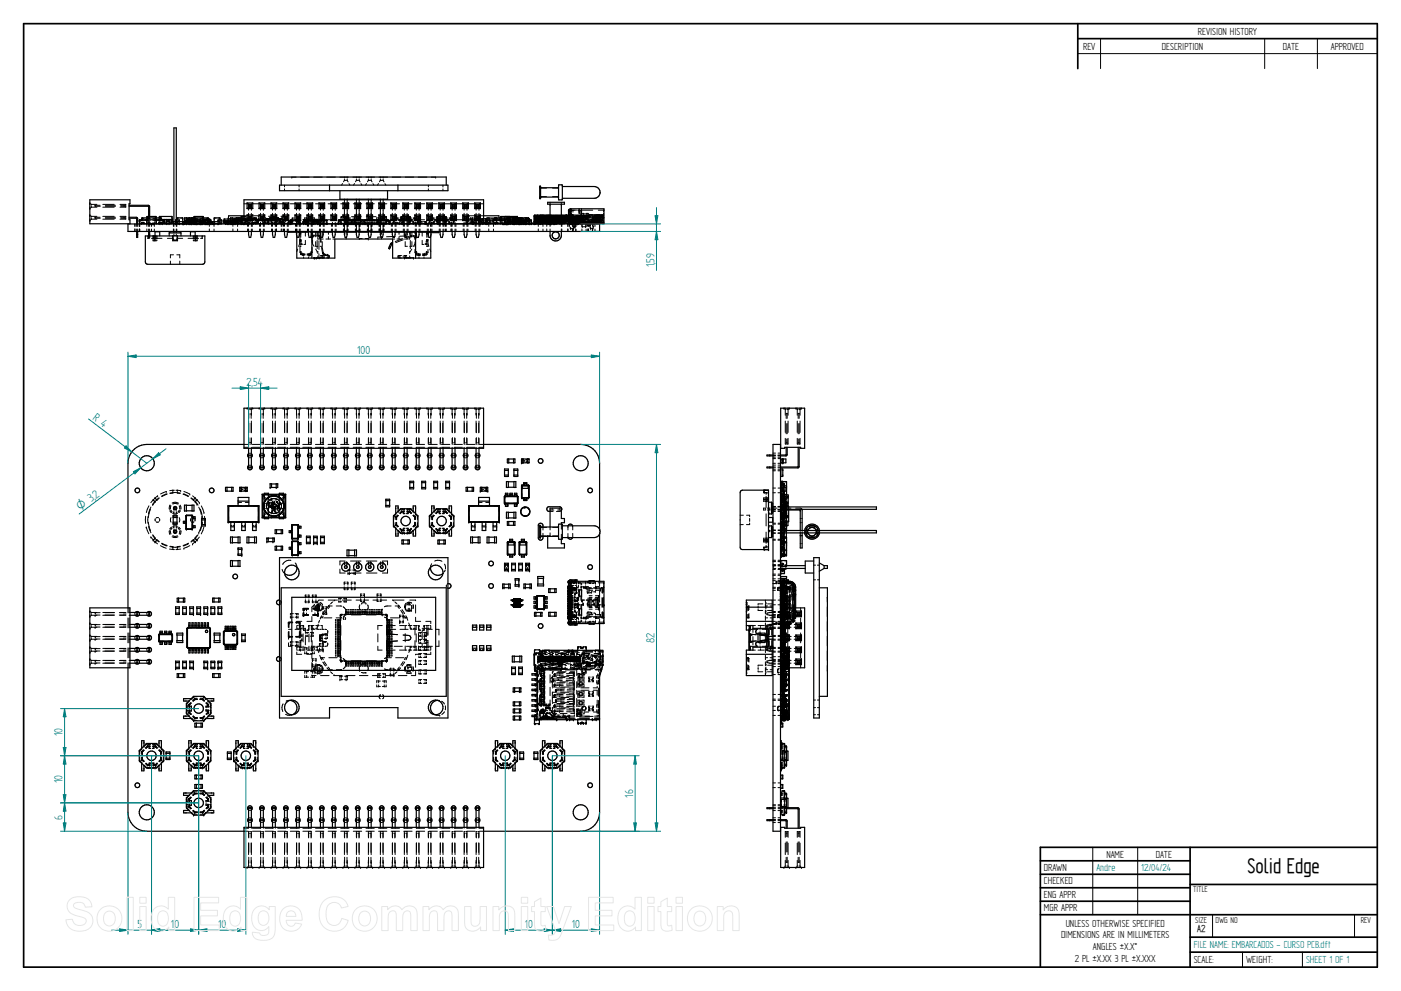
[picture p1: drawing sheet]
<svg xmlns="http://www.w3.org/2000/svg" width="594mm" height="420mm" viewBox="0 0 594 420" stroke-linecap="round" stroke-linejoin="round" font-family="sans-serif">
<defs><g id="words">
<text font-size="10.1" x="529" y="370.2">Solid Edge</text>
<g font-size="5.6" fill="#008080">
<text x="277.5" y="113.4" transform="rotate(-90 277.5 113.4)">1,59</text>
<text x="151.5" y="150.2">100</text>
<text x="104.5" y="163.7">2,54</text>
<text x="39" y="177.7" transform="rotate(37 39 177.7)">R 4</text>
<text x="40.8" y="211.4" transform="rotate(-37 40.8 211.4)">2</text>
<text x="277.5" y="272.6" transform="rotate(-90 277.5 272.6)">82</text>
<text x="26.5" y="312.2" transform="rotate(-90 26.5 312.2)">10</text>
<text x="26.5" y="332.1" transform="rotate(-90 26.5 332.1)">10</text>
<text x="268.4" y="338.2" transform="rotate(-90 268.4 338.2)">16</text>
<text x="26.5" y="347.5" transform="rotate(-90 26.5 347.5)">6</text>
<text x="58.2" y="393.5">5</text>
<text x="72.5" y="393.5">10</text>
<text x="92.5" y="393.5">10</text>
<text x="222.5" y="393.5">10</text>
<text x="242.5" y="393.5">10</text>
</g>
<text font-size="5.4" fill="#008080" x="34" y="216.5" transform="rotate(-37 34 216.5)">O 3,</text>
<g font-size="4.9">
<text x="507.9" y="14.7">REVISION HISTORY</text>
<text x="459.3" y="21">REV</text>
<text x="492.7" y="21">DESCRIPTION</text>
<text x="544" y="21">DATE</text>
<text x="564.3" y="21">APPROVED</text>
<text x="469.1" y="363.6">NAME</text>
<text x="490.1" y="363.6">DATE</text>
<text x="442.7" y="369.3">DRAWN</text>
<text x="442.7" y="375">CHECKED</text>
<text x="442.7" y="380.7">ENG APPR</text>
<text x="442.7" y="386.4">MGR APPR</text>
<text x="451.9" y="392.9">UNLESS OTHERWISE SPECIFIED</text>
<text x="449.9" y="397.9">DIMENSIONS ARE IN MILLIMETERS</text>
<text x="455.7" y="407.8">2 PL ±X.XX 3 PL ±X.XXX</text>
<text x="463.5" y="402.9">ANGLES ±X.X°</text>
<text x="506.2" y="408.3">SCALE:</text>
<text x="528.4" y="408.3">WEIGHT:</text>
</g>
<g font-size="4.9" fill="#008080">
<text x="464.9" y="369.3">Andre</text>
<text x="483.9" y="369.3">12/04/24</text>
<text x="506.2" y="402">FILE NAME: EMBARCADOS - CURSO PCB.dft</text>
<text x="553.8" y="408.4">SHEET 1 OF 1</text>
</g>
<text font-size="4.8" x="507.7" y="395.3">A2</text>
<g font-size="4.1">
<text x="505.9" y="378.3">TITLE</text>
<text x="506.9" y="391.1">SIZE</text>
<text x="515.4" y="391.1">DWG NO</text>
<text x="577" y="391.1">REV</text>
</g>
</g></defs>
<g fill="none" stroke="#000" stroke-width=".72">
<path d="M10 10h574v400h-574zM457 10v19.1M457 16.4h127M504.6 359.2v50.8M584 359.2h-142.9v50.8M441.1 365h63.5M441.1 370.7h63.5M441.1 376.4h63.5M504.6 375h79.4M441.1 382.1h63.5M441.1 387.8h142.9M504.6 397.3h79.4"/>
<path d="M504.6 403.7h79.4"/>
</g>
<g fill="none" stroke="#000" stroke-width=".42">
<path d="M466.7 16.4v12.7M536.3 16.4v12.7M558.6 16.4v12.7M457 22.7h127M120.6 78.5v.7M123.7 75.1h.1M123.7 75.1h1.9M126.8 78.5v.8M127.5 75.1h3.6M133 75.1h3.6M138.6 75.1h3.6M144.1 75.1h3.6"/>
<path d="M145.2 77.8l-.3 .7M146 76.5h.2M146 76.5l-.3 .6M146 75.1v.4M146 76v.5M146.5 76.5h.3M147 76.5h.2M147.2 75.1v.4M147.2 76v.5M147.2 76.5l.4 .6M148 77.9l.4 .6M149.6 75.1h3.7"/>
<path d="M150.3 77.8l-.4 .7M151.1 76.5h.2M151.1 76.5l-.4 .6M151.1 75.1v.4M151.1 76v.5M151.5 76.5h.3M152.1 76.5h.2M152.3 75.1v.4M152.3 76v.5M152.3 76.5l.4 .6M153.1 77.9l.4 .6M155.2 75.1h3.6"/>
<path d="M155.4 77.8l-.4 .7M156.2 76.5h.2M156.2 76.5l-.4 .6M156.2 75.1v.4M156.2 76v.5M156.6 76.5h.3M157.2 76.5h.2M157.4 75.1v.4M157.4 76v.5M157.4 76.5l.4 .6M158.2 77.9l.3 .6M160.5 77.8l-.4 .7"/>
<path d="M160.7 75.1h3.7M161.3 76.5h.2M161.3 76.5l-.4 .6M161.3 75.1v.4M161.3 76v.5M161.7 76.5h.3M162.3 76.5h.2M162.5 75.1v.4M162.5 76v.5M162.5 76.5l.3 .6M163.2 77.9l.4 .6M166.3 75.1h3.6"/>
<path d="M171.8 75.1h3.7M177.3 75.1h3.7M181.6 78.5v.7M182.9 75.1h1.8M184.7 75.1h.1M187.8 78.5v.8M228.8 79.4l.1 .1M228.9 79.6l.2 .1M229.2 79.8h.1M229.2 79.8h2.5M234.3 79.8h2.5M38.1 91.1l.2 .2"/>
<path d="M38.1 86.1h.1M38.1 88.4h.1M38.1 93.5h.1M38.1 91.1h.1M38.1 86.1v.8M38.1 87.7v.7M38.1 91.1v.8M38.1 92.8v.7M38.1 86.1l.2 .1M38.3 93.3l-.2 .2M38.3 88.3l-.2 .1M38.5 91.5l.2 .2"/>
<path d="M38.5 86.4l.2 .3M38.7 91.7v.4M38.7 92.6v.3M38.7 92.9l-.2 .2M38.7 86.7v.3M38.7 87.5v.3M38.7 86.7h2.4M38.7 87.8l-.2 .3M38.7 87.8h2.4M38.7 92.9h2.4M38.7 91.7h2.4M40.3 87.4l2.2 .1"/>
<path d="M40.3 92.5h2.2M40.4 87v.2M40.4 87.4v.1M40.4 92.1v.1M40.4 92.5h.1M42.5 87l-2.2 .2M42.5 92.1l-2.2 .1M43.6 86.7h4.8M43.6 87.8h4.8M43.6 92.9h4.8M43.6 91.7h4.8M44.7 87h4.2"/>
<path d="M44.7 92.1h4.2M44.7 87.5h4.3M44.7 92.5h4.3M50.9 86.7l2.4 .1M50.9 91.7l2.4 .2M51.2 87.5l2.1 .1M51.2 92.5l2.1 .2M52.6 87v.2M52.6 87.4v.1M52.6 92.1v.1M52.6 92.5h.1M53.3 87h-2.1"/>
<path d="M53.3 87.8h-2.4M53.3 92l-2.1 .1M53.3 92.8l-2.4 .1M57.2 95v1M57.2 97.1v1M57.9 95v1M57.9 97.1v1M58.4 95v1M58.4 97.1v1M59 95v1M59 97.1v1M59.2 95v1"/>
<path d="M59.2 97.1v1M59.3 95v1M59.3 97.1v1M60.1 94.5h.3M60.1 93.2h.1M60.1 93.3v.1M60.3 93l-.1 .2M60.3 92.4l-.2 .1M60.4 92.6v.2M60.4 93.2v.2M60.7 94.5h.3M61.1 92.6l-.8 .2"/>
<path d="M61.9 92.6h1.8M62.3 95v1M62.3 97.1v1M62.5 93.2h.1M62.5 93.3v.1M62.6 93v.4M62.6 92.8h.1M62.7 93.4h1M63 91.8v1M63 93.9v2.1M63 97.1v1M63.2 94.9h.1"/>
<path d="M63.2 94.7v.2M63.5 91.8v1M63.5 93.9v2.1M63.5 97.1v1M63.5 94.9h.1M63.7 94.7h.3M64.3 95v1M64.3 97.1v1M64.5 94.7h.3M64.8 92.6h1.8M64.8 93.4h.9M64.9 94.9h.1"/>
<path d="M65.1 94.9h.1M65.2 94.7h.1M65.3 94.9h.1M65.3 94.7h.1M65.4 95v1M65.4 97.1v1M65.8 93.2v.2M65.9 92.6l-.1 .2M65.9 93v.2M66 93.2h.1M66 93.3v.1M67.3 93.4h.1"/>
<path d="M67.3 93.3v.1M67.3 93.4l.1 .4M67.4 94.5h.4M67.4 92.6l.7 .2M67.4 92.9l-.1 .3M67.5 94.3v.4M67.5 92.4v.2M67.6 93.4v.4M67.6 93.3v.1M67.6 93h.1M67.6 93.4h.1M67.6 92.9v.3"/>
<path d="M67.6 94.3v.4M67.6 92.4v.2M67.8 93h.2M67.8 93.4h.4M67.9 94.9h.1M67.9 94.1v.3M67.9 93.4v.5M67.9 93v.2M68.1 92.6v.2M68.1 93.2v.2M68.1 94.5h.3M68.1 92.4l.1 .1"/>
<path d="M68.1 92.4h.1M68.2 93v.2M68.2 92.4h.1M68.2 94.6l-.3 .1M68.3 93h.1M68.3 92.5h.1M68.4 93.2h.1M68.4 93.3v.1M68.4 94.7h.3M68.6 93.4h.4M68.6 94.6h.2M68.8 94.6h.1"/>
<path d="M68.8 94.9h.1M68.8 93.2v.1M68.8 93.5v.4M68.8 94.1v.3M68.8 94.6v.1M69 94.7h.3M69.3 93.4h.2M69.8 93.4h.3M70.4 94.8h.5M70.4 94.1h.5M70.4 93.4h.3M70.4 94.6h.2"/>
<path d="M70.7 94.6h.1M70.7 94.9h.1M70.7 94.6l-.9 .1M70.7 94v.1M70.7 94.3v.1M71.5 94.8h.5M71.5 94.1h.5M71.7 93.4h.3M71.7 94.9h.1M71.7 94.3v.1M71.7 94v.1M71.8 94.6l.8 .1"/>
<path d="M72 94.6h.1M72.3 93.4h.3M73.4 94.8h.5M73.5 95v1M73.5 97.1v1M73.7 95v1M73.7 97.1v1M73.7 98.3v.5M73.7 99.4v.5h.4M73.7 94.9h.2M74.1 94l-.7 .1M74.5 94.1l.6-.1v.9"/>
<path d="M74.5 94.3v.4M74.5 94.7l.1 .1M74.8 93.3v.5M74.8 94.4v1.6M74.8 97.1v1M74.8 98.3v.5M74.8 99.4v.5h-.3M75 95v1M75 97.1v1M75 93.3l-.5 .1v.5M75 94.8l-.8 .1M75 94.8l.1 .1"/>
<path d="M75.1 94.7v.1M75.5 93.3h.4M75.9 92.5h-.8l-.1 1.3M75.9 94.8h-1.4M76 93.4v.5M76 94.3l-.1 .5h-.4M76.1 94v.2M76.1 94.6v.2M76.6 92.5h.8v.8M77.4 94l-.1 .8h-.7M77.5 94.6v.3M77.8 94.8h.4"/>
<path d="M77.8 94.9h.1M77.8 94.6h.1M77.8 94.6v.1M78 94.1h-.5v.2M78 94.6h.1M78.1 94.6h.1M78.2 94v.2M78.2 94.6v.3M78.2 94.8l-.1 .1M78.2 94.5h.1M78.3 94.8h.1M78.3 94.4h.1"/>
<path d="M78.4 94.8h.1M78.4 94v.1M78.4 94.7v.1M78.6 94.6l-.2 .2M78.6 94v.1M78.6 94.2v.2M78.9 94v.2M78.9 94.5l.3 .2M79 93.7h.8M79 94.3h.1M79 94.4h.1M79 92.5v.3"/>
<path d="M79 93.1v.3h.8M79 93.9l.1 .2M79.1 94.4v.3M79.1 93.3v.1M79.1 94l-.5 .1M79.2 93.9h.1M79.2 93.9l.1 .2M79.2 93.9h.2M79.2 94h.1M79.2 93.4v.1M79.2 94.5h.1M79.2 94.3h.1"/>
<path d="M79.2 94.9h.4M79.4 94.4v.3M79.4 93.5l-.1 .1M79.4 93.6l-.2 .3M79.5 93.2l-.1 .1M79.5 94.7h-.2M79.5 93.9h.3M79.7 93.6v.1M79.7 93.9v.2M79.7 94.7h.1M79.7 93.5v.1M79.7 94.4v.3"/>
<path d="M79.7 93.2v.1M79.8 93.6h-.3M79.8 94.8h-1.2M80 93.6h.3M80 93.9h.3M80 93.2h.1M80 94.7h.1M80 94.3h.1M80 93.3v.1M80 94.5v.1M80 94.8v.1M80.1 94.6h.2"/>
<path d="M80.1 94.9h.1M80.1 94.6v.1M80.1 94.4h.1M80.1 94v.2M80.1 93.6v.2M80.1 94.9h1M80.2 92.5h.4M80.2 92.5h.1M80.3 93v.2M80.3 92.4h.1M80.4 94.5h.1M80.4 94.3h.1"/>
<path d="M80.4 94.7h-.4M80.4 93.2v.2M80.4 93.3l.1 .6M80.5 94.6h.1M80.5 93.9h.3M80.5 94.7h.1M80.5 93.4h.1M80.5 94.3v.6M80.5 94.7l.1 .1M80.5 94.9h.1M80.6 93.3h1.3M80.6 94.4h.1"/>
<path d="M80.6 94.6h.1M80.6 94.9h.1M80.6 93.6v.2M80.6 94v.2M80.6 94.6v.1M80.7 93.7h.8M80.7 94.8h.7M80.8 93.6h-.3M81 93.3h-.6M81 92.5h.4l.1 .3M81.1 94.3h.1M81.1 94.5v.1"/>
<path d="M81.1 94.9h.1M81.1 94.7h.1M81.1 94.8v.1M81.1 92.6h-.8l.1 .2M81.2 93.6h.4M81.2 94.9h.1M81.2 94.7h.1M81.2 93.9h.4M81.4 92.5v.3M81.4 94.9h.1M81.4 94.4h.1M81.4 94v.2"/>
<path d="M81.4 92.4v2.5M81.4 92.9h3.5M81.5 93.3h.5M81.5 94.8h.4M81.6 94.6l-.2 .1M81.6 93.1l.1 .4M81.6 94.4l-.1 .3M81.7 93.7h.1M81.7 93.6v.1M81.7 93.7l-.1 .3M81.7 93.8h.1M81.8 94.6h.1"/>
<path d="M81.8 93.9l.4 .2M81.8 93.9l.1 .1M81.9 94.2v.2M81.9 93.5l.2 .2M81.9 93.5h.1M81.9 94.4h.1M81.9 94.6h.1M81.9 94.9h.1M81.9 94v.2M81.9 93.3l.1 .1M81.9 94.6l.2 .2M81.9 92.6h1.8"/>
<path d="M82 94.3l-.1 .5M82 93.4v.5M82 94.4v.4M82 93.3v.5M82.2 94.4h.1M82.2 94.3v.1M82.2 93.4l-.4 .2M82.2 94.5h.1M82.2 92.4v.8M82.2 94.1l.1 .8M82.3 93.4h-.2M82.3 94.6h.2"/>
<path d="M82.5 93.6h.3M82.5 93.9h.3M82.5 93.2h.1M82.5 93.3v.1M82.6 92.4h.1M82.6 93v.2M82.6 94.1h.1M82.6 94.8h.1M82.6 94.1v.2M82.6 94.6v.2M82.6 92.5h.1M82.6 92.4v.1"/>
<path d="M82.6 92.6v.2M82.7 94.9h.1M82.7 94.6v.1M82.7 94.4h.1M82.7 94v.2M82.7 93.6v.2M82.7 94.6h.1M82.7 92.6v.2M82.7 93.2v.2M82.7 94h.1M82.8 94h.1M82.8 94.9h.1"/>
<path d="M82.8 94.1v.3M82.8 93.4v.3M82.8 94.6v.1M82.8 94.5h.1M82.9 94.6l.1 .1M83.1 94h.1M83.1 93.9h.4M83.1 94.6h.1M83.2 94.7h-2.7M83.2 94.4h.1M83.2 94.6h.1M83.2 94.9h.1"/>
<path d="M83.2 93.6v.2M83.2 94v.2M83.2 94.6v.1M83.3 94h.6M83.3 94.8h.1M83.3 94.1h.1M83.3 94.8h.6M83.3 94.7h.1M83.3 94.8v.1M83.4 94.4v.4M83.4 94.8l.1 .1M83.4 94.7h.2"/>
<path d="M83.5 93.6h-.4M83.5 94.9h.1M83.5 93.4h.1M83.5 94.3l.1 .5M83.5 93.4v.5M83.6 94.8l.4 .1M83.6 94.7h.1M83.6 94.9h.1M83.6 94.7h.4M83.6 94.8v.1M83.8 93.6h.4M83.8 93.9h.4"/>
<path d="M83.9 93.3h-.5v.5M84 94.9h.1M84 94.4h.1M84 94v.2M84 93.6v.2M84 93.3l-1.6 .1M84.2 94.6l-.2 .1M84.4 94.6h.1M84.4 93.9h.3M84.4 94.9h.5M84.5 94.4h.1M84.5 94.6h.1"/>
<path d="M84.5 94.9h.1M84.5 94.6l.5 .1M84.5 93.6v.2M84.5 94v.2M84.5 93.3h.5M84.5 93.3l1.6 .1M84.6 94.8h.7M84.7 93.6h-.3M84.8 94.7h.1M84.8 94.8v.1M84.8 92.6h1.8M84.9 94.9h.1"/>
<path d="M84.9 94.7h.1M84.9 94.8v.1M84.9 93.3l.1 .1M85 94.7l-.1 .1M85 94.3v.5M85 94.8h.1M85 93.3v.6M85.1 93.6h.4M85.1 93.9h.4M85.1 94.9h.2M85.3 94.1h.1M85.3 94.8h.1"/>
<path d="M85.3 94.7h.1M85.3 94.9h.1M85.3 94.4h.1M85.3 94v.2M85.3 93.6v.2M85.3 94h.1M85.5 94v.3M85.5 94.8h.5M85.6 94.6h.1M85.7 93.9h.4M85.7 94.6h.1M85.8 94.4h.1"/>
<path d="M85.8 93.4v.4M85.8 94.6h.1M85.8 94.9h.1M85.8 94v.4M85.8 94.6v.1M85.8 94h.1M85.8 94.8h.1M85.8 94.1h.1M85.8 94.1v.2M85.8 94.6v.2M85.8 92.5h.1M85.8 92.4h.1"/>
<path d="M85.8 92.4v.1M85.8 92.6v.2M85.8 92.6l.1 .2M85.9 93l-.1 .4M86 93.2h.1M86 93.3v.1M86.1 93.6h-.4M86.2 94h-1.6M86.3 93.4v.2M86.3 93.8v.1M86.3 93.4h.1M86.4 93.6h.4"/>
<path d="M86.4 93.9h.4M86.4 93.3v.5M86.4 94.4l.1 .5M86.5 93.4h.1M86.5 93.4v.5M86.5 94.3l.1 .5M86.6 94.2l.4-.2v.3M86.6 94.9h.1M86.6 94.4h.1M86.6 93.6v.2M86.6 94.8h.4M86.6 93.3h.4"/>
<path d="M86.7 92.9h1.7M86.8 94.6l-.2 .1M87 93.9h.4M87 93.3h-.6M87.1 92.9h.1M87.1 93h.1M87.1 93h.3M87.1 94.6l-.1 .3-.4-.1M87.1 94.4h.1M87.1 94.6h.1M87.1 94.9h.1M87.1 93.6v.2"/>
<path d="M87.1 94v.2M87.1 94.6v.1M87.3 94.9h.1M87.3 94.7h.1M87.4 93.6h-.4M87.4 92.6h.7M87.5 94.9h.1M87.5 94.3h.1M87.5 94.5v.1M87.5 94.7h.1M87.5 94.8v.1M87.5 94.9h.9"/>
<path d="M87.5 93.3l.5 .1v.5M87.5 93.3h.5M87.7 93.6h.3M87.7 93.9h.3M87.8 93h.3M87.9 94.9h.1M87.9 94.4h.1M87.9 94v.2M87.9 93.6v.2M88 94.9h.1M88 94.3l-.1 .5M88 94.6l-.1 .1"/>
<path d="M88 94.4v.4M88 94.7h.1M88 94.7l-2.7-.1 .2 .3M88.1 93h.1M88.1 92.9h.1M88.1 92.6v.2M88.1 93.2l-.1 .6M88.1 94.3h.1M88.1 94.4v.1M88.1 92.6l.1 .2M88.2 94.7h.4M88.2 92.4v.1"/>
<path d="M88.2 93l.1 .2M88.3 93.6h.3M88.3 94.6h.1M88.3 92.5h.1M88.4 94.4h.1M88.4 94.6h.1M88.4 94.9h.1M88.4 93.6v.2M88.4 94v.2M88.4 94.6v.1M88.4 94.3h.1M88.4 94.5v.1"/>
<path d="M88.4 94.7h.1M88.4 94.8v.1M88.4 93.2h.1M88.4 93.3v.1M88.6 93.9h-.3M88.7 93.6h.3M88.7 93.9h.3M88.8 95v1M88.8 97.1v1M88.8 93.5l.1 .2M88.8 93.2v.1M88.8 94.4l.1 .3"/>
<path d="M88.9 93.9l-.1 .2M88.9 94.9h.3M89.1 93.2v.1M89.1 93.5l.1 .3M89.1 94.4l-.1 .3M89.1 93.9h.1M89.2 93.9h.1M89.2 93.8h.1M89.2 94h.1M89.2 93.4v.1M89.2 93.9v.2M89.2 94.5h.1"/>
<path d="M89.2 94.3h.1M89.4 94h.1M89.4 94.8h.5M89.4 94.1h.6M89.4 94.3h.1M89.4 94.4h.1M90.2 94.8h.1M90.2 94.7v.1M90.4 94.8h.4M90.5 94.1h.6v.2M90.8 95v1M90.8 97.1v1"/>
<path d="M90.8 94l.1 .9M90.9 94.7l.8 .1M91.1 94.6v.2M91.7 92.5h-.8v.8M92.4 94v.8M92.4 92.5h.8v.8M92.5 94.7l.5 .1M93 93.3l-.5 .1v.5M93.2 94v.7l-.8 .1M93.3 94.3l-.1 .6M93.3 93.3v.5M93.5 93.3l.5 .1v.5"/>
<path d="M94 94.3l-.1 .5h-.4M95.5 94.7h.2M95.5 93.9h.2M95.6 94.1v.2M95.6 94.6v.2M95.6 94.1h.1M95.6 94.8h.1M95.7 94h.1M95.7 94.8h.1M95.8 94h.1M95.9 94.7h.1M95.9 93.9h.1"/>
<path d="M96 94h.2M96.2 94h.1M96.3 94.1h.1M96.4 94h.1M96.4 94.1h.5M96.4 94.8h.5M96.5 94.9h.1M96.5 94.4h.1M96.5 94.1v.1M96.5 94h.1M96.5 93.9h.2M96.7 94.6h.3"/>
<path d="M96.7 93.3h.4M96.7 93.3l.1 .5M96.7 92.9v.1M96.7 93.2v.1M96.9 93.9h.1M96.9 94.6h.1M96.9 94.3v.4M97 94.1h.1M97 94h.1M97 94.4h.1M97 94.6h.1M97 94.9h.1"/>
<path d="M97 94.1v.1M97.5 93.9h.2M97.5 94.1h.5M97.5 94.8h.5M97.5 94.9h.1M97.5 94.4h.1M97.5 94.1v.1M97.5 94h.1M97.7 94.6l.3 .1M97.7 92.8h.1M97.7 92.9v.6M97.7 94.2v.7"/>
<path d="M97.8 92.8h.1M97.9 92.8h.5M97.9 94.3h.5M97.9 94.2l.1 .4M97.9 93.5v.3M97.9 92.8v.3M97.9 94.7v.2M98 94.1h.1M98 94h.1M98 94.4h.1M98 94.6h.1M98 94.9h.1"/>
<path d="M98 93.9l-.1 .2M98 94.1v.1M98 94.6v.1M98 94.8h.1M98.2 94.8h.1M98.2 94h.2M98.2 94.1h.1M98.3 94.8h.1M98.4 93.3h-.9M98.5 94.7h.2M98.5 93.9h.2M98.5 94.8h.2"/>
<path d="M98.5 92.9v.6M98.5 94.2v.7M98.6 93h.3M98.6 92.9h.1M98.6 93h.1M98.6 94h.2M98.8 95v1M98.8 97.1v1M98.8 94.8h.1M98.8 94h.1M98.8 94.1v.2M98.8 94.6v.2"/>
<path d="M98.9 94.7h.1M98.9 93.9h.3M98.9 94.8h.1M98.9 92.8h1.5M98.9 94.3h.5M99.1 93.6h.1M99.2 94.8h.6M99.3 93h.3M99.4 93.9h.3M99.4 93.6h.3M99.4 93.9h.1M99.4 92.8v.3"/>
<path d="M99.4 93.5v.3M99.4 93.9v.2M99.4 94.2v.3M99.4 94.7v.2M99.5 94.9h.1M99.5 94.4h.1M99.5 94v.2M99.5 93.6v.2M99.6 93h.1M99.6 92.9h.1M99.7 94.6l-.5 .1M99.8 94.7h.2"/>
<path d="M99.9 93.6h.2M99.9 94.6h.1M100 94.4h.1M100 94.6h.1M100 94.9h.1M100 93.6v.2M100 94v.2M100 94.6v.1M100 94.5h.4M100.1 93.2h.1M100.1 93.3v.1M100.1 92.9h.2"/>
<path d="M100.1 93.9h-.2M100.2 92.5h.3M100.2 92.9l.1 .1M100.2 92.5h.1M100.3 93.9h.2M100.3 93.4l.2 .2M100.3 94.4v.3M100.3 92.4h.1M100.4 92.6l-.1 .2M100.4 92.6h.7M100.4 93.6v.1M100.4 93.9l-.1 .2"/>
<path d="M100.4 94.8h.6M100.4 92.6v.2M100.4 93.2l-1.5 .1M100.5 92.9v.2M100.5 92.9h.1M100.6 93.4l.1 .2M100.6 94.4v.3M100.7 93.9h.1M100.7 93.6h.1M100.7 95v1M100.7 97.1v1M100.7 94.5h.3"/>
<path d="M100.7 93.9v.2M100.7 92.5h.3M100.7 93.6v.1M101 94.8h.1M101 94.3h.4M101 92.4v.9h.5M101 93.7h.1M101 93.6v.1M101 93.9v1M101 94.3v.4l.5 .1M101 94.7h2.1M101.5 92.8h1.5"/>
<path d="M101.6 94.6l.1 .3M101.7 93.9h.2M101.7 93.9l-.1 .3M101.8 92.4v.8M101.8 94.1v.8M101.8 94.9h.1M101.8 93.9h.1M101.9 92.6h1.8M102 93.3h1M102 94.8h.4M102 94.3h1M102.1 93.9h.1"/>
<path d="M102.2 94.8h.1M102.3 93.6l-.1 .3M102.4 94.8h.7M102.4 94.4v.4M102.4 94.8l.1 .1M102.4 94.8h.1M102.5 93.3h.1M102.5 93.4v.5M102.5 94.3v.6M102.5 94.2v.3M102.5 93.9v.2M102.5 93.5v.3"/>
<path d="M102.5 92.8v.3M102.5 94.8h.1M102.5 93.3l-.1 .5M102.5 93.2h.1M102.5 93.4h.1M102.5 93.3v.6M102.6 92.8h.1M102.6 93l.1 .4M102.7 94.8h.1M102.9 92.7h-.5l-.1 .4M103.2 94.9h.1M103.2 94.7h.1"/>
<path d="M103.5 86.4h1.7M103.5 93.2h1.7M103.5 91.5h1.9M103.5 91.8h.8M103.5 92.4h.8M103.5 94.7h.1M103.5 92.8h1.5M103.5 94.3h1M103.5 93.3h.5v.5M103.5 92.7h.6l.1 .3M103.6 94.9h.1M103.6 94.7h.1"/>
<path d="M103.6 94.8v.1M103.6 94.8l.4 .1M103.6 94.7h.4M103.8 94.8h.1M104 93.4v.5v-.4M104 94.7l-.1 .1M104 93.9h.1M104 94.2v.6M104 92.8v.3M104 93.9v.2M104 94.4v.4M104.1 94.8l-.9 .1"/>
<path d="M104.2 93.5l.1 .4M104.3 93.9h.1M104.3 94.9h.1M104.4 93.9h-.1M104.5 94.7h.4M104.6 93.9l.3 .2M104.7 94.8h.1M104.7 94.8l-.2 .1h.4M104.7 94.1l.2 .7M104.8 92.6h1.8M104.9 94.7h.2M104.9 94.4v.3"/>
<path d="M104.9 94.9h.1M104.9 94.7h.1M105 95v1M105 97.1v1M105 94.3h.5M105.2 94.9h.1M105.2 94.7h.1M105.3 94.7l-.1 .2M105.3 91.8h.9M105.4 92.9v.6M105.4 94.2v1.8M105.4 87.8v1.3"/>
<path d="M105.4 90.4v1.3M105.4 97.1v1M105.5 92.5h.8M105.5 94.8h.8M105.5 92.4v1M105.5 94.1v.8M105.5 93.6v.1M105.5 93.9v.3M105.6 93.2h4.9M105.6 94.6h.1M105.7 94.5h.1M105.7 94.1v.3"/>
<path d="M105.7 93.4v.3M105.8 92.6v.2M105.8 93.2v.2M105.9 92.4h.1M105.9 92.5h.1M105.9 92.4v.4M105.9 93.2l.1-.3v.3M106 92.5h.1M106 93.2h.1M106 93.3v.1M106 92.8h1.6M106.2 91.8h.1"/>
<path d="M106.2 93.4h1.2M106.2 91.9h.1M106.2 91.9v.2M106.2 92.2v.2M106.3 93.4v.5M106.3 94.4v.5M106.4 93.3h.1M106.5 93.3h.1M106.6 93.2h.1M106.6 87.8v1.4M106.6 90.5v1.2M106.6 92.9v.7"/>
<path d="M106.6 94.3v1.7M106.6 97.1v1M106.6 92.4h-1.9v.8M107 95v1M107 97.1v1M107.1 86.4h3.5M107.1 94.3h.5M107.1 94.2v.3M107.1 93.9v.2M107.1 93.5v.3M107.1 92.8v.3M107.1 94.7v.2"/>
<path d="M107.2 92.5h.7M107.2 94.8h.7M107.4 94.3h.4M107.4 94.5h.4M107.4 94.7h.1M107.4 94.3h.1M107.4 94.5v.1M107.4 94.8v.1M107.4 92.6l1.6 .2M107.4 92.4h.8M107.5 91.5h2l.1 .4M107.6 93.3h-6.5l-.1 .6"/>
<path d="M107.8 94.7h-2.5M107.9 92.4v.8M107.9 94.1v.8M108.1 92.6v.2M108.1 93.2v.2M108.2 94.7h.6M108.2 92.4v.1M108.2 94.3h.3M108.2 94.5h.3M108.2 93.3h1.6M108.2 94.3h.4M108.2 92.4h.1"/>
<path d="M108.2 93v.2M108.2 92.5h.1M108.3 92.5h.1M108.3 92.5l.1 .2M108.4 92.9l.1 .2M108.5 94.3h.1M108.5 94.5v.1M108.5 94.7h.1M108.5 93.3v.1M108.5 94.8v.1M108.5 93.1h.1M108.5 93.2h.1"/>
<path d="M108.5 92.4l.2 .8M108.6 93.9h.1M108.6 92.8v.3M108.6 93.5v.3M108.6 93.9v.2M108.6 94.2v.3M108.6 94.7v.2M108.7 94.1v.8M109.3 93.9v.4M109.3 93.4v.1M109.3 93.6v.2M109.3 94.6v.3"/>
<path d="M109.3 93.8h.1M109.3 93.9h.1M109.3 93.2h.1M109.3 94h.1M109.4 92.8h.4M109.4 93.4h.1M109.4 93.3h.1M109.4 94h.1M109.4 93.4v.1M109.4 93.6v.2M109.4 93.8h.1M109.4 93.9h.1"/>
<path d="M109.6 94.3v.4h-.4M109.7 92.4v.4M109.8 93.3l-.1 .5M109.8 92.8v.2M109.8 93.2v.1M110.1 95v1M110.1 97.1v1M110.5 92.9v.6M110.5 94.2v1.8M110.5 87.8v1.3M110.5 90.4v1.3M110.5 97.1v1"/>
<path d="M111.2 93.6l.3 .1M111.2 93.3v.1M111.2 93.3h.2M111.2 92.8v.5M111.3 93.7l.1 .2M111.5 94.1v.3M111.5 94.4h.1M111.6 94.5h.1M111.7 87.8v1.4M111.7 90.5v1.2M111.7 92.9v.7M111.7 94.3v1.7"/>
<path d="M111.7 97.1v1M111.8 94.6h.1M111.8 93.3h.8M111.8 93.7h.8M111.8 91.7l.4 .3M112 94.4h.1M112 94.5v.1M112 94.1v.1M112 93.3v.1M112 94.2v.3M112 93.3h.1M112 97.1v1"/>
<path d="M112 94.5h.6M112.1 91.7h-.6l-.1 .5M112.3 93.2h3.6M112.4 86.4h3.5M112.6 92.4l.3 .3M112.6 94.6h-.7M112.6 94.7h-.6v1.3M112.6 94.3l-.6 .1M112.6 93.6h-.6v.3M112.9 92.7h.1M112.9 92.7h1.4M113.2 94.4v.4"/>
<path d="M113.2 93.6h.6v.3M113.2 94.7h.6M113.3 93.7h2.1M113.3 94.6h1M113.7 94.8h.1M113.7 93.3h.7M113.7 94.8h.7M113.7 93.3v.5M113.7 94.4v.4M113.8 93.3v.1M113.8 94.1v.4h-.6M113.8 94.7v.2"/>
<path d="M113.8 93.3h.1M113.9 91.7h3.4M114 94.3h-.8M114 94.4h.1M114 94.5v.1M114 94.1h.1M114 94.3v.1M114.2 92.5h.1M114.2 92.6v.1M114.3 92.7h.1M114.3 92.5h.1M114.3 92.4v.1"/>
<path d="M114.3 92.4h.1M114.5 92.7h.1M114.5 93.3h-1.3v.5M114.5 94.4v.4M114.5 93.3v.5M114.5 92.6v.1M114.6 92.5h.1M114.6 92.7h.1M114.6 92.4h.1M114.6 92.4v.1M114.7 92.2l-.2 .1M114.7 92.2h.1"/>
<path d="M114.7 92.3h.1M115 92.2h.3M115.1 92.7h2.1M115.1 94.4h.1M115.1 94.5v.2M115.1 94.8h.1M115.1 93.9v.3M115.1 95v1M115.1 97.1v1M115.1 94.4h.6v.4M115.4 92.4v.1M115.4 92.5h.1"/>
<path d="M115.4 92.6v.1M115.4 92.2h.1M115.4 92.3h.1M115.4 92.6l1 .1M115.4 92.2v.1M115.5 92.6h.1M115.5 92.7h.1M115.5 92.3h.1M115.6 92.9v.6M115.6 94.2v1.8M115.6 92.3v.3M115.6 87.8v1.3"/>
<path d="M115.6 90.4v1.3M115.6 97.1v1M115.6 92.5l-.1 .2M115.6 92.7h.1M115.6 92.6h.1M115.7 93.3v.5M115.8 92.3l-.1 .2M115.8 94.6h-1M115.8 92.5l-.1 .1M115.9 92.6h.1M115.9 92.2h.2M115.9 93.3h-.8v.3"/>
<path d="M116 92.6h.1M116.2 92.3h.1M116.2 92.6h.1M116.2 93.3h-1.1M116.2 94.8h-1.1M116.2 92.2l-.3 .4M116.2 92.5l.1 .1M116.2 92.5h.1M116.2 92.4v.3M116.3 92.7h.1M116.3 92.4v.1M116.3 94.8h.1"/>
<path d="M116.3 93.3v.5M116.3 94.4v.4M116.3 92.6h.1M116.3 92.4l-.1 .1M116.3 92.3v.1M116.4 92.3l-.1 .1M116.5 92.5h.1M116.5 92.6v.1M116.5 92.2l-.2 .1M116.5 92.7h.1M116.5 94.6h1M116.5 94.3h.6"/>
<path d="M116.6 92.3l-.1 .2M116.6 92.2h.7M116.7 92.3h.4M116.7 93.3h.4M116.7 94.8h.4M116.7 94.1h.1M116.7 94.8h.1M116.7 94.1v1.9M116.7 92.7h.1M116.7 87.8v1.4M116.7 90.5v1.2M116.7 92.9v.7"/>
<path d="M116.7 97.1v1M116.7 94h.1M116.8 92.2h.5M116.8 92.2h.7M117 94h.8M117 93.3h-.8M117.1 94.4h.1M117.1 94.5v.2M117.1 94.3v.1M117.1 94.8h.1M117.1 93.3v.3M117.1 93.9v.2"/>
<path d="M117.1 95v1M117.1 97.1v1M117.2 94.8h.1M117.2 94h.1M117.3 95v1M117.3 97.1v1M117.3 94.8h.1M117.3 94.1h.1M117.3 94.8h.5M117.3 92.7h2M117.3 92.4l.2 .1M117.4 92.7h.1"/>
<path d="M117.5 92.5h.1M117.5 92.6v.1M117.5 92.7h.1M117.6 92.7h.1M117.6 92.3l.1 .2M117.7 92.2h.1M117.7 92.2l.1 .3M117.7 93.2h3.5M117.7 92.5h.1M117.7 92.6v.1M117.8 86.4h3.5M117.8 94.8h.1"/>
<path d="M117.8 94.4v.4M117.8 92.7h.1M117.8 92.5h.1M117.8 92.3h.1M117.8 92.6v.1M117.9 92.5h.1M117.9 92.7h.1M117.9 92.3l.1 .1M118 92.7h.5M118 92.7h.1M118.1 92.5h.1M118.1 92.6v.1"/>
<path d="M118.1 92.7h.1M118.4 94.4h.1M118.4 94.5v.1M118.4 94.1v.1M118.4 94.5h.6M118.4 94.2v.3M118.4 93.3h.1M118.6 94h.8M119 94.6h-1.1M119 93.7h-2.1M119 94.3l-.6 .1M119 93.6h-.6v.3"/>
<path d="M119 93.3h-1.2v.5M119.1 91.7h1.8v.5M119.2 95v1M119.2 97.1v1M119.2 94.8l-.8 .1M119.2 94.1h.1M119.2 94.8h.1M119.3 94.8h.1M119.3 92.7h.1M119.5 95v1M119.5 97.1v1M119.5 92.2v.3h.5"/>
<path d="M119.6 93.6h.7v.3M119.6 91.7v.2M119.6 93.7h1M119.6 94h.2M119.7 94.7h.6M119.7 94.3h.6M119.7 92.4l-.4 .3M119.7 94.6h.6M119.8 94.8h.1M119.8 94h.1M119.8 94.1v.2M119.8 94.6v.2"/>
<path d="M120.2 97.1v1M120.3 93.3v.1M120.3 94.1v.4h-.6M120.3 94.7l-.1 1.3M120.3 93.3h.1M120.3 94.6h.1M120.3 94.4h.1M120.3 94.5v.1M120.3 94.1h.1M120.3 94.3v.1M120.4 91.7l-.3 .3M120.5 94.6h.1"/>
<path d="M120.5 92.5h.5M120.5 93.3h-.9M120.6 87.8v1.3M120.6 90.4v1.3M120.6 97.1v1M120.6 80.1v.8M120.6 92.9v.6M120.6 94.2v1.8M120.7 94.5h.1M120.7 94.4h.1M120.8 94.2v.2M120.9 93.3h.3"/>
<path d="M120.9 93.7v.2M121.1 92.8l.1 .5M121.2 93.6l-.3 .1M121.2 93.3v.1M121.8 87.8v1.4M121.8 90.5v1.2M121.8 92.9v.7M121.8 94.3v1.7M121.8 97.1v1M122.2 97.1v1M122.3 94.1v.2M122.3 94.7l-.1 1.3"/>
<path d="M122.3 94.1h.1M122.5 94.1h1.5M122.5 94.1h.1M122.5 94.1v.2M122.5 94.7v.2M122.5 93.8l-.2 .1M122.5 93.8h.1M122.5 93.6h.1M122.6 93.8h1.4M122.6 94.9h.1M122.7 94.6l-.1 .1M122.8 93.6h1.3"/>
<path d="M122.9 94.6h.1M123 94.6h.1M123.1 93.2h3.5M123.1 94.9h.1M123.1 86.4h3.5M123.1 94.5h.1M123.2 94.4h.1M123.2 94.3l-.1 .5M123.3 94.8h.1M123.3 93.3l-.1 .8M123.4 94.6l-.1 .2M123.5 93.5l-.2 .2"/>
<path d="M123.5 93.9v.1M123.5 94.2v.2M123.6 93.3l.1 .5M123.6 93.8h.1M123.6 93.4h1.1M123.7 94.8h.1M123.7 94.4v.4M123.7 94.8h.7M123.7 93.7l.1 .3M123.7 93.7h.1M123.8 93.7h.1M123.8 93.4h.1"/>
<path d="M123.8 94.4l.1 .3h.8M123.8 93.1v.3M123.9 93.7v.3M123.9 93.7h.8M123.9 93.7h.1M123.9 93.4h.1M123.9 93.6v.1M123.9 94.4l.1 .3M123.9 93.1v.4M124 92.5v.3M124.7 92.5h-.8v.3M125.3 95v1"/>
<path d="M125.3 97.1v1M125.3 93.6l1.2 .1M125.4 93.8h1.4M125.6 94.1h1.5M125.6 93.7h.8M125.6 92.5h.7l.1 .3M125.7 87.8v1.3M125.7 90.4v1.3M125.7 94.4v.4h-.6M125.7 93.3h.2M125.7 92.9v.9M125.7 94.2v1.8"/>
<path d="M125.7 97.1v1M125.8 98.5h.1M125.9 98.5v.4M125.9 99.5v.5M125.9 98.5h.1M125.9 98.5h.2M125.9 95v1M125.9 97.1v1M126.1 93.3l.2 .7M126.2 92.5l.1 .3M126.3 94.4v.3M126.3 93.1l.1 .3-1.3-.1"/>
<path d="M126.4 94.8h.1M126.4 94.4v.4M126.4 94.4v.3h-.8M126.4 93.1l.1 .3M126.5 98.1h.1M126.5 93.7h.1M126.5 93.7v.3M126.5 98.5h.4M126.5 93.4v.1M126.5 93.4h.1M126.6 93.8h.1M126.7 98.2h.1"/>
<path d="M126.7 93.8h.1M126.7 93.9v.1M126.7 94.2v.2M126.8 94.6l.2 .2M126.8 93.5l.2 .2M126.8 93.6h.2M126.8 80.1v.8M126.9 98.2h.1M126.9 87.8v1.4M126.9 90.5v1.2M126.9 92.9v.7M126.9 94.3v1.7"/>
<path d="M126.9 97.1v1M126.9 98.6l.2 .2M127 93.8h.1M127 93.6h.1M127 94.8h.1M127 93.8l.2 .1M127 93.9v.5M127 94.7v.2M127 98.5v1.6M127 94.4h.1M127.1 94.5h.1M127.2 94.1h.1"/>
<path d="M127.2 94.9h.1M127.2 99v2.7M127.2 99.1h.1M127.2 94.6h.1M127.2 94.1v.2M127.2 94.7v.2M127.2 98.4l.1 .1M127.3 95v1M127.3 97.1v1M127.4 98.6l.1 .2M127.5 98.8h.1M127.5 99l-.1 .1"/>
<path d="M127.5 98.5v.1M127.5 98.9v1.7M127.5 94.6l.1 .1M127.6 94.9h.1M128.4 93.2h3.5M128.4 86.4h3.5M128.6 94.7v.1M128.6 94.2h2.1M128.6 94.8h1.3M128.6 94.5v.3M128.6 93.9v.5M128.6 94.1h2.2"/>
<path d="M128.6 93.9h.1M128.6 94.2h.1M128.6 94.1v.2M128.6 94.6v.2zM128.6 94.1h.1M128.6 93.9h2.2h-2M128.7 93.9h.1M128.7 93.5v.1M128.7 93.8l-.1 .4M128.7 94.9h.1M128.7 93.5h.1M128.8 93h.1"/>
<path d="M128.8 93.5h.1M128.8 93v.2M128.8 93.3v.1M128.9 93h.1M128.9 93.5h1.9M128.9 93h1.9v.5M129.2 94.1v.8M129.4 94.8h.1M129.4 94.4v.4M129.5 98.5v1.6M129.5 92.4h-.3v.8M129.5 93.4v.5"/>
<path d="M129.5 94.3l.1 .5M129.6 93.3l-.1 .1M129.6 93.3h.4M129.7 94.1h.1M129.7 94.8h.1M129.7 94.1v.2M129.7 94.6v.2M129.7 94h.1M129.8 92.4l.2 .8M130 94.9h.1M130 94.8h.1M130 94.6v.2"/>
<path d="M130 93.3h-.5l-.1 .5M130 92.5h.8M130 94.8h.9M130 94.1v.8M130.2 94.8h.1M130.2 94h.1M130.3 94.8h.1M130.3 94.1h.1M130.4 95v1M130.4 97.1v1M130.5 93.3l.5 .1v.5M130.5 93.3h.5l.1 .5"/>
<path d="M130.8 87.8v1.3M130.8 90.4v1.3M130.8 94.2v1.8M130.8 97.1v1M130.8 98.5h.3M130.9 94h-.9v.3M131 94.3v.4M131 94.1h1.5l-.1 1.9M131.1 94.4l-.1 .3M131.5 94v.3M131.5 94.6v.3M131.6 98.5h.4v.6"/>
<path d="M131.7 92.5h.8M132 87.8v1.4M132 90.5v1.2M132 92.9v.7M132 94.3v1.7M132 97.1v1M132 99.9v.8M132.2 94.1h.1M132.2 94.8h.1M132.3 94h.1M132.3 94.8h.1M132.4 97.1v1"/>
<path d="M132.5 94.8h.1M132.5 93.3h.5v.5M132.5 94.8h-.9M132.5 99.9l-.3 .3M132.5 94.3l.1 .5M132.5 98.5v1.6M132.6 94h.2M132.7 93.5h1.8M132.7 93h1.8zM132.7 94.1h1.9M132.7 93.9h1.9M132.7 92.4h-.2v.8"/>
<path d="M132.8 94.2h2.1M132.8 94.8h.1M132.8 94h.1M132.8 93.9h2.1M132.8 94.1v.2M132.8 94.6v.2M133 94.8h.1M133 94.4v.4M133 93.4h.1M133 94.3v.5h-1.7M133 93.4v.5M133 93.3l-.5 .1v.5"/>
<path d="M133 92.4h.3v.8M133.3 94.1v.8M133.5 93.3h.6M133.6 94.9h.1M133.6 99.7l-.8 .1M133.8 93.2h3.5M133.8 86.4h3.5M133.9 98.5v1.9M134 93.3h.1M134 93.4v.5M134 94.3l-.1 .5M134.1 93.3v.5"/>
<path d="M134.1 94.4l-.1 .5M134.2 94.8h-.7M134.3 93.3h.1M134.3 99.7h.8M134.4 93.3h.1M134.5 98.5v1.7M134.5 93.3v.6zM134.5 93h.1M134.6 93h.1M134.7 93h.1M134.7 93v.2M134.7 93.3l.1 .3"/>
<path d="M134.7 94.9h.1M134.7 93.5h.1M134.7 93.9h.1M134.8 93.8v.1M134.8 98.5v.9M134.8 93.9h.1M134.8 94.8h.1M134.8 94.6v.2M134.8 93.9v.4M134.9 94.1h.1M134.9 94.2h.1M134.9 94.8h.1"/>
<path d="M134.9 94.8h-.4v-.4l-.1 .4M134.9 94.1h-2.1M134.9 93.9h.1M135 93.9l-.1 .5M135 94.5l-.1 .3M135.1 99.7h.1M135.2 98.5v1.7M135.4 99.9h.1M135.4 99.9l.3 .2M135.5 95v1M135.5 97.1v1M135.5 94.8h.1"/>
<path d="M135.5 93.3v.6M135.5 94.7v.1M135.5 93.4h.1M135.5 94.3v.5M135.5 94.8h.5M135.5 93.3h.5M135.6 94.4v.4M135.6 93.3v.5M135.9 87.8v1.3M135.9 90.4v1.3M135.9 92.9v.6M135.9 94.2v1.8"/>
<path d="M135.9 97.1v1M135.9 98.5h.3M135.9 94.8h.5M136 93.3h-.5M136 98.5v.9M136.3 94.8h.1M136.3 93.3v.5M136.3 94.4v.4M136.4 94h-.5v.3M136.5 94.8h.8M136.5 93.3h.8M136.9 93.3l.1 .6z"/>
<path d="M136.9 94.8h.1M136.9 93.3h.1M137 94.3l-.1 .5M137 94h.5v.3M137 94.8h.5M137 94.8h.1M137.1 87.8v1.4M137.1 90.5v1.2M137.1 92.9l-.1 .9M137.1 94.3v1.7M137.1 97.1v1M137.1 98.5h-.5v1.9"/>
<path d="M137.1 94.8h-.2M137.4 93.3h-.9M137.4 97.1v1M137.5 94.6l-.1 1.4M137.8 93.3h.5M137.8 94.8h.5M137.8 93.3h.6M138.3 93.3h.1M138.3 94.4v.4M138.3 93.3v.5M138.3 94.8h.1M138.4 93.3h.1"/>
<path d="M138.4 94.8h.1M138.5 93.3l.1 .5M138.5 93.4v.5M138.5 94.3v.6l.1-.5M138.6 93.3l.2 .5M138.8 94.8h.1M138.8 94.4v.4M139.1 93.2h3.5M139.1 86.4h3.6M139.3 98.5v.9M140.5 95v1M140.5 97.1v1"/>
<path d="M141 92.9v.6M141 94.2v1.8M141 97.1v1M141 98.5h.3M141 87.8v1.3M141 90.4v1.3M141.7 98.5h.4M142.1 87.8v1.4M142.1 90.5v1.2M142.1 92.9v.7M142.1 94.3v1.7M142.1 97.1v1"/>
<path d="M142.2 94.9h.1M142.5 95v1M142.5 97.1v1M142.5 94.7h-.3M142.9 94.7h.3M143.2 94.7h.1M143.3 94.6h.1M143.3 94.8l-.1 .1M143.4 94.5h.1M143.5 93.6h.1M143.5 93.6v.3M143.5 94.2v.3"/>
<path d="M143.5 94.7v.1M143.6 94.5h.1M143.6 93.6v.2M143.6 94.1v.5M143.6 93.3l-.1 .1M143.6 94.8h.1M143.6 93.6h.1M143.6 93.3v.1M143.6 94.7v.1M143.6 93.3h.2M143.7 93.5h.1M143.8 93.4h.1"/>
<path d="M143.8 93.4h.2M143.9 93.2h-.1M144.1 94.4v.4zM144.1 93.3l.1 .6M144.2 94.8h.1M144.2 94.8h.2M144.2 93.4l.2 .4M144.2 93.4h.1M144.2 93.2h.1M144.3 93.3h-.3M144.4 93.3l-.3 .1M144.4 94.3l.2 .4"/>
<path d="M144.5 86.4h3.5M144.5 92.8l-.1 .4M144.6 93.3h.1M144.6 93.4v.4M144.6 93.4h.1M144.6 93.2h.1M144.6 91.9h.1M144.6 91.9v.5M144.7 92.8v1M144.7 94.3v.4h.6M144.7 94.8h.1M144.7 94.4v.4"/>
<path d="M144.8 91.9h.1M144.8 91.9v.5M144.9 91.9h.1M145.4 93.3l-.9 .1M145.4 94.8h-.8M145.6 91.9h.1M145.6 92l.3 .1M145.6 95v1M145.6 97.1v1M145.9 95v1M145.9 97.1v1M145.9 93.4h1.2"/>
<path d="M146 94.6v.3M146 94.7h.7M146 84.7v2.2M146 98.5h.4M146 97.9h.2M146 87.8v5.7M146 94.2v3.9M146.3 92.1h.3M146.3 94.8h.1M146.3 94.4v.4M146.4 93.3l-.1 .5M146.5 94h-.5v.3"/>
<path d="M146.5 94.9h.1M146.5 94.7l-.5 .1M146.5 94.5h.1M146.5 93.5v.4M146.5 93.2v.1M146.5 94.2v.3M146.6 92.1h.1M146.6 91.9h.1M146.8 97.9h-.3M146.8 98.5v.9M146.8 94.4v.4h-.7M146.8 93.3v.5"/>
<path d="M146.8 98.5h.4M146.8 94.7h.3M146.8 94.8h.1M146.8 94.4v.4M146.9 91.9h-2.3M147 94.7h.1M147 94.5h.1M147 94.9h.1M147 93.2l-.4 .1M147 93.5v.4M147 94.2v.3M147 97.9h.2"/>
<path d="M147.1 94h.4v.3M147.1 94.1v.8M147.1 93.3l.3 .5M147.2 84.7v2.2M147.2 87.8v5.8M147.2 94.3v3.8M147.3 95v1M147.3 97.1v1M147.4 94.8h.1M147.4 94.4v.4M147.4 94.7h.3M147.4 93.4h.3"/>
<path d="M147.4 92.4h-.3v.8M147.5 94.7l-.4 .1M147.5 94.5h.1M147.5 93.2v.7v-.4M147.5 94.2l.1 1.8M147.6 94.8h.1M147.6 93.3h.2M147.6 97.1v1M147.7 92.4l.2 .3M147.9 94.7h.3M147.9 93.4h1.2M147.9 92.5h.9"/>
<path d="M147.9 93l.3 .8M147.9 94.7h.1M147.9 94.5h.1M147.9 94.9h.1M147.9 93.5v.4M147.9 94.2v.3M147.9 94.7l.9 .1M148.2 94.8h.1M148.2 94.4v.4M148.2 94.8h.6M148.2 93.2h-4.1M148.4 94.7h.3"/>
<path d="M148.4 93.2h.3M148.5 94.9h.1M148.5 94.7h.1M148.5 94.5h.1M148.5 93.5v.4M148.5 93.2v.1M148.5 94.2v.3M148.9 94.7h.2M148.9 93.2h.2M149 94.7h.1M149 94.5h.1M149 94.9h.1"/>
<path d="M149 93.2v.1M149 93.5v.4M149 91.9h4.2M149.4 94.7h.3M149.4 93.4h.7M149.4 93.2h4.3M149.5 94h-.5v.9M149.5 94.9h.1M149.5 94.7l-.5 .1M149.5 94.5h.1M149.5 93.5v.4M149.5 93.2v.1"/>
<path d="M149.5 94.2v.3M149.6 94.8h.5M149.6 92.5h.8M149.8 86.4h3.6M149.9 94.7h.2M150 94.7h.1M150 94.5h.1M150 94.9h.1M150 93.2v.1M150 93.5v.4M150 94.2v.3M150.1 94h.4v.3"/>
<path d="M150.1 94.8h.1M150.1 94.4v.4M150.4 93.3l-.3 .5M150.4 94.1v.8M150.4 94.7h.3M150.4 93.4h.3M150.5 94.9h.1M150.5 94.7l-.9 .1M150.5 94.5h.1M150.5 93.5v.4M150.5 93.2v.1M150.5 94.2v.7"/>
<path d="M150.6 93.3l.1 .5M150.6 92.4h-.2v.8M150.7 95v1M150.7 97.1v1M150.7 94.8h.1M150.7 94.4v.4M150.9 94.7h.3M150.9 93.4h.3M151 92.4h.2M151 94.7h.1M151 94.5h.1M151 94.9h.1"/>
<path d="M151 93.2v.1M151 93.5v.4M151 94.2v.3M151 95v1M151 97.1v1M151.1 87.8v5.7M151.1 84.7v2.2M151.1 98.5h.4M151.1 97.9h.2M151.2 94.1l-.1 4M151.4 94.7h.3M151.4 93.4h.3"/>
<path d="M151.5 94.9h.1M151.5 94.7h.1M151.5 94.5h.1M151.5 93.5v.4M151.5 93.2v.1M151.5 94.2v.3M151.8 97.9h-.3M151.8 94.7h.3M151.8 93.4h.3M151.9 98.5h.4M152 94.7h.1M152 94.5h.1"/>
<path d="M152 94.9h.1M152 93.2v.1M152 93.5v.4M152 94.2v.3M152.1 97.9h.2M152.3 87.8v5.8M152.3 84.7v2.2M152.3 94.3v3.8M152.4 95v1M152.4 97.1v1M152.4 94.7h.3M152.4 93.4h.3"/>
<path d="M152.5 94.9h.1M152.5 94.7h.1M152.5 94.5h.1M152.5 93.5v.4M152.5 93.2v.1M152.5 94.2v.3M152.7 95v1M152.7 97.1v1M152.9 94.7h.3M152.9 93.4h.3M152.9 94.7h.1M152.9 94.5h.1"/>
<path d="M152.9 94.9h.1M152.9 93.2v.1M152.9 93.5v.4M153.4 94.7h.3M153.4 93.4h.3M153.5 94h-.6v.9M153.5 94.9h.1M153.5 94.7l-.6 .1M153.5 94.5h.1M153.5 93.5v.4M153.5 93.2v.1M153.5 94.2v.3"/>
<path d="M153.9 94.7h.2M153.9 93.4h.2M154 94.7h.1M154 94.5h.1M154 94.9h.1M154 93.5v.4M154 94.2v.3M154 94h.6v.3M154.1 93.2l-.1 .1M154.4 94.7h.3M154.4 93.4h.3M154.4 93.2h.3"/>
<path d="M154.5 94.9h.1M154.5 94.7l-.5 .1M154.5 94.5h.1M154.5 93.5v.4M154.5 93.2v.1M154.5 94.2l.1 .7M154.8 94.7h.3M154.8 93.2h3.9M154.8 93.4h.3M155 94.7h.1M155 94.5h.1M155 94.9h.1"/>
<path d="M155 93.2v.1M155 93.5v.4M155 94.2v.3M155.2 86.4h3.5M155.3 91.9h4.2M155.4 94.7h.3M155.4 93.4h.3M155.5 94.9h.1M155.5 94.7h.1M155.5 94.5h.1M155.5 93.5v.4M155.5 93.2v.1"/>
<path d="M155.5 94.2v.3M155.8 95v1M155.8 97.1v1M155.9 94.7h.3M155.9 93.4h.3M155.9 94.7h.1M155.9 94.5h.1M155.9 94.9h.1M155.9 94.2v.3M155.9 93.2v.1M155.9 93.5v.4M156.1 95v1"/>
<path d="M156.1 97.1v1M156.2 87.8v5.7M156.2 97.9h.2M156.2 84.7v2.2M156.2 94.2v3.9M156.2 98.5h.3M156.4 94.7h.3M156.4 93.4h.3M156.5 94.9h.1M156.5 94.7h.1M156.5 94.5h.1M156.5 93.5v.4"/>
<path d="M156.5 93.2v.1M156.5 94.2v.3M156.8 94.7h.3M156.8 93.4h.3M156.9 97.9h-.3M157 98.5h.4M157 94.7h.1M157 94.5h.1M157 94.9h.1M157 93.2v.1M157 93.5v.4M157 94.2v.3"/>
<path d="M157.2 97.9h.2M157.4 87.8v5.8M157.4 84.7v2.2M157.4 94.3v3.8M157.4 94.7h.3M157.4 93.4h.3M157.5 94.9h.1M157.5 94.7h.1M157.5 94.5h.1M157.5 93.5v.4M157.5 93.2v.1M157.5 94.2v.3"/>
<path d="M157.8 95v1M157.8 97.1v1M157.9 94.7h.3M157.9 93.4h.3M158 94.7h.1M158 94.5h.1M158 94.9h.1M158 93.2v.1M158 93.5v.4M158 94.2v.3M158.4 94.7h.3M158.4 93.4h.3"/>
<path d="M158.5 94.9h.1M158.5 94.7h.1M158.5 94.5h.1M158.5 93.5v.4M158.5 93.2v.1M158.5 94.2v.3M158.9 94.7h.3M158.9 93.4h.3M159 94.7h.1M159 94.5h.1M159 94.9h.1M159 93.5v.4"/>
<path d="M159 94.2v.3M159.2 93.2l-.2 .1M159.4 94.7h.3M159.4 93.4h.3M159.4 93.2h.3M159.5 94.9h.1M159.5 94.7h.1M159.5 94.5h.1M159.5 93.5v.4M159.5 93.2v.1M159.5 94.2v.3M159.8 94.1v.8"/>
<path d="M159.8 94.7h.3M159.8 93.2h.3M159.8 93.4h.3M160 92.4l-.2 .8M160 94.7h.1M160 94.5h.1M160 94.9h.1M160 93.2v.1M160 93.5v.4M160.1 94.8h.1M160.1 94.4v.4M160.3 92.4h.3v.8"/>
<path d="M160.4 93.3l-.3 .5M160.4 94.7h.3M160.4 93.4h1.3M160.4 93.2h3.6M160.5 94h-.6v.9M160.5 86.4h3.5M160.5 94.9h.1M160.5 94.7h.1M160.5 94.5h.1M160.5 93.5v.4M160.5 93.2v.1M160.5 94.2v.3"/>
<path d="M160.6 94.1v.8M160.6 92.5h.7M160.6 93.3l.1 .5M160.7 95v1M160.7 97.1v1M160.7 94.8h.1M160.7 94.4v.4M160.7 94.8h.7M160.9 95v1M160.9 97.1v1M160.9 94.7h.3M160.9 94.7h.1"/>
<path d="M160.9 94.5h.1M160.9 94.9h.1M160.9 93.2v.1M160.9 93.5v.4M160.9 94.2v.3M161.1 94h.4v.3M161.2 95v1M161.2 97.1v1M161.3 97.9h.2M161.3 84.7v2.2M161.3 87.8v5.7M161.3 94.2v3.9"/>
<path d="M161.3 98.5h.3M161.4 94.7h.3M161.5 94.9h.1M161.5 94.7l-1.6 .1M161.5 94.5h.1M161.5 93.5v.4M161.5 93.2v.1M161.5 94.2v.7M161.6 91.9h2.1M161.7 98.5v.9M161.9 94.7h.7M162 94.7h.1"/>
<path d="M162 94.5h.1M162 94.9h.1M162 93.2v.1M162 93.5v.4M162 94.2v.3M162 97.9h-.3M162 98.5h.5M162.1 94.8h.6M162.1 92.5h.8M162.1 94.8h.8M162.3 97.9h.2M162.5 84.7v2.2"/>
<path d="M162.5 87.8v5.8M162.5 94.3v3.8M162.7 95v1M162.7 97.1v1M162.7 94.8h.1M162.7 94.4v.4M162.7 93.3l-.8 .1M162.8 95v1M162.8 97.1v1M162.9 93.3l-.2 .5M162.9 94.1v.8M163.2 92.4h-.3v.8"/>
<path d="M163.2 93.3l.2 .5M163.3 93.4h.7M163.4 94.8h.1M163.4 94.4v.4M163.5 92.4h.2M163.6 94.6v.3M163.6 94.8h.5M163.7 91.9h.1M163.7 91.9v.5M163.7 92.4v.8l.1-.4M163.7 94.1v.8M163.8 94.3v.4h-.6"/>
<path d="M163.8 91.9l.1 .5M163.8 91.9h.1M163.9 93.4v.4M163.9 93.4h.1M163.9 93.2h.1M164 94.7h.1M164 94.3v.4M164 92.8l.1 .4M164.1 94h-.5v.3M164.2 93.4h.1M164.2 93.2h.2M164.2 93.4v.4"/>
<path d="M164.2 93.2h.1M164.5 93.4h.1M164.5 93.2h.3M164.6 93.4h.1M164.7 94h.5v.3M164.7 94.8h.5M164.8 93.4h.1M164.8 93.5h.1M164.8 94.1v.4M164.8 93.6v.2M164.9 93.3l.1 .1M164.9 93.3h.1"/>
<path d="M164.9 94.7h.1M165 94.7h.1M165.1 93.6h.1M165.1 94.5h.1M165.1 93.6v.3M165.1 94.2v.3M165.1 94.6h.1M165.2 94.6l-.1 .2M165.3 94.7h.3M165.4 93.3l.1 .6M165.4 94.8l.1 .1M165.5 93.4h.1"/>
<path d="M165.5 94.3l-.1 .5M165.5 94.7l.5 .1M165.6 93.3h.4M165.9 86.4h3.5M165.9 95v1M165.9 97.1v1M165.9 94.7h.3M166 93.3h-.6M166.2 94.9h.1M166.4 92.9v.6M166.4 94.2v1.8M166.4 97.1v1"/>
<path d="M166.4 98.5h.3M166.4 87.8v1.3M166.4 90.4v1.3M166.5 93.3h.5v.6M166.5 94.8h.4M166.8 93.3h.1M166.8 94h.1M166.8 93.4v.1M166.8 93.6v.3M166.9 93.3h.1M166.9 93.2h.1M166.9 93.3l.1 .1"/>
<path d="M167 94h.1M167 93.4v1.5M167 94.7l-.1 .1M167 93.9h.1M167 93.2h.1M167 94.4v.4M167.1 98.5h.4M167.5 87.8v1.4M167.5 90.5v1.2M167.5 92.9v.7M167.5 94.3v1.7M167.5 97.1v1"/>
<path d="M167.7 93.2h.1M167.8 94.3h.3M167.8 94.5h.3M167.8 94.7h.1M167.8 94.3h.1M167.8 94.5v.1M167.8 94.8v.1M167.8 94.7h.3M167.8 93.1h.1M167.8 93.3h-1.3M167.9 92.9l-.1 .2M167.9 95v1"/>
<path d="M167.9 97.1v1M167.9 92.5v.2M167.9 92.5h.1M168 92.5h.1M168 92.5h-.1M168.1 92.4h.1M168.1 93l-.1 .2M168.1 92.4h.8M168.1 92.6v.2M168.1 92.6h.8M168.2 92.6v.2M168.2 93.2v.2"/>
<path d="M168.5 94.3h.3M168.5 94.5h.3M168.5 94.7h.3M168.8 94.3h.1M168.8 94.5v.1M168.8 94.7h.1M168.8 94.8v.1M168.9 93.4h1.1M169.2 98.5v.9M169.5 94.8h.1M169.5 94.4v.4M169.5 94.3v.4l.5 .1"/>
<path d="M169.6 93.3l-.1 .6M169.7 93.2h.1M169.7 92.6h1.8M169.8 93.3h.1M170 93.4v.5M170 94.4v.5M170 93.3h-.5v.5M170 91.9v.1M170 92.2v.2M170 91.9h.1M170.1 91.8h.1M170.1 91.8h1.3"/>
<path d="M170.3 92.5h.1M170.3 92.9v.3M170.3 93.2h.1M170.3 93.3l1.2 .1M170.3 92.5v.2M170.3 92.4h.1M170.4 92.5h.1M170.4 92.8h.1M170.4 92.4v.1M170.4 92.4h.1M170.4 93v.2M170.4 94.1h.1"/>
<path d="M170.4 94.8h.1M170.4 94.1l.1 .3M170.4 94.6v.2M170.4 93.2l.1 .5M170.5 94.8h.1M170.5 94.4h.1M170.5 94h.1M170.5 94.8l.6 .1M170.5 93.3h.5l.1 .5M170.6 94.5h.1M170.7 94.6h.1M170.7 94.7h.2"/>
<path d="M170.9 94h.8M171 93.4v.5M171 94.3v.4M171 94.7l-.1 .1M171 95v1M171 97.1v1M171 94.8h.1M171 94.1h.1M171 94.8h.7M171 94.9h.1M171 94.7h.1M171.1 94.4v.4"/>
<path d="M171.1 94.8l-.1 .1M171.2 86.4h3.5M171.2 94.7h.6M171.4 94.9h.4M171.4 94.9h.1M171.4 94.7h.1M171.4 94.8v.1M171.4 92.9v.6M171.4 94.2v1.8M171.4 97.1v1M171.4 98.5h.4M171.4 87.8v1.3"/>
<path d="M171.4 90.4v1.3M171.5 92.4h-1.8M171.7 99.8h.1M171.7 99.8l-.1 .2M171.8 99.6h.1M171.8 98.5v1.9M172.2 98.5h.3v.9M172.2 94.9h.4M172.2 94.7h.6M172.4 94h.9M172.4 94.8h.6M172.6 92.6h1.8"/>
<path d="M172.6 87.8v1.4M172.6 90.5v1.2M172.6 92.9v.7M172.6 94.3v1.7M172.6 97.1v1M172.7 94.7h.1M172.7 94.8l.1 .1M172.7 91.8h1.2M173 97.1v1M173 94.1h.1M173 94.8h.1M173 94.9h.1"/>
<path d="M173 94.7h.1M173.1 94.7l-.1 1.3M173.1 94h.1M173.1 94.8h.1M173.4 94.6l-.3 .1M173.4 94h.1M173.5 94.5h.1M173.5 94.1v.3M173.5 93.4v.3M173.6 94.8h.1M173.6 94h.1M173.6 94.1h.1"/>
<path d="M173.6 94.1v.2M173.6 94.6v.2M173.6 92.5h.1M173.6 92.4v.1M173.6 92.4h.1M173.6 92.6v.2M173.6 93v.4M173.7 92.5h.1M173.7 92.4h.1M173.7 92.5v.2M173.7 98.5v.9M173.7 92.9l.1 .3"/>
<path d="M173.8 92.5h.1M173.8 94.6v.3M173.8 94.8h.5M173.8 93.2h.1M173.8 93.3l-1.3 .1M173.9 91.8h.1M174 93.4h1.2M174 98.5v1.7M174 91.9h.1M174 91.9v.2M174 92.2v.2M174.1 99.9l.1 .2"/>
<path d="M174.1 99.9h.1M174.1 93.4v.5M174.1 94.4v.5M174.1 99.9l-1.6 .6M174.2 93.3h.1M174.2 99.9h.1M174.3 93.2h.1M174.3 94h-.5v.3M174.4 93.2h.1M174.4 99.9h.1M174.4 92.4h-1.8M174.4 99.9h.3"/>
<path d="M174.7 98.5v1.9M174.9 94h.5v.3M174.9 94.8h.5M175.1 99.9h.6M175.2 94.3h.3M175.2 94.5h.3M175.2 94.7h.1M175.2 94.3h.1M175.2 94.5v.1M175.2 94.8v.1M175.2 94.7h.3M175.2 92.4h.7"/>
<path d="M175.2 92.6l.7 .2M175.3 93.2h-9.5M175.4 94.6v.3M175.8 92.6v.2M175.8 93.2v.2M175.9 94.3h.3M175.9 94.5h.3M175.9 94.7h.3M175.9 92.4l.1 .1M175.9 92.4h.1M176 98.5v.7M176 100l.3 .3"/>
<path d="M176 92.4h.1M176 93v.2M176 92.5h.1M176.1 92.5h.1M176.1 95v1M176.1 97.1v1M176.1 92.5v.2M176.2 93.2h3.8M176.2 92.9v.2M176.2 94.3h.1M176.2 94.5v.1M176.2 94.7h.1"/>
<path d="M176.2 94.8v.1M176.2 93.1h.1M176.2 93.3v.1M176.3 93.4h.9M176.3 93.2h.1M176.5 92.9v.6M176.5 94.2v1.8M176.5 87.8v1.3M176.5 90.4v1.3M176.5 97.1v1M176.6 86.4h3.5M176.9 98.5h-.4v.7"/>
<path d="M177 93.4v.1M177 93.6v.2M177 93.8h.1M177 93.9h.1M177 93.9v.4M177 94.6v.3M177.1 94h.1M177.1 93.2h.1M177.2 93.3h.1M177.2 94h.1M177.2 93.8h.1M177.2 93.9h.1"/>
<path d="M177.2 93.4h.1M177.2 93.4v.1M177.2 93.6v.2M177.3 98.5h.4M177.6 94.1h.1M177.6 94.8h.1M177.6 94.1l.1 1.9M177.7 87.8v1.4M177.7 90.5v1.2M177.7 92.9v.7M177.7 97.1v1M177.7 94.8h.1"/>
<path d="M177.8 94h.1M178 94h.1M178.1 95v1M178.1 97.1v1M178.2 94.8h.1M178.2 94h.1M178.3 94.8h.1M178.3 94.1h.1M178.3 94.8h.6M178.3 94l1.1 .1M178.9 94v.3M178.9 94.6v.3"/>
<path d="M179 98.5v1.6M179.6 94.8h.6M179.6 94h.9v.3M180.2 94.1h.1M180.2 94.8h.1M180.3 94h.1M180.3 94.8h.1M180.5 94.8h.1M180.5 94.6v.3M180.6 94h.2M180.8 94.8h.1M180.8 94h.1"/>
<path d="M180.8 94.1v.2M180.8 94.6v.2M181 99.1h.1M181 98.5v.2M181 99v1.6M181.1 98.7l-.1 .2M181.2 95v1M181.2 97.1v1M181.3 98.4l-.1 .2M181.5 98.5v.1M181.5 99.1h-.2M181.6 98.2h.1"/>
<path d="M181.6 87.8v1.3M181.6 90.4v1.3M181.6 92.9v.6M181.6 94.2v1.8M181.6 97.1v1M181.6 98.5h.3M181.6 80.1v.8M181.7 98.7h.1M181.7 98.2h.1M181.7 98.7l-.2 1.8M181.9 93.2h3.5M181.9 86.4h3.6"/>
<path d="M181.9 98.2h.1M182.1 94h.1M182.1 93.4h.1M182.1 93.4v.1M182.1 93.6v.3M182.1 93.3h.1M182.2 98.6l-.4 .1M182.2 94.6v.3M182.2 94h.1M182.3 98.5h.4v.4M182.3 93.9h.1M182.3 93.4v.1"/>
<path d="M182.3 93.6l-.1 .7M182.3 93.2h-.1M182.5 98.6h.3M182.5 95v1M182.5 97.1v1M182.7 99.5v.5M182.8 87.8v1.4M182.8 90.5v1.2M182.8 92.9v.7M182.8 94.3v1.7M182.8 97.1v1M183 93.2h.1"/>
<path d="M183 94.3h.4M183 94.7h.1M183 94.3h.1M183 94.5v.1M183 94.8v.1M183 94.7h.4M183 94.5h.4M183 93.1h.1M183.1 93.3l-1 .1M183.1 92.9v.2M183.2 95v1M183.2 97.1v1"/>
<path d="M183.2 92.5v.2M183.2 92.5h.1M183.3 92.5h-.1M183.3 93v.2M183.3 92.4h.1M183.3 92.4h.8M183.3 92.4l-.1 .1M183.4 92.6h.7M183.4 92.6l-.1 .2M183.4 92.6v.2M183.4 93.2v.2M183.8 94.3h.3"/>
<path d="M183.8 94.7h.3M183.8 94.5h.3M183.9 94.6v.3M183.9 94.8h.5M184.1 94.3h.1M184.1 94.5v.1M184.1 94.7h.1M184.1 94.8v.1M184.1 93.4h1.2M184.4 94h-.5v.3M184.9 93.2h1.6M184.9 92.4h1.8"/>
<path d="M184.9 92.6h1.8M185 93.2h.1M185 94h.5v.3M185 94.8h.5M185 93.3h.1M185.1 93.3h.1M185.2 93.4v.5M185.2 94.4v.5M185.2 91.9v.1M185.2 92.2v.2M185.3 91.9h.1M185.4 91.8h1.2"/>
<path d="M185.4 91.8h.1M185.5 92.5h.1M185.5 93.2h.1M185.5 93.3l1.3 .1M185.5 94.6v.3M185.5 92.4h.1M185.5 92.9v.3M185.6 92.5h.1M185.6 92.4h.1M185.6 92.5l-.1 .2M185.6 93l.1 .4M185.6 92.4v.1"/>
<path d="M185.7 94.1h.1M185.7 94.8h.1M185.7 94.1v.2M185.7 94.6v.2M185.7 92.6l-.1 .2M185.7 92.6v.2M185.7 94h.1M185.8 94h.1M185.8 94.1v.3M185.8 93.4v.3M185.8 94.5h.1M185.9 94.6h.1"/>
<path d="M186 94.7h.1M186 94h.9M186.3 97.1v1M186.3 94.9h.1M186.3 94.7h.1M186.3 94.8v1.2M186.3 94.8h.1M186.3 94.1h.1M186.3 94.8h.6M186.4 94.7h.7M186.5 94.9h.1M186.6 94.7h.1"/>
<path d="M186.6 94.9h.1M186.6 94.8v.1M186.6 87.8v1.3M186.6 90.4v1.3M186.6 92.9v.6M186.6 94.2v1.8M186.6 97.1v1M186.6 94.9h.4M187.2 93.2h3.5M187.3 86.4h3.5M187.4 94.9h.6M187.5 94.7h.5"/>
<path d="M187.6 94.8h.6M187.6 94h.9M187.8 80.1v.8M187.8 92.6h1.8M187.8 92.4h1.8M187.9 87.8v1.4M187.9 90.5v1.2M187.9 92.9v.7M187.9 94.3v1.7M187.9 97.1v1M187.9 91.8h1.3M187.9 94.9h.1"/>
<path d="M187.9 94.7h.1M187.9 94.8v.1M188.1 93.2h2.4M188.2 94.9h.1M188.2 95v1M188.2 97.1v1M188.2 94.7h.1M188.2 94.1h.1M188.2 94.8h.1M188.3 94.9h.1M188.3 94.7h.1M188.3 94.7h.2"/>
<path d="M188.3 94h.1M188.3 94.8h.1M188.6 94.6h.1M188.6 94h.2M188.7 94.5h.1M188.8 94.4h.1M188.8 94.1v.3M188.8 94.8h.1M188.8 94h.1M188.8 94.1v.2M188.8 94.6v.2M188.8 92.6v.2"/>
<path d="M188.8 93.2v.5M188.9 92.6v.2M188.9 93v.2M188.9 92.5h.1M188.9 92.4h.1M188.9 95v1M188.9 97.1v1M189 92.5h.1M189 92.5v.2M189 92.9l.1 .3M189 93.2h.1M189 93.3l-1.2 .1"/>
<path d="M189 94.6v.3M189 94.8h.5M189.2 91.8h.1M189.2 95v1M189.2 97.1v1M189.2 93.4h1.3M189.3 91.9v.2M189.3 92.2v.2M189.3 91.9h.1M189.4 93.4v.5M189.4 94.4v.5M189.4 93.3h.1"/>
<path d="M189.5 93.3h.1M189.5 94h-.5v.3M189.5 93.2h.1M189.6 93.2h.1M190.1 94h.5v.3M190.1 94.8h.5M190.5 92.6h.7l-.1 .2M190.5 92.4h.7M190.5 94.3h.3M190.5 94.7h.3M190.5 94.5h.3M190.5 94.7h.1"/>
<path d="M190.5 94.3h.1M190.5 94.5v.1M190.5 94.8v.1M190.6 94.6v.3M191.1 93.2v.2M191.2 92.4h.1M191.2 92.4v.1M191.2 94.3h.3M191.2 94.7h.3M191.2 94.5h.3M191.2 93l.1 .2M191.3 95v1"/>
<path d="M191.3 97.1v1M191.3 92.4h.1M191.3 92.5h.1M191.3 92.5l.1 .2M191.4 93.2h.9M191.4 92.9l.1 .2M191.5 93.3v.1M191.5 94.3h.1M191.5 94.5v.1M191.5 94.7h.1M191.5 94.8v.1M191.5 93.1h.1"/>
<path d="M191.5 93.4l1 .1M191.6 93.2h.1M191.7 87.8v1.3M191.7 90.4v1.3M191.7 92.9v.6M191.7 94.2v1.8M191.7 97.1v1M192.3 93.8h.1M192.3 93.9h.1M192.3 94h.1M192.3 93.4v.1M192.3 93.6v.2"/>
<path d="M192.3 93.9v.4M192.3 93.2h.1M192.3 94.6v.3M192.4 93.2h.1M192.4 94h.1M192.4 93.3h.1M192.5 93.8h.1M192.5 93.9h.1M192.5 93.6v.2M192.6 93.2h3.5M192.6 86.4h3.5M192.9 87.8v1.4"/>
<path d="M192.9 90.5v1.2M192.9 92.9v.7M192.9 94.3v1.7M192.9 97.1v1M193.3 95v1M193.3 97.1v1M196.4 95v1M196.4 97.1v1M196.8 87.8v1.3M196.8 90.4v1.3M196.8 92.9v.6M196.8 94.2v1.8"/>
<path d="M196.8 97.1v1M197.6 94.1h.1M197.6 94.8h.1M197.6 94.1v.2M197.6 94.6v.2M197.7 94h.1M197.7 94.8h.1M197.9 86.4h3.6M198 87.8v1.4M198 90.5v1.2M198 92.9v.7M198 94.3v1.7"/>
<path d="M198 97.1v1M198 94h.9M198.2 94.8h.1M198.2 94.1h.1M198.2 94.8h.7M198.4 95v1M198.4 97.1v1M198.7 93.3h.4M198.7 93.3l.1 .5M198.7 92.8h.4M198.7 92.8v.2M198.7 93.2v.1"/>
<path d="M198.8 92.4v.4M198.9 94.3v.4h2.3M199.5 92.8h.9M199.6 94.1v.8M199.6 94h.8M199.6 94.8h.6M199.8 92.4h-.2v.8M199.9 94.2v.3M199.9 93.9v.2M199.9 93.5v.3M199.9 92.8v.3M199.9 94.7v.2"/>
<path d="M199.9 94.3h.5M200.1 92.4l.3 1-.9-.1M200.2 94.1h.1M200.2 94.8h.1M200.3 94h.1M200.3 94.8h.1M200.4 93.3h.5M200.4 94.5h.5M200.4 93.7h.5M200.4 93.6v.3M200.4 94.1v.8M200.4 92.5h.8"/>
<path d="M200.4 94.8h.8M200.6 94h.1M200.8 94.8h.1M200.8 94h.1M200.8 94.1v.2M200.8 94.6v.2M200.9 91.5h-1.9l-.1 .4M200.9 93.3h1.5M200.9 92.8h1.5M200.9 94.3h.5M201.4 93.9h.1M201.4 92.8v.4h-3.5"/>
<path d="M201.4 93.5v.3M201.4 93.9v.2M201.4 94.2v.3M201.4 94.7v.2M201.5 95v1M201.5 97.1v1M201.5 93.3h.6M201.5 94.5h.6M201.5 93.7h.6M201.9 87.8v1.3M201.9 90.4v1.3M201.9 92.9v.6"/>
<path d="M201.9 94.2v1.8M201.9 97.1v1M202 92.5h.8M202 94.8h.8M202.1 93.6v.3M202.1 94.2v.4M202.1 94.7v.2M202.8 94.1v.8M202.9 93.7h.1M202.9 93.6v.1M202.9 93.9v.3M202.9 94.6v.3"/>
<path d="M202.9 94.3h.5M202.9 92.8v.1M202.9 93.2v.2M203 92.4h-.2v.8M203 91.5h2.1M203.1 87.8v1.4M203.1 90.5v1.2M203.1 92.9v.7M203.1 94.3v1.7M203.1 97.1v1M203.3 93.2h1.8M203.3 86.4h1.8"/>
<path d="M203.3 92.4l.2 .8M203.4 94.5h.5M203.4 93.7h.5M203.4 93.6v.3M203.4 94.2v.4M203.4 94.8v.1M203.4 93.3h1.6M203.4 92.8h1.3M203.5 97.1v1M203.5 94.1v1.9M203.7 94.7h2.3M203.7 94.8h.1"/>
<path d="M203.7 94.6v.2M203.7 93.9h.2M203.7 93.9v.3M203.8 94.8h1.3M203.8 94.9h.1M203.8 93.9h.1M203.9 93.3l-.5 .1M204 94.3h.7M204.1 93.9h.2M204.3 93.6v.3M204.3 94.8l-.1 .1M204.5 94.2v.3"/>
<path d="M204.5 93.9v.2M204.5 93.5v.3M204.5 93.3h.6M204.5 92.8v.3M204.5 94.7v.2M204.5 94.5h.6M204.5 93.7h.6M204.7 94.8h.1M204.9 92.7h-.6v.4M204.9 92.8h.2M205 94.3h.1M205.5 92.7h.7v.3"/>
<path d="M205.5 93.3h.5M205.8 94.8h.1M206 94.3h.5v.6M206.2 93.5v.4M206.2 93.9h.2M206.3 94.9h.1M206.3 94.7h1.2M206.3 94.5h.6M206.3 93.3h.9M206.3 93.7h.7M206.4 93.9h-.2M206.5 92.8h.8"/>
<path d="M206.5 93.3v.5M206.6 93.9l.2 .3M206.7 94.8h-1.2M206.7 94.8h.1M206.7 93.9h-.2M206.8 94.6v.2M207 94.3h.6M207.3 95v1M207.3 97.1v1M207.3 94.8h.3M207.3 93.3v.5M207.3 94.3v.6"/>
<path d="M207.6 93.6l.5 .1M207.6 93.9v.3M207.6 94.5h.5M207.6 94.6v.3M207.6 92.8v.1M207.6 93.2v.2M207.9 94.8h.2M208.1 93.3h1.5M208.2 92.8h1.4M208.8 94.7h1.3M209.1 94.3h.5M209.1 94.2v.3"/>
<path d="M209.1 93.9v.2M209.1 93.5v.3M209.1 92.8v.3M209.1 94.7v.1M209.2 95v1M209.2 97.1v1M209.2 94.8h.2M209.6 94.8h.1M209.7 93.2v.5M209.7 94.3v.6M210.1 93.2h.1M210.1 93.3v.1"/>
<path d="M210.1 94.5h.3M210.1 93.3h.8M210.1 92.8h.8M210.1 94.3h.5M210.3 93l-.1 .2M210.3 92.4l-.2 .1M210.4 92.6v.2M210.4 93.2v.2M210.5 92.4v.8M210.5 94.1v.8M210.6 93.9h.1M210.6 92.8v.3"/>
<path d="M210.6 93.5v.3M210.6 93.9v.2M210.6 94.2v.3M210.6 94.7v.2M210.8 94.5h.2M211 94.7h.2M211.1 92.6l-.8 .2M211.4 92.8l.3 .2M211.4 93.3h.3M211.6 94.3l-.2 .4M211.7 92.4v.1M211.7 93.2v.1"/>
<path d="M211.7 93.3v.5M211.9 92.6h1.8M212.5 93.2h.1M212.5 93.3v.1M212.6 93v.2M212.6 92.6v.2M212.6 93.2v.2M212.8 93.4h1.9M213.1 94.8h.1M213.1 94.4l.1 .5M213.2 94.7h.1M213.2 94.9h.1"/>
<path d="M213.4 93.3l-.3 .5M213.5 94.9h.1M213.6 93.3l.1 .5M213.6 94.7h.4M213.7 94.8h.7M213.7 94.8h.1M213.7 94.4v.4M213.9 93.3v.5M213.9 93v.2M213.9 93.4h.1M213.9 93h.1M213.9 94.8h.1"/>
<path d="M213.9 93.9v.3M213.9 94.6v.2M213.9 93.9h.6M213.9 93.5v.4M213.9 94l.5 .1M213.9 94.8h.5M214 93.9h.1M214 94.3v.4M214 93.4l.1 .4M214 93.4h.1M214 93h.1M214 93.3v.1"/>
<path d="M214.1 92.7l-.1 .5M214.1 94.3v.4M214.2 94.8h.1M214.2 93.9h.1M214.2 93.9h.3M214.2 91.8l-.2 .4M214.3 94.9h.1M214.3 94.1v.3M214.3 93.4v.5M214.3 93v.2M214.3 93h.4M214.3 93.4h.1"/>
<path d="M214.3 93h.1M214.4 92.7h-.5v.3M214.6 94.8h.2M214.7 94.6l-.4 .1M214.8 94.8l.2 .1M214.8 94.8h.1M214.8 93.4h1.5M214.8 92.6h1.8M214.9 92.4l-.1 .8M215 92.7h.6M215 94.8h1.4M215 93.9h.6"/>
<path d="M215 93l1.2 .2M215.1 94.1h.1M215.1 94.8h.1M215.1 94.1v.2M215.1 93.7h.1M215.1 93.7l.1 .3M215.1 93.6v.1M215.2 92.4h.5M215.2 94h.1M215.2 94.8h.1M215.2 93l-.1 .5M215.2 94.4l.1 .3"/>
<path d="M215.3 94.7h.1M215.3 94.8h.1M215.3 93.9h.1M215.3 94.6h.1M215.3 93v1.1M215.3 94.3v.1M215.3 94.6v.1M215.3 94.6l-.2 .2M215.3 92.4v.3M215.3 93.3h.3M215.3 93.7h.3M215.3 93.7h.1"/>
<path d="M215.3 93.3h.1M215.4 94.8h.1M215.4 93l-.1 .3M215.4 94.4v.3M215.4 93.9h-.4M215.4 92.4v.3M215.5 92.4h.1M215.6 93.9h.1M215.6 94.8h.1M215.6 92.7v.3M215.6 93.5v.7M215.6 94.6v.2"/>
<path d="M215.6 92.7h.1M215.6 92.4v.1M215.6 92.5h.8M215.7 94.8h.1M215.7 94.1h.1M215.7 93.4h.1M215.7 94.8l-.4 .1M215.7 94.4v.2M215.7 94.7v.1M215.9 92.6v.2M215.9 93.2v.2M215.9 93.7h.6"/>
<path d="M215.9 93v.2M216 93.2h.1M216 93.3v.1M216 92.4h.2M216.1 94.7h-2.1M216.1 94.2v.1M216.1 93.8v.3l-1.3-.1v.8M216.1 93.3v.2M216.1 94.8v.1M216.2 93.4h.1M216.2 93.5h.1M216.2 94.6h.3"/>
<path d="M216.2 93.6v.2M216.2 94.1v.4M216.2 94.7v.2M216.2 93.3v.1M216.4 94.8h.1M216.4 93.3v.5M216.4 94.4v.4M216.5 94.8h2.7M216.5 94.5l-.4 .1M216.5 93.3h-.8M216.9 94.6h.3M217 94v.3"/>
<path d="M217 94.6l.2 .2M217 93.7h.6M217 93.3h.6M217 94.5h.8M217.2 92.5h.7M217.2 94.8h.1M217.2 92.4v.8M217.2 94v.9M217.2 94.7h.1M217.2 93.4l1.4-.1 .1 1.6M217.3 93.9h.1M217.3 94.7h.1"/>
<path d="M217.4 94.2h.1M217.4 94.5h.1M217.4 94h.1M217.4 93.3v.2M217.4 93.8v.5M217.4 94.5v.4M217.4 92.6l.8 .2M217.4 93.9h.1M217.5 94.7l-.7 .1M217.6 93.9h.1M217.6 94.8h.1M217.6 93.3v.3"/>
<path d="M217.6 93.9v.4M217.6 94.1h.1M217.6 94.6v.2M217.7 94.8h.1M217.8 94.1h.1M217.8 94.8h.1M217.8 94h.1M217.9 93.4v.5M217.9 93.8h.2M217.9 93.9h.1M217.9 93.8h.1M217.9 92.4v.8"/>
<path d="M217.9 94.1v.8M217.9 93.7h.3M218 92.4h.1M218 93.9h.1M218 94h.1M218 92.5h.1M218 93.8h.1M218.1 93.9l-.1 .1M218.1 92.4h.1M218.1 93.9h.1M218.1 92.4v1.5M218.1 94.1v.8"/>
<path d="M218.1 93.8h.1M218.1 92.4v.3M218.1 94h.1M218.1 92.5h.1M218.1 93v.3M218.1 92.4l.1 .1M218.1 94.9h.1M218.1 94.1l.3 .4M218.1 93.9v-.5v.6M218.1 92.4v.8M218.1 93.9h.2M218.2 92.4v.3"/>
<path d="M218.2 93.9h.1M218.2 93.9l-.1 .1M218.2 94h.1M218.2 94.8h.1M218.2 93v.6M218.2 93.8v.5M218.2 94.8h.4M218.3 94h.1M218.3 93l-.1 .3h-.6M218.3 94.4l-.1 .4M218.3 92.5h.1M218.3 94.8h.1"/>
<path d="M218.3 94.1v.2M218.3 94.6v.2M218.3 93.7h.1M218.3 93.7v.3M218.3 93.3v.2M218.3 93.6v.1M218.4 94l.2 .8M218.4 94.8l.1 .1M218.4 93.2h.1M218.4 93.3l.1 .6M218.4 94.7h.3M218.5 94.6l-.4 .1"/>
<path d="M218.5 93h-1.3M218.5 93.4h.1M218.5 93.3h-.1M218.5 93.3h.4M218.6 94v.3M218.6 94.6v.3M218.7 93.9h.1M218.7 94h.1M218.7 93.8h.1M218.7 92.5h.1M218.7 93.8h.2M218.7 92.4v.8"/>
<path d="M218.8 94h.1M218.8 93.9v.1M218.8 92.4h.1M218.8 93.9h.1M218.9 93.8h.1M218.9 93.9h.1M218.9 92.5l-.1 .5M218.9 93h.3M218.9 94.6h.3M218.9 94h.1M218.9 92.5h.1M218.9 94v-.6h.6v.6"/>
<path d="M218.9 92.5v.5M218.9 92.4h.1M218.9 93.4v.6M218.9 94.8h.3M219 93.9h.1M219 93.9l-.1 .1M219.2 94.6h.1M219.2 94.9h.1M219.2 93v.2M219.2 93.4v.5M219.2 94.1v.3M219.2 93.9h-.6"/>
<path d="M219.4 92.5v.2M219.4 93.9h.6M219.4 92.9v.1M219.4 94.3v.4M219.4 93.4h.1M219.4 93.4v.4M219.4 93v.2M219.5 92.5v.2M219.5 93.8h.1M219.5 93.9h.1M219.5 94h.1M219.5 94v.3"/>
<path d="M219.5 92.5l-.1 .5M219.5 94.6v.3M219.5 94.3l-.1 .4-.2-.1M219.6 94h.1M219.6 93.9h.1M219.6 93.8h.1M219.6 92.5h.1M219.6 92.4h.1M219.6 93.9l.1 .1M219.6 93.9l-.1 .1M219.7 94.8h1.2M219.7 94h.1"/>
<path d="M219.7 93.8h.1M219.7 92.5v.7M219.7 93.9h.1M219.7 93.4l-.1 .4M219.7 93.4h.1M219.7 93.3l-.1 .5M219.7 93h.1M219.7 92.5h.1M219.7 93.8h-.2M219.7 92.4h.1M219.7 93.4v.4M219.7 92.5v.5"/>
<path d="M219.8 93.9h.1M219.9 93.3l.1 .6M220 94.8h.1M220 94v.8M220 94.7l-.1 .1M220 93.3l-.6 .1M220 94.4v.4M220.2 93.1l-.2 .7M220.2 93.9h.6M220.2 93.7v.3M220.3 94.8h.1M220.3 94.7h1.1"/>
<path d="M220.3 92.5v.3M220.3 93.9h.1M220.3 93.3h.3M220.3 92.4h1v.3M220.3 94h.1M220.3 92.5v.4M220.3 93.4v1.4M220.3 92.5h.1M220.3 93.7h.1M220.3 93.3h.1M220.3 93.7h.3M220.4 94.8h.1"/>
<path d="M220.4 94h.1M220.4 93l-.1 .3M220.4 93.8h.1M220.4 92.5h.1M220.4 94.4v.3M220.4 93.9h.1M220.4 92.4h.1M220.4 92.5v.5M220.4 93.3v.7M220.4 92.4v.3M220.5 94h.1M220.5 93.9h.1"/>
<path d="M220.5 93.4v.5M220.5 93.8h.1M220.5 92.5h.1M220.5 92.4h.1M220.6 92.4v.6M220.8 94.8h.1M220.8 94h.1M220.8 94v.1M220.8 94.1v.2M220.8 93.5l.1 .1M220.8 94.6v.2M220.9 93.6h.1"/>
<path d="M220.9 93.6h1.2M221 93.9h.1M221.1 94.5l.3 .2M221.1 94.5v.2zM221.1 93.3v.2M221.1 93.9v.4M221.1 93.9v.2M221.1 94.8h.1M221.1 94.6v.3M221.1 94h.1M221.1 93.3h.1M221.1 93.9h.1"/>
<path d="M221.1 93.6l.1 .4M221.2 94.8h.1M221.2 94.7h.1M221.2 93.3h.1M221.2 94v.2M221.2 94.5v.4l.6-.1M221.2 93v.3M221.2 94.4l.1 .3M221.2 94h.1M221.3 94.9h.1M221.3 93.9h.1M221.3 93.6l.1 .4"/>
<path d="M221.4 93l-.1 .5M221.4 92.4v.3M221.5 92.4h.1M221.5 94.8h.5M221.5 94v.3M221.5 94.6v.3M221.5 93.7h-.6l1.2 .1v.3l-5.6-.1M221.6 93.9h.1M221.7 93.9h.1M221.7 94.7l.1 .1M221.7 94.8h.1M221.8 93.6l-.1 .3"/>
<path d="M221.8 94.5h.2M222 93.3h-1.2M222 93.7h.6M222.1 94.5v.1M222.1 94.2v.1M222.1 93.3v.2M222.1 94.8v.1M222.2 92.7h-.4v.4M222.2 94.5h.1M222.2 92.4h1.1M222.2 93.3h.1M222.2 94.8h.1"/>
<path d="M222.2 94.7h1.3M222.4 94.5h.3M222.4 93.3h.1M222.4 94.2h.1M222.4 94.5h.1M222.4 93.3v.2M222.4 93.8v.3M222.4 94.2v.1M222.4 94.5v.1M222.4 94.8v.1M222.5 93.8h.1M222.6 92.7h.3"/>
<path d="M222.7 93.3h.1M222.7 93.8h.1M222.9 93.3h.1M222.9 93.9h.1M222.9 93.9v.3M222.9 93.3v.2M222.9 94.6v.2M223 92.4h.1M223.1 94.8h.1M223.1 92.7v.2M223.1 93.9h.1M223.1 93.3h.1"/>
<path d="M223.1 93.9h.5M223.1 93.6v.4M223.1 93.1v.4M223.2 92.7v.2M223.2 93.7l-.3 .2M223.3 93.1v.2M223.3 94.4l-.1 .3M223.3 94.8h-1.1M223.3 94.8h.1M223.3 93.7v.3M223.4 93.3h.1M223.4 94.5l-.3 .2"/>
<path d="M223.4 93.7h.1M223.4 94.2h.1M223.4 94.5h.1M223.4 94.2v.1M223.4 94.5v.1M223.4 94.8v.1M223.4 93.7h.2M223.4 94.1h1.3M223.6 94.8h.1M223.6 92.7l.1 .3M223.6 92.4h.3M223.7 93.5l.1 .4"/>
<path d="M223.7 94.8h.2M223.7 94.8l.1 .1M223.9 92.4h.1M223.9 93.7h.3M224 93.9h.3l.1 .3M224.1 92.7v.2M224.1 94.4v.3M224.1 93.1v.4M224.1 93.6v.4M224.2 94.8h.2M224.2 92.7v.2M224.2 94.8h.1"/>
<path d="M224.2 93.9h.1M224.2 94.4l-.3 .3M224.3 93.1l.1 .4M224.4 94.6v.2M224.4 94.8h.1M224.4 93.7l-.1 .3M224.4 93.7h.1M224.4 93.6v.1M224.4 93.9h.1M224.5 93.9h.1M224.5 93.3h-1.4M224.5 93.3v.2"/>
<path d="M224.5 94.6v.2M224.6 93.8h.1M224.6 93.6h.1M224.6 93.6h-1.2v.5M224.6 93.8l-1.7 .1M224.6 93.9l-.1 .3M224.7 94v.1M224.7 93.3v.1M226.4 94.7h.3M226.4 94.9h.1M226.4 91.9h.3M226.4 94.1h.5"/>
<path d="M226.5 94.6h.1M226.5 94.9h.2M226.6 94.6h.1M226.6 93.9h.1M226.6 94.9h.1M226.6 94.3h.1M226.6 94h.1M226.6 91.5h.9M226.6 94.1v.2M226.6 94.5v.2M226.6 93.3h.3M226.7 94.6h.1"/>
<path d="M226.7 93.6l-.1 .1M226.7 93.6h.1M226.8 93.9h.1M226.8 94.5h.1M226.8 93.6h.1M226.9 93.9l.1 .3M226.9 94.6h.4M226.9 91.5v.7M226.9 93.1v.8M226.9 93.9h.1M226.9 94.6h.1M226.9 91.2v.1"/>
<path d="M226.9 91.4v.1M226.9 94.5h.1M226.9 94.8v.1M227 94.3l-.2 .2M227 91.9h1M227 94.4h.1M227 94.1v.3M227.1 93.8h.1M227.1 94.7h.1M227.1 94.7h.5M227.1 93.5l-.1 .4M227.2 94.5h.1"/>
<path d="M227.2 93.6l-.1 .2M227.2 94.5l-.8 .3M227.2 94.8h.6M227.2 94.8h.1M227.2 94.4v.4M227.3 94.2h.1M227.3 93.1l-.1 .2M227.3 94.6l-.2 .2M227.3 93.6h.2M227.3 91.5v.1M227.3 91.8v.2M227.3 92.2v.2"/>
<path d="M227.3 93.5h.3M227.4 93.5h.1M227.4 93.9l-.1 .3M227.4 93.4h.1M227.5 94.1h.5M227.5 94.8h.5M227.5 93.9h-.3M227.5 93v.1M227.5 93.4h.1M227.6 93v.2M227.6 93.3l.1 .5M227.6 93.6h.1"/>
<path d="M227.7 91.5v.8M227.7 94.6h.3M227.7 92.2l.1 .8M227.7 93.1v.8M227.7 92.7l-.2 .3M227.8 91.2h.1M227.8 91.5h.1M227.8 93.4l.1 .4M227.8 93.4h.1M227.8 93.3v.1M227.9 93.9h.1M227.9 94.3v.4h.4"/>
<path d="M227.9 93.5v.4M227.9 91.8l-.1 .4M227.9 92.4v.6M228 91.8l-.1 .4M228 93.5h.3M228 94.8l.1 .1M228 91.5h.1M228 93.3l.3 .2M228 93.5h.1M228 93.6h.1M228 91.7v.6M228 94.3h.3"/>
<path d="M228 93.3h.1M228 93.9h.1M228 93.9v.9M228.1 93.9h.1M228.1 93.3h.1M228.1 93.9v.8l.7 .1M228.1 91.2v.1M228.1 91.4v.1M228.1 93.6h.1M228.1 93.2h.1M228.1 91.8h-.2M228.2 93.6h.1"/>
<path d="M228.2 93.9h-.4v.8v-.4M228.2 93.3l.1 .1M228.2 93.6h-.1M228.2 93.3h.1M228.3 95v1M228.3 97.1v1M228.3 93.6h.1M228.3 92.3h.1M228.3 92.2h.1M228.3 92.3l-.1 .5M228.3 92.2v.1M228.3 93.4h.1"/>
<path d="M228.3 93.6h.3M228.3 92.5v.3M228.3 91.9h.1M228.4 93.9h.3M228.4 93.5h.1M228.4 91.7l-.4 .5h.3M228.4 92.2h.1M228.4 91.7h.1M228.4 91.9h.1M228.4 93.1l-.1 .4M228.4 93.1v.3M228.4 93.4h.1"/>
<path d="M228.4 92.5h.1M228.4 94.8h.5M228.4 92.7v.4M228.5 91.9h.1M228.5 93.9h.1M228.5 92.4h.1M228.5 91.7h.1M228.5 91.5v.2M228.5 93.1l-.2 .8M228.5 93.9h3.5M228.5 92.3v.2M228.5 92.3v.1"/>
<path d="M228.5 92.3v-.3l-.1 .8M228.5 92.4v.6M228.5 93.7v.6M228.5 91.5h.9M228.5 92.4v.1M228.5 93l-.7 .2M228.6 94.7h.1M228.6 92.2l-.1 .1M228.6 92.1v.1M228.6 92h.1M228.6 91.9h.1M228.6 91.7h.1"/>
<path d="M228.6 93.1l.1 .2M228.7 91.9h.6M228.7 93.3v.1M228.7 93.5h.1M228.7 91.9h.1M228.7 91.8h.1M228.8 94.3l.6-.1v.5M228.8 93.6h.1M228.8 93.3h.1M228.8 93.4h.1M228.8 94.6h.1M228.8 92.4l-.8 .1v1.2"/>
<path d="M228.8 93.2h.1M228.8 91.5v.7h-.8M228.8 92.4l.1 .5M228.8 83.8h.1M228.8 92.9l.1 .1M228.8 92.8v.2M228.8 92.9h.1M228.8 93.1v.1M228.8 92.5h-.7v.8M228.9 93.6h.8M228.9 93.3h.1M228.9 93.1v.1"/>
<path d="M228.9 93l-.1 .1M228.9 93.6h.1M228.9 94.6h.1M228.9 94.3h.1M228.9 94.3v.1M228.9 94.6v.1M228.9 93.2h.1M229 94.1h.1M229 83.5h.1M229 83.5l-.1 .1M229 94.1l-.1 .1M229 93.6h.1"/>
<path d="M229 93.5h.1M229 91.9h.1M229.1 94.1h.1M229.1 91.8l-.1 .4M229.1 93.5v.1M229.1 91.9h.1M229.1 93.2h1.1M229.1 94.6v.1M229.1 93.9h.1M229.1 91.7h.1M229.1 93.2h.1M229.1 93.9v.1"/>
<path d="M229.1 94.2v.2M229.1 93.2v.1M229.1 92.9h.1M229.1 92.9v.1M229.1 93.2l-.1 .3M229.1 92h.1M229.1 92l.1 .4M229.1 91.4v.2M229.1 91.2v.3M229.1 91.7v.8M229.1 93.2l.1 1M229.1 91.2h.1"/>
<path d="M229.1 93.6h.1M229.1 91.8l-.8 .1M229.2 91.9h.1M229.2 92.5h.1M229.2 94.8h.1M229.2 93.4h.1M229.2 94.6v.2M229.2 94.4h.1M229.2 91.7h.1M229.2 93.3l-2 .1 .1 .7M229.2 93h.7M229.2 94.7h.3"/>
<path d="M229.3 91.9h.1M229.3 94.4h.1M229.3 92.1h.1M229.3 92h.1M229.3 91.5v.1M229.3 91.8v.6M229.3 93v.5h.4M229.3 92.1l-.1 .1M229.3 93.9h.1M229.3 91.7h.1M229.3 93.1h.1M229.3 93.1v.1"/>
<path d="M229.4 91.8l.1 .4M229.4 94.4h.1M229.4 91.8h.1M229.4 93.3h.1M229.4 93.4v.1M229.4 91.9h.1M229.4 92.2h.6M229.4 93.5h.1M229.4 94.5h.2M229.4 91.6h-.7M229.4 93.2v.5M229.4 93.6h.1"/>
<path d="M229.4 91.9h.3M229.5 93.4h.1M229.5 93.3h.1M229.5 93.6h.1M229.5 93.3h-.7M229.5 93.5h.1M229.5 93l.1 .2M229.5 93h.1M229.5 93.1v.1M229.5 93.2h.1M229.5 91.8l-.1 .1M229.6 93.9h.1"/>
<path d="M229.6 93.3h.1M229.6 93.6h.1M229.6 93.2h.1M229.6 92.5h.8M229.7 93.6h.1M229.7 93.8v.1M229.7 92.1h.1M229.7 93.3h.1M229.7 92.4l.8 .1-.1 1.2M229.7 91.9v.2M229.7 93.5h.1M229.7 93.6v.3"/>
<path d="M229.7 94.3h.3M229.7 93.6h1M229.7 93.9h.1M229.8 91.8l-.1 .1M229.8 93.3l.9 .1M229.8 94.8h.1M229.8 94.4v.4M229.8 94.5h3.3M229.8 91.2h.9M229.8 91.7h.1M229.8 94.7h.2M229.8 93.1h.1"/>
<path d="M229.8 91.9h.1M229.8 92h.1M229.8 93.1v.7M229.9 93.9h.1M229.9 93.6h.1M229.9 91.7h.1M229.9 91.9h.1M229.9 92v.2M229.9 92.8v.4M229.9 91.6h.5M229.9 93.6h.2M229.9 92.5h.1"/>
<path d="M229.9 92.2v.2M229.9 93.4v1M229.9 91.8h.7v.6M229.9 91.5h.1M229.9 91.2v.1M229.9 91.4v.1M229.9 91.7v1M229.9 91.5l-.2 .1M229.9 92.1v.1M229.9 92h.1M229.9 93.3h.7M230 91.7h.1"/>
<path d="M230 92h.1M230 91.9h.1M230 93.1v.1M230 93.3h.1M230 93.2h.1M230 93.9h.1M230 93.2v.2M230 93.3l.1 .1M230.1 92.2h.1M230.1 91.9h.3v.5M230.1 91.9h.1M230.1 91.8h.1"/>
<path d="M230.1 93.6h.1M230.1 93.4v.1M230.1 93.2h.1M230.1 92.8h.1M230.1 91.9l.1 .3M230.1 93.5h.1M230.2 93.9h.1M230.2 93.3h.1M230.2 93.5h.3v.4M230.2 93.6h.1M230.2 92.2h.1M230.2 93.2h.1"/>
<path d="M230.2 92.5h.1M230.2 91.5h.2M230.2 93.6v.3M230.2 95v1M230.2 97.1v1M230.2 92.4h.1M230.2 93v.1M230.2 92.9v.1M230.2 92.9h.1M230.2 93.6h.3M230.2 92.7h.1M230.2 92.5v.1"/>
<path d="M230.2 93h.1M230.2 92.4v.1M230.3 93.9h.1M230.3 93l-.1 .2M230.3 93.1v.1M230.3 93v.1M230.3 93.8v.1M230.3 93.6h.1M230.3 92.4h.1M230.3 93.3h.1M230.4 93l.5 .1M230.4 93.9h.1"/>
<path d="M230.4 93h.1M230.4 92.9v.7M230.4 93.8l-.1 .1M230.4 93.5h.1M230.4 93.6h.1M230.4 94v.9M230.4 94.7l-.8 .1M230.5 91.8h.1M230.5 91.8l-.1 .3M230.5 93.3h.1M230.5 93.9h.1M230.5 91.7h.1"/>
<path d="M230.5 93.1v.2M230.5 93.6h1.3M230.5 93.6h.1M230.5 91.9h.1M230.5 91.9l.1 .5M230.5 91.8l.1 .4M230.6 94.3l-.1 .4v-.4M230.6 91.7h.1M230.6 92.5h.1M230.6 91.9h.1M230.6 92.7v.3M230.6 92.4h.1"/>
<path d="M230.7 93.5v.1M230.7 93.4l-.1 .4M230.7 93v.4M230.7 93.6h.1M230.7 91.7h.1M230.7 92l-2.1 .2M230.7 92h.1M230.7 91.9h.1M230.7 93.4h.1M230.7 94.3v.4M230.7 93.1h.1M230.7 93.1l.1 .2"/>
<path d="M230.8 93.6h.1M230.8 93.3h.1M230.8 93.5v.1M230.8 91.8h.1M230.8 93.9h.1M230.8 93.3v.1M230.8 92.7v.3M230.8 91.9v.3M230.8 91.9h.1M230.8 93.4h.1M230.8 93.5h.1M230.8 93.3h.2"/>
<path d="M230.8 93.4v.4M230.9 93.4h.1M230.9 93.2h.1M230.9 93.2l-.1 .1M230.9 93.3h.1M230.9 92.2h.1M230.9 93.9h.1M230.9 92.5v.1M230.9 92.9l-.1 .3M230.9 93.6h.1M230.9 93.5h.1M230.9 93.1h.1"/>
<path d="M231 92.4h.1M231 93.6h.1M231 93.6v.1M231 92.8h.1M231 92.9v.1M231 93.3h.1M231 93.9h.1M231 93.1h.1M231 93.9v.1M231 94.1v.2M231 93l3.5 .2M231 93.2h.1"/>
<path d="M231 93.1v.1M231 92.3h.1M231 94.3h.7M231 93.2v.8M231 93.5h.6M231 92.2h.1M231 91.5v.1M231 92.1h1.1M231.1 92.6l-.8 .2M231.1 93.5h.1M231.1 92.1l-.1 .1M231.1 93.4h.1"/>
<path d="M231.1 94.1l.1 .3M231.1 91.9v.1M231.2 93.6v.1M231.2 93.8v.1M231.2 91.7l-.1 .4M231.2 93.1l.2 .2M231.2 93.1h.1M231.2 93h.1M231.2 91.9v.3M231.2 92.6v.5M231.2 91.9h.1M231.2 91.7h.1"/>
<path d="M231.2 94.6l.2 .2M231.3 92.6v.2M231.3 92.8l-.1 .2M231.3 93h.1M231.3 91.9h.1M231.3 92.1h.1M231.3 91.7h.1M231.3 94.1v.2M231.3 93.3h.9M231.3 93.6h.1M231.3 92.1l.1 .3M231.3 92.8v.1"/>
<path d="M231.3 92.5h.1M231.3 92.5v.2M231.3 93.9v.1M231.4 93.6h.1M231.4 92h.1M231.4 91.9h.1M231.4 92l-.1 .1M231.4 92.7h.1M231.4 92.5v.2M231.4 92.7l-.1 .1M231.4 92.8v.1M231.4 93h.1"/>
<path d="M231.4 93.5h.1M231.4 91.7h.1M231.4 93.5v.4M231.4 94.1v.3M231.5 91.9h.5M231.5 93.5h.3M231.5 91.2h.1M231.5 91.8h.1M231.5 91.4l-.1 .1M231.5 93.4v.1M231.5 94.4h.1M231.5 93h1.9"/>
<path d="M231.5 91.9l.1 .4h-.5M231.5 91.9v.3M231.5 92.6v.4M231.5 93.5h.1M231.5 93.6h.1M231.6 93.3h.1M231.6 93.5v.1M231.6 91.9h.1M231.6 93h.1M231.6 93.6h.1M231.6 94.8v.1M231.6 94.5h.1"/>
<path d="M231.6 93.2h.1M231.6 92.5v.4M231.6 93.9h.1M231.6 92.9v.1M231.6 93v.1M231.6 92.9h.1M231.6 92.5h-.6v.3M231.6 93.6v.1M231.6 91.2h.9M231.6 94.6h.2M231.7 93v.1M231.7 93.6h.1"/>
<path d="M231.7 83.4h-2.6M231.7 93.3h.1M231.7 93.2h.1M231.8 93.5h.1M231.8 93.5l-.1 .1M231.8 91.9v.3M231.8 91.9h.1M231.9 95v1M231.9 97.1v1M231.9 91.8h.1M231.9 93.4h.1M231.9 93.6h.1"/>
<path d="M231.9 92.6h1.8M231.9 93.9h.1M231.9 93.6v.1M231.9 91.7h.1M231.9 91.7v.1M231.9 91.9h.1M231.9 92v.1M231.9 94.6l-.9 .1M231.9 92.8v.3M232 93.2h3.5M232 92.1h.1M232 91.7h.1"/>
<path d="M232 92.5v.2M232 92.7l-.1 .1M232 93.6v.1M232 93.6h.1M232 93.6h.2M232 93h.1M232 92.5l.1 .5M232 94.9h.1M232 93.9h.1M232.1 91.9h.1M232.1 91.7h.1M232.1 92v.2"/>
<path d="M232.1 92h.1M232.1 92.2h-.1M232.1 93h.1M232.1 93.4l.1 .1M232.2 92.3h.5M232.2 93.5h.1M232.2 91.9h.1M232.2 91.8h.1M232.2 93.6h.1M232.2 91.9h1.3M232.2 91.9l.1 .3M232.3 92.5h.5v.3"/>
<path d="M232.3 93.3h.1M232.3 93.6h.1M232.3 93.1h.1M232.3 93.1v.1M232.4 92.8h.1M232.4 92.9v.1M232.4 93.3h.1M232.4 92.8v.2M232.4 93l-.1 .1M232.4 93v.1M232.4 93.6h.1M232.4 93.2h.1"/>
<path d="M232.4 93.5h.1M232.5 93.2h.1M232.5 94.3l.7 .1M232.5 93.3v.1M232.5 91.2l1.5 .1M232.5 91.5h.1M232.5 91.2v.1M232.5 91.9l4.2 .1M232.5 91.9h.6M232.5 93.6h.1M232.5 93.8v.1M232.5 91.9h.1"/>
<path d="M232.5 93.6v.1M232.5 93.9h.1M232.5 93.4h.1M232.5 93.5v.1M232.6 93h.5M232.6 93.6h.1M232.6 91.8l-.1 .1M232.6 92.6v.2M232.6 93v.2M232.6 91.7h.1M232.6 93v.1M232.6 91.9h.1"/>
<path d="M232.7 92.6v.2M232.7 93.2l1.1 .2M232.7 94.1h.1M232.7 94.8h.1M232.7 94.1v.2M232.7 94.6v.2M232.7 91.7h.1M232.7 93.9h1.6h-1.3M232.7 92.8l-.1 .2M232.7 92h.1M232.7 92.1v.1M232.7 93.9h.1"/>
<path d="M232.7 93.6v.1M232.7 92.5h.1M232.7 92.5v.3M232.7 92.2h.1M232.7 93.6h.1M232.7 94h.2M232.7 92.5l.1 .4M232.8 92.3h.1M232.8 91.7h.1M232.8 92l-.1 .1M232.8 92h.1M232.8 91.9h.1"/>
<path d="M232.8 92.9h.1M232.8 92.9v.2M232.8 93.2v.3h-.7M232.8 93.6h.1M232.8 93.9v.1M232.8 94.2v.1M232.8 93.1h.1M232.9 93.6h.1M232.9 93.3v.2M232.9 92.3h.1M232.9 91.8v.1M232.9 91.8h.1"/>
<path d="M232.9 91.9l.1 .3M232.9 91.9h.1M232.9 93.5h.1M233 92.4h.1M233 92.8v.2M233 93h.1M233 93.1h.1M233 92.5v.1M233 93.6h.1M233 93.2h.1M233 93.5h.1M233 93.6h1.3"/>
<path d="M233 93.3h.1M233 94h.2M233 93.4h.1M233 92.9l.1 .1M233 92.9v.1M233 93v.1M233 92.9h.1M233.1 93.3h.1M233.1 93v.3M233.1 92.8l-.1 .1M233.1 93.6h.1M233.1 93.3h.9"/>
<path d="M233.2 94.8h.1M233.2 93.3h.1M233.2 92.1v.1M233.2 94.9h.1M233.2 94.7h1.1M233.2 93.5h.1M233.2 93.9h.1M233.2 94.7h.1M233.2 94.1h.1M233.2 94.6v.1M233.2 94h.7M233.2 94.8h.7"/>
<path d="M233.2 85.8v.2M233.2 86.4v.2M233.2 91.2v.9M233.2 93v1M233.2 95v1M233.2 97.1v1M233.2 91.8h.1M233.2 91.8v.3M233.3 93.4h.1M233.3 93.4l-.1 .1M233.3 91.9h.4M233.3 93h.5"/>
<path d="M233.3 91.7h.1M233.3 93v.1M233.3 91.9h.1M233.3 92h.1M233.4 91.7h.1M233.4 92.6l-.1 .4M233.4 92.1h.1M233.4 92.1v.1M233.4 92.2h.1M233.4 92.6l.1 .4M233.4 92.5v.1M233.5 92v.2"/>
<path d="M233.5 94.9h.1M233.5 91.9h.1M233.5 91.8h.1M233.5 91.7h.1M233.6 91.9l.1 .3M233.6 91.8v.1M233.6 93.4h.1M233.6 93.4v.1M233.6 93.3v.4M233.6 94.2v.5M233.6 93.5h.1M233.6 93.6h.1"/>
<path d="M233.7 93.3h.1M233.7 93.9v.2M233.7 94.4v.3M233.7 93.1v.1M233.8 92.8h.1M233.8 92.8v.2M233.8 92.9v.1M233.8 93l-.1 .1M233.8 93.6h.1M233.8 93.3h.1M233.8 93.2v.1M233.8 93v.1"/>
<path d="M233.8 93.5v.1M233.8 92.2h.1M233.8 93.9h.1M233.9 93.5h.1M233.9 93.3h.1M233.9 93.9h.1M233.9 93.6v.1M233.9 93.9v.2M233.9 94.4v.3M233.9 93.6h.1M233.9 93.3v.2M234 91.8h.1"/>
<path d="M234 91.7l-.2 .5M234 91.9h.1M234 91.9l.1 .1M234.1 92h.1M234.1 92.1h.1M234.1 91.9h1.2M234.1 91.7h.1M234.1 92.6h.1M234.1 92.6l-.1 .5M234.1 93h1.2M234.1 92.5h.1M234.1 92.5l.1 .5"/>
<path d="M234.2 92h.1M234.2 91.9h.1M234.2 92l-.1 .2M234.2 91.7h.1M234.2 93.5v.2M234.2 93.9v.2M234.2 94.4v.3M234.2 94.3h1.1M234.2 93.9h.1M234.2 93.6h.1M234.3 91.8v.3M234.3 91.8h.1"/>
<path d="M234.3 91.5v.1M234.3 93.4v.1M234.3 92l.1 .2M234.3 92.7h.1M234.3 83.4h2.5M234.3 93.5h.1M234.4 93.6h.1M234.4 93.3h-.2M234.4 93.2v.1M234.4 93.3h.1M234.4 91.5v.1M234.4 91.7v.1"/>
<path d="M234.4 92.9h.1M234.4 93.1v.1M234.4 92.6h.1M234.4 92.8l.1 .5M234.4 91.8h.1M234.5 93.9h.1M234.5 93.3h.1M234.5 92.8l-.1 .3M234.5 94.7h1.2M234.5 94.7h.1M234.5 93.6h.1M234.6 92.2h.1"/>
<path d="M234.6 93.3h.1M234.6 92.9h.1M234.6 93.6h.1M234.6 91.8h.1M234.6 94.4l4.7 .1M234.6 94h.9M234.6 94.8h.6M234.6 93.5h.1M234.6 91.8v.4M234.6 91.9h.1M234.6 93.4h.1M234.6 93.4v.1"/>
<path d="M234.7 91.7h.1M234.7 92.8h.1M234.7 92.4l-.2 .1M234.7 93.3h.1M234.7 91.8h.1M234.7 93.6h2.2M234.7 93.6h.1M234.7 91.3h.1M234.7 91.9h1.4M234.7 91.5v.1M234.7 93.3v.1M234.7 93h2.1"/>
<path d="M234.7 93.9h2.3h-2.2M234.7 93.9h.1M234.7 93v.1M234.7 91.9h.1M234.7 92h.1M234.8 93.9h.1M234.8 91.7h.1M234.8 93.4h.9M234.8 94.7h.1M234.8 91.8h.1M234.8 92.6l-.1 .4M234.8 92.1v.1"/>
<path d="M234.8 92.2h.1M234.8 92.6h1.8M234.8 91.8h.2M234.8 93.6v.1M234.8 93.8v.1M234.8 92.7l-.1 .1M234.8 92.5l.1 .1M234.9 93.3h.1M234.9 92v.1M234.9 92.1l-.1 .1M234.9 92.6v.4M234.9 94.9h.1"/>
<path d="M234.9 91.7h.1M234.9 92h.1M234.9 91.9h.1M234.9 93h.1M235 92.7v.1M235 91.8v.3M235 91.8h.1M235 93.4v.1M235 92.1l-.1 .1M235 93.5h.1M235.1 92.6l-.1 .1M235.1 93.3h.1"/>
<path d="M235.1 92.1v.1M235.1 93.6h.1M235.1 92.8l.1 .1M235.1 93.1h.1M235.2 92.6h.1M235.2 92.8h.1M235.2 92.9v.1M235.2 93l-.1 .1M235.2 94.9h.1M235.2 93v.2M235.2 93.3h.1M235.2 93.6h.1"/>
<path d="M235.2 92.1h-.2M235.2 92.9h.1M235.2 94.7h.1M235.2 94.8v.1M235.2 94.1h.1M235.2 94.8h.1M235.2 91.8h.2M235.2 93.3h.6M235.2 92.4h.1M235.2 92.4l-.2 .1M235.3 92v.2M235.3 94.8h.1"/>
<path d="M235.3 92h.2M235.3 92.8h.1M235.3 91.9h.1M235.3 91.9v.1M235.3 92.3h.1M235.4 92.4l-.2 .2M235.4 91.7h.1M235.4 91.8h.1M235.4 91.8l-.1 .1M235.4 93v.1M235.4 91.9h.1M235.4 93.1l-.1 .4"/>
<path d="M235.5 91.7h.1M235.5 91.8h.1M235.5 92.3h.1M235.5 92h.1M235.5 92.1v.1M235.5 92.7l-.2 .1M235.5 91.9h.1M235.5 92.2v.2M235.5 91.3l1.6 .1M235.5 92.7v.1M235.5 92.3v.1M235.5 92.7h.1"/>
<path d="M235.6 91.7h.1M235.6 92.4l.1 .1M235.6 92h.1M235.6 91.9h.1M235.6 91.5v.1M235.6 91.9v.2M235.6 93.1l.1 .2M235.6 92.8l.1 .1M235.6 92.6h.1M235.7 91.8v.3M235.7 91.8h.1M235.7 94h.1"/>
<path d="M235.7 92.1h.1M235.7 93.3v.1M235.7 91.8h-.2M235.7 92.1l-.2 .2M235.7 93.5h.1M235.7 92.1v.1M235.7 92.1l.3 .1M235.7 93.6h.1M235.7 92.9h.1M235.8 93.2h.1M235.8 93.3h.1M235.8 94.8h.1"/>
<path d="M235.8 94h.1M235.8 93.6h.1M235.8 93v.1M235.8 93.2v.2M235.8 92.1h-.1M235.8 94.1h.1M235.8 94.7v.1M235.8 91.8h.2M235.8 93.9v.1M235.8 94.1v.3M235.9 92.6l-.1 .2M235.9 93v.2"/>
<path d="M235.9 92.8h.1M235.9 93.3h.1M235.9 92.9v.3M235.9 92.9l-.1 .1M235.9 92.5h.1M235.9 92.4l-.2 .2zM235.9 93.6h.1M235.9 92.4h.1M236 92.3h.1M236 92l.2 .2M236 92.2h.1M236 93.3h.1"/>
<path d="M236 93.2h.1M236 93.3v.1M236 93.6h-3.6M236 93.6h.1M236 92v.2M236 93.5h.1M236 91.8v.2M236 93.4v.1M236.1 91.7h.1M236.1 92.3h.1M236.1 91.9h.1M236.1 91.8h.1"/>
<path d="M236.1 91.5h.1M236.1 92h.1M236.1 91.7v.1M236.2 92.5v.3M236.2 92.8l-.1 .3M236.2 92.3h.1M236.2 91.7h.1M236.2 92.4l.4 .1v.7M236.2 92.8h-.3M236.2 92.5l.1 .3M236.3 91.9h1.4M236.3 91.9h.1"/>
<path d="M236.3 92.1v.1M236.3 92h.1M236.3 92.8v.1M236.3 91.7h.1M236.3 93h1.4M236.3 92.9l2.4 .2M236.3 92.1l.3 .1M236.3 92.1h.1M236.3 91.8h.1M236.3 92.9h.1M236.3 92.1l-.2 .1M236.4 91.8l.1 .4"/>
<path d="M236.4 94.3h1M236.4 93.3h1.1M236.4 92.9h.1M236.4 93.4v.1M236.4 93.5h.1M236.4 93.6h.1M236.4 92.4h.1M236.4 92.4l-.2 .1M236.5 93.3h.1M236.5 92.9h.1M236.5 93.6h.1M236.5 92.3h.1"/>
<path d="M236.5 93.1v.1M236.5 92.6h.1M236.5 92h.2M236.6 93v.1M236.6 92.8h.1M236.6 92.9l-.1 .2M236.6 93.3h.1M236.6 93.4v.2M236.6 93.6h.1M236.6 93.1v.1M236.6 94.7h.8M236.6 92.3h.1"/>
<path d="M236.7 93.5h.1M236.7 91.8v.2M236.7 93.9v.1M236.7 94.1v.2M236.7 93.4h.1M236.7 92.3h.1M236.8 91.8h.1M236.8 91.7h.2M236.8 92.4l.1 .1M236.8 93.1h.1M236.8 91.9h.1M236.8 91.7h.1"/>
<path d="M236.8 93.9h.1M236.8 93h.5M236.8 93.6h.1M236.8 93.3v.1M236.8 93l1.7 .2M236.8 92.7l.1 .1M236.8 92.7h.1M236.8 92h.1M236.8 92.9v.1M236.8 92.7l1.6 .2M236.8 92.1h.1M236.9 91.7h.1"/>
<path d="M236.9 92.4l.2 .2M236.9 91.5h-.3v.4M236.9 92.5v.1M236.9 92.1h.1M236.9 92.6l-.1 .3M236.9 92.8h.1M236.9 92.6l.1 .2M237 91.6h.1M237 91.7h.1M237 93h.1M237 93v.1M237 92.1h.1"/>
<path d="M237 92h.1M237 91.9h.1M237 92.8v.2M237 93.1h.1M237.1 92.9h.1M237.1 91.8v.3M237.1 91.8h.1M237.1 93.4v.1M237.1 91.6h.1M237.1 91.4h.1M237.1 93.5h.1M237.1 92.1h-.2"/>
<path d="M237.1 92.2h.1M237.2 92.6h.1M237.2 93.3h.1M237.2 93.6h.1M237.2 92.7l.3 .2M237.2 93l1.7 .2M237.2 91.9h.1M237.3 93.1v.1M237.3 93.3h.1M237.3 92.8v.1M237.3 92.9l-.1 .1M237.3 93.9h.1"/>
<path d="M237.3 93.1h.1M237.3 92.9v.1M237.3 93.6v.1M237.3 91.6h.1M237.3 93.6h.1M237.3 93.2h.1M237.4 92.6l.1 .1M237.4 93.3h.1M237.4 91.4l-.2 .1M237.4 93.6h.1M237.4 92.1v.1M237.4 92.6h.7"/>
<path d="M237.4 91.7h.1M237.4 93h.1M237.4 92.2l.2 .2M237.4 93.5h.1M237.4 92.4l.2 .1M237.4 91.8v.3M237.5 92.7h.5v.6M237.5 92.7h.1M237.5 92.9v.1M237.5 91.7h.1M237.5 91.8h.1M237.5 93h.3"/>
<path d="M237.5 92h.1M237.5 92.9v.2M237.5 91.9h.1M237.5 92.9h.2M237.6 92.1h.1M237.6 92.1v.1M237.6 92.6l-.1 .3M237.6 92.5l.1 .5M237.6 91.7h.1M237.6 93h2M237.6 92.5l.1 .2M237.7 93h2.6"/>
<path d="M237.7 92.7v.1M237.7 93v.1M237.7 92v.2M237.7 92h.1M237.7 91.7h.1M237.7 92.6h.1M237.7 93h.1M237.7 91.9h.1M237.7 93.6h3.5M237.8 91.9l.1 .3M237.8 91.9h.1M237.8 91.8h.1"/>
<path d="M237.8 93.4h.1M237.8 93.5h.1M237.8 91.9v.1M237.8 93.6h.1M237.9 93.3h.1M237.9 91.9v.1M237.9 93.6h.1M237.9 92.9l.1 .1M237.9 92.8v.5M237.9 92.9h.1M237.9 93h.2M237.9 92.7l.6 .1"/>
<path d="M238 93.5v2.5M238 93.3h.1M238 93v.1M238 93.6h.1M238 93.2h.1M238 85.8v.2M238 86.3v.3M238 91.2v1.2M238 97.1v1M238.1 92.6v.4M238.1 93.2v.2M238.1 93l1.2 .2"/>
<path d="M238.1 93.9h.1M238.1 92.2h.1M238.1 93.9v.1M238.1 94.1v.2M238.1 93.6h.1M238.1 91.8h.1M238.1 91.9v.3M238.1 92.6l.1 .2M238.1 92.2l.1 .3M238.1 93.5h.1M238.2 91.8h.1M238.2 93.1h.3"/>
<path d="M238.2 91.7h.1M238.2 93h.1M238.2 92.6v.2M238.2 91.9h.1M238.2 93v.1M238.2 95v1M238.2 97.1v1M238.2 91.9h1.5M238.2 92.7v.3M238.2 92h.1M238.2 92v.1M238.3 91.7h.1"/>
<path d="M238.3 92.5v.1M238.3 92.2h.1M238.3 92.6l-.1 .1M238.3 91.2v.1M238.3 91.4v.1M238.3 92.5h.1M238.3 92.6l.1 .2M238.4 91.7h.1M238.4 92.1h.1M238.4 92h.1M238.4 91.9h.1M238.4 92.8h.1"/>
<path d="M238.4 92.8v.2M238.4 92.1l-.1 .1M238.4 93.2h.1M238.4 93.3l.1 .2M238.4 93h.1M238.5 91.8l.1 .4M238.5 91.8h.1M238.5 91.7h.1M238.5 94.7h.2M238.5 94.3h1.6M238.5 93.5h.1M238.5 93.6h.1"/>
<path d="M238.6 92.9l.5 .1M238.6 93.3h.1M238.6 93.6h.1M238.6 93l1 .3M238.7 93v.1M238.7 92.8h.1M238.7 93h.1M238.7 92.9v.1M238.7 92.9l-.1 .1M238.7 93.6h.1M238.7 93.3h.1M238.7 93.2h.1"/>
<path d="M238.8 92.2h.1M238.8 93.3h.1M238.8 92v.2M238.8 93.5h.1M238.8 91.5v.1M238.8 91.9l-1 .2M238.8 91.9h.1M238.8 93.4h.1M238.8 93.4v.1M238.9 91.7h.1M238.9 91.8h.1M238.9 93.9h.1"/>
<path d="M238.9 93.2v.1M238.9 93.5v.1M238.9 91.9h.1M238.9 92h.1M239 91.7h.1M239 92.6l-.1 .5M239 92.1h.1M239 92.1v.1M239 94.7h.3M239 92.5l.1 .6M239 92.9l.5 .1M239.1 91.7h.1"/>
<path d="M239.1 92h.1M239.1 91.9h.1M239.1 92l-.1 .2M239.2 91.8l.1 .3M239.2 93.4h.1M239.2 91.9l.1 .3M239.2 93.5h.1M239.3 93.3h.1M239.3 93.6h.1M239.3 93.2h.1M239.3 92.9h.1M239.3 92.9v.1"/>
<path d="M239.3 93v.2M239.4 93.3h.1M239.4 93.2h.1M239.4 93v.1M239.4 92.8l-.1 .1M239.4 93.6h.1M239.4 93.9h.1M239.5 92.1h.1M239.5 93.6h.1M239.5 93.5h.1M239.6 91.8h.1M239.6 91.8l-.1 .3"/>
<path d="M239.6 93.4h.1M239.6 91.7h.1M239.6 91.9h.1M239.6 92h.1M239.6 92.1h.1M239.6 92.8v.3M239.7 91.7h.1M239.7 93.9h.1M239.7 92.7l.1 .4M239.7 92.7l-.1 .1M239.7 93.9v.1M239.7 94.1v.2"/>
<path d="M239.7 92.2h.1M239.8 91.7h.1M239.8 92.1h.1M239.8 92h.1M239.8 91.9h.1M239.8 92.1l-.1 .1M239.9 91.8h.1M239.9 93.4v.1M239.9 91.8l.1 .4M239.9 93.5h.1M239.9 93.6h.1M240 93.3h.1"/>
<path d="M240 93.6h.1M240 91.9h.3M240 91.5h2.4M240.1 93l-.1 .2M240.1 93.3h.1M240.1 92.9l-.7 .2M240.1 92.8v.2M240.1 93.6h.1M240.1 93.2l1.6 .3M240.1 93.2v.1M240.1 93.1h.1M240.1 93.5l1.6 .2"/>
<path d="M240.2 92.2h.1M240.2 93.3h.1M240.2 93.6h.1M240.2 92.1h1M240.2 91.5v.1M240.2 91.9v.2M240.2 93.2l.5 .1M240.2 93.5h.1M240.3 91.8l-.1 .3M240.3 91.7h.1M240.3 92h.1M240.3 92.9l.3 .2"/>
<path d="M240.3 92.9l.1-.3 .1 .4h.8M240.3 91.9h.1M240.4 91.7h.1M240.4 92.1v.1M240.4 92.2h.1M240.4 93.5l.9 .2M240.4 92.1h.1M240.4 92h.1M240.5 93.3h-2.3M240.5 93.5l1.2 .2M240.5 92h.1M240.5 91.9h.1"/>
<path d="M240.5 91.7h.1M240.6 91.9h.1M240.6 91.8h.1M240.6 93.4v.1M240.6 93.2h-.3h.4M240.6 91.9l.1 .3M240.6 93.5h.1M240.7 93.3h.1M240.7 93.6h.1M240.7 91.9l3 .1M240.7 93.2v.1M240.7 95l.1 1"/>
<path d="M240.7 95h.3M240.7 92.9h.1M240.7 92.9v.3M240.8 93.1v.1M240.8 93.1h.1M240.8 92.8l-.1 .1M240.8 97.1v1M240.8 93.6h.1M240.8 93.3h.1M240.8 93h.1M240.8 92.9h.1M240.8 95v1"/>
<path d="M240.9 92.1v.1M240.9 93.1h.1M240.9 92.8h.1M240.9 93.5h.1M240.9 92v.1M240.9 93.4v.1M240.9 93.2h3.1M241 93.2h.1M241 92.7h.1M241 91.8v.3M241 92.4v.2M241 93v.1"/>
<path d="M241 91.8h.1M241 91.2h.1M241 91.5h.1M241 91.2v.1M241 91.5v.1M241 93.1h.3M241 91.7h.1M241 93.1h.1M241 92.8v.2M241 91.9h.1M241 92h.1M241 92.1h.1"/>
<path d="M241 92.8l.1 1.4h.3M241.1 91.7h.1M241.1 89.8h.2M241.1 92.9h.1M241.1 89.2h.1M241.1 89.3h.1M241.1 91.2l-.1 1.1M241.1 93.3h.1M241.1 92.7h.2M241.1 89.4h.2M241.1 89.7h.2M241.1 91.5v.1"/>
<path d="M241.1 92.5v.2M241.1 92.1v.1M241.1 89.4h.1M241.1 91.5h.1M241.1 91.3v.1M241.1 91.2h.1M241.1 92.7l-.1 .1M241.1 92.6l.1 .3M241.1 89.1v.1M241.1 92.5v.1M241.2 92v.1M241.2 92h.1"/>
<path d="M241.2 91.9h.1M241.2 92.9v.1M241.2 92.1l-.1 .1M241.2 91.7h.1M241.2 93.3h.1M241.2 93h.1M241.2 91.6h.1M241.2 93.3l.5 .1M241.3 91.8h.1M241.3 91.6h.2M241.3 93.3h.1M241.3 93.4v.1"/>
<path d="M241.3 91.8l.1 .4M241.3 93.2h.1M241.3 93.5h.1M241.3 93.6h.1M241.4 93.3h.1M241.4 92.2h.1M241.4 93.7h.1M241.4 93.6h.1M241.5 93v.1M241.5 92.8h.1M241.5 93l-.1 .2M241.5 93.3h.1"/>
<path d="M241.5 92.9v.1M241.5 92.8v.2M241.5 94.8h.1M241.5 95.2h.1M241.5 95h.5M241.5 93.6h.1M241.5 94.2v.5M241.5 95.6l.1 .5M241.5 95.2v.2M241.5 93.1v.1M241.5 89.8h.2M241.5 93.4v.1"/>
<path d="M241.5 93.6v.3M241.5 93h.2M241.5 92.7h.2M241.5 89.4h.2M241.5 89.7h.2M241.5 92.2h.1M241.5 93.9h.1M241.5 93.2h.1M241.5 91.5v.1M241.5 91.8v.4M241.5 92.2v.1M241.5 94.2v.3"/>
<path d="M241.5 93.1h1.7M241.5 95.2v.1M241.5 93.7v.1M241.6 93.6h.5M241.6 93.2v.1M241.6 91.9h.1M241.6 94.7h.1M241.6 93.4l-.1 .5M241.7 91.8l-.1 .1M241.7 91.2h.1M241.7 91.3h.1M241.7 91.4h.1"/>
<path d="M241.7 91.6h.1M241.7 89.1h.1M241.7 90.9v1.1M241.7 93.3l-.1 .1M241.7 93.4h.1M241.7 93.7h.1M241.7 93.4v.1M241.7 91.7h.1M241.7 91.9h.1M241.7 92h.1M241.7 94.6h.1M241.7 93.1v.1"/>
<path d="M241.7 92.8v1.4h1M241.8 94.8h.2M241.8 92h.1M241.8 92.1v.1M241.8 91.1h-.1M241.8 95h-.1M241.8 96.4v.2M241.8 91.7h.1M241.8 92.5h.1M241.8 91.9h.1M241.8 92.2v.3M241.8 94.2h4.5"/>
<path d="M241.8 93.4h.1M241.8 91.2h.1M241.8 91.3h.1M241.8 91.2v1.2M241.8 93.2v1.3l-.3 .1M241.8 93.4l-.1 .1M241.8 92.1v.2M241.8 92.3v.1M241.8 96.6h.1M241.9 92h.1M241.9 91.9h.1M241.9 90.9h.1"/>
<path d="M241.9 93.4h.1M241.9 96.6h.1M241.9 93.8l.3 .1M241.9 93.9h.1M241.9 93.1l.1 .4M241.9 91.8h.1M241.9 91.7h.1M241.9 89.6v1.3M241.9 92.2v1.2M241.9 96.7l.1 .1M241.9 92.7h.4M241.9 92.4h.4"/>
<path d="M241.9 90.9h.4M241.9 93.9v.1M241.9 94.2v.1M242 93.3l.1 1.4M242 91.9h.1M242 91.8v.1M242 93.5h.1M242 92l.1 .2M242 96.8h.1M242 94.6h.3M242.1 93.3h1.9M242.1 93.6h.1"/>
<path d="M242.1 94.7h.1M242.1 90.9h.1M242.1 91.2v1.1M242.1 93.5l.3 .1M242.1 93.2h.1M242.1 93.3h.1M242.1 96.8h.3M242.2 93.3h.1M242.2 92.8l-.1 .4M242.2 89.1h2.3M242.2 92.9v.3M242.2 93.6h.1"/>
<path d="M242.2 89.2h.1M242.2 89.2v.6M242.2 90.5v1.6M242.2 94.9h.1M242.2 94.9l-.1 .1M242.2 93.2v1M242.2 93.2h.1M242.3 92h.1M242.3 92.1v.1M242.3 94.6l-.2 .2M242.3 94.6h.1M242.3 91.7h-.4"/>
<path d="M242.3 91.9h.1M242.3 91.9v.1M242.3 93.5h.1M242.4 91.8h.1M242.4 94.5h.1M242.4 91.7h.1M242.4 93.2h.1M242.4 93.2v.2M242.4 93.9h.1M242.4 91.9h.1M242.4 92h.1M242.5 91.7h.1"/>
<path d="M242.5 93.4h.1M242.5 93.2v.1M242.5 92.5v.3M242.5 94.5h.1M242.5 94h.1M242.5 92.4v.1M242.5 92.6v.3M242.5 94.1v.2M242.5 91.9h.1M242.5 92.1h.1M242.5 92.1v.2M242.5 92.4h.3"/>
<path d="M242.5 93.4h.3M242.5 93.5l.1 .1M242.5 93.5h.1M242.5 92.4h.1M242.5 92.3v.1M242.6 93.2h.1M242.6 92l-.1 .4M242.6 91.9h.1M242.6 93.6h.1M242.6 91.7h.1M242.6 93.6h.5M242.6 93v.1"/>
<path d="M242.6 92.3h.1M242.6 93.1v.1M242.6 91.8h.1M242.6 93.2l.1 .3M242.6 92.7h.3M242.6 92.4h.3M242.6 90.9h.3M242.7 93.6h.2M242.7 91.9l.1 .3M242.7 91.8v.1M242.7 93.3h.1M242.7 92.2h.2"/>
<path d="M242.7 93.5h.1M242.7 96.8h.3M242.7 91.6h-.9M242.7 94h.2M242.7 93l2.4 .1M242.7 93.6h.1M242.8 93.3h.1M242.8 93.6l.5 .1M242.8 93.1v.1M242.9 92.8l-.1 .3M242.9 92.9v.1M242.9 97.1v1"/>
<path d="M242.9 92.7l-.3 .1M242.9 91.5h.1M242.9 93.6h.1M242.9 94h.1M242.9 91.5v.1M242.9 91.8v.5M242.9 92.8v.4M242.9 94.1v.3M242.9 94.7v1.3M242.9 94.9l.2 1.1M242.9 93.3h.1M242.9 93.2h.1"/>
<path d="M242.9 93.1v.1M242.9 91.2h.1M242.9 92.2h.1M242.9 92.3v.3M242.9 92.7h.1M242.9 92.1h.1M242.9 92.4h.1M242.9 92.4v.1M242.9 91.2v.1M242.9 89.2v.8M242.9 90.9v1.3M242.9 91.7h-.3"/>
<path d="M243 92.1l-.1 .1M243 93.1h.1M243 92.8v.1M243 93.5h.1M243 97.1v1M243 91.9v.2M243 91.8v.1M243 92.9h.1M243 93h.1M243 93.4h.1M243.1 91.8h.1M243.1 96h.1"/>
<path d="M243.1 96.8h.1M243.1 91.7h.1M243.1 93.1h.1M243.1 91.9h.1M243.1 93.1l-.1 .3M243.2 92.2h.1M243.2 92.4h.4M243.2 91.9h.1M243.2 92h.1M243.2 92.1h.1M243.2 92.1v.1M243.2 93.6h2.1"/>
<path d="M243.2 91.7h.1M243.2 92.7l.2 .2M243.2 96.2h.2M243.2 96.7h.1M243.2 96.7l-.1 .1M243.2 92.2v.1M243.2 92.3v.1M243.2 92.4v.1M243.2 96.6h.1M243.2 92.2v.2M243.3 92h.1M243.3 91.9h.1"/>
<path d="M243.3 93.9h-4M243.3 91.8h.1M243.3 93.9h.1M243.3 93.1l.1 .4M243.3 91.5v.1M243.3 91.9v.2M243.3 92.1h-1.4M243.4 91.9h.1M243.4 91.8h.1M243.4 92.2h.1M243.4 96.4l-.1 .2M243.4 93.9h.5"/>
<path d="M243.4 91.9l.1 .2M243.4 93.6h.1M243.4 93v.1M243.4 93.5h.1M243.5 92.2h.1M243.5 92.1v.1M243.5 93.6h.1M243.5 93.2v.1M243.5 93.3h.1M243.5 96.2h.1M243.5 91.6l1.3 .2M243.5 92.9v.2"/>
<path d="M243.5 93.1h.1M243.5 93.7h.1M243.5 94.2v.5M243.5 93.2v.5M243.6 92.8v.5M243.6 93.3h.1M243.6 92.1h.1M243.6 92.1l-.1 .1M243.6 96.2h.1M243.6 93.6h.1M243.6 93.4h-.4M243.6 93.7h.1"/>
<path d="M243.6 95.8h.1M243.6 95.8l.1 .2M243.7 92.1v.1M243.7 93.3h.1M243.7 94.7h.1M243.7 94.5v.1M243.7 93.6h.1M243.7 92.5h.1M243.7 95.5v.3M243.7 93.5h.1M243.7 91.8h.1M243.7 91.8v.3"/>
<path d="M243.7 93.7h.1M243.7 93.7l.1 .6M243.7 94.7v.5M243.7 96.2h.2M243.7 94.2h.3M243.7 94.2h.1M243.7 92.6h.1M243.8 91.7h.1M243.8 92.1h.1M243.8 94.3h.1M243.8 93.2l-.1 .1M243.8 94.2h.1"/>
<path d="M243.8 92.7h.1M243.8 93v.1M243.8 93.2h.1M243.8 92.7v.1M243.8 93.7h.1M243.8 91.9h.1M243.8 92h.1M243.9 91.7h.1M243.9 92.2h.1M243.9 92.6h.1M243.9 92.7h.1M243.9 93.2h.1"/>
<path d="M243.9 92.7l-.2 .6M243.9 96.2h.1M243.9 91.9h.1M243.9 93.6h.1M243.9 92.5h.1M243.9 92.2v.2M243.9 92.4v.1M243.9 94.1h.1M243.9 94.1h-.1M243.9 96h.2M244 91.7h.1M244 92.3h.1"/>
<path d="M244 92.5h.1M244 93.3h.1M244 93.5l-.1 .1M244 94.4l-2.5 .1M244 94.2h.1M244 92.2h.1M244 92h.1M244 91.9h.1M244 93.1h-.1M244 92.2h-.1M244 93.1v.1M244 91.8h.1"/>
<path d="M244 92.3v.1M244 92.5l.1 .2M244 94.8l-.6 .1M244 93.2v.1M244 93.3l.1 .1M244.1 91.8l.1 .3M244.1 92.7h.1M244.1 93h.1M244.1 91.6v.9M244.1 92.9v.1M244.1 93.4v.8M244.1 92.2h.1"/>
<path d="M244.1 96l-.1 .1M244.1 93.4h.1M244.1 93.5h.1M244.1 94.2h.1M244.1 93.6h.1M244.2 93.3h.1M244.2 95l-.1 1M244.2 97.1v1M244.2 93.1h.1M244.2 92.2h.1M244.2 93.1v.1M244.2 92.9h1"/>
<path d="M244.2 93.6h.1M244.3 92.8l-.1 .3M244.3 93.2h.1M244.3 93.2h.8M244.3 92.1h.1M244.3 94.8h.2M244.3 92.1h1.9M244.3 93.6h.1M244.3 93.1v.1M244.3 93h.1M244.3 93.3h.1M244.3 94.2h.3"/>
<path d="M244.3 94.1h-.3M244.4 92h.1M244.4 92.1v.1M244.4 94h.1M244.4 93v.1M244.4 94l-.1 .1M244.4 91.5h2.3M244.4 91.6h.4M244.4 93.6h.1M244.4 93.5h.1M244.4 94.1h.2M244.4 91.6h.1"/>
<path d="M244.4 91.9h.1M244.4 91.9v.1M244.5 91.7h.1M244.5 91.8h.1M244.5 92.2v.6M244.5 93.3v.5M244.5 94.1v.2M244.5 94.5v.2M244.5 93.3h.8M244.5 91.9h.1M244.5 93.1v.1M244.5 93.2v.1"/>
<path d="M244.6 91.7v.1M244.6 94.1l-.1 .1M244.6 91.7h.1M244.6 93.9h.1M244.6 93.9v.5M244.6 94.6v.1M244.6 92h.1M244.6 92v.4M244.6 94.1h.1M244.6 93.3h.1M244.6 93.5v.3M244.6 93.6h.1"/>
<path d="M244.6 91.9h.1M244.6 91.9l-.1 .1M244.6 92.4h.1M244.6 92.4v.1M244.6 92.1v.3M244.7 91.9v.7M244.7 91.7h.1M244.7 93.6h.1M244.7 92.1h.1M244.7 92h.1M244.7 91.9h.1M244.7 91.5v.1"/>
<path d="M244.7 91.9v.2M244.7 94.1h.1M244.7 93.1l-.1 .8M244.7 93.2l.1 .3M244.8 91.8v.4M244.8 91.8h.1M244.8 91.7h.1M244.8 94.2h.1M244.8 94.7h.1M244.8 94.1v.1M244.8 93.7v.2M244.8 93.7h.1"/>
<path d="M244.8 94.2v.2M244.8 94.5v.2M244.8 91.5h5.1M244.8 93.6v.1M244.8 93.5h.1M244.8 92.2h.1M244.8 94.8h.1M244.8 94.2h1.2M244.8 93.6h.1M244.9 93.2h.1M244.9 92.9v.4M244.9 93.6l.1 .4"/>
<path d="M244.9 92.8l.1 .1M244.9 93.3h.1M244.9 92.8h.1M244.9 94.2h.1M244.9 93.6h.1M245 93.6h.1M245 94.8h1.1M245 93.9h.1M245 93.3h.1M245 93v.1M245 94.2h.1M245 92.9v.1"/>
<path d="M245 94.2l1.2 .2M245 92.8l-.1 .2M245 89.2h1.3M245 93.2h.1M245 94.8h.1M245.1 93.9v.1M245.1 93.9h.1M245.1 93.3v.4M245.1 93.6h.1M245.1 92.1v.1M245.1 93.5h.1M245.1 94.8h.1"/>
<path d="M245.1 91.9v.1M245.1 94.2h.1M245.1 91.8h.1M245.1 91.9h.1M245.2 93.1l-.1 .2M245.2 91.8h.1M245.2 91.9h.1M245.2 92h.1M245.2 94.8h.1M245.2 94.2h.1M245.2 92l.1 .1M245.2 91.7h.1"/>
<path d="M245.3 93.9v.9M245.3 94.8h.1M245.3 94.2h.1M245.3 92.1v1M245.3 92.2v.2M245.3 93h.1M245.3 91.7h.1M245.3 92.5h.1M245.3 92.4h.1M245.4 92.1v.1M245.4 92h.1M245.4 91.9h.1"/>
<path d="M245.4 92.2l-.1 .1M245.4 94.2v.2M245.4 94.7v.1M245.4 93.1l.1 .3M245.4 91.6h.5M245.4 91.8h.1M245.4 91.7h.1M245.4 91.8l.1 .1M245.5 93h.2M245.5 91.9l.1 .3M245.5 91.9h.1M245.5 93.4v.1"/>
<path d="M245.5 93.5h.1M245.5 93.6h.7M245.6 89.5h.3M245.6 90.1h.3M245.6 94.4h.1M245.6 93.6l.3 .2M245.6 93.4l1-.2v.7M245.6 94v.1M245.6 94.6v.2M245.6 89.1h.1M245.6 88.5v.2M245.6 88.9v.9"/>
<path d="M245.6 90l-.1 .5h.4M245.6 93.3h.1M245.6 93.6h.1M245.6 94.1l.1 .1M245.6 94.1h.1M245.7 93.9h.1M245.7 93.6h.1M245.7 93.8v.1M245.7 93v.2M245.7 92.8h.1M245.7 93l-.1 .3M245.7 93.3h.1"/>
<path d="M245.7 93h.1M245.7 92.8v.1M245.7 92.9v.1M245.7 93.2v.1M245.7 92.9v.3M245.7 93.6v.4M245.7 94.1v.2M245.7 92.2h.1M245.7 93.3h.9M245.8 93.5h.1M245.8 91.9h4.2M245.8 93.6h.1"/>
<path d="M245.8 91.9l-.1 .3M245.8 91.8v.1M245.9 93.9h.1M245.9 93.6l-.1 .3M245.9 93.3h.1M245.9 93h.2M245.9 91.7h.1M245.9 91.8h.1M245.9 93.6v.1M245.9 93.6h.1M245.9 91.6h.1M245.9 91.7l-.5 .1"/>
<path d="M245.9 91.9v.1M245.9 92.1h.1M245.9 92.9h1.7M246 92.1v.2M246 92.3h.1M246 91.7h.1M246 92.2v.1M246 92.3v.8M246 92.4h.1M246.1 91.7h.1M246.1 92.3h.1M246.1 92.4h.1"/>
<path d="M246.2 93.6h.1M246.2 93.2v.1M246.2 93.5v.1M246.2 91.8v.2M246.2 92.4h.1M246.2 91.8h.1M246.2 94.7l-1.2 .1M246.2 91.5v.7M246.2 92.9v.7M246.2 93h.1M246.2 93h.2M246.2 92.3h.1"/>
<path d="M246.3 93.9h.1M246.3 93.6v.6M246.3 89.2v.6M246.3 89.2h.1M246.3 91.9v1M246.4 93h.1M246.4 94.3h.1M246.4 93.6h.1M246.4 93.9h.1M246.5 94.1l-.2 .1M246.5 94.3h.1M246.5 93.1h.1"/>
<path d="M246.5 93.1l-1.6 .1M246.5 93h.1M246.5 89.4l-.3 .1M246.6 94.4h.1M246.6 93.6l-.4 .2M246.6 94.2v.2M246.6 94.6v.2M246.6 93.9h.1M246.6 89.2h.1M246.6 88.5v.2M246.6 88.9v.2M246.6 89.2v.9h-.4"/>
<path d="M246.6 94.3h.1M246.6 93.1h.1M246.6 93.9v.2M246.6 90.5v2.6M246.7 94.4h.1M246.7 94.2v.2M246.7 94.6v.2M246.7 94.3l.1 .1M246.8 97.1v1M246.8 94.6l.1 1.5M246.8 94.6v.1M246.8 93.9h.1"/>
<path d="M246.8 94.1v.3M246.8 94.3h.1M246.8 94.7h.1M246.8 89.1h4.5M246.8 95.5v.3M246.8 94.4h.1M246.8 93.6v.4M246.8 93.6h.1M246.9 94.3h.1M246.9 93.2h3.5M246.9 94.4h.1M246.9 96.1h.1"/>
<path d="M247 93h.1M247 92.5v.5M247 94.6h.1M247 96.1h.2M247 92.1v.3M247.1 93.6h-.8M247.1 94.3l.2 .1M247.2 93.3h2.4M247.2 93h.1M247.2 94.2l4.3 .1M247.3 91.5v.4M247.3 92.5v.5"/>
<path d="M247.3 93h.1M247.3 93h1.5M247.3 94.8h1.1M247.3 92.1v.3M247.3 92.7v.3M247.3 93.9h.1M247.3 93.9v.1M247.3 94.1v.3M247.3 94.7v.1M247.4 94.2v.2M247.4 91.1v.5M247.4 91.8v.4"/>
<path d="M247.4 92.5l.5 .2M247.4 91.8h.1M247.4 91.6h.1M247.4 94.5h1.2M247.4 96.1h.3M247.5 94.4h.1M247.5 90.5h-1.2v1M247.5 91.6h.1M247.6 91.8h.1M247.6 91.5v.4M247.6 92.5v.5M247.6 93.9v.1"/>
<path d="M247.6 94.2v.2M247.6 93.5v.1M247.7 93.2l-.1 .1M247.7 92.1h1.8M247.7 91.6h.1M247.7 93.9h.1M247.7 91.5v.7M247.7 93v.6M247.7 91.6h.3M247.7 91.8h.3M247.9 90.6h-.5v.3M247.9 91.6l-.9-.1v.4"/>
<path d="M247.9 91.9l-1.1 .2M247.9 92.1h.1M248.1 91.5v.7M248.1 92.9v.7M248.1 93.9h.1M248.2 96.1h-.3M248.2 94.7h.1M248.2 94.6h.1M248.3 94.4h.1M248.3 93.6h-1M248.3 92.2h.1M248.3 91.6h.3"/>
<path d="M248.3 92.3v.8M248.3 94v.8M248.3 96.1h.1M248.4 94.8h.1M248.4 91.8h.3M248.4 96l-.1 .1M248.4 94.8v.4M248.4 94.7h.1M248.4 90.6l.5 .2M248.4 95.5v.3M248.4 95.8h.1M248.4 94.3h.1"/>
<path d="M248.4 94.3v.1M248.4 90.5h.9M248.4 91.9h.1M248.4 91.9v.1M248.5 92.9h.8M248.5 94.4h.1M248.5 95v1M248.5 97.1v1M248.5 93.9h-4.2M248.6 94.3h.1M248.6 94.8h.1M248.6 94.7l-1.2 .1"/>
<path d="M248.6 91.7l.1 .1M248.6 91.6h.1M248.7 91.2v.1M248.7 91.4v.5M248.7 92.5v.5M248.7 91.6h.1M248.7 91.8l.2 .4M248.7 91.8h.1M248.7 91.6h.2M248.8 91.8h.1M248.9 91.1v.4M248.9 93.9h.1"/>
<path d="M248.9 92.5v.2h-.5M248.9 93.6v.1M248.9 91.9l.2 .1M249 94.2v.2M249 94.6v.1M249 94.6v.2M249 93.9h.1M249.1 92h.1M249.1 94.8h.6M249.1 92.1v.9M249.1 93.9v.8M249.2 95h.1"/>
<path d="M249.2 91.5h.1M249.2 93l-2.6 .1M249.2 92.5v.5M249.2 95.1h.1M249.3 95v1M249.3 97.1v1M249.3 94.2h.4M249.3 91.2h.1M249.3 91.4v.6h.8M249.3 90.5v.3M249.3 91.1v.5M249.3 90.5l.2 .1"/>
<path d="M249.3 95.1h.1M249.3 91.8v.5M249.3 92.6v.3M249.4 95v1M249.4 97.1v1M249.4 93.6v.1M249.4 93.8v.1M249.4 95.1h.1M249.5 95v1M249.5 97.1v1M249.5 92.7l-.2 .2M249.5 93.9v.1"/>
<path d="M249.5 94.1v.2M249.5 93.9h.1M249.6 94.7v.1M249.6 94.2v.2h1.9M249.6 95.1h.2M249.6 90.8l.2 .1M249.6 93.6h.1M249.7 93l-.1 .6M249.8 93.9l-.2 .1M249.8 90.9l.9 .2M249.8 91.2v.3M249.8 92.2l-.1 .3"/>
<path d="M249.8 91.6h.9M249.8 92.3l1.5 .1M249.8 91h1.6M249.8 95.1h.1M249.9 95.1h.1M250 95h.1M250.1 95h.1M250.1 93.9h.1M250.1 93.6h.1M250.1 95.5v.1M250.1 95.8l.1 .4M250.1 94.2h.5"/>
<path d="M250.1 94.8h.5M250.2 95.1h.1M250.2 95.4h.1M250.2 95.2h.1M250.2 95.3h.1M250.3 96.4v.2M250.3 93.4l-1.3 .2M250.3 93v.2M250.3 96.6h.1M250.4 93.9h.1M250.4 96.6h.1M250.4 93.6v.1"/>
<path d="M250.4 93.9v.1M250.4 94.2v.1M250.4 93h1.7M250.4 96.7l.1 .1M250.5 96.8h.1M250.6 91.5h.6M250.6 96.8h.2M250.7 94.8h.4M250.7 91.8h-.9v.3M250.8 94.2v.2M250.8 94.7v.1M251 96.8h.2"/>
<path d="M251.1 92.1h1.6M251.1 93.9h.1M251.1 93.6v.1M251.1 93.8v.2M251.1 93.6h.1M251.1 94.1v.2M251.2 91.5h.1M251.2 92.5h.1M251.2 96.8h.1M251.2 95v1M251.2 97.1v1M251.3 91.5l.1 .5"/>
<path d="M251.3 94.2v.2M251.3 94.6v.2M251.3 96.8h.1M251.4 92.5v.5M251.5 94.8h.2M251.5 96.7l-.1 .1M251.5 96.7h.1M251.6 96.4l-.1 .2M251.6 93.5v.1M251.6 93.9v.1M251.6 94.2v.1M251.6 93.9h.1"/>
<path d="M251.6 93.6h.1M251.7 91.6h1M251.7 94.2h.6M251.7 91.8h1M251.7 92.3l2.8 .1M251.7 91.1h1.1M251.7 93.9v.8M251.7 95v.3M251.7 95.7v.5M251.8 92h.1M251.8 92l-.1 1h2.5M251.8 93.6h-.8"/>
<path d="M251.9 93.9h.1M251.9 93h.1M251.9 91.5h2.3M252 94.2v.2M252 94.7v.1M252 93.9h-3M252 91.8l.3 .1M252 91.8l-.1 .1M252 93.6h.3M252 91.5h.1M252 91.8l-.9 .2M252 91.2v.1"/>
<path d="M252 91.5v.1M252.1 93.2h1.9M252.2 93.9v.1M252.2 94.1v.2M252.2 93.9h.1M252.2 93.6v.1M252.3 95v1M252.3 97.1v1M252.3 91.9h.1M252.3 93.4h.1M252.4 93.5h.1M252.4 93.2h.1"/>
<path d="M252.4 93.2l-.1 .1M252.4 93h.1M252.4 93.1h.1M252.4 92.5v.1M252.4 92.4h.1M252.4 92.9v.3M252.4 94.2h1.3M252.4 93.9h.1M252.4 93.6h.1M252.4 92.1h.1M252.4 93.4v.2M252.4 93.6h.4"/>
<path d="M252.5 92.4h.1M252.5 92v.1M252.5 93h.1M252.5 92.1h.1M252.5 92.2v.8M252.5 93.9v.8M252.5 92.2h.1M252.6 93.6h.1M252.6 92.5h.5M252.6 93.2v.3h.7h-.3M252.6 92.4v.2M252.6 92.8h.1"/>
<path d="M252.6 92.7h.1M252.6 92.4h.1M252.6 92.8l-.1 .1M252.6 92.3h.1M252.6 92.1h.1M252.6 91.8h.1M252.6 91.2v.1M252.6 91.4v.1M252.6 91.6h.1M252.7 92.1h.1M252.7 93h.1M252.7 93h-.1"/>
<path d="M252.8 93.6h.1M252.8 92.2v.1M252.8 93v.2M252.8 93.4v.2M252.8 92.3h.1M252.8 92.8v.1M252.8 93.9h.1M252.9 93.6h.1M252.9 93h.1M252.9 92.7h.1M252.9 92.4v.2M252.9 92.1h.2"/>
<path d="M252.9 93.5h.1M252.9 91l1.6 .1M253 93h.1M253 91.7l.2 .1M253 91.6h.1M253 91.1h.3M253 93.9v.1M253 94.2v.1M253.1 93.9v.1M253.1 94.1v.2M253.1 93.9h.1M253.1 93.6v.1"/>
<path d="M253.1 91.4l-.2 .2M253.1 91.1v.1M253.1 91.8v.1M253.1 92.1v.2M253.1 93h-.6M253.2 93.9h-.9h.3M253.2 94.3l.1 .1M253.2 94.6l.1 .1M253.2 93h.4M253.2 92.1h.4M253.2 93.6h.7M253.3 94.3h.1"/>
<path d="M253.3 91.5v.4M253.3 92.5v.5M253.4 91l.1 .1M253.4 91.6h.8M253.4 93.9h1M253.5 92.3h.1M253.5 91.8h.7M253.6 91.1h.6M253.6 94.2v.2M253.6 94.6v.2M253.7 93.6h.1M253.7 91.6h.1"/>
<path d="M253.7 91.7v.1M253.7 93.2v.3h.6M253.7 93.7v1.1M253.7 93.3h-2.1M253.7 93.9h.1M253.7 89.1h2.2M253.7 93.6l.1 .1M253.7 93.3h.1M253.8 91l.1 .1M253.8 92.5h.5v.3M253.8 93.9h.1M253.8 93.7h.1"/>
<path d="M253.8 93.9h-.1M253.8 91.1v.1M253.8 91.4v.2M253.8 91.8v.1M253.8 92.1l.1 .2M253.8 93.3h.1M253.8 94.3h.2M253.8 93.2l.2 .1M253.8 93.3l.2 .1M253.9 92.3h.1M253.9 93h.3M253.9 92.1h.3"/>
<path d="M254 93.5h.1M254 93.3h.1M254 94.3v.1M254 94.6v.1M254 94.3h.1M254 93.6h.1M254.1 91.5v.7M254.1 92.9v.7M254.1 93.5l.1 .1M254.1 93.6h.1M254.1 93.6h.3M254.2 93.9h.2"/>
<path d="M254.2 93.2h.1M254.2 93.9h.1M254.2 93h.1M254.2 92.1h.1M254.2 93.3h.1M254.2 94.7v.1M254.2 92.3h.1M254.2 93.6h.1M254.2 93.4h.1M254.3 92.3h.1M254.3 94.2v.2M254.3 93v.6"/>
<path d="M254.3 92.2v.1M254.3 94.3l-.1 .1M254.3 94.3h.1M254.3 93.6h.1M254.3 94.6v.2M254.3 92.7h.1M254.3 92.8l-.5 .2M254.3 93.9h.1M254.4 93.5h.1M254.4 92.3h.1M254.4 93.9v.1M254.4 94.2v.1"/>
<path d="M254.4 92.4v.2M254.4 93v.3M254.4 93.5v.1M254.4 93.9h.1M254.4 92.4h.1M254.5 92.8v.2M254.5 93h.1M254.5 93.1h.1M254.5 93.6h.1M254.5 93.5h.1M254.5 93.2h.1M254.5 93.9h.1"/>
<path d="M254.5 93v.2M254.5 93.3v.2M254.5 93.4h.1M254.5 94.3l.1 .1M254.5 92.3h.1M254.5 92.3v.1M254.6 94.6v.1M254.6 93.9h.1M254.6 93.6h.1M254.6 93.9h-.1M254.7 93.6v.1M254.7 93.8l-.1 .2"/>
<path d="M254.7 91.9h-2.5M254.8 91.1h.5M254.8 93.9h.1M254.8 91.6h.6M254.8 92.3h.5M254.9 91.8h.5M254.9 93v.9M254.9 91.5v.8M254.9 93.9h.1M255 93v.2M255 93.4l-.2 .1M255.2 91.9h.4"/>
<path d="M255.3 91.1h.1M255.3 92.3h.1M255.3 94.4h.1M255.3 92.2v.1M255.4 94.4h-2M255.5 92.1h.1M255.5 91.6h.1M255.5 91.8h.1M255.5 91.8v.1M255.5 91.3v.4M255.6 94.3h.1M255.6 94.3l-.1 .1"/>
<path d="M255.6 91.6h.1M255.6 92.5v.4M255.6 91.8h.1M255.6 91.2h.1M255.6 94.1h.1M255.6 94.1v.1M255.6 91.4v.5M255.9 91.9v1M255.9 89.1v.6M255.9 90.4v1M255.9 93.6v.6h-1.1M256 94.3h.1"/>
<path d="M256 89l-.1 .1M256.1 94.4h.1M256.1 88.9h.1M62.6 100v.4M62.6 100.8v.2h.8M62.9 100v.3M62.9 100.7v.3M63 100h.2M63.4 100h.1M64.2 101h.8M65.6 100v.4M65.6 100.8v.2"/>
<path d="M65.8 102.1h.2M65.9 100v.4M65.9 100.8l.1 .2M66.2 101h2.5M66.5 101.8l-.2 .3M66.5 100v.4M66.5 100.8v.6M66.5 100v.3M66.5 100.7v.3M71 101h2.2M72.3 110.7v1.4M73.6 108h-1.3v1.3"/>
<path d="M75 108h1.2v1.3M75.3 101h2.2M76.2 110.7v1.4M79.7 101h2.6M82 101v-.2v.6M82 100v.4M82 101.8l.2 .3M82.5 101h.2M82.5 102.1h.2M82.6 100v.4M82.6 100.8v.2M82.9 100v.4"/>
<path d="M82.9 100.8v.2M83.5 101h.7M85.6 100v.3M85.6 100.7v.3M85.8 100v.4M85.8 100.8v.2h-.8M126.2 105.6l-.3 1M127 101.8v1.6l-.4 1.1M127.2 104.3l.1 2.9M127.2 104.5h.1M127.2 101.5h.1M127.2 101.6h.1"/>
<path d="M127.3 101.9l.2 .6M127.3 101.9h.1M127.4 107.6h.1M127.4 107.6l.4 .3M127.4 101.5h.1M127.5 103.6h.7M127.5 102.2v1.7M127.5 106.6l.3 .3M127.5 106.6h.1M127.5 106.8v.3M127.5 101.5h.1M127.5 101.6h.1"/>
<path d="M127.5 101.8h.1M127.5 104.3l-.1 .2M127.5 107.1h.1M127.6 101.8l.1 .6M127.6 103.1l.2 .5M127.7 107.4l.3 .3M127.7 107.4h.1M127.8 107.9h.1M127.9 103l.2 .6M128 107.7h.1M128.2 107.3l.3 .4h.8M128.2 108.1h.1"/>
<path d="M128.3 108.1l1 .1M128.3 107.8h.1M128.3 107.8l1.1 .1M128.7 107.9h.1M128.7 107.7v.5M128.7 108.9v.5M129.5 101.9v1.7h-.6M130.8 107.7v.5M130.8 108.9v.5M130.9 107.9h.1M130.9 108.1v.1M131.2 107.8l-.9 .1"/>
<path d="M131.3 108.1l-1.1 .1M131.3 107.8h.1M131.3 108.1h.1M131.3 107.4l-1.1 .3M131.6 107.7h.1M131.7 107.9h.1M131.9 107.4l-.3 .3M131.9 107.4h.1M132 107.1h.1M132 106.6l-.3 .4M132 100.7h.1M132 106.6h.1"/>
<path d="M132 106.8v.3M132.1 100.5l-.1 .2M132.1 107.6h.1M132.1 107.6l-.4 .3M132.3 100.6v.1M132.3 100.7h.1M132.3 100.7v2.1M132.3 104.9v2.3M132.4 100.4h.1M132.5 100.3h.1M132.5 101.8v1.6l.7 1M132.7 100.1h.1"/>
<path d="M132.7 100.1l-.2 .1M132.8 100h.1M132.9 100h.1M133 100h.6M133.1 109.3h.1M133.1 109.3v.1M133.2 109.3h.5M133.4 109.4h.1M133.4 109.3h.1M133.9 105.6l.6 1M133.9 102.4v2h.9M134.1 109.4h.1"/>
<path d="M134.1 109.3h.1M134.3 100h.7M134.3 109.2v.1M134.5 106.6h.1M134.5 101.9v3.5M134.5 109.3h.1M134.7 106.6h.1M134.8 100.4v.9h.4M134.8 106.6v.9M134.8 108.5v.9M134.9 109.3h-.7M135.1 109.3h.8"/>
<path d="M135.2 100.1l.3 .2M135.2 102.1v3.6M135.2 107.6v1.8M135.3 109.3h.1M135.5 100.3h.1M135.5 100.5h.1M135.5 109.3h.1M135.6 100.6h.1M135.6 100.6l.4 2.1M135.6 100.5v.1M135.6 101.3h1.5M135.7 100.1h.1"/>
<path d="M135.8 100.4l.1 .1M135.8 100.4h.1M135.9 100.5l-.1 .1M135.9 100.5l.4 2.2M136 100.4v.9M136.1 108.3l.1 .1M136.1 108.3h1.1M136.1 108.3v.3M136.1 109v.3h.2M136.3 104.9l.4 2.2M136.4 109.3h1.3M136.4 108.5h.2"/>
<path d="M136.6 108.5v.2M136.6 108.9v.2M136.6 108.5h1.1M136.6 109.1h1M136.6 109.1h-.1M136.6 104.9l.4 2.1M136.6 102.4v2h-.8M136.7 107.1h.1M136.7 107.1l.1 .2M136.8 107.3h.1M136.9 109.3h.1M136.9 109.3v.1"/>
<path d="M137 107.6l.4 .4M137 107h.1M137 107.1l.1 .1M137.1 107.2h.1M137.3 107.5l.3 .2M137.3 107.5h.1M137.4 108h.1M137.5 107.7h.1M137.7 108.1l.6 .1M137.8 107.8h.1M137.8 107.8l.2 .1M138 107.9h.1"/>
<path d="M138 108v.2M138 107.9h.3M138.2 101.3h2M138.3 108.3h1M138.5 109.3h.8M138.7 109.1h1M138.7 108.2h.3M138.7 108.5h1M138.7 107.9h.3M139 107.9h.1M139 108.1v.1M139.3 108.3l.1 .1"/>
<path d="M139.3 100.4v.9M139.3 108.3v.4M139.3 109.1v.2M139.4 109.3h-.1M139.6 108.5h.1M139.7 109.1h-.1M139.7 108.5v.2M139.7 108.9v.2M141.1 101.3h.9M146.8 100.4v.9M152.4 101.1h.1M152.4 101.3h.1"/>
<path d="M152.4 101.1h1.2M154.9 101.1l1.3 .1M156.2 101.3h.1M160.2 101.1v.2M161.7 100.4v.9M162 100.5h-1.8v.3M165.1 104.4h.1M165.6 104.7h.1M165.6 103.5l.1 .1M165.9 103.7h.1M166.1 103l.1 .2M166.2 103.3l.1 .2"/>
<path d="M166.5 101.3h.9M167.5 100.2l-3.6 .2M168.4 101.3h1.9M168.8 108.5h1M168.8 108.5v.2M168.8 108.9v.2M168.8 109.1h.1M168.8 109.1h.9M168.9 108.5h-.1M169.1 109.3h.1M169.2 108.3l-.1 .1M169.2 109.3h1"/>
<path d="M169.2 108.3h1.1M169.2 108.3v.3M169.2 109v.3M169.2 100.4v.9M170.9 109.1h1M170.9 101.2l-3.3 1.2M170.9 108.5h1M171 101.6l-3.2 1.3M171.3 100.1h.1M171.3 100.1l-1.9 .1M171.4 108.3h1M171.5 101.3h1.4"/>
<path d="M171.5 109.3h.1M171.5 109.4h.1M171.8 102.4v2h1M171.9 108.5v.2M171.9 108.9v.2M171.9 109.1h.1M172 108.5h-.1M172.4 108.3l-.2 .1M172.4 108.3v.4M172.4 109.1l-.1 .2M172.5 100.4v.9M172.8 109.3h-1.4"/>
<path d="M172.8 109.3h.1M173 109.3h.4M173.1 109.3h.1M173.7 106.6h.1M173.7 100.4v.9h-.4M173.7 106.6v.9M173.7 108.5v.9M174 101.9v3.5M174.1 109.3h.1M174.2 100.2l.1 .2M174.3 100.4l-1.6 .6M174.6 105.6l-.7 1"/>
<path d="M174.7 102.4v2h-.9M174.8 100.3l-.5 .1M175.2 100.3l.4 .1M175.3 109.3h-1.6M175.3 109.4h.1M175.3 109.3h.1M175.8 100.5l.1 .1M175.8 100.5h.1M175.9 100.8h.2M176 100v1.7M176 103.4l-.7 1.1M176 102.6v2"/>
<path d="M176 105.7v1.5M176.2 107.7h.1M176.2 107.7l.5 .4M176.3 100.8h.2M176.4 100.6l.1 .2M176.5 107.1h.1M176.5 106.6l.3 .3M176.5 100v.8M176.5 106.6h.1M176.5 106.8v.3M176.7 107.4l.2 .3M176.7 107.4h.1"/>
<path d="M176.9 107.7h.1M177.1 107.3l.4 .4h.8M177.1 108.3h1.2M177.3 107.8l1 .1M177.7 107.7l-.1 .6M177.7 108.9v.5M179 101.9v1.7h.7M179.1 108.3h1.1M179.8 107.7v.6M179.8 108.9v.5M180.2 107.8l-1 .1M180.2 107.8h.1"/>
<path d="M180.2 107.4l-1.1 .3M180.4 103.6h.6M180.4 103.1l-.2 .5M180.5 107.7h.1M180.8 107.4l-.3 .3M180.8 108.1l-.1 .1M180.8 107.4h.1M180.9 101.9h.1M180.9 101.9l-.2 .5M180.9 107.1h.1M180.9 103.2l-.2 .4M180.9 101.7h.1"/>
<path d="M181 106.6l-.4 .4M181 106.6h.1M181 106.8l-.1 .3M181 104.2l.1 .3M181 101.5h.1M181 101.6h.1M181 102.2v1.7M181.2 107.6l-.4 .5M181.3 101.5h.2M181.4 101.9l-.3 .7M181.4 101.7v.1M181.5 102l-.2 2.5"/>
<path d="M181.5 101.5h.1M181.5 105.7l-.1 1.5M181.5 103.4l.4 1M182.2 105.6l.5 1M104.8 173.1h.1M104.8 173.1h.7M104.8 173.1l.1 .1M105.2 173.4l.2 .3M105.4 175.3h.1M105.4 173.7v2.4M105.4 178.5v4.8M105.4 173.7h.3"/>
<path d="M105.5 175.3v2M105.5 179.4v4.1M106.2 173.7h.4M106.4 173.1h.8M106.5 175.3h.1M106.6 173.7l-.1 3.7M106.6 178.5l-.1 5M106.8 173.4l-.2 .3M107.2 173.1h.1M107.2 173.1l-.2 .1M109.8 173.1h.1M109.8 173.1h.8"/>
<path d="M109.8 173.1l.2 .1M110.3 173.4l.2 .3M110.5 175.3h.1M110.5 173.7v2.4M110.5 178.5v4.8M110.5 173.7h.3M110.6 175.3v2M110.6 179.4v4.1M111.2 173.7h.5M111.5 173.1h.8M111.6 175.3h.1M111.7 173.7l-.1 3.7"/>
<path d="M111.7 178.5l-.1 5M111.9 173.4l-.2 .3M112.3 173.1h.1M112.3 173.1l-.2 .1M114.9 173.1h.1M114.9 173.1h.8M114.9 173.1l.2 .1M115.4 173.4l.2 .3M115.6 175.3h.1M115.6 173.7v2.4M115.6 178.5v4.8M115.6 173.7h.3"/>
<path d="M115.6 175.3v2M115.6 179.4v4.1M116.3 173.7h.4M116.5 173.1h.8M116.7 175.3h.1M116.7 173.7v3.7M116.7 178.5v5M117 173.4l-.3 .3M117.3 173.1h.1M117.3 173.1l-.1 .1M120 173.1h.1M120 173.1h.8"/>
<path d="M120 173.1l.2 .1M120.4 173.4l.2 .3M120.6 175.3h.1M120.6 173.7v2.4M120.6 178.5v4.8M120.6 173.7h.4M120.7 175.3h.1M120.7 175.3v2M120.7 179.4v4.1M121.4 173.7h.4M121.6 173.1h.8M121.7 175.3h.1"/>
<path d="M121.7 175.3v2.1M121.7 179.5v4M121.8 175.3h.1M121.8 173.7v2.4M121.8 178.5v4.8M122 173.4l-.2 .3M122.4 173.1h.1M122.4 173.1l-.1 .1M125.1 173.1h.1M125.1 173.1h.8M125.1 173.1l.2 .1M125.5 173.4l.2 .3"/>
<path d="M125.7 175.3h.1M125.7 173.7v2.4M125.7 178.5v4.8M125.7 173.7h.4M125.8 175.3h.1M125.8 175.3v2M125.8 179.4v4.1M126.5 173.7h.4M126.7 173.1h.8M126.8 175.3h.1M126.8 175.3v2.1M126.8 179.5v4"/>
<path d="M126.9 175.3h.1M126.9 173.7v2.4M126.9 178.5v4.8M127.1 173.4l-.2 .3M127.5 173.1h.1M127.5 173.1l-.2 .1M130.2 173.1h.1M130.2 173.1h.7M130.2 173.1l.1 .1M130.6 173.4l.5 .3M130.8 175.3h.1M130.8 173.7v2.4"/>
<path d="M130.8 178.5v4.8M130.9 175.3v2M130.9 179.4v4.1M131.6 173.7h.4M131.8 173.1h.8M131.9 175.3h.1M131.9 175.3v2.1M131.9 179.5v4M132 173.7v2.4M132 178.5v4.8M132.2 173.4l-.2 .3M132.6 173.1h.1"/>
<path d="M132.6 173.1l-.2 .1M135.2 173.1h.1M135.2 173.1h.8M135.2 173.1l.2 .1M135.7 173.4l.5 .3M135.9 175.3h.1M135.9 173.7v2.4M135.9 178.5v4.8M136 175.3v2M136 179.4v4.1M136.6 173.7h.5M136.9 173.1h.8"/>
<path d="M137 175.3h.1M137 175.3v2.1M137 179.5v4M137.1 173.7v2.4M137.1 178.5v4.8M137.3 173.4l-.2 .3M137.7 173.1h.1M137.7 173.1l-.2 .1M140.3 173.1h.1M140.3 173.1h.8M140.3 173.1l.2 .1M140.8 173.4l.5 .3"/>
<path d="M141 175.3h.1M141 173.7v2.4M141 178.5v4.8M141 175.3v2M141 179.4v4.1M141.7 173.7h.4M141.9 173.1h.8M142.1 175.3h.1M142.1 175.3v2.1M142.1 179.5v4M142.1 173.7v2.4M142.1 178.5v4.8"/>
<path d="M142.4 173.4l-.3 .3M142.7 173.1h.1M142.7 173.1l-.1 .1M145.4 173.1h.1M145.4 173.1h.8M145.4 173.1l.2 .1M145.8 173.4l.6 .3M146 175.3h.1M146 173.7l.1 3.6M146 178.5l.1 5M146.1 175.3h.1M146.8 173.7h.4"/>
<path d="M147 173.1h.8M147.1 175.3h.1M147.1 175.3v2.1M147.1 179.5v4M147.2 173.7v2.4M147.2 178.5v4.8M147.4 173.4l-.2 .3M147.8 173.1h.1M147.8 173.1l-.1 .1M150.5 173.1h.1M150.5 173.1h.8M150.5 173.1l.2 .1"/>
<path d="M150.9 173.4l.6 .3M151.1 173.7l.1 3.6M151.1 178.5l.1 5M151.1 175.3h.1M151.2 175.3h.1M151.9 173.7h.4M152.1 173.1h.8M152.2 175.3h.1M152.2 175.3v2.1M152.2 179.5v4M152.3 173.7v2.4M152.3 178.5v4.8"/>
<path d="M152.5 173.4l-.2 .3M152.9 173.1h.1M152.9 173.1l-.2 .1M155.6 173.1h.1M155.6 173.1h.7M155.6 173.1l.1 .1M156 173.4l.2 .3M156.2 173.7h.3M156.2 173.7v2.4M156.2 178.5v4.8M156.2 175.3h.1M156.3 175.3v2"/>
<path d="M156.3 179.4v4.1M157 173.7h.4M157.2 173.1h.8M157.3 175.3h.1M157.3 175.3v2.1M157.3 179.5v4M157.4 173.7v2.4M157.4 178.5v4.8M157.6 173.4l-.2 .3M158 173.1h.1M158 173.1l-.2 .1M160.6 173.1h.1"/>
<path d="M160.6 173.1h.8M160.6 173.1l.2 .1M161.1 173.4l.1 .3M161.2 173.7h.4M161.3 173.7v2.4M161.3 178.5v4.8M161.3 175.3h.1M161.4 175.3v2M161.4 179.4v4.1M162 173.7h.5M162.3 173.1h.8M162.4 175.3h.1"/>
<path d="M162.4 175.3v2.1M162.4 179.5v4M162.5 173.7v2.4M162.5 178.5v4.8M162.7 173.4l-.2 .3M163.1 173.1h.1M163.1 173.1l-.2 .1M165.7 173.1h.1M165.7 173.1h.8M165.7 173.1l.2 .1M166.2 173.4l.1 .3M166.3 173.7h.4"/>
<path d="M166.4 175.3h.1M166.4 173.7v2.4M166.4 178.5v4.8M166.4 175.3v2M166.4 179.4v4.1M167.1 173.7h.4M167.3 173.1h.8M167.4 175.3h.1M167.4 175.3v2.1M167.4 179.5v4M167.5 175.3h.1M167.5 173.7v2.4"/>
<path d="M167.5 178.5v4.8M167.8 173.4l-.3 .3M168.1 173.1h.1M168.1 173.1l-.1 .1M170.8 173.1h.1M170.8 173.1h.8M170.8 173.1l.2 .1M171.2 173.4l.2 .3M171.4 173.7h.4M171.4 175.3h.1M171.4 173.7v2.4M171.4 178.5v4.8"/>
<path d="M171.5 175.3h.1M171.5 175.3v2M171.5 179.4v4.1M172.2 173.7h.4M172.4 173.1h.8M172.5 175.3h.1M172.5 175.3v2.1M172.5 179.5v4M172.6 175.3h.1M172.6 173.7v2.4M172.6 178.5v4.8M172.8 173.4l-.2 .3"/>
<path d="M173.2 173.1h.1M173.2 173.1l-.1 .1M175.9 173.1h.1M175.9 173.1h.8M175.9 173.1l.2 .1M176.3 173.4l.2 .3M176.5 173.7h.4M176.5 175.3h.1M176.5 173.7v2.4M176.5 178.5v4.8M176.6 175.3h.1M176.6 175.3v2"/>
<path d="M176.6 179.4v4.1M177.3 173.7h.4M177.5 173.1h.8M177.6 175.3v2.1M177.6 179.5v4M177.6 175.3h.1M177.7 175.3h.1M177.7 173.7v2.4M177.7 178.5v4.8M177.9 173.4l-.2 .3M178.3 173.1h.1M178.3 173.1l-.2 .1"/>
<path d="M181 173.1h.1M181 173.1h.7M181 173.1l.1 .1M181.4 173.4l.2 .3M181.6 173.7h.3M181.6 175.3h.1M181.6 173.7v2.4M181.6 178.5v4.8M181.7 175.3v2M181.7 179.4v4.1M182.4 173.7h.4M182.6 173.1h.8"/>
<path d="M182.7 175.3h.1M182.7 175.3v2.1M182.7 179.5v4M182.8 173.7v2.4M182.8 178.5v4.8M183 173.4l-.2 .3M183.4 173.1h.1M183.4 173.1l-.2 .1M186 173.1h.1M186 173.1h.8M186 173.1l.2 .1M186.5 173.4l.1 .3"/>
<path d="M186.6 175.3h.1M186.6 173.7v2.4M186.6 178.5v4.8M186.6 173.7h.4M186.7 175.3h.1M186.8 175.3v2M186.8 179.4v4.1M187.4 173.7h.5M187.7 173.1h.8M187.7 175.3h.1M187.7 175.3v2.1M187.7 179.5v4"/>
<path d="M187.8 175.3h.1M187.9 173.7v2.4M187.9 178.5v4.8M188.1 173.4l-.2 .3M188.5 173.1h.1M188.5 173.1l-.2 .1M191.1 173.1h.1M191.1 173.1h.8M191.1 173.1l.2 .1M191.6 173.4l.1 .3M191.7 175.3h.1M191.7 173.7v2.4"/>
<path d="M191.7 178.5v4.8M191.7 173.7h.4M191.8 175.3h.1M191.8 175.3v2M191.8 179.4v4.1M192.5 173.7h.4M192.7 173.1h.8M192.8 175.3h.1M192.8 175.3v2.1M192.8 179.5v4M192.9 175.3h.1M192.9 173.7v2.4"/>
<path d="M192.9 178.5v4.8M193.2 173.4l-.3 .3M193.5 173.1h.1M193.5 173.1l-.1 .1M196.2 173.1h.1M196.2 173.1h.8M196.2 173.1l.2 .1M196.6 173.4l.2 .3M196.8 175.3h.1M196.8 173.7v2.4M196.8 178.5v4.8M196.8 173.7h.4"/>
<path d="M196.9 175.3h.1M196.9 175.3v2M196.9 179.4v4.1M197.6 173.7h.4M197.8 173.1h.8M197.9 175.3h.1M197.9 175.3v2.1M197.9 179.5v4M198 175.3h.1M198 173.7v2.4M198 178.5v4.8M198.2 173.4l-.2 .3"/>
<path d="M198.6 173.1h.1M198.6 173.1l-.1 .1M201.3 173.1h.1M201.3 173.1h.8M201.3 173.1l.2 .1M201.7 173.4l.2 .3M201.9 175.3h.1M201.9 173.7v2.4M201.9 178.5v4.8M201.9 173.7h.4M202 175.3h.1M202 175.3v2"/>
<path d="M202 179.4v4.1M202.7 173.7h.4M202.9 173.1h.8M203 175.3h.1M203 175.3v2.1M203 179.5v4M203.1 175.3h.1M203.1 173.7v2.4M203.1 178.5v4.8M203.3 173.4l-.2 .3M203.7 173.1h.1M203.7 173.1l-.2 .1"/>
<path d="M332.4 173.1l.2 .1M332.4 173.1h.1M332.4 173.1h.7M332.8 173.4l.2 .3M333 173.7h.3M333 173.7v2.4M333 178.5v4.8M333.4 175.3v2.1M333.4 179.6v4.3M333.4 175.3h.1M333.7 175.3l.1 2.1M333.7 175.3h.1"/>
<path d="M333.8 179.6v4.3M333.8 173.7h.4M334 173.1h.8M334.2 173.7v2.4M334.2 178.5v4.8M334.4 173.4l-.2 .3M334.8 173.1h.1M334.8 173.1l-.2 .1M337.5 173.1l.1 .1M337.5 173.1h.1M337.5 173.1h.7M337.9 173.4l.2 .3"/>
<path d="M338.1 173.7h.3M338.1 173.7v2.4M338.1 178.5v4.8M338.4 175.3h.1M338.4 175.3v2.1M338.4 179.6v4.3M338.7 175.3h.2M338.7 175.3l.2 2.1M338.9 173.7h.4M338.9 179.6v4.3M339 173.1h.8M339.3 173.7v2.4"/>
<path d="M339.3 178.5v4.8M339.5 173.4l-.2 .3M339.8 173.1h.1M339.8 173.1l-.1 .1M103.5 188.4h1.7M103.5 189.7h1.7M105.4 193.9l.1 .1M105.4 189.7v.1M105.4 189.9v.2M105.4 198h.3M105.4 192.9l.3 .1M105.4 185.8v2.5h.3"/>
<path d="M105.5 185.5v2.1h.3M105.5 197.3l-.1 .1M105.5 192.2l-.1 .1M105.7 198v.1M105.7 198.2v.2M105.7 193.2l-.3 .1M105.8 197.2h.4M105.8 192.2h.4M105.8 194.1h.4M106.2 198h.4M106.2 192.9h.4M106.2 193.3h.4"/>
<path d="M106.2 187.6h.3M106.3 198v.1M106.3 198.2v.2M106.3 192.9v.1M106.3 193.2v.1M106.5 197.3l.1 .1M106.5 192.2l.1 .1M106.5 185.6l.1 2.7h-.4M106.6 193.9l-.2 .1M106.6 189.7v.1M106.6 190v.1M107 188.4h3.5"/>
<path d="M107 189.7h3.5M110.5 193.9l.1 .1M110.5 189.7v.1M110.5 189.9v.2M110.5 198h.3M110.5 192.9l.3 .1M110.5 185.8v2.5h.3M110.6 185.5v2.1h.3M110.6 197.3l-.1 .1M110.6 192.2l-.1 .1M110.8 198v.1M110.8 198.2v.2"/>
<path d="M110.8 193.2l-.3 .1M110.9 197.2h.4M110.9 192.2h.4M110.9 194.1h.4M111.2 198h.5M111.2 192.9h.5M111.2 193.3h.5M111.2 187.6h.4M111.4 198v.1M111.4 198.2v.2M111.4 192.9v.1M111.4 193.2v.1"/>
<path d="M111.5 192.2l.2 .1M111.5 197.3l.2 .1M111.6 185.6l.1 2.7h-.5M111.7 193.9l-.2 .1M111.7 189.7v.1M111.7 190v.1M112.3 188.4h3.6M112.3 189.7h3.6M115.6 198h.3M115.6 193.9v.1M115.6 189.7v.1M115.6 189.9v.2"/>
<path d="M115.6 192.9l.3 .1M115.6 185.8v2.5h.3M115.6 185.5v2.1h.3M115.7 197.3l-.1 .1M115.7 192.2l-.1 .1M115.9 198v.1M115.9 198.2v.2M115.9 193.2l-.3 .1M115.9 197.2h.5M115.9 192.2h.5M115.9 194.1h.5M116.3 198h.4"/>
<path d="M116.3 192.9h.4M116.3 193.3h.4M116.3 187.6h.4M116.5 198v.1M116.5 198.2v.2M116.5 192.9v.1M116.5 193.2v.1M116.6 197.3l.1 .1M116.6 192.2l.1 .1M116.7 185.6v2.7h-.4M116.7 193.9l-.1 .1M116.7 189.7v.1"/>
<path d="M116.7 190v.1M117.7 188.4h3.5M117.7 189.7h3.5M120.6 198h.4M120.6 193.9l.1 .1M120.6 189.7v.1M120.6 189.9v.2M120.6 192.9l.3 .1M120.6 185.8v2.5h.4M120.7 185.5v2.1h.3M120.8 197.3l-.2 .1M120.8 192.2l-.2 .1"/>
<path d="M120.9 198v.1M120.9 198.2v.2M120.9 193.2l-.3 .1M121 197.2h.4M121 192.2h.4M121 194.1h.4M121.4 198h.4M121.4 192.9h.4M121.4 193.3h.4M121.5 198v.1M121.5 198.2v.2M121.5 192.9v.1"/>
<path d="M121.5 193.2v.1M121.7 197.3l.1 .1M121.7 192.2l.1 .1M121.7 185.6v2h-.3M121.8 193.9l-.1 .1M121.8 189.7v.1M121.8 190v.1M121.8 185.8v2.5h-.4M123.1 188.4h3.5M123.1 189.7h3.5M125.7 193.9l.2 .1M125.7 189.7v.1"/>
<path d="M125.7 189.9v.2M125.7 192.9l.3 .1M125.7 198h.4M125.7 185.8v2.5h.4M125.8 185.5v2.1h.3M125.9 197.3l-.2 .1M125.9 192.2l-.2 .1M126 193.2l-.3 .1M126 198v.1M126 198.2v.2M126.1 197.2h.4M126.1 192.2h.4"/>
<path d="M126.1 194.1h.4M126.5 192.9h.4M126.5 193.3h.4M126.5 198h.4M126.6 192.9v.1M126.6 193.2v.1M126.6 198v.1M126.6 198.2v.2M126.8 197.3l.1 .1M126.8 192.2l.1 .1M126.8 185.6v2h-.3M126.9 193.9l-.2 .1"/>
<path d="M126.9 189.7v.1M126.9 190v.1M126.9 185.8v2.5h-.4M128.4 188.4h3.5M128.4 189.7h3.5M130.8 193.9l.1 .1M130.8 189.7v.1M130.8 189.9v.2M130.8 198h.3M130.8 185.8v2.5h.3M130.8 192.9l.3 .1M130.9 185.5v2.1h.3"/>
<path d="M130.9 197.3l-.1 .1M130.9 192.2l-.1 .1M131.1 193.2l-.3 .1M131.1 198v.1M131.1 198.2v.2M131.2 192.2h.4M131.2 197.2h.4M131.2 194.1h.4M131.6 198h.4M131.6 192.9h.4M131.6 193.3h.4M131.7 192.9v.1"/>
<path d="M131.7 193.2v.1M131.7 198v.1M131.7 198.2v.2M131.8 197.3l.2 .1M131.9 192.2l.1 .1M131.9 185.6v2h-.3M132 193.9l-.2 .1M132 189.7v.1M132 190v.1M132 185.8v2.5h-.4M133.8 188.4h3.5M133.8 189.7h3.5"/>
<path d="M135.9 193.9l.1 .1M135.9 189.7v.1M135.9 189.9v.2M135.9 198h.3M135.9 185.8v2.5h.3M135.9 192.9l.3 .1M136 185.5v2.1h.3M136 197.3l-.1 .1M136 192.2l-.1 .1M136.2 193.2l-.3 .1M136.2 198v.1M136.2 198.2v.2"/>
<path d="M136.3 197.2h.4M136.3 192.2h.4M136.3 194.1h.4M136.6 198h.5M136.6 192.9h.5M136.6 193.3h.5M136.8 192.9v.1M136.8 193.2v.1M136.8 198v.1M136.8 198.2v.2M136.9 197.3l.2 .1M136.9 192.2l.2 .1"/>
<path d="M137 185.6v2h-.4M137.1 193.9l-.2 .1M137.1 189.7v.1M137.1 190v.1M137.1 185.8v2.5h-.5M139.1 188.4h3.5M139.1 189.7h3.5M141 198h.3M141 193.9v.1M141 189.7v.1M141 189.9v.2M141 185.8v2.5h.3"/>
<path d="M141 192.9l.3 .1M141 185.5v2.1h.3M141.1 197.3l-.1 .1M141.1 192.2l-.1 .1M141.3 193.2l-.3 .1M141.3 198v.1M141.3 198.2v.2M141.3 192.2h.5M141.3 197.2h.5M141.3 194.1h.5M141.7 198h.4M141.7 192.9h.4"/>
<path d="M141.7 193.3h.4M141.9 192.9v.1M141.9 193.2v.1M141.9 198v.1M141.9 198.2v.2M142 197.3l.1 .1M142 192.2l.1 .1M142.1 185.6v2h-.4M142.1 193.9l-.1 .1M142.1 189.7v.1M142.1 190v.1M142.1 185.8v2.5h-.4"/>
<path d="M144.4 188.4h3.5M144.4 189.7h3.5M146 198h.4M146 193.9l.2 .1M146 189.7v.1M146 189.9v.2M146 192.9h.4M146 193.3h.4M146.1 185.5l-.1 2.8h.4M146.1 187.6h.3M146.2 197.3l-.2 .1M146.2 192.2l-.2 .1"/>
<path d="M146.3 192.9v.1M146.3 193.2v.1M146.3 198v.1M146.3 198.2v.2M146.4 197.2h.4M146.4 192.2h.4M146.4 194.1h.4M146.8 198h.4M146.8 192.9h.4M146.8 193.3h.4M146.9 192.9v.1M146.9 193.2v.1"/>
<path d="M146.9 198v.1M146.9 198.2v.2M147.1 197.3l.1 .1M147.1 192.2l.1 .1M147.1 185.6v2h-.3M147.2 193.9l-.1 .1M147.2 189.7v.1M147.2 190v.1M147.2 185.8v2.5h-.4M149.8 188.4h3.5M149.8 189.7h3.5M151.1 193.9l.1 .1"/>
<path d="M151.1 189.7v.1M151.1 189.9v.2M151.1 198h.4M151.1 192.9h.4M151.1 193.3h.4M151.2 185.5l-.1 2.8h.4M151.2 187.6h.3M151.3 197.3l-.2 .1M151.3 192.2l-.2 .1M151.4 192.9v.1M151.4 193.2v.1M151.4 198v.1"/>
<path d="M151.4 198.2v.2M151.5 192.2h.4M151.5 197.2h.4M151.5 194.1h.4M151.9 198h.4M151.9 192.9h.4M151.9 193.3h.4M152 192.9v.1M152 193.2v.1M152 198v.1M152 198.2v.2M152.1 197.3l.2 .1"/>
<path d="M152.2 192.2l.1 .1M152.2 185.6v2h-.3M152.3 193.9l-.2 .1M152.3 185.8v2.5h-.4M152.3 189.7v.1M152.3 190v.1M155.1 188.4h3.6M155.1 189.7h3.6M156.2 193.9l.1 .1M156.2 189.7v.1M156.2 189.9v.2M156.2 198h.3"/>
<path d="M156.2 185.8v2.5h.3M156.2 192.9h.3M156.2 193.3h.3M156.3 185.5v2.1h.3M156.3 197.3l-.1 .1M156.3 192.2l-.1 .1M156.5 192.9v.1M156.5 193.2v.1M156.5 198v.1M156.5 198.2v.2M156.6 197.2h.4M156.6 192.2h.4"/>
<path d="M156.6 194.1h.4M157 198h.4M157 192.9h.4M157 193.3h.4M157.1 192.9v.1M157.1 193.2v.1M157.1 198v.1M157.1 198.2v.2M157.3 197.3l.1 .1M157.3 192.2l.1 .1M157.3 185.6v2h-.3M157.4 193.9l-.2 .1"/>
<path d="M157.4 189.7v.1M157.4 190v.1M157.4 185.8v2.5h-.4M160.5 188.4h3.5M160.5 189.7h3.5M161.3 193.9l.1 .1M161.3 189.7v.1M161.3 189.9v.2M161.3 192.9h.3M161.3 193.3h.3M161.3 198h.3M161.3 185.8v2.5h.3"/>
<path d="M161.4 185.5v2.1h.3M161.4 197.3l-.1 .1M161.4 192.2l-.1 .1M161.6 192.9v.1M161.6 193.2v.1M161.6 198v.1M161.6 198.2v.2M161.7 197.2h.4M161.7 192.2h.4M161.7 194.1h.4M162 192.9h.5M162 193.3h.5"/>
<path d="M162 198h.5M162.2 192.9v.1M162.2 193.2v.1M162.2 198v.1M162.2 198.2v.2M162.3 197.3l.2 .1M162.3 192.2l.2 .1M162.4 185.6v2h-.4M162.5 193.9l-.2 .1M162.5 189.7v.1M162.5 190v.1M162.5 185.8v2.5h-.5"/>
<path d="M165.8 188.4h3.6M165.8 189.7h3.6M166.4 198h.3M166.4 193.9v.1M166.4 189.7v.1M166.4 189.9v.2M166.4 192.9h.3M166.4 193.3h.3M166.4 185.8v2.5h.3M166.4 185.5v2.1h.3M166.5 197.3l-.1 .1M166.5 192.2l-.1 .1"/>
<path d="M166.7 192.9v.1M166.7 193.2v.1M166.7 198v.1M166.7 198.2v.2M166.7 197.2h.5M166.7 192.2h.5M166.7 194.1h.5M167.1 198h.4M167.1 192.9h.4M167.1 193.3h.4M167.3 192.9v.1M167.3 193.2v.1"/>
<path d="M167.3 198v.1M167.3 198.2v.2M167.4 197.3l.1 .1M167.4 192.2l.1 .1M167.4 185.6v2h-.3M167.5 193.9l-.1 .1M167.5 189.7v.1M167.5 190v.1M167.5 185.8v2.5h-.4M171.2 188.4h3.5M171.2 189.7h3.5M171.4 198h.4"/>
<path d="M171.4 193.9l.1 .1M171.4 189.7v.1M171.4 189.9v.2M171.4 192.9l.3 .1M171.4 185.8v2.5h.4M171.5 185.5v2.1h.3M171.6 197.3l-.2 .1M171.6 192.2l-.2 .1M171.7 193.2l-.3 .1M171.7 198v.1M171.7 198.2v.2M171.8 197.2h.4"/>
<path d="M171.8 192.2h.4M171.8 194.1h.4M172.2 198h.4M172.2 192.9h.4M172.2 193.3h.4M172.3 192.9v.1M172.3 193.2v.1M172.3 198v.1M172.3 198.2v.2M172.5 192.2l.1 .1M172.5 197.3l.1 .1M172.5 185.6v2h-.3"/>
<path d="M172.6 193.9l-.1 .1M172.6 189.7v.1M172.6 190v.1M172.6 185.8v2.5h-.4M176.5 188.4h3.5M176.5 193.9l.2 .1M176.5 189.9v.2M176.5 198h.4M176.5 192.9l.3 .1M176.5 185.8v2.5h.4M176.6 185.5v2.1h.3M176.7 197.3l-.2 .1"/>
<path d="M176.7 192.2l-.2 .1M176.8 193.2l-.3 .1M176.8 198v.1M176.8 198.2v.2M176.9 197.2h.4M176.9 192.2h.4M176.9 194.1h.4M177.3 198h.4M177.3 192.9h.4M177.3 193.3h.4M177.4 192.9v.1M177.4 193.2v.1"/>
<path d="M177.4 198v.1M177.4 198.2v.2M177.5 192.2l.2 .1M177.6 197.3l.1 .1M177.6 185.6v2h-.3M177.7 193.9l-.2 .1M177.7 189.7v.1M177.7 190v.1M177.7 185.8v2.5h-.4M180 189.7l-3.5 .1M181.6 193.9l.1 .1M181.6 189.7v.1"/>
<path d="M181.6 189.9v.2M181.6 198h.3M181.6 192.9l.3 .1M181.6 185.8v2.5h.3M181.7 185.5v2.1h.3M181.7 197.3l-.1 .1M181.7 192.2l-.1 .1M181.9 188.4h3.5M181.9 189.7h3.5M181.9 193.2l-.3 .1M181.9 198v.1M181.9 198.2v.2"/>
<path d="M182 194.1h.4M182 197.2h.4M182 192.2h.4M182.4 198h.4M182.4 192.9h.4M182.4 193.3h.4M182.5 192.9v.1M182.5 193.2v.1M182.5 198v.1M182.5 198.2v.2M182.7 197.3l.1 .1M182.7 192.3h.1"/>
<path d="M182.7 185.6v2h-.3M182.8 193.9l-.2 .1M182.8 189.7v.1M182.8 190v.1M182.8 185.8v2.5h-.4M186.6 198h.4M186.6 193.9l.2 .1M186.6 189.7v.1M186.6 189.9v.2M186.6 192.9l.4 .1M186.6 185.8v2.5h.4M186.8 185.5v2.1h.3"/>
<path d="M186.8 197.3l-.2 .1M186.8 192.2l-.2 .1M187 193.2l-.4 .1M187 198v.1M187 198.2v.2M187.1 197.2h.4M187.1 192.2h.4M187.1 194.1h.4M187.2 188.4h3.5M187.2 189.7h3.5M187.4 198h.5M187.4 192.9h.5"/>
<path d="M187.4 193.3h.5M187.6 192.9v.1M187.6 193.2v.1M187.6 198v.1M187.6 198.2v.2M187.7 192.2l.2 .1M187.7 197.3l.2 .1M187.7 185.6v2h-.3M187.9 193.9l-.2 .1M187.9 189.7v.1M187.9 190v.1M187.9 185.8v2.5h-.5"/>
<path d="M191.7 193.9l.1 .1M191.7 189.7v.1M191.7 189.9v.2M191.7 192.9l.4 .1M191.7 198h.4M191.7 185.8v2.5h.4M191.8 185.5v2.1h.3M191.9 197.3l-.2 .1M191.9 192.2l-.2 .1M192.1 193.2l-.4 .1M192.1 198v.1M192.1 198.2v.2"/>
<path d="M192.1 194.1h.5M192.1 192.2h.5M192.1 197.2h.5M192.5 192.9h.4M192.5 193.3h.4M192.5 198h.4M192.6 188.4h3.5M192.6 189.7h3.5M192.7 192.9v.1M192.7 193.2v.1M192.7 198v.1M192.7 198.2v.2"/>
<path d="M192.8 197.3l.1 .1M192.8 192.2l.1 .1M192.8 185.6v2h-.3M192.9 193.9l-.1 .1M192.9 189.7v.1M192.9 190v.1M192.9 185.8v2.5h-.4M196.8 193.9l.2 .1M196.8 189.7v.1M196.8 189.9v.2M196.8 198h.4M196.8 192.9l.3 .1"/>
<path d="M196.8 185.8v2.5h.4M196.9 185.5v2.1h.3M197 197.3l-.2 .1M197 192.2l-.2 .1M197.1 193.2l-.3 .1M197.1 198v.1M197.1 198.2v.2M197.2 194.1h.4M197.2 197.2h.4M197.2 192.2h.4M197.6 198h.4M197.6 192.9h.4"/>
<path d="M197.6 193.3h.4M197.7 192.9v.1M197.7 193.2v.1M197.7 198v.1M197.7 198.2v.2M197.9 192.2l.1 .1M197.9 188.4h3.5M197.9 189.7h3.5M197.9 197.3l.1 .1M197.9 185.6v2h-.3M198 193.9l-.1 .1M198 189.7v.1"/>
<path d="M198 190v.1M198 185.8v2.5h-.4M201.9 198h.4M201.9 193.9l.2 .1M201.9 189.7v.1M201.9 189.9v.2M201.9 192.9l.3 .1M201.9 185.8v2.5h.4M202 185.5v2.1h.3M202.1 197.3l-.2 .1M202.1 192.2l-.2 .1M202.2 198v.1"/>
<path d="M202.2 198.2v.2M202.2 193.2l-.3 .1M202.3 194.1h.4M202.3 197.2h.4M202.3 192.2h.4M202.7 198h.4M202.7 192.9h.4M202.7 193.3h.4M202.8 198v.1M202.8 198.2v.2M202.8 192.9v.1M202.8 193.2v.1"/>
<path d="M202.9 192.2l.2 .1M203 197.4h.1M203 185.6v2h-.3M203.1 193.9l-.2 .1M203.1 189.7v.1M203.1 190v.1M203.1 185.8v2.5h-.4M203.3 188.4h1.8M203.3 189.7h1.8M222.5 195.2l-.3 .2 .3 .2M222.9 195l.4-.2v.4M223.3 195.6v.4l-.3-.1"/>
<path d="M327.8 194.1h1M327.8 192.9h1M327.8 198h1M327.8 199.6h1M327.8 199.2h1M327.8 196.4h1M327.8 197.2h1M327.8 192.1h1M327.8 194.4h1M327.8 198.4h1M328.8 193.2l-1 .1M329.9 194.1h1.1"/>
<path d="M329.9 192.9h1.1M329.9 193.3h1.1M329.9 198h1.1M329.9 199.6h1.1M329.9 199.2h1.1M329.9 196.4h1.1M329.9 198.4h1.1M329.9 197.2h1.1M329.9 192.1h1.1M329.9 194.4h1.1M331.1 194.8v1.3M331.1 196.2h.1"/>
<path d="M331.1 196h.1M331.1 194.8h.1M331.1 194.6v.4M331.1 194.6v.6M331.1 195.7v.5M331.8 194.6v.6M331.8 195.7v.5M332 196h.1M332 194.8h.1M332 196.2h.1M332 194.6v.1M332 194.8v.4"/>
<path d="M332 195.7v.4M333 185.8l.1 2.5M333.4 186.1l-.2 2.2M333.4 187.6h.1M333.7 187.6h.1M333.8 188.3h.1M333.8 186.1v2.2M334.2 185.8l-.2 2.5M338.1 185.8l.1 2.5M338.4 187.6h.1M338.4 186.1l-.1 2.2M338.7 187.6h.2"/>
<path d="M338.9 188.3h.1M338.9 186.1v2.2M339.3 185.8l-.2 2.5M61.8 218.9v3M62.7 219v2.8M63 217.6h.1M63.2 214.5l-1.1 2.8M63.8 215.9l-.9 3.6M64 215l-1 2.6M64.8 213.8h.1M64.9 211.9h.1M64.9 212l.2 .1"/>
<path d="M64.9 212l-.9 1.1M65 211.8h.1M65 211.8l.3 .3M65.2 211.7l-.2 .1M65.4 212.4l.2 .2M65.4 211.4l.3-.2 .2 .3M65.6 212.6l-.8 1.2M65.6 212.4l.3 .3-1.2 1.5M65.7 212.6h.1M65.7 211.2h.1M65.8 211.1l.2 .2M65.8 211.1h.1"/>
<path d="M65.9 220v.9M65.9 212.3l-.2 .3M66.3 211.6l.2 .2M66.4 211.9l-.2 .2M66.4 211.9h.1M66.5 211.8h.1M66.8 210.2h.1M66.8 210.2l-1 .9M67.2 219.5l-1 .1M67.5 211l-1 .8M67.5 211.3l-1 .7-.3-.2M67.6 219.9v1"/>
<path d="M70.5 208.4l-2.4 1M70.5 208.4h.1M70.8 209.4l-2.3 1M70.8 209.6l-2.2 1M72 216.5l.7 .9M72.1 214.2l-.3 1.8M72.1 214.2h.1M72.5 216.3l.4 .6M72.5 219.5l-.2 .9 .2 1M72.5 214.4l-.2 1.4M73 213.3a2.55 2.55 0 0 1 2.5 0M73.2 208.9l-1.2 .1"/>
<path d="M73.2 207.9l-1.2 .1M73.2 217.7l.5 .2M73.2 207.9v.3M73.2 208.5v.4M73.3 218.7l.6-.3 1.3 .3M73.4 217.2l.3 .1M73.4 207.9v.3M73.4 208.7v.3l-1.3 .3M73.5 208.8l-.3 .1M73.7 216.9v.6M73.7 215.9v.5M73.7 217.7v.2"/>
<path d="M73.7 217.9h.2M73.7 208.8h.5M73.9 207.9h-.7M74.1 217.9h.3M74.6 207.9h.7M74.6 217.9h.2M74.7 208.8h-.3M74.8 216.9v.6M74.8 215.9v.5M74.8 217.8v.1M75 208.8l.3 .1M75.1 217.2l-.3 .1"/>
<path d="M75.1 207.9v.3M75.1 208.7v.3l1.3 .3M75.2 213.7l-1.3-.3-.6 .3M75.3 207.9v.3M75.3 208.6v.3M75.3 208.9l1.2 .1M75.3 207.9l1.3 .1M75.3 217.7l-.5 .2M75.5 213.3h.1M76 219.4l.2 1-.2 1M76 216.4l-.5 .6M76 214.5l.2 1.4"/>
<path d="M76 216.3v.1M76.4 214.2l.3 1.7M76.5 216.5l-.7 .8M76.6 208h.1M77.6 209.6l2.3 .9M77.7 209.4l2.3 1M78 208.4l2.5 1.1M78.9 218.7h.1M79 218.7v1.8M79.1 218.6h.1M79.1 218.5h.1M79.1 218.6h.7"/>
<path d="M80.5 209.5h.1M80.6 218.6h.8M80.9 220v.9M81 211.2l1 .8 .2-.2M81.1 211.1l.9 .7 .2-.2M81.4 219.5l-.1 .1M81.4 219.5h.7M81.4 218.5h.1M81.5 218.7h.1M81.5 218.7v1.8M81.6 218.7h.1M81.7 210.2l1 .9-.2 .2"/>
<path d="M81.7 219.1v.2M81.7 219.7v.2M81.9 219.1v.2M81.9 219.7v.2M82 211.8h.1M82.1 211.9l.2 .2M82.1 211.9h.1M82.1 219.5h.1M82.6 212.4l.2 .2M82.6 219.9v1M82.8 211.1h.1M82.8 212.6h.1"/>
<path d="M82.8 211.2h.1M82.8 211.2l-.2 .3M82.8 211.2l.3 .2M82.9 212.6h.1M82.9 212.6l1.1 1.6M82.9 212.4l-.3 .3 .9 1.1M83.1 212.4l-.2 .2M83.3 211.7l-.1 .4M83.5 213.8h.1M83.6 212l.9 1.1M83.6 212h.1M83.6 212l-.3 .2"/>
<path d="M84.3 215l1 2.6M84.5 213.1h.1M84.9 215.9l.9 3.6M85.3 217.6h.1M85.4 214.5l1.1 2.8M85.5 219v2.8M86.5 217.3h.1M86.7 218.9v3.1M96.8 214.5h.1M96.9 219v2.2h2.1M99.1 214.6h-2.2v2.2M101 213h1.4"/>
<path d="M101 214.4h1.5M101.2 214.6h4.2M103 207.2l-.3 .2 .4 .2M103.4 207l.4-.2v.4M103.8 207.6v.5l-.3-.2M104 213h1.5M104 214.4h1.5M107.5 214.6h2.1v2.2M109.6 219.1v2.1h-2.2M109.7 214.5h.1M111.3 218.5v.8h1.8M111.3 213.2v3.5"/>
<path d="M111.5 209.8h.1M111.5 209.9l.1 .1M111.6 219.1l-.1 .1M111.7 210.1l.1 .1M111.8 218.9l-.1 .1M112 215.6h.6M112 213.5h.6M112 209.8h.1M112 210v.7M112 211.4v.6h.6M112 219.2h.1M112 218.4v.7"/>
<path d="M112 209.6h.6M112 212.5v4.1M112 217.7v1.8M112 209.6h.1M112 211.2h.6M112 211.1h.6M112 219.5h.6M112 217.9h.6M112.2 209.8h-.9v1.7M112.6 217.1h-.6v.6M112.6 209.5h-.6v1.9M112.6 219.5h-.6"/>
<path d="M113 214.9l.4 1.2M113 214.2h.4M113 214.9v.3M113 214.2v.7M113 214.2h.1M113 214v.1M113.2 213.4l-.2 1.5M113.2 219.5h.6M113.2 209.6h.6M113.2 211.2h.6M113.2 211.1h.6M113.2 209.5h.6v1.9"/>
<path d="M113.2 217.9h.6M113.3 213l-.1 .4M113.3 213.5h.7v.7M113.3 217.1h.7v.6M113.4 212.9l-.1 .1M113.4 216.2l1.4 1.2M113.5 213.7l-.5 .1M113.8 212.5v4.1M113.8 217.7v1.8h-.6M113.8 212.4l-.4 .6M113.8 209.6h.1M113.8 219.5h.1"/>
<path d="M114 214.9v.7h-.7M114 209.8h.1M114 210v.7M114 211.4v.6h-.7M114 219.2h.1M114 218.4v.7M114 209.8h3.4M114 214.2l.8 .2M114.2 213.1h.1M114.2 213h.1M114.3 213.1h.4M114.3 213h.1"/>
<path d="M114.3 213.1h.1M114.5 213.1v.6h-.5M114.5 211.8v.6M114.5 211.8l-.4 .3M114.5 211.8h.1M114.5 214.6h.1M114.5 214.5h.1M114.5 217.3l.3 .1M114.5 214.7h.1M114.6 214.5h.1M114.8 217.4l.9 .3M114.8 211.7l-.2 .1"/>
<path d="M114.8 211.7h.1M114.8 219.3h3.5M114.9 214.2l-.3 .3M115 214.5l.7 .2M115.1 213v.8M115.1 211.5v.7M115.1 209.8v.1M115.1 210.1v.6M115.1 211.4v.6h.7M115.1 219.2h.1M115.1 218.4v.7M115.2 213h.4"/>
<path d="M115.2 211.5l-.3 .1M115.3 211.5l-.5 .2M115.3 215.3l.1 .1M115.3 215h.1M115.3 214v1M115.3 213.9l.6 .1M115.3 215.3h.1M115.4 215.3v.4M115.4 214.8l-.1 .3M115.4 215.3h.1M115.4 216.6h.1M115.4 215.4h.1"/>
<path d="M115.4 215.2h.1M115.4 216.2v.4M115.4 216.5h.1M115.5 213.7h.1M115.5 216.6h.1M115.5 213.7l.5-.2h-.5l-.1 .3h.3M115.5 216.7h.1M115.5 215h.1M115.5 214.9h.1M115.5 213.5h.1M115.5 213.2h.1M115.5 214.8h.1"/>
<path d="M115.5 216.5h.1M115.5 213.3h.2M115.5 215.1h.1M115.5 213.6h.1M115.5 214.5v.4M115.5 213.1h.2M115.6 213.7h.1M115.6 213.3h.1M115.6 213h.1M115.6 215.4h.1M115.6 215h.1M115.6 213.6h.1"/>
<path d="M115.6 213.7l-.1 .4M115.6 213.1h.1M115.6 212.9h.1M115.6 213.3l-.3 .4M115.6 214.9h.1M115.6 213.2h.1M115.6 214.8v.2M115.6 215.3v.1M115.6 213.5v.2M115.6 215.4l.8 .1M115.7 212.9h.1M115.7 213.7h.1"/>
<path d="M115.7 213.5h.1M115.7 212.8h-.3v.3M115.7 212.9v.4M115.7 212.9l-.2 .4M115.7 211.4l-.4 .1M115.7 213.6h.1M115.7 213.6l.2 .5M115.7 211.4l-.3 .1M115.8 217.1h-.7v.6M115.9 213.7h.1M115.9 213.5l-.1 .2M115.9 213.6l.7 .1"/>
<path d="M115.9 213.6l-.2 .1M115.9 213.5h.1M115.9 215.4h.1M115.9 213.7l.7 .4M115.9 213.6h.1M116 214.8l-.1 .6M116 214.8h.1M116 213.6h.1M116.1 212.8h.3v.3M116.1 215.2l.1 .1M116.1 214.6l.2 .5M116.2 213.2h.1"/>
<path d="M116.2 211.3l-.5 .1M116.2 211.3l.4 .1M116.2 214.9l-.1 .1M116.2 211.3l-.3 .1M116.2 213.3h.1M116.2 213.1h.1M116.2 213h.1M116.2 215.4h.1M116.2 216.2h.1M116.2 212.9h.1M116.2 214.7l.5 .1M116.2 215.3h.1"/>
<path d="M116.2 213.3l.7 .4M116.2 216h.1M116.2 216.1h.1M116.2 215.4v.2M116.2 215.9v.2M116.3 215.4h.1M116.3 215.5h.1M116.3 216.2h.1M116.3 215.1h.1M116.3 216.1h.1M116.3 214.9l.2 .1M116.3 212.9v.4"/>
<path d="M116.3 212.9l-.1 .4M116.4 215.4h.1M116.4 216.1h.1M116.4 216.4h.1M116.4 213.5v.3h-.3M116.4 216.5h.1M116.5 215.1l-.1 .2M116.5 216.5h.1M116.5 216.4h.1M116.5 216.3h.1M116.5 214.8h.1M116.5 214.8l.2 .2"/>
<path d="M116.5 214h.5M116.5 217.1h.6v.6M116.6 211.4l1.1 .4M116.6 215.4l-.2 .1M116.6 215.4l.1 .7M116.6 211.4h.2M116.7 212.9l-.4 .1M116.7 215h.1M116.7 216.9v.8M116.7 217.7h-.9M116.8 216.1l-.3 .3M117 217.6l-.3 .1"/>
<path d="M117 214.1v1M117 214.1h.1M117.1 218.4v.6M117.1 209.8h.1M117.1 210v.7M117.1 211.4v.6h-.6M117.1 219.2h.1M117.3 214.5l.5 .5M117.3 213.8l-.3 .2M117.4 212.6h.1M117.4 212.7h.1M117.4 211.6l1 .7"/>
<path d="M117.5 212.7h.1M117.5 215.6l.1 .7M117.5 212.6l-.4 .1M117.5 214.1l.6 .4M117.6 212.6h.1M117.6 215.3l.1 .1M117.6 214.2l-.1 .8M117.6 217.4l-.4 .2M117.7 215.3h.1M117.7 214.8l-.1 .3M117.7 215.3l-.4 .4M117.7 215.4h.1"/>
<path d="M117.7 215.2h.1M117.7 217.3l-2 .4M117.8 215.4h.1M117.8 215.3h.1M117.8 215h.1M117.8 214.9h.1M117.8 214.8l.2 .2M117.8 216.4l.2 .3M117.9 215.1h.1M117.9 215h.1M117.9 214.9h.1M118 215h.1"/>
<path d="M118 215.3l-.1 .1M118 214.5h.1M118 217v.1M118 217.1l-.2 .1M118.1 214.5h.1M118.1 214.6h.1M118.2 214.5h.1M118.2 213.4l-.6 .2M118.4 219.2h.1M118.4 218.4v.7M118.4 209.8h.1M118.4 214.9v.7h.5"/>
<path d="M118.4 210v.7M118.4 211.4v.6h.5M118.4 209.6h.6M118.4 213.9l-.5 .1M118.4 209.6v1.8zM118.4 211.2h.6M118.4 211.1h.6M118.4 209.5h.6M118.4 219.5h.6M118.4 217.9h.6M118.4 209.6h.1M118.4 212.5v4.1"/>
<path d="M118.4 217.7v1.8M118.5 216.7l-.5 .4M118.7 213.4h.4M118.9 213.9h.4M118.9 212.9v.1M118.9 216.1v.1M118.9 213h.1M118.9 213l.2 .4M119 217.1h-.6v.6M119 213.5h-.6v.7M119 219.5h-.6M119.1 215.7l-.2 .4"/>
<path d="M119.1 213.4v2.3M119.1 215.7l-.2 .5M119.1 213.4h.1M119.2 213.5v.1M119.2 213.6h.1M119.2 213.8l.1 .1M119.2 209.8h1.7M119.3 213.9v.5M119.3 215.1l-.2 .6M119.6 219.5h.7M119.6 209.6h.7M119.7 215.6h.6"/>
<path d="M119.7 211.2h.6M119.7 211.1h.6M119.7 209.5h.6v1.9M119.7 217.9h.6M119.7 217.1h.6v.6M119.7 213.5h.6M120.3 212.5v4.1M120.3 217.7v1.8h-.6M120.3 209.6h.1M120.3 219.5h.1M120.3 219.2h.1M120.3 218.4v.7"/>
<path d="M120.3 209.8h.1M120.3 210v.7M120.3 211.4v.6h-.6M120.5 218.9h.1M120.6 219h.1M120.6 210.1l-.1 .1M120.7 219.1h.1M120.8 209.9l-.1 .1M120.8 219.2h.1M120.8 209.8h.1M120.9 209.8v.8M120.9 212.4v3.5"/>
<path d="M120.9 217.6v1.7h-.8M120.9 209.8h.1M166.9 218.7h.1M167 218.8v1.5M167 218.7h.1M167 218.8h.1M167 218.7v.1M167.8 218h.1M167.8 217.7v.1M168 217.8l-1 1M168 219.2l.1 .1M168 219.2v1.1"/>
<path d="M168.1 219.3l.1 1M168.6 218.4l-.8 .8v1.1M168.8 218.5l-.8 .7M168.8 217h.1M168.8 216.7v.1M168.9 218.6l-.8 .7M170.1 215.9l-1.1 1M170.4 216.9v.1M170.4 216.9h1M170.4 216.9l-.8 .8M170.4 217l-.7 .8M170.4 217h1"/>
<path d="M170.5 215.8l-.2 .1M170.5 215.7h.1M170.6 215.9h.3M171 217.5v.3h.7M171 217.7h.7M171.1 216.7l-.1 .7M171.2 215.9h.2M171.4 215.9h.1M171.4 215.9l-.1 .3M171.4 216.7h-1.1l-.8 .8M171.4 215.7v.1M172.4 217.7h.6"/>
<path d="M172.6 216.9h1.1M172.6 216.7h1.2l.7 .8M172.6 215.7v.1M172.7 215.9h.2M172.7 215.9l.1 .4M172.7 215.9h.1M172.9 216.7l.1 .4M173 217.1l.1 .2M173 217.6l.1 .2h-.7M173 217.1l.1 .1M173.1 215.9h.3M173.5 215.9h.1"/>
<path d="M173.5 215.9h.2M173.5 215.7v.1M173.6 217l.8 .7M173.6 217h-1.1M173.7 216.9l.7 .7M173.7 216.9l-.1 .1M173.9 215.9l1.1 .9M175.1 218.6l.9 .6M175.2 217h.1M175.2 216.7v.1M175.3 218.4l.7 .8M175.4 218.4l.8 .8v1.1"/>
<path d="M175.8 219.3v1M176 219.2v1.1M176.1 217.8l.9 1M176.2 218h.1M176.2 217.7v.1M177 218.7h.1M177 218.7v1.6M177 218.8h.1M177.2 218.7h.1M182.1 218.7h.1M182.2 218.7h.1M182.3 218.8h.1"/>
<path d="M182.3 218.7l-.1 1.5M183 218h.1M183 217.7v.1M183.2 217.8l-.9 1M183.3 219.2l.1 .1M183.3 219.2v1.1M183.4 219.3v1M183.8 218.4l-.7 .8v1.1M184 218.5l-.7 .7M184.1 217h.1M184.1 216.7v.1M184.1 218.6l-.7 .7"/>
<path d="M185.3 215.9l-1.1 1M185.6 215.9h.2M185.6 216.9l-.8 .8M185.6 216.9h1.1M185.6 216.9l.1 .1M185.7 217h1M185.7 217l-.8 .8M185.8 215.9h.1M185.8 215.7v.1M186 215.9h.2M186 215.9h.1M186.3 217.5v.3h.6"/>
<path d="M186.3 217.7h.6M186.3 217.1v.2M186.4 216.7l-.1 .4M186.4 215.9h.2M186.6 215.9l-.1 .4M186.6 215.9h.1M186.6 215.7h.1M186.6 215.8v.1M186.6 216.7h-1.1l-.8 .8M187.6 217.7h.6M187.8 217h1.1M187.8 216.9h1.1"/>
<path d="M187.8 216.7h1.2l.8 .8M187.9 215.7h.1M187.9 215.8v.1M187.9 215.9h.2M187.9 215.9h.1M187.9 215.9l.1 .3M188.2 216.7v.4M188.2 217.6l.1 .2h-.7M188.2 217.1l.1 .3M188.2 217.1l.1 .1M188.4 215.9h.1M188.5 215.9h.1"/>
<path d="M188.7 215.9h.1M188.8 215.7h.1M188.8 215.8l.1 .1M188.8 217l.8 .8M188.9 217l.7 .7M188.9 216.9l.8 .7M188.9 216.9v.1M189.1 215.9l1.2 .9M190.4 218.6l.7 .7M190.4 218.5l.8 .8M190.5 217h.1M190.5 216.7v.1"/>
<path d="M190.5 218.4l.8 .8M190.6 218.4l.9 .8v1.1M191.1 219.3l.1 1M191.3 219.2v1.1M191.3 219.2l-.1 .1M191.3 217.8l1 1M191.5 218h.1M191.5 217.7v.1M192.3 218.8v1.4M192.3 218.8h.1M192.3 218.7v.1M192.3 218.7h.1"/>
<path d="M192.5 218.7h.1M198.8 214.5h.1M198.9 219v2.2h2.1M201 214.6h-2.1v2.2M202.9 214.4h1.6M202.9 213h1.5M203.2 214.6h4.1M205 207.2l-.3 .2 .4 .2M205.4 207l.4-.2v.4M205.8 207.6v.5l-.3-.2M206 213h1.6M206 214.4h1.6"/>
<path d="M209.5 214.6h2.1v2.2M211.6 219.1v2.1h-2.1M211.7 214.5h.1M213.9 213.3h.1M213.9 210.5h.1M214 210.6v.9M214 212.4v.8M214.1 213.3h.1M214.1 210.5h.1M214.1 213.5h.1M214.1 210.4h.1M214.1 213.4h1.8"/>
<path d="M214.1 210.5h1.7M214.3 210.3h.3M214.3 210h.3M214.3 213.5h.4M214.3 213.8h.4M215 210.3h.3M215 210h.3M215 213.5h.3M215 213.8h.3M216.2 210.3h.3M216.2 210h.3M216.9 210.3h.3"/>
<path d="M216.9 210h.3M217.6 210.5h1.8M217.7 213.4h1.7M218.1 210.3h.3M218.1 210h.3M218.1 213.5h.4M218.1 213.8h.4M218.8 210.3h.4M218.8 210h.4M218.9 213.5h.3M218.9 213.8h.3M219.4 210.4h.1"/>
<path d="M219.4 213.3h.1M219.4 210.6h.1M219.4 213.5h.1M219.4 212.3v.9M219.4 210.6v.9M219.6 210.5h.1M219.6 213.3h.1M221.2 205.9h.1M221.2 210.9h.1M221.3 205.9v1.7M221.3 209.3v1.6M221.3 205.7h.1"/>
<path d="M221.3 210.9h.1M221.4 211.1h.1M221.4 205.9h.1M221.4 205.8h.8M221.4 211h.9M222.1 205.7h.4M222.1 205.4h.4M222.1 211.4h.4M222.1 211.2h.4M222.5 215.1h.1M222.5 215.1l1 .2M222.5 215.1l-.8 .3"/>
<path d="M222.5 215.1a1.82 1.82 0 0 0-1.3 2.8M222.7 215.1l1.1 .3 .5 .5M223 205.7h.4M223 205.4h.4M223 211.4h.4M223 211.2h.4M223.2 205.8h.9M223.2 211h.9M223.7 218.5l-.9 .2-.9-.2M224.1 211.1h.1M224.1 211h.1M224.1 205.9h.1"/>
<path d="M224.1 205.7h.1M224.2 209.3v1.6M224.2 205.9v1.7M224.2 215.9a1.81 1.81 0 0 1-.4 2.5 1.81 1.81 0 0 1-2.5-.4M224.3 205.9h.1M224.3 210.9l.1 .1M233.2 216.2h1.7M233.2 216.8h1.4M234.1 215.4v.2M234.1 215.9v.3M236.5 216.2h1.5M237.1 215.4v.3"/>
<path d="M237.1 216v.2M237.4 216.8h-1.4M237.8 216.6l-.2 .1M238.1 216.4l-.2 .1M313.9 218.4h1.3M316.6 218.4h1.3v.7M317.9 219.8v1.3M323.8 215.9v.3h.7M323.8 208.5v.3h.5M323.8 212.4l.3 .2M323.8 207.9v.3M323.8 212v.1"/>
<path d="M324.1 208.8h.1M324.1 207.9v.3M324.1 208.5v.3M324.5 215.4l-.7 .2M324.5 212.6h.7M324.6 215.4v.2M324.6 215.9v.3M324.7 208.9h.2M324.9 212.3v2.9M324.9 208.9h.3M324.9 212v.1M324.9 211.8h.3"/>
<path d="M324.9 212h.3M324.9 208.9v.7M324.9 217.8v5.2M324.9 210.4v.8M324.9 209h.3M325.4 216.2h1.2M325.4 215.4h1.2M325.5 208.9h.4M325.5 212.6h.4M325.5 211.8h.4M325.6 212h.3M325.6 209h.3"/>
<path d="M326 215.9h.6M326 215.4v.8M326 217v.9M327.1 215.9h.6v.3h-.6M327.1 215.4h2.5M327.7 215.4v.2M327.8 216.8h1M327.8 215.9h1M327.8 216.2h1M327.8 214.8l1 .1M327.8 214.7h1M327.8 216.1h1"/>
<path d="M327.8 208.9h1M327.8 206.9h1M329.9 216.8h1.1M329.9 214.8h1.1M329.9 216.1h1.1M329.9 208.9h1.1M329.9 214.7h1.1M329.9 206.9h1.1M331 212.2h.1M331 212.2l.1 .1M331 215.7l.1 .8 .8 .1M331 215.9h.1"/>
<path d="M331 217.5l.1 .2M331 219.1h.2M331 215.2h.1M331 216.7v.6M331 217.2h.1M331 217.8h.1M331 214.7h.1M331 219.2l.3 .7M331 214.2v.1M331 214.9v.3M331 215.6v.6M331 204.6h.1"/>
<path d="M331 214.5h.1M331 209.6l.1 .1M331.1 206.2l.1 .5M331.1 211.9l-.1 .1M331.1 207.2h.1M331.1 206.7h.4M331.1 215.3h.1M331.1 204.9h.1M331.1 206.8v1.3M331.1 206.7h.1M331.1 208.2h.1M331.1 208.1h.1"/>
<path d="M331.1 208h.1M331.1 206.8h.1M331.1 206.8v.2M331.1 214.8h.1M331.1 214.3h.1M331.1 211.8h.1M331.1 219.9h.1M331.1 205.8v1.3M331.1 207.3h.1M331.1 207.3h.2M331.1 205.1l.2 .3M331.1 219.9h.2"/>
<path d="M331.1 212.5h.1M331.1 205.1h.1M331.1 206.7h.8M331.1 207.7v.5M331.1 218.8v.7M331.1 219.5l.1 .1M331.1 214.9h.1M331.1 211.7h.1M331.1 219.8h.1M331.1 214.9h.2M331.1 214.2v.8M331.1 211.7h.2"/>
<path d="M331.1 219.8h.2M331.1 219.7h.7M331.1 217.2l.8 .1M331.1 217.2l-.1 .1M331.2 217.8h.1M331.2 210.9h.1M331.2 214h.1M331.2 217.1h.1M331.2 214.2l.7 .1M331.2 214.2l-.1 .1M331.2 209.9h.1M331.2 219.6h.7"/>
<path d="M331.2 217.3l-.1 .7M331.3 215.7l.1 .7M331.3 215.7h.1M331.3 215.8v.9M331.3 212.4v1h.3M331.3 210.5v1l.2-.6M331.3 205.9h.2M331.3 214.7h.1M331.3 209.1v.5M331.3 210.1v.4M331.3 217.1v2.8M331.3 217.9v.1"/>
<path d="M331.3 215.1h.1M331.3 214.5h.3M331.3 217.7h.1M331.3 205.8v.9M331.3 219.9h.1M331.3 207.5v.7M331.3 213.2l.3 .1M331.3 213.5h.1M331.3 218.9h.1M331.3 217.1h.1M331.3 215.6h.1M331.3 212.2h.1"/>
<path d="M331.3 215.5l.1 .1M331.3 204.6h.1M331.3 212h.1M331.3 215.2l.1 .1M331.3 215.2h.1M331.3 212.1v.6M331.3 214.2v1.5M331.3 213.9h.1M331.3 211.5l-.2 .3M331.3 214.3v.2M331.3 214.6v.1M331.3 204.2l-.3 .1"/>
<path d="M331.3 218.8l-.2 .2M331.3 219.7l.2 .2M331.3 209.2v.1M331.3 219.1v.2M331.3 209.5h.1M331.4 214.2h.1M331.4 215.6h.1M331.4 219.1h.1M331.4 212.1h.1M331.4 212h.1M331.4 219.1h.3M331.4 217.3v.7"/>
<path d="M331.4 204.8h.1M331.4 204.6h.1M331.4 219.5h.1M331.4 204.7v.1M331.4 217h.1M331.4 209.6h.1M331.5 215.7h.1M331.5 215.7h.3M331.5 211.9h.1M331.5 210h.3M331.5 209.9v.4M331.5 219.5h.1"/>
<path d="M331.5 204.9v.1M331.5 219l-.1 .5M331.5 213.5l.3 .6M331.5 219.2h.1M331.5 215.6h.1M331.5 217.1l.1 .9M331.5 214.1h.1M331.5 211.1h-.3M331.5 205.8h-.2M331.5 219.2h.3M331.5 215.4l.1 .1M331.5 215.9h-1.6"/>
<path d="M331.5 205h.1M331.5 205.2h-.4v.5M331.5 205.4h.3M331.5 218h.1M331.5 215.4h3.9M331.5 218v.5M331.5 213.8h.3M331.6 210.1l-.2 1M331.6 218.4v.6M331.6 207.3h.2M331.6 218h.1M331.6 215.5h.1"/>
<path d="M331.6 212h.1M331.6 211.4v.6M331.6 217h.1M331.6 211.7h.2M331.6 219.8h.2M331.6 210h.1M331.6 211.8h.1M331.6 205h.1M331.6 210.6h-.3M331.6 210.4l-.3 .1M331.7 211.8h.1M331.7 218.8h.4"/>
<path d="M331.7 204.2h.2M331.7 205h.1M331.7 219.2h.1M331.7 209.9h.1M331.8 211.4l-.3 .1M331.8 219.2h.1M331.8 209.8h.1M331.8 211.8h.3M331.8 207.3h.1M331.8 206.7h.1M331.8 206.6v.5M331.8 207.7v.5"/>
<path d="M331.8 214.9h.1M331.8 214.3h.1M331.8 212.3h.1M331.8 211.7h.1M331.8 214.9v1.3M331.8 218.9h.1M331.8 219.8h.1M331.8 217.6v1.3M331.8 205l.3 .1M331.8 214.9h-.2v1.5M331.9 207.2h.1M331.9 206.7h.1"/>
<path d="M331.9 219.1h.2M331.9 205.9h.3M331.9 211.1l.3 .1M331.9 204.3h-.8v1.3M331.9 219.9h.4M331.9 214.8h.1M331.9 214.3h.1M331.9 212.2h.1M331.9 211.8h.1M331.9 219.9h.1M331.9 210.9l.3 .1M331.9 211.4h.1"/>
<path d="M331.9 218.9v1.3M331.9 205.4h.1M331.9 218.9h.1M331.9 205.1v.5l.3 .1M331.9 206.2v.4l-.8-.1M331.9 211.8v.1M331.9 212.1v.8M331.9 214.7v.1M331.9 213.7v.8M332 208h.1M332 206.8h.1M332 206.7h.1"/>
<path d="M332 208.2h.1M332 208.1h.1M332 206.8v.4M332 207.6v.4M332 211.4h-.1M332 219.3h.2M332 219.5h.3M332 218.8h.1M332 215.9h.5M332.1 206.7h1.1M332.1 205.2h.4M332.1 215v.1"/>
<path d="M332.1 218.7h.2M332.1 205.5v.1M332.1 218.7h.1M332.1 205.5h.1M332.1 213.4l.4 .1M332.1 210h.3M332.1 213.3h.5M332.1 210.5h.4M332.1 213.8h.3M332.1 218.8h.1M332.1 211.3h.1M332.1 215.1h.1"/>
<path d="M332.1 215.1v1.2l-2.2-.1M332.1 217.6v1.2M332.2 211.2h.1M332.2 209.5h.1M332.2 219.5h.1M332.2 205.7h.1M332.2 209.7h.1M332.2 219.1h.1M332.2 219.9h.1M332.2 205.9h.1M332.2 205.9v.7M332.2 207.5v.7"/>
<path d="M332.2 209.2l.1 2.2M332.2 211h.1M332.2 215.7h.3M332.2 209.6h.1M332.3 218.8h.1M332.3 219.5h.1M332.3 212.5v4.1M332.3 217.7l-.1 1.8M332.3 205.1l.2 .3M332.3 209.7l.1 .1M332.3 218.8h.2M332.3 215.1v.5"/>
<path d="M332.3 216.3v1.2zM332.3 218.1v.7zM332.3 215.1v.6M332.3 215.1h.1M332.4 219.1h.1M332.4 219.9h.1M332.4 210.1h.1M332.4 213.8h.1M332.4 218.7h.1M332.4 211.2h.2M332.4 205.9h.2M332.4 205.7h.2"/>
<path d="M332.4 214.1h-.3M332.4 215l-.1 .1M332.5 210.1h.1M332.5 219.5l.9 .1M332.5 213.7v.1M332.5 218.9h.1M332.5 219.8l-.1 .1M332.5 205.2h.1M332.5 213.5h.1M332.5 210.2h.1M332.5 215.7v1M332.5 217.8v2.5"/>
<path d="M332.5 217h.2M332.5 219.3h.2M332.5 210.5l-.2 1.2M332.5 212.4v1M332.5 213.5v.1M332.5 210.5h.1M332.5 213.6h.1M332.5 210.2v.2M332.6 215.7h.1M332.6 218.7h.1M332.6 219.7h.1M332.6 214.4h.1"/>
<path d="M332.6 206.2v.5M332.6 205.2v.5M332.6 214.2h.1M332.6 214.4l-.5 .1M332.6 219.2h.1M332.6 216.7h.1M332.6 214.4v.7M332.6 205.6v.1M332.6 211.2v.1M332.6 211.2h.1M332.6 211h.1M332.6 205.9h.1"/>
<path d="M332.6 205.7h.3M332.6 207.5v.7M332.6 209.4v2M332.6 209.8l.2 .2M332.6 205.9h.3M332.6 210.3l-.5 .1M332.6 215.7l.1 .1M332.6 209.6h.1M332.6 219.5h.1M332.6 214.2h.8l.1 .8M332.6 212.5v4.1h.8M332.6 217.3v2.3"/>
<path d="M332.6 204.3h.8l.1 .7M332.6 214.9v.1M332.6 206.7h.1M332.7 218.7h.1M332.7 215.9h.1M332.7 218.5h.1M332.7 215.9v.9M332.7 217.7v2.4M332.7 216.6h.1M332.7 219.2h.1M332.7 219.1l.3 .1M332.7 219.2h.2"/>
<path d="M332.7 216.9h.2M332.7 213.5h.1M332.7 210.5h.1M332.7 210.3l.5 .1M332.8 213.9h.1M332.8 213.9l-.2 .1M332.8 210h.1M332.8 216.7h.1M332.8 213.7h.1M332.8 213.5v.1M332.8 210.5l.4 .1M332.8 210.1v.3"/>
<path d="M332.8 216.7h.2M332.8 213.5h.1M332.8 210.5v1M332.8 212.4v1M332.9 210.9l-.5 .1M332.9 211.1h-.3M332.9 214.4l.4 .1M333 217h.3M333.1 214.2h.1M333.1 214.3v.8M333.1 215.9v.8M333.1 218.6v.9"/>
<path d="M333.2 219.5h-.6M333.2 217h.1M333.2 215.3h.1M333.2 214.5h.1M333.2 214.9h.1M333.2 216.4h.1M333.2 212.6h.1M333.2 211.5h.1M333.2 211.3v.1M333.2 213.7h.1M333.2 211.8h.1M333.2 214.2h.1"/>
<path d="M333.2 211.3h.1M333.2 212.7h.1M333.2 214h.1M333.2 213.1h.1M333.2 213h.1M333.2 216.5h.1M333.2 216.3v.1M333.2 216.2h.1M333.2 216.1h.1M333.2 216.7h.1M333.2 214.7h.1M333.2 214.4v.1"/>
<path d="M333.2 212.8l.1 .5M333.2 211.3v2.7M333.2 214.1l.1 1.3M333.2 215.6v2.2M333.2 217.8l.3 .3M333.2 217.8h.1M333.2 215h.1M333.2 216.8h.2M333.2 219.2h.2M333.2 215.1h.1M333.2 210.9h.3M333.2 213.3h-.5"/>
<path d="M333.2 213.4l-.4 .1M333.2 205.8l.3 .1M333.2 206h.3M333.3 216.2h1.1M333.3 213.2h.1M333.3 213.6l.2 .1M333.3 213.6h.1M333.3 212.9v.1M333.3 213h.1M333.3 215.4h.1M333.3 213.7h.1M333.3 213.5h.1"/>
<path d="M333.3 213.3h.1M333.3 213.1h.1M333.3 212.9h.1M333.3 213.5l-.1 .3M333.3 213.3l.3 .1M333.3 219.3h-.3M333.3 217v.8M333.3 218.6v1.7M333.4 215.3h.1M333.4 213.1h.1M333.4 216.5h.1M333.4 215h.1"/>
<path d="M333.4 217.3l.1 .7M333.4 216.8v.1M333.4 219.2h.1M333.4 216.8h.1M333.4 216.9h.1M333.4 219.3h.1M333.4 213.7h.1M333.4 216.4h.1M333.4 214.5h.1M333.4 214.9h.1M333.4 213h-.2M333.4 213h.1"/>
<path d="M333.4 212.6h.1M333.4 215.6l.1 .2M333.4 213.6l.1 .1M333.4 209.7v.4M333.4 210.7l.2 .5M333.5 216.1h.1M333.5 205.8l-.1 .8h-.8v-.7M333.5 215.8v.7M333.5 216.5l-.1 .1M333.5 218.8v.7M333.5 217.2v.1M333.5 219.5l-.1 .1"/>
<path d="M333.5 217.2l-.9 .1M333.5 219.2h.1M333.5 219.3h.1M333.5 215.8h.1M333.5 216h.1M333.5 214.9h.1M333.5 213.7h.1M333.5 217h.1M333.5 216.9h.1M333.5 215.4l.1 .1M333.5 216.5h.1M333.5 215.4h.1"/>
<path d="M333.5 214.5h.1M333.5 211h-.3M333.5 218.9h.2M333.5 213.7v.1M333.5 209.7v.4M333.5 210.5v.5M333.5 214.9v.3M333.5 215.6v.3M333.5 215l-.2 .1M333.5 219.6l-.8 .1M333.5 207.1h.1M333.5 206h.1"/>
<path d="M333.5 206v.3M333.5 206.7v.4M333.5 211l-.3 .3M333.5 217v1M333.5 218.6v1.4M333.6 216.5h.1M333.6 214.5h.1M333.6 216.3l-.1 .1M333.6 214.1v.4M333.6 214.9h.1M333.6 214.9l-.2 .1M333.6 213.1h.1"/>
<path d="M333.6 216.2h.1M333.6 212.8h.1M333.7 213h.1M333.7 215.7v.5M333.7 213.7v.5M333.7 210.6h.4M333.7 210.5l.4 .1M333.7 214.6v-.6v.7M333.9 218.5l.3 .3M333.9 218.9h.1M334 218.9h.1M334.1 219h.1"/>
<path d="M334.1 210.6h.1M334.1 213.3h.1M334.1 212.4v.8h-.4M334.1 210.6v.9M334.1 219v.7M334.1 213.3l-.4 .1M334.2 214.6v1.5M334.2 217.7v1.5l-.5 .1M334.2 211l-.3 .1M334.2 210.2l-.3 .4M334.4 214.9v.3M334.4 215.6v.3"/>
<path d="M337.4 215.4h2M339.3 219.8h.3M339.6 215.5l.2 .1M339.9 219.8h.2M340 215.8l.1 .1M62 223.5h.1M62 223.5l1.1 2.8M62.9 221.4l.9 3.6M63 223.3l1 2.6M64 227.7l.9 1.2 .2-.2M64 227.7h.1M64.8 227.1l.8 1.1"/>
<path d="M64.8 226.7l1.1 1.4-.3 .3M65 229h.1M65 229l.2 .2M65.3 228.7l-.3 .3M65.6 228.2h.1M65.6 228.2l-.2 .2M65.7 229.7h.1M65.7 228.3h.1M65.7 228.3l.2 .2M65.8 229.7h.1M65.8 229.7l1 .9M65.9 229.4l-.2 .3-.3-.3"/>
<path d="M66 229.5l-.2 .2M66.2 228.7l.2 .2M66.2 229.1l.3-.3 1 .8M66.3 221.3h.9M66.4 228.9h.1M66.5 229h.1M66.5 229l.9 .8M66.5 229l-.2 .2M68 231.4l2.5 1.1M68.5 230.5l2.3 1M68.6 230.3l2.3 1M71.8 224.9l.2 1.8"/>
<path d="M71.9 232.8l1.3 .2M72 231.8l1.2 .2M72.1 231.6l1.3 .2v.4M72.3 225l.2 1.4M72.7 223.5l-.7 .8M73 227.6a2.47 2.47 0 0 0 2.5 0M73 223.9l-.5 .6M73.2 233h.2M73.2 232h.3M73.2 232v.3M73.2 232.7v.3M73.3 227.1l.6 .3 1.3-.2"/>
<path d="M73.4 233h.5M73.4 232.6v.4M73.7 223.5l-.3 .1M73.7 223l-.5 .2M73.7 223.3v.6M73.7 223h.2M73.7 223v.1M73.7 224.5v.4M73.8 232h.4M74.1 222.9h.3M74.6 233h.5M74.6 223h.2"/>
<path d="M74.8 223.4v.6M74.8 223v.1M74.8 224.5v.4M74.8 232h-.4M74.8 223.5l.3 .1M74.8 223l.5 .1M75.1 232.6v.4M75.2 222.1l-.7 .3-1.2-.2M75.3 233h-.2M75.3 232h-.3M75.3 232v.3M75.3 232.7v.3"/>
<path d="M75.6 223.9l.4 .7M75.8 223.5l.6 .8M76.2 225l-.2 1.4M76.4 231.6l-1.3 .2v.4M76.4 231.8l-1.1 .2M76.6 232.8l-1.3 .2M76.7 224.9l-.3 1.8M78 232.5h.1M78.6 221v.3M78.6 221.6v.2M78.9 221v.3M78.9 221.6v.2"/>
<path d="M78.9 224.2h.1M79 222.4v1.8M79 224.2h.1M79.1 224.4h.1M79.1 224.3h.8M79.9 230.3l-2.2 1M80 230.5l-2.3 1M80.5 231.4l-2.5 1.1M80.7 224.3h.7M81.3 221.3h.9M81.4 224.2h.1M81.4 224.4h.1"/>
<path d="M81.5 222.3v1.9M81.6 224.2h.1M81.7 230.6h.1M81.7 222.9v.2M81.7 223.4v.3M81.9 222.9v.2M81.9 223.4v.3M82 229h.1M82 229l-1 .8M82 229l.2 .3M82.1 229h.1M82.2 229.1l-.2-.3-1 .8"/>
<path d="M82.3 228.8l-.2 .1M82.5 229.5l.2 .2-1 .9M82.6 229.4l.2 .3M82.8 229.7h.1M82.8 228.3l-.3 .2M82.8 228.3h.1M82.8 228.2h.1M83.1 229.4l-.3 .3M83.2 228.7l.3 .3-.2 .2M83.3 228.6l.3 .3M83.5 227.1l-.9 1 .3 .3M83.5 229h.1"/>
<path d="M83.6 228.9h.1M84 226.7l-1.1 1.5 .2 .2M84.3 225.8h.1M84.5 227.7l-.9 1.2M85.3 223.3l-1 2.5M85.5 221.8h.1M85.8 221.4l-.9 3.6M86.4 223.5l-1.1 2.9M96.8 221.4h.1M97.9 222.8h.5M97.9 221.4h.4M98.9 221.4h.5"/>
<path d="M98.9 222.8h.5M101.1 221.2h4.2M102.5 222.8h.5M102.5 221.4h.4M103.5 221.4h.5M103.5 222.8h.5M107.1 222.8h.5M107.1 221.4h.5M108.1 221.4h.5M108.2 222.8h.4M109.7 221.4h.1M123.4 237.6l-.3-.1a3.2 3.2 0 0 0-3.2 1.8"/>
<path d="M123.5 225v.3M123.5 225.6v.2M123.5 232v.3M123.5 232.6v.2M123.7 225v.3M123.7 225.6v.2M123.7 232v.3M123.7 232.6v.2M123.8 228.2h.1M123.8 235.2h.1M123.8 229.6h.1M123.8 222.6h.1"/>
<path d="M123.9 222.7v1.8M123.9 226.4v1.8M123.9 229.7v1.8M123.9 233.4v1.8M123.9 228.2h.1M123.9 229.4v.1M123.9 235.2h.1M123.9 228.4h.1M123.9 222.6h.1M123.9 235.4h.1M123.9 229.6h.1M123.9 222.5h.1"/>
<path d="M124 222.5h.7M124 228.3h.7M124 229.6h.7M124 235.3h.7M125.2 238.7l.7 1.8M125.5 222.5h.8M125.5 229.6h.8M125.6 228.3h.7M125.6 235.3h.7M126.3 228.4h.1M126.3 228.3h.1M126.3 235.4h.1"/>
<path d="M126.3 235.2h.1M126.3 222.5h.1M126.3 229.4v.1M126.4 222.6h.1M126.4 229.6h.1M126.4 226.4v1.8M126.4 222.7v1.8M126.4 233.3v1.9M126.4 229.7v1.8M126.5 235.2h.1M126.5 228.2h.1M126.5 229.6h.1"/>
<path d="M126.5 222.6h.1M126.5 223.1v.3M126.5 223.6v.3M126.5 226.9v.3M126.5 227.5v.2M126.5 230.1v.2M126.5 230.7v.2M126.5 233.9v.2M126.5 234.4v.3M126.7 223.1v.3M126.7 223.6v.3M126.7 226.9v.3"/>
<path d="M126.7 227.5v.2M126.7 230.1v.2M126.7 230.7v.2M126.7 233.9v.2M126.7 234.4v.3M146.3 238.3l-.3 .7 .3 .4M146.3 237.9h-2.2v1.7M147 238.2h.1M147 238.3l.3 .5-.3 .6M147 239.4h.1M148.6 237.9h4.5M151.3 238.3l-.3 .7 .4 .4"/>
<path d="M152.1 238.2h.1M152.1 238.3l.3 .5-.3 .6M152.1 239.4h.1M155.4 237.9h4.4M156.4 238.3l-.3 .7 .4 .4M157.1 238.2h.1M157.2 238.3l.3 .5-.3 .6M157.2 239.4h.1M161.5 238.3l-.3 .7 .3 .4M162.1 237.9h2.2v1.6M162.2 238.2h.1M162.3 238.3l.3 .5-.3 .6"/>
<path d="M162.3 239.4h.1M166.8 223.1h.1M167 223.1l1 .8M167 221.6v1.4M167 223h.1M167.8 223.8h.1M167.8 223.9v.1M167.8 221.5v1.1l.8 .8M168 222.5l.8 .8M168 221.5v1M168.1 222.5h-.1M168.1 222.5l.8 .8"/>
<path d="M168.2 221.4v1.1M168.2 222.5l.7 .7M168.8 224.8h.1M168.8 225h.1M169 225l1.1 .9M169.5 224.3l.8 .8h1.1M169.7 224l.7 .7M170.4 224.9h1.1M170.4 225.9h.2M170.4 224.8l-.8-.6 .8 .7M170.4 224.7h1.1M170.4 224.8v.1"/>
<path d="M170.5 226.1h.1M170.5 225.9v.1M170.7 225.9h.1M170.7 225.9h.2M171 224.5v.2M171 224.1h.7M171 224.7l.1 .4M171 224.4v.3M171.1 225.9h.3M171.3 225.6l.1 .3M171.4 225.9v.1M171.4 225.9h.1"/>
<path d="M171.4 226.1h.1M171.7 223.9h-.7v.3M172.4 224.1h.6M172.4 223.9h.7l-.1 .4M172.6 224.8h1M172.6 224.9h1.1M172.6 226.1h.1M172.7 225.9v.1M172.7 225.9h.1M172.8 225.5l-.1 .4M173 224.7l-.1 .3M173.1 224.5l-.1 .2"/>
<path d="M173.1 224.6l-.1 .1M173.1 225.9h.2M173.3 225.9h.1M173.5 225.9h.1M173.5 226v.1M173.5 225.9h.2M173.6 224.7l.8-.7-.7 .9M173.6 224.8l.1 .1M174.6 224.3l-.8 .8h-1.2M175.1 224.9l-1.2 1M175.2 224.8h.1M175.2 225h.1"/>
<path d="M175.8 221.4v1.1l-.6 .7 .7-.7M175.9 221.4l.1 1.1M175.9 222.5h.1M176 222.5l-.7 .8M176.2 223.8h.1M176.2 221.5v1.1l-.8 .8M176.2 223.9v.1M177 223v.1M177 221.6v1.4M177 223l-.9 .9M177.1 223.1h.1M177.2 223.1h.1"/>
<path d="M182.1 223.1h.1M182.2 221.5l.1 1.6M182.3 223h.1M182.3 223.1h.1M182.3 223l1 .9M183 223.8h.1M183 223.9v.1M183 239l-.5 1.5M183.1 221.5v1.1l.8 .8M183.3 221.5v1M183.3 222.5l.8 .8M183.4 222.5l.7 .8"/>
<path d="M183.4 222.5h-.1M183.4 221.4v1.1M184.1 224.8h.1M184.1 225h.1M184.2 225l1.2 .9M184.3 237.9l1.2-.4 1.9 .5M184.7 224.3l.8 .8h1.2M184.9 224l.8 .7M185.6 225.9h.2M185.6 224.9h1.1M185.7 224.8l-.8-.6 .7 .7M185.7 224.8l-.1 .1"/>
<path d="M185.8 226v.1M185.8 225.9h.1M185.9 225.9h.2M186.3 224.5l.1 .5M186.3 224.1h.6M186.4 225.9h.2M186.5 225.5l.1 .4M186.6 225.9h.1M186.6 226v.1M186.7 224.7l-1 .1M186.9 223.9h-.6v.3M187.6 223.9h.7l-.1 .4"/>
<path d="M187.7 224.1h.5M187.8 224.8h1.1M187.9 226v.1M187.9 224.9h1M187.9 225.9h.1M187.9 225.9h.2M188 225.6l-.1 .3M188.2 224.7v.4M188.3 224.4l-.1 .3M188.3 224.6l-.1 .1M188.3 225.9h.3M188.5 239.2l.4 2"/>
<path d="M188.8 226.1h.1M188.9 224.8v.1M189 225.9l-.2 .1M189.6 224l-.7 .8M189.7 224.1l-.8 .8M189.8 224.3l-.8 .8h-1.1M190.3 224.9l-1.1 1M190.5 224.8h.1M190.5 225h.1M191.1 221.4l.1 1.1M191.2 222.5h.1M191.2 222.5l-.8 .7"/>
<path d="M191.3 221.4v1.1M191.3 222.5l-.8 .8M191.5 223.8h.1M191.5 221.5v1.1l-.8 .8M191.5 223.9v.1M192.3 223.1h.1M192.3 223h.1M192.3 223l-1 .9M192.3 221.5v1.6M192.4 223.1h.1M198.8 221.4h.1M199.9 221.4h.5"/>
<path d="M199.9 222.8h.5M200.9 221.4h.5M200.9 222.8h.5M203.2 221.2h4.1M204.5 221.4h.4M204.5 222.8h.5M205.5 221.4h.5M205.5 222.8h.5M209.1 222.8h.5M209.1 221.4h.4M210.1 221.4h.5M210.1 222.8h.5"/>
<path d="M211.7 221.4h.1M214.5 239.9h-.4l.2 .3M215 239.9h.4l-.2 .3M215.2 229.9h.1M215.2 235h.1M215.3 229.9v1.7M215.3 233.3v1.6M215.3 235h.1M215.3 235.1h.1M215.3 229.8h.1M215.3 229.7h.1M215.4 235h.1"/>
<path d="M215.4 229.8h.8M215.4 235h.9M216.1 229.7h.4M216.1 229.4h.4M216.1 235.4h.4M216.1 235.2h.4M217 229.7h.4M217 229.4h.4M217 235.4h.4M217 235.2h.4M217.2 229.8h.9M217.2 235h.9"/>
<path d="M218.1 235.1h.1M218.1 235h.1M218.1 229.7h.1M218.2 229.9h.1M218.2 233.3v1.6M218.2 229.9v1.7M218.3 229.9h.1M218.3 235h.1M220.1 229.9h.1M220.2 235h-.1M220.3 229.9v1.7M220.3 233.3v1.6"/>
<path d="M220.3 235h.1M220.3 229.8h.1M220.3 235.1h.1M220.3 229.7h.1M220.4 235h.1M220.4 229.8h.9M220.4 235h.9M221.1 235.4h.4M221.1 235.2h.4M221.1 229.7h.4M221.1 229.4h.4M221.9 229.7h.5"/>
<path d="M221.9 229.4h.5M222 235.4h.4M222 235.2h.4M222.2 229.8h.9M222.2 235h.9M223.1 235h.1M223.1 235.1h.1M223.1 229.7h.1M223.2 229.9h.1M223.2 233.3v1.6M223.2 229.9v1.7M223.3 235h.1"/>
<path d="M223.3 229.9h.1M223.5 239.9h-.4l.2 .3M223.9 239.9h.5l-.2 .3M228.8 227.6h.1M228.8 223.2l.1 .1M228.9 223.4l.1 .1M229 227.3h.1M229 227.3l-.1 .1M229 223.5l.1 .1M229.2 223.6h.1M229.2 223.6h2.6M230.2 223.4v1.3"/>
<path d="M230.2 226.1v1.3M231.7 227.2h-2.6M232.2 227.1h.1M232.2 227.3v.1M232.2 227.1h.4M233.2 223.4v1.3M233.2 225.9v1.2h-.2M234.3 227.2h2.5M234.4 223.6h2.4M238 222.2v2.2M238 226.5v2.1M240.8 223.2v1.5"/>
<path d="M240.8 226.2l.1 1.5M240.8 223.2h.1M240.9 227.9h.1M240.9 222.9v.1M242.8 222.9h.1M242.8 223.1l.1 1.6M242.8 227.8v.1M242.9 226.1v1.5M254.2 224.4v.6M254.2 225.8v.6M313.9 222.4h1.3M317.9 221.7v.7h-1.4"/>
<path d="M323.8 232h.1M323.8 228.7v.2M323.8 232.7v.3M324 232h.1M324.1 232.7v.3M324.1 232h-.3v.3M324.1 228.2l-.3 .2M324.2 232l-.1 .3M324.6 232h.6M324.8 232h.1M324.9 229h.3M324.9 231.8h.3"/>
<path d="M324.9 228.1l.3 .1h-.7M324.9 231.2v.8M324.9 225.6v2.9M324.9 229.7v.7M325.2 228.8l-.3 .1M325.5 232h.4M325.5 229h.4M325.6 231.8h.3M325.6 228.8h.3M325.9 228.1l-.4 .1M326 224.9h.6M326 223v.7"/>
<path d="M326 224.6v.8h.6M327.1 225.4h.6M327.2 224.9h.5M327.8 237.5h1M327.8 225.9h1M327.8 224.7h1M327.8 239.9h1M327.8 237.9h1M327.8 226.1h1M327.8 238.1h1M327.8 221.8h1M327.8 229h1"/>
<path d="M327.8 222.2h1M327.8 228.6h1M327.8 224.9h1M328.8 239.4l-1 .1M329 239.8h-1v.4M329.9 239.9h1.1M329.9 239.5h1.1M329.9 226.1h1.2M329.9 228.6h1.2M329.9 237.5h1.1M329.9 224.7h1.1M329.9 237.9h1.1"/>
<path d="M329.9 238.1h1.1M329.9 221.8h1.1M329.9 222.2h1.1M329.9 224.9h1.1M330 239.8h1.8M331 226.1h.1M331 227.7h.1M331 224.5v.8M331 230.1h.2M331 223.1h.2M331 224.6h.3M331 221.1h.3"/>
<path d="M331 230.6h.3M331 223.9h.1M331 224.6h.1M331 224.7h.1M331 225.8h.1M331 225h.1M331 223.7h.1M331 221.8h.1M331 223l.7 .1M331 225.6v.4M331 239.4h.1M331 227.7h1.1"/>
<path d="M331 227.3h.3M331 232.8h.1M331 232h.1M331 223.9l.3 .3M331.1 227.9h.1M331.1 227.4h.1M331.1 230.5h.1M331.1 230h.1M331.1 228.9h.1M331.1 229.2v.5h.4M331.1 229.6l.4 .1M331.1 234.7h.2"/>
<path d="M331.1 233.9h.2M331.1 239h.1M331.1 239.9h.1M331.1 239v.6M331.1 239.9v.3M331.1 238.8h.2M331.1 223.5l-.1 .2M331.1 228.1h.1M331.1 229.9h.1M331.1 229.9h1M331.1 228.1h.4M331.1 227.9v.1"/>
<path d="M331.1 228.2v.5M331.1 227.9h.2M331.1 239.4h.1M331.1 238.9h.1M331.1 227.3h.1M331.1 223h.1M331.1 224.1l-.1 .1M331.1 229.2v.9M331.1 230.5h.2M331.1 229.1l.2 .3M331.1 229.1h.1M331.1 234.8v.7"/>
<path d="M331.1 235.5l.1 .1M331.1 233.2h.1M331.1 221h.1M331.1 233.2h-.1M331.1 221.4v.2M331.1 221.9v.1M331.1 224.6v.6M331.1 225.7v.5M331.1 230.4v.2M331.1 231.6v.6M331.1 232.7v.5M331.1 237.8v.7"/>
<path d="M331.1 239.3v.7l.8 .1M331.1 233.2l.8 .1M331.1 230l.1 .1M331.1 222.7h.1M331.1 222.4v.1M331.1 238.8h.1M331.1 223h.2M331.2 228.2l-.1 .1M331.2 224.7h.1M331.2 233.3l-.1 .7M331.2 235.6h.7M331.2 227.8l-.1 .8"/>
<path d="M331.2 237.7l-.1 .1M331.2 237.7h.7M331.2 230.1h.7M331.3 224.1h.1M331.3 226.1h.1M331.3 223.7h.1M331.3 221.8h.1M331.3 225.8h.1M331.3 227.3h.1M331.3 226.7h.1M331.3 226.4h.1M331.3 234v1.3h.2"/>
<path d="M331.3 232v.3M331.3 228l.2 .3M331.3 224.3l.1 1.8M331.3 225.6v.6M331.3 227.7v.1M331.3 230v.2M331.3 231.6v1.2M331.3 235l.2 .1M331.3 234.9l.2 .1M331.3 235.2h.2M331.3 221.2l.3 .1M331.3 235.6l-.1 .1"/>
<path d="M331.3 226.9v.3M331.3 228.6h.1M331.3 226.6h.1M331.3 223.1l-.1 .1M331.3 229h-1.4M331.3 234.4l.4 .3M331.3 227.5l.4 .2M331.3 223.9h.1M331.3 221.3v-.3v1M331.3 221.6v.2M331.3 223.4l.1 1.1M331.3 230.7v.2"/>
<path d="M331.3 232.6v.2M331.3 232.8h.1M331.4 235.5h.1M331.4 226.2h.1M331.4 226.5l-.1 .1M331.4 228.8h.1M331.4 228.6h.1M331.4 223.9h.3M331.4 223.8h.1M331.4 224.8h.1M331.4 224.6h.2M331.4 226.1h.1"/>
<path d="M331.5 226.1h.1M331.5 226.1h.3M331.5 223.7h.2M331.5 225h.1M331.5 221h.1M331.5 228.9v.1M331.5 230.9h.2M331.5 222.9l.6 .1M331.5 232h.1M331.5 221.8h.1M331.5 225.8h.1M331.5 232.8h.1"/>
<path d="M331.5 226.9h.2M331.5 229h.1M331.5 229.5l-.2 .3h.2M331.5 225.9h-1.6M331.5 222.7h-.5M331.5 222.5h-.2M331.5 235.5h-.1M331.5 229.4h.3M331.5 223l-.2 .1M331.6 230.5h.5M331.6 227.3h.5M331.6 223.8h.1"/>
<path d="M331.6 224.8h.1M331.6 222.7h.3M331.6 229h.3M331.6 233.2h.3M331.6 223.7v.2M331.6 221.1h.3M331.6 230.6h.3M331.6 226.3h.1M331.6 226.3l-.1 .1M331.6 227.9h.5M331.6 223h.2M331.6 223.8v.7"/>
<path d="M331.6 225.4v.8M331.6 229h.1M331.6 226.2h.1M331.7 235.4h.1M331.7 229h.1M331.7 230.1l-.4 .2M331.7 233.9l-.4 .2M331.7 238.8h.3M331.8 223.4l-.1 .2M331.8 222.8h.3M331.8 221.8h.1M331.8 221h.1"/>
<path d="M331.8 232h.1M331.8 227.9h.1M331.8 227.3h.1M331.8 229.9h.1M331.8 225h.3M331.8 222.4h.1M331.8 224.6v.6M331.8 225.7v.5M331.8 231.6v.6M331.8 220.4h.1M331.8 221.1v.6M331.8 222.3v.4"/>
<path d="M331.8 230v.6M331.8 225.8h.3M331.8 239.4h.1M331.8 238.8h.1M331.8 239.4h.6M331.8 223h.1M331.9 227.9h.1M331.9 227.4h.1M331.9 230h.1M331.9 223.1h.2M331.9 223.7h.2M331.9 229.6h.3"/>
<path d="M331.9 223.9h.2M331.9 234.7h.2M331.9 230.9h.2M331.9 233.9h.2M331.9 226.9h.2M331.9 222.5h.1M331.9 220.3h.1M331.9 235.1l.3 .1M331.9 235h.3M331.9 222.6h.3M331.9 235.4h.3M331.9 235.2h.3"/>
<path d="M331.9 228.4h.3M331.9 228.2h.3M331.9 239.4h.1M331.9 238.9h.1M331.9 223h.1M331.9 227.4v.1M331.9 227.7v.9M331.9 230.3v.1M331.9 229.2l.2 .9M331.9 229.4h.1M331.9 222.8h.1M331.9 229l-.1 .5"/>
<path d="M331.9 235.4h.1M331.9 230.4h.1M331.9 230.5h.1M331.9 224.9v.4M331.9 225.6v.3M331.9 232.3v.3M331.9 233v.2M331.9 229l.2 .1M331.9 221.4v1.5M331.9 238.9v.1M331.9 239.2v.1M331.9 239.4v.6"/>
<path d="M332 222.9h.1M332 223.4h.1M332 223.4h-.1M332 239h.1M332 238.8l.1 .1M332 225.9h.5M332 235.4h-.1M332.1 223h.1M332.1 238.9l-.1 .2M332.1 239.3v.1M332.1 223.1h.2M332.1 229.5v.1"/>
<path d="M332.1 229.5h.1M332.1 232.8l-.3-.1v.5M332.1 229.7h.5M332.1 235.3h.1M332.1 221.4h.6M332.2 229.7h.1M332.2 235.2h.1M332.2 229.4h.1M332.2 230.1h.1M332.2 234.7h.1M332.2 230.9h.1M332.2 233.9h.1"/>
<path d="M332.2 222.8h.1M332.2 229.7h-.3M332.2 229.4h-.3M332.2 225.6v.3M332.2 228.2h.1M332.2 222.6h.1M332.2 222.4h.1M332.2 223.1h.1M332.2 227.7h.1M332.2 223.9h.1M332.2 226.9h.1M332.2 223.7h.1"/>
<path d="M332.2 222.9h.1M332.2 235h.1M332.2 229.6l.1 .3h-.4M332.2 221v.3M332.2 221.6v.2M332.2 224.9v.4M332.2 229.4v.1M332.2 230v.2M332.2 222.4l-.3 .1M332.2 235.4h.1M332.2 235.3h.1M332.2 232.6v1"/>
<path d="M332.2 228.4h.1M332.2 227.7v.1M332.2 228.1v.2M332.2 232v.3M332.2 234.5v.7M332.3 229.1l.2 .3M332.3 225l.2 .3M332.3 225.8h.2M332.3 232.8h.2M332.4 223.3l-.3 .1M332.4 235.7h.1M332.4 223h.1"/>
<path d="M332.4 230.5h.2M332.4 229.9h.2M332.4 227.3l.2 .2M332.4 229.4h.1M332.4 230.1h.1M332.4 234.7h.1M332.4 230.9h.1M332.4 233.9h.1M332.4 229.6h.1M332.4 223.9h.1M332.4 222.4h.1M332.4 222.6h.1"/>
<path d="M332.4 227.7h.1M332.4 228.2h.1M332.4 223.1h.1M332.4 226.9h.1M332.4 223.7h.1M332.4 229.7h.2M332.4 235h.2M332.4 222.7h.1M332.4 235.2h.2M332.5 234.5v.7M332.5 235.4h.1M332.5 235.3h.1"/>
<path d="M332.5 227.7v.1M332.5 228.1l.3 .2M332.5 229.4l.3 .1M332.5 235.2h.1M332.5 228.4h.1M332.5 229.6l.1 .3M332.5 225.6v.3M332.5 230v.2M332.5 232.3v.2M332.5 232.7v.9M332.5 229.6l.3 .1M332.5 222.5h.3"/>
<path d="M332.5 222.6l-.1 .1M332.5 223v1.1M332.5 225.1v1h-.3M332.5 235.5h.1M332.5 229.4h.1M332.5 224.7h.2M332.5 222.5h.4M332.5 222.9v.1M332.5 228.2l.1 .1M332.6 222.4h.1M332.6 220.4l-.1 2.4M332.6 228.1l-.5 .1"/>
<path d="M332.6 223.1h.1M332.6 226.1h.1M332.6 225.1h.1M332.6 222.6h.1M332.6 228.1v.6M332.6 229.2v.5M332.6 229.9h.1M332.6 227.9v.1M332.6 228.2v.5M332.6 235.4h.1M332.6 229.9v1.7M332.6 233.3v1.7"/>
<path d="M332.6 235.2h.1M332.6 235h.1M332.6 234.9h.3M332.6 229.9h.3M332.6 229.7h-.5M332.6 229.2v.5h.3M332.6 233.3h.8l.1 .7M332.6 235.6h.8M332.6 229.7h.1M332.6 237.7h.8M332.6 230.1h.8M332.7 239.8h.8"/>
<path d="M332.7 223.1h.1M332.7 226h.1M332.7 223.3h.1M332.7 225.9h.1M332.7 225.2h.1M332.7 225.1h.1M332.7 222.6h.1M332.7 221.7v2.4M332.7 225v.9M332.7 224.9h.2M332.8 228.2h-.3M332.9 235.1h-.3"/>
<path d="M332.9 239.5h.3v.5M332.9 222.9l-.3 .3M332.9 221.4h.2M333 222.6h-.5M333 225l-.2 .1M333 224.7h.3M333.1 222.1v.6h.4M333.1 221.4h.1M333.1 220.5v1.2M333.1 229.7h.4M333.1 229.6h.4M333.2 222.6h.2"/>
<path d="M333.2 234.9h.3M333.2 229.8l.3 .1M333.2 229.9l.3 .1M333.3 221.4h.2M333.3 221.5v1.8M333.3 224.1v.7M333.3 224.8h-.1M333.4 222.6h.1M333.4 225h.1M333.4 222.5h.1M333.4 237.7l.1 .1M333.4 227.8h.1"/>
<path d="M333.4 227.8l-1 .1M333.4 224.9h.1M333.4 225h-.2M333.5 228.2l-.4 .1M333.5 228.1l-.4 .1M333.5 227.7v.8M333.5 224.9v.4M333.5 225.6v.3M333.5 234.8v.7M333.5 235.5l-.1 .1M333.5 229.3v.9M333.5 237.8v.7"/>
<path d="M333.5 239.3v.7l-.9 .1M333.5 230l-.1 .1M333.5 224.8h.1M333.5 235h-.3M333.5 231.1h.1M333.5 230h.1M333.5 220.7v.6M333.5 230v.3M333.5 230.7v.4M333.5 222.5h-.5l.5 .1M333.5 224.8v.1M334.1 220.5v.7"/>
<path d="M339.3 224.9v.3M339.3 225.6v.3M339.3 221.6h.3M339.3 230.5h.3M339.9 221.6h.2M339.9 230.5h.2M340.1 224.9v.4M340.1 225.6v.3M341.2 225.3v.3M341.2 224.9v.2M341.2 225.8v.1M341.7 225.3v.3"/>
<path d="M341.7 224.9v.1M341.7 225.8v.1M342.2 224.2h.1M342.2 224.2l-.4 1.2 .3 1.2M342.6 225.7v.1M342.6 225.4v.1M342.6 225.2v.1M342.6 225.9h.1M342.6 224.9v.1M342.6 224.5l-.3 .9 .3 1M343.1 227.6l1.2 .3 1.2-.3M343.1 227.6h.1"/>
<path d="M343.1 223.2l1.2-.3 1.3 .4M343.4 223.7l.6-.3 1.3 .3M345.1 239.6h.7M345.3 227.1l-.7 .3-1.2-.2M345.6 223.3h.1M346.1 224.9h.1M346.1 224.4l.2 1-.2 1M346.1 225.8v.1M346.1 225.6v.1M346.1 225.1v.1M346.2 225.4h.1M346.5 226.7h.1"/>
<path d="M346.5 224.2l.3 1.2-.3 1.3M346.6 239.6h.8M347 224.9v.4M347 225.6v.3M347.5 225.3v.3M347.5 224.9v.1M347.5 225.8v.1M38.1 259.1h.1M38.1 259.1v.7M38.1 259.1l.2 .1M38.5 259.5l.2 .2M38.7 259.7l3.8 .1"/>
<path d="M38.7 259.7v.4M40.4 259.8h.1M43.6 259.7l4.9 .1M50.6 259.8l2.7-.1v.4M52.6 259.8v.3M54.3 257.7v2.1M54.7 259.7h.2M54.7 257.7v2.1M55 259.7h.1M57.4 259.7l-.1 .1M57.9 260h.2M57.9 259.7v.4"/>
<path d="M58.2 260h.2M58.4 259.7v.4M59 259.7h.1M59 259.8l.1 .2M62.4 259.7v.1M63 260h.2M63 259.7v.4M63.3 260h.2M118.5 254.5l.2 .1M118.7 256.3l-.2 .1M118.9 254.7l.3 .3M119.2 255h.1"/>
<path d="M119.2 255.8l-.3 .4M119.2 255.2v.4M119.6 241.4l1.1 1.8M128.6 258h.1M128.6 259.9v1M128.6 257.9h.1M128.7 259.8v.9M128.7 258.3h.1M128.7 258.1h.1M128.7 258.1l-.1 .9M128.7 258.1h2.1M128.8 259.8v.6"/>
<path d="M128.8 258.1h.1M128.8 258.3v.7M128.9 259.8v.6M128.9 258.4h.1M128.9 258.4v.6M128.9 258h1.9M128.9 258.2h.1M128.9 258.1h.1M129 258.2h1.8M129 258.1h.1M129.4 252.3h.1M129.4 252.7v.2"/>
<path d="M129.4 254.9h.1M129.4 255.3v.2M129.4 252.3v.2M129.4 254.9v.2M129.5 252.3h.5M129.5 254.3v.6h.5M129.5 255.5h.5M130 252.9h-.5v.6M130 258.1v.9M130 259.9v.8M130.5 252.3l.6 .2M130.5 254.9l.6 .2"/>
<path d="M130.7 257.9h-2.1v1v-.9M131 252.9v.6M131 254.3v.6M131.1 252.7l-.6 .2M131.1 255.3l-.6 .2M132.5 252.3h.1M132.5 252.7v.2M132.5 254.9h.1M132.5 255.3v.2M132.5 252.3v.2M132.5 254.9v.2M132.5 252.3h.5"/>
<path d="M132.5 254.3v.6h.5M132.5 255.5h.5M132.7 258.2h1.8M133 252.9h-.5v.6M133.2 257l.1 1M133.2 256.5l-1 .9v2M133.3 256.6l-.1 .2M133.3 258h.1M133.4 256.2l-.1 .2M133.5 252.3l.6 .2M133.5 254.9l.6 .2M133.6 258.1v.9"/>
<path d="M133.6 259.8v.9M133.8 258.7l1.5 .4M134 256.8h.1M134 256.8v1.3M134 252.9v.6M134 254.3v.6M134 258.1h.1M134.1 252.7l-.6 .2M134.1 255.3l-.6 .2M134.3 256.8h.1M134.3 257.4l.2 .6M134.5 258.2h.1"/>
<path d="M134.5 256.2h.1M134.5 258.1h.2M134.5 258.1h.1M134.5 257.3l.1 .1M134.5 257.3h.1M134.6 256.2h1.3M134.6 258.7h.1M134.6 258.7h1.3M134.6 258l-1.9 .1M134.6 257.6v.1M134.6 256.8v.3M134.6 258.3h.1"/>
<path d="M134.6 258.4h.1M134.6 256.7h.1M134.6 257.3h.1M134.6 257.8h.1M134.7 258.4v.7M134.7 259.8v.6M134.7 256.6l-.1 .1M134.7 258.4h.1M134.7 257.4h.1M134.7 258.2h.1M134.7 258.1h.1M134.7 258.1h-2"/>
<path d="M134.7 258.1v1M134.7 257.5h.1M134.8 258.3h.1M134.8 257.9l.1 .1M134.8 256.5h.1M134.8 258.2h.2M134.8 257.9h.1M134.8 258.3v.7M134.8 259.8v.8M134.8 257.9h-2h2.1l.1 1.1M134.9 255.3l-.8 .3M134.9 257.9h.1"/>
<path d="M134.9 258h.1M134.9 259.9v1M135 256.4h.1M135 257.5h.1M135.1 258h-.1M135.1 256.5h.1M135.1 257.3h.1M135.1 257.3h-.2M135.2 256.5h.1M135.2 257.9h.1M135.2 257.2h.1M135.2 257.2v.1"/>
<path d="M135.2 256.5l.1 .2M135.2 258.2h.1M135.2 256.3h-.5l-.4 .5M135.3 257.7l-.1 .2M135.3 256.7v.1M135.4 257.7h.1M135.4 258.1h.1M135.4 258.1h-.1M135.4 257.3l-.1 .1M135.5 258h.1M135.5 257.9h.1M135.5 257.7v.1"/>
<path d="M135.6 256.8l-.2 .5M135.7 255.4l1.1 1.2M135.9 256.2h.1M135.9 258.6h.1M136.4 256.7l.1 1.3M136.5 258h.1M136.9 257.3h.1M136.9 257.7v.2M136.9 259.9h.1M136.9 257.3v.2M136.9 257.4h.1M136.9 257.4l-.8 1.4"/>
<path d="M137 257.9v.6M137 259.2l-.1 .9M137 257.3h.4M137 259.9h.4M137 257.9h.4M137.2 254.4h-2l-1 1M138 258.5l-1.1 1.7M138 257.3l.6 .2M138 259.9l.6 .2M138.5 257.9v.6M138.5 259.2v.7M138.5 258.8l-1 1.5"/>
<path d="M138.6 257.7l-.6 .2M139.2 254.4h3.9M139.3 256.9l.1 .1M139.3 256.9l-.7 .8M139.3 256.9h1.6M139.6 257.2l-.5 .8M139.7 256.5l-.4 .4M141 255.2l-.8 .8M142 254.4l-.4 .4M142.6 256.9l2.2 .1M143.6 254.7l.2 .5M143.6 253.7v.4"/>
<path d="M143.6 253.6h.2M144.1 253.6h.1M144.1 241.3v1.7h2.3M144.2 253.6h.1M144.2 254.7l-.1 .5M144.2 255.1h.7M144.9 253.7h-.7v.4M145.1 254.4h3.9M145.5 257.3l.9 .8M145.6 253.7h.7v.4M145.6 255.1h.7M146 249.9l.5 .1"/>
<path d="M146 247.2v.2M146 247.4v.7M146 248.8v.8M146 247.4h.5M146 249.4h.5M146.3 254.7l.1 .5M146.3 253.6h.1M146.5 246.8h-.5v.3M146.5 259.4h.1M146.5 259.8h.1M146.5 259.1v.3M146.5 259.5v.2"/>
<path d="M146.5 259.9v.2M146.5 259.6h.1M146.6 258.8l.1 1.3M146.6 258.4l-.1 .3M146.7 253.6h.1M146.8 259.8h.2M146.8 258.4l.2 .3M146.8 259.6h.2M146.8 253.6h.1M146.8 254.7l-.1 .5M146.8 253.7v.4M147 259.1v.3"/>
<path d="M147 259.5v.2M147 259.9v.2M147.1 247.4h.4M147.1 249.4h.4M147.1 246.8h.4v.3M147.5 259.8h.1M147.5 259.6h.1M147.5 258.4h.1M147.5 259.4h.1M147.5 258.4v.3M147.5 259.1v.3M147.5 259.5v.2"/>
<path d="M147.5 259.9v.2M147.5 249.9l-.4 .1M147.5 247.2v.9M147.5 248.8v.8M147.6 243.2h.1M147.6 241.7v.4M147.6 242.7v.5M147.6 241.6h.2M147.6 243.2h.2M147.8 259.8h.1M147.8 259.6h.1M147.8 258.4l.1 .3"/>
<path d="M147.9 259.1v.3M147.9 259.5v.2M147.9 259.9v.2M148 241.6h.2M148.2 241.6h.1M148.2 243.2h.1M148.2 242.7v.5M148.5 259.4h.1M148.5 259.8h.1M148.5 259.1v.3M148.5 259.5v.2M148.5 259.9v.2"/>
<path d="M148.5 259.6h.1M148.6 258.4l-.1 .3M148.7 243h4.4M148.8 259.8h.2M148.8 243.2h-.8M148.8 241.7h-.6v.4M148.8 258.4l.2 .3M148.8 259.6h.2M149 259.1v.3M149 259.5v.2M149 259.9v.2M149 249.9l.5 .1"/>
<path d="M149 247.2v.2M149 247.4v.7M149 248.8v.8M149 247.4h.5M149 249.4h.5M149.5 246.8h-.5v.3M149.5 259.4h.1M149.5 259.1v.3M149.5 259.5v.2M149.5 259.9v.2M149.5 259.8h.1M149.5 259.6h.1"/>
<path d="M149.6 241.7h.5v.4M149.6 243.2h.8M149.6 258.4l-.1 .3M149.8 259.8h.2M149.8 259.6h.2M149.8 258.4l.2 .3M150 259.1v.3M150 259.5v.2M150 259.9v.2M150.1 247.4h.4M150.1 246.8h.4v.3M150.1 249.4h.4"/>
<path d="M150.1 243.2h.1M150.1 242.7v.5M150.1 241.6h.3M150.5 259.4h.1M150.5 249.9l-.4 .1M150.5 247.2v.9M150.5 248.8v.8M150.5 259.1v.3M150.5 259.5v.2M150.5 259.9v.2M150.5 259.8h.1M150.5 259.6h.1"/>
<path d="M150.6 241.6h.1M150.6 243.2h.1M150.6 258.4l-.1 .3M150.7 241.6h.1M150.7 243.2h.1M150.7 241.7v.4M150.7 242.7v.5M150.8 259.8h.2M150.8 259.6h.2M150.8 258.4l.2 .3M151 259.1v.3M151 259.5v.2"/>
<path d="M151 259.9v.2M151 254.4h2.5M151.5 259.4h.1M151.5 259.8h.1M151.5 259.1v.3M151.5 259.5v.2M151.5 259.9v.2M151.5 259.6h.1M151.6 258.4l-.1 .3M151.8 259.8h.2M151.8 258.4l.2 .3M151.8 259.6h.2"/>
<path d="M152 259.1v.3M152 259.5v.2M152 259.9v.2M152.5 259.4h.1M152.5 259.8h.1M152.5 259.1v.3M152.5 259.5v.2M152.5 259.9v.2M152.5 259.6h.1M152.6 256.5l-.2 .7 .2 1.1M152.6 258.4l-.1 .3M152.8 259.8h.1"/>
<path d="M152.8 259.6h.1M152.8 258.4l.1 .3M152.9 259.1v.3M152.9 259.5v.2M152.9 259.9v.2M152.9 252.4h.6M152.9 254.8l.6 .2M152.9 252.2v.2M152.9 252.4v.7M152.9 253.8v.8M153.4 255.7h.1M153.5 251.8l-.6 .3"/>
<path d="M153.5 259.4h.1M153.5 259.8h.1M153.5 259.1v.3M153.5 259.5v.2M153.5 259.9v.2M153.5 259.6h.1M153.6 258.4l-.1 .3M153.8 259.8h.2M153.8 259.6h.2M153.8 258.4l.2 .3M154 259.1v.3M154 259.5v.2"/>
<path d="M154 259.9v.2M154 251.8l.6 .3M154 252.4h.6M154.5 259.4h.1M154.5 259.8h.1M154.5 259.1v.3M154.5 259.5v.2M154.5 259.9v.2M154.5 259.6h.1M154.6 254.8l-.6 .2M154.6 252.2v.9M154.6 253.8v.8"/>
<path d="M154.6 258.4l-.1 .3M154.8 259.8h.2M154.8 259.6h.2M154.8 258.4l.2 .3M155 259.1v.3M155 259.5v.2M155 259.9v.2M155.1 259.1l-.8 .2-1-.2M155.1 259.1h.1M155.1 255.7h-1.7M155.2 255.8h.1M155.4 243h4.4"/>
<path d="M155.5 259.4h.1M155.5 259.8h.1M155.5 259.1v.3M155.5 259.5v.2M155.5 259.9v.2M155.5 259.6h.1M155.6 258.4l-.1 .3M155.8 259.8h.1M155.8 259.6h.1M155.8 258.4l.1 .3M155.9 256.5v.1M155.9 259.1v.3"/>
<path d="M155.9 259.5v.2M155.9 259.9v.2M155.9 256.6l.3 .8-.3 1M156.3 254.4h-2.3M156.5 259.4h.1M156.5 259.8h.1M156.5 258.4v.3M156.5 259.1v.3M156.5 259.5v.2M156.5 259.9v.2M156.5 259.6h.1M156.5 258.4h.1"/>
<path d="M156.8 259.8h.2M156.8 259.6h.2M156.8 258.4l.2 .3M157 259.1v.3M157 259.5v.2M157 259.9v.2M157.5 259.4h.1M157.5 259.8h.1M157.5 259.1v.3M157.5 259.5v.2M157.5 259.9v.2M157.5 259.6h.1"/>
<path d="M157.6 258.4l-.1 .3M157.8 259.8h.2M157.8 259.6h.2M157.8 258.4l.2 .3M158 259.1v.3M158 259.5v.2M158 259.9v.2M158.2 254.4h2.3M158.5 259.4h.1M158.5 259.8h.1M158.5 259.1v.3M158.5 259.5v.2"/>
<path d="M158.5 259.9v.2M158.5 259.6h.1M158.6 258.4l-.1 .3M158.8 259.8h.2M158.8 259.6h.2M158.8 258.4l.2 .3M159 259.1v.3M159 259.5v.2M159 259.9v.2M159.5 259.4h.1M159.5 259.8h.1M159.5 259.1v.3"/>
<path d="M159.5 259.5v.2M159.5 259.9v.2M159.5 259.6h.1M159.6 258.4l-.1 .3M159.8 259.8h.2M159.8 259.6h.2M159.8 258.4l.2 .3M159.9 252.4h.6M159.9 254.8l.6 .2M159.9 252.2v.2M159.9 252.4v.7M159.9 253.8v.8"/>
<path d="M160 259.1v.3M160 259.5v.2M160 259.9v.2M160.5 251.8l-.6 .3M160.5 259.4h.1M160.5 259.8h.1M160.5 259.1v.3M160.5 259.5v.2M160.5 259.9v.2M160.5 259.6h.1M160.6 258.4l-.1 .3M160.8 259.8h.1"/>
<path d="M160.8 259.6h.1M160.8 258.4l.1 .3M160.9 259.1v.3M160.9 259.5v.2M160.9 259.9v.2M161.1 251.8l.4 .3M161.1 252.4h.4M161.5 259.4h.1M161.5 259.1v.3M161.5 259.5v.2M161.5 259.9v.2M161.5 259.8h.1"/>
<path d="M161.5 252.2v.9M161.5 253.8v.8M161.5 254.8l-.4 .2M161.5 259.6h.1M161.6 258.4l-.1 .3M161.8 259.8h.2M161.8 259.6h.2M161.8 258.4l.2 .3M162 259.1v.3M162 259.5v.2M162 259.9v.2M162 258.3h.1"/>
<path d="M162 258.3l-.3 .8 .3 1.5M164 254.4h-2.9M164.3 241.3v1.7h-2.2M165.9 256.9l-2.9 .4M166.4 254.4h4.9M166.5 254.4l.5 .4M167.4 255.2l.9 .8M167.5 256.9h1.7M168.8 256.5l.4 .4M168.9 257.2l.4 .8M169.2 256.9l.6 .7M169.2 256.9l-.1 .1"/>
<path d="M169.9 258.8l1 1.5M170.5 258.5l1.1 1.6M171.6 257.6h.1M171.6 256.8v.8M171.7 258.1l.5 .6M171.8 256.3h.1M172 256.8h.1M172 256.8v1.3M172 258.1h.1M172.2 258.7h.1M172.3 255.7l-.5 .6M172.5 256.2h.1"/>
<path d="M172.6 258.7h.1M172.6 256.2h1.3M172.6 258.7h1.3M172.7 259l.4 .1M172.8 255.4h.1M173.1 255.4v1.2M173.1 257.9v1.2M173.1 255.4h.2M173.1 255.4h-.3M173.1 259.1h.1M173.3 259.1h.2M173.4 255.3h.2"/>
<path d="M173.7 255.4v1.2M173.7 257.9v1.2M173.7 255.4h.1M173.7 255.4l.9 .3M173.7 259.1h-.1M173.8 254.4h2.4v.3M173.9 256.2h.1M173.9 258.6h.1M174.4 256.7l.1 .1M174.5 258h.1M174.5 256.8v1.2M174.5 258.8l-.8 .3"/>
<path d="M174.5 258.8h.1M175.2 256.5v1.5M175.2 256.5h.1M175.2 258l-.1 .1M176.2 256.5v3.4M188.1 242.9l-.3 .3M188.8 241.7l-.4 .7M189.4 248l-.1 .8M189.6 249.2l.3 .2M189.9 247.5l-.3 .1M215 240.6l-.2 .4-.3-.4M217.3 256.5h.1"/>
<path d="M217.3 254.5h.1M217.3 256.4h.1M217.4 256.4h.1M217.4 254.4h.1M217.9 253.9h.1M217.9 256.4h.1M217.9 254.5h.1M218 256.2h.1M218 253.9h.1M218 256.8l.2 .1M218 256.8l-.1 .2M218 256.8h.1"/>
<path d="M218 256.9h.1M218 257h.1M218 256.6h.1M218 256.3h.1M218 254.4h.1M218.1 255.9h.1M218.1 256h.1M218.1 256.2h.1M218.1 256.9h.1M218.1 253.9h.1M218.1 256.8v.2M218.1 256.8h.1"/>
<path d="M218.1 256.4v.1M218.1 257h.1M218.1 256.6h.1M218.1 255.9v.3M218.1 256.5v.1M218.7 254h.1M218.7 254.3h.1M218.7 253.9h.1M218.7 256.9h.1M218.8 253.9h.1M218.8 256.8h.1M218.8 254.2l-.1 .1"/>
<path d="M218.8 256.8l-.1 .2M218.8 254.6l-.1 .1M218.8 257h.1M218.8 256.6h.1M218.8 253.9v.1M218.8 254.3v.2M218.8 254v.1M218.9 254h.1M218.9 254.3h.1M218.9 253.9h.1M218.9 256.9h.1M218.9 254v.1"/>
<path d="M218.9 256.8v.1M218.9 256.8l.1 .1M218.9 256.8v.2M218.9 256.4v.1M218.9 257h.1M218.9 256.8h.1M218.9 256.6h.1M218.9 256.1v.1M218.9 256.5v.1M218.9 253.9v.1M219.5 254h.1M219.5 254.3h.1"/>
<path d="M219.5 254.6v.1M219.6 254.2l-.1 .1M219.6 253.9h.1M219.6 256.9h.1M219.6 256.8h.1M219.6 256.8l-.1 .2M219.6 257h.1M219.6 256.6h.1M219.6 253.9l.1 .2M219.6 254.3v.2M219.6 254v.1M219.7 254h.1"/>
<path d="M219.7 254.3h.1M219.7 253.9h.1M219.7 256.9h.1M219.7 256.8h.1M219.7 256.8v.1M219.7 256.4v.1M219.7 256.8v.2M219.7 257h.1M219.7 256.6h.1M219.7 256.1v.1M219.7 253.9v.1M219.7 256.5v.1"/>
<path d="M220.3 254.3h.1M220.3 253.9h.1M220.3 256.9h.1M220.3 254.6v.1M220.4 253.9h.1M220.4 254.2v.3M220.4 254.8l-.1 .1M220.4 254h.1M220.4 257h.1M220.4 256.9h.1M220.4 254.9h.1M220.4 254v.1"/>
<path d="M220.4 254.6v.1M220.4 253.9v.1M220.5 254.3h.1M220.5 254.8h.1M220.5 256.5h.1M220.5 254.6h.1M220.5 254h.1M220.5 253.9h.1M220.5 254v.1M220.5 254.6v.1M220.5 256.9h.1M220.5 257h.1"/>
<path d="M220.5 256.4h.1M220.5 254.5h.1M220.5 253.9v.1M221.1 256.4h.1M221.1 254.4h.1M221.2 256.4h.1M223.9 240.6l-.2 .4-.1-.4M227.3 253v.4M227.3 253.7v.3M227.3 254.9v.4M227.3 255.6v.3M227.3 256.8v.3"/>
<path d="M227.3 257.5v.3M227.6 252.7h.1M227.6 253v.4M227.6 253.7v.3M227.6 254.9v.4M227.6 255.6v.3M227.6 256.8v.3M227.6 257.5v.3M227.7 258.1h-.1M227.8 252.8v1.8M227.8 256.3v1.7M227.9 252.6h.1"/>
<path d="M227.9 258.1h.1M227.9 252.7h.1M227.9 258.3h.1M227.9 252.7h.9M227.9 258.1h.9M229.7 252.7h.8M229.7 258.1h.8M230.6 258.1h.1M230.6 252.6h.1M230.6 252.8h.1M230.6 258.3h.1M230.7 256.3v1.7"/>
<path d="M230.7 252.8v1.7M230.8 252.7h.1M230.8 258.1h.1M230.8 253v.3M230.8 253.7v.3M230.8 254.9v.3M230.8 255.6v.3M230.8 256.8v.3M230.8 257.5v.3M231.1 253v.3M231.1 253.7v.3M231.1 254.9v.3"/>
<path d="M231.1 255.6v.3M231.1 256.8v.3M231.1 257.5v.3M241.1 258.1h.1M241.1 259.2h.1M241.1 257.2h.1M241.1 256.2h.1M241.1 255.1h.1M241.1 247.3h.1M241.1 252.4h.1M241.1 250.1h.1M241.1 252.7h.1"/>
<path d="M241.1 254.2h.1M241.1 254.7h.1M241.1 248.5h.1M241.1 259.7h.6M241.1 258.7h.1M241.1 257.7h.1M241.1 256.7h.1M241.1 255.7h.1M241.1 253.7h.1M241.1 253.2h.1M241.1 252.1h.1M241.1 251.7h.1"/>
<path d="M241.1 251.1h.6M241.1 249.5h.1M241.1 250.6h.1M241.1 249h.1M241.1 259.8h.1M241.1 258.5h.1M241.2 251.1v.4M241.2 252v.3M241.2 258.5h.2M241.2 259.7h.1M241.2 252.3h.1M241.2 251.1h.1"/>
<path d="M241.2 258.5v.4M241.2 259.3v.4M241.3 246.2h.1M241.3 250.7h.1M241.3 249h.1M241.3 257.7h.2M241.3 250.1h.3M241.3 252.7h.4M241.3 254.2l.4 .1M241.3 248.5h.5M241.3 258.7h.4M241.3 256.7h.4"/>
<path d="M241.3 255.7h.4M241.3 253.7h.4M241.3 253.2h.3M241.3 252.1h.4M241.3 251.7h.4M241.3 249.5h.4M241.4 258.1h.3M241.4 259.2h.3M241.4 257.2h.3M241.4 256.2h.3M241.4 255.1h.3M241.4 247.4h.1"/>
<path d="M241.4 246.2h.3M241.5 247v.1M241.5 253v4.8M241.5 249.6h.2M241.5 251.2h.2M241.5 253.3h.2M241.5 255.3h.2M241.5 256.2h.2M241.5 257.3h.2M241.5 258.3h.2M241.5 259.2h.2M241.5 250h.3"/>
<path d="M241.5 248.4h.3M241.5 251.6h.3M241.5 252.6h.3M241.5 253.6h.3M241.5 255.6h.3M241.5 256.6h.3M241.5 257.6h.3M241.5 258.6h.3M241.5 259.6h.3M241.5 246.8v.1M241.5 248.2v2.4M241.5 258.5h.2"/>
<path d="M241.6 246.5l-.1 .1M241.7 247.4h.1M241.7 248.2h.1M241.7 246.8h.1M241.7 247.1h.1M241.7 250.2v.5M241.7 251.3v.6M241.7 258.9v.6M241.7 252.3h-.5M241.8 250.1h.1M241.8 250.6h.5M241.8 254.6l-.5 .1"/>
<path d="M241.8 251.4l.1 .5M241.9 246.5h.2M241.9 250.6h.1M241.9 247.4h.6M241.9 251.3h.1M241.9 251.6h.1M241.9 251.5h.1M241.9 251.9h.1M241.9 259.2h.1M241.9 259.4h.1M241.9 259.7h.1M241.9 250.4l-.1 .4"/>
<path d="M241.9 250.5v.3M241.9 251v.2M241.9 251.3v.2M241.9 251.6v.2M241.9 259l-.1 .5M241.9 259.4v.2M241.9 259.7v.2M241.9 248.2h.2M241.9 251.6l.4 .2M241.9 259.7l.4 .1M241.9 259.2h.4M241.9 251.1h.4"/>
<path d="M241.9 259.5h.4M241.9 259.4h.4M241.9 251.5h.4M241.9 251.3h.4M242 257.7h-.2M242 249.5h.3M242 256.2h.3M242 253.7l.3 .1M242 255.7l.3 .1M242 256.7l.3 .1M242 254.2l.4 .1M242 255.1h.3"/>
<path d="M242 252.1h.3M242 259.2h.3M242 258.1h.3M242 258.7l.3 .1M242 253.2h-.2M242 249h-.2M242.1 248.5l.2 .7M242.1 249.6h.3M242.1 253.3h.3M242.1 255.3h.3M242.1 256.2h.3M242.1 257.3h.3"/>
<path d="M242.1 250.1h.3M242.1 246.2h.7M242.1 250h.3M242.1 257.7h.3M242.1 249h.2M242.1 248.4h.3M242.1 251.6h.3M242.1 253.6h.3M242.1 255.6h.3M242.1 256.6h.3M242.1 258.6h.3M242.1 259.6h.3"/>
<path d="M242.2 249.1h.1M242.2 249h.1M242.2 253.2h.1M242.2 249.2h.2M242.2 258.1h.2M242.2 256.2h.2M242.2 253.2h.2M242.2 258.4h.2M242.2 256.3h.2M242.2 254.5h.2M242.2 253.3h.2M242.2 249.2h.1"/>
<path d="M242.3 249.5h.1M242.3 255.1h.1M242.3 254.2h.1M242.3 253.2h.1M242.3 252.1h.1M242.3 251.1h.1M242.3 249h.1M242.3 250.6h.1M242.3 257.7h.1M242.3 257l-.3 .2M242.3 249.4v.1M242.3 251v.1"/>
<path d="M242.3 254v.2M242.3 254.7v.1M242.3 256v.2M242.3 257.7v.2M242.3 258.1h.1M242.3 259v.2M242.3 250.1v.1M242.3 250.4v.4M242.3 252.7v.1M242.3 253v.2M242.3 250.1h.1M242.3 257.6h.1"/>
<path d="M242.3 256.7h.1M242.3 255.7h.1M242.3 254.6h.1M242.3 253.7h.1M242.3 252.6h.1M242.3 251.6h.1M242.3 259.7h.1M242.3 258.7h.1M242.3 248.5h.1M242.3 248.2h.3M242.4 249.6h.1M242.4 257.2h.1"/>
<path d="M242.4 256.2h.1M242.4 255.2h.1M242.4 254.2h.1M242.4 253.2h.1M242.4 252.2h.1M242.4 251.2h.1M242.4 259.2h.1M242.4 258.2h.1M242.4 250h.1M242.4 257.6h.1M242.4 256.6h.1M242.4 255.6h.1"/>
<path d="M242.4 254.6h.1M242.4 253.6h.1M242.4 252.6h.1M242.4 251.6h.1M242.4 259.6h.1M242.4 258.6h.1M242.4 248.4h.1M242.4 250.9v.3h-.3M242.4 251.6v.2M242.4 252.1l-.3 .2M242.4 252.6v.2M242.4 258.1l-.3 .2"/>
<path d="M242.4 258.6v.2M242.4 259.1l-.3 .1M242.4 259.6v.4M242.4 252.7h-.4M242.4 252.5l-.3 .1M242.4 254.7h-.4M242.4 257.6h-.3M242.5 246.4h.1M242.5 245.8v.2M242.5 246.2v.2M242.5 248.2v2.4M242.5 253l-.1 4.8"/>
<path d="M242.6 247v.1M242.6 259.5h.3v2.1h-.2M242.6 259.7h.3M242.6 259.2h.3M242.6 251.6h.3M242.6 251.1h.3M242.6 259.4h.3M242.6 251.5h.3M242.6 251.3h.3M242.6 250.6h.3M242.7 250h.2M242.7 250.1h.2"/>
<path d="M242.7 248.2h.7M242.7 249.2l.2 2M242.7 253.3l.2 4.1M242.7 252.7h.2M242.7 258.1h.2M242.7 252.5h.2M242.7 254.7h.2M242.7 257.6h.2M242.7 257.7h.2M242.7 256.2h.2M242.7 253.2h.2M242.7 258.4h.2"/>
<path d="M242.7 256.3h.2M242.7 254.5h.2M242.8 246.8l-.2 .1M242.9 248.2v2.4M242.9 253v4.8M243 250l.2 .2M243.1 249.5v.1M243.1 249.6h.1M243.1 249.7v.2M243.1 249.5h.1M243.2 249.4l-.1 .1M243.2 246.8l.2 .1"/>
<path d="M243.2 249.1h.1M243.2 249.1l-.2 .9M243.3 250.1h.3M243.3 249.8h.1M243.3 249.5v.3M243.4 247v.1M243.5 246.2h.1M243.6 250.1h.1M243.6 249.1l-.3 .1M243.6 246.2h.1M243.6 246.2h-.4M243.6 249.1l.2 .1"/>
<path d="M243.6 249.1h.1M243.7 246.5v.2M243.7 246.9v.2M243.7 249.3l-.2 .1M243.7 249.9h-.3M243.7 256.3h.6M243.7 255.7v1M243.7 257.1v1M243.7 257.6h.4M243.7 252.7v1M243.7 253.3h.5M243.7 249.4h.1"/>
<path d="M243.7 258.8l.1 .1M243.7 257.5v.4M243.7 257.4h.1M243.7 256.5v.3M243.7 258.4l.3 1.2M243.7 254.6h.1M243.7 254.3h.1M243.7 256.5h.1M243.7 256.2h.1M243.7 246.3h.1M243.7 254.4v-.3v1M243.7 253.5v.2"/>
<path d="M243.7 252.9v.5M243.7 252v.4M243.8 259h.1M243.8 250.1h-.2M243.8 254.3h.1M243.8 254.4h.1M243.8 256.2h.1M243.8 246.4h.1M243.8 246.2l.1 .1M243.8 247.3l-.7 .1M243.8 251.9h.1M243.8 254.7h.1"/>
<path d="M243.8 256.4h.1M243.8 256.1h.1M243.8 249.5v.3M243.8 249.5h.1M243.9 259.1l.1 .2M243.9 259.1h.1M243.9 254.5h.1M243.9 256.4h.1M243.9 246.3h.1M243.9 256.1h.1M243.9 250.2h.1M243.9 249.1l.3 .5"/>
<path d="M243.9 245.8v.2M243.9 246.3v.1M243.9 251.8h.1M243.9 251.2l-.2 .9M243.9 256h.1M244 248.2h.5M244 254.8h.1M244 249.4h.1M244 254.6h.1M244 249.4v.1M244 246.4l.1 .2M244 256h.1"/>
<path d="M244 251.6l-.1 .1M244 249.8v.1M244 249.8h.1M244 249.5v.1M244.1 254.8h.2M244.1 249.6h.1M244.1 254.7v.1M244.1 254.8h-.1M244.1 249.6l-.1 .1M244.1 256v.1M244.1 256.2v.1M244.1 256h.1"/>
<path d="M244.2 249.6l-.3 .6M244.2 246.9l-.2 .3M244.2 259.5l.1 .1M244.2 254.5l-.5 .1M244.3 259.9h.2M244.3 251.2h.1M244.3 251.2l-.1 .2M244.4 259.6h.1M244.4 247.1h.1M244.4 254.5h.2M244.4 256h.2M244.4 254.8h.2"/>
<path d="M244.4 251.2h.1M244.5 259.9h.1M244.5 259.8h.1M244.5 250.9l.4 .6M244.5 250.7l-.3 .3M244.5 250.1h.3M244.5 246.5v.2M244.5 246.9v.8M244.5 248.4v.9M244.5 249.8v.6M244.5 250.7v.2M244.5 251h.1"/>
<path d="M244.5 249.4h.1M244.6 254.6h.3M244.6 256h.1M244.6 254.5v.1M244.6 254.7v.1M244.6 256.2v.1M244.6 249.2h.1M244.6 249.2l-.1 .1M244.7 254.5h.1M244.7 257.6h.4M244.7 256.1h.1M244.7 254.7h.1"/>
<path d="M244.7 256.4h.1M244.7 253.3h.4M244.8 253.5h.1M244.8 257.3h.1M244.8 256.2h.1M244.8 254.6h.1M244.8 254.1v.2M244.8 253.5v.2M244.8 256.4v.4M244.8 254.5v.1M244.8 257.1v.2M244.8 257h.1"/>
<path d="M244.8 253.4h.1M244.8 257.2h.1M244.8 259.3l-.3 .6M244.9 257.3l.1 .1M244.9 254.2v.9M244.9 247.1h-2.7v.7M244.9 256.3h-.3M244.9 255.7v.9M244.9 257v.3M244.9 257.4l.1 .1M244.9 257.5h.1M245 253.4l-.1 .4"/>
<path d="M245 257.5h.1M245 249h-.2M245 253.3h.1M245 247.1h1.3M245.1 257.5h.1M245.1 253.3h.1M245.1 257.6h.1M245.1 253.3v1.4M245.1 256.2v1.4M245.1 248.9h.1M245.2 250.1h.6M245.2 248.8l-.1 .1"/>
<path d="M245.2 257.5h.1M245.2 253.4h.1M245.3 257.4h.1M245.3 248.1l-.1 .6M245.3 246.5v.1M245.3 246.9v.7M245.3 258.7l.5-.6h-.3v.9M245.4 257v.3M245.4 252.1l.3 .6M245.4 253.6v1M245.4 255.5v1.2M245.5 250.1v.9"/>
<path d="M245.5 251.9v.8h.3M245.5 259.9v.8M245.9 247.1h.1M246 256.4l-.6 .1M246.1 252.7l.2 1.8M246.3 247.1v.7M246.3 248.5v.9M246.3 249.8l-.2 .3M246.3 256.4v1.7h-.2M246.3 247.1l.2 .1M246.5 258.1h.1M246.5 250.1h.1"/>
<path d="M246.5 252.7h.1M246.5 256.4h.7M246.6 247.4v.5M246.6 252.7v1.8M246.6 256.4v1.7M246.6 249.8v.3M246.6 248.8h.1M246.6 248.5v.9M246.6 248.8h.2M246.7 254.7l.3 .5M246.8 254.8h.1M246.8 247.1h4.5"/>
<path d="M246.8 254.8l.1 .4M246.8 254.6h.1M247 254.4h.8M247 254.4l-.2 .2M247.1 248.8l.3 .1M247.1 256.4l-.6 .1M247.1 255.6l.2 .4M247.2 255.7l.1 .3M247.3 256h.1M247.3 256.3h.1M247.3 256v.1M247.3 256.2v.2"/>
<path d="M247.4 249l.5 .1M247.4 249h.1M247.6 249h.1M247.7 248.9h.1M247.7 248.8h.3M248.3 248.4l.1 .6M248.3 246.5v.2M248.3 246.9v.8M248.4 248.8h.2M248.4 249h.1M248.4 249.2h.1M248.6 249.3h.1"/>
<path d="M248.6 248.9h.1M248.7 249h.1M248.7 249h.2M248.8 249.4l.1 .1M248.9 249l-.5 .1M248.9 249.5h.1M249 249.6v.5M249 250.5v.4M249 259.8v.5M249 251.1l.1 .1M249 256.2v.1M249 248.8h-.1"/>
<path d="M249.1 259.6l-.1 .1M249.1 251.2h.1M249.1 256.3h.1M249.1 246.5v.2M249.1 246.9v.2M249.2 259.6h-.1M249.2 255.6l-.2 .5M249.2 256.4l.1 .1M249.2 248.8h.1M249.3 251.3h.4M249.3 259.5h.4M249.3 256.4h.8z"/>
<path d="M249.3 248.8l.2 .1M249.3 248.8v.2M249.3 249.4v2.1M249.3 253.5v3.8M249.3 259.3v2.2M249.4 254.4h-.8h.9M249.5 246.9l.2 .3M249.5 254.5h.1M249.6 246.5l-.1 .2M249.6 254.7v.1M249.6 254.8l-.2 .4M249.6 254.8h.1"/>
<path d="M249.6 254.6h.1M249.7 249l.1 .3h.9M249.8 259.3v2h1.6M249.8 253.5v3.8M249.8 254.7h1.2M249.8 256.7h1.2M249.8 255.7h1.2M249.8 252.6h1.3M249.8 253.3h1.3M249.8 254.2h1.1M249.8 253.7h1.1M249.8 257.6h1.3"/>
<path d="M249.8 258.3h1.3M249.8 257.2h1.2M249.8 256.2h1.2M249.8 255.2h1.2M249.8 250.3h1.5M249.8 249.2h.9M249.9 247.4h.7M250.1 251.3h.4M250.1 259.5h.4M250.2 246.5l-.1 .2M250.2 246.9l-.1 .2M250.5 259.5h.1"/>
<path d="M250.7 259.6h.1M250.7 251.2h.1M250.7 251.2h-.1M250.7 259.7h.1M250.8 259.8l.4 .1M251.2 250.9l-.5 .2M251.3 249.6h-1.5v1.9M251.3 254.7l.3 .5M251.4 254.8h.1M251.4 254.6h.1M251.4 254.8l.1 .4M251.5 254.5l-.1 .1"/>
<path d="M251.6 254.4h.8zM251.6 254.4l-.1 .1M251.7 250.9h.4M251.7 259.9l.5 .1M251.7 249.2h1M251.7 249.3h1.1M251.7 246.5v.2M251.7 246.9v.2M251.7 255.6l.3 .4M251.8 255.7l.2 .3M251.8 256.4h-.9l.8 .1M251.9 247.3l-.7 .1"/>
<path d="M251.9 256.3h.1M252 256.3h.1M252 256v.1M252 256.3l-.1 .1M252 256h.1M252 256.2l-.1 .1M252.2 246.5l.1 .1M252.2 254.2h1.2M252.2 253.7h1.2M252.3 254.7h1.1M252.3 256.7h1.1M252.3 255.7h1.1"/>
<path d="M252.3 246.9l-.2 .3M252.3 257.2h1.1M252.3 256.2h1.1M252.3 255.2h1.1M252.4 250.8h.1M252.4 250.8h-.1M252.5 252.6h1.4M252.5 253.3h1.4M252.5 257.6h1.4M252.5 258.3h1.4M252.5 248.4v1.1M252.5 246.5v.1"/>
<path d="M252.5 246.9v.8M252.5 250.1v.5M252.9 249.1h.1M252.9 249.6h1.6M252.9 250.3h1.6M252.9 249v.1M252.9 249.3h.1M253.1 249.1l-.2 .2M253.2 254.4h.8M253.2 248.8l-.2 .1M253.2 254.4h.9M253.4 248.8l-.3 .1"/>
<path d="M253.4 254.7v.1M253.4 253.7h.1M253.4 253.7l.1 .1M253.5 254.2h.1M253.5 256.7h.1M253.5 257.2h.1M253.5 254.7h.1M253.5 255.2h.1M253.5 255.7h.1M253.5 256.2h.1M253.5 248.8l.7 .1M253.5 254v.2"/>
<path d="M253.5 255v.2M253.5 255.7l-.1 .1M253.5 256v.2M253.5 256.7l-.1 .1M253.5 257v.2M253.6 248.8l.7 .2M253.7 247.1h2.2M253.7 256.2v.1M253.7 256v.1M253.7 256.3l.1 .1M253.7 256.3h.1M253.8 252.6v.2"/>
<path d="M253.8 253.1v.2M253.8 257.6v.2M253.8 258.1v.2M253.8 256.4l.1 .1M253.9 258.3h.1M253.9 253.3h.1M253.9 252.6h.1M253.9 257.6h.1M253.9 255.6l-.2 .4M253.9 252.6v.2M253.9 253v.3M253.9 257.6v.2"/>
<path d="M253.9 258v.3M253.9 255.7l-.2 .3M253.9 256.4h.1M254.2 254.5h.1M254.2 246.5v1.9M254.2 250.4v4M254.2 256.4v4M254.2 254.7v.1M254.2 254.8l-.1 .4M254.2 254.8h.1M254.2 254.6h.1M254.5 249.6v.2"/>
<path d="M254.5 250.1v.2M254.5 250.3h.1M254.5 249.6h.1M254.6 256.4l-.7 .1M255.3 249.3h.1M255.3 249.3v2M255.3 253.4v4.1M255.3 259.5v2.1M255.3 249.3l-.5-.2 .6 .2M255.4 249.4h.1M255.5 249.6h.1M255.5 249.3h.1"/>
<path d="M255.5 249.6v1.9M255.5 253.5v3.9M255.5 259.4v2M255.6 249.6h.1M255.6 249.5h.1M255.6 249.3v.1M255.9 247.1h.1M255.9 247.1v.6M255.9 248.4v2.7M255.9 253.3v4.2M255.9 259.7v2.7M255.9 256.4l-.6 .1"/>
<path d="M256 256.5h.1M256.1 246.9h.1M256.1 256.5h.1M316.5 259.1h.1M316.5 255.3h.1M316.6 259.1h.1M316.6 255.9v.9M316.6 256.4h.1M316.6 258.2h.1M316.6 257.7h.1M316.6 257.4v.6M316.6 258.1h.1"/>
<path d="M316.6 257.5h.1M316.6 258.1v1.3M316.6 257.3h.1M316.6 255.6h.1M316.6 255.3h.1M316.6 255.3v.3M316.6 256.2v.3M316.6 256.9v.9M316.6 258.5v.6M316.8 257.2l.1 .1M316.9 257.3h.1M316.9 257.3v1.5"/>
<path d="M316.9 256.9l-.3 .1M317.2 257.3h.2M317.3 256.9h.3M317.4 257.3v1.6M317.4 257.2v.1M317.6 256.9l-.1 .1M317.6 256.9v1.6M321.5 258.4v.4h1.9M321.5 257v.9M323.5 256h-2v.5M324.6 255.5h.1M324.6 259.3h.1"/>
<path d="M324.6 258.7v1.6M324.6 256.9h.9M324.6 254.4v.8M324.6 256.1v1.7M324.8 258.7l-.1 .6M324.8 255.5v.7M324.8 256.8v1.2M324.8 255.5h.1M325.5 258.8h1.9M325.5 256h1.9M326.5 256.9h.9M327.4 259.7v.3"/>
<path d="M327.8 247.4h1M327.8 246.2h1M327.8 249.4h1M327.8 259.2h1M327.8 259.7h1M327.8 250.3h1M327.8 249h1M327.8 256.4h1M327.8 254.4h1M327.8 245.4h1M327.8 243.9h1M327.8 241.4h1"/>
<path d="M327.8 243.4h1M328 240.7v.3h1M329.1 246.5h.1M329.1 246.5v.2M329.1 246.9v.2M329.1 247.1h.1M329.2 246.5h.3M329.3 247.1h.3M329.3 246.5h.1M329.3 247.1h.1M329.7 249.9h.1M329.7 249.7v.2"/>
<path d="M329.7 249.3v.2M329.8 250.1h.1M329.8 246.5h.5M329.9 247.1h.5M329.9 247.4h1.1M329.9 246.2h1.1M329.9 250.1h.3M329.9 256.4h1.1M329.9 245.4h1.1M329.9 243.9h1.1M329.9 241.4h1.1M329.9 249.1v.3h1.1"/>
<path d="M329.9 249.8v.3M329.9 249.1h.3M329.9 249.1h.1M329.9 259.2h1.1M329.9 249h1.2M329.9 254.4h1.1M329.9 243.4h1.1M330 241h1M330.5 246.5h.2M330.6 250.1h.7M330.7 249.1h.3M330.8 246.9l.2 .2"/>
<path d="M330.8 246.5v.2M330.9 246.9v.2M330.9 259l.2 .2M330.9 259.7h.1M330.9 258.1h.4M330.9 254l.2 .2M330.9 248.6l.1 .1M330.9 257l.2 .2M330.9 256.8h.1M330.9 255.1h.6M330.9 253l.2 .2M330.9 251l.2 .1"/>
<path d="M330.9 249.3l.2 .2M330.9 248.8v.4M330.9 250.4v.3M330.9 259.7v.2M330.9 252l.2 .1M330.9 251.8h.1M331 246.5v.2M331 259.4h.2M331 256h-.1M331 250.1l-1.1 .2M331 248.9v.3M331 249.4v.1"/>
<path d="M331 250.5v.3M331 251v.1M331 252.1h.1M331 252.7v.2M331 253v.2M331 253.7v.1M331 254v.2M331 254.7v.1M331 255.1h.1M331 255.7v.1M331 257v.2M331 257.7v.2"/>
<path d="M331 258.1h.1M331 258.7v.1M331 259v.2M331 259.7v.4M331 251.5h.2M331 250.7h.3M331 259.4l.1 .1M331 248.4h.6M331 249.6h.3M331 255.1l.1 .1M331 258.4h.1M331 241.9h.1"/>
<path d="M331 254h.1M331.1 257.4v1.1M331.1 258h.2zM331.1 246.8h.1M331.1 254.9h.1M331.1 255.1h.1M331.1 242.7v.4l.4 .1M331.1 248.7l.1 .5M331.1 247.1h.1M331.1 257.9h.1M331.1 257.4h.1M331.1 260h.1"/>
<path d="M331.1 247.9h.4M331.1 248.5h.1M331.1 248.5h.4v3l.2-.3M331.1 257.5h.1M331.1 257v.3M331.1 256.5v.2M331.1 259.5h.1M331.1 259.9v.1M331.1 259.5l.1 .2M331.1 259.1v.8M331.1 258.4v.6M331.1 246.5h.1"/>
<path d="M331.1 259.6h.1M331.1 254.9h.2M331.1 242h.2M331.1 240.4v.6v-.3M331.1 253h.1M331.1 259.9h.4v2.4M331.1 252.3h.1M331.1 247.6v.6M331.1 259.5h.2M331.1 259.9h.2M331.1 241.6v.5M331.1 246.8v.2"/>
<path d="M331.1 247.2v.2M331.1 253.6v.4M331.1 259.6l.1 .1M331.1 253.6h.1M331.1 253.6v1.3M331.1 252.9v.7M331.1 251.9v.5M331.1 251.6v.2M331.1 251.2v.2M331.1 251h.1M331.1 250.8h.1M331.1 250.9h.1"/>
<path d="M331.1 251.3h.1M331.1 249h.1M331.1 248.8v.1M331.1 242h.1M331.1 241.5h.1M331.1 249.3v.6M331.1 255.5v.9M331.3 253.3h.1M331.1 249.4h.2M331.1 251.3h.2M331.1 250.9h.2M331.1 250.1v.6"/>
<path d="M331.1 252.6v.1M331.1 256.5h.1M331.1 257.5h.2M331.1 254.4h.1M331.1 258.7v.1M331.1 259l.1 1.3M331.1 257.3h.1M331.1 259.9h.1M331.1 251.8h.1M331.1 249.2h.1M331.1 255.9h.1M331.1 255h.1"/>
<path d="M331.1 252.4h.1M331.1 249.2h.2M331.1 255h.2M331.1 245.3v.7M331.1 246.8l.2 .8M331.1 248.5v.2M331.1 248.8v.2M331.1 249.4v.1M331.1 249.6v.6M331.1 250.4v.8M331.1 252.4v.4M331.1 253v.2"/>
<path d="M331.1 253.3v.9M331.1 254.7v.5M331.1 255.7v.1M331.1 256.8v.1M331.1 257.1v.1M331.1 257.7v.8M331.1 250.1l-.2 .1M331.1 254.7l-.2 .1M331.1 258.7l-.2 .1M331.1 257.7l-.2 .2M331.1 255.7l-.2 .1M331.1 250.6l-.2 .1"/>
<path d="M331.1 254.2h.1M331.1 253.2h.1M331.1 252.1h.1M331.1 251.1h.1M331.1 249.5h.1M331.1 259.2h.1M331.1 258.1h.1M331.1 257.7h.1M331.1 257.2h.1M331.1 241.4h.1M331.1 240.7v.7M331.1 250.6h.1"/>
<path d="M331.2 259.7l.1 .1M331.2 254.4h.1M331.2 255.7h.1M331.2 254.7h.1M331.2 253.7h.1M331.2 252.7h.1M331.2 250.1h.1M331.2 256.4h.1M331.2 249.2h.3M331.2 253.7h-.1M331.2 259.7h.1M331.2 258.7h.1"/>
<path d="M331.2 253.7l.1 .3M331.2 250.5v.1M331.2 258.6l.1 .1M331.2 258.6l.1-.2v.3M331.2 257h.1M331.2 257l.1 .1M331.2 246.5h.1M331.2 250.6l.1 .1M331.3 259.4h.1M331.3 253h.1M331.3 250.7h.1M331.3 249h.1"/>
<path d="M331.3 254h.1M331.3 259.1v.3M331.3 252.7v1.1M331.3 254.2h.1M331.3 256.8v.4M331.3 256.2h.1M331.3 253.2h.1M331.3 252.1h.1M331.3 251.1h.1M331.3 249.5h.1M331.3 256.4h-.2M331.3 254.9v1"/>
<path d="M331.3 257.8h.1M331.3 256.7h.1M331.3 258h.5M331.3 259.2h.1M331.3 259.5h.1M331.3 252.7l-.4 .1M331.3 252.2l-.1 .2M331.3 256.8l-.1 .2M331.3 253.7l-.1 .1M331.3 257.7v.4l.3 .1M331.3 255.7h.1M331.3 255.1h.1"/>
<path d="M331.3 254.7h.1M331.3 253.7h.1M331.3 252.7h.1M331.3 252.6h.1M331.3 250.1h.1M331.3 253v.4M331.3 256l.1 .3M331.3 257v.9M331.3 259l.1 .3M331.3 246.7l.1 .1M331.3 248.5h.1M331.3 259.7h.1"/>
<path d="M331.3 258.7h.1M331.3 258.1h.1M331.3 257.7h.1M331.3 257.2h.1M331.4 246.8v.1M331.4 247l1 .1M331.4 256.2h.1M331.4 252.2h.1M331.4 251.2h.1M331.4 246.8h1M331.4 259.2h.1M331.4 248.4v1.3"/>
<path d="M331.4 251.6l-.1 .2M331.4 252.1v.2M331.4 258.1v.2M331.4 259.8h.1M331.4 256.6h.1M331.4 255.6h.1M331.4 255.3h.1M331.4 253.6h.1M331.4 253.3h.1M331.4 252.6h.1M331.4 252.3h.1M331.4 250h.1"/>
<path d="M331.4 249.9v1.3M331.4 252.5l-.1 .3M331.4 253.5v.8M331.4 254.5l-.1 1.3M331.4 256.5l-.1 .3M331.4 259.8h.3M331.4 248.4h.1M331.4 248.2h.1M331.4 259.6h.1M331.4 258.6h.1M331.4 258.3h.1M331.4 257.6h.1"/>
<path d="M331.4 258.5l-.1 .3M331.4 259.5v1.4M331.5 258.1h1M331.5 259.4h.2M331.5 253h.3M331.5 259.5l.2 .2h-1.8M331.5 259.9h.2M331.5 257.8h.3M331.5 256.4l.2 .1M331.5 249.4h.2M331.5 251.3h.2M331.5 250.1h.2"/>
<path d="M331.5 252l.2-.1v.5M331.5 257.5h.2M331.5 253.3h.2M331.5 250.7h.2M331.5 254.3l.2 .3M331.5 252.7h1M331.5 253.7l-.6 .1M331.5 241.7h-.4M331.5 247.7h-.4M331.6 257.3h.1M331.6 249.6h.3M331.6 255h.2"/>
<path d="M331.6 249h.1M331.6 252.6l-.3 .1M331.6 252.8h-.3M331.7 254.6h.1M331.7 259.9v.1M331.7 259.1v.2M331.7 258.4v.6l-.2-.2M331.7 257.4v.5M331.7 248.8h.1M331.7 256.2l-.2 .3M331.7 258.2h.1M331.7 252.7h.1"/>
<path d="M331.7 246.5v.3M331.7 256.2h.1M331.7 246.3h.1M331.7 249.2h.2M331.7 254.9h.2M331.7 242h.3M331.7 247.6h.2M331.7 246.8h.1M331.7 247v.3M331.7 247.1h.1M331.7 253.6v1M331.7 250.3v.7l-.2-.2"/>
<path d="M331.7 255.5v4.1h-.4M331.7 253.4v.1M331.7 252.9v.5M331.7 251.6v.2M331.7 250.8h.1M331.7 251.3h.1M331.7 257.5h.1M331.7 257v.3M331.7 248l-.6 .6M331.7 247.4v.3M331.7 248.6v.2M331.7 247.5h1.1"/>
<path d="M331.7 259.9v1M331.7 248.6h.1M331.7 258h.1M331.7 251.3v.8M331.7 252.7v2M331.7 259.9v.7M331.7 253.5l-.1 .1M331.7 257.3v.1M331.7 258l.4 .1M331.7 250.7h.1M331.7 258.3h.1M331.7 252.6h.1"/>
<path d="M331.7 252.5h.1M331.7 250.3h.1M331.7 250.2h.1M331.7 253.3l.4 .4M331.7 258.3l.1 .1M331.7 258.4h.1M331.7 253.5l.2 .2M331.8 254h-.3v4.2M331.8 250.3h.1M331.8 256.1h.1M331.8 247.2h.1M331.8 258h.1"/>
<path d="M331.8 257.9h-.7M331.8 257.9l.2 1.1M331.8 254.8v.4M331.8 256l.2 3M331.8 248.5l-.1 1.6h.4M331.8 250.4h.1M331.8 247.2l.3 .3M331.8 258.4h.1M331.8 248.2l-.1 .4M331.8 257.1l-.1 .2M331.8 257.9h.1M331.8 257.3h.1"/>
<path d="M331.8 259.9h.1M331.8 255h.1M331.8 254.4h.1M331.8 252.4h.1M331.8 253.6v.6M331.8 251h.2M331.8 249.6v.5M331.8 250.7v.5M331.8 259.6v1.6M331.8 252.5h.1M331.8 246.2h.1M331.8 242h.1"/>
<path d="M331.8 241.4h.1M331.8 258.4h.2M331.9 257.9h.1M331.9 257.4h.1M331.9 260h.1M331.9 255h.1M331.9 252.3h.1M331.9 242h.1M331.9 241.5h.1M331.9 248.2v2.4M331.9 253v4.8M331.9 254.8h-.1"/>
<path d="M331.9 254h.1M331.9 256.8h.1M331.9 254.4h.1M331.9 254.4h-.8M331.9 252.4l-.1 .1M331.9 256.4h.1M331.9 255.2h.2M331.9 252.4v.4M331.9 257.9v.6M331.9 259.2v.9M331.9 255.9h.1M331.9 253.6h.2"/>
<path d="M331.9 240.7v.9M331.9 241.8v.1M332 254.7l-.2 .1M332 251.8h-.2M332 251h.1M332 241.9h.1M332 258h.1M332 257.9h.1M332 259.8v.8M332 256.5h.1M332 254.4h.1M332 256.9h.1"/>
<path d="M332 259h.1M332 259.8h-.2M332 249.8v.3M332 256.8h.1M332 254h.1M332 248h.1M332 251.8h.1M332 258.1h.1M332 257.9v1M332 259.9v1h-2.1M332 256.4h.1M332 253.9h.1"/>
<path d="M332 246.1h.6M332 252.7v2.1M332.1 248.7v.1M332.1 248.8l-.1 .6M332.1 254h.1M332.1 251.1h.1M332.1 251.2h.1M332.1 251.7h.1M332.1 253h.3M332.1 259.6h.3M332.1 241.6l.4 .1M332.1 254h.3"/>
<path d="M332.1 241.9v.1M332.1 242h-.1M332.1 259.2h.1M332.1 259.7h.1M332.1 243.2h.4M332.1 259.7h.9M332.1 253.7h.4v.6M332.1 249.2h.4M332.1 257.8h.4M332.1 247.7h.4M332.1 254.1l.1 .2M332.1 253.9h.1"/>
<path d="M332.1 251.2v.1M332.1 251.5v.2M332.1 253.8h.2M332.1 253.8h.1M332.1 256.9h.1M332.1 247.9h.5M332.1 259.8h.3M332.1 250.5l.2 .1M332.1 259.5v.2M332.1 258.3h.4M332.1 258.5l.2 .1M332.1 247.5l-.3 .4"/>
<path d="M332.1 247.8h.1M332.1 250.9h-.6M332.1 248.4h.5M332.1 252.3v1.7M332.1 255.8v3.5M332.1 248.2v.3h.5M332.1 248.9v.3M332.1 257.1l-.4 .5M332.2 256.5l-.1 .3M332.2 254.3h.1M332.2 256.5h.1M332.2 246.3v.1"/>
<path d="M332.2 252.3l-.1 .1M332.2 256.2l.1 .1M332.3 248.2h-.1M332.3 246l-.6-.2v.3M332.3 252.3h.1M332.3 256.4h.1M332.3 248.2h-.3M332.3 254.5v.1M332.3 254.6h-.2M332.3 254.5l-.1 .1M332.3 258.1h.1M332.4 246.8l-.8 .7"/>
<path d="M332.4 259.6h.1M332.4 254h.1M332.4 255.2h.2M332.4 253.6h.2M332.4 255.6l.1 2.1M332.4 248.8h.1M332.4 259.8h.1M332.4 255.1h.8M332.4 249.1v.1M332.4 255.8h.8M332.4 258.1h.1M332.4 259.8v.7"/>
<path d="M332.4 258.2v.8M332.4 253.9h.2M332.4 247.8l.4 .3M332.5 246.5h.1M332.5 252.3v.9M332.5 254.2l-.1 1.1M332.5 259.7l-.1 2.1M332.5 253h.1M332.5 253.8h.1M332.5 250.7l.5 .2M332.5 250.7h.1M332.5 259.9h.1"/>
<path d="M332.5 259.6l.1 .1M332.5 248.6l-.1 .3M332.5 258.7l.1 .3M332.5 258.7h.1M332.5 252.5h.1M332.5 258.3h.1M332.5 254h.1M332.5 252.7v.1M332.5 252.9v.5M332.5 254.7v.6M332.5 255.6v.3M332.5 256.8v.3"/>
<path d="M332.5 257.5l.1 1M332.5 259.7l.1 .1M332.5 252.5l-.4 .1M332.5 255.1h-.4l-.1 .4M332.5 241.7h.1M332.5 247.7h.1M332.5 252.5v.1M332.5 258.2h.1M332.5 246.4l-1.2 .1M332.6 246.3h.1M332.6 246.3h-.1M332.6 247.6v.6"/>
<path d="M332.6 259.2v4.2M332.6 254.9h.1M332.6 255.1h.1M332.6 259.9h.1M332.6 241.7v.4M332.6 242.7v.4M332.6 248.7v.4M332.6 249.1l-.1 .1M332.6 247.2l-.5 .3M332.6 251.9h.1M332.6 250.1h.4M332.6 251.9l-.2 .3"/>
<path d="M332.6 254.1l.4 .5M332.6 259.9v.2M332.6 251.1l.1 .3M332.6 248.8h.1M332.6 251.1h.1M332.6 259.7h.1M332.6 257.7h.1M332.6 259.8v.3M332.6 255.1v.1M332.6 259.1l.1 .3M332.6 259.1h.1M332.7 247.3l-.6 .5"/>
<path d="M332.7 251.5l-.1 .3M332.7 259.9v.2M332.7 259.5l-.1 .3M332.7 247.7h.1M332.7 247.7l-.4 .5M332.7 259.9h-.6M332.7 258.3l.2 .7M332.7 257.7v2.1M332.8 247l-1.1 .1M332.8 246.8h.1M332.8 247.3l-.8 .7M332.8 248.1h.1"/>
<path d="M332.8 256.9v.1M332.8 257.7v.2M332.8 258.3h.4M332.8 257.8l-.7 .1M332.8 258.2h.1M332.8 258.1h.1M332.8 248.2h.1M332.9 248.8h1.3M332.9 259.7h.1M332.9 256.2v1.4M332.9 249.2h1.1M332.9 258.5v.4"/>
<path d="M332.9 259.3v1.1M332.9 248.2h.1M332.9 248.3v.1M332.9 259.9h.1M332.9 246.2h-.2M332.9 245.8h.6M332.9 253.1h.1M332.9 257.7h.1M332.9 259.8v.6M332.9 258.1h.1M332.9 253.2v1.5M332.9 257.8h.1"/>
<path d="M333 258.5h.1M333 250v.4M333 252.2v1.1M333 254v1.1M333 257.6v1.3M333 258.1h-.5M333 250.7v.8M333 253h.1M333 252.7h-.5M333 259.3v.8M333 257.9h.1M333 259.8h.1"/>
<path d="M333 255.7v1.2M333 256.3l-.4 .4M333.1 249.4l-.1 .4M333.1 249.5l-.1 .1M333.1 257.9h.1M333.1 258.4h.1M333.1 259.8h.1M333.1 246.9l1 .2M333.2 246.8v.1M333.2 247v.1M333.2 249.2h.1M333.2 258.4h.1"/>
<path d="M333.2 252.9h.1M333.2 258.3h.1M333.2 258v.1M333.2 259.9v.1M333.2 249.1h.3M333.2 259.4h.1M333.2 259.4l.1 .2M333.2 251.5h.1M333.2 251.3h.1M333.2 251.3v.2M333.2 258.1h.1M333.2 240.6v.4"/>
<path d="M333.2 252.6v.1M333.2 258.1h-.4M333.3 249l-.1 .1M333.3 247.1h.2M333.3 247.1l-.1 .1M333.3 247.1h-.1M333.3 246.2h.1M333.4 248.9l-.2 .3M333.4 246.3h.1M333.4 246.5h.9M333.4 248.9h.1M333.5 259.7h.1"/>
<path d="M333.5 251.6h.1M333.5 246.4h.1M333.5 248.8l-.1 .1M333.5 246.5h.1M333.5 246.8h1.1M333.5 259.3l.1 2M333.5 253.5v3.8M333.5 259.2h-.1M333.5 259.2h.1M333.5 251.1l-.1 .1M333.5 251.1h.1M333.5 247.1h1.2"/>
<path d="M333.5 254.2h.1M333.5 257.2h.1M333.5 255.2h.1M333.5 250.3h.1M333.5 253.1l.1 .2M333.5 254.7h.1M333.5 258.1l.1 .2M333.5 256.7h.1M333.5 255.7h.1M333.5 253.7h.1M333.5 249.6l.1 .2M333.5 249.6v1.9"/>
<path d="M333.5 256.2h.1M333.5 249.5v.1M333.6 250.1v.9M333.6 253v.4M333.6 255v.3M333.6 252.6l-.1 .2M333.6 257.6l-.1 .2M333.6 249.3h.2M333.6 251.8v1M333.6 253.5v.3M333.6 254v.3M333.6 254.5v.3"/>
<path d="M333.6 255.5v.3M333.6 256v.3M333.6 256.5v.3M333.6 257v.3M333.6 257.4v.4M333.6 258v1M333.6 259.8v1M333.6 249.3h.1M333.6 248.8v.2M333.6 249.2v.1M333.7 248.2l-1.2 .2M333.7 245.8v.2"/>
<path d="M333.7 246.3l-.7 .2M333.7 249.3h-.1M333.7 249.3h.1M333.7 259.7l.5 .2M333.7 251.6l.1 .3M333.7 248.8h.5M333.8 245.8v.2M333.8 246.3v.1M333.8 249.5v2M333.8 247.1h1.4M333.8 247.5l1.3 .1M333.8 259l-.1 .2"/>
<path d="M333.8 252.2l.4 .4M333.8 249.1h.3M333.8 253.4v3.9M333.8 259.3v2M333.9 249.2h.1M334 246.1l-.9 .1M334 247.4l-.8 .1M334 255.1h.8M334 249.3h.1M334 246.2h.1M334.1 246.5v.2M334.1 246.2h.1"/>
<path d="M334.1 249.2h.1M334.1 258h.1M334.1 257.7v.1M334.1 258l-.4 .1M334.1 249h.1M334.1 249.6h.1M334.1 249.4h.1M334.1 249.2v.1M334.1 249.1h.1M334.1 247.1h.1M334.1 248.8h.1M334.2 258.3l-.4 .4"/>
<path d="M334.2 254.2l.2 .4M334.2 257.2l.2 .4M334.2 251l-.5 .1M334.2 246.2h.1M334.2 249.2v.2M334.2 249.7l.2 .3M334.2 259.7h1.3M334.3 249.2v.1M334.3 249h.1M334.3 246.2v.1M334.3 246.5h.1M334.3 247.1h.1"/>
<path d="M334.3 249.3h.1M334.3 249.5v.1M334.3 249.2h.1M334.3 248.8h.1M334.3 249.1l.3 .1M334.3 249.3h.2M334.3 249.6h.1M334.3 248.8h.2M334.3 246.6l.1 .1M334.4 253.3l-.2 .4M334.4 256.3l-.2 .4M334.4 247.4l.9 .1"/>
<path d="M334.4 246.7h.1M334.5 246.9l.9 .1M334.6 246.7h.1M334.6 252.6l.4 .1M334.6 249.6h.1M334.6 249.6v1.9M334.6 253.5v3.9M334.6 259.4v1.9M334.7 249.4h.1M334.7 256.2l.3-.1v.6M334.7 246.7h.1M334.7 249.3h.2"/>
<path d="M334.7 248.8l.2 .2M334.8 248.8h-.4M334.8 254.6l.2 .1M334.8 257.6l.2 .1M334.8 255.1v.2M334.8 255.6v.2M334.8 250.1h.2M334.8 255.1h.1M334.8 247.1h.2M334.8 249.3h.1M334.8 247.1h.4M334.8 252.6h.1"/>
<path d="M334.8 254.7h.1M334.8 253.7h.1M334.8 253.3h.1M334.8 254.2h.1M334.8 255.2h.1M334.8 250.3h.1M334.8 249.6h.1M334.8 257.6h.1M334.8 256.7h.1M334.8 255.7h.1M334.8 255.6l-.8 .2M334.8 251.8v1"/>
<path d="M334.8 253.6v.2M334.8 254.6v.2M334.8 256.5v.3M334.8 257.5v.3M334.8 259.8v1M334.8 258.3h.1M334.8 257.2h.1M334.8 256.2h.1M334.9 249.3h.1M334.9 249.2v.1M334.9 246.7l.1 .1M334.9 249.6l-.1 .2"/>
<path d="M334.9 250.1l-.1 .9M334.9 253l-.1 .4M334.9 254l-.1 .3M334.9 256l-.1 .3M334.9 257l-.1 .3M334.9 258l-.1 1M335 258.1l-.4 .1M335 253.2h-.3M335 250.6l-.4 .2M335 253v.7M335 255v.3M335 255.6v.3"/>
<path d="M335 258v.9M335 255.8h.1M335 250.5v.8M335 249.1h.3M335 250v.3M335 252v.9M335 254.2v.6M335 257.2v.7M335 259.6v.8M335 255.1l-.2 .3M335 249.6v.2M335 248.9l.2 .1"/>
<path d="M335 248.9h.1M335.1 248.8h1.1M335.1 249.2h1.3M335.2 247.1h.1M335.2 249l.1 .1M335.2 249h.1M335.2 247.1l.1 .1M335.3 249.2h.1M335.3 247.6l.4 .2M335.4 249.5v.3M335.4 249.5h.1M335.4 252.7h.5"/>
<path d="M335.4 251.9v2.6M335.4 250.1h.5M335.4 259.9v1h-1.2M335.4 250v1M335.4 256.3v2.7M335.4 258.1h.5M335.7 247.7l.5 .5M335.7 247.7h.1M335.8 251.5v.2M335.8 259.2v.1M335.8 259.5v.2M335.8 247.4l.6 .6"/>
<path d="M335.8 251.7h.1M335.8 251.1v.2M335.8 259.7h.1M335.8 259.1v.1M335.9 247.4h.1M335.9 247.4l.5 .5M335.9 250.9h.1M335.9 251.9l.1 .2M335.9 258.9h.1M335.9 259.9l.1 .2M336 248l.1 .2M336 247.2l.7 .7"/>
<path d="M336 252.1h.1M336 250.7l-.1 .2M336 258.7l-.1 .2M336.1 248.2h.1M336.1 258.4v.3M336.1 257.7v.3M336.2 258.8h.1M336.2 252.3l.2 .1M336.2 248.2h-1.3M336.2 250.6h.1M336.2 258.6h.1M336.2 249h.1"/>
<path d="M336.2 249.2h.1M336.2 249.1h.1M336.2 248.8h.1M336.2 248.8v.1M336.2 258.9h.1M336.3 248.4l.1 .1M336.4 250.1h.4M336.4 258.1h.6M336.4 248.5h.1M336.4 248.7v.1M336.4 248.8l.1 .6M336.4 248l.1 .1"/>
<path d="M336.4 247.9l.1 .1M336.4 251.7h.1M336.4 251.1v.3M336.4 251.5v.1M336.4 250.4l-.2 .2M336.4 259.7h.1M336.4 259.6h.1M336.4 259.2v.2M336.4 259.1h.1M336.4 259.5v.1M336.4 258.4l-.2 .2M336.5 249.8v.3"/>
<path d="M336.5 252.7v1.8M336.5 256.4v1.7M336.5 248.7l-.1 .1M336.5 251.8h.1M336.5 251.1h.1M336.5 259.8h.1M336.5 259.1h.1M336.5 249.2h.1M336.5 250.2h.1M336.5 251h.1M336.5 252.4l.2 .1M336.5 259h.1"/>
<path d="M336.6 258.4h.1M336.7 258.4h.1M336.7 248.5l.1 .4M336.7 252.5h.1M336.7 258.3h.1M336.7 248.6l.1 .4M336.8 252.6h.1M336.8 250.3h.1M336.8 258.3h.1M336.8 251.3l.2 .7M336.8 257.7v1.7M336.8 250.3l-.2 .1"/>
<path d="M336.8 258.9h.1M336.8 258.4v.3M336.8 259.9l.2 .1M336.8 259.7h1.3M336.9 248.5l.1 2.6M337 250.1l-.2 .6M337 259.7l-.1 2.6M337 253.3v4.2M337 252.7h-.6M337.1 250.8l-.3 .2M337.1 258.8l-.3 .2M337.1 252.1l.2 .2"/>
<path d="M337.2 258.1l.2 .2M337.2 250.1l.2 .2M337.3 258.6l-.1 .1M337.3 250.4l-.1 .3M337.3 258.4v.2M337.4 252.6l-.2 .1M337.4 258.3v.3M337.4 257.7v.3M337.4 258.8v.7M337.4 258.9h-1.1M337.4 258.9h.1M339.5 257.7v2.1"/>
<path d="M345.1 245.8h.7M346.6 245.8h.8M350.8 253.2h.1M350.8 253.2v2M350.8 257.3v4.2M38.1 274.3l.2 .2M38.1 279.4l.2 .2M38.1 269.2l.2 .2M38.1 264.2l.2 .1M38.1 261.5h.1M38.1 264.2h.1M38.1 266.5h.1"/>
<path d="M38.1 269.2h.1M38.1 271.6h.1M38.1 279.4h.1M38.1 274.3h.1M38.1 276.7h.1M38.1 260.7v.8M38.1 264.2v.7M38.1 265.8v.7M38.1 269.2v.8M38.1 270.8v.8M38.1 274.3v.8M38.1 275.9v.8"/>
<path d="M38.1 279.4v.8M38.3 276.5l-.2 .2M38.3 271.4l-.2 .2M38.3 266.4l-.2 .1M38.3 261.3l-.2 .2M38.5 274.7l.2 .2M38.5 279.8l.2 .2M38.5 269.6l.2 .2M38.5 264.5l.2 .3M38.7 274.9v.4M38.7 275.8v.3M38.7 276.1l-.2 .2"/>
<path d="M38.7 264.8h2.4M38.7 280h2.4M38.7 274.9h2.4M38.7 269.8h2.4M38.7 280v.4M38.7 260.9h2.4M38.7 271h2.4M38.7 265.9h2.4M38.7 269.8v.4M38.7 270.7v.3M38.7 271l-.2 .2M38.7 264.8v.3"/>
<path d="M38.7 265.6v.3M38.7 265.9l-.2 .2M38.7 260.5v.4M38.7 260.9l-.2 .2M40.3 260.9h.1M40.3 265.9h.1M40.3 271h.1M40.3 276.1h.1M40.3 264.8h.1M40.3 269.8h.1M40.3 280h.1M40.3 274.9h.1"/>
<path d="M40.4 260.8h.1M40.4 265.9h.1M40.4 270.9h.1M40.4 276h.1M40.4 264.8h2.1M40.4 269.9h2.1M40.4 275h2.1M40.4 264.8h.1M40.4 269.9h.1M40.4 275h.1M40.4 260.8h2M40.4 265.9h2"/>
<path d="M40.4 270.9h2M42.4 276l-3.7 .1M43.6 264.8h4.8M43.6 280h4.8M43.6 274.9h4.8M43.6 269.8h4.8M43.6 260.9h4.8M43.6 271h4.8M43.6 265.9h4.8M44.5 260.8h4M44.5 265.9h4M44.5 270.9h4"/>
<path d="M44.5 264.8h4M44.5 269.9h4M44.5 275h4M48.5 276l-4.9 .1M50.6 264.8h2v.4M50.6 269.9h2v.4M50.6 275h2v.3M50.9 264.8h2.4v.3M50.9 280h2.4v.4M50.9 274.9h2.4v.4M50.9 269.8h2.4v.4M52.6 260.5v.3h-2"/>
<path d="M52.6 265.6v.3h-2M52.6 270.6v.3h-2M52.6 275.7v.3M53.3 275.8v.3l-2.7-.1M53.3 260.5v.4h-2.4M53.3 270.7v.3h-2.4M53.3 265.6v.3h-2.4M54.3 262v4.2M54.3 268.4v4.1M54.3 274.7v4.2M54.7 276.1h.1M54.7 260.9h.1"/>
<path d="M54.7 271h.1M54.7 265.9h.1M54.7 264.8h.2M54.7 280h.2M54.7 274.9h.2M54.7 269.8h.2M54.7 262v4.2M54.7 268.4v4.1M54.7 274.7v4.2M55 276.1h.1M55 260.9h.1M55 271h.1"/>
<path d="M55 265.9h.1M55 264.8h.1M55 280h.1M55 274.9h.1M55 269.8h.1M57.2 270.2v.4M57.2 265.1v.5M57.2 260.1v.4M57.2 275.3v.4M57.3 260.7l.1 .2M57.3 275.9l.1 .2M57.3 270.8l.1 .2"/>
<path d="M57.3 265.8l.1 .1M57.4 280l-.1 .1M57.4 274.9l-.1 .1M57.4 264.8h-.1M57.4 269.8l-.1 .2M57.9 275.2h.2M57.9 275.8h.2M57.9 270.1h.2M57.9 270.7h.2M57.9 265h.2M57.9 265.6h.2M57.9 264.8v.3"/>
<path d="M57.9 265.6v.3M57.9 269.8v.4M57.9 270.7v.3M57.9 274.9v.4M57.9 275.8v.3M57.9 280v.4M58.1 260.6l-.2 .3M58.2 260.6l.2 .3M58.2 275.2h.2M58.2 275.8h.2M58.2 270.1h.2M58.2 270.7h.2"/>
<path d="M58.2 265h.2M58.2 265.6h.2M58.4 264.8v.3M58.4 265.6v.3M58.4 269.8v.4M58.4 270.7v.3M58.4 274.9v.4M58.4 275.8v.3M58.4 280v.4M59 280h.1M59 274.9h.1M59 269.8h.1"/>
<path d="M59 264.8h.1M59 276v.1M59 265.9h.1M59 260.8v.1M59 270.9v.1M59 264.9l.1 .2M59 270l.1 .2M59 275.1l.1 .1M59.1 260.5v.1M59.1 265.6v.1M59.1 275.7v.2M59.1 275.2v.1"/>
<path d="M59.1 275.4l.1 .1M59.1 270.3l.1 .1M59.1 265.2l.1 .1M59.1 260.1l.1 .2M59.1 270.6v.2M59.2 275.5h.1M59.2 265.3h.1M59.2 260.3h.1M59.2 270.4h.1M62.3 275.3v.4M62.3 270.2v.4M62.3 265.1v.5"/>
<path d="M62.3 260.1v.4M62.4 275.9v.2M62.4 270.8v.2M62.4 265.8v.1M62.4 260.7v.2M62.4 280v.1M62.4 269.8v.1M62.4 274.9v.2M62.4 264.8v.1M63 264.8v.3M63 265.6v.3M63 269.8v.4"/>
<path d="M63 270.7v.3M63 274.9v.4M63 275.8v.3M63 280v.4M63 275.2h.2M63 275.8h.2M63 270.1h.2M63 270.7h.2M63 265h.2M63 265.6h.2M63.2 260.6l-.2 .3M63.3 260.6h.2"/>
<path d="M63.3 275.2h.2M63.3 275.8h.2M63.3 270.1h.2M63.3 270.7h.2M63.3 265h.2M63.3 265.6h.2M67.4 271.8h.1M67.4 269h.1M67.5 269.1v.9M67.5 270.9v.8M67.6 271.8h.1M67.6 268.9h.1"/>
<path d="M67.6 271.9v.1M67.6 269h.1M67.6 271.8h1.8M67.6 269h1.7M67.9 268.8h.2M67.9 272h.3M67.9 272.3h.3M67.9 268.5h.2M68.5 268.8h.3M68.5 268.5h.3M68.6 272h.2M68.6 272.3h.2"/>
<path d="M69.8 268.8h.3M69.8 268.5h.3M69.8 272h.3M69.8 272.3h.3M70.4 268.8h.3M70.4 268.5h.3M70.4 272h.3M70.4 272.3h.3M71.1 269h1.7M71.2 271.8h1.6M71.7 268.8h.2M71.7 272h.3"/>
<path d="M71.7 272.3h.3M71.7 268.5h.2M72.3 268.8h.3M72.3 268.5h.3M72.3 272h.3M72.3 272.3h.3M72.9 271.8h.1M72.9 269.1h.1M72.9 268.9h.1M72.9 271.9l.1 .1M73 270.8v.9M73 269.1v.8"/>
<path d="M73.1 269h.1M73.1 271.8h.1M79.2 266.4l.1 .1M79.3 274.4h-.1M79.4 271.8l.1 2.6M79.5 266.4l-.1 2.7M79.7 274.6v.1M79.7 266v.1M79.7 274.7h.3M79.7 274.7v.1M80.1 274.8h.2M80.1 275.4h.2"/>
<path d="M80.1 265.4h.1M80.1 266h.1M80.4 265.4h.2M80.4 266h.2M80.5 274.8h.1M80.5 275.4h.1M81.4 274.8h.2M81.4 275.4h.2M81.4 265.4h.1M81.4 266h.1M81.4 266.2l-1.8 .1M81.7 265.4h.2"/>
<path d="M81.7 266h.2M81.8 274.8h.1M81.8 275.4h.1M81.8 274.7h3.5M82.7 274.8h.1M82.7 275.4h.1M82.7 265.4h.1M82.7 266h.1M83.1 265.4h.1M83.1 266h.1M83.1 274.8h.1M83.1 275.4h.1"/>
<path d="M83.2 266.2h3.5M84 274.8h.2M84 275.4h.2M84 265.4h.1M84 266h.1M84.3 265.4h.2M84.3 266h.2M84.4 274.8h.1M84.4 275.4h.1M85.3 266h.1M85.3 274.8h.2M85.3 275.4h.2"/>
<path d="M85.3 265.4h.1M85.6 266h.2M85.6 265.4h.2M85.7 274.8h.1M85.7 275.4h.1M86.6 266h.1M86.6 274.8h.2M86.6 275.4h.2M86.6 265.4h.1M86.9 266h.2M86.9 265.4h.2M87 274.8h.1"/>
<path d="M87 275.4h.1M87.9 266h.1M87.9 274.8h.1M87.9 275.4h.1M87.9 265.4h.1M88.2 266h.2M88.2 265.4h.2M88.3 274.8h.1M88.3 275.4h.1M88.5 266.2l.4 .1M88.8 274.7l.1 .1M88.9 266l-.1 .1"/>
<path d="M88.9 274.6l-1.8 .1M89 266.4l.1 .1M89.1 266.5v2.6M89.1 271.7v2.6M89.1 274.3l-.1 .1M89.1 274.4h.1M89.2 266.4l-.1 .1M94.7 267.8l.2 .1M94.9 273h-.2M94.9 272.9l.1 .1M94.9 267.9v1.7M94.9 271.3v1.6"/>
<path d="M95 267.8l-.1 .1M95.2 267.4v.1M95.2 273.2v.1M95.2 273.3v.1M95.2 273.3h1.7M95.5 273.4h.2M95.5 267.4h.1M95.5 266.8h.1M95.5 274h.2M95.8 267.4h.2M95.8 266.8h.2M95.9 273.4h.1"/>
<path d="M95.9 274h.1M96.5 273.4h.2M96.5 267.4h.1M96.5 266.8h.1M96.5 274h.2M96.8 267.4h.2M96.8 266.8h.2M96.9 273.4h.1M96.9 274h.1M96.9 267.6l-1.8 .1M97.5 273.4h.2M97.5 267.4h.1"/>
<path d="M97.5 266.8h.1M97.5 274h.2M97.8 267.4h.2M97.8 266.8h.2M97.9 273.4h.1M97.9 274h.1M98.5 274h.2M98.5 273.4h.2M98.5 267.4h.1M98.5 266.8h.1M98.6 267.6l1.7 .1M98.6 273.3h1.7"/>
<path d="M98.8 267.4h.2M98.8 266.8h.2M98.9 274h.1M98.9 273.4h.1M99.5 274h.2M99.5 273.4h.2M99.5 267.4h.1M99.5 266.8h.1M99.8 267.4h.2M99.8 266.8h.2M99.9 274h.1M99.9 273.4h.1"/>
<path d="M100.3 273.3l.1 .1M100.4 273.1l-.1 .2M100.4 267.4l-.1 .1M100.5 267.8l.1 1.7M100.6 271.3l-.1 1.7M100.7 273h.1M100.7 267.8v.1M118.5 278.5l.2 .1M118.9 278.7l.3 .3M119.2 279h.1M119.2 279.8l-.3 .4M119.2 279.3v.3"/>
<path d="M122.3 263.9v2M122.3 268v1.9M122.3 263.9h.1M122.3 264.2v1.8M122.3 267.8v3.2M122.3 269.6l.1 .1M122.3 272.5v1.5h1.4M122.3 266.8h1.4M122.4 264.2h.1M122.4 270h.1M122.4 269.8l.1 .2M122.4 263.8h.1"/>
<path d="M122.5 270.1h.1M122.5 263.7h1.4M122.5 270.1h1.5M122.5 270h.1M122.5 263.9l-.1 .1M122.5 267.8v1.6M122.6 264.3l-.1 1.8M122.6 269.6l.1 .1M122.7 264.2h.1M122.7 269.7h.1M122.7 263.8h1.4M122.8 264.1l-.1 .1"/>
<path d="M122.8 270h1.2M122.8 269.8h1.3M122.9 264h1.3M123.1 261.7h.1M123.1 261.2v.5M123.1 261.7h.3M123.1 273.2l.2 .5M123.1 272.1h.1M123.1 272.1h.2M123.1 272.2v.5M123.4 260.1l-.3 .5M123.6 273.7h.1"/>
<path d="M123.6 272.1l.8 .1M123.6 261.7h.1M123.6 260.1l.8 .1M123.7 261.7h.7M123.7 273.6h.7M125.1 273.6h.6M125.1 260.2h.6M125.1 266.8h1.8M125.2 274h1.6M125.3 269.8h1.2M125.4 270h1.4M125.4 264h1.1"/>
<path d="M125.4 263.8h1.3M125.5 263.7h1.5M125.6 270.1h1.4M125.7 261.7h.2M125.7 261.7h.1M125.7 260.2v.4M125.7 261.2v.5h-.6M125.7 260.1h.2M125.7 273.2l.2 .5M125.7 272.1h.1M125.7 272.2v.5M125.9 275.6h.3"/>
<path d="M125.9 265.2h.3M125.9 265.4v1h.3M125.9 276.4v1h2M125.9 272.1l-.8 .1M126.1 272.1h.3M126.2 261.7h.2M126.2 260.1h.2M126.2 274.4h-.3v1M126.4 260.1h.1M126.4 261.7h.1M126.4 260.2v.4M126.4 261.2v.5"/>
<path d="M126.4 273.2l-.3 .5M126.4 272.1h.1M126.4 272.2v.5M126.5 264l.1 .1M126.7 274.4h.3v.4M126.8 264.2h.1M126.9 269.6l-.2 .1M126.9 264.4l.1 2h-.4M126.9 263.9h.1M126.9 263.9l.2 .1M127 267.8l-.1 1.7M127 263.7h.1"/>
<path d="M127 275.3v.3M127.1 269.8l-.2 .2M127.1 270.1h.1M127.1 263.8h.1M127.1 270h.1M127.2 269.6l-.1 .1M127.2 264.2v1.8M127.2 270h.1M127.2 265.2h-.5M127.2 263.9h.1M127.2 269.2h.1M127.2 266.3v3.6"/>
<path d="M127.2 271.7v2.9M127.2 275.1v.5M127.2 268.4h.1M127.2 272.4h.1M127.2 271.6h.1M127.2 265.2h.1M127.2 274h.3M127.2 269.9h.1M127.2 263.9v2M127.2 266.8h.3M127.3 275.6h-.7M127.4 265.2h.4"/>
<path d="M127.4 265.2h.1M127.4 275.6h.1M127.4 268.4h.1M127.4 272.4h.1M127.5 269.2h.2l.1 .8M127.5 266.7v2.5M127.5 265.2v.4M127.5 266v.5M127.5 266.4h.6M127.5 274.4h.7M127.5 275.2v.4M127.5 269.2h.1"/>
<path d="M127.5 271.6v2.5M127.5 274.3v.5M127.5 271.6h.1M127.8 270.8l-.1 .8h-.3M127.8 275.6h-.4M127.9 269.2l.2 .8M128 263.4h-2.1v1M128.1 270.8l-.2 .8M128.2 275.6h1.1M128.2 265.2h.4M128.5 265.2v1.7M128.5 268.7v3.5"/>
<path d="M128.5 274v1.6M128.6 260.9h2.1h-2.1M128.6 260.8h.1M128.6 260.9h.1M128.7 260.5h.1M128.7 265.2v.7M128.7 265.2h.1M128.7 266.5v.7h.7M128.7 267.1h.7M128.7 260.6h.1M128.7 260.7h.1M128.7 260.7l2.1 .1"/>
<path d="M128.8 260.4h.1M128.8 260.7h.1M128.8 266.4h.7v1.7M128.8 260.6h.1M128.9 260.5h.1M128.9 274.4h.6M128.9 260.7h.1M128.9 260.7h1.9M129 260.6h.1M129 260.6h1.8M129.2 276.3v.9h.3M129.5 274.7h-.3v.8"/>
<path d="M129.5 269.9v3.5M129.7 269.2l.1 .5M129.8 274.7l.2 .8M129.8 268.1l-.1 .5M130 268.1h.9M130 269.7h.9M130 274.7h.8M130 276.3v.9M130.1 277.4h2.1v1.7M130.2 275.6h1.1M130.3 268.1v.5M130.3 269.2v.5"/>
<path d="M130.8 265.8l.1-.6v.7M130.8 266.5v.6h-.6M130.8 277.1l-1 .1M130.9 266.6v.6h-.7M131 268.7v3.5M131 274v1.6M131.4 265.2h-.4v1.7M131.6 268.1h.6M131.6 269.7h.8M131.7 277.1l1 .1M131.7 274.7h.8M131.7 265.2h1.5"/>
<path d="M132 265.2v1.6h.4M132 268.6v3.5M132 273.9v1.7M132 274h.3M132.1 265.2h.1M132.1 275.6h.1M132.2 268.1h.2M132.2 261.4v2h-2M132.2 268.1v.5M132.2 269.2v.5M132.3 265.2v.5M132.3 266.3v2.9"/>
<path d="M132.3 271.6v3M132.3 275.1v.5M132.5 276.3v.9M132.5 279.9h.1M132.5 279.3h.1M132.5 279.3v.2M132.5 279.8v.1M132.5 279.3h.5M132.5 265.2v.4M132.5 266v.4h.6M132.5 275.2v.4M132.6 268.1l.2 .5"/>
<path d="M132.7 260.6h1.8M132.7 260.7h1.8M132.7 274.7h-.2v.8M132.7 274h.9M132.8 266.8h.8M132.8 269.2l-.2 .5M133 274.7h.3v.8M133 279.9h-.5v.7M133.1 275.6h-1.4M133.2 274.4h-.7v.4M133.3 276.3v.9h-.3M133.5 279.3l.6 .2"/>
<path d="M133.9 266.4h.6M133.9 274.4h.6v.4M133.9 265.2h.7l-.1 .4M134 279.9v.7M134.1 279.8l-.6 .1M134.3 266.8h.9M134.3 274h.9M134.5 266v.4M134.5 260.7h.1M134.5 275.3v.3h-.6M134.5 260.6h.1M134.5 260.8h.1"/>
<path d="M134.6 266.1l-.1 .3M134.6 260.5h.1M134.7 260.4h.1M134.7 260.6h-.1M134.7 275.6h.7M134.7 275.3l.1 .3M134.7 260.5v-.7v.9M134.7 260.7h.1M134.7 260.7l-2 .1M134.8 265.2h.6M134.8 265.2l-.1 .4M134.8 265.2h.1"/>
<path d="M134.8 275.6l.4 1.1M134.8 260.6h.1M134.8 260.7h.1M134.8 260.9h.1M134.9 260.9h.1M134.9 260.8h.1M134.9 260.9h-2.1h2M135 264.7l-.2 .5M135.5 272.8h.1M135.5 273.2v.2M135.5 275.4h.1M135.5 275.8l.5 .2"/>
<path d="M135.5 272.8v.2M135.5 263l-.4 1.1M135.5 273.4h.5M135.5 275.4h.5M135.5 272.8h.5M135.5 273.4v.6M135.5 274.7v.9M135.5 266.8h.7M135.6 277.8l.4 1M135.6 270.1h.1M135.6 270.4v.3M135.6 274h.7"/>
<path d="M135.6 270.8v.2M135.6 269.7v.4M135.6 270.7h.1M135.6 270.7h.2M135.6 271.1h.1M135.7 271.3h.1M135.7 269.5h.1M135.7 271.4h.1M135.8 271.4h.1M135.8 269.4h.1M135.8 271.4l.3 .2M135.8 269.1l-.2 .6"/>
<path d="M135.9 270.3v.3M135.9 270.8v.3M135.9 269.8v.3M135.9 269.7h.1M136 269.6h.1M136 278.8l.4 1M136 278.8h1.7M136 271.3v.1M136 271.3h.1M136 269.5h.1M136 265.2h.6v1.7M136.1 261.7l.1 .1"/>
<path d="M136.1 270.7h.2M136.1 269.1l.8 .1M136.1 271.4l.3 .2M136.1 271.4h.1M136.1 269.3l-.3 .1M136.2 279.1h-.1M136.3 269.1v.6M136.3 270.2v.5h.6M136.3 269.3l-.2 .1M136.4 261.1l-.6 1.4M136.4 271.7l.3 .2M136.4 279l.7 .7"/>
<path d="M136.5 276h.5M136.5 273.4h.5v.6M136.5 272.8h.5M136.6 274v1.6h-.5M136.6 268.7v3.5M136.6 266.8h.7M136.7 274h.7M136.7 271.9h.1M136.7 268.9h.1M136.7 268.9l-.3 .2M136.7 271.7l.3 .2M136.8 271.9h.1"/>
<path d="M136.9 268.9h.1M136.9 260.3l.5 .2M137 274.7v.7h-.5M137 268.9l-.3 .2M137 261.2l-.6 .7M137 268.9h.1M137 272.8h.1M137 273.4h.1M137 275.4h.1M137 276h.1M137 272.8v.2M137 273.2v.2"/>
<path d="M137 275.4v.2M137 275.8v.2M137.1 271.9h.1M137.1 268.9h.1M137.1 271.9l.4 .1M137.2 268.9h.1M137.2 268.9h-.5M137.3 262h3.4M137.4 271.9l.1 .1M137.5 272h.1M137.7 272h.1M137.7 266.8l.8 .2"/>
<path d="M137.8 272l.7 .2M137.9 272h.1M138 268.8l-.6 .1M138 272h.1M138.3 270.7h.1M138.3 270.2v.5h-.7M138.3 269.1v.6M138.4 269.1l-.8 .1M138.5 273.9l-.8 .1M138.6 260.3l-.6 .2M138.6 268.6l-.8 .3M138.6 270.7h.2"/>
<path d="M138.6 269.1l.2 .6M138.8 270.2v.5M138.9 267.3v.9M138.9 273.5h.1M138.9 272.6v.9M138.9 268.2h.1M139.4 278.8h3.5M142.2 270l.3 .1M142.2 273l.3 .1M142.2 272l.3 .2M142.2 269l.3 .2M142.2 271l.3 .1"/>
<path d="M142.2 268.1h.1M142.2 268.1h.3M142.2 278l.3 .1M142.2 277l.3 .2M142.2 264l.3 .2M142.2 276.1h.3M142.2 265l.3 .1M142.2 275l.3 .1M142.2 266l.3 .1M142.2 274l.3 .2M142.2 267l.3 .1M142.2 263l.3 .1"/>
<path d="M142.5 274.7l-.3 .1M142.5 265.7l-.3 .2M142.5 266.7l-.3 .1M142.5 273.7l-.3 .2M142.5 267.7l-.3 .1M142.5 272.7l-.3 .1M142.5 277.7l-.3 .1M142.5 268.7l-.3 .2M142.5 271.7l-.3 .2M142.5 276.7l-.3 .2M142.5 263.7l-.3 .2M142.5 269.7l-.3 .1"/>
<path d="M142.5 270.7l-.3 .1M142.5 264.7l-.3 .1M142.5 275.7l-.3 .1M142.5 262.7l-.3 .1M142.9 265.1h.3M142.9 265.7h.3M142.9 274.7h.3M142.9 275.1h.3M142.9 266.1h.3M142.9 266.7h.3M142.9 273.7h.3M142.9 274.2h.3"/>
<path d="M142.9 267.1h.3M142.9 267.7h.3M142.9 272.7h.3M142.9 278.1h.3M142.9 273.1h.3M142.9 268.1h.3M142.9 277.7h.3M142.9 268.7h.3M142.9 271.7h.3M142.9 263.1h.3M142.9 272.2h.3M142.9 269.2h.3"/>
<path d="M142.9 263.7h.3M142.9 276.7h.3M142.9 269.7h.3M142.9 270.7h.3M142.9 277.2h.3M142.9 270.1h.3M142.9 264.2h.3M142.9 271.1h.3M142.9 264.7h.3M142.9 275.7h.3M142.9 276.1h.3M142.9 262.7h.3"/>
<path d="M143.2 265.1h.1M143.2 275.1h.1M143.2 266.1h.1M143.2 274.2h.1M143.2 267.1h.1M143.2 278.1h.1M143.2 273.1h.1M143.2 268.1h.1M143.2 263.1h.1M143.2 272.2h.1M143.2 269.2h.1M143.2 277.2h.1"/>
<path d="M143.2 264.2h.1M143.2 271.1h.1M143.2 270.1h.1M143.2 276.1h.1M143.4 265.1h.1M143.4 275.1h.1M143.4 266.1h.1M143.4 265.7h.1M143.4 274.7h.1M143.4 274.2h.1M143.4 267.1h.1M143.4 266.7h.1"/>
<path d="M143.4 273.7h.1M143.4 278.1h.1M143.4 273.1h.1M143.4 268.1h.1M143.4 267.7h.1M143.4 272.7h.1M143.4 263.1h.1M143.4 272.2h.1M143.4 269.2h.1M143.4 277.7h.1M143.4 268.7h.1M143.4 271.7h.1"/>
<path d="M143.4 277.2h.1M143.4 270.1h.1M143.4 264.2h.1M143.4 271.1h.1M143.4 263.7h.1M143.4 276.7h.1M143.4 269.7h.1M143.4 270.7h.1M143.4 276.1h.1M143.4 264.7h.1M143.4 275.7h.1M143.4 262.7h.1"/>
<path d="M143.5 267.7v.1M143.5 268.1h.1M143.5 268.7v.2M143.5 269v.2M143.5 269.7v.1M143.5 270v.1M143.5 270.7v.1M143.5 271v.1M143.5 271.7v.2M143.5 272v.2M143.5 272.7v.1M143.5 273v.1"/>
<path d="M143.5 263.7v.2M143.5 264v.2M143.5 264.7v.1M143.5 265v.1M143.5 265.7v.2M143.5 266v.1M143.5 266.7v.1M143.5 267v.1M143.5 273.7v.2M143.5 274v.2M143.5 274.7v.1M143.5 275v.1"/>
<path d="M143.5 275.7v.1M143.5 276.1h.1M143.5 276.7v.2M143.5 277v.2M143.5 277.7v.1M143.5 278v.1M143.5 262.7v.1M143.5 263v.1M143.6 264.7v.1M143.6 265v.1M143.6 274.7v.1M143.6 275v.1"/>
<path d="M143.6 265.7v.2M143.6 266v.1M143.6 273.7v.2M143.6 274v.2M143.6 266.7v.1M143.6 267v.1M143.6 272.7v.1M143.6 273v.1M143.6 267.7v.1M143.6 268.1h.1M143.6 271.7v.2M143.6 272v.2"/>
<path d="M143.6 277.7v.1M143.6 278v.1M143.6 262.7v.1M143.6 263v.1M143.6 268.7v.2M143.6 269v.2M143.6 270.7v.1M143.6 271v.1M143.6 276.7v.2M143.6 277v.2M143.6 263.7v.2M143.6 264v.2"/>
<path d="M143.6 269.7v.1M143.6 270v.1M143.6 275.7v.1M143.6 276.1h.1M143.7 275.7h.2M143.7 265.1h.2M143.7 265.7h.2M143.7 274.7h.2M143.7 275.1h.2M143.7 266.1h.2M143.7 266.7h.2M143.7 273.7h.2"/>
<path d="M143.7 274.2h.2M143.7 267.1h.2M143.7 267.7h.2M143.7 272.7h.2M143.7 278.1h.2M143.7 273.1h.2M143.7 268.1h.2M143.7 277.7h.2M143.7 268.7h.2M143.7 271.7h.2M143.7 263.1h.2M143.7 272.2h.2"/>
<path d="M143.7 269.2h.2M143.7 263.7h.2M143.7 276.7h.2M143.7 269.7h.2M143.7 270.7h.2M143.7 277.2h.2M143.7 270.1h.2M143.7 264.2h.2M143.7 271.1h.2M143.7 264.7h.2M143.7 276.1h.2M143.7 262.7h.2"/>
<path d="M144.1 275.7h.1M144.1 265.1h.1M144.1 274.7h.1M144.1 265.7h.1M144.1 275.1h.1M144.1 266.1h.1M144.1 266.7h.1M144.1 274.2h.1M144.1 267.1h.1M144.1 273.7h.1M144.1 278.1h.1M144.1 268.1l.1 .2"/>
<path d="M144.1 267.7h.1M144.1 273.1h.1M144.1 272.7h.1M144.1 277.7h.1M144.1 263.1h.1M144.1 268.7h.1M144.1 272.2h.1M144.1 269.2h.1M144.1 271.7h.1M144.1 277.2h.1M144.1 276.7h.1M144.1 270.1h.1"/>
<path d="M144.1 263.7h.1M144.1 264.2h.1M144.1 269.7h.1M144.1 271.1h.1M144.1 270.7h.1M144.1 264.7h.1M144.1 276.1h.1M144.1 262.7h.1M144.2 263v.3M144.2 264v.3M144.2 265v.3M144.2 266v.3"/>
<path d="M144.2 267v.3M144.2 269v.3M144.2 270v.3M144.2 271v.3M144.2 272v.3M144.2 273v.3M144.2 274v.3M144.2 275v.3M144.2 276.1v.2M144.2 277v.3M144.2 278v.8l.6 .1M144.2 260.8v.6"/>
<path d="M144.2 262.1v.7M144.2 260.8h.1M144.2 263.6v.3M144.2 264.5v.3M144.2 265.6v.3M144.2 266.6v.2M144.2 267.5v.3M144.2 268.6v.3M144.2 269.5v.3M144.2 270.6v.2M144.2 271.6v.3M144.2 272.5v.3"/>
<path d="M144.2 273.6v.3M144.2 274.6v.2M144.2 275.5v.3M144.2 276.6v.3M144.2 277.5v.3M144.2 279.5v.6M144.3 260.7l-.1 .1M144.4 280h.1M144.4 263v.3M144.4 263.6v.3M144.4 264v.3M144.4 264.5v.3"/>
<path d="M144.4 265v.3M144.4 265.6v.3M144.4 266v.3M144.4 266.6v.2M144.4 267v.3M144.4 267.5v.3M144.4 268.1v.2M144.4 268.6v.3M144.4 269v.3M144.4 269.5v.3M144.4 270v.3M144.4 270.6v.2"/>
<path d="M144.4 271v.3M144.4 271.6v.3M144.4 272v.3M144.4 272.5v.3M144.4 273v.3M144.4 273.6v.3M144.4 274v.3M144.4 274.6v.2M144.4 275v.3M144.4 275.5v.3M144.4 276.1v.2M144.4 276.6v.3"/>
<path d="M144.4 277v.3M144.4 277.5v.3M144.4 278v.8M144.4 279.4v.6M144.4 280l.1 .1M144.4 260.9h.1M144.4 260.9v.6M144.4 262.1v.7M144.4 260.8v.1M144.5 260.9v2.1M144.5 277.9l.1 2.1M144.5 265.2v4.2"/>
<path d="M144.5 271.5v4.2M144.6 260.9l.1 .1M144.6 260.5h.1M144.6 260.4l-.1 .1M144.6 260.4h.6M144.7 260.6h-.1M144.7 260.6h.1M144.7 260.6h.5M144.7 279.8l-.1 .1M144.8 260.7v.1M144.8 260.8l.1 .1M144.9 261.9l-2.4 .1"/>
<path d="M144.9 279.9l-.1 .2M145.5 279.2l.9 .9M145.7 261.9l-.1 .5 .2 .3M145.7 261.9h.1M145.9 260.4h.7M145.9 260.6h.7M146.3 261.8l.3 .5-.3 .3M146.4 260.7l-.9 .9M146.5 260.3v.1M146.8 260.7l-2.2 .1M147 260.3v.1M147.1 260.6h-.3"/>
<path d="M147.1 260.4h-.3M147.4 260.6h.2M147.5 260.3l-.1 .1M147.8 260.6h.3M147.9 260.3v.1M148.1 260.4h-.3M148.3 260.6h.3M148.3 260.4h.3M148.5 260.3v.1M148.8 260.6h.3M149 260.3v.1M149 260.7h4.2"/>
<path d="M149.1 260.4h-.3M149.3 260.6h.3M149.3 260.4h.3M149.5 260.3v.1M149.8 260.6h.3M150 260.3v.1M150.1 260.4h-.3M150.3 260.6h.3M150.3 260.4h.3M150.5 260.3v.1M150.8 260.6h.3M151 260.3v.1"/>
<path d="M151.1 260.4h-.3M151.3 260.6h.3M151.3 260.4h.3M151.5 260.3v.1M151.8 260.6h.3M152 260.3v.1M152.1 260.4h-.3M152.4 260.6h.2M152.4 260.4h.2M152.5 260.3v.1M152.8 260.6h.3M152.9 260.3v.1"/>
<path d="M153.1 260.4h-.3M153.3 260.6h.3M153.3 260.4h.3M153.5 260.3v.1M153.8 260.6h.3M154 260.3v.1M154.1 260.4h-.3M154.3 260.6h.3M154.3 260.4h.3M154.5 260.3v.1M154.8 260.6h.3M155 260.3v.1"/>
<path d="M155.1 260.4h-.3M155.3 260.7h4.2M155.4 260.6h.2M155.4 260.4h.2M155.5 260.3v.1M155.8 260.6h.3M155.9 260.3v.1M156.1 260.4h-.3M156.3 260.6h.3M156.5 260.3l-.2 .1M156.8 260.6h.3M157 260.3v.1"/>
<path d="M157.1 260.4h-.3M157.3 260.6h.3M157.3 260.4h.3M157.5 260.3v.1M157.8 260.6h.3M158 260.3v.1M158.1 260.4h-.3M158.3 260.6h.3M158.3 260.4h.3M158.5 260.3v.1M158.8 260.6h.3M159 260.3v.1"/>
<path d="M159.1 260.4h-.3M159.3 260.6h.3M159.3 260.4h.3M159.5 260.3v.1M159.8 260.6h.3M160 260.3v.1M160.1 260.4h-.3M160.2 268.7v3.5M160.2 274v1.6h1.8M160.4 260.6h.2M160.4 260.4h.2M160.5 260.3v.1"/>
<path d="M160.8 260.6h.3M160.9 260.3v.1M161.1 260.4h-.3M161.3 260.6h.3M161.3 260.4h.3M161.5 260.3v.1M161.6 260.7h2.1M161.8 260.6h.8M162 260.3v.1M162.1 265.2h-1.9v1.7M162.1 260.7h.1M162.6 260.4h-.8"/>
<path d="M163.1 261.7l1.2 .3M163.2 260.6h.6M163.2 260.4h.7M163.7 279.9v.3M163.7 260.7v.2M163.7 260.7h.1M163.7 279.8l.2 .1M163.8 260.6h.1M163.9 260.5h.1M163.9 260.4l.1 .1M163.9 275.6h3.6M163.9 260.9l-.2 .1"/>
<path d="M163.9 260.9h.1M164 265.2h3.6M164 277.8v2.2M164 260.9v2.1M164 265.1v4.2M164 271.5v4.2M164 260.8l.1 .1M164.1 280l-.1 .1M164.1 280h.1M164.1 260.9v.5M164.1 262.1v.7M164.1 263v.3"/>
<path d="M164.1 263.5v.3M164.1 264v.3M164.1 264.5v.3M164.1 265v.3M164.1 265.5v.3M164.1 266v.3M164.1 266.5v.3M164.1 267v.3M164.1 260.9h.1M164.1 267.5v.3M164.1 268v.3M164.1 268.5v.3"/>
<path d="M164.1 269v.3M164.1 269.5v.3M164.1 270v.3M164.1 270.5v.3M164.1 271v.3M164.1 271.5v.3M164.1 272v.3M164.1 272.5v.3M164.1 273v.3M164.1 273.5v.3M164.1 274v.3M164.1 274.5v.3"/>
<path d="M164.1 275v.3M164.1 275.5v.3M164.1 276v.3M164.1 276.5v.3M164.1 277v.3M164.1 277.5v.3M164.1 278v.7M164.1 279.4v.6M164.1 260.6l.1 .2M164.2 260.8h.1M164.2 270.1h.2M164.2 270.7h.2"/>
<path d="M164.2 271.1h.2M164.2 269.7h.2M164.2 269.2h.2M164.2 271.7h.2M164.2 272.2h.2M164.2 268.7h.2M164.2 268.1h.2M164.2 273.1h.2M164.2 275.7h.2M164.2 265.1h.2M164.2 267.7h.2M164.2 276.1h.2"/>
<path d="M164.2 267.1h.2M164.2 273.7h.2M164.2 264.7h.2M164.2 274.2h.2M164.2 276.7h.2M164.2 264.2h.2M164.2 266.7h.2M164.2 277.2h.2M164.2 274.7h.2M164.2 266.1h.2M164.2 263.7h.2M164.2 275.1h.2"/>
<path d="M164.2 277.5l.2 .2M164.2 260.8v.6M164.2 262v.8M164.2 263.5v.3M164.2 264.5v.3M164.2 265.5v.3M164.2 275.5v.3M164.2 276.5v.3M164.2 279.4v.7M164.2 265.7h.2M164.2 263.1h.2M164.2 278.1h.2"/>
<path d="M164.2 263v.3M164.2 264v.3M164.2 265v.3M164.2 266v.3M164.2 266.5v.3M164.2 267v.3M164.2 267.5v.3M164.2 268v.3M164.2 268.5v.3M164.2 269v.3M164.2 269.5v.3M164.2 270v.3"/>
<path d="M164.2 270.5v.3M164.2 271v.3M164.2 271.5v.3M164.2 272v.3M164.2 272.5l.2 .2M164.2 273v.3M164.2 273.5v.3M164.2 274v.3M164.2 274.5v.3M164.2 275v.3M164.2 276v.3M164.2 277v.3"/>
<path d="M164.2 278v.7M164.2 262.7h.2M164.5 270.7l.3 .1M164.5 269.7l.3 .1M164.5 271.7l.3 .1M164.5 268.7l.3 .1M164.5 272.7h.3M164.5 275.7l.3 .1M164.5 267.7l.3 .1M164.5 273.7h.3M164.5 267.1h.3M164.5 264.7l.3 .1"/>
<path d="M164.5 276.7l.3 .1M164.5 266.7l.3 .1M164.5 274.7l.3 .1M164.5 263.7l.3 .1M164.5 277.7h.3M164.5 265.7l.3 .1M164.5 262.7l.3 .1M164.8 272.8v.4M164.8 267.7v.3M164.8 272.5v.1M164.8 273.4v.3M164.8 268.2v.3"/>
<path d="M164.8 271l-.3 .1M164.8 270l-.3 .1M164.8 272l-.3 .2M164.8 269l-.3 .2M164.8 273l-.3 .1M164.8 272.7v.1M164.8 268l-.3 .1M164.8 274l-.3 .2M164.8 273.7v.1M164.8 265l-.3 .1M164.8 277l-.3 .2M164.8 267v.1"/>
<path d="M164.8 275l-.3 .1M164.8 264l-.3 .2M164.8 278l-.3 .1M164.8 266l-.3 .1M164.8 277.7v.1M164.8 276l-.3 .1M164.8 263l-.3 .1M164.8 272.3v.2M164.8 267.1h.1M164.8 267.1v.3M164.9 272.3h.1M164.9 273.8h.1"/>
<path d="M164.9 268.6h.1M165 270.1h.1M165 270.7h.1M165 271.1h.1M165 269.7h.1M165 269.2h.1M165 271.7h.1M165 272.2h.1M165 268.7h.1M165 268.1h.1M165 272.7h.1M165 273.1h.1"/>
<path d="M165 275.7h.1M165 265.1h.1M165 267.7h.1M165 276.1h.1M165 267.1h.1M165 273.7h.1M165 264.7h.1M165 274.2h.1M165 276.7h.1M165 264.2h.1M165 266.7h.1M165 277.2h.1"/>
<path d="M165 274.7h.1M165 266.1h.1M165 263.7h.1M165 275.1h.1M165 277.7h.1M165 265.7h.1M165 263.1h.1M165 278.1h.1M165 262.7h.1M165 272.1h.1M165 268.7l.3 .2M165 273.9l.3 .1"/>
<path d="M165 273.9h.1M165.1 262.7v.1M165.1 263v.1M165.1 263.7v.1M165.1 264v.2M165.1 264.7v.1M165.1 265v.1M165.1 265.7v.1M165.1 266v.1M165.1 266.7v.1M165.1 267v.1M165.1 267.7v.1"/>
<path d="M165.1 268v.1M165.1 268.7v.1M165.1 269v.2M165.1 269.7v.1M165.1 270v.1M165.1 270.7v.1M165.1 271v.1M165.1 271.7v.1M165.1 272v.2M165.1 273v.1M165.1 273.7v.1M165.1 274v.2"/>
<path d="M165.1 274.7v.1M165.1 275v.1M165.1 275.7v.1M165.1 276v.1M165.1 276.7v.1M165.1 277v.2M165.1 278v.1M165.1 272l-.1 .1M165.1 270.1h.1M165.1 270.7h.1M165.1 271.1h.1M165.1 269.7h.1"/>
<path d="M165.1 269.2h.1M165.1 271.7h.1M165.1 272.2h.1M165.1 268.7h.1M165.1 268.1h.1M165.1 272.7h.1M165.1 273.1h.1M165.1 265.1h.1M165.1 267.7h.1M165.1 276.1h.1M165.1 267.1h.1M165.1 273.7h.1"/>
<path d="M165.1 264.7h.1M165.1 274.2h.1M165.1 264.2h.1M165.1 276.7h.1M165.1 266.7h.1M165.1 277.2h.1M165.1 266.1h.1M165.1 274.7h.1M165.1 263.7h.1M165.1 275.1h.1M165.1 263.1h.1M165.1 277.7h.1"/>
<path d="M165.1 265.7h.1M165.1 278.1h.1M165.1 275.7h.1M165.1 262.7h.1M165.2 273.5l.1 .2M165.2 273.5h.1M165.2 272.8h.1M165.2 272.6h.1M165.2 272.8v.3h.4M165.2 267.4h.1M165.2 268.2l.1 .3M165.2 267.6v.4"/>
<path d="M165.3 270.7h.3M165.3 270.1h.3M165.3 270.7h.1M165.3 271.1h.3M165.3 269.7h.3M165.3 271.7h.3M165.3 269.7h.1M165.3 269.2h.3M165.3 271.7h.1M165.3 272.2h.3M165.3 268.7h.3M165.3 272.7h.3"/>
<path d="M165.3 268.7h.1M165.3 268.1h.3M165.3 272.7h.1M165.3 267.7h.3M165.3 265.1h.3M165.3 273.7h.3M165.3 267.7h.1M165.3 276.1h.3M165.3 264.7h.3M165.3 273.7h.1M165.3 274.2h.3M165.3 276.7h.3"/>
<path d="M165.3 266.7h.3M165.3 264.7h.1M165.3 264.2h.3M165.3 274.7h.3M165.3 276.7h.1M165.3 266.7h.1M165.3 277.2h.3M165.3 266.1h.3M165.3 263.7h.3M165.3 274.7h.1M165.3 275.1h.3M165.3 277.7h.3"/>
<path d="M165.3 265.7h.3M165.3 263.7h.1M165.3 263.1h.3M165.3 275.7h.3M165.3 277.7h.1M165.3 265.7h.1M165.3 278.1h.3M165.3 262.7h.3M165.3 275.7h.1M165.3 262.7h.1M165.3 272h-.2M165.3 272.5h.1"/>
<path d="M165.3 272.5l-.1 .1M165.3 266.8l-.3 .1M165.3 272.3h.1M165.3 272.3v.1M165.3 268.5h.1M165.3 273.8h.1M165.4 271.9h.2M165.4 273.9h.1M165.4 273.9l.2 .1M165.4 272.1h.1M165.4 266.9h.1M165.4 268.7l.3 .1"/>
<path d="M165.4 268.9h.3M165.5 274h.2M165.5 266.9h.1M165.5 266.8h.2M165.5 272h.1M165.6 267.1l-.4 .3M165.6 262h3.4M165.6 272h.1M165.6 266.8h.1M165.7 272h-.1M165.9 268.9h.1M165.9 268.9h.2"/>
<path d="M165.9 270.7l.3 .1M165.9 269.7l.3 .1M165.9 271.7l.3 .1M165.9 268.7l.3 .1M165.9 272.7h.3M165.9 267.7l.3 .1M165.9 273.7l.3 .1M165.9 264.7l.3 .1M165.9 276.7l.3 .1M165.9 266.7l.3 .1M165.9 274.7l.3 .1M165.9 263.7l.3 .1"/>
<path d="M165.9 277.7h.3M165.9 265.7l.3 .1M165.9 275.7l.3 .1M165.9 262.7l.3 .1M165.9 266.8h1.9M166 278.8l-2.1 .1-.9 .3M166 274h.1M166 271.9l-.1 .1M166 271.9h.1M166 268.9h.1M166.1 271.9h-.2M166.1 268.9l2.5 .2"/>
<path d="M166.2 271.9h.1M166.2 268.9h.1M166.2 278l-.3 .1M166.2 277l-.3 .2M166.2 270l-.3 .1M166.2 263l-.3 .1M166.2 264l-.3 .2M166.2 276l-.3 .1M166.2 265l-.3 .1M166.2 275l-.3 .1M166.2 266l-.3 .1M166.2 274l-.3 .2"/>
<path d="M166.2 267l-.3 .1M166.2 273l-.3 .1M166.2 268l-.3 .1M166.2 272l-.3 .2M166.2 271l-.3 .1M166.2 272.7v.1M166.2 277.7v.1M166.3 271.9h.1M166.3 271.9h-.1M166.3 268.9l-.4 .3M167.1 274h3.5M167.8 278.8h3.4"/>
<path d="M168.5 271.7l-2.4 .2M168.6 271.7l-2.3 .2M169.4 275.6h2M169.5 265.2h1.9M169.5 264h.1M169.5 263.4h.1M169.5 261.4h.1M169.5 260.8h.1M169.5 260.8v.2M169.5 261.3v.1M169.5 263.4v.2M169.5 263.9v.1"/>
<path d="M169.5 262.8v.6h.5M169.5 260.8h.5M169.5 264h.5M169.6 266.8h3.5M170 261.4h-.5v.7M170.5 263.4l.6 .2M170.5 260.8l.6 .2M170.8 262h1.7M170.9 269.2l2.7 .3M171 261.4v.7M171 262.8v.6M171.1 263.9l-.6 .1"/>
<path d="M171.1 261.3l-.6 .1M171.4 261.2l.6 .7M171.7 275.6h.8M171.7 265.2h.7M171.8 265.2v1.7M171.8 268.6v3.5M171.8 273.9v1.7M172 278.9l-.6 .8M172.1 261.1l.4 .9M172.2 279.1h.2M172.4 274h1.8M172.4 261.7l-.1 .1"/>
<path d="M172.5 262l.4 1M172.9 277.8l-.8 1.9M173.1 265.2h.7M173.1 275.6h.6M173.2 269.4l.2 .1M173.3 264.1l.5 1.5M173.4 271.4l-2.4 .2M173.5 271.4l-2.6 .2M173.6 271.4h-.2M173.7 269.6l.3 .3M173.7 275.6h.1M173.7 275.6l-.4 1"/>
<path d="M173.8 275.2l-.1 .4M173.9 275.6h.7M173.9 266l.1 .4M173.9 269.6l.3 .4M174 274.4l-.1 .4M174 274.4h.7M174 266.4h.6M174 266v.4M174 274.4v.4M174 275.2v.4M174 270.9l-.3 .3M174.1 270.2v.4"/>
<path d="M174.1 266.8h.1M174.2 270.9l-.3 .3M174.2 270.2v.5M174.3 274h.4M174.3 266.8h.4M174.7 265.2h-.7v.4M175.1 274h.7M175.1 266.8h.7M175.3 275.6h.8M175.3 266.4h.7M175.3 274.4l.7-.1v.5M176 265.2v.4"/>
<path d="M176 266.1v.4M176 275.3v.3M176 266.7v2.5M176 271.6v2.6M176.1 265.2h-.8M176.1 274h.4M176.1 266.8h.4M176.2 261.7v1.7h2.2M176.2 279.4v3.5M176.3 265.2h.5M176.4 275.6h.3M176.5 265.2v1.7"/>
<path d="M176.5 268.7v3.5M176.5 274v1.6M177.1 275.6h1.2M177.2 265.2h.3M177.5 265.2v1.7M177.5 268.6v3.5M177.5 273.9v1.7M177.6 278.2l.2 .5M177.6 275.2l.2 .5M177.6 265.2l.1 .7M177.6 269.2l.2 .5M177.6 272.2l.2 .5"/>
<path d="M177.7 265.2h.1M177.7 266.5l-.1 .7h.7M177.7 267.1h.6M177.8 274.1l-.2 .6M177.8 268.1l-.2 .5M177.8 277.1l-.2 .6M177.8 271.1l-.2 .6M178 277.1h.9M178 278.7h.9M178 275.7h.9M178 271.1h.9M178 274.1h.9"/>
<path d="M178 268.1h.9M178 272.7h.9M178 269.7h.9M178.3 268.1v.5M178.3 269.2v.5M178.3 271.1v.6M178.3 272.2v.5M178.3 274.1v.6M178.3 275.2v.5M178.3 277.1v.6M178.3 278.2v.5M178.3 277.4h-2.1v.3"/>
<path d="M179 272.7v1.7h.7M179 266.4h.6M179 267.5v3.4M179.1 267.1h.7M179.1 275.6h1.1M179.6 271.1h.8M179.6 277.1h.6M179.6 274.1h.6M179.6 268.1h.6M179.6 278.7h.8M179.6 275.7h.8M179.6 272.7h.8"/>
<path d="M179.6 269.7h.8M179.8 266.5v.7h-.7M179.8 265.2h.1M179.8 265.2v.7M180 268.6v3.5M180 273.9v1.7M180.2 270.8v.9M180.2 271.6h.2M180.2 268.1v.5M180.2 272.2v.5M180.2 274.1v.6M180.2 275.2v.5"/>
<path d="M180.2 277.1v.6M180.2 278.2v.5M180.2 274.1h.2M180.2 268.1h.2M180.2 277.1h.2M180.3 265.2h-.3v1.7M180.3 266.4h.7M180.4 274.4h.6v.4M180.4 269.2l-.2 .8M180.5 263.4h2.2v1M180.6 275.6h.5M180.6 277.1l.2 .6"/>
<path d="M180.6 271.1l.2 .6M180.6 268.1l.2 .5M180.6 274.1l.2 .6M180.7 265.2h.4M180.7 271.6h.4M180.7 270.8v.8M180.8 278.2l-.2 .5M180.8 275.2l-.2 .5M180.8 269.2l-.2 .5M180.8 272.2l-.2 .5M181 274h.3M181 268.4h.1"/>
<path d="M181 272.4h.1M181 266.8h.3M181 265.2v.4M181 266.1v.5M181 275.3v.3M181 271.7v2.5M181 266.7v2.5M181.1 269.2h-.4v.8M181.3 268.4h.2M181.3 272.4h.2M181.3 271.6l.2 2.6M181.3 269.2h.2"/>
<path d="M181.5 266.7v2.5M181.5 266.4h.3M181.5 265.2v.4M181.5 266v.5M181.5 275.2v.4M181.6 274h1.7M181.8 275.6h-.5M181.9 265.2h-.6M181.9 274.4h-.4v.4M182.2 275.6h.5M182.3 265.2h.4M182.3 274.4h.4v1"/>
<path d="M182.7 265.5v.9h-.5M182.7 276.5v.9h-2.2M183.3 266.8h-1.6M184.7 266.8h1.4v2.4M186.1 271.7v2.3h-1.3M200.4 275.4h.5M200.4 265.4h.5M201.5 275.4h.6M201.5 265.4h.6M203.4 265.4h.6M203.4 275.4h.5M204.5 275.4h.6"/>
<path d="M204.6 265.4h.5M206.3 275.4h.7M206.3 265.4h.7M207.6 275.4h.5M207.6 265.4h.5M226.6 277.3h.9M226.6 277.2h.9M226.6 277.7h.9M227.2 277.2h.1M227.2 276.9v.1M227.3 277.2v.1M228 279.7v.7"/>
<path d="M228 279.7h.7M228 279.3h.1M228 278.7h.7M228.1 278.8l-.1 .3M228.1 279.4h.1M228.2 278.4l-.1 .2M228.2 279.3l.1 .1M228.2 278.3h.1M228.3 278.3h.1M228.3 278.5h.1M228.3 278.6h.1M228.3 278.6v.5"/>
<path d="M228.3 279.1v.3M228.3 279.4h.1M228.3 276.9v.1M228.3 279h.1M228.3 279v.1M228.4 278.3h.1M228.4 277.7h.8M228.4 279.1h.1M228.4 276.9v.1M228.4 277.1v.1M228.5 279.9l-.1-.3 .1 .4M228.5 278.4h.1"/>
<path d="M228.5 278.4l.1 .1M228.5 280h.1M228.6 278.6v.2M228.6 278.6h.1M228.6 279.9h.1M228.6 278.8h.1M228.6 279.7h.1M228.6 279.8h.1M228.6 279.1l.1 .5M228.7 279.4h.1M228.7 279.7h-.1M228.7 279.9h.1"/>
<path d="M228.8 278.9l-.1 .4M228.8 279.9h.1M228.8 279.8h.1M228.8 278.6h.1M228.8 278.4v.2M228.8 280v.1M228.9 278.4h.1M228.9 279.9h.1M228.9 277.2h.1M228.9 276.9v.1M228.9 279.7v.1M229 278.3h.1"/>
<path d="M229 278.5h.1M229 278.6h.1M229 278.6v.2M229 279v.4M229 278.8h.1M229.1 278.3h.1M229.1 278.5h.1M229.1 279v.4M229.1 278.6h.1M229.1 279.4v.1M229.1 278.6v.2M229.1 277.2l-.8 .1h.8"/>
<path d="M229.1 279.8l.1 .2M229.2 278.4h.1M229.2 278.4v.1M229.2 280h.1M229.3 278.6l.1 .5M229.3 278.6h.1M229.3 279.9h.1M229.4 279.9h.1M229.4 278.7h.6M229.4 279.7h.6M229.4 279.4h.1M229.4 279.5l-.1 .4"/>
<path d="M229.4 279.7h.1M229.4 279.4v.4M229.5 278.5v.1M229.6 278.4l-.1 .4M229.6 280h.1M229.6 278.3h.1M229.6 279.9h.1M229.7 279.7h.1M229.7 278.5h.1M229.7 278.6h.1M229.7 279.7l-.1 .1M229.7 278.3h-.1"/>
<path d="M229.7 278.7h.1M229.7 278.3h.1M229.7 278.9v.2M229.7 279.1l.1 .4M229.7 279v.4M229.7 279.1v.1M229.8 278.3h.1M229.8 278.6h.1M229.8 279.5h.1M229.9 278.3v.2M229.9 278.3h.1M229.9 279.8v.1"/>
<path d="M229.9 279.9v.1M229.9 280h.1M229.9 278.6l.1 .1M229.9 278.6h.1M229.9 276h1.8M229.9 276.5h1.9M230 278.7v.4M230 279.8h.1M230 279.9h.1M230 278.7h.1M230.1 279.6l-.1 .1M230.1 279.3v.3"/>
<path d="M230.1 279.9h.1M230.1 278.7h.1M230.2 279.9h.1M230.2 278.1h-2.2v.7M230.2 278.8h.1M230.2 279.6h.1M230.2 279.7v.1M230.2 278.5v.3M230.2 278.8v.3M230.2 279.4v.2M230.3 278.3h.1M230.3 280h.1"/>
<path d="M230.3 279.9h.1M230.3 279.8h.1M230.4 278.3h.1M230.4 279.4l-.1 .4M230.4 278.5h.1M230.4 278.6h.1M230.4 278.6v.1M230.4 278.7l.1 .3M230.5 277.8v.3M230.5 278.7v.1M230.5 278.5h.1M230.5 279h.1"/>
<path d="M230.5 278.6h.1M230.5 279.6l.1 .2M230.5 279.7l.1 .2M230.6 278.4v.1M230.6 278.4h.1M230.6 279.9v.1M230.6 280h.1M230.7 278.7v.2M230.7 278.7h.1M230.7 279.8h.1M230.7 279.9h.1M230.8 279.8h.1"/>
<path d="M230.8 279.9h.1M230.8 279.1v.3M230.8 279.4v.1M230.8 275.7h.1M230.8 275.9v.1M230.8 278.9v.5M230.9 278.9h.1M230.9 278.6h.1M230.9 276h.1M230.9 275.7v.1M231 278.4l-.1 .2M231 280h.1"/>
<path d="M231 280l-.1 .1M231 278.3h.1M231 277.3l1.1 .2M231 276.1h.1M231 275.7v.1M231 279.8v.8h-.8M231 278.1v.8M231.1 279.4h.1M231.1 278.5h.1M231.1 278.7v.3M231.1 279.4l-.1 .5M231.1 278.3h.1"/>
<path d="M231.1 278.6h.1M231.2 278.6v.2M231.2 278.5h.1M231.2 278.6h.1M231.2 279.6h.1M231.2 279.7l.1 .3M231.3 278.4h.1M231.3 278.4v.1M231.4 278.7v.4M231.4 278.7h.1M231.4 277.1h-.9v.3M231.4 279.9h.1"/>
<path d="M231.4 279.1h.1M231.5 279.3l-.1 .5M231.5 279.9h.1M231.5 279.7v.1M231.6 279.9h.1M231.6 278.6v.2M231.6 278.5h.1M231.6 278.6h.1M231.6 279.8v.1M231.6 278.1v.6M231.6 279.3v.5M231.7 278.4h.1"/>
<path d="M231.7 278.4l-.1 .1M231.7 280h.1M231.8 279.6h.1M231.8 279.6l-.2 .4M231.8 278.5h.1M231.8 278.6h.1M231.8 279.1l.1 .5M231.9 278.3h.1M231.9 279.1h.1M231.9 278.9h.1M231.9 278.7h.1M231.9 278.6h.1"/>
<path d="M231.9 278.9l-.1 .2M231.9 279.3l-.1 .1M231.9 278.5h.1M231.9 279.6h.1M231.9 278.4h.1M232 278.4v.1M232 278.4h.1M232 278.5h.1M232 279.9h.1M232 280l.1 .1M232.1 276.7h-1.1v.3M232.1 278.6v.1"/>
<path d="M232.1 279.9h.1M232.1 279l.1 .4M232.1 279h.1M232.1 279.7v.1M232.1 279.8h.1M232.2 279.3h.1M232.2 279.8h.1M232.2 279.7h.1M232.3 278.9h.1M232.3 278.9l-.1 .4M232.3 278.6h.1M232.3 278.1h2.6"/>
<path d="M232.4 278.5l-.1 .1M232.4 277.1h.8v1.7M232.4 278.3h.1M232.4 279.7h.1M232.4 279.9v.1M232.4 279.9h.1M232.4 279.8h.1M232.4 278.5h.1M232.4 279.6v.1M232.5 278.6h.1M232.5 278.7v.1M232.5 278.5h.1"/>
<path d="M232.5 278.3h.1M232.5 279.1l.1 .5M232.5 279.1h.1M232.5 279v.1M232.5 279.1v.2M232.6 278.7h.1M232.6 278.6h.1M232.6 278.5h.1M232.7 278.4h.1M232.7 279.9v.2M232.7 278.4v.1M232.7 278.5h.1"/>
<path d="M232.7 278.5l.1 .2M232.8 278.7h.1M232.8 280h.1M232.8 276.1h.1M232.8 275.7v.1M232.8 279l.1 .2M232.8 279.7h.1M232.8 279.8h.1M232.9 279.7h.1M232.9 279.9h.1M232.9 279.8h.1M232.9 279.2h.1"/>
<path d="M233 276h.1M233 275.7v.1M233 278.9l-.1 .3M233 278.6h.1M233 278.5h.1M233.1 279.9v.1M233.1 278.4l-.1 .2M233.1 278.3h.1M233.1 279.8h.1M233.2 278.3h.1M233.2 278.5h.1M233.2 279.3l-.1 .4"/>
<path d="M233.2 278.6h.1M233.2 276.7l1.1 .2M233.2 278.7v.1M233.2 278.8l.1 .2M233.2 279.5h.1M233.2 279v.4M233.3 279v.1M233.3 278.6h.1M233.3 278.5h.1M233.3 278.6v.2M233.3 279.7l.2 .2M233.3 279.7h.1"/>
<path d="M233.3 279.6l.1 .4M233.4 278.3v.1M233.4 278.3h.1M233.4 278.5h.1M233.5 278.6v.5M233.5 278.6h.1M233.5 279.9h.1M233.5 278.8v.1M233.5 279.8h.1M233.5 279.1h.1M233.6 276h3.6M233.6 279.4l-.1 .4"/>
<path d="M233.6 279.9h.1M233.6 279.7v.1M233.7 276.5h3.6M233.7 279.9h.1M233.7 278.1v.7M233.7 278.9v.5h1M233.7 279.9l1.1 .1M233.8 278.4h.1M233.8 278.5h.1M233.8 280h.1M233.8 280l-.1 .1M233.8 278.3h.1"/>
<path d="M233.8 279.8h.1M233.8 279.8v.1M233.9 279.3l-.1 .4M233.9 278.5h.1M233.9 278.6h.1M233.9 278.7v.1M233.9 278.3h.1M234 278.5h.1M233.9 278.8v.2M234 279.1h.1M234 278.3h.1M234 278.6h.1"/>
<path d="M234 279.6l.1 .4M234 278.6v.2M234.1 278.3v.1M234.1 278.5h.1M234.2 278.6v.5M234.2 278.6h.1M234.2 277.8v.3M234.2 279.4v.7M234.2 279.8h.1M234.2 279.9h.1M234.2 279.1h.1M234.3 279.9h.1"/>
<path d="M234.3 277.2v.3h-1.1M234.3 279.7l-.1 .1M234.3 279.4v.3M234.3 279.7l.1 .1M234.4 279.9h.1M234.4 278.6v.2M234.4 278.6h.1M234.4 278.7h.1M234.4 278.1v.2M234.4 278.5v.1M234.4 278.5h.1M234.4 278.8h.1"/>
<path d="M234.5 278.4h.1M234.5 278.8h.1M234.5 280h.1M234.5 280l-.1 .1M234.5 278.3h.1M234.5 279.8h.1M234.5 279.8v.1M234.6 278.8h.4M234.6 278.5h.1M234.6 278.6h.1M234.6 279.4v.1M234.6 279.3h.1"/>
<path d="M234.6 278.7v.1M234.6 278.8v.2M234.6 279.3l-.1 .4M234.6 278.3h.1M234.6 278.8h.1M234.6 279v.1M234.7 278.3h.1M234.7 278.6l-.1 .2M234.7 278.6h.1M234.7 278.5h.1M234.7 278.8h.1M234.7 279.6l.1 .4"/>
<path d="M234.8 277.1h-.6v.3M234.8 278.3h.1M234.8 278.8h.1M234.8 280v.1M234.8 278.5h.1M234.9 279.9h.1M234.9 279v.1M234.9 278.8v.2M234.9 279.8h.1M234.9 279.1v.2M235 279.4h.1M235 279.9h.1"/>
<path d="M235 279.3h.1M235 279.3v.1M235 279.7v.1M235.1 278.9h.1M235.1 279l-.1 .3M235.1 279.9h.1M235.1 278.5v.1M235.2 278.5h.1M235.2 280h.1M235.2 280l-.1 .1M235.2 278.4v.1M235.2 278.3h.1"/>
<path d="M235.2 279.8h.1M235.3 278.3h.1M235.3 279.4l-.1 .5M235.3 278.5h.1M235.3 278.6h.1M235.3 278.7v.1M235.3 278.8l.1 .3M235.4 278.3h.1M235.4 279.1h.1M235.4 278.6h.1M235.4 279.6h.1M235.4 278.6v.2"/>
<path d="M235.4 278.8h.1M235.5 278.3v.1M235.5 278.3h.1M235.5 279.7v.4M235.5 278.8h.1M235.5 278.8h.4M235.5 278.4h.1M235.5 278.5h.1M235.6 278.1h2.4M235.6 278.8l.1 .4M235.6 278.8h.1M235.6 279.7v.1"/>
<path d="M235.6 279.9h.1M235.6 277.3l1.1 .2M235.7 279.9h.1M235.7 279.3h.1M235.7 279.2v.1M235.7 279.7v.1M235.7 279.2v.2M235.7 279.7h.1M235.7 278.9v.3M235.7 280h1M235.8 278.4v.2M235.9 280l-.1 .1"/>
<path d="M235.9 278.3h.1M235.9 278.8h.1M236 278.8h.1M236 278.5h.1M236 278.6h.1M236 278.6v.2M236 278.3h.1M236 279.4h.1M236 278.8v.3M236 279.4l-.1 .4M236.1 278.6v.1M236.1 278.6h.1"/>
<path d="M236.1 278.5h.1M236.1 278.7l-.1 .1M236.1 278.3h.1M236.1 278.1v.2M236.1 278.5v.1M236.1 278.7h.1M236.1 279.6h.1M236.1 279.7l.1 .4M236.2 278.4h.1M236.2 278.4v.1M236.3 278.7v.3M236.3 278.7h.1"/>
<path d="M236.3 278.6h.1M236.3 279v.1M236.3 279.9h.1M236.3 279.1h.1M236.4 279.9h.1M236.4 279.3l-.1 .5M236.4 279.7v.1M236.5 278.8h.1M236.5 279.9h.1M236.6 278.5l-.1 .3M236.6 278.4l-.1 .3M236.6 278.3h.1"/>
<path d="M236.6 278.4h.1M236.6 277.1h3.4M236.6 279.9h.1M236.6 279.9v.2M236.6 276.7h-1v.3M236.6 279.6v.1M236.6 279.7v.1M236.6 279.7h.1M236.7 278.5h.1M236.7 278.6h.1M236.7 278.6v.2M236.7 278.3h.1"/>
<path d="M236.7 280h.1M236.7 278.9v.5h-1M236.7 278.1v.4M236.7 278.9v.3M236.8 278.3h.1M236.8 279.9h.1M236.8 278.8h.1M236.8 278.5h.1M236.8 279.1v.1M236.8 279.2v.4M236.8 278.8l-.1 .1M236.8 278.6h.1"/>
<path d="M236.8 279.8l.1 .3M236.9 278.4h.1M236.9 278.4v.1M237 278.7v.4M237 278.7h.1M237 279.8h.1M237 279.9h.1M237.1 279.1h.1M237.1 279.7v.1M237.1 279.3h.1M237.1 279.4l-.1 .4M237.1 279.9h.1"/>
<path d="M237.1 279.7h.1M237.2 279.7l-.2 .1M237.3 278.9v.5M237.3 278.1l-.1 .5M237.3 279.9h.1M237.3 279.9l-.1 .2M237.3 278.3h.1M237.4 278.5h.1M237.4 279.6h.1M237.4 278.6h.1M237.4 278.6v.2M237.4 279.6l-.1 .2"/>
<path d="M237.4 278.8v.3M237.4 279.1l.1 .4M237.4 279.1v.2M237.5 278.6h.1M237.5 278.5h.1M237.5 278.3l-.3 .5M237.5 279.5h.1M237.6 279.8v.1M237.6 279.9v.2M237.6 278.4l.1 .1M237.6 278.4h.1M237.7 278.6v.1"/>
<path d="M237.7 278.7h.1M237.7 278.7v.4M237.7 279.9h.1M237.7 279.7v.1M237.7 276.7l1.1 .2M237.7 279.1h.1M237.8 279.4l-.1 .3M237.8 279.7l.1 .1M237.8 279.7h.1M237.9 278.8h.1M237.9 279.9h.1M237.9 278.6h.1"/>
<path d="M237.9 278.6v.2M237.9 278.5v.1M238 278.4h.1M238 278.3h.1M238 279.9h.1M238 279.9l-.1 .2M238 279.6v.1M238 279.8h.1M238.1 278.3h.1M238.1 277.6v.1M238.1 278v.5M238.1 279.3h.1"/>
<path d="M238.1 278.5h.1M238.1 278.6h.1M238.1 278.6v.2M238.1 279.2h.5M238.1 278.8v.4M238.1 278.8h.1M238.2 278.3h.1M238.2 278.8h.1M238.2 278.5h.1M238.2 279.1v.4M238.2 278.8l-.1 .5M238.2 278.6h.1"/>
<path d="M238.3 278.4v.1M238.3 278.4h.1M238.3 279.9h.1M238.3 279.9v.1M238.4 278.6v.5M238.4 279.8h.1M238.4 279.9h.1M238.5 279.1h.1M238.5 279.7v.1M238.5 279.4l-.1 .4M238.5 279.9h.1M238.5 279.7h.1"/>
<path d="M238.6 278.6v.2M238.6 278.6h.1M238.6 278.5v.1M238.7 278.4h.1M238.7 279.9h.1M238.7 279.9l-.1 .2M238.7 278.3h.1M238.7 279.8h.1M238.8 278.5h.1M238.8 278.6h.1M238.8 278.6v.1M238.8 278.3h-.1"/>
<path d="M238.8 277.2v.3h-1M238.8 279.4h.1M238.8 278.7h.1M238.8 278.8v.2M238.8 278.7v.1M238.8 279.4l-.1 .4M238.8 278.3h.1M238.9 278.3h.1M238.9 278.7v.1M238.9 278.6h.1M238.9 278.5h.1M238.9 279.6l.1 .4"/>
<path d="M239 277.6h.4M239 278.4v.1M239 278.4h.1M239 280h.1M239 278.6l.1 .1M239 278.6h.1M239.1 279.9h.1M239.1 278.7v.5M239.1 278.7h.1M239.1 276h2.1M239.1 279.7h.1M239.1 279.8v.1"/>
<path d="M239.2 279.9h.1M239.2 279.4l-.1 .3M239.2 279.7v.1M239.2 276.5h1.8M239.3 278.8h.1M239.3 279.9h.1M239.3 279.8h.1M239.3 278.5v.3M239.4 278.4h.1M239.4 277.6h.1M239.4 277.8h.1M239.4 279.9h.1"/>
<path d="M239.4 279.9l-.1 .2M239.4 279.6v.2M239.4 279.8h.1M239.5 278h.1M239.5 278.5h.1M239.5 278.6h.1M239.5 278.3h.1M239.5 279v.4M239.5 278.9l.1 .6M239.6 278.3h.1M239.6 278.7h.1M239.6 278.6h.1"/>
<path d="M239.6 277.6l.1 .1M239.6 278.1h.1M239.6 279.8h.1M239.7 279.9v.1M239.7 278.1h.1M239.7 277.9v.6M239.7 278.8v.4h-.5M239.8 278.7h.1M239.8 278.7v.2M239.8 278.6v.1M239.8 279.8h.1M239.8 279.9h.1"/>
<path d="M239.9 279.3v.1M239.9 279.1v.2M239.9 279.7v.1M239.9 279.9h.1M239.9 279.5h.1M239.9 279.3h.1M239.9 279.8h.1M239.9 278.9v.4M240 278.9h.1M240 278.1h3.9M240 278.6h.1M240.1 278.4h.1"/>
<path d="M240.1 278.4v.1M240.1 278.4l.1 .1M240.1 279.7h.1M240.1 279.9h.1M240.1 279.8h.1M240.1 279.9v.1M240.2 278.5h.1M240.2 277.3l1 .2M240.2 279.6h.1M240.2 279.6l-.1 .1M240.2 278.6h.1M240.2 278.7v.1"/>
<path d="M240.2 278.3h.1M240.2 279.1h.1M240.2 278.7h.1M240.2 279.1v.2M240.2 279.1l.1 .5M240.3 278.5l-.1 .1M240.4 278.4h.1M240.4 278.5h.1M240.4 278.4v.3M240.4 279.9v.2M240.5 280h.1M240.5 278.7h.1"/>
<path d="M240.5 279.7v.1M240.5 279.9h.1M240.5 279l.1 .4M240.6 279.9h.1M240.6 279.8h.1M240.6 279.7h.1M240.7 278.9l-.1 .4M240.7 278.6h.1M240.7 278.4v.2M240.8 278.3h.1M240.8 278.4h.1M240.8 279.8h.1"/>
<path d="M240.8 279.8v.1M240.8 275.7h.1M240.8 275.9v.1M240.8 279.7h.1M240.8 279.7v.1M240.9 278.3h.1M240.9 278.5h.1M240.9 278.6h.1M240.9 278.6v.1M240.9 279v.2M240.9 278.7h.1M240.9 278.8h.1"/>
<path d="M240.9 279.2v.2M241 278.9h.1M241 278.5h.1M241 278.6h.1M241 279h.1M241 279.2v.2M241 278.9l-.1 .1M241 278.3h.1M241 279.4v.1M241 275.7h.1M241 276.3h.1M241 276.4h.1"/>
<path d="M241 279.8l.1 .2M241.1 262.3h.1M241.1 261.8h.1M241.1 260.2h.1M241.1 263.6h.1M241.1 261.3h.1M241.1 260.7h.1M241.1 279.9v.1M241.1 278.4l.1 .3M241.1 260.6h.1M241.2 276.7h-1v.3M241.2 279.8h.1"/>
<path d="M241.2 279.9h.1M241.3 279.4v.3M241.3 279.6v.1M241.3 279.8h.1M241.3 279.9h.1M241.3 279.4h.1M241.3 260.6h.1M241.3 279.5h.1M241.3 276h.1M241.3 275.7h.1M241.3 264.7h.1M241.3 260.2h.2"/>
<path d="M241.3 261.8h.2M241.3 261.3h.4M241.3 276h.4M241.4 262.3l.3 .1M241.4 263.4h.1M241.4 263.4l-.1 .1M241.4 261.8h.2M241.4 260.2h.2M241.4 260.7h.5M241.4 264.7h.4M241.5 278.4l-.1 .5M241.5 260.2v2.4"/>
<path d="M241.5 261.2h.3M241.5 263.8h.1M241.5 263.9v.3M241.5 264.3l.1 .1M241.5 278.3h.1M241.5 278.5h.1M241.5 278.6h.1M241.6 263.4h.1M241.6 262.6h.1M241.6 263.8h.1M241.6 279.2l-.1 .5M241.6 278.6v.1"/>
<path d="M241.6 278.8h.1M241.6 264.1h.1M241.6 278.3h.1M241.6 278.5h.1M241.6 279l.1 .5M241.7 278.3h.1M241.7 275.7l-.4 .1M241.7 278.6v.2M241.7 278.5h.1M241.7 260.1v.5M241.7 278.6h.1M241.8 278.3l.1 .9h.6"/>
<path d="M241.8 278.3h.1M241.8 260.2h.5M241.8 261.8h.2M241.8 264.4h.1M241.8 279.8h.1M241.8 279.9v.1M241.8 280h.1M241.8 277.1l1.7 .1M241.9 260.2h.1M241.9 279.7v.1M241.9 279.8h.1M241.9 279.9h.1"/>
<path d="M241.9 262.6h.2M241.9 263.4h.5M241.9 260.1v.3M241.9 278v.5M242 279.5v.1M242 279.5v.2M242 279.9h.1M242 279.4v.1M242 279.7l.1 .1M242 279.7h.1M242 279.6v.1M242 261.3l.3 .2"/>
<path d="M242 262.3l.4 .1M242 260.2l-.1 .4M242.1 278.8h.1M242.1 260.8h.3M242.1 278.4v.4M242.1 275.7h.5M242.1 261.8h.2M242.1 261.2h.3M242.1 260.9h.3M242.2 278.4h.1M242.2 261.8h.1M242.2 260.2h.1"/>
<path d="M242.2 261.6h.1M242.2 261.7h.1M242.2 261.6h.2M242.2 263.1v.6l2.3 .1M242.2 276h.4M242.2 264.7h.6M242.2 279.8v.1M242.2 279.7v.1M242.3 278.3h.1M242.3 262.3h.1M242.3 278.5h.1M242.3 278.6h.1"/>
<path d="M242.3 260.7h.1M242.3 260.2h.1M242.3 260.6v.1M242.3 276.7l1 .2M242.3 260.1v.3M242.3 261.6l-.1 .8M242.3 261.8h.1M242.3 279.4h.1M242.3 261.3h.1M242.3 279.3v.1M242.3 279v.3M242.3 279h.1"/>
<path d="M242.4 278.3h.1M242.4 262.4h.1M242.4 262.6h.2M242.4 278.6h.1M242.4 278.9h.1M242.4 279v.2M242.4 260.8h.1M242.4 279.2v.2M242.4 261.2h.1M242.4 278.6v.2M242.4 278.5h.1M242.4 279.4v.1"/>
<path d="M242.4 279.8l.1 .3M242.5 278.3v.1M242.5 278.3h.1M242.5 260.2v2.4M242.5 264.4v.3M242.5 264.8v.2M242.5 264.4h.1M242.5 278.5h.1M242.6 278.6v.5M242.6 278.6h.1M242.6 275.7h.1M242.6 276h.1"/>
<path d="M242.6 275.9v.1M242.6 279.8h.1M242.6 279.9h.1M242.6 263.8h.1M242.6 263.9l.3 .2M242.6 279.6v.1M242.6 279.7h.1M242.6 260.2h.3M242.7 279.4v.1M242.7 279.7h.1M242.7 279.5l-.1 .1M242.7 260.7h.2"/>
<path d="M242.7 275.7h.1M242.7 279.9h.1M242.7 279.7v.1M242.7 275.7h.2M242.7 262.6h.7M242.7 260.9h.2M242.7 276h.2M242.8 278.8h.1M242.8 279.9h.1M242.9 260.2v2.4M242.9 276.5h.1M242.9 276.4h.1"/>
<path d="M242.9 276.5h2.1M242.9 278.3h.1M242.9 278.4l-.1 .4M242.9 278.6h.1M243 278.3h.1M243 260.9l.2 .8M243 279.2l-.1 .5M243 278.5h.1M243 278.6h.1M243 276h.1M243 263.4l.7 .1M243 275.7v.1"/>
<path d="M243 279.2h.5M243 278.9h.1M243 279l.1 .1M243.1 278.3h.1M243.1 261.1v.1M243.1 261.2v.1M243.1 261.3h.1M243.1 278.6v.2M243.1 278.5h.1M243.1 279.1v.1M243.1 279.2v.2M243.1 261h.1"/>
<path d="M243.1 261.4v.1M243.1 278.6h.1M243.1 279.4v.1M243.2 260.9l-.1 .1M243.2 278.3l.1 .5M243.2 278.3h.1M243.2 279.8v.2M243.2 260.6l-.2 .3M243.2 280h.1M243.3 279.7h.1M243.3 279.8h.1M243.3 260.8h.1"/>
<path d="M243.3 261.6l.3 .1M243.3 277.2v.3M243.3 279.9h.1M243.3 261.3h.1M243.3 261.1v.2M243.4 279.7h-.1M243.4 279.9h.1M243.4 279.4v.2M243.4 263.8h.1M243.4 263.9l-.2 .2M243.4 279.5v.1M243.4 279.7h.1"/>
<path d="M243.5 279.9h.1M243.5 279.8h.1M243.5 278.8v.1M243.5 278.5v1.5M243.5 277.5v.2M243.5 278v.5M243.5 277.6l-1.6 .1M243.6 278.4h.1M243.6 278.4l-.1 .1M243.6 261.7h.1M243.6 260.7l-.3 .1M243.6 264.7h-.4"/>
<path d="M243.6 260.7l.2 .1M243.6 260.7h.1M243.6 278.3h.1M243.6 279.7v.1M243.6 279.8v.1M243.7 261.5h-.3M243.7 264.6l-.2 .1M243.7 260.9h-.2M243.7 263.8v.1M243.7 264.2v.2M243.7 278.5h.1M243.7 279.4h.1"/>
<path d="M243.7 279.4v-.4l.1 .5M243.7 278.6h.1M243.7 264.6h.1M243.7 260.9h.1M243.7 264.5h.1M243.7 278.3h.1M243.7 278.9h.1M243.8 261.7h-.2M243.8 264.4h.1M243.8 278.6l-.1 .2M243.8 278.6h.1M243.8 278.5h.1"/>
<path d="M243.8 261.1v.3M243.8 261.1h.1M243.9 264.6h.1M243.9 260.6l.3 .6M243.9 278.3h.1M243.9 279.9v.1M243.9 279.8v.3M243.9 264.5h.1M243.9 262.6h.6M243.9 278.4v.1M244 278.7v.3M244 278.7h.1"/>
<path d="M244 263.6l.2 .3M244 264.4l-.1 .2M244 264.8l-.1 .2M244 279.9h.1M244 279v.1M244 279.6h.1M244 261.4h.1M244 261.1v.1M244 261h.1M244 279v.2M244 279.3l.1 .3M244 279.7h.1"/>
<path d="M244 279.7v.1M244 279.8h.1M244.1 279.7h.1M244.1 278.8l-.1 .1M244.1 261.2h.1M244.1 261.2l-.1 .3M244.1 264.4h.1M244.1 279.4h.1M244.1 279.4v.2M244.1 279.9h.1M244.1 279.6l-.1 .1M244.1 279.8h.1"/>
<path d="M244.2 278.7h.1M244.2 264.2l-.1 .2M244.2 261.2l-.3 .5M244.2 278.8h.1M244.2 279.9h.1M244.2 279.7h.1M244.2 278.5v.3M244.3 278.7h.1M244.3 279.7l.5 .1M244.3 278.7h.6M244.3 278.5h.1M244.3 278.3h.1"/>
<path d="M244.3 278.4v.1M244.3 278.6h.1M244.4 263.7h.4M244.4 279.2l-.1 .5M244.4 278.5h.1M244.4 278.3h.1M244.4 278.6v.1M244.4 278.8h.1M244.4 279.1l.1 .5M244.5 261.4v1M244.5 260.7h.3M244.5 260.4v.6"/>
<path d="M244.5 263.1v.8M244.5 278.7v.1M244.5 278.7h.1M244.5 264.2v.2M244.5 278.3h.1M244.5 278.6h.1M244.5 278.5h.1M244.6 278.3h.1M244.6 261.7h.1M244.6 278.3l.1 .5M244.6 280h.1M244.6 280v1.5"/>
<path d="M244.7 277.3l1.3 .3M244.7 279.7v.1M244.7 279.9h.1M244.8 279.5h.1M244.8 279.6v.1M244.8 279.9h.1M244.8 279.3v.2M244.8 261.8h.1M244.8 278.9h.1M244.9 277.1h-.3v1.3M245 263.7h1.3M245 275.7h.1"/>
<path d="M245 278.4h.1M245 278.4l-.2 .5M245 275.9l-2.1 .1M245 278.3h.1M245 279.8v.1M245.1 279.4l-.1 .4M245.1 278.5h.1M245.1 278.6h.1M245.1 261.9h.1M245.1 278.3h.1M245.1 278.7h.1M245.1 278.9v.2"/>
<path d="M245.2 278.3h.1M245.2 278.7h.1M245.2 278.6h.1M245.2 278.5h.1M245.2 278.5l-.1 .1M245.2 260.7h.6M245.2 279.6l.1 .5M245.2 262.1l.1 .6M245.3 278.3h.1M245.3 263.2v.7M245.3 264.2v.2M245.3 278.5h.1"/>
<path d="M245.3 278.4v.1M245.4 278.8l.1 .6M245.4 279.9h.1M245.4 278.8h.1M245.4 279.6v.1M245.4 279.7h.1M245.4 279.8h.1M245.5 279.9h.1M245.5 279.4h.1M245.5 279.8h.1M245.6 279.9h.1M245.6 278.9l-.1 .4"/>
<path d="M245.6 279.7h.6M245.6 278.6h.1M245.7 278.7h.5M245.7 278.4h.1M245.7 278.5l-.1 .1M245.7 280h.1M245.7 280l-.1 .1M245.7 278.3h.1M245.7 276.7h-1v.3M245.7 278.1h.1M245.7 278.8v.4h.6M245.7 277.6v.1"/>
<path d="M245.7 278v.5M245.7 278.1h.2M245.8 278.5h.1M245.8 278.6h.1M245.8 278.3h.1M245.8 279v.2M245.8 279.2l-.1 .4M245.8 278.8v.2M245.8 279l.1 .1M245.9 278.7h.1M245.9 278.5h.1M245.9 278.6h.1"/>
<path d="M245.9 279.1h.1M245.9 279.3v.3M245.9 263.7h.1M246 278.3v.2M246 278.3h.1M246 280h.1M246 279.8l.1 .2M246 278.6l.1 .2M246 278.6h.1M246 279.9h.1M246.1 279.1l.1 .3M246.1 279.1h.1"/>
<path d="M246.1 260.7l.2 .4M246.1 280h.1M246.1 278.1h.2M246.2 279.7h.1M246.2 279.7l-.1 .2M246.2 279.8h.1M246.2 278.1v.7M246.2 279.6v.7h-1.6M246.3 278.1h.1M246.3 263.1v.6M246.3 261.5v.9M246.4 263.7h-.1"/>
<path d="M246.5 278h.1M246.5 278h-.1M246.5 260.7h.1M246.6 277.8h.1M246.6 277.6v.1M246.6 277.8l-.1 .1M246.6 260.7v.4M246.6 261.5v.8M246.6 262.1h.2M246.6 261.8h.1M246.6 262.9l-.1 .6M246.7 277.1h3.4"/>
<path d="M246.8 263.8h4.5M246.8 276.7l1.1 .2M247 279.4v.3M247 279.2h.1M247 279.9v.4M247 279.2v.2M247.1 279h.1M247.1 279.3v.1M247.1 278.9h.1M247.1 278.9v.1M247.2 276h4.2M247.2 276.5h4.2"/>
<path d="M247.3 277.6v.1M247.3 278v.4M247.3 278.8v.4h-.5M247.3 278.8h.1M247.3 278.8h-.1M247.3 279.9v.3M247.4 262l-.3 .1M247.4 261.9h.1M247.4 279.4l-.1 .2M247.5 278.8l-.3 .3M247.5 261.9h.1M247.6 261.9h.1"/>
<path d="M247.6 278.6l-.1 .1M247.6 278.6h.1M247.6 278.6h.4M247.6 279.1l-.1 .1M247.7 278.8h.7M247.7 261.9h.1M247.7 279.9h.1M247.7 279.9l-.1 .1M247.7 262h.3M247.8 279.1h.1M247.9 261.7l-.5 .1M247.9 278l-.2 .1"/>
<path d="M247.9 277.2v.3l-1.6 .1M247.9 279.1h.5M248.1 278.1h-2.3M248.3 263.2v.7M248.3 261.9v.7M248.3 264.2v.2M248.3 262h.3M248.4 261.7h.1M248.4 261.8l-.1 .1M248.4 261.7h.5M248.4 261.6h.1M248.5 261.6h-.1"/>
<path d="M248.6 276h.1M248.6 275.7v.1M248.6 262h.1M248.7 261.5h.1M248.7 261.9h.1M248.7 278.1v.2M248.7 278.5l-.3 .1M248.7 261.9h.2M248.9 261.7v.1M248.9 262l.1 .1M248.9 277.8v.1M248.9 277.8h.1"/>
<path d="M248.9 261.3h.1M248.9 278.8h.5M248.9 279.1h.6M249 260.7v.5M249 279.7l-1.1 .1M249 278h.1M249.1 263.8v.1M249.1 264.2v.2M249.2 278h.1M249.2 262.1h.1M249.3 278h-.1M249.3 261.8v.3"/>
<path d="M249.4 278.8h.1M249.4 277.7v.1M249.5 262l-.2 .1M249.5 278.8h.1M249.5 264.2l.1 .2M249.5 277.7v.4h-1.1M249.5 278.7v.5h.6M249.5 277.7h.1M249.5 277.6h.1M249.5 277.6h.5M249.7 278.8h.1M249.7 263.7l-.2 .2"/>
<path d="M249.7 279.1h.1M249.8 277.7l-1.8 .2M249.8 261.7l-.2 .1M249.8 261.6h.9M249.8 260.6h1.6M249.8 279.1h.1M250.1 264.2v.2M250.2 263.8v.1M250.3 278.1h1.2M250.3 278.5l-.6 .3M250.5 278.8l-.7 .3M250.6 263.4l-.7 .1"/>
<path d="M250.6 277.6h.5M250.7 261.5l-.9 .2M251.1 279.4l-1 .1M251.1 279.4h.1M251.1 278.7v.5h-.5M251.1 277.7v.5M251.1 277.7h.1M251.2 263.4l.6 .1M251.2 279.9l-1 .3M251.3 279.9h.1M251.3 279.5l.1 .3M251.6 277.7h1.7v.6"/>
<path d="M251.7 261.6h.9M251.7 261.5h1.1M251.7 263.8v.1M251.7 264.2v.2M251.8 277.9l-.8 .3M251.9 278.2l-.7 .3M251.9 277.1h2.1M252 277.8l.3 .1M252 278.1h.6M252 263.6l.3 .3M252 278.2h.1M252.3 264.2l-.1 .2"/>
<path d="M252.3 278.4h.1M252.3 275.7h.1M252.3 275.9v.1M252.3 260l.2 .1M252.4 278.5v.1M252.4 278.5h.1M252.4 278l.2 .2M252.4 276h.1M252.4 275.7v.1M252.5 278.5h-.1M252.5 263.1v.8M252.5 264.2v.2"/>
<path d="M252.5 260.3v.5M252.5 261.4v1M252.5 278.8h.1M252.6 276.1h.1M252.6 275.7v.1M252.6 278.2h.1M252.6 278.8h.1M252.6 261.6h.1M252.6 278.3h.1M252.6 278.3l.1 .1M252.7 278.1h.1M252.8 278.6v.2"/>
<path d="M252.8 261.7h.1M252.8 261.5h.1M252.8 279.5h.2M252.8 277.7v.2M252.8 278v1M252.8 279.9v1M252.9 261.7h.1M252.9 261.8h.1M252.9 261.6l.2 .1M253 261.9l.2 .2M253.1 261.7h.1M253.1 279.5h.7"/>
<path d="M253.1 261.9l.2 .1M253.3 278.9v.6M253.5 276h2.1M253.7 277.3h.2M253.7 277.3v.4M253.7 278.2l.1 .4M253.7 277.3h.1M253.7 277.1v.1M254.1 278.8l.2 .2M254.1 277.3h.3M254.2 261.9l-.8 .2M254.2 262.4v2"/>
<path d="M254.2 275.7v1.8M254.2 279.4v3.7M254.2 278.6h-.2M254.2 261.9l-.6 .1M254.3 279.5v.2M254.3 279.9l-.5 .1M254.3 278.1l-.2 .3M254.3 277.1l.3 .1M254.3 276.1h.1M254.3 275.7v.1M254.4 279.5h.5v.5M254.4 277.3h.1"/>
<path d="M254.5 260.6v.2M254.5 261.1v.2M254.5 276h.1M254.5 275.7v.1M254.5 278.6h.1M254.5 277.4l.1 .1M254.5 261.3h-1.6M254.5 260.6h-1.6M254.5 260.6h.1M254.5 261.3h.1M254.5 261v.3M254.6 278.1l.3 .3"/>
<path d="M254.6 277.4v.2M254.6 277.9l.1 2M254.9 278.7l-.2 .3M255.3 261.6h.1M255.4 261.5h.1M255.4 261.6h.1M255.4 261.6l-.6 .1 .5-.1M255.5 261.2h.1M255.6 278.3h.1M255.6 279.1h.1M255.6 261.2h.1M255.6 261.3h.1"/>
<path d="M255.6 278.3v.3M255.6 278.9v.2M255.6 261.5h.1M255.6 261.4h.1M255.6 261.5h-.1M255.6 276.4l-2 .1M255.9 263.1v.7h-2.2M256 263.8h.1M256.1 263.9h.1M316.6 261.7v.1M316.6 261.7h.3M316.6 260.6v1.1"/>
<path d="M316.6 279.1v.9M316.6 279.1h.3M316.6 279.1h.1M316.8 261.9l.1 .1M316.9 278.8h.1M316.9 262h.1M316.9 260.4v1.6M316.9 278.8l-.1 .1M316.9 278.8v1.6M317.2 262h.2M317.2 278.8h.2M317.2 261.7h.4"/>
<path d="M317.3 279.1h.3M317.4 260.5v1.5M317.4 278.8v.2M317.4 278.8v1.6M317.4 261.9v.1M317.5 279.1h.1M317.6 261.7h.1M317.6 265.2v.6M317.6 266.5v.6M317.6 260.1v1.6M317.6 279.1v1.6M317.6 267.2h.1"/>
<path d="M317.7 272h.1M317.7 272h.2M317.7 268.8h.1M317.7 267.2h.1M317.7 266.8h.4M317.7 267.1h.2M317.7 274h.4M317.7 267.2h.2M317.8 268.9h.1M317.8 272h.1M317.9 272h.1M317.9 268.9h.1"/>
<path d="M317.9 271.9h.1M318 268.8h.1M318 272h.1M318 267.2h.1M318 265.2v1.7M318 268.6v3.5M318 273.9v1.7M318.1 268.9h.1M318.1 272h.1M318.1 267.1h.2M318.1 271.9h.2M318.1 268.9h.3"/>
<path d="M318.2 268.9h.1M318.3 265.2v1.7M318.3 268.7v3.5M318.3 274v1.6M318.3 271.9h.1M318.4 271.9h.1M318.4 268.9h.2M318.5 266.8h2.4M318.5 271.9h.1M318.5 271.9h-.1M318.5 274h2.4M318.6 268.9h.1"/>
<path d="M318.6 268.9h.2M318.8 268.9h.1M318.8 271.9h.1M318.8 268.9l1.8 .2M318.9 271.9h.1M318.9 268.9l1.9 .2M319.3 266.4v1.7M319.3 269.9v3.5M319.3 275.6h1M319.3 265.2h1M320.4 267.6v.4M320.4 272.8v.5"/>
<path d="M320.5 268.3l.3 .3M320.5 273.5l.3 .4M320.6 267.6v.5M320.6 272.8v.5M320.7 268.3l.3 .3M320.7 271.7l-1.9 .2M320.7 273.5l.3 .4M320.8 272.2l-.3 .3M320.8 267l-.3 .3M321 268.7l.5 .2M321 267l-.3 .3M321 272.2l-.3 .3"/>
<path d="M321 274h.5M321.2 268.8h.2M321.4 268.8l.3 .1M321.4 275.6h2.7M321.4 272l-.2 .1M321.5 266.8l-.5 .1M321.5 265.2h2.6M321.5 272l-.5 .1M321.7 272h-.3M321.9 268.9h.3M322.1 268.9h.5h-.3M322.2 271.9h.1"/>
<path d="M322.2 268.9h.1M322.2 271.9l-.3 .1M322.3 266.4v.7M322.3 267.8v.6M322.3 272.4v.7M322.3 273.8v.6M322.4 268.9l.9 .2M322.5 265.2v.4M322.5 266.1v.3M322.5 274.4v.4M322.5 275.3v.3M322.5 269.3l1.9 .1"/>
<path d="M322.6 271.9h-.3M322.7 268.9l1.1 .2M323 266.8h2.5M323.1 274h2.4M323.3 271.7l-1.2 .3M323.8 271.7l-1.1 .2M324 271.6h.1M324.1 269.2h.1M324.3 269.2l.9 .2M324.4 269.4l.2 .1M324.4 269.4l.3 .1M324.6 277.8v1.9"/>
<path d="M324.6 273.9v2.8M324.6 278.8h.9M324.6 261.2v1.8M324.6 264.1v2.8M324.6 268.6v3.5M324.6 262h.9M324.6 271.4l-2 .2M324.8 269.3l.9 .1M324.9 269.6l.3 .3M324.9 269.6l.3 .4M325.1 274.3v.5M325.1 275.3v.3"/>
<path d="M325.1 266v.5M325.1 265.2v.4M325.1 266.7v2.5M325.1 271.7v2.5M325.2 270.9l-.3 .3M325.2 271.4l-.9 .2M325.2 271.4h.1M325.2 265.2v.6M325.2 266.3v2.9M325.2 271.7v2.9M325.2 275.1v.5M325.2 270.2l.1 .4"/>
<path d="M325.2 269.5h.1M325.3 269.5h.1M325.3 270.2v.5M325.3 271.3h.1M325.3 271.3l-.1 .1M325.4 265.2v1.7M325.4 268.7v3.5M325.4 274v1.6M325.4 269.7h.1M325.5 269.8v.2M325.5 270.8l-.1 .3M325.5 270h.1"/>
<path d="M325.5 270.3v.3M325.6 266.8v2.4M325.6 271.6v2.4M325.7 271.4l-.9 .2M325.7 269.4h.1M325.7 271.4h.1M325.7 269.5h.1M325.8 271.3h.1M325.8 269.5h.1M325.8 275.6h1.6M325.8 265.2h1.6M325.9 271.6l-.1 2.4h.4v-2.3"/>
<path d="M325.9 269.2v-2.4h.3v2.4M325.9 271.1h.1M325.9 269.7l.1 .3M325.9 271h.1M326 270.8v.1M326 270.9l-.1 .1M326 270.3v.3M326 266.8v2.4M326 271.6v2.4M326.5 278.8h.9M326.6 262h.8M326.8 265.2v.4"/>
<path d="M326.8 266.1v.3M326.8 274.4v.4M326.8 275.3v.3M327.3 266.8v2.4M327.3 271.6v2.4M327.4 260.5v.4M327.4 264.8v.3M327.4 265.6v.3M327.4 269.8v.4M327.4 270.7v.3M327.4 274.9v.4M327.4 275.7v.4"/>
<path d="M327.4 280v.3M327.8 264.7l1 .1M327.8 263.4h1M327.8 276.1h1M327.8 279.6h1M327.8 276.5h1M327.8 278.4h1M327.8 280h1M327.8 260.9h1M327.8 261.3h1M327.8 264.4h1M327.8 260.6h1"/>
<path d="M327.8 261.8h1M327.8 274.9h1M327.8 269.8h1M327.8 271h1M327.8 265.9h1M327.8 266.4h1M327.8 271.4h1M327.8 266.3h1M327.8 274.5h1M327.8 269.4h1M327.8 264.3h1M329.1 263.8v.1"/>
<path d="M329.1 264.2v.2M329.1 263.8h.1M329.1 264.4h.1M329.2 263.8h.3M329.3 263.8h.1M329.3 264.4h.3M329.3 264.4h.1M329.7 261.5h.1M329.7 261.3v.2M329.7 260.8v.3M329.8 263.8h.6M329.8 261.6l.1 .1"/>
<path d="M329.9 264.7l1.8 .1v.2M329.9 263.4h1.1M329.9 276.1h5.5M329.9 276.5h1.1M329.9 261.7h.3M329.9 261.8h1.2M329.9 271l2 .1v.6M329.9 265.9h1.7M329.9 266.4h1.1M329.9 271.4h1.1M329.9 266.3h1.1M329.9 260.7v.3"/>
<path d="M329.9 260.7h.3M329.9 260.7h.1M329.9 279.6h1.1M329.9 278.4h1.1M329.9 280h1.8M329.9 260.6h1.1v.3M329.9 274.9h1.8M329.9 274.5h1.1M329.9 269.4h1.1M329.9 264.3h1.1M330.3 264.4h-.4h1.2M330.6 261.7l1.1 .1"/>
<path d="M330.7 264.4h.1M330.8 264.2l-.3 .2M330.9 260.2h.1M330.9 262.2l.2 .1M330.9 263.8v.1M330.9 264.2v.2M330.9 260.6v.1M330.9 261.3v.2M330.9 261.7v.3M330.9 260.7h.1M331 264.2h-.2M331 261.3v.2"/>
<path d="M331 261.7v.3M331 262.2v.1M331 272.7h.1M331 273.1h.1M331 267.7h.1M331 267.1h.1M331 273.7h.1M331 274.2h.1M331 266.7h.1M331 266.1h.1M331 274.7h.1M331 275.1h.1"/>
<path d="M331 265.7h.1M331 265.1h.1M331 275.7h.1M331 276.1h.1M331 264.7h.1M331 270.1h.1M331 264.2h.1M331 270.7h.1M331 271.1h.1M331 269.7h.1M331 276.7h.1M331 277.2h.1"/>
<path d="M331 263.7h.1M331 269.2h.1M331 274.6h.1M331 265.5h.1M331 266.4h.1M331 263.1h.1M331 271.7h.1M331 262.6h.2M331 272.2h.1M331 268.7h.1M331 275.3h.1M331 278.1h.1"/>
<path d="M331 277.7h.1M331 275.4l.1 .1M331 265.3v.1M331 274.4v.1M331 277.1l1.4 .2M331 278.7h.3M331 260.7h.1M331 268.1h.1M331 268.1h.9v.5M331 269.7h.7M331 269.2h.5M331 268.4h.8"/>
<path d="M331 272.4h.8M331 271.6h.5M331 261.2h.1M331 276.6v.1M331 264.1h.1M331 262.7h.1M331 275.7h.2M331 274.1h.9v.6M331 265h.1M331 270.1h.3M331 269.9h.3M331 275.4l.2 .3"/>
<path d="M331 276.8h.1M331 275.8v.1M331 268l.1 .1M331.1 269.3h.1M331.1 260.1v.6M331.1 273.2v1M331.1 270.6l.1 .1M331.1 265.2h.1M331.1 260.8h.3M331.1 261.2v.8M331.1 263.4h.1M331.1 261.4h.1"/>
<path d="M331.1 270.7h.4M331.1 263.4h.4M331.1 272.1l.6 .1M331.1 269.1l.6 .1M331.1 261.4h.6M331.1 262.8v.6M331.1 261.1l.4 .1M331.1 261.6l.1 .1M331.1 260.5h.1M331.1 263.8h.1M331.1 263.9v.2M331.1 261v.5"/>
<path d="M331.1 260.1v.5M331.1 261.2h.1M331.1 279.9h.1M331.1 279.3h.1M331.1 272h.1M331.1 271.4h.1M331.1 269.4h.1M331.1 268.8h.4M331.1 279.3h.4M331.1 273.4h.2M331.1 261.2h.4M331.1 260.5h.4l-.2 .2"/>
<path d="M331.1 272h.4M331.1 279.9h.4l.1 1.4M331.1 271.4h.4M331.1 269.4h.4M331.1 269.4v.7M331.1 270.8v.6M331.1 279.9v.3M331.1 261.7h.1M331.1 273.4h.1M331.1 275.4h.1M331.1 276h.1M331.1 260.1h.1"/>
<path d="M331.1 274.8v.9M331.1 276.3v1.4M331.1 277l-.1 .1M331.1 266.6l.1 .1M331.1 266.6h.1M331.1 274.7v.7M331.1 261.8h.1M331.1 262.3l.1 .3M331.1 278.2l-.1 .1M331.1 262.3h.1M331.1 260.2h.1M331.1 270.8l.1 .9 .4 .1"/>
<path d="M331.1 276.9l.1 .1M331.1 260.6v.9M331.1 278.2v.9M331.1 261.3h-1.2v.4M331.1 268.1v.5M331.1 269.2v.8M331.1 275.7l.2 .1M331.1 272.2l.2 .5M331.1 274.1v.6M331.1 260.7h.1M331.1 261.7v.3M331.1 268.3l.2 .1"/>
<path d="M331.1 268.3h.1M331.2 267.7h.5M331.2 273.1h.5M331.2 273.7h.1M331.2 266.1h.1M331.2 274.7h.1M331.2 265.7h.1M331.2 275.1h.1M331.2 265.1h.1M331.2 275.7h.1M331.2 264.7h.1M331.2 276.1h.1"/>
<path d="M331.2 270.7h.1M331.2 264.2h.1M331.2 269.7h.1M331.2 271.1h.1M331.2 276.7h.1M331.2 263.7h.1M331.2 263.1h.1M331.2 268.7h.1M331.2 277.7h.1M331.2 272.2l-.1 .6h.4M331.2 270.7h.5M331.2 269.2h-.1"/>
<path d="M331.2 262.7h.1M331.2 265.1l-.1 .1M331.2 261.7h.3M331.2 260.2h-.1M331.2 275.8l.1 .1M331.2 261.3h.1M331.2 274.7l.9 .1M331.2 274.7l-.1 .1M331.2 277l.1 .1M331.3 273.1h.1M331.3 267.1h.1M331.3 274.2h.1"/>
<path d="M331.3 275.1h.1M331.3 265.1h.1M331.3 263v.3M331.3 276.1h.1M331.3 270.1h.1M331.3 264.2h.1M331.3 271.1h.1M331.3 269.2h.1M331.3 274.6h.1M331.3 263.1h.1M331.3 280h.1M331.3 274.7h.1"/>
<path d="M331.3 266.2h.1M331.3 272.2h.1M331.3 263.6l-.3 .3M331.3 260.7v.1M331.3 262.1v.7l-.1-.2M331.3 264.5v.3M331.3 276.6v.3M331.3 277.5v.3M331.3 279.4v.6M331.3 278.1h.1M331.3 277v.3h.8M331.3 261.8h.1"/>
<path d="M331.3 265l-.2 .2M331.3 266v.3M331.3 274.7v.1M331.3 275v.3M331.3 276.1v.2M331.3 278v.7M331.3 268.1h.1M331.3 273.6v.8M331.3 260.2h.1M331.3 268.2v.8M331.3 271.8v.9M331.3 267.9h.2"/>
<path d="M331.3 280h.3M331.3 274.7h.2M331.3 274.3l.2 .1M331.3 270.9v.9M331.3 269v1M331.3 273.3h.2M331.3 272.9l.2 .1M331.3 271.8l.3 .1M331.3 276.8h.1M331.3 262.3h.1M331.3 260.7h-.6M331.3 274.1l-.2 .2"/>
<path d="M331.3 260.1l-.1 .2M331.3 277.1h.1M331.3 272.4l-.2 .2M331.3 265.5v.4M331.3 266.3h.1M331.3 262.6l.4 .2M331.3 274.5v.3M331.3 275.8h.4M331.3 264.9h.1M331.3 264.6v.3M331.3 275.8v.1M331.3 275.8h.1"/>
<path d="M331.3 275.6h.1M331.3 275.9v.3M331.3 276.6v.2M331.3 275.4h.1M331.3 261.3h.1M331.3 260.7h.1M331.3 274.4v.1M331.3 268h.1M331.3 267.9v.1M331.3 272.8v.2M331.4 272.7h.1M331.4 267.7h.1"/>
<path d="M331.4 273.1h.1M331.4 267.1h.1M331.4 273.7h.1M331.4 266.7h.1M331.4 274.2h.1M331.4 266.1h.1M331.4 274.7h.1M331.4 265.7h.1M331.4 275.1h.1M331.4 265.1h.1M331.4 275.7h.1M331.4 264.7h.1"/>
<path d="M331.4 276.1h.1M331.4 270.1h.1M331.4 270.7h.1M331.4 264.2h.1M331.4 269.7h.1M331.4 276.7h.1M331.4 271.1h.1M331.4 263.7h.1M331.4 277.2h.1M331.4 269.2h.1M331.4 266.4h.1M331.4 271.7h.1"/>
<path d="M331.4 263.1h.1M331.4 268.7h.1M331.4 274.4h.1M331.4 277.7h.1M331.4 272.2h.1M331.4 278.1h.1M331.4 263.8h.1M331.4 262.7h.1M331.4 268.1h.1M331.4 263.9l-.1 .4M331.4 275.8h.1M331.4 275.4l.1 .1"/>
<path d="M331.4 264.1h1M331.4 268.1v.1M331.4 266.7h.3M331.4 266.1h.3M331.4 265.7h.3M331.4 275.1h.3M331.4 265.1h.5M331.4 270.1h.4M331.4 276.1h.3M331.4 276.7h.3M331.4 264.2h.3M331.4 263.7h.3"/>
<path d="M331.4 271.1h.3M331.4 271.7h.3M331.4 265h1.1v.3M331.4 268.7h.3M331.4 277.7h.3M331.4 263.1l.3 .3M331.4 266.6v.5M331.4 273.7l-.1 .5M331.4 265h.1M331.4 262.7h.3M331.4 274.9v.5M331.4 275.6h.1"/>
<path d="M331.4 262.4h.1M331.4 261.2h.1M331.4 261.1v1.3M331.4 262.6h.1M331.4 276.8l.1 .1M331.4 276.8h.1M331.5 266.8h.1M331.5 266.5l-.2 .8M331.5 274h.1M331.5 267.5l-.2 .1M331.5 265.4l-.2 .9M331.5 266.1l-.2 .1"/>
<path d="M331.5 277.2h.1M331.5 268.5h.3M331.5 272.3h.3M331.5 266.5h.1M331.5 260.7h.2M331.5 274.3h.1M331.5 265.1h.1M331.5 268.2h.1M331.5 275.7h.1M331.5 272.6h.1M331.5 275.9v.1M331.5 273.6l-.4 .1"/>
<path d="M331.5 264h-.2v.4h1.1M331.5 260.1l-.6 .3M331.5 268.2h.3M331.5 272.6h.3M331.6 277.2h.1M331.6 269.9h.2M331.6 263.9h.2M331.6 276.9h.1M331.6 260.9h-.3v.6M331.6 278.6h.1M331.6 277.1v.3M331.6 277.8v1.2"/>
<path d="M331.6 263.4h.1M331.6 263.4l.8 .6M331.6 277.2h.8M331.6 275.9v.1M331.6 269.1h-.3M331.6 268.9l-.3 .1M331.6 276.9h.9M331.6 279.2h.2M331.6 277.6h.1M331.7 272.7h-.7M331.7 267.1h-.7M331.7 273.7h-.6"/>
<path d="M331.7 260.1h.1M331.7 263.8h.1M331.7 264.5v.1M331.7 261.8h.1M331.7 261.9v.1M331.7 273.4h.4M331.7 260.7h.1M331.7 260.6h.1M331.7 269.8h-1.8M331.7 263.6v.8h.9M331.7 263.3h1M331.7 262l.1 .3"/>
<path d="M331.7 266.5h.2M331.7 263.7h.1M331.7 260.8h.1M331.7 274.3l.4 .1M331.7 260.7v1.3M331.7 274.8h.3M331.7 264.6h.1M331.7 262.1l.1 .5M331.8 260.8h.1M331.8 264.6l.1 .1M331.8 262.9l.3 .4M331.8 266.8h.1"/>
<path d="M331.8 260.7v.1M331.8 265.4h.1M331.8 274h.1M331.8 263.6h.1M331.8 275.7h.1M331.8 275.4h.2M331.8 260.5h.1M331.8 264h.3M331.8 277.1v.6M331.8 278.2v.5M331.8 275.4h.1M331.8 270h.1"/>
<path d="M331.8 263.8h.1M331.8 270.1h.1M331.8 274.1v.6h-.7M331.8 263.9v2M331.8 268v2M331.8 271.1v.6M331.8 272.2v.5M331.8 275.2v.5M331.9 278.6h.1M331.9 274.3h-.1M331.9 278.3h-.8M331.9 260.5h.1"/>
<path d="M331.9 277.6h.1M331.9 260.2v2.4M331.9 266.9h.1M331.9 273.9v.1M331.9 278.2v.5h-.3M331.9 277.1v.6M331.9 269.2v.5h-.3M331.9 275.3v.1M331.9 275.2v.5h-.5M331.9 265.5h.1M331.9 272.2v.5h-.3M331.9 279.2h.1"/>
<path d="M332 266.3v.1M332 266.4h-.3M332 267.4h.1M332 267.5v3.4M332 267.8h.1M332 267h.1M332 273.8h.1M332 262.8h.1M332 267.8h-.3M332 267.4l-.3 .1M332 266l-.3 .1M332 260.6h.1"/>
<path d="M332 260.7v.1M332 274.7v.2M332 275.2h.1M332 269.2h.4M332 271.6h.4M332 266.4h.1M332 265.6h.1M332 266h.1M332 265.9l.3 .2M332 265.6v.2M332 262.6h.2M332 276h.1"/>
<path d="M332 261.5l.1 .7M332 262.8l.1 .2M332 277.3h.1M332 260.7l.1 .5h.4M332 260.8h.1M332 277.1v.1M332 277.7h.1M332 279h.1M332 279.8v1.3v-.5l-.9-.1v-.7M332 279.3v.7M332 280h.1M332 278.1h.1"/>
<path d="M332 263.8h.1M332 277.6v.2M332 279.5h.1M332 277.5h.1M332 277.6h.1M332 278v.9M332.1 267.7h.3M332.1 273.1h.3M332.1 273.7h.3M332.1 267.1h.3M332.1 266.7h.3M332.1 274.2h.3"/>
<path d="M332.1 265.7h.3M332.1 270.1h.3M332.1 276.1h.3M332.1 269.7h.3M332.1 276.7h.3M332.1 264.2h.3M332.1 263.7h.3M332.1 271.1h.3M332.1 271.7h.3M332.1 269.2h.6M332.1 268.7h.3M332.1 266.6l.1 .2"/>
<path d="M332.1 277.7h.3M332.1 263.1h.3M332.1 273h-.4M332.1 272.2h.6M332.1 262.7h.3M332.1 273.6h.4M332.1 268.1h.3M332.1 268.8h.5l-.1 .2M332.1 261.7h.4M332.1 268.2h.3M332.1 265.4l.2 .7M332.1 263.4h.5"/>
<path d="M332.1 261.4h.5M332.1 263.3l-.3 .3M332.1 279.9h.5M332.1 272.8h.5M332.1 271.4l.5 .2M332.1 269.4h.5M332.1 264h.1M332.1 264.1v1.9M332.1 267.8v1.9M332.1 269.9l-.1 .1M332.1 263.8v.1M332.1 271.9l.4 .1"/>
<path d="M332.1 263h.1M332.1 271.8h.5M332.1 269h.4M332.1 263.3l.3 .3M332.1 268.5h.3M332.1 272.3h.3M332.1 263l.5 .4M332.1 261.1v1.5M332.1 263.1l.6 .4M332.2 278h.1M332.2 267.4h.1M332.2 267.8h.1"/>
<path d="M332.2 273.4h.2M332.2 264.8l.2 .2M332.2 266.4h.1M332.2 280h.8M332.2 279.5h.1M332.2 260.4h-.1M332.2 266.8h.1M332.2 274.1l-.1 .1M332.2 275.8h.1M332.2 275.5h.1M332.2 265.4h.1M332.2 275.5l-.1 .1"/>
<path d="M332.2 279l1 .1M332.3 262.7l.4 .4M332.3 262.7h.1M332.3 266.9v.1M332.3 267.9h.2M332.3 267.5h.2M332.3 274.7h-.2M332.3 264.4v.2M332.3 264h.1M332.3 275.3h.1M332.3 267.5v3.4M332.3 272.7v1.9"/>
<path d="M332.3 275.1l-.1 .3M332.3 276h.1M332.3 266.3v.1M332.3 275.7v.1M332.3 266.5h.2M332.3 260.3h.1M332.3 260.9h.7M332.3 271h.7M332.3 278v.7M332.3 264.3v1.8M332.3 267.8v1.7M332.3 269.7l.7 .1"/>
<path d="M332.3 277.7v.1M332.3 275.4h.3M332.3 277.2h.1M332.3 276.9v.1M332.3 279.3l.1 .1M332.4 264.2h.1M332.4 274.8l-.2 .2M332.4 274.9h.6M332.4 264l.1 .1M332.4 279l-.1 1M332.4 279.5h.1M332.4 279.4h.1"/>
<path d="M332.4 276v.1M332.4 276.9v.1M332.4 262l.1 .3M332.4 263.8l-1.6 .1M332.4 262h1.2M332.4 279.6v.1M332.4 272.3h.1M332.4 279.1h.1M332.4 272.7h-.3l-.1 1.9M332.4 275.1l-.4 .1M332.4 265.1h-.3l.1 .3M332.4 264.7h-.3"/>
<path d="M332.4 270.7h-.3h.6M332.4 265.1l.2 .1M332.4 265.1h.1M332.4 260.7h.1M332.4 263.6l.1 .1M332.4 279.7l.1 .1M332.4 272.6h-.3M332.4 279.5h.2M332.4 279.5v.2M332.4 279.9v.1M332.5 273h-.3M332.5 262.5l1.2 .1"/>
<path d="M332.5 273.3h-.2M332.5 260.7h.1M332.5 274.4h-.3M332.5 273.4h.1M332.5 268.6h.1M332.5 272.2h.1M332.5 264.4h.1M332.5 260.8h-.9M332.5 260.4l-.4 .1h.5M332.5 260.4h.1M332.5 260.8h.1M332.5 269.2h.1"/>
<path d="M332.5 260h.1M332.5 268.7h.1M332.5 276.6l-.1 .3M332.5 263.6v.3M332.5 264v.3M332.5 265.6v.3M332.5 266v.3M332.5 266.6v.2M332.5 267v.3M332.5 267.5v.3M332.5 268.1v.2M332.5 268.6v.3"/>
<path d="M332.5 273v1.3M332.5 274.6l.1 .8M332.5 275.5v.3M332.5 276.1v.2M332.5 277v.3M332.5 277.5v.3M332.5 278v.8M332.5 279.5v1M332.5 272h.1M332.5 260.2h.1M332.5 269l.1 1.1M332.5 268.8l-.4 .1"/>
<path d="M332.5 272v.8M332.5 279.2h.1M332.6 275.7l-.2 .1M332.6 275.6h.1M332.6 275.6l-.4 .2M332.6 269.4h.1M332.6 269.3h.1M332.6 272.1v.6M332.6 269.1v.1M332.6 270.6l-.1 .1M332.6 270.8l-.1 1.1M332.6 260.1l-.5 .1"/>
<path d="M332.6 260.1l-.2 .1M332.6 279.3h.1M332.6 264.6h.1M332.6 264.6l-.1 .2M332.6 272.7h.1M332.6 267.1l.3 .1-.1 .3M332.6 266.7h.1M332.6 274.2h.1M332.6 274.7h.9v.8M332.6 266.1l.4 .3M332.6 265.7h.1M332.6 275.1h.1"/>
<path d="M332.6 265.1h.1M332.6 270.1h.1M332.6 276.1h.1M332.6 269.7h.1M332.6 271.1h.1M332.6 277.2h.9M332.6 271.7h.1M332.6 279.3l.1 .3M332.6 279v.3M332.6 268.7h.1M332.6 263.4h.1M332.6 263.1h.1"/>
<path d="M332.6 262.7h.1M332.6 268.1l.1 4.7M332.6 279.9l.2 .1M332.6 268.3l.2 .2M332.6 278.6l-.2 .2M332.6 265.3v.3M332.6 265.9v.1M332.6 279.1h.1M332.6 279.1v.3M332.6 270.3v.4h-.5M332.6 278.3h.8M332.6 263.9l-.1 .1"/>
<path d="M332.6 263.4l.1 .3M332.6 274.8v.2M332.6 275.3l.1 .8M332.6 271.9l-.5 .1M332.6 260.3v.6M332.6 269.3v.5M332.6 279.3v.2M332.6 279.8v.1M332.6 279.3l-.8 .1M332.6 261.2h-.5M332.6 261.3v.4h-.5M332.7 260.4h.1"/>
<path d="M332.7 260.8h.1M332.7 279.4v.1M332.7 278.9v.1M332.7 279l-.1 .1M332.7 268.4l.8 .2M332.7 263.5h.1M332.7 264.7h.2M332.7 273.7h-.6M332.7 275.7h-.9M332.7 263.1l.1 .1M332.7 263.7h-1.1M332.7 267v.3"/>
<path d="M332.7 273v.3M332.7 274v.3h.3M332.7 266.6v.2M332.7 267.5l.3 .5M332.7 273.6v.3M332.7 260.3l.4 .3M332.7 262v4.3M332.7 272h.1M332.7 269h.1M332.7 268.8l.5 .1M332.7 279.5h.7M332.8 262.8l-.3 .2"/>
<path d="M332.8 266.5h.2M332.8 278.9l-.1 1.3M332.8 263.8h.1M332.8 272.4l-.2 .1M332.8 268.6h.1M332.8 268.7h.1M332.8 269.6h.1M332.8 268.6v.3M332.8 275.7h.5M332.8 276.9l.3 .1M332.8 277.7l.1 1.2M332.8 268.2h.1"/>
<path d="M332.8 267.9v.3M332.8 272h.1M332.8 272v.2M332.8 269v1M332.8 270.9v1h.4M332.8 269l.4 .1M332.8 279.1v.4M332.9 260.7l-.2 .7M332.9 261.9v.7M332.9 262.6h.1M332.9 262.7h.1M332.9 260.7h.1"/>
<path d="M332.9 279.7h.1M332.9 278.8h.5M332.9 277.8h.1M332.9 278.1h.1M332.9 260.5h.1M332.9 260.6v.6M332.9 260.6h.1M332.9 277.8h.3M332.9 279.4h.5M332.9 278.5l.6 .1M332.9 275.7l.2 .1M332.9 278.7h.1"/>
<path d="M332.9 260.4h.1M332.9 278.7l.1 .1M332.9 278.5l.1 .1M333 269.6h.1M333 265.9l-.8 .1M333 279.7h.2M333 268.2h.1M333 277.7h-.8M333 267.7h-.4M333 274.6h-.3v4.2M333 272.9h-.2M333 268.6h.1"/>
<path d="M333 260.7l-.7 .1M333 261l.1 .4M333 278.9v.2h.5M333 260.4v.5h-.3M333 273.2l-.4-.1v.6M333 279.7h.1M333 266.5h.1M333 274.6h.1M333 266.5v2.6M333 271.7v2.7M333 267.2h.1M333 278.8h.1"/>
<path d="M333 278.3l-.2 .1M333 278.6h.1M333.1 261.4h.1M333.1 278.6l-.2 .1h.4M333.1 264.3l.6 .3M333.1 263.9h.9M333.1 260.3h.1M333.1 277.3l1.1 .1M333.1 280h-.4M333.2 279.2h-.3v.5M333.2 261.7h.1M333.2 263.7h.4h-.3"/>
<path d="M333.2 278.7h.1M333.2 279.7h.1M333.2 260.3h.1M333.2 263.8h.1M333.2 263.9v.2M333.2 260.2h.1M333.2 263.4h.8M333.2 261.8h.1M333.2 260h.1M333.2 260.1v.1M333.2 278.7l.6 .1M333.2 278.7h-.3"/>
<path d="M333.2 271.8h-.5M333.2 264.6l-.8 .2M333.3 276l.2 .1M333.3 277.2l.2 .1M333.3 261.8l.1 .1M333.3 277.2h.9M333.3 278.7l.2 .1M333.3 276.9h.8M333.4 274.7l.1 .1M333.4 274.7l-.8 .1M333.4 278.3l.1 .8M333.4 264.6h.1"/>
<path d="M333.4 279.7h.1M333.4 279.7h-.1M333.4 278.3h.1M333.4 278.3h-.2M333.4 278.7h.4M333.5 276.3l-.1 .8M333.5 274.8v.7M333.5 262h.1M333.5 278.2v.1M333.5 279.8l-.1 .8M333.5 269.2v.8M333.5 270.8v.8"/>
<path d="M333.5 278.8h.1M333.5 275.7h.8M333.5 264.5l-.1 .1M333.5 279.2h.3M333.5 278.3l-.5 .3M333.5 263.8h1.1M333.5 261.7l-.3 .1M333.5 279.7h-.3M333.5 264.4h.1M333.5 276.3v.9M333.5 278.3v.8l.9-.1M333.5 260.7l.5 .1"/>
<path d="M333.5 272.2v.2h-.8M333.5 271.6v.3M333.5 264.7h.5M333.5 260.6h.1M333.5 268.9v.3M333.5 260.9l.5 .1M333.5 277.8h.3M333.5 264.1h1.1M333.6 279.8h-.6M333.6 277.2h.1M333.6 276.9v.1M333.6 261.5h.1"/>
<path d="M333.6 279.9h.1M333.6 261.3h.1M333.6 261.4l-1.2 .2M333.6 261v.3M333.6 276h.1M333.6 275.7v.1M333.6 280h.1M333.6 261.9l.2 .1M333.7 279v.4M333.7 279.4v.1M333.7 279h.1M333.7 264.8v.2"/>
<path d="M333.7 261.5h.1M333.7 279.9h.1M333.7 278.6h.1M333.7 262.1h.1M333.7 275.7h.3M333.7 278.4l.1 .1M333.7 269.1h.4M333.7 269l.4 .1M333.7 277.7h.7M333.7 279l.1 .2M333.7 278.7h.1M333.7 278.7l-.1 .1"/>
<path d="M333.7 280l-.1 .1M333.8 263.7h1.4M333.8 264.4v.2M333.8 264.8v.2M333.8 279.2v.4M333.8 278.5v.5M333.8 277.8h.1M333.8 277.9v.3M333.8 279.9v.5M333.8 279.2l-.1 .3M333.8 278.5v.1M333.8 261.4h.1"/>
<path d="M333.8 278.3v.1M333.8 278.8h.1M333.8 262.1h.3M333.8 262.5l.1 .3M333.8 261.3h.1M333.8 278.5l.6 .1M333.8 277.3l.2 .2M333.9 278.9v.6M333.9 261.7h.1M333.9 279.4h.5M334 279.9h.1M334 260.8h.1"/>
<path d="M334 280l-.4 .1M334 260.8v.1M334 261h.1M334 280h.1M334 279.9l-.5-.1v.9M334 261.5h.1M334 279.5h.4M334 278.3h.4M334 262h.2M334 279.8l-.1 .1M334 279.8h.1M334 275.7l.2 .1"/>
<path d="M334 261.7h.1M334 276.1l.1 .1M334 262.8h.1M334 261v2.1M334 265.2v4.2M334 271.5v4.1M334 277.8v2.1M334 279.9v.1M334 278.7l.2 .1M334 276.7l-.2 .3M334.1 263.8v.1M334.1 264.2v.2"/>
<path d="M334.1 264.7h.1M334.1 279.7l-.1 .1M334.1 278.8h.1M334.1 261.7l-.3 .4M334.1 278.1v.2M334.1 278.5v.2M334.1 261.9h.1M334.1 261.2h.1M334.1 261.7h.1M334.1 262h.1M334.1 261.5h.1M334.1 261.2v.2"/>
<path d="M334.1 263.7h.1M334.1 262l.1 .1M334.1 269.1h.1M334.1 269.1v.9M334.1 270.9v.9l-.4 .1M334.1 271.7h-.4M334.1 278.8h.2M334.2 260.9v.2M334.2 261.4l-.1 .2M334.2 264.6l-.1 .1M334.2 280h1.3M334.2 274.9h1.3"/>
<path d="M334.2 276.9h.1M334.2 278.8v.2M334.2 269.8h1.3M334.2 271h1.2M334.2 264.8h1.3M334.2 265.9h1.2M334.2 261.6l-.3 .1M334.2 279.2v.2M334.3 264.6h.1M334.3 276.4l.1 .1M334.3 264.5h.1M334.3 264.5v.3"/>
<path d="M334.3 264.3v.1M334.3 264.9l-.9 .1M334.3 264.2h.1M334.3 276.9h.1M334.3 276.7h.1M334.3 275.8h.1M334.3 277.5h.1M334.3 276l.1 .1M334.3 277.6l.1 .1M334.3 261.6h.1M334.3 261.9h.1M334.3 261.2h.1"/>
<path d="M334.3 261.7h.1M334.3 262h.1M334.3 261.2v.1M334.3 261.5h.1M334.3 263.7h.1M334.3 262.1h.1M334.3 262v.1M334.3 264.4v.1M334.3 261.2h-.2M334.3 264.4h.1M334.3 261.7h.3M334.3 262h.2"/>
<path d="M334.3 276.1l.1 .1M334.3 276.1h.1M334.4 260.8l-.2 .1M334.4 264.3h.1M334.4 264.2h.1M334.4 277.4h.1M334.4 276.2h.1M334.4 277.9h.1M334.4 277.7v1.4h-.4M334.4 276.1h.1M334.4 277.7h.1M334.4 277.6h.1"/>
<path d="M334.4 276.5h.1M334.4 276.4h.1M334.4 276.5v.3M334.4 277.2v.3M334.4 278.1h.1M334.4 276.3h.1M334.4 278.1l-3.3 .1M334.4 278.8h.1M334.5 261.5l-.2 .1M334.5 264.2h.1M334.5 277l.2 .2M334.5 277h.1"/>
<path d="M334.5 264.1l-.1 .1M334.5 275.8l.2 .2M334.5 275.8h.1M334.5 279.9h.1M334.5 279.3l-.1 1.1M334.6 264.2h.1M334.6 278.2h.1M334.6 277.9h.1M334.6 260.1l.4 .1M334.6 261.6l-.2 .1M334.6 261.3l.1 .1M334.6 277.7h.1"/>
<path d="M334.6 276.4h.1M334.7 261.5h.1M334.7 279.4l-.1 .5M334.7 262.1h.1M334.7 262.1h-.4M334.7 277.1v1.7v-.6M334.7 276.3v.4M334.7 277.4v.1M334.7 276.2v.1M334.7 278.2h.1M334.7 276.1v.1M334.8 264.1h.1"/>
<path d="M334.8 261.6h.1M334.8 264.2h.1M334.8 260.6h.1M334.9 261.5h.1M334.9 261.3h.1M334.9 264.4h-1.4M334.9 261.5l-.1 .1M334.9 261.8l-.2 .2M334.9 261.5v.1M334.9 262.6h1.2M334.9 264.2l.1 .2M334.9 264.2h.1"/>
<path d="M334.9 264.4h.1M334.9 262h1.3M334.9 261v.3M335 260.7l-.3 .1M335 260.6v.3M335 261.1v.2M335 261.6h1.4M335 264.4h.1M335 263.7l-.2 .1M335 261.7h.3M335.1 262h.1M335.1 262h-.1"/>
<path d="M335.1 264.3l-.1 .1M335.1 263.3h-1.3M335.2 261.8h.1M335.2 261.8l-.1 .1M335.2 263.8h.1M335.2 264.3h.1M335.3 263.4h-.8M335.3 261.7h.1M335.3 261.7l-.1 .1M335.3 264l-.4 .1M335.3 264h.1M335.4 263.7h-.2"/>
<path d="M335.4 263.9h-1M335.4 260.7h.5M335.4 261v.5M335.7 263.1h.1M335.8 263l-.4 .2M335.8 264.2l-.6 .1M335.9 263.4h.1M335.9 263.7h-.1M336 260.1h.1M336.1 262.6l-.1 .2M336.2 262.6h.1M336.2 260.3l.2 .1"/>
<path d="M336.2 263.4l-.3 .3M336.2 263.5l-.3 .2M336.2 262.6l-.5 .5M336.2 261.3h.1M336.2 260.9v.1M336.2 261.2v.1M336.2 260.9h.1M336.2 260.8h.1M336.2 261.8h.1M336.2 261.7h.1M336.2 262h.1M336.2 261.8v.1"/>
<path d="M336.3 262.6h.1M336.3 261.5h.1M336.3 260.7h.1M336.4 262.3h.1M336.4 260.7h.4M336.4 261.5l.1 .1M336.4 263.1h.1M336.4 261.5h.1M336.4 263.1l-.2 .3M336.5 262l-.1 .2M336.5 260.7v.4M336.5 261.5v.6"/>
<path d="M336.5 262h.1M336.5 260.6h.1M336.5 260.6h-.1M336.5 262.8l-.6 .6M336.6 261.6h.2M336.6 260.5h.1M336.6 263h.1M336.6 263l-.4 .5M336.7 261.7l.1 .1M336.7 261.7h.1M336.7 260.5h.1M336.8 261.8v.1"/>
<path d="M336.8 262.2v.1M336.8 261.6h.1M336.8 261.7h.1M336.8 260.6h.1M336.8 276.1h1.3M336.8 271h1.3M336.8 260.9h1.3M336.8 265.9h1.3M336.8 262v.2M336.8 262.2l-.1 .4M336.8 260.7h.2M336.8 280h1.3"/>
<path d="M336.8 260.7h.1M336.8 260.9h.1M336.8 274.9h1.3M336.8 269.8h1.3M336.8 260.1v1.9M336.8 264.8h1.3M336.8 262.1h.1M336.8 262.1v.1M336.8 260.6h.3M337.1 263.1h.1M337.1 263.1l-.8 .8M337.1 260.1l.2 .2"/>
<path d="M337.2 260.6h.2M337.4 260.6h.1M337.4 260.8v.4M337.4 261.5l-.1 .9M337.4 260.1v.6M339.5 262v4.2M339.5 268.4v4.1M339.5 274.7v4.2M350.8 263.6v4M350.8 269.7v4.2M350.8 276v4M38.1 281.8h.1"/>
<path d="M38.1 281v.8M38.3 281.6l-.2 .2M38.7 280.8v.4M38.7 281.2l-.2 .2M40.3 281.2h.1M40.4 281.1h.1M40.4 280.1h2.1M40.4 280.1h.1M42.4 281.1l-3.7 .1M44.5 280.1h4M48.5 281.1l-4.9 .1M50.6 280.1h2v.3"/>
<path d="M52.6 280.8v.3M53.3 280.8v.4l-2.7-.1M54.3 281.1v2M54.7 281.2h.1M54.7 281.1v2M55 281.2h.1M57.2 280.4v.4M57.3 281l.1 .2M57.9 280.3h.2M57.9 280.9h.2M57.9 280.8v.4M58.2 280.3h.2"/>
<path d="M58.2 280.9h.2M58.4 280.8v.4M59 281.1v.1M59 280.2h.1M59.1 280.8v.2M59.1 280.2v.1M59.1 280.5l.1 .1M59.2 280.6h.1M62.3 280.4v.4M62.4 281v.2M63 280.3h.2M63 280.9h.2"/>
<path d="M63 280.8v.4M63.3 280.3h.2M63.3 280.9h.2M79 298.9h.1M79 299.8h.1M79.2 299.8h.1M79.2 298.9h.1M79.2 298.8v.1M79.2 299v.3M79.2 299.6v.2M79.6 299.6l-.4 .2M80.1 297.2h.1"/>
<path d="M80.2 297.4l-1 1.1M80.3 298.7v1.1M80.3 298.7v.1M80.3 297.2h.1M80.3 298.8v1.1M80.5 299.4h.1M80.5 299.4l-.4 .1M80.7 299.4h-.2M80.8 297.9l-.8 .8v1.1M80.9 299.4h.3v.6M81 298l-.7 .7M81.1 299.4v.7"/>
<path d="M81.1 298.1l-.7 .7M81.1 296.2h.1M81.4 296.2h.1M82.1 295.4h.1M82.1 295.3h.1M82.1 295.4h1.5M82.2 295.4l-1 1M82.2 295.4h.1M82.6 296.4l-.8 .8M82.6 296.4h1M82.6 296.4l1.1 .1M83.6 296.2h-1.1l-.8 .9"/>
<path d="M83.7 296.6h-1l-.8 .7M84.8 296.5h1M84.8 296.4h1.1M84.8 296.6h1l.8 .7M84.8 296.2h1.2l.8 .8M85 295.4h1.3M85.8 296.5l.8 .8M85.9 296.4l.7 .8M85.9 296.4l-.1 .1M86.3 295.4l1 1M86.3 295.4h.1M86.4 295.2h.1"/>
<path d="M86.4 295.4h.1M87.1 296.2h.1M87.3 296.2h.1M87.3 298.1l.8 .7M87.5 298l.8 .7M87.5 299.4v.7M87.6 299.4h-.3v.6M87.6 297.9l.8 .8v1.1M87.8 299.4h.2M88 299.4h.1M88 299.4l.4 .1M88.1 298.8v1"/>
<path d="M88.1 297.2h.1M88.3 297.3l.9 1.2M88.3 298.7v1.1M88.3 298.7l-.2 .1M88.3 297.2h.1M88.9 299.6l.3 .2M89.2 299.1h.1M89.2 299.8h.1M89.2 298.7v.3M89.2 299.1v.2M89.2 299.6v.2M89.2 298.9h.1"/>
<path d="M89.4 298.9h.1M89.4 299.8h.1M118.7 280.3l-.2 .1M120.1 298.4l-.2 .2a3.1 3.1 0 0 0 0 3M122.9 296.9l-1.6 .4M129.2 286.3v.9h.3M129.5 284.6h-.3v.9M129.8 284.6l.2 .9M130 287.1h.8M130 284.7h.8M130 286.3l-.2 .9M131.7 287.1h.8"/>
<path d="M131.7 284.7h.8M132.2 286.2v.2h1.8M132.2 280.9v3.5M132.5 286.3v.9h.2M132.5 282.5h.1M132.5 281.9h.1M132.5 281.9v.2M132.5 282.4v.1M132.5 281.3v.6h.5M132.5 282.5h.5M132.7 284.6h-.2v.9M133 284.6h.3v.9"/>
<path d="M133.1 283.5v.1M133.1 283.7h.1M133.1 283.8h.1M133.2 283.3h.1M133.2 283.4h.1M133.2 283.9h.1M133.2 283.3h.4M133.2 283.9h.4M133.2 283.9l.1 .4M133.3 283l-.1 .3M133.3 286.3v.9h-.3M133.5 284.6l.4 .6"/>
<path d="M133.5 282.5h.1M133.5 281.9l.6 .2M133.9 285.2h.1M134 282.8h.1M134 282.8v1.3M134 281.3l-.1 .8-.4 .4M134 284.1h.1M134.1 282.4l-.6 .1M134.2 283.9h.5v.5M134.4 285.4l.3 .1M134.5 282.2h.1M134.6 284.6h.1"/>
<path d="M134.6 282.2h1.3M134.6 284.6h1.3M134.7 281.7h.1M134.7 285.5h.1M134.7 282.8v.5h-.5M134.7 281.7v.5M134.7 285v.5M134.7 281.7l-.3 .2M135 281.7h.2M135.1 285.5h-.1M135.2 285.5h.1M135.3 281.7l.4 .2"/>
<path d="M135.3 281.7h.1M135.3 282.8v.5h.6M135.3 281.7v.5M135.3 285v.5M135.6 285.4h.1M135.6 285.4l-.3 .1M135.9 283.9h-.6v.5M135.9 282.2h.1M135.9 284.6h.1M135.9 286.4h3.6M136.1 285.2h.1M136.1 282.1h.1"/>
<path d="M136.1 282.1l.5 .5M136.4 283.3h.5M136.4 283.9h.5M136.4 282.7l.1 1.4M136.6 284.7l-.5 .5M136.6 284.7h.1M136.9 283v.3M136.9 283h.1M136.9 283.3v.1M136.9 283.9l-.1 .4M136.9 280.7l1.1 1.7M136.9 283.5v.2"/>
<path d="M136.9 283.8v.1M137.5 280.5l1.1 1.6M138.6 283.2l.7 .7M139.1 282.8l.5 .8M139.3 283.9l.4 .5M139.3 283.9h1.6M139.4 283.8l-.1 .1M140.2 284.8l.8 .8M141.4 286.4h3.6M141.6 286l.4 .4M144.1 288.2h.1M144.1 286.6h.1"/>
<path d="M144.1 286.7v.5M144.1 287.7v.5M144.1 288.2h.2M144.1 286.6h.2M144.2 280.1l.2 .1M144.3 280l-.1 .1M144.5 280.3l.1 .1M144.6 288.2h.1M144.6 286.6l.8 .1M144.6 280.4h.1M144.6 280.4h.6M144.6 280.2l.1 .1"/>
<path d="M144.7 280.3h.1M144.7 280.3h.6M144.7 286.6h.1M144.7 287.7v.5h.7M144.7 286.7v.5M144.9 283.8l-2.3 .1M146 280.3h.7M146.4 282.7l-.9 .8M146.5 282.1l.2 .3M146.5 281.4v.4M146.5 281.1v.2M146.5 280.7v.3"/>
<path d="M146.5 280.4v.1M146.5 281h.2M146.5 281.2h.2M146.6 280.8l.1 1.2M146.7 280.4h-.8M146.8 288.2h.1M146.8 286.6h.1M146.8 287.7v.5h-.7M146.8 286.7v.5M146.8 280.4h.3M146.8 281h.2M146.8 281.2h.2"/>
<path d="M146.8 280.2l-2.1 .1M146.9 286.4h3.6M146.9 286.6l-.8 .1M147 281.4h.1M147 282.1l-.2 .3M147 280.4v.1M147 280.7v.3M147 281.1v.2M147 281.4v.4M147.1 280.3h-.3M147.1 288.2h.3M147.1 286.6h.3"/>
<path d="M147.4 286.6h.1M147.4 286.7v.5M147.4 287.7v.5M147.4 280.3h.3M147.5 281h.2M147.5 281.4v.4M147.5 281.1v.2M147.5 280.7v.3M147.5 282.1l.2 .3M147.5 280.4v.1M147.5 281.2h.2M147.7 280.4h-.3"/>
<path d="M147.9 280.4h.3M147.9 281h.1M147.9 281.2h.1M147.9 281.4h.1M147.9 282.1v.3M147.9 280.4v.1M147.9 280.7v.3M147.9 281.1v.2M147.9 281.4v.4M148.2 280.3h-.3M148.4 280.3h.3M148.5 281.4v.4"/>
<path d="M148.5 281.1v.2M148.5 280.7v.3M148.5 282.1l.2 .3M148.5 280.4v.1M148.5 281h.2M148.5 281.2h.2M148.7 280.4h-.3M148.9 280.4h.2M148.9 281h.1M148.9 281.2h.1M149 281.4h.1M149 282.1l-.1 .3"/>
<path d="M149 280.4v.1M149 280.7v.3M149 281.1v.2M149 281.4v.4M149 280.2h4.2M149.1 280.3h-.2M149.4 280.3h.3M149.5 281.4v.4M149.5 281.1v.2M149.5 280.7v.3M149.5 282.1l.2 .3M149.5 280.4v.1"/>
<path d="M149.5 281h.2M149.5 281.2h.2M149.7 280.4h-.3M149.9 280.4h.2M149.9 281h.1M149.9 281.2h.1M150 281.4h.1M150 282.1l-.1 .3M150 280.4v.1M150 280.7v.3M150 281.1v.2M150 281.4v.4"/>
<path d="M150.1 280.3h-.2M150.4 280.3h.3M150.5 281.4v.4M150.5 281.1v.2M150.5 280.7v.3M150.5 282.1l.2 .3M150.5 280.4v.1M150.5 281h.2M150.5 281.2h.2M150.7 280.4h-.3M150.9 280.4h.3M150.9 281h.1"/>
<path d="M150.9 281.2h.1M151 281.4h.1M151 282.1l-.1 .3M151 280.4v.1M151 280.7v.3M151 281.1v.2M151 281.4v.4M151.2 280.3h-.3M151.4 280.3h.3M151.5 281.4v.4M151.5 281.1v.2M151.5 280.7v.3"/>
<path d="M151.5 280.4v.1M151.5 281h.2M151.5 282.1l.2 .3M151.5 281.2h.2M151.7 280.4h-.3M151.8 280.4h.3M151.8 281h.2M151.8 281.2h.2M152 281.4h.1M152 282.1l-.2 .3M152 280.4v.1M152 280.7v.3"/>
<path d="M152 281.1v.2M152 281.4v.4M152.1 280.3h-.3M152.4 280.3h.3M152.4 286.4h3.6M152.5 284.3h.1M152.5 281.4v.4M152.5 281.1v.2M152.5 280.7v.3M152.5 282.1l.2 .3M152.5 280.4v.1M152.5 281h.2"/>
<path d="M152.5 281.2h.2M152.6 282.5l-.2 .7 .1 1.1M152.7 280.4h-.3M152.9 280.4h.3M152.9 281h.1M152.9 281.2h.1M152.9 281.4h.1M152.9 282.1v.3M152.9 280.4v.1M152.9 280.7v.3M152.9 281.1v.2M152.9 281.4v.4"/>
<path d="M153.2 280.3h-.3M153.3 285.1l1 .2 .8-.2M153.4 281.7h.1M153.4 280.3h.3M153.5 281.4v.4M153.5 281.1v.2M153.5 280.7v.3M153.5 282.1l.2 .3M153.5 280.4v.1M153.5 281h.2M153.5 281.2h.2M153.7 280.4h-.3"/>
<path d="M153.9 281h.1M153.9 281.2h.1M153.9 282.4h.1M154 281.4h.1M154 280.7v.3M154 281.1v.2M154 281.4v.4M154 282.1v.3M154.1 280.3h-.2M154.1 280.4l-.1 .1M154.4 280.3h.3M154.5 281.4v.4"/>
<path d="M154.5 281.1v.2M154.5 280.7v.3M154.5 282.1l.2 .3M154.5 280.4v.1M154.5 281h.2M154.5 281.2h.2M154.7 280.4h-.3M154.8 280.4h.3M154.8 281h.2M154.8 281.2h.2M155 281.4h.1M155 282.1l-.2 .3"/>
<path d="M155 280.4v.1M155 280.7v.3M155 281.1v.2M155 281.4v.4M155.1 285.1h.1M155.1 281.7h-1.7M155.1 280.3h-.3M155.2 281.8h.1M155.4 280.2h4.1M155.4 280.3h.3M155.5 281h.2M155.5 281.4v.4"/>
<path d="M155.5 281.1v.2M155.5 280.7v.3M155.5 282.1l.2 .3M155.5 280.4v.1M155.5 281.2h.2M155.7 280.4h-.3M155.9 280.4h.3M155.9 281h.1M155.9 281.2h.1M155.9 282.5l.3 .9-.3 1M155.9 281.4h.1M155.9 282.1v.3"/>
<path d="M155.9 280.4v.1M155.9 280.7v.3M155.9 281.1v.2M155.9 281.4v.4M156.2 280.3h-.3M156.4 280.3h.3M156.5 281h.2M156.5 281.4v.4M156.5 281.1v.2M156.5 280.7v.3M156.5 282.1l.2 .3M156.5 280.4v.1"/>
<path d="M156.5 281.2h.2M156.7 280.4h-.3M156.8 280.4h.3M156.8 281h.2M156.8 280.3h.3M156.8 281.2h.2M157 281.4h.1M157 282.1l-.2 .3M157 280.4v.1M157 280.7v.3M157 281.1v.2M157 281.4v.4"/>
<path d="M157.4 280.3h.3M157.5 281.4v.4M157.5 281.1v.2M157.5 280.7v.3M157.5 282.1l.2 .3M157.5 280.4v.1M157.5 281h.2M157.5 281.2h.2M157.7 280.4h-.3M157.9 280.4h.3M157.9 281h.1M157.9 281.2h.1"/>
<path d="M157.9 286.4h3.6M158 281.4h.1M158 282.1l-.1 .3M158 280.4v.1M158 280.7v.3M158 281.1v.2M158 281.4v.4M158.2 280.3h-.3M158.4 280.3h.3M158.5 281h.2M158.5 281.4v.4M158.5 281.1v.2"/>
<path d="M158.5 280.7v.3M158.5 282.1l.2 .3M158.5 280.4v.1M158.5 281.2h.2M158.7 280.4h-.3M158.9 281h.1M158.9 281.2h.1M158.9 282.4h.1M159 281.4h.1M159 280.7v.3M159 281.1v.2M159 281.4v.4"/>
<path d="M159 282.1v.3M159.2 280.3h-.3M159.2 280.4l-.2 .1M159.4 280.3h.3M159.5 281.4v.4M159.5 281.1v.2M159.5 280.7v.3M159.5 282.1l.2 .3M159.5 280.4v.1M159.5 281h.2M159.5 281.2h.2M159.7 280.4h-.3"/>
<path d="M159.8 290.4l.2 .8M159.8 280.4h.3M159.8 281h.2M159.8 281.2h.2M160 281.4h.1M160 282.1l-.2 .3M160 280.4v.1M160 280.7v.3M160 281.1v.2M160 281.4v.4M160 288.7l-.2 .8M160.1 286.7l.3 .5"/>
<path d="M160.1 285.7v.4M160.1 285.6h.3M160.1 280.3h-.3M160.3 288.7h.3v.8M160.4 280.3h.3M160.5 281.4v.4M160.5 281.1v.2M160.5 280.7v.3M160.5 282.1l.2 .3M160.5 280.4v.1M160.5 281h.2M160.5 281.2h.2"/>
<path d="M160.6 290.4v.8h-.3M160.6 291.1h.7M160.6 288.8h.7M160.6 285.6h.1M160.7 280.4h-.3M160.7 285.6h.1M160.7 286.7v.5M160.9 280.4h.3M160.9 281h.1M160.9 281.2h.1M160.9 281.4h.1M160.9 282.1v.3"/>
<path d="M160.9 280.4v.1M160.9 280.7v.3M160.9 281.1v.2M160.9 281.4v.4M161.2 280.3h-.3M161.2 294.6h.1M161.2 294.6a1.01 1.01 0 0 0 0 1.7M161.4 280.3h.3M161.4 287.1l-.8 .1M161.4 285.7h-.7v.4M161.5 281h.2M161.5 281.4v.4"/>
<path d="M161.5 281.1v.2M161.5 280.7v.3M161.5 282.1l.2 .3M161.5 280.4v.1M161.5 281.2h.2M161.7 280.4h-.3M161.7 280.2h2M161.9 280.4h.7M161.9 281h.1M161.9 281.2h.1M162 281.4h.1M162 282.1l-.1 .3"/>
<path d="M162 280.4v.1M162 280.7v.3M162 281.1v.2M162 281.4v.4M162 280.2h.1M162 280.2l-.3 1.5 .4 1M162.1 287.1l.8 .1M162.1 285.7h.6v.4M162.1 291.1h.8M162.1 288.8h.8M162.2 294.6l.5 .8-.4 .8M162.6 280.3h-.7"/>
<path d="M162.7 286.7v.5M162.7 285.6h.2M162.9 290.4v.8h.3M163.1 283.6l1.6 .3M163.2 285.6h.2M163.2 288.7h-.3v.8M163.2 280.3h.6M163.3 280.4h.6M163.4 285.6h.1M163.4 286.7l-.2 .5M163.4 285.7v.4M163.4 286.4h3.6"/>
<path d="M163.5 288.7h.2v.8M163.7 290.4v.8h-.2M163.8 280.2v.1M163.8 280.3h.1M163.9 280.4h.1M163.9 280.2l-.1 .1M164 280.3l-.1 .1M164.2 280h.1M164.2 280.1v.1M165.4 286.3l.6 .2M165.4 285.9h.6M165.4 283.8l.1 .8"/>
<path d="M165.5 285.3l-.1 .8M166 283.3l-.6 .2M166 283.9h-.9M166.5 286.5h.5M166.5 283.3h.5M166.5 283.9h1.3M167 286l-.5 .4M167 285.3v.6h-.5M167 283.9v.7M167 286.5h.1M167 285.9v.2M167 283.9h.1"/>
<path d="M167 283.3v.2M167 283.8v.1M167 286.3v.2M168.4 284.8l-.9 .8M168.5 283.9h.7M168.9 286.4h3.6M169.1 283.8l.1 .1M169.2 283.9l-.4 .5M169.4 282.8l-.5 .8M169.9 283.2l-.7 .7M171 280.5l-1 1.5M171.6 280.7l-1.1 1.6"/>
<path d="M171.8 282.7l-.3 .9 .3 .9M172 282.8h.1M172 282.8v1.3M172 284.1h.1M172.5 285.2h.1M172.5 281.9h.1M172.5 281.9l.9-.2 1 .3M172.5 282.2h.1M172.6 284.6h.1M172.6 282.2h1.3M172.6 284.6l.2 .1M172.8 284.1v.7"/>
<path d="M173.1 284.2v.6M173.2 282.8h-.4v.6M173.4 283h-.3v.6M173.7 282.8h.4M173.7 283h.4M173.9 284.6l-1.1 .1M173.9 282.2h.1M173.9 284.6h.1M174.1 282.8v.1M174.3 285.3l-.9 .2-.9-.2M174.3 285.3h.1M174.4 282.7l.1 1.4"/>
<path d="M175.1 282.7l.2 .9-.2 1M176.2 284.7v1.7h-1.8M177.6 281.2l.2 .5M177.6 285.2l.2 .5M177.6 289.2l.2 .5M177.8 288.1l-.2 .6M177.8 280.1l-.2 .6M177.8 284.1l-.2 .5M178 281.7h.9M178 284.1h.9M178 280.1h.9M178 285.7h.9"/>
<path d="M178 289.7h.9M178 288.1h.9M178.3 280.1v.6M178.3 281.2v.5M178.3 284.1v.5M178.3 285.2v.5M178.3 288.1v.6M178.3 289.2v.5M179.6 284.1h.6M179.6 280.1h.6M179.6 288.1h.6M179.6 281.7h.8"/>
<path d="M179.6 285.7h.8M179.6 289.7h.8M180.2 280.1v.6M180.2 281.2v.5M180.2 284.1v.5M180.2 285.2v.5M180.2 288.1v.6M180.2 289.2v.5M180.2 288.1h.2M180.2 280.1h.2M180.2 284.1h.2M180.6 284.1l.2 .5"/>
<path d="M180.6 280.1l.2 .6M180.6 288.1l.2 .6M180.8 281.2l-.2 .5M180.8 285.2l-.2 .5M180.8 289.2l-.2 .5M185.5 296.9l.9 .1M187.2 297.3l1.3 1.2M188.8 299.3v1.6M226.9 282h.1M227 285.6v.2M227 286v.2M227 287.8v.2"/>
<path d="M227 288.2v.2M227 290v.2M227 290.4v.2M227 292.2v.2M227 292.7v.1M227 294.4v.2M227 294.9v.1M227 296.6v.2M227 297.1v.1M227 298.8v.2M227 299.3v.1M227 288.4h.1"/>
<path d="M227 287.8h.1M227 299.4h.1M227 298.8h.1M227 286.2h.1M227 285.6h.1M227 297.2h.1M227 296.6h.1M227 295h.1M227 294.4h.1M227 290.6h.1M227 290h.1M227 292.8h.1"/>
<path d="M227 292.2h.1M227.2 282l.1 .9M227.3 285.6v.2M227.3 286v.2M227.3 290v.2M227.3 290.4v.2M227.3 294.4v.2M227.3 294.9v.1M227.3 296.6v.2M227.3 297.1v.1M227.3 298.8v.2M227.3 299.3v.1"/>
<path d="M227.3 287.8v.2M227.3 288.2v.2M227.3 292.2v.2M227.3 292.7v.1M227.3 283.8v.8M227.7 283.3v.2M227.7 283.3h.1M227.7 283.2v.1M227.7 284.6h.1M227.7 282.9h.1M227.8 283.5h.1M227.8 282.8h.1"/>
<path d="M227.8 282.8l-.1 .1M227.9 283.1v.1M227.9 283l-.1 .3M227.9 283.3l.1 .1M227.9 282.9h.1M227.9 283.4h.1M228 283.5h.1M228 284.6l.1 2.3M228 283.6l.1 .1M228 280.4h.1M228 283.6h.1M228 282.1l-.1 .8"/>
<path d="M228 280.5v.8M228 283.7h.4M228 280.6h.1M228 280.4h1.1M228 282.7h-.1M228.1 282.9h.1M228.1 283.5h.1M228.1 289.2v4.4M228.1 295.9v4.4M228.1 283.7h.1M228.2 282.9h-.1M228.2 283.5h.1"/>
<path d="M228.3 282.9h.1M228.3 283.4h.1M228.3 282.9l.2 .2M228.3 280.6h1M228.4 282.8l-.1 .1M228.4 283.1v.3M228.5 283.1h.1M228.5 283.4l-.3 .1M228.5 282.8l-.2 .1M228.5 282l.4 .2M228.5 280.4v.7M228.5 281.8l-.2 .7"/>
<path d="M228.5 282.9h.1M228.6 280.1v.1M228.6 282.9h.1M228.6 280.2h.1M228.7 283.2h.1M228.7 283.2l-.3 .2M228.7 280.2h.1M228.8 283.1h.1M228.8 283h.1M228.8 283.7v2.2M228.8 288.2v4.3M228.8 294.8v4.4"/>
<path d="M228.9 283.7h-.3M229 283.7h.1M229.1 292.1h.1M229.1 285.5h.1M229.1 294.8v4.4h.6M229.1 283.7v2.1M229.1 288.1v4.4M229.1 298.7h.1M229.1 289.9h.1M229.1 287.7h.1M229.1 294.3h.1M229.1 296.5h.1"/>
<path d="M229.1 295h.5M229.1 288.4h.5M229.1 298.6h.6M229.1 294.4h.6M229.1 287.8h.6M229.1 292.9h.1M229.1 293h.1M229.1 286.3h.1M229.1 286.4h.1M229.1 298.8h.1M229.1 290.7h.1M229.1 288.5h.1"/>
<path d="M229.1 295.1h.1M229.1 295.2h.1M229.1 297.3h.1M229.1 287.7l.1 .1M229.1 294.3l.1 .1M229.2 290.7h-.1M229.2 287.8h.1M229.2 294.4h.1M229.2 297.3h-.1M229.3 298.9h.1M229.3 285.6h.1M229.3 290h.1"/>
<path d="M229.3 292.2h.1M229.3 296.6h.1M229.3 280.1h.1M229.3 286.2h.1M229.3 290.6h.1M229.3 292.8h.1M229.3 284.1h.1M229.3 288.4l-.2 .1M229.3 295l-.2 .1M229.3 297.2h.1M229.3 280.2h.1M229.4 286.2h.1"/>
<path d="M229.4 290.6h.1M229.4 292.8h.1M229.4 297.2h.1M229.4 280.2h.1M229.4 299h.1M229.4 285.6h.1M229.4 290h.1M229.4 292.2h.1M229.4 284.1h.1M229.4 296.7h.1M229.4 282.6l.5 .4M229.5 292.3h.1"/>
<path d="M229.5 296.7h.1M229.5 290.6h.1M229.5 299h.1M229.5 284.1h.1M229.5 285.7h.1M229.5 290.1h.1M229.5 286.2h.1M229.5 292.8h.1M229.5 297.2h.1M229.5 280.1h.1M229.6 292.2h.1M229.6 296.6h.1"/>
<path d="M229.6 298.1h.1M229.6 296.5h.1M229.6 293.7h.1M229.6 291.8h.1M229.6 287.1h.1M229.6 298.9h.1M229.6 285.2l.3 .3M229.6 286.9v.2M229.6 289.6l.3 .3M229.6 291.5v.3M229.6 292.9v.3M229.6 293.4v.3"/>
<path d="M229.6 296.2v.3M229.6 297.8v.3M229.6 292.9h.3M229.6 286.3h.1M229.6 288.5h.1M229.6 295.1h.1M229.6 284.1h.1M229.6 287.8h.1M229.6 294.4h.1M229.7 298.9h.1M229.7 286.3h.1M229.7 290.7h.1"/>
<path d="M229.7 292.9h.1M229.7 290h-.1M229.7 285.6h.1M229.7 297.3h.1M229.7 290h.1M229.7 287.7h.1M229.7 298.1h.1M229.7 296.5h.1M229.7 293.7h.1M229.7 291.8h.1M229.7 287.1h.1M229.7 292.9h.2"/>
<path d="M229.7 288.6h.1M229.7 295.1v.3M229.7 284.2h.1M229.7 285.5h.1M229.7 289.9h.1M229.7 294.3h.1M229.7 292h.1M229.7 298.7h.1M229.7 286.4h.2M229.7 291.1h.2M229.7 288.7v.1M229.7 290.9v.1"/>
<path d="M229.7 284.2v.2M229.7 287.1h.2M229.7 284.6v.2M229.7 287.1v.1M229.7 287.4v.2M229.7 289.1v.1M229.7 293.7v.1M229.7 294v.2M229.7 295.7h.1M229.7 298.1v.1M229.7 298.4v.3M229.7 298.1h.2"/>
<path d="M229.7 296.5h.2M229.7 293.7h.2M229.7 291.8h.2M229.7 296.5v.1M229.7 297.3h.2M229.7 287.6h.1M229.7 294.2h.1M229.8 282v.4M229.8 283v.4M229.9 297.3l-.3 .3M229.9 286.4l-.3 .2M229.9 291.1l-.3 .2"/>
<path d="M229.9 284.8l-.3 .1M229.9 283.3v.1M229.9 289.2l-.3 .1M229.9 283.4h.9M229.9 295.7l-.3 .3M229.9 280.1l.1 .1M230 280.2h.1M230.1 296.5h.1M230.1 291.8h.1M230.1 284.8l.3 .2M230.1 289.9h.1M230.1 280.2h.1"/>
<path d="M230.1 280.4h1.1M230.1 286.4l.3 .2M230.1 289.2l.3 .2M230.1 291.1l.3 .2M230.1 292.9l.3 .3M230.1 295.7l.3 .3M230.1 297.3l.3 .3M230.2 280.2h.1M230.2 295h.6M230.2 288.4h.6M230.2 280.1h.1M230.2 298.7h.1"/>
<path d="M230.2 289.9h.1M230.2 292h.1M230.2 298.1h.1M230.2 293.7h.1M230.2 291.8h.1M230.2 287.1h.1M230.2 290.7v.1M230.2 291v.1M230.2 296.5h.1M230.2 288.6h.1M230.2 295.1h.1M230.2 295.2h.1"/>
<path d="M230.2 288.7v.1M230.2 289v.2M230.2 295.2v.2M230.2 295.6v.1M230.2 294.4h.6M230.2 287.8h.6M230.2 294.2h.1M230.2 294.3h.1M230.2 284.4v.1M230.2 284.3h.1M230.2 284.6v.2M230.2 287.1v.1"/>
<path d="M230.2 287.4l.1 .4M230.2 291.9v.1M230.2 293.7v.1M230.2 294v.2M230.2 298.1v.1M230.2 298.4v.3M230.3 292.9h.1M230.3 298.8v.1M230.3 292.1l.1 .1M230.3 288.5h.1M230.3 295.1h.1M230.3 285.5h.1"/>
<path d="M230.3 286.3l-.1 .1M230.3 295h.1M230.3 290l.1 .1M230.3 294.4h.1M230.3 284.1h.1M230.3 284.1v.1M230.3 297.3h-.1M230.4 292.8h.1M230.4 292.2h.1M230.4 290.6h.1M230.4 296.6h.1M230.4 288.4h.1"/>
<path d="M230.4 285.5h.1M230.4 290.1h.1M230.4 298.9h.1M230.4 285.6h.1M230.4 285.3l-.3 .2M230.4 286.9l-.3 .2M230.4 289.7l-.1 .2M230.4 291.6l-.1 .2M230.4 293.5l-.3 .2M230.4 296.3l-.1 .2M230.4 297.9l-.3 .2M230.5 299h.1"/>
<path d="M230.5 290.6h-.1M230.5 286.2h.1M230.5 297.2h.1M230.5 285.6h.1M230.5 284.1h.1M230.5 296.7h.1M230.5 290.1h.1M230.6 280.1h.1M230.6 286.2h.1M230.6 296.7h.1M230.7 286.2l.1 .1M230.7 292.8l.1 .1"/>
<path d="M230.7 292.8h.1M230.7 283l-1.9 .3M230.7 290.6h.1M230.7 285.5h.1M230.7 292.2h.1M230.7 290h.1M230.7 295l.1 .1M230.7 296.6h.1M230.7 288.5h.1M230.7 295h.1M230.7 280.1l.1 .1M230.7 287.8h.1"/>
<path d="M230.7 294.4h.1M230.8 285.5h.1M230.8 292.2l-.3 .1M230.8 290h-.1M230.8 297.3h.1M230.8 288.5h.1M230.8 295.1h.1M230.8 297.4v1.2h-.6M230.8 284.1v1.2M230.8 286.6v1.2M230.8 288.4v2M230.8 292.4v2"/>
<path d="M230.8 295v1.2M230.8 287.8h.1M230.8 296.6h-.1M230.8 298.9h-.1M230.8 298.9h.1M230.8 289.9h.1M230.8 280.2h.1M230.8 287.7h.1M230.8 288.7l.1 .1M230.8 286.5l.1 .1M230.8 294.2h.1M230.8 288.7h.1"/>
<path d="M230.8 286.5h.1M230.8 285.3h.1M230.8 287.6h.1M230.8 285.3v.1M230.8 293l.1 .1M230.8 290.8l.1 .1M230.8 293h.1M230.8 292h.1M230.8 290.8h.1M230.8 289.8h.1M230.8 292v.1M230.8 295.2l.1 .1"/>
<path d="M230.8 295.2h.1M230.8 297.5h.1M230.8 296.4h.1M230.8 296.4v.1M230.8 294.2v.1M230.9 297.5h.1M230.9 298.7h.1M230.9 295h.1M230.9 288.4h.1M231 288.9h.1M231 284.1h.1M231 286.7h.1"/>
<path d="M231 287.1v.4M231 294h-.1M231 285.1l-.1 .1M231 287.4h-.1M231 292.8v.7M231 293.3h.1M231 291h.1M231 286.1v.8M231 291.5v.7M231 293.7v.3M231 291.8h-.1M231 289.6h-.1"/>
<path d="M231 290.6v.7M231 294.3v.1M231 283.7v.1M231 283.9v.5M231 295v.1M231 295.3v.4M231 287.7v.1M231 288.4v.1M231 288.7v.4M231 297.2v.8M231 295.5h.1M231 297.7h.1"/>
<path d="M231 298.4v.4M231 296.2h-.1M231 284.7v.9M231 289.3v.7M231 295.9v.7M231 299l-.6 .2M231.2 284.1h-2.1h.2M231.2 280.4h.1M231.3 282.8v.5h.5M231.3 280.1h.1M231.3 298.9v.5M231.3 299.8v.4"/>
<path d="M231.4 280.1h.1M231.4 280.2h.1M231.4 280.3h.1M231.5 280.2h.1M231.5 298.9l-.2 .1M231.6 298.9h.3M231.6 298.9v.4M231.6 299.7v.4h.4M231.6 280.1l-.2 .2M231.6 280.1h.1M231.6 298.9l.4 .1M231.6 298.9h.1"/>
<path d="M231.7 281.7h-.4v.5l-2.6 .5M231.8 283.4h1M231.9 299.8h.1M231.9 299.6v.2M231.9 298.5l-.6 .2M232 299.8h.1M232 299h.1M232 299v.1M232 280h.1M232 299.9h.1M232.1 280.1h.1M232.1 280.2h.1"/>
<path d="M232.2 280.2h.1M232.2 299.1l-.3 .2M232.3 280.2h.1M232.3 280.1h.1M232.3 281.7h.5v.5M232.3 280.1v.1M232.4 280l-.1 .1M232.4 299.8h.1M232.4 299.1l.3 .2M232.4 298.9h.5v.4M232.5 299.8h.1M232.6 299.9h.1"/>
<path d="M232.6 298.5h.6M232.6 300h.1M232.7 299.8h.1M232.7 298.9l-.2 .2M232.7 298.9h.1M232.7 299.6v.2M232.7 280h.1M232.8 280.1l.1 .1M232.8 280.1h.1M232.8 298.9h.1M232.8 298.9h.2M232.8 280.2h.1"/>
<path d="M232.8 282.8v.5h-.4M232.9 280.2h.1M232.9 299.7v.4h-.4M233 280.1h.1M233.2 298.7v.6M233.2 299.7v.5M233.2 298.9h-.1M233.2 280.7v3.5M233.2 286v3.6M233.2 291.4v3.5M233.2 296.8v1.8M233.4 284.1h4.2"/>
<path d="M233.4 280.1h.1M233.5 280.1h.1M233.6 280.2h.1M233.6 288.4l.1 .5M233.8 287.5l-.2 .5M233.8 289l1.8 .1M234 283.2l-1.5 .2M234.1 287.3l-.2 .1M234.1 281.9h.1M234.1 280.1h.1M234.2 291.3h1.8M234.2 287.3h.1"/>
<path d="M234.2 286.5v.8M234.2 289.1v2.1M234.2 293.4v4.2M234.2 299.8v2.3M234.2 298.3h.1M234.2 296.1h.1M234.2 283.6l1.8 .2M234.2 280.9v1.3M234.2 282.8v.6M234.2 291.7h.1M234.2 289.5h.1M234.2 293.5h1.8"/>
<path d="M234.2 286.9h1.8M234.2 293.9h.1M234.2 283.3h.6M234.2 281.7h.5M234.2 295.7h1.8M234.2 285.1h.1M234.2 280.2h.1M234.2 297.9h1.8M234.3 280.2h.1M234.3 288.1h.1M234.3 288.2v.1M234.3 288.3h.1"/>
<path d="M234.4 288h.1M234.4 288.4h.1M234.4 280.2h.1M234.4 287.9h.1M234.5 287.9h.1M234.5 288.5h.2M234.5 288.4l.1 .1M234.5 288.3h.1M234.5 288.1h.1M234.5 288.4h.1M234.5 288h.1M234.6 287.9h.1"/>
<path d="M234.6 288.5h.1M234.7 288.5h.1M234.7 287.9h.1M234.8 284.8h-.6v.8M234.8 281.6l-.7 .3M234.8 280.1h.1M234.9 287.9h.3M234.9 280.1h.1M234.9 288.5h.4M234.9 280.2h.1M235 285.9h.1M235 286v.1"/>
<path d="M235 290.2h.1M235 290.4v.1M235 294.7h.1M235 294.8h.1M235 294.9h.1M235 299h.1M235 299.2h.1M235 299.3h.1M235 280.2h.1M235 285.8h.1M235 286.2h.1M235 290.6h.1"/>
<path d="M235 294.6h.1M235 295h.1M235 299.4h.1M235.1 285.7h.1M235.1 290.1h.1M235.1 294.5h.1M235.1 298.9h.1M235.1 286.3h.1M235.1 290.7h.1M235.1 295.1h.1M235.1 299.5h.1M235.2 285.7h.1"/>
<path d="M235.2 286.3h.2M235.2 290.1h.1M235.2 290.7h.2M235.2 294.5h.1M235.2 295.1h.2M235.2 298.9h.1M235.2 299.5h.2M235.2 281.8l-1.2 .1M235.2 286.1h.1M235.2 285.9h.1M235.2 286.2h.1M235.2 285.8h.1"/>
<path d="M235.2 290.6v.1M235.2 290.5h.1M235.2 290.3h.1M235.2 290.6h.1M235.2 290.2h.1M235.2 294.9h.1M235.2 294.7h.1M235.2 295h.1M235.2 294.6h.1M235.2 299.3h.1M235.2 299.1h.1M235.2 299h.1"/>
<path d="M235.2 299.4h.1M235.3 286.3h.1M235.3 285.7h.1M235.3 290.7h.1M235.3 290.1h.1M235.3 295.1h.1M235.3 294.5h.1M235.3 281.7h.5v.5M235.3 299.5h.1M235.3 298.9h.1M235.5 292.4h.1M235.5 292.6v.1"/>
<path d="M235.5 292.8h.1M235.5 285.7h.4M235.5 290.1h.4M235.5 296.8h.1M235.5 296.9h.1M235.5 297v.1M235.5 297.2h.1M235.5 294.5h.4M235.5 280.1h.1M235.5 287.9h.4M235.5 298.9h.4M235.6 292.3h.1"/>
<path d="M235.6 292.9h.1M235.6 286.3h.4M235.6 290.7h.4M235.6 295.1h.4M235.6 296.7h.1M235.6 297.2h.1M235.6 288.5h.4M235.6 299.5h.4M235.6 297.3h.1M235.6 280.1h.1M235.7 292.3h.1M235.7 292.9h.2"/>
<path d="M235.7 296.7h.1M235.7 297.3h.2M235.7 280.2h.1M235.7 292.7h.1M235.7 292.5h.1M235.7 297.1h.1M235.7 296.9h.1M235.7 296.8h.1M235.7 292.8v.1M235.7 297.2v.1M235.8 281.9l-3.4 .7M235.8 282.8v.5h-.4"/>
<path d="M235.9 292.9h.1M235.9 292.3h.1M235.9 297.3h.1M235.9 296.7h.1M235.9 281.3l-.1 .1M236 292.3h.4M236 296.7h.4M236.1 292.9h.4M236.1 297.3h.4M236.1 298.3h3.5M236.1 296.1h3.5M236.1 291.7h3.5"/>
<path d="M236.1 289.5h3.5M236.1 293.9h3.5M236.1 287.3h3.5M236.1 285.1h3.5M236.2 285.7h.4M236.2 290.1h.4M236.2 294.5h.4M236.2 287.9h.4M236.2 298.9h.4M236.2 286.3h.4M236.2 290.7h.4M236.2 295.1h.4"/>
<path d="M236.2 288.5h.4M236.2 299.5h.4M236.2 280.1h.1M236.3 280.1h.1M236.3 281.1l-2.5 .6M236.3 280.2h.1M236.4 280.2h.1M236.5 280.2h.1M236.6 280.3h.1M236.6 281.1v.1M236.6 281.4v.2M236.6 280.3h.9"/>
<path d="M236.6 284.8h3.4M236.6 281.6h.1M236.6 281.8l.2 .2M236.7 292.3h.4M236.7 296.7h.4M236.8 292.9h.3M236.8 297.3h.3M236.8 288.5h1.6M236.8 281.1l-.9 .2M236.8 282h.1M236.8 285.7h.5M236.8 290.1h.5"/>
<path d="M236.8 294.5h.5M236.8 287.9h.1M236.8 298.9h.5M236.8 282.1l.3 .1M236.9 286.3h.3M236.9 290.7h.3M236.9 295.1h.3M236.9 299.5h.3M236.9 280.1h.1M237 281.3l.1 .2M237 281l.2 .3M237 280.2h.1"/>
<path d="M237.1 280.2h.1M237.2 286.3h.1M237.2 290.7h.1M237.2 295.1h.1M237.2 299.5h.1M237.2 281.6h.1M237.2 281.5l-1 .1M237.2 281.5h.1M237.2 282.6l-1.6 .3M237.2 280.1h.1M237.3 281.5h.2M237.3 282.3l.1 .1"/>
<path d="M237.4 292.3h.4M237.4 286.3h1.4M237.4 290.7h1.4M237.4 295.1h1.4M237.4 296.7h.4M237.4 299.5h1.4M237.4 281.4h.1M237.4 282.5h.1M237.4 292.9h.4M237.4 297.3h.4M237.4 281.5l.1 .3M237.4 282.4v.1"/>
<path d="M237.4 289.1h3.5M237.5 282v.2M237.6 280.1h.1M237.7 281.2h.1M237.7 280.1h.1M237.7 280.9v.1M237.7 280.2h.1M237.7 291.3h3.5M237.7 283.8h3.5M237.7 293.5h3.5M237.7 286.9h3.5M237.7 295.7h3.5"/>
<path d="M237.7 297.9h3.5M237.8 280.8h.1M237.8 281.4h.1M237.8 280.2h.1M237.9 280.2h.1M237.9 280.1h.1M237.9 292.9h1.3M237.9 297.3h1.3M238 281.4h.1M238 283.7h2M238.1 282.8v.5h.5M238.3 280.7h2.4"/>
<path d="M238.3 281.5h.1M238.3 283.4h2.3M238.3 280h.1M238.4 280.1h.1M238.4 280.2h.1M238.5 281.5h.1M238.5 287.8l-1.7 .1M238.5 280.2h.1M238.5 280.7h.1M238.6 281.7h-.5v.5M238.7 281.6h.1M238.7 280.7l.7 .2"/>
<path d="M238.7 280.7h.1M238.7 281.6l1.5 .5M238.8 280.7h.1M238.8 280.7l1.5 .6M238.8 285.6l-1.4 .1M238.8 290l-1.4 .1M238.8 294.4l-1.4 .1M238.9 298.8l-1.5 .1M239 280.1h.1M239.1 280.2h.1M239.2 281.7h.5v.5M239.2 280.2h.1"/>
<path d="M239.3 292.2l-1.3 .1M239.3 296.6l-1.3 .1M239.3 280.3h3.5M239.7 282.8v.5h-.5M239.7 280h.1M239.8 284.1h4.2M239.8 280h.1M239.8 280.1h.1M239.8 280.1l.1 .1M239.8 280.2h.1M239.9 280.1h.1M239.9 280.2h.1"/>
<path d="M240 280.1h.1M240 280.1v.1M240.1 288.5l1.7 .1M240.2 294.4h1.4M240.2 281.2l1.8 .3M240.3 286.3l1.5 .1M240.3 290.7l1.5 .1M240.3 295.1l1.5 .1M240.3 299.6h1.5M240.3 298.8h1.5M240.4 280h.1M240.4 280.1h.1"/>
<path d="M240.5 292.9l1.3 .1M240.5 297.3l1.3 .1M240.5 280.1h.1M240.5 280.1l.1 .1M240.5 296.6h1.3M240.5 280.2h.1M240.6 280.2h.1M240.7 280.1h.1M240.7 280h.1M241.1 280h.1M241.1 280.1h.1M241.2 280.2h.1"/>
<path d="M241.3 280.2h.1M241.4 298.3h1.7M241.4 296.1h1.7M241.4 291.7h1.7M241.4 289.5h1.7M241.4 293.9h1.7M241.4 287.3h1.7M241.4 285.1h1.7M241.5 283.7h3.7M241.5 280h.1M241.5 280l-.1 .1M241.6 285.6h-1.4"/>
<path d="M241.6 290h-1.4M241.8 292.2h-1.3M241.8 287.8h-1.7M241.8 284.8h1.7v2M241.8 282.7l1.6 .6M241.9 285.6h.5M241.9 290h.5M241.9 294.4h.5M241.9 280.1h.1M241.9 280.2h.1M241.9 281.9l1.7 .5M241.9 292.2h.5"/>
<path d="M241.9 296.6h.5M241.9 287.8h.5M241.9 298.8h.5M241.9 282.8v.5h.6M242 286.4h.4M242 280.2h.1M242 299.6h.4M242 297.4h.4M242 290.8h.4M242 293h.4M242 295.2h.4M242 288.6h.4"/>
<path d="M242.1 280.1h.1M242.4 281.7h-.5v.5M242.5 280.1h.1M242.6 280.1h.1M242.6 280.2h.1M242.7 289.1h.8M242.7 280.2h.1M242.7 285.6h.4M242.7 292.2h.4M242.7 290h.4M242.7 294.4h.4M242.7 296.6h.4"/>
<path d="M242.7 298.8h.4M242.7 287.8h.4M242.8 297.4h.4M242.8 293h.4M242.8 288.6h.4M242.9 280h.1M242.9 280l-.1 .1M242.9 283.4h2.9M243 291.3h.5M243 293.5h.5M243 286.9h.5M243 281.7h.5"/>
<path d="M243 295.7h.5M243 297.9h.5M243 283.3h.6M243.1 298.8h.1M243.1 296.6h.1M243.1 290h.1M243.1 292.2h.1M243.1 294.4h.1M243.1 287.8h.1M243.1 285.6h.1M243.1 280.7h2.4M243.1 298.3h.1"/>
<path d="M243.1 296.1h.1M243.1 289.5h.1M243.1 291.7h.1M243.1 293.9h.1M243.1 287.3h.1M243.1 285.1h.1M243.2 281.5l.9 .1M243.2 298.7h.1M243.2 296.5h.1M243.2 289.9h.1M243.2 292.1h.1M243.2 294.3h.1"/>
<path d="M243.2 287.7h.1M243.2 285.5h.1M243.2 286.4h-.4M243.2 290.8h-.4M243.2 289.6h.1M243.2 291.8h.1M243.2 295.2h-.4M243.2 299.6h-.4M243.2 280l.1 .1M243.3 298.6h.1M243.3 298.4h.1M243.3 296.4h.1"/>
<path d="M243.3 296.2h.1M243.3 289.8h.1M243.3 289.6h.1M243.3 292h.1M243.3 291.8h.1M243.3 294.2h.1M243.3 294h.1M243.3 287.6h.1M243.3 287.4h.1M243.3 285.4h.1M243.3 285.2h.1M243.3 280.1h.1"/>
<path d="M243.3 298.5h.1M243.3 296.3h.1M243.3 287.5h.1M243.3 280.2h.1M243.4 280.2h.1M243.4 293h.1M243.4 286.4h.1M243.4 290.8h.1M243.4 295.2h.1M243.4 288.6h.1M243.4 297.4h.1M243.4 299.6h.1"/>
<path d="M243.4 283.3h.1M243.5 280.2h.1M243.5 280.1h.1M243.5 288.8v3.9M243.5 294.6v3.9M243.5 283.7l-.5 .1M243.5 280.9v1.3M243.5 282.8v.7M243.7 283.3h.5M243.7 282.4l.3 .1M243.9 280.1h.1M244 280.1h.1"/>
<path d="M244 280.2h.1M244 281.8v.2M244 282.2l.1 .1M244.1 280.2h.1M244.1 282.3h.1M244.3 280h.1M244.3 280l-.1 .1M244.3 282.4v.1M244.6 281.9v.5M244.6 282.7l1.6 .1M244.6 289.1v2.5M244.6 292.7v1.6"/>
<path d="M244.6 296.1v3.5M244.6 282.3h2.2M244.6 281.2h1.8M244.6 280.1h.1M244.7 280.2h.1M244.8 281.8v.1M244.8 281.8h.1M244.8 281.9h.1M244.8 281.6h.1M244.8 281.6v.2M244.8 280.2h.1M244.9 280.1h.1"/>
<path d="M245 282.1h1.7M245 282.1h.1M245 281.4h.1M245.1 286.7v.1M245.1 285.9l.1 .1M245.1 289.6h.1M245.1 290.2h.1M245.1 289.7h.1M245.1 296.8h.7l.1 .3M245.1 287.2v.8h.8M245.1 290.4v.9h.8v-.3M245.1 294.8v.8l.8-.2"/>
<path d="M245.1 296.8v.9M245.1 298.6v.8l.8-.2M245.1 297.9h.2M245.1 296.8h.1M245.1 294h.1M245.1 294.6h.1M245.1 282h.1M245.1 289.7h.2M245.1 283.8h-.5v2.6M245.1 294.6h.3M245.1 294.1h.2M245.2 286.9h.1"/>
<path d="M245.2 282.2h.1M245.3 281.9h.1M245.3 282.2l.1 .1M245.3 290.2h-.2M245.3 280.1h.1M245.4 287h.1M245.4 281.8l-.1 .1M245.4 298.4l-.3 .1M245.4 280.1h.1M245.4 283.3h-.2M245.4 286.3l.2 .2M245.4 280.2h.1"/>
<path d="M245.4 283.3h.1M245.4 283.3h.3M245.4 283.3h-.7M245.5 287h.1M245.5 280.2h.1M245.5 281.7h.1M245.5 289.7h.2M245.5 294.1h.2M245.6 286.5h.1M245.6 290.2h.1M245.6 297.9h.2M245.6 294.6h.1"/>
<path d="M245.6 282.4h.3M245.7 286.5h.1M245.7 281.6l-.2 .1M245.7 298.4h.1M245.7 280.7h.1M245.7 283.2h.1M245.7 283.2l-.1 .1M245.8 287h.1M245.8 289.7h.1M245.8 290.2h.1M245.8 294.1h.1M245.8 294.6h.1"/>
<path d="M245.8 286.9v.1M245.8 286.5v.1M245.8 294.4l.2 .4M245.8 290.1v.1M245.8 289.7v.1M245.8 290l.2 .4M245.8 286.8l.2 .4M245.8 283.3h.1M245.8 298.2l.2 .4M245.8 294.5v.1M245.9 281.6h.1M245.9 283.8h.7"/>
<path d="M245.9 285.5h-.8v.8M245.9 293h-.8v.9M245.9 283.3h.2M245.9 290.4v.3M245.9 290.4h.1M245.9 287.2h.1M245.9 288h.1M245.9 288.9v-.3h-.8v.9M245.9 287.2v.2M245.9 287.7v.2M245.9 289.1v.1M245.9 294.8h.1"/>
<path d="M245.9 297.3v.1M245.9 298.6v.3M245.9 293v.2M245.9 293.5v.1M245.9 294.8v.3M245.9 280.8h.1M245.9 285.5v.2M245.9 285.8v.2M246.1 281.6h.1M246.1 280.1h.1M246.1 293.6h-.3v.6M246.1 297.4h-.3v.6"/>
<path d="M246.2 289.2h-.4v.4M246.2 284.1h4.2M246.2 281.7h.1M246.2 298.6l.3 .1M246.2 280h.1M246.2 290.4h.3M246.2 280.9l.2 .1M246.3 291.6h3.5M246.3 281.7h.1M246.3 292.7h3.5M246.3 297.4l.5 .2M246.3 293.6l.5 .1"/>
<path d="M246.3 282.3l-.2 .1M246.4 282.3h.1M246.4 293v.2M246.4 293.4v.2M246.4 289l-.1 .2M246.4 287.2v.2M246.4 287.7v.3M246.4 288.6v.2M246.4 285.9l-.6 .1v.3M246.4 285.5v.2M246.4 294.8v.2M246.4 295.4v.2"/>
<path d="M246.4 298.6v.3M246.4 299.2v.2M246.4 290.4v.2M246.4 291v.3M246.4 296.8v.2M246.4 297.2v.2M246.5 282.4h.1M246.5 281.7h.1M246.5 287.2h-.3M246.5 283l-.2 .2M246.5 283.7h.1M246.5 294.8h-.3"/>
<path d="M246.5 286l.3 .2M246.5 289.2l.3 .1M246.5 281.1l.1 .1M246.5 281.1h.1M246.6 282.4h.1M246.6 281.6h.1M246.6 282.5h.1M246.6 282.2v.5M246.6 281.5h.1M246.6 281.4v.4M246.6 281.4h.1M246.7 287.2h.1"/>
<path d="M246.7 290.4h.1M246.7 298.7h.1M246.8 285.5h.8v.8M246.8 288.6h.8v.9M246.8 293h.8v.9M246.8 296.8h.8v.8M246.8 284.6v.9M246.8 284.4l.1 .3M246.8 284.4h.1M246.8 293.9v.3l.3-.1M246.8 297.8v.2M246.8 286.4v.2"/>
<path d="M246.8 283.8h.2M246.8 281.4h-1.8M246.8 290.4h.1M246.8 287.2h.1M246.8 287.1h.1M246.8 289.6v.3M246.8 285.5h.1M246.8 294.6h.1M246.8 298.4h.1M246.8 283.1v.9M246.8 286.9l.3 .1M246.8 290v.3"/>
<path d="M246.8 294.4v.2M246.8 294.7l-.1 .1M246.8 298.2v.2M246.8 298.6v.1M246.8 298.4h.3M246.8 294.6h.3M246.8 290.2h.3M246.8 286.5h.3M246.8 297.9h.3M246.8 289.7h.3M246.9 283.1h.1M246.9 299.9l-.1 .4"/>
<path d="M246.9 284.7v.1M247 280.2v.3M247 283.8l-.2 .3M247 280.6v.1M247 283.5h.1M247 283.5l-.2 .1M247.1 280.8v.1M247.1 280.8h.1M247.1 280.6l.3 .3M247.1 280.6h.1M247.1 283.7l-.1 .1M247.2 285l.4 .1"/>
<path d="M247.2 285h.1M247.2 281l.1 .1M247.2 281h.1M247.2 299.6l-.4 .7M247.2 282.7h.9M247.2 285.9h.8M247.3 299.6h.1M247.3 299.6h.7M247.3 281.1h.1M247.3 283.5h.5M247.3 298.4h.3M247.3 294.6h.3"/>
<path d="M247.3 290.2h.3M247.3 287h.3M247.4 280.4l.2 .2M247.4 286.5h.2M247.4 297.9h.2M247.4 294.1h.2M247.4 289.7h.2M247.4 280.9h.1M247.6 281.2h.4M247.6 281.2h.1M247.6 280.2l.1 .2M247.6 287.1v.9h-.8"/>
<path d="M247.6 290.4v.9h-.8M247.6 294.8v.8h-.8M247.6 298.6v.8h-.8M247.7 283l-.5 .5M247.7 281l.5 .1M247.7 283.7h3.5M247.8 283.5h.1M247.8 280.6h.1M247.9 285.1h.1M248 282.8h3.5M248.1 283.7h.1M248.1 299.6h.1a.87 .87 0 0 1-.1 1.5"/>
<path d="M248.1 283.7l.1 .1M248.2 283.8l.1 .1M248.2 283.8h.1M248.2 284.8l-.3 .3M248.3 282.1h1.5M248.4 284.1h.1M248.4 281.2h.3M248.4 284.5h.1M248.4 284.3h.1M248.4 284.3v.2M248.4 280.8h.3M248.4 283.1l.1 1"/>
<path d="M248.4 283.1h.1M248.4 281.1h.3M248.5 284.6l-.1 1M248.5 283.8h2M248.7 282l-.5 .4M248.8 283.4h-2.2M249.2 280.4l-1.4 .3M249.3 280.8h.9M249.3 281.1h.9M249.3 280.8h.8M249.6 288.5v.6h.7M249.6 294.6v.6h.7"/>
<path d="M249.6 299.9h.1M249.6 287.6h.1M249.6 293.8h.1M249.7 288.6h.1M249.7 294.8h.1M249.7 299.9l.1 .1M249.7 287.6h.1M249.7 293.8h.1M249.8 294.7l-.1 .1M249.8 300h.1M249.8 293.8h.1M249.9 287.7h.1"/>
<path d="M249.9 293.8h.1M249.9 288.5h.1M249.9 294.6h.1M249.9 287.7l.1 .1M249.9 293.9l.1 .1M250 288.4l-.1 .1M250 287.8h.1M250 294h.1M250.1 288.3h.1M250.1 294.5h.1M250.1 288v.2M250.1 294.1h.1"/>
<path d="M250.1 294.2v.1M250.2 282.1h.3M250.3 299.4h-.7v.7M250.3 287.1h-.7v.6M250.3 293.2h-.7v.7M250.4 283.4h1.5M251 299.4h.6v.6M251 287.1h.6v.6M251 293.2h.6v.6M251.1 281.1l-2.5 .3M251.1 294.3h.1M251.1 288.1h.1"/>
<path d="M251.1 280.8h.9M251.1 294.2v.1M251.1 288.1v.1M251.2 280.8h.8M251.2 281.1h.8M251.2 288.2h.1M251.2 294.4h.1M251.2 287.8h.1M251.2 280.8l-.8 .4h-2M251.2 294h.1M251.2 288.4l.2 .1M251.2 288.4h.1"/>
<path d="M251.2 294.6h.1M251.3 287.7h.1M251.3 287.7l-.1 .1M251.3 293.9h.1M251.3 293.9l-.1 .1M251.3 294.6l.1 .1M251.5 282.1h-.6M251.5 287.6h.1M251.5 293.8h.1M251.5 282.2l-2.5 .1M251.5 300h.1M251.5 292.7h1.7v2"/>
<path d="M251.5 288.6h.1M251.5 294.8h.1M251.5 299.9h.1M251.6 288.6h.1M251.6 288.4v.7h-.6M251.6 294.6v.6h-.6M251.6 294.8h.1M252 283.1l-.1 .3M252 283l-.1 .4M252.3 281.9l-.4 .1M252.3 283.8h1.7l-.2 .9M252.3 282.4l-.1 .3"/>
<path d="M252.4 282.2h.1M252.4 282.2l-.1 .3M252.5 281.9h.1M252.5 284.1h2.3M252.6 280.8h.1M252.6 281.9h.5M252.6 281.7h.1M252.6 281.1h.1M252.6 282.2h.5M252.8 282.1l-.9 .1M252.8 280h.4M252.8 280.5h.1"/>
<path d="M252.8 280.5l-.8 .3M252.8 281.1h.1M252.8 281.3l-.1 .2M252.8 280.8h.1M252.9 280.8h.1M253 281.2l.1 .1M253 281.2h.1M253 283.7h1.8M253 288.5l.2 1.1M253.1 281l.1 .1M253.2 281.5l.2 .2M253.2 291v.6h-1.7"/>
<path d="M253.2 289.6v.6M253.2 281.1h.1M253.2 296.8l-.2 3.1M253.3 280.4l-.3 .1M253.3 280.2l-1.1 .3M253.4 282.1h.5M253.4 281.3h.1M253.4 289.6h.3M253.5 286.6h.2M253.5 281.3h.1M253.5 298.9h.2M253.5 285.7l-.2 .9h-.3v.9"/>
<path d="M253.5 281.9h.5M253.6 280.4h.4M253.6 281.4l.1 .1M253.6 280.2h.4M253.7 289.6h.1M253.7 286.6v1.2M253.7 298.9v1.3M253.7 288.9h.1M253.7 281.5h.1M253.7 287.3l.1 .5M253.7 298.8h.1M253.7 299.6h.1"/>
<path d="M253.7 299.6l.1 .6M253.7 287.3h.1M253.7 288.4v1.2M253.7 282.2h.6M253.8 286.4l-.1 .2M253.8 288.4l-.1 .5M253.8 289.7v.1M253.8 298.7h.1M253.8 289.8l.2 .1M253.8 289.8v.1M253.8 291.7v3.5M253.8 297v1.7"/>
<path d="M253.9 281.4h.1M253.9 281.7l-.3 .1M254 281.3h-.1M254 282.1h.1M254 286.2l-.1 .1M254 298.5l-.2 .2M254 280.2h.1M254 280.5h.1M254 281.9h.1M254.1 281.6l.1-.3-.1 .6M254.1 280.5h.1M254.1 281.9h.1"/>
<path d="M254.1 290l.1 .2M254.1 280.2l.2 .2M254.1 282.1h.1M254.2 281l-.1 .1M254.2 280.6v.4M254.2 286l-.2 .2M254.2 280.9v.1M254.2 285.5l-.2 .7M254.2 282l-.1 .1M254.2 285v1.9M254.2 298.3l-.1 .1M254.3 280.4h.1"/>
<path d="M254.3 282.2h.1M254.3 281.9v.1M254.3 281.9h.1M254.3 281.8h.1M254.4 281.5h.1M254.4 281.8h.1M254.4 281.7h.1M254.4 280.5v.4M254.4 282.4l-.1 .4h-1M254.5 280.7h-.2M254.5 281l-.1 .6M254.5 281.4h.1"/>
<path d="M254.5 281.4h.2M254.5 281.5h.1M254.5 281.1v.3M254.6 280.7l-.1 1.3M254.6 283.9l-.2 .9M254.6 280.8h.1M254.7 280.2l-.2 .6M254.7 285.2l-.3 .6M254.8 280.5h.1M254.9 283l-.2 .8M254.9 280.6l.2 .5M254.9 284.1h.1"/>
<path d="M254.9 284.3l-.1 .4M255 281.1h.1M255 281.3l-.1 .1M255 283.7h.1M255.2 281.7l-.1 .6M255.2 281.7h.2M255.2 281.1v.2M255.2 281.5v.2M255.4 281.1h.2M255.6 281.8h.1M316.5 281.7l.1 .5M316.5 285.5h.1"/>
<path d="M316.6 284.8h.1M316.6 283h.1M316.6 283.5v.1M316.6 283.8v.6M316.6 280.8v1.5M316.6 283.6h.1M316.6 283.3v-.5v.7M316.6 285v.5v-.5M316.9 283.5h.1M316.9 282v1.5M316.9 283.5l-.1 .1M316.9 283.9h-.3v.5"/>
<path d="M317.2 283.5h.2M317.2 283.9h.4M317.4 282v1.5M317.4 283.5v.1M317.5 283.8l.1 .1M317.6 282.4v1.5M321.5 284.4v.4h1.9M321.5 283v.8M323.5 282h-2v.5M324.6 281.5h.1M324.6 285.3h.1M324.6 283.1v1.6"/>
<path d="M324.6 280.6v1.6M324.6 285.6v.8M324.6 283.9h.9M324.8 284.7l-.1 .6M324.8 281.5v.7M324.8 282.8v1.2M324.8 281.5h.1M325.5 284.8h1.9M325.5 282h1.9M326.6 283.9h.8M327.4 280.8v.4M327.8 282.6h1"/>
<path d="M327.8 286h1M327.8 280.4h1M327.8 281.2h1M327.8 299.4h1M327.8 294.4h1M327.8 281.6h1M327.8 296.4h1M327.8 296.9h1M329.8 284.8h.1M329.8 284.3h.1M329.8 284.5v.1M329.8 283.8h.1"/>
<path d="M329.8 284v.1M329.8 284.2v.1M329.8 284.7v.1M329.8 299.8h.1M329.8 300v.1M329.9 299.6h.1M329.9 283.6h.1M329.9 284.9v.1M329.9 286h1.1M329.9 280.4h1.1M329.9 281.6h1.1M329.9 296.4h1.1"/>
<path d="M329.9 282.6h1.1M329.9 294.4h1.1M329.9 296.9h1.1M330 285.1h.1M330.1 299.5h.1M330.1 283.5h.1M330.1 285.1h.2M330.1 299.5h.3M330.1 283.5h.3M330.7 285.1h.3M330.7 283.5h.4M331 290v.2"/>
<path d="M331 290.4l.1 .2M331 288.2l.1 .2M331 297l.1 .2M331 296.6v.2M331 298.8v.2M331 298.8h.1M331 290h.1M331 297.6h.3M331 296.6h.1M331 289.7h.3M331 288.1l.9 .1M331 287.1l.1 .1"/>
<path d="M331 287.8h.1M331 285.6h.1M331 285.1h.1M331 299.4h.1M331 292.6l.1 .5 .4 .1M331 299.6v.2M331 285.7h1.6M331 281.7h.7M331 280.1h.3M331 292.8h.1M331 292.2h.1M331 282.4h.1"/>
<path d="M331.1 286.5h.1M331.1 285.9h.1M331.1 286.5l.6 .1M331.1 285.9h.4M331.1 284.7v.3M331.1 286.4v.8M331.1 287.7v1M331.1 283.3h.1M331.1 282.9h.1M331.1 280.9h.1M331.1 280.3h.1M331.1 286.6h.1"/>
<path d="M331.1 282.5h.1M331.1 281.9h.1M331.1 281.9l1.8 .1M331.1 283.3h.4M331.1 282.5h.4M331.1 280.9h.4M331.1 286.6l.4 .1M331.1 282.3v.6M331.1 283.5h.1M331.1 283h.1M331.1 280.8h.1M331.1 280.4h.1"/>
<path d="M331.1 281.3l-.1 .1M331.1 286h.1M331.1 285.5h.1M331.1 286.3v.9M331.1 287l1.2 .1M331.1 290.3v.7l.8 .1M331.1 299.5h-.4M331.1 280.7v.9M331.1 297.6v.6M331.1 298.7v.5M331.1 284.1h.1M331.1 284.1h.2"/>
<path d="M331.1 286l.4 .2M331.1 283.4h.1M331.1 282.8h.1M331.1 282.8h.2M331.1 283.4v.2M331.1 283.9v.7M331.1 285.4h.1M331.2 285.1h.1M331.2 282.4h.1M331.2 285.7l-.1 .1M331.2 286.7h-.1M331.2 281.1h.1"/>
<path d="M331.3 281.6h.1M331.3 290h.2M331.3 280.2h.1M331.3 283.7h.1M331.3 287.3h.4M331.3 284.8h.2M331.3 287.6h.4M331.3 296.6h.2M331.3 299.5h.1M331.3 280.2l.2 .1h-.4M331.3 289.6h.1M331.3 283.5h.1"/>
<path d="M331.3 287.8h.2M331.3 285.6h.2M331.3 299.4h.1M331.3 299.4h-1.4M331.3 292.2h.2M331.3 281.1v.7M331.3 298.3h.2M331.3 290.2h.2M331.3 280.2v.4M331.3 282.1v1.1M331.3 284v2.9M331.3 291.6v.5"/>
<path d="M331.3 294.4v.2M331.3 294.9v.1M331.3 295.4v.3M331.3 296v.2M331.3 297.2v2.1M331.3 299.8v.4M331.3 281.1h-.1M331.3 281.3h.1M331.3 285.6v.2M331.3 290.4l.2 .2M331.3 290v.2M331.3 288.2l.2 .2"/>
<path d="M331.3 287.8v.2M331.3 292.7v.5M331.3 292.6l.2 .2M331.3 292.2v.2M331.4 281.2h.1M331.4 283.8h-.1M331.4 285.2h.1M331.4 296.9l.1 .3M331.4 281.2h.3M331.4 296.2l-.1 .6M331.4 281h.3M331.5 289.1l-.2 2.1"/>
<path d="M331.5 299.4h.1M331.5 282.8h2.2M331.5 281.6h.1M331.5 299.4l-.5-.2v.3M331.5 283.7h.2M331.5 285.2h.1M331.5 292.7h.1M331.5 289.6h.2M331.5 287.1l-.4 .1M331.6 285.4l.4 .2M331.6 299.2h.3M331.6 297.6h.3v.6"/>
<path d="M331.6 281.7l.9 .1M331.6 280.1l.4 .1M331.6 286h.2M331.6 282.3h.2M331.6 283.5h.1M331.6 283.6h.1M331.6 288.4h.3M331.6 295h.1M331.6 288.2v2.2M331.6 294.8v.6M331.6 294.4h.2M331.6 287.8h.2"/>
<path d="M331.6 291.6l-.5 .1-.1 .7M331.6 283l.2 .3M331.6 288.6h.1M331.6 291.3h.1M331.6 288h.1M331.6 283.7v1.3M331.6 286.5v1.5M331.6 292.4v2.2M331.6 295.9v.3M331.6 297.2v.7M331.6 298.6v1.3M331.6 298.5h.2"/>
<path d="M331.6 283.8h-.1M331.6 289.1h.4M331.6 296.8h.1M331.6 299.4h.1M331.6 299.1v.1M331.6 295.6h.1M331.6 293h.1M331.6 295.2h.1M331.6 293.2h.1M331.6 280.2h.2M331.7 298.8h.3M331.7 290h.3"/>
<path d="M331.7 296.6h.3M331.7 287.8h.3M331.7 287.2h.9M331.7 292.2h.3M331.7 281.2h-1.8M331.7 290.6h.3M331.7 297.2h.3M331.7 286.2h.3M331.7 292.8h.3M331.8 284.8h.2M331.8 298.9l-.5 .1M331.8 282.1l-.2 .8h-.5"/>
<path d="M331.8 298.7l-.2 .5M331.8 286.7v.5M331.8 297.6v.6M331.8 282.9h.1M331.8 280.9h.1M331.8 280.3h.1M331.8 284.1v.5M331.8 285.2v1M331.8 288.1v.6M331.8 289.2v.5M331.8 283.4h.1M331.8 282.8h.1"/>
<path d="M331.8 280.1v.6h-.7M331.8 281.2v.5M331.8 285.4h.1M331.9 281.2h.1M331.9 295h.1M331.9 288.4h.1M331.9 288h.1M331.9 284.7l-.8 .1-.1 1.4 .1-.8M331.9 283.5h.1M331.9 283h.1M331.9 280.8h.1M331.9 290.2h.4"/>
<path d="M331.9 288.8h-.8v.9M331.9 283.4h.1M331.9 282.9h.1M331.9 296.8h.1M331.9 299.4h-.4M331.9 286h.1M331.9 285.5h.1M331.9 295.6h.1M331.9 293.2h.1M331.9 287.8l1 .1M331.9 298.7v.5M331.9 298.5h.1"/>
<path d="M331.9 289.4v.3h-.3M331.9 283.3l.1 .4M331.9 285.2v.3h.7l-.4 .1M331.9 280.4v.1M331.9 280.7v.9M331.9 284.1h-.3M331.9 280.4h.1M331.9 283.9v.7M331.9 283.3h.1M331.9 282.1h.1M332 287.4h.1M332 286.9h.1"/>
<path d="M332 287.2h.1M332 291.1h.1M332 290.7h.1M332 288.4h.1M332 288.5h.1M332 287.7v.1M332 287.1h.1M332 288.9h.1M332 297.9h.1M332 288.6h.1M332 299.1h.1M332 299h.1"/>
<path d="M332 298.7v.1M332 296.2h.1M332 295.7h.1M332 294.8h.1M332 289.6h.1M332 289.1h.1M332 289.7h.1M332 290.2v.1M332 297.2h.1M332 292.3h.1M332 299.6h.5M332 290h.3"/>
<path d="M332 298.1l.3 .1M332 291h.1M332 290.4l-.1 .9M332 290.8h.1M332 289.4v.8M332 296.6l1.1 .1M332 285.7h.1M332 297.3h.1M332 296.5h.1M332 292.9h.1M332 289.9h.1M332 285.5h.1"/>
<path d="M332 286.4h.1M332 294.7h.1M332 297.4h.3M332 297.7h.1M332 294.1h.1M332 294.6h.1M332 294.6v.1M332 294h.1M332 291.3h.1M332 290.4h.1M332 297v.8M332 288.6l-.1 .4"/>
<path d="M332 290.5h.1M332 290.1h.1M332 287.8h.1M332 286.2h.1M332 285.6h.1M332 295h.1M332 299.6h.1M332 282h.1M332 282.8h.1M332 283.4h.1M332 298.4h.1M332 298.5h.1"/>
<path d="M332 286.3h.1M332 285.1h.1M332 286.5h.1M332 287h.1M332 296.8h.1M332 295.1h.1M332 294.3v.1M332 286.4h.3M332 281.5v.7M332 283.2l.1 .3M332 288.2v.9M332 294.4v.2"/>
<path d="M332 294.8v.9M332 295.5h.1M332 293.3h.1M332 299.9h.1M332 293.8h.1M332 280.5h.1M332 290.2h.1M332 286h.1M332 284.1h.1M332 283l-.1-.7v.9M332 292.6v.8M332 289.2h.1"/>
<path d="M332 296.9h.1M332 287.3h.1M332 281.4h.1M332 282.1h.1M332 293.6h.1M332 282.5h.1M332 294.8h.3M332 297.4h.1M332 298.9h.1M332 292.1h.1M332 293h.1M332 294.3h.1"/>
<path d="M332 295.2h.1M332 298.7h.1M332 287.2v.8M332 298.2v2M332 287.3h.6M332 287.6h.1M332 290.3h.1M332 286.7h.1M332 285.9h.1M332 280.4h.1M332 281.5h.1M332 281.9h.1"/>
<path d="M332 282.2h.1M332 299.8h.1M332 296.6h.1M332 296.7h.1M332 294.4h.1M332 292.7h.1M332 292.8h.1M332 298.1h.1M332 295.8h.1M332 293.7h.1M332 291.8h.1M332 289.2h.3"/>
<path d="M332 284.8h.1M332.1 281.2h.3M332.1 287.1h.4M332.1 284.1v-.6l-.1 3.3M332.1 282.9h.1M332.1 285.6h.2M332.1 286.4h.1M332.1 296.6h.1M332.1 287.8h.1M332.1 298.8h.1M332.1 285.9h.5M332.1 283.3l1.3 .1"/>
<path d="M332.1 280.9h.5M332.1 282.9l.5 .1M332.1 280l.4 .1M332.1 295.2h-.2M332.1 296.1l-.1 .7M332.1 293.9l-.1 .4M332.1 299.1l-.2 .1M332.1 286.4h.2M332.1 288.6h.1M332.1 287.8h.3M332.1 290.8h.2M332.1 295.2h.2"/>
<path d="M332.2 289.9h.1M332.2 286.9h.1M332.2 290h.2M332.2 297.9h.1M332.2 290v.2M332.2 287.6h.4M332.2 288.8h1.2l.1 .8M332.2 290.4h.1M332.2 293.5h.1M332.2 291.3l.1 .1M332.2 291.8h.1M332.2 292.2h-.2"/>
<path d="M332.2 292.2h.2M332.2 298.4h.1M332.2 294.1h.1M332.2 289.7h.1M332.2 292.2h.1M332.2 287h.1M332.2 299.8h.1M332.2 282.5h.1M332.3 280.4h.1M332.2 296.5h.1M332.2 299.4h.2M332.2 284.1h.2"/>
<path d="M332.2 290.6h.1M332.2 297.2h.1M332.2 298.3l.1 .3M332.2 286.2h.1M332.2 287.3l.1 .8M332.2 280.5h.1M332.2 292.8h.1M332.2 282.5v.5M332.2 283.5l.1 1.1M332.2 296.1h.1M332.3 286.2h.1M332.3 286.4h.1"/>
<path d="M332.3 285.7h.1M332.3 285.5h.1M332.3 287h.1M332.3 285.9v.1M332.3 290.1h.1M332.3 292.3h.1M332.3 294.6h.1M332.3 294.5h.1M332.3 287.7v.1M332.3 288.4v.1M332.3 297.4h.1M332.3 296.9h.1"/>
<path d="M332.3 296.8h.1M332.3 285.9h.1M332.3 297.2h.1M332.3 297.3h.1M332.3 296.7h.1M332.3 296.5h.1M332.3 294.3l-.2 .1M332.3 295.2h.1M332.3 295.1h.1M332.3 294.3h.1M332.3 290.7h.1M332.3 289.9h.1"/>
<path d="M332.3 290.2v.1M332.3 292.9h.1M332.3 292.8h.1M332.3 292.1h.1M332.3 293h.1M332.3 289.5v.4M332.3 290.1v2M332.3 288.6h.1M332.3 287.7h.1M332.3 294.6v.1M332.3 293.6h.1M332.3 293h-.4"/>
<path d="M332.3 293v.4M332.3 284.8h.1M332.3 284.1h.1M332.3 297.4v.4M332.3 298.2v.5M332.3 286h.1M332.3 294.8h.1M332.3 298.7h.1M332.3 299.1h.1M332.3 295.8h.1M332.3 291.1h.1M332.3 289.2h.1"/>
<path d="M332.3 287.1h.1M332.3 298.9h.1M332.3 298.9v.4M332.3 290.5h.1M332.3 291.3h.1M332.3 288.3v.7M332.3 286.4v.4M332.3 285v.2M332.3 297.9h.1M332.3 298h.1M332.3 298.8h.1M332.3 289.3l-.4 .3"/>
<path d="M332.3 296v.2M332.3 286.9h.1M332.3 286.5h.1M332.3 285.6h.1M332.3 286.3h.1M332.3 286.7h.1M332.3 285.6l-.1 .1M332.3 286v.2M332.3 286.4v.1M332.3 286.6v.2M332.3 287.1v.1M332.3 287.4v.2"/>
<path d="M332.3 297.1v.1M332.3 298.8v.2M332.3 299.3v.3M332.3 293.5h.1M332.3 292.7h.1M332.3 287.8h.1M332.3 287.6h.1M332.3 288.7l-.1 .2M332.3 288.7h.1M332.3 287.2h.1M332.3 288.5h.1M332.3 289.7v.1"/>
<path d="M332.3 299.8v.1M332.3 299.8h.1M332.3 287.7v.3M332.3 288.1v.1M332.3 289.1v.1M332.3 282.2h.2M332.3 280.5h.1M332.3 281.5h.1M332.3 294.7h.1M332.3 293.8h.1M332.3 296.3v.1M332.3 294.4h.1"/>
<path d="M332.3 294.2h.1M332.3 295.3v.1M332.3 290.9v.1M332.3 290.8h.1M332.3 290.6h.1M332.3 290.3h.1M332.3 292h.1M332.3 290.4h.1M332.3 289.9v.3M332.3 290.4v.2M332.3 292.1v.3M332.3 292.6v.2"/>
<path d="M332.3 295.7v.1M332.3 296.5v.3M332.3 281.9h.1M332.3 295v.1M332.3 285.5h-.3M332.3 293.7v3.5M332.3 285.3v.1M332.3 299.9h.1M332.3 299.6h.1M332.3 283.5v.6M332.3 284.2v.2M332.3 293l.1 .2"/>
<path d="M332.3 293.7l-.1 .2M332.3 284.6v.2M332.3 291.5v.3M332.3 293.4v.1M332.3 294v.2M332.3 299.7v.1M332.3 295h.1M332.3 291.7h.1M332.3 282.6h.2M332.3 281.5l-.1 .6M332.3 280.2v.2M332.3 282.3v.7"/>
<path d="M332.3 289.1h.1M332.3 298.3h-.4M332.3 285.1v.7M332.3 280.5l.1 .5h-.3M332.3 280h.1M332.3 299.4h.1M332.3 288.4h.1M332.4 288.5l-.3 .1M332.4 283.9v.2M332.4 286.4h.1M332.4 286.3l-.3 .1M332.4 290h.3"/>
<path d="M332.4 297.3l-.2 .1M332.4 283.5h-.9M332.4 290.8h.1M332.4 280.5h.1M332.4 295.2h.2M332.4 281h.1M332.4 292.2h.3M332.4 292.9l-.2 .1M332.4 298.6l-.4 .1M332.4 280h.1M332.4 295.6l-.2 .1M332.4 289.1h-.2"/>
<path d="M332.4 288.6h.1M332.4 283v.8M332.4 281.5h.1M332.4 281.7v.7M332.4 281.4h.1M332.4 280.5v.3M332.4 281.1v.3M332.5 297.4h.1M332.5 293h.1M332.5 280.9h.1M332.5 280.4h.1M332.5 280.1h.1"/>
<path d="M332.5 280.8h.1M332.5 298.5l.1 .1M332.5 291.7h-.5v.7M332.5 291.7h.1M332.5 286.7h.1M332.5 295h.1M332.5 284.8h.1M332.5 288h.1M332.5 296.8h.1M332.5 299.4h.1M332.5 288.4h.1M332.6 286.6l-.5 .1"/>
<path d="M332.6 280.6v.9l-.3 .1M332.6 285.4v.8M332.6 282.3v.6M332.6 284.6v.4M332.6 286.6v.1M332.6 292.7l-.1 .5h-.4M332.6 296.2h.1M332.6 298.7h.1M332.6 287.7l-.1 .5h-.4M332.6 286.4v.8M332.6 291.7v.4M332.6 285.6v.1"/>
<path d="M332.6 281.4h-.4M332.6 288.6h.1M332.6 291.3h.1M332.6 295.6h.1M332.6 293.2h.1M332.6 281.1h.1M332.6 281.1h-.1M332.6 288.2h.1M332.6 288.3l-.2 1.3M332.6 285.2v.8M332.6 290.6v1.1M332.6 293.2v.3"/>
<path d="M332.6 294v.6M332.6 294.8v1.4M332.6 297.4v2.8M332.6 286.5l-.7 .1M332.6 280.9l.1-.2 1.1 .1v.3M332.6 283.1h.1M332.6 284.7h.8l.1 .8M332.6 282.4l-.5 .1M332.6 280.3v.2M332.6 281.9v.2M332.6 287.1v.1M332.6 289.8l-.1 .1"/>
<path d="M332.6 281.9h.2M332.6 298.9l-.1 1M332.6 289.1h-.1M332.7 281.7l.5 .1M332.7 294.4h-.8M332.7 282.2h.2M332.7 280.4h.1M332.7 280.1h.1M332.7 286.3l-.2 .1M332.7 285.7h.2M332.7 290l.2 .1M332.7 297.3l-.2 .1"/>
<path d="M332.7 294.4l.2 .1M332.7 281.6l.1 .1M332.7 280.7v.2M332.7 292.2l.3 .1M332.7 296.2h.1M332.7 298.7h.1M332.7 281v2.1M332.7 292.9l-.2 .1M332.7 298.7l.2 .1M332.7 296.4l.2 .1M332.7 284l-.1 .6M332.7 283.7v.1"/>
<path d="M332.8 280.8h.1M332.8 282.4h.1M332.8 283.7h.1M332.8 283v.5h.4M332.8 282.2l-.1 .4M332.8 281.2v.9M332.8 282.7v.6M332.8 283.2l.6 .1M332.8 282.3h.1M332.8 281.5h.4M332.8 280.7l.1 .3M332.8 281.1h.1"/>
<path d="M332.8 281.3l-.1 .1M332.8 281.5h.1M332.8 283.6v.1M332.8 281.9h.1M332.8 282.2h.1M332.8 281.9v.1M332.9 280.6h.1M332.9 280.5h.1M332.9 281.2v.5M332.9 281.9v.3M332.9 282.4v.4M332.9 280.2v.3"/>
<path d="M332.9 281.2h.5M332.9 282.5h-.1M332.9 286.3h-.3v.6M332.9 290.7h.1M332.9 290.7l-.8 .1M332.9 288.5h.1M332.9 299.5h.1M332.9 298.9h-1M332.9 299.5l-.8 .1 .2 .8M332.9 288.5l-.5 .1M332.9 295.1l-.8 .1M333 285.7h.1"/>
<path d="M333 286.3h.1M333 285.6l.2 .1M333 290.1h.1M333 287.9h.1M333 298.9h.1M333 286.1h.1M333 285.9h.1M333 286.2h.1M333 292.3h.1M333 290.7h.1M333 296.6l.2 .1M333 290l.2 .1"/>
<path d="M333 294.5h.1M333 288.5h.1M333 299.5h.1M333 287.8l.2 .1M333 298.8l.2 .1M333 295.1h.1M333 294.4l.2 .1M333 297.1h.1M333 296.9h.1M333 294.9h.1M333 294.7h.1M333 295h.1"/>
<path d="M333 290.5h.1M333 290.3h.1M333 290.6h.1M333 292.7h.1M333 292.5h.1M333 292.8h.1M333 288.3h.1M333 288.1h.1M333 288.4h.1M333 299.3h.1M333 299.1h.1M333 299.4h.1"/>
<path d="M333 292.2l.2 .1M333 280.3h-.9l.4 .1M333 280.8h.1M333 283.7h.1M333 296.7v.2M333 294.5v.2M333 298.8l.5 .1M333 296.6h.3M333 280.9h.1M333 280.9h-.1M333 280.7h.1M333 280.1l.1 .1"/>
<path d="M333 283.7v2.2M333 288.2v4.3M333 294.8v4.4M333.1 281.4h.1M333.1 280.8h.1M333.1 285.7h.1M333.1 286.3h-.1M333.1 286.3h.1M333.1 296.7h.1M333.1 290.1h.1M333.1 292.3h.1M333.1 285.7l-.1 .2"/>
<path d="M333.1 292.9h-.4M333.1 297.3h-.4M333.1 297.3h.1M333.1 290.7h.1M333.1 292.9h.1M333.1 287.9h.1M333.1 298.9h.1M333.1 281.1l-.8 .1M333.1 288.5h.1M333.1 299.5h.1M333.1 294.5h.1M333.1 280.2l-.4 .3"/>
<path d="M333.1 295.1h.1M333.1 290.1l-.1 .2M333.1 292.3l-.1 .2M333.1 287.9l-.1 .2M333.1 298.9l-.1 .2M333.1 280.2h.2M333.2 281.1h-.3M333.2 296.5l.1 .8M333.2 296.9h.1M333.2 297v.1M333.2 292.5h.1M333.2 292.6v.1"/>
<path d="M333.2 280.8h.2M333.2 285.7h.1M333.2 285.9h.1M333.2 286v.1M333.2 286.2h.1M333.2 281.4h.1M333.2 297.3h-.2M333.2 290.7h-.2M333.2 292.9h-.2M333.2 288.5h-.2M333.2 299.5h-.2M333.2 296.8h.1"/>
<path d="M333.2 297.1h.1M333.2 297.2h.1M333.2 294.6h.1M333.2 294.7h.1M333.2 294.8h.1M333.2 290.2h.1M333.2 290.4v.1M333.2 290.6h.1M333.2 292.4h.1M333.2 292.7h.1M333.2 292.8h.1M333.2 295.1h-.2"/>
<path d="M333.2 288h.1M333.2 288.2v.1M333.2 288.3h.1M333.2 288.4h.1M333.2 299h.1M333.2 299.2h.1M333.2 299.3h.1M333.2 299.3v.1M333.2 294.9h.1M333.2 295h.1M333.3 290.1h.1M333.3 287.9h.1"/>
<path d="M333.3 298.9h.1M333.3 285.7h.1M333.3 283.5h.1M333.3 296.7h.1M333.3 294.5h.1M333.3 290.7h.1M333.3 292.3h.1M333.3 292.9h.1M333.3 299.5h.1M333.3 282h1.2M333.3 285.7h.2M333.3 286.3h.2"/>
<path d="M333.3 296.7h.2M333.3 290.1h.2M333.3 292.3h.2M333.3 280.8h.2M333.3 280.8h.1M333.3 287.9h.2M333.3 297.3h.2M333.3 290.7h.2M333.3 292.9h.2M333.3 294.5h.2M333.3 288.5h.2M333.3 299.5h.2"/>
<path d="M333.3 295.1h.2M333.3 298.1v1.8M333.3 283.7h-.7M333.4 296.3l.1 .2M333.4 298.8h.1M333.5 286.3l-.1 .8h-.9M333.5 290.3l-.1 .8h-.8M333.5 280.8h.1M333.5 283.1h.1M333.5 281.5h.3M333.5 281.4h.1M333.5 281.8h.3"/>
<path d="M333.5 281.1h.3M333.5 283h.1M333.5 283.3h.1M333.5 298.8h.1M333.5 282.9h.1M333.6 281.4h.1M333.6 280.8l.1 .1M333.6 283.3h.1M333.6 282.9h.1M333.6 288.1h.3M333.6 299.1h.3M333.6 285.9h.3"/>
<path d="M333.6 296.9h.3M333.6 294.7h.3M333.6 290.3h.3M333.6 292.5h.3M333.6 294.9h.3M333.6 288.3h.3M333.6 292.7h.3M333.6 299.3h.3M333.6 286.1h.3M333.6 297.1h.3M333.6 290.5h.3M333.7 283.4h.1"/>
<path d="M333.7 280.7v.1M333.7 280.7h.1M333.7 280.8h.1M333.7 281.4h.1M333.7 281.3h.1M333.7 283h.1M333.7 282v.1M333.7 282.3v.7M333.7 283.4v.3M333.7 280.9h.1M333.7 280.3h.8M333.7 281.3v.6"/>
<path d="M333.7 282.4h.2M333.7 282.9h.1M333.8 281.4h.1M333.8 280.8l.2 .1M333.8 282.9h.1M333.8 281.5h.1M333.8 281.7h.1M333.8 281.2v.1M333.8 280h.1M333.8 281.1h.1M333.8 280.9v.1M333.8 281.1l1.6 .1"/>
<path d="M333.8 282.8h.1M333.9 280.9h.1M333.9 280.8h.1M333.9 281l-.1 .1M333.9 283.3h.5M334 283.4h.1M334 283.4l-1 .1M334 281.2h.4M334.1 283.3h.1M334.1 280.4h.1M334.1 280.5l-1.8 .1M334.1 280.4h.2"/>
<path d="M334.2 281.1h.1M334.3 281.1h.1M334.3 281.4v.3M334.3 281.6v.2zM334.3 282v.3M334.3 281.1v.2M334.3 282.5v.4M334.3 280.8h.1M334.3 283.1h.1M334.3 283.1v.1M334.3 281.3h.1M334.3 281.2h.1"/>
<path d="M334.3 281.9h.1M334.3 281.8v.1M334.3 281.1v.3M334.3 283h.1M334.3 282.7v.3M334.3 283.2l.1 .2M334.4 281.8l-.1 .5M334.4 280.4h.1M334.4 286.9h.1M334.4 283.3h.1M334.4 283.3l-.4 .1M334.4 281l-.1 .1"/>
<path d="M334.4 280.8h.1M334.4 283.6l-.9 .1M334.4 280.7h-.5M334.4 281.8h.1M334.4 283l.1 .4M334.4 281.4h.1M334.4 284h.1M334.5 282.4h-.3M334.6 280.5l-.2 2.8M334.6 282v.3M334.6 281.5v.3M334.6 282.5v.4"/>
<path d="M334.6 281.1v.2M334.6 281.1v.3M334.6 281.1h.1M334.6 281h.1M334.6 286.9h.1M334.6 283.2l.1 .2M334.6 281.8h.1M334.6 282h.1M334.6 280.4h.1M334.6 280.3h.1M334.6 281.4h.1M334.6 282.4h.1"/>
<path d="M334.6 283.4h.1M334.6 284h.1M334.7 280.9l-.1 .1M334.7 281.8v.2M334.7 280.5h.1M334.7 280.8h.1M334.7 280.2v1.4M334.7 281.8v.1M334.7 282v.4M334.7 282.8v.3M336.8 281.2h1.3M339.5 281.1v2"/>
<path d="M345.1 296.8h.7M346.6 296.8h.8M350.8 284.2h.1M350.8 282.2v2M59 318.3h.1M59.2 318.3h.1M59.3 318.3v1.4M60.1 317.5h.1M60.1 317.2v.2M60.2 317.4l-.9 .9M60.2 318.8v1.1M60.2 318.8h.2"/>
<path d="M60.4 318.8v1.1M60.8 317.9l-.7 .8v1.1M61 318l-.8 .8M61 316.5h.1M61 316.3v.1M61.1 318.1l-.7 .7M62.3 315.4l-1.1 1M62.6 315.4h.2M62.6 316.4v.1M62.6 316.4h1.1M62.6 316.4l-.8 .8M62.6 316.5l-.7 .8"/>
<path d="M62.7 315.4h.1M62.7 315.2v.1M62.9 315.4h.1M62.9 315.4h.3M63.2 316.6v.2M63.2 317v.3h.7M63.2 317.2h.7M63.2 316.6v.3M63.4 316.3l-.2 .3M63.4 315.4h.2M63.6 315.4l-.1 .4M63.6 315.4h.1"/>
<path d="M63.6 316.2h-1.1l-.8 .8M63.7 316.5l-1.1 .1M63.7 315.2h.1M64.8 316.2h1.2l.8 .8M64.8 316.4h1.1M64.8 315.2h.1M64.9 315.4h.1M64.9 315.4l.1 .4M64.9 315.4h.2M65.1 316.2l.1 .4M65.2 317.1l-.6 .1M65.2 316.6v.2"/>
<path d="M65.2 316.6l.1 .3M65.3 317.2l-.7 .1M65.4 315.4h.1M65.5 315.4h.1M65.7 315.4h.1M65.7 315.2h.1M65.7 315.4h.2M65.8 316.6l.8 .6M65.9 316.5l-1.1 .1M65.9 316.4v.1M65.9 316.4l.8 .8M66.1 315.4l1.2 1"/>
<path d="M67.3 318.1l.8 .7v1M67.4 318.1l.7 .7M67.4 316.5h.1M67.4 316.3v.1M67.5 318l.7 .8M67.6 317.9l.8 .8v1.1M68.1 318.8v1M68.2 318.8h-.1M68.2 318.8v1M68.3 317.4l1 .9M68.4 317.5h.1M68.4 317.2v.2"/>
<path d="M69.3 318.3v1.4M69.3 318.3h.1M69.5 318.3h.1M79 301h.1M79 318.3h.1M79 301.9h.1M79.2 301.9h.1M79.2 318.3h.1M79.2 301.1l.4 .1M79.2 301.9v.2M79.2 301.1h.1M79.2 318.3v1.4"/>
<path d="M79.2 301.1v.1M79.2 301.5v.3M79.2 302.3l1 1.2M80 301.3l.6 .1M80 317.5h.1M80 301v1.2l.8 .8M80 317.2v.2M80.1 303.6h.1M80.2 317.4l-1 .9M80.3 301v1.1M80.3 318.8v1.1M80.3 302.1l.7 .8"/>
<path d="M80.3 318.8h.1M80.3 303.6h.1M80.3 301v1M80.3 302v.1M80.3 302l.8 .8M80.5 301.5h.2M80.5 301.5h.1M80.8 317.9l-.8 .8v1.1M81 318l-.7 .8M81.1 316.5h.1M81.1 300.8l-.3 .6M81.1 316.3v.1"/>
<path d="M81.1 304.6h.1M81.1 318.1l-.8 .7M81.2 300.8l-.2 .7M81.2 304.5l1 .9M81.4 304.6h.1M81.7 303.8l.8 .8h1.2M81.8 303.7l.8 .7M81.9 303.6l.7 .7M82 303.5l.7 .7h1M82.1 305.4h.1M82.1 305.6h.1M82.2 305.4h.1"/>
<path d="M82.3 315.4l-1.1 1M82.5 315.4h.3M82.6 304.4h1.1M82.6 316.4l-.8 .8M82.6 316.4h1M82.6 316.4v.1M82.6 304.3h1.1M82.6 316.5l-.7 .8M82.6 316.5l1.1 .1M82.6 304.3v.1M82.7 316.6l-.8 .7M82.8 315.2v.1"/>
<path d="M82.8 315.4h.1M83 315.4h.1M83 315.4h.2M83.3 316.6l-.1 .1M83.3 317l-.1 .3h.7M83.3 317.2h.6M83.3 316.6l-.1 .3M83.3 316.3v.3M83.4 315.4h.2M83.6 315.4l-.1 .4M83.6 315.4h.1M83.6 305.4h-1.5"/>
<path d="M83.6 315.2h.1M83.6 316.2h-1.1l-.8 .8M84.6 317.2h.7M84.8 316.4h1.1M84.8 316.5l1 .1M84.8 315.2h.1M84.8 316.2h1.2l.8 .8M84.8 304.4h1.1M84.8 304.3h1M84.9 315.4h.1M84.9 315.4l.1 .4M84.9 315.4h.2"/>
<path d="M85 305.4h1.3M85.1 316.2l.2 .4M85.3 316.6v.3zM85.3 317.1v.2h-.7M85.4 315.4h.1M85.5 315.4h.1M85.7 315.4h.2M85.8 315.2h.1M85.8 315.3v.1M85.8 304.3l.1 .1M85.8 316.5l.8 .7M85.9 316.4l.7 .8"/>
<path d="M85.9 316.4l-.1 .1M86.1 315.4l1.2 1M86.3 305.4h.1M86.4 305.6h.1M86.4 305.5h.1M86.6 303.6l-.8 .7M86.6 303.5l-.8 .7h-1M86.7 303.7l-.8 .7M86.8 303.8l-.8 .8h-1.1M87.1 304.6h.1M87.3 304.5l-1 .9M87.3 300.8l.2 .7"/>
<path d="M87.3 304.6h.1M87.3 318.1l.8 .7M87.4 318.1l.7 .7M87.5 318l.8 .8M87.5 316.5h.1M87.5 300.7l.1 .7M87.5 316.3v.1M87.6 317.9l.8 .8v1.1M87.8 301.4h.2M88 301.4l-.2 .1M88.1 302l-.7 .8 .9-.7M88.1 318.8v1"/>
<path d="M88.1 300.9v1.1M88.1 302l.2 .1M88.1 303.6h.1M88.3 317.4l.9 .9M88.3 301v1.1M88.3 318.8v1M88.3 318.8h-.2M88.3 303.6h.1M88.4 301.3l-.4 .1M88.4 317.5h.1M88.4 317.2v.2M88.4 301v1.2l-.7 .7"/>
<path d="M89.2 318.3h.1M89.2 301.1h.1M89.2 301.7h.1M89.2 301.8v.2M89.2 301.1v.2M89.2 301.5v.2M89.2 302.3l-.9 1.1M89.2 301.1l-.3 .1M89.2 318.3v1.4M89.2 301.9h.1M89.3 318.3h-.1M89.4 301.9h.1"/>
<path d="M89.4 301h.1M89.4 318.3h.1M99.1 318.3h.1M99.3 318.3h.1M99.3 318.3l-.1 1.5M100 317.5h.1M100 317.2v.2M100.2 317.4l-.9 .9M100.2 318.8h.2M100.2 318.8v1.1M100.4 318.8v1.1M100.8 317.9l-.7 .8v1.1"/>
<path d="M101 318l-.8 .8M101 316.5h.1M101 316.3v.1M101.1 318.1l-.7 .7M102.3 315.4l-1.1 1M102.6 315.4h.1M102.6 316.4l.1 .1M102.6 316.4h1.1M102.6 316.4l-.8 .8M102.7 316.5l-.8 .8M102.7 316.5h1M102.7 315.2h.1"/>
<path d="M102.7 315.3v.1M102.9 315.4h.3M103.2 317v.3h.7M103.2 317.2h.7M103.4 316.2l-.2 .7M103.4 315.4h.2M103.6 315.4h.1M103.6 315.4l-.1 .4M103.6 315.2v.1M103.6 316.2h-1.1l-.8 .8M104.6 317.2h.6M104.8 316.4h1.1"/>
<path d="M104.8 316.2h1.2l.8 .8M104.9 315.2v.1M104.9 315.4h.2M104.9 315.4l.1 .4M104.9 315.4h.1M105.1 316.3l.1 .3M105.2 317.1l.1 .2h-.7M105.2 316.6l.1 .3M105.2 316.6l.1 .1M105.4 315.4h.2M105.7 315.4h.1M105.7 315.4h.2"/>
<path d="M105.7 315.2v.1M105.9 316.5l.6 .8-.7-.7M105.9 316.5l-1.1 .1M105.9 316.4l.8 .8M105.9 316.4v.1M106.1 315.4l1.2 1M107.4 318.1l.7 .7v1M107.4 318.1l.8 .7M107.4 316.5h.1M107.4 316.3v.1M107.5 318l.7 .8M107.6 317.9l.9 .8v1.1"/>
<path d="M108.2 318.8v1M108.2 318.8h.1M108.3 317.4l1 .9M108.5 317.5h.1M108.5 317.2v.2M109.3 318.3h.1M109.3 318.3v1.5M109.4 318.3h.1M121.1 302.9l1.8 .4M123.6 303.1l-.4 .2M124.2 303l-.3 .1M184.3 303l.2 .1"/>
<path d="M184.8 303.1l.4 .2M186.5 303.2h.1M186.5 303.2l-1 .1M188.5 301.8l-1.2 1.1M209 318.3h.1M209.2 318.3h.1M209.2 318.3v1.4M210.1 317.5h.1M210.1 317.2v.2M210.2 317.4l-1 .9M210.2 318.8h.1M210.2 318.8v1.1"/>
<path d="M210.3 318.8l.8-.7-.7 .7v1.1M210.3 318.8v1.1M210.9 317.9l-.8 .8v1.1M211 318l-.8 .8M211 316.5h.1M211 316.3v.1M212.3 315.4l-1.1 1M212.5 315.4h.3M212.6 316.4v.1M212.6 316.4l-.8 .8M212.6 316.4h1M212.6 316.5h1"/>
<path d="M212.6 316.5l-.7 .8M212.8 315.2v.1M212.8 315.4h.1M212.9 315.4h.2M212.9 315.4h.1M213.2 317v.3h.7M213.2 317.2h.7M213.2 316.6v.2M213.2 316.6v.3M213.4 316.3l-.2 .3M213.4 315.4h.2M213.6 315.4h.1"/>
<path d="M213.6 316.2h-1.1l-.8 .8M213.6 315.4l-.1 .4M213.6 315.2h.1M214.6 317.2h.7M214.8 316.5h1.1M214.8 316.4h1.1M214.8 315.2h.1M214.8 316.2h1.2l.8 .8M214.9 315.4h.2M214.9 315.4h.1M214.9 315.4l.1 .4M215.1 316.2l.2 .4"/>
<path d="M215.3 316.6v.3zM215.3 317.1v.2h-.7M215.4 315.4h.2M215.6 315.4h.1M215.7 315.4h.1M215.7 315.2h.1M215.7 315.4h.2M215.9 316.5l.7 .7M215.9 316.4v.1M215.9 316.4l.8 .8M216.1 315.4l1.1 1M217.3 318.1l.8 .7v1"/>
<path d="M217.4 318.1l.7 .7M217.5 316.5h.1M217.5 316.3v.1M217.5 318l.7 .8M217.6 317.9l.8 .8v1.1M218.1 318.8v1M218.2 318.8h-.1M218.2 318.8v1M218.3 317.4l.9 .9M218.4 317.5h.1M218.4 317.2v.2M219.2 318.3v1.4"/>
<path d="M219.2 318.3h.1M219.3 318.3h-.1M219.4 318.3h.1M226.6 303.8h.2M226.8 303.2h.1M226.9 303.8h.2M226.9 303.2h.1M227 301v.2M227 301.5v.1M227 303.2h.1M227 301.6h.1M227 301h.1"/>
<path d="M227 303.2v.2M227 303.6v.2M227.2 305.1h.1M227.3 301v.2M227.3 301.5v.1M227.3 303.7l.2 .1M227.3 304.7l-.1 .1M227.3 304.2v.3M227.3 304.4h.7M227.4 303.2l-.1 .2M227.4 303.2h.1M227.5 304.8h.1"/>
<path d="M227.5 305.1v.1M227.5 304l-.2 .1M227.6 303.8h.1M227.7 303.6l-.1 .4M227.7 302.8l-.1 .4M228 304.8h-1.4M228.1 302.6v2.2M228.6 305.1v.1M228.6 304.4h.7M228.7 304.8h.1M228.7 305v.1M228.7 304.8v.1"/>
<path d="M228.7 305.1h.1M228.8 301.5v2.1h.5M229.1 301.4v2.2M229.1 302.6h1.4M229.1 301.7l.1 .2M229.1 301.7h.1M229.1 301.6h.1M229.1 318.3h.1M229.1 301.3v.2M229.2 301.7h-.1M229.2 318.3h.1M229.2 318.3v1.5"/>
<path d="M229.3 304.3v.2M229.3 304.7v.1M229.3 304.8h.1M229.3 301.5h.1M229.4 302.1l.3 .3M229.4 301.5l.1 .3M229.4 304.8h-.8M229.4 304.8h.1M229.4 301.5h.1M229.4 301.5h-.1M229.5 301.2h.1M229.5 301.2l-.1 .3"/>
<path d="M229.5 304l-.2 .1M229.5 301.5h.2M229.7 301.5h.1M229.7 301.5v.1M229.7 300.7l-.4 .3M229.7 301.4v.1M229.7 301.8h.1M229.7 302.1h.1M229.8 301.2h.1M229.8 300.9h.1M229.8 300.9l-.1 .1M229.9 300.9h.4"/>
<path d="M229.9 301.9h.1M229.9 302.1h.1M229.9 301.2h-.1M229.9 304h.3M229.9 302.4l.3 .1M230 300.6h.3M230 301.1h.1M230 301.1l.2 .1M230 317.5h.1M230 317.2v.2M230 302.1l.1 .1M230.1 302.2h.1"/>
<path d="M230.1 301.1l-.1 .1M230.1 300.9v.2M230.1 302.4l.1 .1M230.2 300.7h.1M230.2 302.1h.1M230.2 317.4l-1 .9M230.2 318.8h.1M230.2 301.9h.1M230.2 318.8v1.1M230.2 301.9h-.1M230.3 300.6h.1M230.3 300.6l.2 .1"/>
<path d="M230.3 301.2h.1M230.3 300.9h.1M230.3 302.4l-.1 .1M230.3 301.8h.1M230.3 318.8l.8-.7-.7 .7v1.1M230.3 318.8v1.1M230.4 301.8h.1M230.4 302.1h-.5M230.4 303.6v.1M230.4 303.9v.1M230.4 301.4l.1 .1M230.4 301.6l.3 .1"/>
<path d="M230.4 301.6v.2M230.5 301.5h.1M230.5 301.5l-.1 .1M230.5 303.1h.1M230.5 303.1v.2M230.5 303.5l-.6 .1M230.5 304.3h.1M230.5 304.5v.1M230.6 301.2l.1 .5M230.6 302.3l-.2 .1M230.6 301.8h.1M230.6 302.5l-.1 .4"/>
<path d="M230.7 300.9l.2 .3M230.7 301.7l-.1 .1M230.8 302.1h.1M230.8 317.9l-.8 .8v1.1M230.8 302v.1M230.9 301.6h.1M230.9 301.9h.1M231 301.4v.2M231 301.6h.1M231 301.8l-.1 .1M231 301.6l-.2 .5M231 318l-.8 .8"/>
<path d="M231 316.5h.1M231 316.3v.1M231.2 303.1v.2M231.2 303.4l.1 .1M231.2 301.3h.1M231.2 301.3l-.2 .2M231.3 300.5h.7M231.3 300.5h.1M231.3 300.1h.1M231.3 301.3h.9M231.4 302.6l-.1 .1M231.5 302.5l-.2 .4"/>
<path d="M231.5 303.2v.2M231.6 303.5h.1M231.6 302.9v.1M231.6 300.1h.1M231.6 302.8h.1M231.6 302.8v.1M231.7 300.1h.1M231.8 302.2h.1M231.9 300.1h.1M231.9 302.5h.1M231.9 300h.1M232.3 315.4l-1.1 1"/>
<path d="M232.4 302.3l-.5 .2M232.5 302l-.7 .2M232.5 315.4h.2M232.6 316.4l1.1 .1M232.6 316.4h1M232.6 316.4l-.8 .8M232.7 300.5h.5M232.7 300.1h.1M232.7 316.6l-.8 .7M232.7 302.4l.4 .3M232.7 315.2h.1M232.7 315.3v.1"/>
<path d="M232.8 300.1h.1M232.9 315.4h.3M232.9 302.2l.4 .3M233.1 301.3h.7M233.1 300.1h.1M233.2 300.4v.8M233.2 300.5h.1M233.2 301.9v.7h-1.3M233.2 316.6v.3M233.2 317v.3h.7M233.2 317.2h.7M233.2 316.6v.1"/>
<path d="M233.3 302.9l.2 .2M233.4 316.2l-.2 .4M233.4 304.1h-.4M233.4 315.4h.2M233.5 304.8h.9M233.5 302.7l.3 .2M233.6 315.4l-.1 .4M233.6 315.4h.1M233.6 316.2h-1.1l-.8 .8M233.6 315.2v.1M233.7 303.3l.3 .1M233.8 304.1h.5z"/>
<path d="M233.8 301.3h.1M233.8 301.4h.1M233.9 301.5h.1M233.9 301.6h.1M233.9 303l.3 .1M233.9 303h.1M233.9 301.7l.1 .1M234 303.4h.1M234.1 301.9l.1 .1M234.2 302.3l.2 .2M234.2 303.5h.1M234.2 301.9l.2 .1"/>
<path d="M234.2 300.5h.1M234.2 300.1h1.8M234.3 303.5l1 .2M234.4 303.2l1 .2M234.4 304h.1M234.5 303.9h.1M234.6 302.5h1.5M234.6 317.2h.6M234.6 302.3l.2 .2M234.6 303.8h.1M234.6 303.7v.1M234.6 303.7h.1"/>
<path d="M234.7 302.5h.1M234.8 303.7h2.2h-2.3M234.8 303.7h.1M234.8 316.4h1.1M234.8 316.2h1.2l.8 .8M234.9 315.2v.1M234.9 302.6h.1M234.9 315.4h.2M234.9 315.4l.1 .4M234.9 315.4h.1M235 301.2h.1M235 301.4h.1"/>
<path d="M235 301.5h.1M235.1 301.1h.1M235.1 301.6h.1M235.1 302.8h.1M235.2 301.7h.2M235.2 301.1h.1M235.2 301.7h.1M235.2 316.3v.6M235.2 302.8h.1M235.2 301.5h.1M235.2 301.3h.1M235.2 301.2h.1"/>
<path d="M235.2 301.6h.1M235.2 304.8h.9M235.2 317.1v.2h-.6M235.3 301.1h.1M235.3 301.7h.1M235.3 302.9l.5 .1M235.4 315.4h.2M235.5 301.1h.4M235.6 301.7h.4M235.7 315.4h.1M235.7 315.4h.2M235.7 315.2v.1"/>
<path d="M235.8 316.6l.8 .7M235.9 316.5l.7 .7M235.9 316.5l-1.1 .1M235.9 316.4v.1M235.9 316.4l.7 .8M236.1 315.4l1.2 1M236.1 300.5h3.5M236.2 301.1h.4M236.2 301.7h.4M236.3 303.9l1.3 .2M236.3 303.6l1.4 .2M236.4 303.1l1.1 .1"/>
<path d="M236.8 301.1h.5M236.9 301.7h.3M237.2 301.7h.1M237.3 318.1l.8 .7M237.4 301.7h1.4M237.4 318.1l.7 .7M237.4 316.5h.1M237.4 316.3v.1M237.4 318l.8 .8M237.5 302.5h2.9M237.6 317.9l.8 .8v1.1M237.7 300.1h3.5"/>
<path d="M238 304.1h.5M238.1 318.8v1M238.2 317.4l1.1 .9M238.2 318.8h-.1M238.2 303.2h.7M238.2 318.8v1M238.3 303.8l1.4 .1M238.5 317.5h.1M238.5 317.2v.2M238.9 301l-1.5 .1M238.9 303v.3h.9M238.9 302.5v.2"/>
<path d="M239.3 318.3h.1M239.3 318.3v1.5M239.4 318.3h.1M239.9 304.2h.5M240.3 301.8h1.5M240.3 304.8h.1M240.3 304.8v.1M240.3 301h1.5M240.3 305.1h.1M240.4 305.1h.1M240.4 304.8v.1M240.7 303.3l.9 .1"/>
<path d="M241 304.2h.5v.3M241.1 304.8v.1M241.1 305v.1M241.4 300.5h1.7M241.5 303.7h.1M241.5 304.7v.2M241.5 305.1h.1M241.5 303.6h2.1M241.5 304.4h2.1M241.5 303.7h-2.2M241.6 303.5l-.1 .4h-.9M241.9 301h.5"/>
<path d="M242 301.8h.4M242 302.5h1.5M242.7 301h.4M242.8 301.8h.4M243 300.1h.5M243.1 301h.1M243.1 300.5h.1M243.2 304.8v.1M243.2 305.1h.1M243.2 300.9h.1M243.2 300.5l.1 .1M243.2 300.5h.1"/>
<path d="M243.3 300.8h.1M243.4 301.8h.1M243.5 304.8v.1M243.5 305.1h.1M243.5 300.5v2.3M243.5 303.2v.4M243.7 304.8h-3.4M244 304.8v.1M244 305.1h.1M244.6 303.2h.6M244.6 302.5h.1M244.6 302.3l.1 .6"/>
<path d="M244.6 303v.4M244.6 303.6l1.6 .1M244.6 301.8h.1M244.6 300.9h.5M244.7 300.6l-.1 1.4M244.8 302.5h.2M244.9 300.6h.7M244.9 301.8h.1M244.9 303.4v.2M245 300.9h.1M245 301.1h.1M245 302.5h.1"/>
<path d="M245 301.2l.1 .2M245 304.8v.1M245 305v.1M245 300.8h.1M245 301.8h.1M245 300.7v.1M245.1 301.9v.4M245.1 302.3h.2M245.1 301.7v.1M245.1 302.5h.1M245.1 300.6h.1M245.1 302.4h.1"/>
<path d="M245.3 301.2l-.2 .3M245.3 302.9l-.4 .2M245.5 302.3h.2M245.6 300.9h.6v.6M245.7 301.2l.2 .4M245.7 302.3h.1M245.7 302.5h.1M245.7 302.6h.1M245.8 303.6h4.2M245.8 304.4h4.2M245.8 302.7h.1M245.9 302h.1"/>
<path d="M245.9 302.7h.1M245.9 301.5h.1M245.9 301.8l-.1 .5M246 302.7h.2M246.2 302.6h.1M246.2 302.8l-.4 .1M246.2 302.6h.5M246.2 302.7h.1M246.2 302.1v.5M246.2 300.6h.6M246.3 302.7h.1M246.3 301.5h-.2"/>
<path d="M246.3 302h-.3M246.4 302.8h.1M246.5 302.8h.1M246.5 301.5h.3M246.6 303.2h.1M246.6 302h.2M246.6 303h.1M246.8 300.6v.3M246.8 301.2v.4M246.8 302.8v.4h-.9M246.8 300.3v.4M246.8 301.8v.5"/>
<path d="M246.8 300.3l.1 .3M246.8 300.7l.4 .4M246.9 300.6h.1M247.2 301h.7M247.7 302.4v.2h-.5M247.9 301h.1M248 303.7h3.5M248.3 300v.6M248.3 300h.1M248.3 300.6v.1M248.6 304.8v.1M248.6 305.1h.1"/>
<path d="M249.6 300.7v.7h.7M249.6 301.9l-1.9 .2M249.6 304.8v.1M249.6 305.1h.1M249.7 300.9h.1M249.8 300.9h-.1M249.9 300h.1M249.9 300.8h.1M249.9 300.1h.1M250 304.8h-4.9M250 300.1h.1M250 300.7l-.1 .1"/>
<path d="M250.1 300.7h.1M250.1 300.3h.1M250.1 300.4v.1M251 304.8v.1M251 305v.1M251.1 300.4h.1M251.1 300.5l.1 .1M251.1 300.4v.1M251.2 300.6h.1M251.2 304.8h.1M251.2 305v.1M251.2 300.7l.2 .2"/>
<path d="M251.2 300.7h.1M251.2 300.2h.1M251.3 300.1h.1M251.3 300.1h-.1M251.5 300.9h.1M251.6 300.7v.7h-.6M251.6 300.9h.1M251.7 301.9h2M252.1 303.6h2.1M252.1 304.4h2.1M252.8 304.8h.1M252.8 305v.1"/>
<path d="M253 300.9v1M253.2 301.9v.6M253.2 303.2v.5M253.4 304.8v.1M253.4 305.1h.1M253.7 301.9h.1M253.7 301.2h.1M253.7 300.7v1.2M253.8 302v.1M253.8 300.7l-.1 .5M253.8 302.1l.2 .1M253.8 302.1v.5"/>
<path d="M253.8 303.1v.5M254.1 302.3l.1 .2M254.2 304.5h.1M254.2 304.7l-2.2 .1M327.8 303.3h1M327.8 301.2h1M329.8 300.8h.1M329.8 300.3h.1M329.8 300.5v.1M329.8 300.2v.1M329.8 300.7v.1M329.9 300.9v.1"/>
<path d="M329.9 303.3h1.1M329.9 301.2h1.1M330 301.1h.1M330.1 301.1h.2M330.7 301.1h.3M331 301v.2M331 306.2h.1M331 300.6h.3M331 305.2h.3M331 316.6l.3 .1M331 302.2h.3M331 303.2h.1"/>
<path d="M331 306.8h.1M331 316.7h.1M331 317.3h.1M331 301.3l.1 .3M331 301.5h.1M331 317l.1 .2M331 315.4v.4M331 316.3v.5M331 305.3h.1M331 305.4h.1M331 301h.1M331 303.6l.1 .2"/>
<path d="M331 303.2v.2M331 306.5v.1M331.1 319.4h.1M331.1 318.9h.1M331.1 318.8h.1M331.1 306.6v.6M331.1 307.7v.5M331.1 319.4v.6M331.1 318.8h.2M331.1 305.1h.1M331.1 300.6v.6M331.1 301.7v.5"/>
<path d="M331.1 303.6v.6M331.1 304.7v.5M331.2 301.5l.1 2.1M331.2 301.1h.1M331.2 301.4h.1M331.3 302.5h1.1M331.3 302.6h.1M331.3 303.2h.2M331.3 301.1h.1M331.3 316.6h.1M331.3 317.2h.1M331.3 317.1l-.1 .2"/>
<path d="M331.3 316.6v.3M331.3 306.8h.1M331.3 304.8h.1M331.3 304.7h.1M331.3 304.8l.2 .1M331.3 304.1h.2M331.3 303.7h.3M331.3 301.9h.1M331.3 300.7v.3M331.3 301h.2M331.3 301.4l.2 .2M331.3 301l.2 .2"/>
<path d="M331.3 306.2h.1M331.3 303.8h.2M331.3 306.6h.1M331.3 305.4h.1M331.3 306.7v.1M331.3 303.2v.2M331.4 315.4h.1M331.4 316.5h.1M331.4 303.6v.4M331.4 304.3v.3M331.4 304.8l-.3 .3M331.4 305.2h.1"/>
<path d="M331.4 304.8h.1M331.4 305l.1 .1M331.5 302.6h.1M331.5 301.2h.1M331.5 304.8h.1M331.5 315.2h.1M331.5 301.9h.2M331.5 305.1h.1M331.5 305.2h-.1M331.6 315.4h.1M331.6 316.5h.1M331.6 318.8h.2"/>
<path d="M331.6 304.8h.1M331.6 301v.2M331.6 300.6h.2M331.6 315.2h.1M331.6 303.6h.1M331.6 300.5h.1M331.6 303.5v.1M331.6 304.8h-.1M331.6 303.2h.2M331.6 305.1h.1M331.6 304.8l.6 .1M331.6 303v.3"/>
<path d="M331.6 304.8v.1M331.7 303.2h.3M331.7 301h.3M331.7 303.8h.3M331.7 301.6h.3M331.7 301.4l-.1 .1M331.8 303.7h.2M331.8 319.4h.1M331.8 318.8h.1M331.8 306.6v.6M331.8 307.7v.5M331.8 300.6v.6"/>
<path d="M331.8 301.7v.5M331.8 304.7v.5M331.9 319.4h.1M331.9 318.9h.1M331.9 300.5h.2M331.9 301.9h.8l-.2 .1M331.9 301.4h.2M331.9 300.6h.1M331.9 318.9v.1M331.9 319.2v.8M331.9 303.2h.1M331.9 301.7l-.3 1.1"/>
<path d="M331.9 304.7v.5h-.3M331.9 300.6v.6M332 318.3h.1M332 301.1h.1M332 304.5v.4M332 302.9h.1M332 303h.1M332 301.3h.1M332 303.3h.1M332 300.1h.1M332 302.6v1.2M332 304v.2"/>
<path d="M332 300.6h-.5l.1 1.2M332 304h.1M332 301.2l.4 .1M332 302.5h.1M332 300.5h.1M332 303.8h.1M332 303.9h.1M332 302.7h.1M332 301.7h.1M332 301.5h.1M332 300.5v.7M332 304h.5"/>
<path d="M332 304.1h.1M332 305l-.4 .1M332 301.2h.1M332 302.3h.1M332 301.4h.1M332 301.1v.2M332 301.4v1.1M332 301h.7M332 300.6h.1M332 303.2h.1M332 300.4v.2M332 301.9h.1"/>
<path d="M332 303.7h.1M332 303.6h.1M332.1 301h.1M332.1 301.8h-.1M332.1 301.8h.2M332.2 305v.1M332.2 303.2h.1M332.2 300.1l.1 .1M332.2 304h.1M332.2 303.8h.1M332.2 301.6h.1M332.3 301.1h.1"/>
<path d="M332.3 300.9h.1M332.3 301.1v.1M332.3 301.5h.1M332.3 301.3h.1M332.3 301.4h.1M332.3 302.2h.1M332.3 302l-.1 .3 .1-.2M332.3 301.2h.1M332.3 302.7h.1M332.3 301.8h.1M332.3 300.1h.1M332.3 300.7l-.1 .5"/>
<path d="M332.3 301.5v.3M332.3 302.5h.1M332.3 300.4v.2M332.3 301.5v.2M332.3 300.5h.1M332.3 300.9v.3M332.3 303.6h.1M332.3 303.2h.1M332.3 301.5h-.3M332.3 303.6h1.2M332.3 303.3h.1M332.3 301l-.3 .1"/>
<path d="M332.3 301h.1M332.3 300.7v.1M332.3 302.6l.1 .3M332.3 303h.1M332.3 303.1h.1M332.3 303.8h.1M332.3 302.1h.1M332.3 301.9h.1M332.3 303.1v.7M332.3 304v.1M332.3 303.7h-.1M332.4 305.2h.1"/>
<path d="M332.4 302.5v.3M332.4 305.1v.1M332.4 318.3h.1M332.4 301.8h-.3M332.4 301.8h.1M332.4 301.4h-.2M332.4 304.5v.4M332.4 304.1h-.6v-.5l.1 .6M332.5 305.2h.1M332.5 302.3l-.1 .2M332.5 303.2h.1M332.5 318.3v.1"/>
<path d="M332.5 316.6h.2M332.5 304.2h.2M332.5 300.9v1M332.5 318.6v1.2M332.5 302.5h.2M332.6 300.9h.1M332.6 318.7h.1M332.6 316.2h.1M332.6 304.6h.1M332.6 302.2h.1M332.6 300.1h.1M332.6 301.4h.1"/>
<path d="M332.6 302.9h.1M332.6 301.3h.1M332.6 303.3h.1M332.6 302v1.6M332.6 305.2h.1M332.7 301l.2 .1M332.7 301.8h-.2M332.7 303v.4M332.7 303.5v.1M332.7 318.7h.1M332.7 316.2h.1M332.7 304.6h.1"/>
<path d="M332.7 302.2h.1M332.7 302.1l-.2 .1M332.7 305.1l-.3 .1M332.7 316.4h.2M332.7 302.3l-.1 .3M332.8 304.8l-.5 .1M332.9 318.8h-.4M332.9 304.4h-.2M332.9 302l-.2 .1M332.9 301.7h.1M332.9 301.7h-.2M332.9 304.6v.2"/>
<path d="M332.9 305.1h.1M332.9 304.3v.1M332.9 305v.1M333.1 303.8h.1M332.9 304.1h.1M332.9 302.9h.1M332.9 302.6v.5M332.9 303.5v.4h.5M332.9 304h.1M332.9 304.2h.4M332.9 304.6h.1M332.9 304.3h.1"/>
<path d="M333 301.1h.1M333 301.7h.1M333 301l.2 .1M333 301.5h.1M333 301.3h.1M333 301.6h.1M333 301.1v.1M333 316.6h.3M333 304.2h.3M333 318.8h.3M333 303.9l.1 .1M333 301.5v2.1"/>
<path d="M333.1 304h.4M333.1 304l-.7 .2M333.1 305.1l-.2 .1M333.1 303.8l.1 .1M333.1 301.7h.1M333.1 304h.1M333.2 304.8h.3M333.2 316.5h.1M333.2 304.6h.2M333.2 304h.1M333.2 301.2h.1M333.2 301.4h.1"/>
<path d="M333.2 301.6l.3 .1M333.2 304h.2M333.3 301.1h.1M333.3 301.1h.2M333.3 303.6l-.1 .7h.3M333.3 302h-.4v.3h.4M333.3 301v1.8M333.3 316.5v.8M333.3 318.1v1.8M333.4 316.3v.1M333.4 304.5h.1M333.4 318.8h.1"/>
<path d="M333.4 304.8h.1M333.5 318.8h.1M333.5 304.8l-.2 .1M333.5 316.5h.1M333.5 304.3h.1M333.6 304.8v.1M333.6 305.1h.1M333.6 304.3h.1M333.6 301.3h.3M333.6 301.5h.3M333.6 304.6h.2M333.7 302.3h.3"/>
<path d="M333.7 302l.3 .3M333.7 304.2h.3M333.7 303.6h.7M333.7 303.8l.3 .1M333.8 304h.6M333.9 303.9l-.4 .1M333.9 304.3h.1M334 302.6v.5M334 302.9h.1M334 303.7h.1M334 303.9v.1M334 304.1h.1"/>
<path d="M334 303.7l-.2 .1M334 303.4v.4M334 303.8l-.1 .1M334 304.6h.1M334 304.3h.1M334 304.5v.1M334 304.7h.1M334 305.1h.1M334 304.8v.1M334 305v.1M334.1 304.8h.2M334.4 303.5h.1"/>
<path d="M334.4 304.1h.1M334.5 304.8h.1M334.6 303.5h.1M334.6 304.1h.1M334.7 303.6h.1M345.1 300h.7M345.1 303h.7M346.6 300h.8M346.6 303h.8M59 322.6h.1M59.3 322.6h.1M59.3 322.5l.9 1"/>
<path d="M59.3 322.5h.1M59.3 321.1v1.5M60.1 321.1v1.1l.8 .8M60.1 323.3h.1M60.1 323.5v.1M60.2 322.1l.8 .8M60.2 321v1.1M60.4 322l-.2 .1M60.4 321v1M60.4 321v1l.7 .8-.7-.8M61 324.3h.1M61 324.5v.1"/>
<path d="M61.2 324.5l1.2 .9M61.7 323.8l.8 .8h1.2M61.8 323.7l.8 .7M61.9 323.6l.7 .7M62.6 324.4h1.1M62.6 325.4h.1M62.6 324.3h1.1M62.6 324.3v.1M62.7 325.5v.1M62.7 325.4h.1M62.9 325.4h.1M62.9 325.4h.2"/>
<path d="M63.2 323.6h.7M63.2 324l.2 .6M63.4 325.4h.2M63.5 325l.1 .4M63.6 325.4h.1M63.6 325.5l.1 .1M63.9 323.5h-.7v.3M64.6 323.5l.7 .2M64.6 323.6l.6 .2M64.8 324.3h1.1M64.8 324.4h1.1M64.8 325.5v.1"/>
<path d="M64.9 325.4h.1M64.9 325.4h.2M65 325.1l-.1 .3M65.2 324.1v.1M65.2 324.2l-.1 .4M65.3 323.9l-.1 .3M65.3 325.4h.3M65.7 325.4h.2M65.7 325.6h.1M65.7 325.4v.1M65.9 324.3v.1M66.6 323.5l-.7 .8"/>
<path d="M66.7 323.6l-.8 .8M66.8 323.8l-.8 .8h-1.2M67.3 324.4l-1.1 1M67.4 324.3h.1M67.4 324.5v.1M68.1 320.9v1.1M68.1 321v1M68.1 322l.1 .1M68.1 322l-.7 .7M68.2 321v1.1M68.2 322.1l-.7 .7M68.4 323.3h.1"/>
<path d="M68.4 321v1.2l-.8 .8M68.4 323.5v.1M69.3 322.5h.1M69.3 322.6h.1M69.3 322.5l-1 .9M69.3 321.1v1.5M69.4 322.6h.1M79 322.6h.1M79 338.9h.1M79 339.8h.1M79.2 322.6h.1M79.2 322.5l1 1"/>
<path d="M79.2 322.5h.1M79.2 321.1v1.5M79.2 339.8h.1M79.2 339.1h.1M79.2 339h.1M79.2 338.8v.1M79.2 339.1v.2M79.2 339.6v.2M79.6 339.7l-.4 .1M80 323.3h.1M80 323.5v.1M80 321.1v1.1l.8 .8"/>
<path d="M80.1 337.2h.1M80.2 337.4l-1 1.1M80.3 338.8h.1M80.3 321v1.1M80.3 338.8v1.1M80.3 322.1l.7 .8M80.3 337.2h.1M80.3 322v.1M80.3 322l.8 .8M80.4 321v1M80.5 339.4h.2M80.6 339.4l-.6 .1"/>
<path d="M80.8 337.9l-.8 .8v1.2M80.9 339.4l.2 .7M81 338l-.7 .8M81 339.4l.2 .7M81.1 324.3h.1M81.1 324.5v.1M81.1 338.1l-.8 .7M81.1 336.2h.1M81.2 324.5l1.2 .9M81.4 336.2h.1M81.7 323.8l.8 .8h1.2M81.8 323.7l.8 .7"/>
<path d="M81.9 323.6l.7 .7M82 323.6l.7 .7M82.1 335.2h.1M82.1 335.4h.1M82.2 335.4l-1 1M82.2 335.4h1.4M82.2 335.4h.1M82.6 325.4h.2M82.6 336.4v.1M82.6 324.4h1.1M82.6 336.4l-.7 .9M82.6 336.4l1.1 .1"/>
<path d="M82.6 324.3h1.1M82.6 324.3v.1M82.8 325.4h.1M82.8 325.5v.1M82.9 325.4h.2M83.2 324l.1 .2M83.2 324.1l.1 .1M83.3 324.2v.4M83.3 323.6h.6M83.4 325.4h.2M83.5 325l.1 .4M83.6 325.4h.1"/>
<path d="M83.6 336.2h-1.1l-.8 .9M83.6 325.5v.1M83.7 336.6h-1l-.8 .7M83.9 323.5h-.7l.1 .3M84.6 323.5h.7v.3M84.6 323.6h.7M84.8 336.6h1M84.8 336.2h1.2l.8 .8M84.8 324.4h1.1M84.8 324.3h1M84.9 325.5l-.1 .1M84.9 325.4h.1"/>
<path d="M84.9 325.4h.2M85 325.1l-.1 .3M85.3 323.9l-.2 .7M85.3 325.4h.2M85.6 325.4h.1M85.8 325.4h.1M85.8 325.6h.1M85.8 325.4v.1M85.8 336.5l.8 .8M85.8 324.3l.1 .1M85.9 336.4l-.1 .1M85.9 336.4l.7 .8"/>
<path d="M85.9 336.4l-1.1 .1M86.3 335.4h.1M86.3 335.4l1 1M86.4 335.4h-1.5M86.4 335.4h.1M86.4 335.3h.1M86.6 323.6l-.8 .7M86.7 323.6l-.8 .8M86.8 323.8l-.8 .8h-1.1M87.1 336.2h.1M87.3 324.4l-1.1 1M87.3 336.2h.1"/>
<path d="M87.4 338l.7 .8M87.5 338l.8 .8M87.5 324.3h.1M87.5 324.5v.1M87.5 339.4l-.2 .7M87.6 339.4l-.1 .6M87.6 337.9l.8 .8v1.1M87.8 339.4h.2M87.9 339.4h.1M88 339.4l.4 .1M88.1 320.9v1.1M88.1 322l-.7 .7"/>
<path d="M88.1 338.8v1.1M88.1 322l-.6 .8 .8-.7M88.1 322l.2 .1M88.1 337.2h.1M88.3 338.8h-.2M88.3 321v1.1M88.3 338.8v1M88.3 337.4l.9 1.1M88.3 337.2h.1M88.4 323.3h.1M88.4 323.5v.1M88.4 321v1.2l-.7 .8"/>
<path d="M88.9 339.7l.3 .1M89.2 322.5h.1M89.2 322.6h.1M89.2 321.1v1.5M89.2 322.5l-.9 .9M89.2 338.7l.1 .2M89.2 339.8h.1M89.2 339v.3M89.2 339.6v.2M89.4 322.6h.1M89.4 339.8h.1M89.4 338.9h.1"/>
<path d="M99.1 322.6h.1M99.2 322.6h.1M99.2 321.1v1.4M99.2 322.5h.1M99.3 322.5v.1M99.3 322.5l.9 1M100 323.3h.1M100 323.5v.1M100.1 321.1v1.1l.8 .8M100.2 322.1l.8 .8M100.2 321v1.1M100.4 322l-.2 .1"/>
<path d="M100.4 322l.7 .8M100.4 321v1M101 324.3h.1M101 324.5v.1M101.2 324.5l1.2 .9M101.7 323.8l.8 .8h1.2M101.9 323.6l.7 .8M101.9 323.6l.8 .7M102.6 324.4h1.1M102.6 325.4h.2M102.7 324.3h1M102.7 324.3l-.1 .1"/>
<path d="M102.7 325.6h.1M102.7 325.4v.1M102.9 325.4h.1M102.9 325.4h.2M103.2 324.2l.2 .4M103.2 323.9v.3M103.2 324v.2M103.2 323.6h.7M103.4 325.4h.2M103.5 325.1l.1 .3M103.6 325.4v.1M103.6 325.4h.1"/>
<path d="M103.6 325.6h.1M103.9 323.5h-.7v.3M104.6 323.5h.7l-.1 .3M104.6 323.6h.6M104.8 324.3h1.1M104.9 324.4h1M104.9 325.6h.1M104.9 325.4h.1M104.9 325.4h.2M105 325l-.1 .4M105.2 324.2l-.1 .4M105.3 324l-.1 .2"/>
<path d="M105.3 324.1l-.1 .1M105.3 325.4h.2M105.5 325.4h.1M105.7 325.4h.3M105.7 325.4h.1M105.7 325.5v.1M105.9 324.3v.1M106.6 323.5l-.7 .8M106.7 323.6l-.8 .8M106.8 323.8l-.8 .8h-1.1M107.3 324.4l-1.1 1M107.4 324.3h.1"/>
<path d="M107.4 324.5v.1M108.1 320.9v1.1l-.7 .7 .8-.7M108.2 322v.1M108.2 321v1M108.2 322.1l-.7 .7M108.2 321v1.1M108.5 323.3h.1M108.5 321v1.2l-.9 .8M108.5 323.5v.1M109.3 322.5v.1M109.3 321.1v1.4M109.3 322.5l-1 .9"/>
<path d="M109.3 322.6h.1M109.4 322.6h.1M209 322.6h.1M209.2 322.5h.1M209.2 322.6h.1M209.2 321.1v1.5M209.2 322.5l1 1M210.1 321.1v1.1l.8 .8M210.1 323.3h.1M210.1 323.5v.1M210.2 321v1.1M210.2 322.1l.8 .8"/>
<path d="M210.3 322l.8 .8M210.3 322l-.1 .1M210.3 321v1M210.4 321v1l.8 .7M211 324.3h.1M211 324.5v.1M211.2 324.5l1.1 .9M211.7 323.8l.8 .8h1.1M211.8 323.7l.8 .7M211.9 323.6l.7 .7M212.6 324.4h1.1M212.6 325.4h.2"/>
<path d="M212.6 324.3h1.1M212.6 324.3v.1M212.8 325.4h.1M212.8 325.5v.1M212.9 325.4h.1M212.9 325.4h.2M213.2 324l.2 .6M213.2 323.6h.7M213.4 325.4h.2M213.5 325l.1 .4M213.6 325.4h.1M213.6 325.5v.1"/>
<path d="M213.9 323.5h-.7v.3M214.6 323.5h.7v.3M214.6 323.6h.7M214.8 324.3h1.1M214.8 324.4h1.1M214.9 325.4h.1M214.9 325.4h.2M214.9 325.5l-.1 .1M215 325.1l-.1 .3M215.3 323.9l-.2 .7M215.3 325.4h.3M215.6 325.4h.1"/>
<path d="M215.7 325.4h.2M215.7 325.6h.1M215.7 325.4v.1M215.9 324.3v.1M216.6 323.6l-.7 .7M216.7 323.6l-.8 .8M216.8 323.8l-.8 .8h-1.1M217.3 324.4l-1.2 1M217.5 324.3h.1M217.5 324.5v.1M218.1 320.9v1.1M218.1 322l-.7 .7"/>
<path d="M218.1 321v1M218.1 322l.1 .1M218.2 321v1.1M218.2 322.1l-.7 .7M218.4 323.3h.1M218.4 321v1.2l-.8 .8M218.4 323.5v.1M219.2 322.6h.1M219.2 322.5h.1M219.2 322.5l-.9 .9M219.2 321.1v1.5M219.4 322.6h.1"/>
<path d="M229.1 322.6h.1M229.2 322.6h.1M229.2 322.5l1 1M229.2 321.1v1.4M229.2 322.5h.1M229.2 322.5v.1M230 321.1v1.1l.9 .8M230 323.3h.1M230 323.5v.1M230.2 322.1l.8 .8M230.2 321v1.1M230.3 321v1"/>
<path d="M230.3 322l-.1 .1M230.4 321v1l.7 .7-.8-.7M231 324.3h.1M231 324.5v.1M231.2 324.5l1.2 .9M231.7 323.8l.8 .8h1.2M231.9 323.6l.8 .7M232.6 324.4h1.1M232.6 325.4h.2M232.6 324.3h1.1M232.6 324.3l-.7-.6 .7 .7M232.6 324.3v.1"/>
<path d="M232.7 325.6h.1M232.7 325.4v.1M233 325.4h.1M233.2 323.9v.3M233.2 324.1v.1M233.2 324.2l.2 .4M233.2 323.6h.7M233.4 325.4h.2M233.5 325.1l.1 .3M233.6 325.4h.1M233.6 325.6h.1M233.9 323.5h-.7v.3"/>
<path d="M234.6 323.5h.6v.3M234.6 323.6h.6M234.8 324.4h1.1M234.8 324.3h1.1M234.9 325.6h.1M234.9 325.4h.1M234.9 325.4h.2M234.9 325.4v.1M235 325l-.1 .4M235.2 324v.2M235.2 324.2v.4M235.2 324.1v.1"/>
<path d="M235.3 325.4h.2M235.5 325.4h.1M235.7 325.4h.2M235.7 325.4h.1M235.7 325.5v.1M235.9 324.3v.1M236.6 323.5l-.8 .8M236.7 323.6l-.8 .8M236.8 323.8l-.8 .8h-1.1M237.3 324.4l-1.1 1M237.4 324.3h.1M237.4 324.5v.1"/>
<path d="M238.1 320.9v1.1M238.1 322l.1 .1M238.1 322l-.7 .7M238.2 322.1l-.7 .7M238.2 321v1.1M238.4 321v1.2l-.7 .8M238.5 323.3h.1M238.5 323.5v.1M239.3 321.1v1.4M239.3 322.5v.1M239.3 322.5l-1 .9M239.3 322.6h.1"/>
<path d="M239.4 322.6h.1M327.8 333.9h1M327.8 331.9h1M329.9 333.9h1.1M329.9 331.9h1.1M331 324.2h.1M331 323.5h.1M331 324.1h.1M331 324v.6M331 325v.4M331 339.4h.1M331 339.4v.1"/>
<path d="M331 339.7v.1M331.1 321.9h.1M331.1 321.5h.1M331.1 332.6v.5M331.1 333.7v.5M331.1 322h.1M331.1 323.6l-.1 .2M331.1 320.8v.6M331.1 328.6v.5M331.1 329.7v.5M331.1 322h.2M331.1 321.4h.1"/>
<path d="M331.2 323.5l.1 .2M331.2 324.1h.1M331.2 339.4h.1M331.3 324.2h.1M331.3 323.6h.1M331.3 324v.2M331.3 339.8v.4M331.4 324.3h.1M331.4 325.4h.1M331.4 336.2v.4M331.4 336.9v.3M331.5 325.6h.1"/>
<path d="M331.6 325.4h.1M331.6 322h.2M331.6 324.3h.1M331.6 325.6h.1M331.8 321.4h.1M331.8 328.6v.5M331.8 329.7v.5M331.8 332.6v.5M331.8 333.7v.5M331.9 321.9h.1M331.9 321.5h.1M331.9 320.8v.8"/>
<path d="M331.9 321.8v.1M332 322.5h.1M332.4 322.5h.1M332.5 336.6h.2M332.5 338.8h.2M332.5 324.3h.2M332.5 321.1v1.2M332.5 322.4v.2M332.5 338.9v1M332.5 322l.4 .1M332.6 338.7h.1M332.6 336.2h.1"/>
<path d="M332.6 322.2h.1M332.6 324.6h.1M332.7 338.8h.2M332.7 336.4l.2 .1M332.7 338.7h.1M332.7 336.2h.1M332.7 322.2h.1M332.7 324.6h.1M332.7 324.4h.2M333 336.6h.3M333 324.3h.3M333 322h.3"/>
<path d="M333.2 336.5l.1 .8M333.3 338.1v1.8M333.3 338.8h-.3M333.3 321v1.8M333.3 323.6v.7M333.3 324.3l-.1 .1M333.4 324.5h.1M333.4 322h.1M333.4 336.4h.1M333.5 322h.1M333.5 336.5h.1M333.5 324.3v.1"/>
<path d="M79 341h.1M79 341.9h.1M79.2 341.9h.1M79.2 341.7h.1M79.2 341.1h.1M79.2 342.3l1 1.2M79.2 341.1v.1M79.2 341.5v.2M79.2 341.8v.3M79.2 341.1l.4 .1M80 341v1.1l.8 .9M80.1 343.6h.1"/>
<path d="M80.1 341.3l.4 .1M80.3 341v1.1M80.3 342.1l.7 .8M80.3 343.6h.1M80.3 342v.1M80.3 342l.8 .8M80.4 341l-.1 1M80.5 341.4h.1M80.7 341.4h-.2M81.1 340.8v.6M81.1 344.6h.1M81.2 340.8v.6h-.4"/>
<path d="M81.2 344.5l1 .9M81.4 344.6h.1M81.7 343.8l.8 .8h1.2M81.8 343.7l.8 .7M81.9 343.6l.8 .7h1M82.1 345.6h.1M82.2 345.4l-.1 .1M82.2 345.4h.1M82.2 345.4h1.4M82.6 344.4h1.1M83.7 344.3l-1.1 .1M84.8 344.3h1"/>
<path d="M84.8 344.4h1.1M84.9 345.4h1.4M85.8 344.3l.1 .1M86.3 345.4h.1M86.4 345.4h.1M86.4 345.6h.1M86.6 343.5l-.8 .8M86.7 343.6l-.8 .8M86.8 343.8l-.8 .8h-1.1M87.1 344.6h.1M87.3 344.4l-1 1M87.3 340.8v.6h.3"/>
<path d="M87.3 344.6h.1M87.5 340.7v.7M88.1 341v1M88.1 342l-.7 .7M88.1 342l.2 .1M88.1 342l-.7 .8M88.1 343.6h.1M88.3 341v1.1M88.3 342.1l-.8 .7M88.3 343.6h.1M88.4 341.3l-.6 .1M88.4 341v1.1l-.7 .8"/>
<path d="M89.2 341.1l-.3 .1M89.2 341.1h.1M89.2 341.9h.1M89.2 341.1v.2M89.2 341.5v.3M89.2 341.9v.2M89.2 342.3l-.9 1.2M89.4 341.9h.1M89.4 341h.1M103.5 352.4h1.7M103.5 351.2h1.7M105.4 357.5v4.8"/>
<path d="M105.4 343.5h.1M105.4 347.9h.4M105.4 347.5h.4M105.4 348.5l.1 .1M105.4 342.9h.4M105.4 350.8v.1M105.4 351v.2M105.5 357.3v4.1M105.5 346.8l-.1 .1M105.7 347.5v.1M105.7 347.9h.1M105.7 342.4v.2"/>
<path d="M105.7 342.8v.1M105.8 352.6h-.4v2.4M105.8 346.8h.4M105.8 343.6h.4M105.8 348.7h.4M105.8 353.3h-.3v2M106.2 352.6h.4l-.1 2.7M106.2 353.3h.3M106.2 347.9h.4M106.2 347.5h.4M106.2 342.9h.4M106.3 347.5v.1"/>
<path d="M106.3 347.9h.1M106.3 342.4v.2M106.3 342.8v.1M106.4 346.8l.2 .1M106.5 357.4l.1 4.9M106.6 348.5l-.2 .1M106.6 343.5h-.2M106.6 350.8v.1M106.6 351.1v.1M107.1 352.4h3.5M107.1 351.2h3.5M110.5 357.5v4.8"/>
<path d="M110.5 347.9h.4M110.5 347.5h.4M110.5 348.5l.1 .1M110.5 342.9h.4M110.5 343.5h.1M110.5 350.8v.1M110.5 351v.2M110.6 357.3v4.1M110.6 346.8l-.1 .1M110.8 347.5v.1M110.8 347.9h.1M110.8 342.4v.2"/>
<path d="M110.8 342.8v.1M110.9 352.6h-.4v2.4M110.9 346.8h.4M110.9 343.6h.4M110.9 348.7h.4M110.9 353.3h-.3v2M111.3 352.6h.4l-.1 2.7M111.3 347.9h.4M111.3 347.5h.4M111.3 353.3h.3M111.3 342.9h.4M111.4 347.5v.1"/>
<path d="M111.4 347.9h.1M111.4 342.4v.2M111.4 342.8v.1M111.5 346.8l.2 .1M111.6 357.4l.1 4.9M111.7 348.5l-.2 .1M111.7 343.5h-.2M111.7 350.8v.1M111.7 351.1v.1M112.4 352.4h3.5M112.4 351.2h3.5M115.6 357.5v4.8"/>
<path d="M115.6 347.9h.3M115.6 347.5h.3M115.6 350.8v.1M115.6 351v.2M115.6 342.9h.3M115.6 348.5v.1M115.6 343.5h.1M115.6 357.3v4.1M115.7 346.8l-.1 .1M115.9 347.5v.1M115.9 347.9h.1M115.9 342.4v.2"/>
<path d="M115.9 342.8v.1M115.9 352.6h-.3v2.4M115.9 346.8h.5M115.9 348.7h.5M115.9 343.6h.5M116 353.3h-.4v2M116.4 352.6h.3v2.7M116.4 353.3h.3M116.4 347.9h.3M116.4 347.5h.3M116.4 342.9h.3M116.5 347.5v.1"/>
<path d="M116.5 347.9h.1M116.5 342.4v.2M116.5 342.8v.1M116.6 346.8l.1 .1M116.7 357.4v4.9M116.7 350.8v.1M116.7 351.1v.1M116.7 343.5h-.1M116.7 348.5l-.1 .1M117.8 352.4h3.5M117.8 351.2h3.5M120.6 357.5v4.8"/>
<path d="M120.6 347.9h.4M120.6 347.5h.4M120.6 350.8v.1M120.6 351v.2M120.6 343.5h.2M120.6 342.9h.4M120.6 348.5l.1 .1M120.7 357.3v4.1M120.8 346.8l-.2 .1M120.9 347.5v.1M120.9 347.9h.1M120.9 342.4v.2"/>
<path d="M120.9 342.8v.1M121 352.6h-.4v2.4M121 346.8h.4M121 348.7h.4M121 343.6h.4M121.1 353.3h-.4v2M121.4 352.6h.4v2.4M121.4 353.3h.3v2M121.5 347.9h.3M121.5 342.4v.2M121.5 342.8l.3 .1M121.7 346.9h.1"/>
<path d="M121.7 357.4v4M121.8 357.5v4.8M121.8 350.8v.1M121.8 351.1v.1M121.8 347.5l-.3 .1M121.8 343.5h-.1M121.8 348.5l-.1 .1M123.1 352.4h3.5M123.1 351.2h3.5M125.7 357.5v4.8M125.7 347.9h.4M125.7 347.5h.4"/>
<path d="M125.7 348.5l.2 .1M125.7 342.9h.4M125.7 343.5h.1M125.7 350.8v.1M125.7 351v.2M125.8 357.3v4.1M125.9 346.8l-.2 .1M126 347.5v.1M126 347.9h.1M126 342.4v.2M126 342.8v.1M126.1 352.6h-.4v2.4"/>
<path d="M126.1 346.8h.4M126.1 343.6h.4M126.1 348.7h.4M126.1 353.3h-.3v2M126.5 352.6h.4v2.4M126.5 353.3h.3v2M126.6 347.9h.3M126.6 342.4v.2M126.6 342.8l.3 .1M126.7 346.8l.2 .1M126.8 357.4v4M126.9 357.5v4.8"/>
<path d="M126.9 347.5l-.3 .1M126.9 343.5h-.2M126.9 348.5l-.2 .1M126.9 350.8v.1M126.9 351.1v.1M128.4 352.4h3.5M128.4 351.2h3.5M130.8 357.5v4.8M130.8 347.5l.3 .1M130.8 348.5l.1 .1M130.8 343.5h.1M130.8 350.8v.1"/>
<path d="M130.8 351v.2M130.9 357.3v4.1M130.9 346.8l-.1 .1M131.1 347.9h-.3M131.1 342.4v.2M131.1 342.8l-.3 .1M131.2 352.6h-.4v2.4M131.2 346.8h.4M131.2 348.7h.4M131.2 343.6h.4M131.2 353.3h-.3v2M131.6 352.6h.4v2.4"/>
<path d="M131.6 347.9h.4M131.6 347.5h.4M131.6 342.9h.4M131.6 353.3h.3v2M131.7 347.5v.1M131.7 347.9h.1M131.7 342.4v.2M131.7 342.8v.1M131.9 346.9h.1M131.9 357.4v4M132 357.5v4.8M132 343.5h-.2"/>
<path d="M132 348.5l-.2 .1M132 350.8v.1M132 351.1v.1M133.8 352.4h3.5M133.8 351.2h3.5M135.9 357.5v4.8M135.9 347.5l.3 .1M135.9 348.5l.1 .1M135.9 343.5h.1M135.9 350.8v.1M135.9 351v.2M136 357.3v4.1"/>
<path d="M136 346.8l-.1 .1M136.2 347.9h-.3M136.2 342.4v.2M136.2 342.8l-.3 .1M136.3 352.6h-.4v2.4M136.3 346.8h.4M136.3 348.7h.4M136.3 343.6h.4M136.3 353.3h-.3v2M136.7 352.6h.4v2.4M136.7 347.9h.4M136.7 347.5h.4"/>
<path d="M136.7 342.9h.4M136.7 353.3h.3v2M136.8 347.5v.1M136.8 347.9h.1M136.8 342.4v.2M136.8 342.8v.1M136.9 346.8l.2 .1M137 357.4v4M137.1 357.5v4.8M137.1 343.5h-.2M137.1 348.5l-.2 .1M137.1 350.8v.1"/>
<path d="M137.1 351.1v.1M139.1 352.4h3.6M139.1 351.2h3.6M141 347.5l.3 .1M141 357.5v4.8M141 350.8v.1M141 351v.2M141 343.5h.1M141 348.5l.1 .1M141 357.3v4.1M141.1 346.8l-.1 .1M141.3 342.4v.2"/>
<path d="M141.3 342.8l-.3 .1M141.3 347.9h-.3M141.3 352.6h-.3v2.4M141.3 346.8h.5M141.3 348.7h.5M141.3 343.6h.5M141.4 353.3h-.4v2M141.8 347.9h.3M141.8 347.5h.3M141.8 352.6h.3v2.4M141.8 353.3h.3v2M141.8 342.9h.3"/>
<path d="M141.9 342.4v.2M141.9 342.8v.1M141.9 347.5v.1M141.9 347.9h.1M141.9 346.8l.2 .1M142.1 357.4v4M142.1 357.5v4.8M142.1 350.8v.1M142.1 351.1v.1M142.1 343.5h-.1M142.1 348.5l-.1 .1M144.5 352.4h3.5"/>
<path d="M144.5 351.2h3.5M146 350.8v.1M146 351v.2M146 343.5h.2M146 347.9h.4M146 347.5h.4M146 342.9h.4M146 348.5l.2 .1M146.1 353.3h.4M146.1 357.3l-.1 5M146.2 346.8l-.2 .1M146.3 342.4v.2"/>
<path d="M146.3 342.8v.1M146.3 347.5v.1M146.3 347.9h.1M146.4 352.6h-.4l.1 2.7M146.4 346.8h.4M146.4 348.7h.4M146.4 343.6h.4M146.8 353.3h.3v2M146.8 352.6h.4v2.4M146.8 347.9h.4M146.8 347.5h.4M146.8 342.9h.4"/>
<path d="M146.9 342.4v.2M146.9 342.8v.1M146.9 347.5v.1M146.9 347.9h.1M147.1 346.9h.1M147.1 357.4v4M147.2 357.5v4.8M147.2 350.8v.1M147.2 351.1v.1M147.2 343.5h-.1M147.2 348.5l-.1 .1M149.8 352.4h3.6"/>
<path d="M149.8 351.2h3.6M151.1 342.9h.4M151.1 343.5h.1M151.1 350.8v.1M151.1 351v.2M151.1 348.5l.2 .1M151.1 347.9h.4M151.1 347.5h.4M151.2 353.3h.3M151.2 357.3l-.1 5M151.3 346.8l-.2 .1M151.4 342.4v.2"/>
<path d="M151.4 342.8v.1M151.4 347.5v.1M151.4 347.9h.1M151.5 352.6h-.4l.1 2.7M151.5 346.8h.4M151.5 348.7h.4M151.5 343.6h.4M151.9 353.3h.3v2M151.9 352.6h.4v2.4M151.9 342.9h.4M151.9 347.9h.4M151.9 347.5h.4"/>
<path d="M152 342.4v.2M152 342.8v.1M152 347.5v.1M152 347.9h.1M152.1 346.8l.2 .1M152.2 357.4v4M152.3 357.5v4.8M152.3 343.5h-.2M152.3 348.5l-.2 .1M152.3 350.8v.1M152.3 351.1v.1M155.2 352.4h3.5"/>
<path d="M155.2 351.2h3.5M156.2 357.5v4.8M156.2 342.9h.4M156.2 348.5l.1 .1M156.2 343.5h.1M156.2 350.8v.1M156.2 351v.2M156.2 347.9h.4M156.2 347.5h.4M156.3 357.3v4.1M156.3 346.8l-.1 .1M156.5 342.4v.2"/>
<path d="M156.5 342.8v.1M156.5 347.5v.1M156.5 347.9h.1M156.6 346.8h.4M156.6 352.6h-.4v2.4M156.6 348.7h.4M156.6 343.6h.4M156.6 353.3h-.3v2M157 353.3h.3v2M157 352.6h.4v2.4M157 342.9h.4M157 347.9h.4"/>
<path d="M157 347.5h.4M157.1 342.4v.2M157.1 342.8v.1M157.1 347.5v.1M157.1 347.9h.1M157.2 346.8l.2 .1M157.3 357.4v4M157.4 343.5h-.2M157.4 348.5l-.2 .1M157.4 350.8v.1M157.4 351.1v.1M157.4 357.5v4.8"/>
<path d="M160.5 352.4h3.5M160.5 351.2h3.5M161.3 357.5v4.8M161.3 348.5l.1 .1M161.3 343.5h.1M161.3 342.9h.4M161.3 350.8v.1M161.3 351v.2M161.3 347.9h.4M161.3 347.5h.4M161.4 357.3v4.1M161.4 346.8l-.1 .1"/>
<path d="M161.6 342.4v.2M161.6 342.8v.1M161.6 347.5v.1M161.6 347.9h.1M161.7 352.6h-.4v2.4M161.7 346.8h.4M161.7 348.7h.4M161.7 343.6h.4M161.7 353.3h-.3v2M162.1 353.3h.3v2M162.1 352.6h.4v2.4M162.1 342.9h.4"/>
<path d="M162.1 347.9h.4M162.1 347.5h.4M162.2 342.4v.2M162.2 342.8v.1M162.2 347.5v.1M162.2 347.9h.1M162.3 346.9h.2M162.4 357.4v4M162.5 357.5v4.8M162.5 343.5h-.2M162.5 348.5l-.2 .1M162.5 350.8v.1"/>
<path d="M162.5 351.1v.1M165.9 352.4h3.5M165.9 351.2h3.5M166.4 357.5v4.8M166.4 350.8v.1M166.4 351v.2M166.4 342.9h.3M166.4 348.5v.1M166.4 343.5h.1M166.4 347.9h.3M166.4 347.5h.3M166.4 357.3v4.1"/>
<path d="M166.5 346.8l-.1 .1M166.7 342.4v.2M166.7 342.8v.1M166.7 347.5v.1M166.7 347.9h.1M166.7 352.6h-.3v2.4M166.7 346.8h.5M166.7 348.7h.5M166.7 343.6h.5M166.8 353.3h-.4v2M167.2 352.6h.3v2.4M167.2 353.3h.2v2"/>
<path d="M167.2 342.9h.3M167.2 347.9h.3M167.2 347.5h.3M167.3 342.4v.2M167.3 342.8v.1M167.3 347.5v.1M167.3 347.9h.1M167.4 357.4v4M167.4 346.9h.1M167.5 357.5v4.8M167.5 350.8v.1M167.5 351.1v.1"/>
<path d="M167.5 348.5l-.1 .1M167.5 343.5h-.1M171.2 352.4h3.5M171.2 351.2h3.5M171.4 357.5v4.8M171.4 350.8v.1M171.4 351v.2M171.4 342.9h.4M171.4 348.5l.1 .1M171.4 343.5h.1M171.4 347.9h.4M171.4 347.5h.4"/>
<path d="M171.5 357.3v4.1M171.6 346.8l-.2 .1M171.7 342.4v.2M171.7 342.8v.1M171.7 347.5v.1M171.7 347.9h.1M171.8 352.6h-.4v2.4M171.8 346.8h.4M171.8 348.7h.4M171.8 343.6h.4M171.9 353.3h-.4v2M172.2 352.6h.4v2.4"/>
<path d="M172.2 353.3h.3v2M172.2 342.9h.4M172.2 347.9h.4M172.2 347.5h.4M172.3 342.4v.2M172.3 342.8v.1M172.3 347.5v.1M172.3 347.9h.1M172.4 346.8l.2 .1M172.5 357.4v4M172.6 357.5v4.8M172.6 350.8v.1"/>
<path d="M172.6 351.1v.1M172.6 343.5h-.1M172.6 348.5l-.1 .1M176.5 357.5v4.8M176.5 342.9h.4M176.5 348.5l.1 .1M176.5 343.5h.1M176.5 350.8v.1M176.5 351v.2M176.5 347.9h.4M176.5 347.5h.4M176.6 352.4h3.5"/>
<path d="M176.6 351.2h3.5M176.6 357.3v4.1M176.7 346.8l-.2 .1M176.8 342.4v.2M176.8 342.8v.1M176.8 347.5v.1M176.8 347.9h.1M176.9 352.6h-.4v2.4M176.9 346.8h.4M176.9 348.7h.4M176.9 343.6h.4M176.9 353.3h-.3v2"/>
<path d="M177.3 352.6h.4v2.4M177.3 353.3h.3v2M177.3 342.9h.4M177.3 347.9h.4M177.3 347.5h.4M177.4 342.4v.2M177.4 342.8v.1M177.4 347.5v.1M177.4 347.9h.1M177.5 346.8l.2 .1M177.6 357.4v4M177.7 357.5v4.8"/>
<path d="M177.7 348.5l-.2 .1M177.7 343.5h-.2M177.7 350.8v.1M177.7 351.1v.1M181.6 347.9h.4M181.6 347.5h.4M181.6 342.9h.4M181.6 357.5v4.8M181.6 343.5h.1M181.6 348.5l.1 .1M181.6 350.8v.1M181.6 351v.2"/>
<path d="M181.7 357.3v4.1M181.7 346.8l-.1 .1M181.9 342.4v.2M181.9 342.8v.1M181.9 347.5v.1M181.9 347.9h.1M181.9 352.4h3.6M181.9 351.2h3.6M182 352.6h-.4v2.4M182 348.7h.4M182 343.6h.4M182 346.8h.4"/>
<path d="M182 353.3h-.3v2M182.4 352.6h.4v2.4M182.4 353.3h.3v2M182.5 342.4v.2M182.5 342.8l.3 .1M182.5 347.9h.3M182.6 346.8l.2 .1M182.7 357.4v4M182.8 357.5v4.8M182.8 343.5h-.2M182.8 348.5l-.2 .1M182.8 350.8v.1"/>
<path d="M182.8 351.1v.1M182.8 347.5l-.3 .1M186.6 357.5v4.8M186.6 347.9h.5M186.6 347.5h.5M186.6 350.8v.1M186.6 351v.2M186.6 342.9h.5M186.6 348.5l.3 .1M186.6 343.5h.2M186.8 357.3v4.1M186.8 346.8l-.2 .1"/>
<path d="M187 342.4v.2M187 342.8v.1M187 347.5v.1M187 347.9h.1M187.1 352.6h-.5v2.4M187.1 346.8h.4M187.1 348.7h.4M187.1 343.6h.4M187.1 353.3h-.3v2M187.3 352.4h3.5M187.3 351.2h3.5M187.5 352.6h.4v2.4"/>
<path d="M187.5 353.3h.2v2M187.6 342.4v.2M187.6 342.8l.3 .1M187.6 347.9h.3M187.7 357.4v4M187.7 346.9h.2M187.9 357.5v4.8M187.9 350.8v.1M187.9 351.1v.1M187.9 347.5l-.3 .1M187.9 348.5l-.2 .1M187.9 343.5h-.2"/>
<path d="M191.7 357.5v4.8M191.7 347.9h.4M191.7 347.5h.4M191.7 342.9h.4M191.7 348.5l.2 .1M191.7 343.5h.1M191.7 350.8v.1M191.7 351v.2M191.8 357.3v4.1M191.9 346.8l-.2 .1M192.1 342.4v.2M192.1 342.8v.1"/>
<path d="M192.1 347.5v.1M192.1 347.9h.1M192.1 352.6h-.4v2.4M192.1 343.6h.5M192.1 348.7h.5M192.1 346.8h.5M192.2 353.3h-.4v2M192.6 352.6h.3v2.4M192.6 353.3h.2v2M192.6 352.4h3.5M192.6 351.2h3.5M192.7 342.4v.2"/>
<path d="M192.7 342.8l.2 .1M192.7 347.9h.2M192.8 346.8l.1 .1M192.8 357.4v4M192.9 357.5v4.8M192.9 347.5l-.2 .1M192.9 343.5h-.1M192.9 348.5l-.1 .1M192.9 350.8v.1M192.9 351.1v.1M196.8 357.5v4.8M196.8 347.5l.3 .1"/>
<path d="M196.8 348.5l.2 .1M196.8 343.5h.2M196.8 350.8v.1M196.8 351v.2M196.9 357.3v4.1M197 346.8l-.2 .1M197.1 342.4v.2M197.1 342.8l-.3 .1M197.1 347.9h-.3M197.2 352.6h-.4v2.4M197.2 348.7h.4M197.2 343.6h.4"/>
<path d="M197.2 346.8h.4M197.3 353.3h-.4v2M197.6 352.6h.4v2.4M197.6 347.9h.4M197.6 347.5h.4M197.6 353.3h.3v2M197.6 342.9h.4M197.7 342.4v.2M197.7 342.8v.1M197.7 347.5v.1M197.7 347.9h.1M197.8 346.8l.2 .1"/>
<path d="M197.9 357.4v4M197.9 352.4h3.6M197.9 351.2h3.6M198 357.5v4.8M198 348.5l-.1 .1M198 343.5h-.1M198 350.8v.1M198 351.1v.1M201.9 357.5v4.8M201.9 347.5l.3 .1M201.9 348.5l.1 .1M201.9 343.5h.1"/>
<path d="M201.9 350.8v.1M201.9 351v.2M202 357.3v4.1M202.1 346.8l-.2 .1M202.2 342.4v.2M202.2 342.8l-.3 .1M202.2 347.9h-.3M202.3 352.6h-.4v2.4M202.3 348.7h.4M202.3 343.6h.4M202.3 346.8h.4M202.3 353.3h-.3v2"/>
<path d="M202.7 352.6h.4v2.4M202.7 347.9h.4M202.7 347.5h.4M202.7 342.9h.4M202.7 353.3h.3v2M202.8 342.4v.2M202.8 342.8v.1M202.8 347.5v.1M202.8 347.9h.1M202.9 346.8l.2 .1M203 357.4v4M203.1 357.5v4.8"/>
<path d="M203.1 350.8v.1M203.1 351.1v.1M203.1 343.5h-.2M203.1 348.5l-.2 .1M203.3 352.4h1.8M203.3 351.2h1.8M327.8 346.7h1M327.8 347.9h1M327.8 347.5h1M327.8 342.9h1M327.8 347.6h1M327.8 348.7h1"/>
<path d="M327.8 343.7h1M327.8 341.2h1M327.8 341.6h1M327.8 342.4h1M329.9 347.6h1.1M329.9 348.7h1.1M329.9 343.7h1.1M329.9 346.7h1.1M329.9 347.9h1.1M329.9 347.5h1.1M329.9 342.9h1.9M329.9 341.2h1.1"/>
<path d="M329.9 341.6h1.1M329.9 342.4h1.9M331 341.3l.3 .1M331 341.1v.1M331.3 341.4h.1M331.3 340.7v.3M331.4 343.6v.4M331.4 344.3v.3M332.5 344.3h.2M332.5 342h.2M332.5 341v.9M332.6 344.6h.1"/>
<path d="M332.6 342.1h.1M332.7 342.9h.8M332.7 342.4h.8M332.7 342.1h.2M332.7 344.6h.1M332.7 342.1h.1M332.9 344.4h-.2M333 357.5v4.8M333 344.3h.3M333 342l.2 .1M333.1 352.6l-.1 2.4M333.3 352.6l.1 2.2"/>
<path d="M333.3 341v1.8M333.3 343.6l-.1 .7M333.4 344.5h.1M333.4 357v4.2M333.4 353.3h.1M333.5 344.3v.1M333.7 353.3h.1M333.8 356.9v4.3M333.9 352.6l-.1 2.1M334.1 352.6l.1 2.4M334.2 357.5v4.8M338.1 357.5v4.8"/>
<path d="M338.2 352.6l-.1 2.4M338.4 352.6v2.2M338.4 357v4.2M338.4 353.3h.1M338.7 353.3h.2M338.9 356.9v4.3M339 352.6l-.1 2.1M339.2 352.6l.1 2.4M339.3 357.5v4.8M463.4 359.2v28.6M482.4 359.2v28.6M104.8 367.8h.8"/>
<path d="M104.8 367.8h.1M104.9 367.6l-.1 .2M105.4 364.8v2.4M105.4 365.5h.1M105.4 367.2h.4M105.4 367.2l-.2 .2M105.5 365.5h.1M105.5 363.4v2.1M106.2 367.2h.4M106.4 367.8h.8M106.5 365.5h.1M106.5 363.5l.1 3.7"/>
<path d="M106.6 365.6h.1M106.6 367.2l.2 .2M107 367.6l.2 .2M107.2 367.8h.1M109.8 367.8h.9M109.8 367.8h.1M110 367.6l-.2 .2M110.5 364.8v2.4M110.5 365.5h.1M110.5 367.2h.4M110.5 367.2l-.2 .2M110.6 365.5h.1"/>
<path d="M110.6 363.4v2.1M111.3 367.2h.4M111.5 367.8h.8M111.6 365.5h.1M111.6 363.5l.1 3.7M111.7 365.6h.1M111.7 367.2l.2 .2M112.1 367.6l.2 .2M112.3 367.8h.1M114.9 367.8h.8M114.9 367.8h.1M115.1 367.6l-.2 .2"/>
<path d="M115.6 364.8v2.4M115.6 365.5h.1M115.6 367.2h.3M115.6 367.2l-.2 .2M115.6 363.4v2.1M116.4 367.2h.3M116.6 367.8h.7M116.7 365.5h.1M116.7 363.5v3.7M116.7 365.6h.1M116.7 367.2l.3 .2M117.2 367.6l.1 .2"/>
<path d="M117.3 367.8h.1M120 367.8h.8M120 367.8h.1M120.2 367.6l-.2 .2M120.6 364.8v2.4M120.6 365.5h.1M120.6 367.2h.4M120.6 367.2l-.2 .2M120.7 365.5h.1M120.7 363.4v2.1M121.4 367.2h.4M121.7 367.8h.7"/>
<path d="M121.7 365.5h.1M121.7 363.5v2M121.8 364.8v2.4M121.8 365.6h.1M121.8 367.2l.2 .2M122.3 367.6l.1 .2M122.4 367.8h.1M125.1 367.8h.8M125.1 367.8h.1M125.3 367.6l-.2 .2M125.7 364.8v2.4M125.7 365.5h.1"/>
<path d="M125.7 367.2h.4M125.7 367.2l-.2 .2M125.8 365.5h.1M125.8 363.4v2.1M126.5 367.2h.4M126.7 367.8h.8M126.8 365.5h.1M126.8 363.5v2M126.9 364.8v2.4M126.9 365.6h.1M126.9 367.2l.2 .2M127.3 367.6l.2 .2"/>
<path d="M127.5 367.8h.1M130.2 367.8h.8M130.2 367.8h.1M130.3 367.6l-.1 .2M130.8 365.5h.1M130.8 364.8v2.4M130.9 365.5h.1M130.9 363.4v2.1M131.2 367.2l-.6 .2M131.6 367.2h.4M131.8 367.8h.8M131.9 365.5h.1"/>
<path d="M131.9 363.5v2M132 364.8v2.4M132 365.6h.1M132 367.2l.2 .2M132.4 367.6l.2 .2M132.6 367.8h.1M135.2 367.8h.9M135.2 367.8h.1M135.4 367.6l-.2 .2M135.9 364.8v2.4M135.9 365.5h.1M136 365.5h.1"/>
<path d="M136 363.4v2.1M136.3 367.2l-.6 .2M136.7 367.2h.4M136.9 367.8h.8M137 365.5h.1M137 363.5v2M137.1 364.8v2.4M137.1 365.6h.1M137.1 367.2l.2 .2M137.5 367.6l.2 .2M137.7 367.8h.1M140.3 367.8h.8"/>
<path d="M140.3 367.8h.1M140.5 367.6l-.2 .2M141 364.8v2.4M141 365.5h.1M141 363.4v2.1M141.3 367.2l-.5 .2M141.8 367.2h.3M142 367.8h.7M142.1 365.5h.1M142.1 363.5v2M142.1 364.8v2.4M142.1 365.6h.1"/>
<path d="M142.1 367.2l.3 .2M142.6 367.6l.1 .2M142.7 367.8h.1M145.4 367.8h.8M145.4 367.8h.1M145.6 367.6l-.2 .2M146.1 365.5h.1M146.1 363.4l-.1 3.8M146.4 367.2l-.6 .2M146.8 367.2h.4M147.1 367.8h.7M147.1 365.5h.1"/>
<path d="M147.1 363.5v2M147.2 365.6h.1M147.2 364.8v2.4M147.2 367.2l.2 .2M147.7 367.6l.1 .2M147.8 367.8h.1M150.5 367.8h.8M150.5 367.8h.1M150.7 367.6l-.2 .2M151.2 365.5h.1M151.2 363.4l-.1 3.8M151.5 367.2l-.6 .2"/>
<path d="M151.9 367.2h.4M152.1 367.8h.8M152.2 365.5h.1M152.2 363.5v2M152.3 365.6h.1M152.3 364.8v2.4M152.3 367.2l.2 .2M152.7 367.6l.2 .2M152.9 367.8h.1M155.6 367.8h.8M155.6 367.8h.1M155.7 367.6l-.1 .2"/>
<path d="M156.2 367.2h.4M156.2 367.2l-.2 .2M156.2 365.5h.1M156.2 364.8v2.4M156.3 365.5h.1M156.3 363.4v2.1M157 367.2h.4M157.2 367.8h.8M157.3 365.5h.1M157.3 363.5v2M157.4 365.6h.1M157.4 364.8v2.4"/>
<path d="M157.4 367.2l.2 .2M157.8 367.6l.2 .2M158 367.8h.1M160.6 367.8h.9M160.6 367.8h.1M160.8 367.6l-.2 .2M161.2 367.2l-.1 .2M161.2 367.2h.5M161.3 365.5h.1M161.3 364.8v2.4M161.4 365.5h.1M161.4 363.4v2.1"/>
<path d="M162.1 367.2h.4M162.3 367.8h.8M162.4 365.5h.1M162.4 363.5v2M162.5 365.6h.1M162.5 364.8v2.4M162.5 367.2l.2 .2M162.9 367.6l.2 .2M163.1 367.8h.1M165.7 367.8h.8M165.7 367.8h.1M165.9 367.6l-.2 .2"/>
<path d="M166.3 367.2l-.1 .2M166.3 367.2h.4M166.4 364.8v2.4M166.4 365.5h.1M166.4 363.4v2.1M167.2 367.2h.3M167.4 367.8h.7M167.4 363.5v2M167.5 365.5h.1M167.5 364.8v2.4M167.5 365.6h.1M167.5 367.2l.3 .2"/>
<path d="M168 367.6l.1 .2M168.1 367.8h.1M170.8 367.8h.8M170.8 367.8h.1M171 367.6l-.2 .2M171.4 367.2l-.2 .2M171.4 367.2h.4M171.4 364.8v2.4M171.4 365.5h.1M171.5 365.5h.1M171.5 363.4v2.1M172.2 367.2h.4"/>
<path d="M172.5 367.8h.7M172.5 363.5v2M172.5 365.5h.1M172.6 364.8v2.4M172.6 365.6h.1M172.6 367.2l.2 .2M173.1 367.6l.1 .2M173.2 367.8h.1M175.9 367.8h.8M175.9 367.8h.1M176.1 367.6l-.2 .2M176.5 367.2h.4"/>
<path d="M176.5 367.2l-.2 .2M176.5 364.8v2.4M176.5 365.5h.1M176.6 365.5h.1M176.6 363.4v2.1M177.3 367.2h.4M177.5 367.8h.8M177.6 363.5v2M177.6 365.5h.1M177.7 364.8v2.4M177.7 365.6h.1M177.7 367.2l.2 .2"/>
<path d="M178.1 367.6l.2 .2M178.3 367.8h.1M181 367.8h.1M181 367.8h.8M181.1 367.6l-.1 .2M181.6 367.2h.4M181.6 367.2l-.2 .2M181.6 364.8v2.4M181.6 365.5h.1M181.7 365.5h.1M181.7 363.4v2.1M182.4 367.2h.4"/>
<path d="M182.6 367.8h.8M182.7 363.5v2M182.7 365.5h.1M182.8 364.8v2.4M182.8 365.6h.1M182.8 367.2l.2 .2M183.2 367.6l.2 .2M183.4 367.8h.1M186 367.8h.9M186 367.8h.1M186.2 367.6l-.2 .2M186.6 364.8v2.4"/>
<path d="M186.6 367.2h.5M186.6 367.2l-.1 .2M186.7 365.5h.1M186.8 365.5h.1M186.8 363.4v2.1M187.5 367.2h.4M187.7 367.8h.8M187.7 363.5v2M187.8 365.5h.1M187.9 364.8v2.4M187.9 365.6h.1M187.9 367.2l.2 .2"/>
<path d="M188.3 367.6l.2 .2M188.5 367.8h.1M191.1 367.8h.1M191.1 367.8h.8M191.3 367.6l-.2 .2M191.7 364.8v2.4M191.7 367.2h.4M191.7 367.2l-.1 .2M191.8 365.5h.1M191.8 363.4v2.1M192.6 367.2h.3M192.8 367.8h.7"/>
<path d="M192.8 363.5v2M192.9 365.5h.1M192.9 364.8v2.4M192.9 365.6h.1M192.9 367.2l.3 .2M193.4 367.6l.1 .2M193.5 367.8h.1M196.2 367.8h.1M196.2 367.8h.8M196.4 367.6l-.2 .2M196.8 364.8v2.4M196.8 367.2h.4"/>
<path d="M196.8 367.2l-.2 .2M196.8 365.5h.1M196.9 365.5h.1M196.9 363.4v2.1M197.6 367.2h.4M197.9 367.8h.7M197.9 363.5v2M197.9 365.5h.1M198 364.8v2.4M198 365.6h.1M198 367.2l.2 .2M198.5 367.6l.1 .2"/>
<path d="M198.6 367.8h.1M201.3 367.8h.1M201.3 367.8h.8M201.5 367.6l-.2 .2M201.9 364.8v2.4M201.9 367.2h.4M201.9 367.2l-.2 .2M201.9 365.5h.1M202 365.5h.1M202 363.4v2.1M202.7 367.2h.4M202.9 367.8h.8"/>
<path d="M203 363.5v2M203 365.5h.1M203.1 364.8v2.4M203.1 365.6h.1M203.1 367.2l.2 .2M203.5 367.6l.2 .2M203.7 367.8h.1M332.4 367.8h.8M332.4 367.8h.1M332.6 367.6l-.2 .2M333 367.2h.4M333 367.2l-.2 .2"/>
<path d="M333 364.8v2.4M333.4 363.5v2.1M333.4 365.6h.1M333.4 365.5h.1M333.7 365.5h.1M333.8 363.4l-.1 2.2M333.8 367.2h.4M334 367.8h.8M334.2 367.2l.2 .2M334.2 364.8v2.4M334.6 367.6l.2 .2M334.8 367.8h.1"/>
<path d="M337.5 367.8h.7M337.5 367.8h.1M337.6 367.6l-.1 .2M338.1 367.2h.3M338.1 367.2l-.2 .2M338.1 364.8v2.4M338.4 363.5v2.1M338.4 365.6h.1M338.4 365.5h.1M338.7 365.5h.2M338.9 363.4l-.2 2.2M338.9 367.2h.4"/>
<path d="M339.1 367.8h.7M339.3 367.2l.2 .2M339.3 364.8v2.4M339.7 367.6l.1 .2M339.8 367.8h.1M514.2 387.9v9.4M574.4 387.9v9.4M526.9 403.7v6.3M552.3 403.7v6.3"/>
</g>
<g fill="none" stroke="#000" stroke-width=".51">
<path d="M118.5 78.5h71.4v2.4h-71.4zM119.2 78.5v-3.4h70v3.4M139.7 78.5v2.4M168.7 78.5v2.4M228.9 78.9l.3 .2-.1 5.1-.3-.1zM236.8 79.4h-7.6M236.9 78.4l1.6 .2-.3 6.2-1.4-.2zM238.5 78.9l13.5 .2a2.5 2.5 0 0 1 2.5 2.5 2.5 2.5 0 0 1-2.5 2.5l-13.5 .2M38.1 84.7h17v1.7h-.4v6.8h.4v1.7h-17zM54.3 95h199.9v3.1h-199.9zM54.7 87l8.5 .1 .3 .5v4.2M54.7 92.1l3.4 .1 .3 .5v2.3"/>
<path d="M54.7 87.5h8.3v4.3M54.7 92.5l3.2 .1v2.4M57.9 99.5h.5M57.9 98.1v2.6h.5v-2.6M59 93.4h3.7v1l1 .5M59 93.4l.3 .6M59.3 93.4v1.5h10v-1.5M60.1 94.3v.6M60.1 94.3h.9M60.1 94.7h.9M60.3 92.4l-.1 .1M61 94.3v.3"/>
<path d="M61 94.7v.2M61.9 93.2l.2 .2M61.9 93.2l7.6 .2M61.9 93.2l-2.9 .2M62.2 93.4v1.5M62.3 92.4l.1-.6h3.8v.6M62.6 92.5l-.1 .7M62.6 92.4h-2.3l-.3 .8M62.6 92.4v.1M62.6 92.4h5.5l.3 .7M63 98.1v2.6h.5v-2.6M63 94.9v.1"/>
<path d="M63 99.5h.5M63.5 94.9v.1M63.6 94.7v.2M65.9 92.4v.1M65.9 92.5l.1 .7M66.6 93.2l-.3 .2v1.5M67.4 94.7h1M67.4 94.3h1M67.4 94.3v.6M67.6 91.8l-.1 .6M67.6 91.8h5.3l.2 1.2M67.6 91.8v.6"/>
<path d="M68.4 93.1l.1 .1M68.4 94.3v.3M68.4 94.7v.2M68.4 93h4.7M68.8 93v.2M69.3 94.7h.5M69.5 93.4h-3.8v1.2l-.9 .3M69.5 93.4l-.2 .6M69.5 93.4h.3M69.8 94.6h.6M70.4 94.9v-.9h1.6v.9M70.7 93.4h1"/>
<path d="M70.7 93v1M71.7 93v1M71.7 98.8v1.2M71.7 98.8l.6-.5h3.9l.5 .5M71.7 98.8h5M72 94.6h.6M72.6 93v1.9h-2.8v-1.9M72.6 93.4h.5M72.8 91.8v2.9M73.1 93.4l-.1 1.3h-.4M73.1 93v.4M73.7 98.1v.2"/>
<path d="M73.7 94h-.3v.9h.3M74.5 94.9h7.7M74.8 98.1v.2M74.8 93.3v-39.1h-1.1v40.8M74.8 94.9v.1M75 93.3l.1-.9h2.3l.1 1.6M75.7 94v.1M76.1 94l-.1-.7h-1.5v1.5M76.1 94.8l-.1 .1M76.7 98.8v1.2M77.5 94.8v.1M77.8 94v.1"/>
<path d="M78.9 93.4v.6M78.9 93.4l-.5 .5M78.9 94.3l-1.1 .6h-2.2M78.9 94.3h2.5l-2.4 .2M79 94.5l-.5 .4M79 92.5l-.1 .9M79 92.5l-.8-.1 .2 2.3M79 94.5v.4M79 94h-3.8v.9M79 93.7l-.4 .2M79 92.5h1.2M79 94.7h.2"/>
<path d="M79.1 92.5v.8M79.2 93.4v.9M79.2 94.5v.4M79.8 92.9l-.1 .3M80.1 92.9h-.6v.3M81.9 93.2l.2 .2M82.1 93.4l.1 .5M82.1 93.4h-3.2M82.2 94.9h7M82.2 93.9v1M82.2 92.4l.1-.6h3.8l.1 .6M82.6 92.4l-.1 .8"/>
<path d="M85.8 92.5l.2 .7M86.3 93.9v1M86.4 93.4l-.2 .6-4-.1M86.4 93.4h3M86.6 93.2l-.2 .2M88.1 92.4l.4 .8M88.2 92.4h-7.9l-.3 .8M88.4 92.9h.6l.1 .3M88.7 92.9l.1 .3M89.2 93.4v.9M89.2 94.5v.4M89.2 94.7h.2"/>
<path d="M89.4 94.5l.6 .4M89.4 94.5l-2.3-.2h2.4l1.1 .6h2.2M89.4 93.4l-10.2-.2-.2 1.1M89.4 94.5v.4M89.4 93.4v.9M89.4 94h3.9M90.2 94.1v.6M90.2 94v.1M90.7 94l.1 .1M90.8 94v.1M91.1 94.8v.1M92.4 94l.1-.7h1.5l.1 1.5-4.9 .1"/>
<path d="M92.7 94v.1M92.8 94l-.1 .1M93.3 94v.1M93.3 93.3l-.1-.9h-2.3l-.1 1.6M93.3 94.1v.8M94.7 93.9l.2 .8h.6M94.7 93.9h.8M95.3 92.9l-.1 1.8M95.5 93.6v1.3l.9-.1M95.5 94.6h.5M96 93.6v1.3M96 94.7h.4"/>
<path d="M96 93.9h.5M96.4 94v.8M96.4 94.8l4.6 .1M96.4 94h1.6v.9M96.5 93.6v.4M97 93.6v.4M97 93.9h.5M97.5 93.6v.4M97.7 92.8l-1 .1M97.7 92.9v-.5h.8v.5M98 93.6v.4M98 93.9h.5"/>
<path d="M98 94.7h.5M98.5 93.6v1.3M98.5 94.6h.5M98.5 92.5h1.7M99 94.7h.2M99 94.8h.2M99 93.9h.1M99.1 93.4l-.1 1.5M99.1 94h.1M99.1 93.4h3.6v1l.8 .3M99.1 93.6h-4.4v.3M99.3 93.4l-.1 1.5"/>
<path d="M100 94.3v.6M100 94.7h1M100 94.3h1M100.1 92.9h-5.1l-.1 .7M101 94.9h2.5M101 94.3v.3M101 94.7v.2M101.9 93.2l.2 .2M102.2 93.4v1.5M102.6 92.4l-.1 .8M103.5 94.9v-10.2h101.6v10.2M103.5 91.8h-1.1l-.2 .6"/>
<path d="M103.5 94.9h104.6v-1.6h-1.8v1.6M103.5 93.2l-4.4 .2M103.5 92.4h-3.2l-.4 .8M103.5 91.5h-6.5l-.2 1.3M104.8 91.1h2.4M104.8 86.1h2.4M104.8 86.1v2.3M104.8 91.1v2.4M104.8 93.5h2.4M104.8 88.4h2.4M104.8 86.1l.6 .6M104.8 91.1l.6 .6"/>
<path d="M105.4 94.9v.1M105.4 92.1h1.2M105.4 87.5h.1M105.4 87h1.2M105.4 86.7v1.1M105.4 91.7v1.2M105.4 87.8l-.6 .6M105.4 92.9l-.6 .6M105.4 92.5h1.2M105.5 87.5h1.1M105.5 87v.5M105.5 92.1v.4"/>
<path d="M106.6 94.9v.1M106.6 98.1l-.3 2.6h-.6l-.3-2.6M106.6 92.9h-1.2M106.6 87.8h-1.2M106.6 87.8l.6 .6M106.6 92.9l.6 .6M106.6 86.7v1.1M106.6 91.7v1.2M106.6 91.7h-1.2M106.6 86.7h-1.2M107.2 86.1v2.3M107.2 91.1v2.4"/>
<path d="M107.2 91.1l-.6 .6M107.2 86.1l-.6 .6M109.8 91.1h2.5M109.8 86.1h2.5M109.8 93.5h2.5M109.8 88.4h2.5M109.8 86.1v2.3M109.8 91.1v2.4M109.8 91.1l.7 .6M109.8 86.1l.7 .6M110.5 86.7h1.2M110.5 86.7v1.1"/>
<path d="M110.5 91.7v1.2M110.5 92.9h1.2M110.5 87.8h1.2M110.5 92.9l-.7 .6M110.5 87.8l-.7 .6M110.5 91.7h1.2M110.5 94.9v.1M110.5 92.5h1.2M110.5 92.1h1.2M110.5 87.5h.1M110.5 87h1.2M110.6 87.5h1.1"/>
<path d="M110.6 87v.5M110.6 92.1v.4M111.7 87.8l.6 .6M111.7 92.9l.6 .6M111.7 86.7v1.1M111.7 91.7v1.2M111.7 94.9v.1M111.7 98.1l-.3 2.6h-.6l-.3-2.6M112.3 86.1v2.3M112.3 91.1v2.4M112.3 91.1l-.6 .6M112.3 86.1l-.6 .6"/>
<path d="M114.9 91.1l.7 .6M114.9 86.1l.7 .6M114.9 91.1h2.4M114.9 86.1h2.4M114.9 93.5h2.4M114.9 88.4h2.4M114.9 86.1v2.3M114.9 91.1v2.4M115.6 86.7v1.1M115.6 91.7v1.2M115.6 87.8h1.1M115.6 92.9l-.7 .6"/>
<path d="M115.6 87.8l-.7 .6M115.6 91.7h1.1M115.6 86.7h1.1M115.6 92.9h1.1M115.6 94.9v.1M115.6 92.5h1.1M115.6 92.1h1.1M115.6 87.5h.1M115.6 87h1.1M115.6 87.5h1.1M115.6 87v.5M115.6 92.1v.4"/>
<path d="M116.7 92.9l.6 .6M116.7 87.8l.6 .6M116.7 86.7v1.1M116.7 91.7v1.2M116.7 98.1l-.2 2.6h-.6l-.3-2.6M116.7 94.9v.1M117.3 91.1l-.6 .6M117.3 86.1l-.6 .6M117.3 86.1v2.3M117.3 91.1v2.4M120 91.1l.6 .6M120 86.1l.6 .6"/>
<path d="M120 91.1h2.4M120 86.1h2.4M120 93.5h2.4M120 88.4h2.4M120 86.1v2.3M120 91.1v2.4M120.6 86.7h1.2M120.6 86.7v1.1M120.6 91.7v1.2M120.6 92.9h1.2M120.6 87.8h1.2M120.6 92.9l-.6 .6"/>
<path d="M120.6 87.8l-.6 .6M120.6 91.7h1.2M120.6 94.9v.1M120.6 92.5h1.2M120.6 92.1h1.2M120.6 87.5h.1M120.6 87h1.2M120.7 87.5h1.1M120.7 87v.5M120.7 92.1v.4M121.7 87v.5M121.7 92.1v.4"/>
<path d="M121.8 92.9l.6 .6M121.8 87.8l.6 .6M121.8 86.7v1.1M121.8 91.7v1.2M121.8 98.1l-.3 2.6h-.6l-.3-2.6M121.8 94.9v.1M122.3 98.1v.4h3.4M122.4 86.1l-.6 .6M122.4 91.1l-.6 .6M122.4 86.1v2.3M122.4 91.1v2.4M125.1 91.1l.6 .6"/>
<path d="M125.1 86.1l.6 .6M125.1 91.1h2.4M125.1 86.1h2.4M125.1 93.5h2.4M125.1 88.4h2.4M125.1 86.1v2.3M125.1 91.1v2.4M125.7 91.7h1.2M125.7 91.7v1.2M125.7 92.9h1.2M125.7 92.9l-.6 .6M125.7 86.7h1.2"/>
<path d="M125.7 86.7v1.1M125.7 87.8h1.2M125.7 87.8l-.6 .6M125.7 98.1l.3 2.6h.6l.3-2.6 .3 .3M125.7 94.9v.1M125.7 92.5h1.2M125.7 92.1h1.2M125.7 87.5h.1M125.7 87h1.2M125.8 87.5h1.1M125.8 87v.5M125.8 92.1v.4"/>
<path d="M126.8 87v.5M126.8 92.1v.4M126.9 92.9l.6 .6M126.9 91.7v1.2M126.9 87.8l.6 .6M126.9 86.7v1.1M126.9 94.9v.1M126.9 98.5h3.9M127.5 91.1l-.6 .6M127.5 86.1l-.6 .6M127.5 86.1v2.3M127.5 91.1v2.4"/>
<path d="M130.2 86.1l.6 .6M130.2 86.1h2.4M130.2 86.1v2.3M130.2 88.4h2.4M130.2 91.1h2.4M130.2 93.5h2.4M130.2 91.1v2.4M130.2 91.1l.6 .6M130.8 86.7v1.1M130.8 87.8l-.6 .6M130.8 92.9h1.2M130.8 91.7v1.2"/>
<path d="M130.8 92.9l-.6 .6M130.8 91.7h1.2M130.8 92.5h1.2M130.8 92.1h1.2M130.8 94.9v.1M130.8 87.5h.1M130.8 87h1.2M130.9 92.1v.4M130.9 87.5h1.1M130.9 87v.5M131.9 92.1v.4M131.9 87v.5"/>
<path d="M132 87.8l.6 .6M132 86.7v1.1M132 86.7h-1.2M132 87.8h-1.2M132 92.9l.6 .6M132 91.7v1.2M132 94.9v.1M132 98.1l-.3 2.6h-.6l-.3-2.6M132 98.5h3.9M132.2 98.5v10.9M132.6 86.1l-.6 .6M132.6 86.1v2.3"/>
<path d="M132.6 91.1v2.4M132.6 91.1l-.6 .6M135.2 86.1l.6 .6M135.2 86.1h2.5M135.2 86.1v2.3M135.2 88.4h2.5M135.2 91.1h2.5M135.2 93.5h2.5M135.2 91.1v2.4M135.2 91.1l.6 .6M135.8 86.7v1.1M135.8 87.8l-.6 .6"/>
<path d="M135.8 92.9h1.3M135.8 91.7v1.2M135.8 92.9l-.6 .6M135.8 91.7h1.3M135.9 86.7v1.1M135.9 92.5h1.2M135.9 92.1h1.2M135.9 91.7v1.2M135.9 94.9v.1M135.9 87.5h.1M135.9 87h1.2M136 92.1v.4"/>
<path d="M136 87.5h1.1M136 87v.5M137 92.1v.4M137 87v.5M137.1 87.8l.6 .6M137.1 86.7v1.1M137.1 86.7h-1.3M137.1 87.8h-1.3M137.1 92.9l.6 .6M137.1 91.7v1.2M137.1 94.9v.1M137.1 98.1l-.3 2.6h-.6l-.3-2.6"/>
<path d="M137.1 98.5h3.9M137.7 86.1l-.6 .6M137.7 86.1v2.3M137.7 91.1v2.4M137.7 91.1l-.6 .6M140.3 86.1l.6 .6M140.3 86.1h2.4M140.3 86.1v2.3M140.3 88.4h2.4M140.3 91.1h2.4M140.3 93.5h2.4M140.3 91.1v2.4"/>
<path d="M140.3 91.1l.6 .6M140.9 86.7v1.1M140.9 87.8l-.6 .6M140.9 92.9h1.2M140.9 91.7v1.2M140.9 92.9l-.6 .6M140.9 91.7h1.2M141 86.7v1.1M141 92.5h1.1M141 92.1h1.1M141 91.7v1.2M141 94.9v.1"/>
<path d="M141 87.5h.1M141 87h1.1M141 92.1v.4M141 87.5h1.1M141 87v.5M142.1 92.1v.4M142.1 87v.5M142.1 87.8l.6 .6M142.1 86.7v1.1M142.1 86.7h-1.2M142.1 87.8h-1.2M142.1 91.7v1.2"/>
<path d="M142.1 92.9l.6 .6M142.1 98.1l-.2 2.6h-.6l-.3-2.6M142.1 94.9v.1M142.1 98.5h3.9M142.7 86.1l-.6 .6M142.7 86.1v2.3M142.7 91.1v2.4M142.7 91.1l-.6 .6M144.1 80.9v3.6h20.2v-3.6M145.4 86.1l.6 .6M145.4 86.1h2.4M145.4 86.1v2.3"/>
<path d="M145.4 88.4h2.4M145.4 91.1h2.4M145.4 93.5h2.4M145.4 91.1v2.4M145.4 91.1l.6 .6M146 86.7v1.1M146 87.8l-.6 .6M146 92.9h1.2M146 91.7v1.2M146 92.9l-.6 .6M146 91.7h1.2M146 92.5h1.2"/>
<path d="M146 92.1h1.2M146 84.5v.2M146 94.9v.1M146 87.5h.1M146 87h1.2M146.1 87.5h1.1M147.1 92.1v.4M147.1 87v.5M147.2 87.8l.6 .6M147.2 86.7v1.1M147.2 86.7h-1.2M147.2 87.8h-1.2"/>
<path d="M147.2 92.9l.6 .6M147.2 91.7v1.2M147.2 98.1l-.3 2.6h-.6l-.3-2.6M147.2 84.5v.2M147.2 94.9v.1M147.2 98.5h3.9M147.8 86.1l-.6 .6M147.8 86.1v2.3M147.8 91.1v2.4M147.8 91.1l-.6 .6M150.5 86.1l.6 .6M150.5 86.1h2.4"/>
<path d="M150.5 86.1v2.3M150.5 88.4h2.4M150.5 91.1h2.4M150.5 93.5h2.4M150.5 91.1v2.4M150.5 91.1l.6 .6M151.1 86.7v1.1M151.1 87.8l-.6 .6M151.1 92.9h1.2M151.1 91.7v1.2M151.1 92.9l-.6 .6M151.1 91.7h1.2"/>
<path d="M151.1 92.5h1.2M151.1 92.1h1.2M151.1 84.5v.2M151.1 94.9v.1M151.1 87.5h.1M151.1 87h1.2M151.2 87.5h1.1M152.2 92.1v.4M152.2 87v.5M152.3 87.8l.6 .6M152.3 86.7v1.1M152.3 86.7h-1.2"/>
<path d="M152.3 87.8h-1.2M152.3 91.7v1.2M152.3 92.9l.6 .6M152.3 84.5v.2M152.3 94.9v.1M152.3 98.1l-.3 2.6h-.6l-.3-2.6M152.3 98.5h3.9M152.9 86.1l-.6 .6M152.9 86.1v2.3M152.9 91.1v2.4M152.9 91.1l-.6 .6M155.6 86.1l.6 .6"/>
<path d="M155.6 86.1h2.4M155.6 86.1v2.3M155.6 88.4h2.4M155.6 91.1h2.4M155.6 93.5h2.4M155.6 91.1v2.4M155.6 91.1l.6 .6M156.2 87.8l-.6 .6M156.2 91.7v1.2M156.2 92.9h1.2M156.2 92.9l-.6 .6M156.2 91.7h1.2"/>
<path d="M156.2 86.7v1.1M156.2 92.5h1.2M156.2 92.1h1.2M156.2 84.5v.2M156.2 94.9v.1M156.2 87.5h.1M156.2 87h1.2M156.3 92.1v.4M156.3 87.5h1.1M156.3 87v.5M157.3 92.1v.4M157.3 87v.5"/>
<path d="M157.4 87.8l.6 .6M157.4 86.7v1.1M157.4 86.7h-1.2M157.4 87.8h-1.2M157.4 91.7v1.2M157.4 92.9l.6 .6M157.4 84.5v.2M157.4 94.9v.1M157.4 98.1l-.3 2.6h-.6l-.3-2.6M157.4 98.5h3.9M158 86.1l-.6 .6M158 86.1v2.3"/>
<path d="M158 91.1v2.4M158 91.1l-.6 .6M160.6 91.1l.6 .6M160.6 86.1l.6 .6M160.6 91.1h2.5M160.6 86.1h2.5M160.6 93.5h2.5M160.6 86.1v2.3M160.6 91.1v2.4M160.6 88.4h2.5M161.2 87.8l-.6 .6M161.2 92.9l-.6 .6"/>
<path d="M161.2 91.7h1.3M161.3 86.7l-.1 1.1M161.3 91.7l-.1 1.2M161.3 84.5v.2M161.3 94.9v.1M161.3 92.5h1.2M161.3 92.1h1.2M161.3 87.5h.1M161.3 87h1.2M161.4 87.5h1.1M161.4 87v.5M161.4 92.1v.4"/>
<path d="M162.4 87v.5M162.4 92.1v.4M162.5 92.9l.6 .6M162.5 87.8l.6 .6M162.5 86.7v1.1M162.5 91.7v1.2M162.5 86.7h-1.3M162.5 92.9h-1.3M162.5 87.8h-1.3M162.5 84.5v.2M162.5 94.9v.1M162.5 98.1l-.3 2.6h-.6l-.3-2.6"/>
<path d="M162.5 98.5h3.9M163.1 86.1l-.6 .6M163.1 91.1l-.6 .6M163.1 86.1v2.3M163.1 91.1v2.4M165.7 91.1l.6 .6M165.7 86.1l.6 .6M165.7 86.1h2.4M165.7 86.1v2.3M165.7 88.4h2.4M165.7 91.1h2.4M165.7 93.5h2.4"/>
<path d="M165.7 91.1v2.4M166.3 92.9l-.6 .6M166.3 87.8l-.6 .6M166.4 91.7l-.1 1.2M166.4 86.7l-.1 1.1M166.4 94.9v.1M166.4 92.5h1.1M166.4 92.1h1.1M166.4 87.5h.1M166.4 87h1.1M166.4 87.5h1.1M166.4 92.1v.4"/>
<path d="M166.4 87v.5M167.4 87v.5M167.4 92.1v.4M167.5 92.9l.6 .6M167.5 87.8l.6 .6M167.5 91.7v1.2M167.5 91.7h-1.2M167.5 92.9h-1.2M167.5 86.7v1.1M167.5 86.7h-1.2M167.5 87.8h-1.2M167.5 98.1l-.2 2.6h-.6l-.3-2.6"/>
<path d="M167.5 94.9v.1M167.5 98.5h3.9M168.1 91.1l-.6 .6M168.1 86.1l-.6 .6M168.1 86.1v2.3M168.1 91.1v2.4M170.8 91.1l.6 .6M170.8 86.1l.6 .6M170.8 86.1h2.4M170.8 86.1v2.3M170.8 88.4h2.4M170.8 91.1h2.4"/>
<path d="M170.8 93.5h2.4M170.8 91.1v2.4M171.4 92.9l-.6 .6M171.4 87.8l-.6 .6M171.4 91.7v1.2M171.4 86.7v1.1M171.4 94.9v.1M171.4 92.5h1.2M171.4 92.1h1.2M171.4 87.5h.1M171.4 87h1.2M171.5 92.1v.4"/>
<path d="M171.5 87.5h1.1M171.5 87v.5M172.5 92.1v.4M172.5 87v.5M172.6 92.9l.6 .6M172.6 87.8l.6 .6M172.6 91.7v1.2M172.6 91.7h-1.2M172.6 92.9h-1.2M172.6 86.7v1.1M172.6 98.1l-.3 2.6h-.6l-.3-2.6M172.6 86.7h-1.2"/>
<path d="M172.6 87.8h-1.2M172.6 94.9v.1M172.6 98.5h3.9M173.2 91.1l-.6 .6M173.2 86.1l-.6 .6M173.2 86.1v2.3M173.2 91.1v2.4M175.9 86.1l.6 .6M175.9 86.1h2.4M175.9 86.1v2.3M175.9 88.4h2.4M175.9 91.1l.6 .6"/>
<path d="M175.9 91.1h2.4M175.9 93.5h2.4M175.9 91.1v2.4M176.2 98.5v10.9M176.5 87.8l-.6 .6M176.5 91.7v1.2M176.5 92.9h1.2M176.5 92.9l-.6 .6M176.5 91.7h1.2M176.5 86.7v1.1M176.5 92.5h1.2M176.5 92.1h1.2"/>
<path d="M176.5 94.9v.1M176.5 87.5h.1M176.5 87h1.2M176.6 92.1v.4M176.6 87.5h1.1M176.6 87v.5M177.6 92.1v.4M177.6 87v.5M177.7 87.8l.6 .6M177.7 91.7v1.2M177.7 92.9l.6 .6M177.7 86.7v1.1"/>
<path d="M177.7 86.7h-1.2M177.7 87.8h-1.2M177.7 94.9v.1M177.7 98.1l-.3 2.6h-.6l-.3-2.6M177.7 98.5h3.9M178.3 86.1l-.6 .6M178.3 86.1v2.3M178.3 91.1l-.6 .6M178.3 91.1v2.4M181 93.5h2.4M181 86.1v2.3M181 91.1v2.4"/>
<path d="M181 88.4h2.4M181 91.1l.6 .6M181 91.1h2.4M181 86.1h2.4M181 86.1l.6 .6M181.6 87.8l-.6 .6M181.6 92.9l-.6 .6M181.6 91.7h1.2M181.6 91.7v1.2M181.6 87.5h.1M181.6 86.7v1.1M181.6 92.5h1.2"/>
<path d="M181.6 92.1h1.2M181.6 94.9v.1M181.6 87h1.2M181.7 87v.5M181.7 87.5h1.1M181.7 92.1v.4M182.7 92.1v.4M182.7 87v.5M182.8 87.8l.6 .6M182.8 92.9l.6 .6M182.8 91.7v1.2M182.8 92.9h-1.2"/>
<path d="M182.8 86.7v1.1M182.8 86.7h-1.2M182.8 87.8h-1.2M182.8 94.9v.1M182.8 98.1l-.3 2.6h-.6l-.3-2.6-.3 .3M183.4 86.1l-.6 .6M183.4 86.1v2.3M183.4 91.1v2.4M183.4 91.1l-.6 .6M186 86.1l.6 .6M186 93.5h2.5M186 86.1v2.3"/>
<path d="M186 91.1v2.4M186 88.4h2.5M186 91.1h2.5M186 86.1h2.5M186 91.1l.6 .6M186.1 98.1v.5h-3.3M186.6 91.7h1.3M186.6 86.7h1.3M186.6 86.7v1.1M186.6 91.7v1.2M186.6 92.9h1.3M186.6 87.8h1.3"/>
<path d="M186.6 87.8l-.6 .6M186.6 92.5h1.3M186.6 92.1h1.3M186.6 94.9v.1M186.6 92.9l-.6 .6M186.6 87.5h.2M186.6 87h1.3M186.8 92.1v.4M186.8 87.5h1.1M186.8 87v.5M187.7 92.1v.4M187.7 87v.5"/>
<path d="M187.9 86.7v1.1M187.9 91.7v1.2M187.9 92.9l.6 .6M187.9 87.8l.6 .6M187.9 98.1l-.3 2.6h-.6l-.4-2.6M187.9 94.9v.1M188.5 86.1v2.3M188.5 91.1v2.4M188.5 91.1l-.6 .6M188.5 86.1l-.6 .6M191.1 86.1l.6 .6M191.1 86.1v2.3"/>
<path d="M191.1 88.4h2.4M191.1 86.1h2.4M191.1 91.1l.6 .6M191.1 93.5h2.4M191.1 91.1v2.4M191.1 91.1h2.4M191.7 91.7h1.2M191.7 87.8l-.6 .6M191.7 91.7v1.2M191.7 92.9h1.2M191.7 92.5h1.2M191.7 92.1h1.2"/>
<path d="M191.7 86.7v1.1M191.7 94.9v.1M191.7 92.9l-.6 .6M191.7 87.5h.1M191.7 87h1.2M191.8 92.1v.4M191.8 87.5h1.1M191.8 87v.5M192.8 92.1v.4M192.8 87v.5M192.9 87.8l.6 .6M192.9 92.9l.6 .6"/>
<path d="M192.9 91.7v1.2M192.9 86.7v1.1M192.9 94.9v.1M192.9 98.1l-.2 2.6h-.6l-.4-2.6M192.9 86.7h-1.2M192.9 87.8h-1.2M193.5 86.1l-.6 .6M193.5 86.1v2.3M193.5 91.1v2.4M193.5 91.1l-.6 .6M196.2 86.1l.6 .6M196.2 93.5h2.4"/>
<path d="M196.2 88.4h2.4M196.2 86.1v2.3M196.2 91.1v2.4M196.2 91.1l.6 .6M196.2 91.1h2.4M196.2 86.1h2.4M196.8 86.7h1.2M196.8 87.8l-.6 .6M196.8 86.7v1.1M196.8 87.8h1.2M196.8 91.7h1.2M196.8 91.7v1.2"/>
<path d="M196.8 94.9v.1M196.8 92.9h1.2M196.8 92.9l-.6 .6M196.8 92.5h1.2M196.8 92.1h1.2M196.8 87.5h.1M196.8 87h1.2M196.9 87.5h1.1M196.9 87v.5M196.9 92.1v.4M197.9 87v.5M197.9 92.1v.4"/>
<path d="M198 87.8l.6 .6M198 86.7v1.1M198 92.9l.6 .6M198 91.7v1.2M198 94.9v.1M198 98.1l-.3 2.6h-.6l-.3-2.6M198.6 86.1l-.6 .6M198.6 86.1v2.3M198.6 91.1v2.4M198.6 91.1l-.6 .6M201.3 93.5h2.4M201.3 88.4h2.4"/>
<path d="M201.3 86.1v2.3M201.3 91.1v2.4M201.3 91.1h2.4M201.3 86.1h2.4M201.3 86.1l.6 .6M201.3 91.1l.6 .6M201.9 86.7v1.1M201.9 87.8l-.6 .6M201.9 94.9v.1M201.9 86.7h1.2M201.9 87.5h.1M201.9 87.8h1.2"/>
<path d="M201.9 92.5h1.2M201.9 92.1h1.2M201.9 87h1.2M201.9 91.7v1.2M201.9 92.9l-.6 .6M202 87v.5M202 87.5h1.1M202 92.1v.4M203 87v.5M203 92.1v.4M203.1 98.1l-.3 2.6h-.6l-.3-2.6M203.1 87.8l.6 .6"/>
<path d="M203.1 86.7v1.1M203.1 94.9v.1M203.1 92.9l.6 .6M203.1 91.7v1.2M203.1 91.7h-1.2M203.1 92.9h-1.2M203.7 86.1v2.3M203.7 91.1v2.4M203.7 86.1l-.6 .6M203.7 91.1l-.6 .6M205.1 92.8h1.4M205.1 93.3v1.6"/>
<path d="M205.1 91.5h6.4l.2 .9M205.1 94.3h.9M206 92.8v2.1M206 94.7h.3M206 93.3h.3M206.5 93.3v-.9h.8v.9M207.3 92.5h2.4M208.1 94.8h1.1M209 93.4h3.8v1.2l.8 .1v.2M209 93.4l.2 .6M209.2 93.4v1.5M210.1 94.3v.6"/>
<path d="M210.1 94.7h.9M210.1 94.3h.9M210.1 92.5l-.1 .7M210.3 92.4h.1M211 94.3v.3M211 94.7v.2M211.9 93.2l-2.9 .2M211.9 93.2l.3 .2v1.5M211.9 93.2l7.5 .2M212.3 92.4v-.6h7.1l.1 .7M212.5 92.5v.7M212.6 92.4v.1"/>
<path d="M215.9 92.4v.1M215.9 92.5l.1 .7M216.1 91.8l.1 .6M216.6 93.2l-.3 .2v1.5M217.5 94.3v.6M217.5 94.7h.9M217.5 94.3h.9M218.1 92.4l.2 .1M218.3 92.5h2.1M218.3 92.5l.2 .7M218.4 94.3v.3M218.4 94.7v.2"/>
<path d="M218.7 92.4h-9v.8M219.2 94.8l1.1 .1M219.2 93.4v1.5M219.2 94h2.8v.9M219.3 91.8l.1 .7M219.4 93.4v.6M219.4 93.3h.9M219.4 93.4h-3.7v1.2l-.9 .3M220.3 92.4v.1M220.3 94v.1M220.4 94v.9M220.8 94v-.7h-.5v.8"/>
<path d="M221.2 92.4v1.6M221.2 93.3h1.7M222 94.5h.2M222.2 93.3v1.5M222.8 93.3v1.5M222.8 93.3h1.9v1.5M222.9 93.3v-.6h1.6v.6M223 92.4l.1 .3M223.2 92.4v.3M224.1 92.4v.3M224.1 92.4l.1 .3M224.1 92.4h-3.7v.9"/>
<path d="M224.5 93.3h.8v1.6l-16.2-.1M226.4 94v.9M226.4 94.6h-.8v.3h5.4M226.4 94h1.6v.9M226.6 91.5l-.2 2.5M227.2 92.5l.3 1M227.3 92.4v1.2M227.3 92.5h1.4l-.1 1M227.3 93h1.4M227.5 92.3h1.1M227.5 93.6h1.1zM228 94.6h.7"/>
<path d="M228.7 94.7h.5M228.7 92.5v.9M228.8 94.1l-.1 .8M228.9 94.1h.1M228.9 94.7v.2M229.1 93.4h3.6l.1 1.2 .8 .3 2.1-.3v-1.2h3.7M229.1 93.4l.1 .6M229.2 93.4v1.5M229.4 91.2v2M229.4 91.2h-2.8v2.8M229.4 91.2h26.2v3.5h-7M229.4 91.5h1"/>
<path d="M229.9 93.2l.4-.8h7.9l.3 .8M230 94.3v.6M230 94.7h1M230 94.3h1M230.1 92.7v.1M230.1 92.2v.5M230.1 92v.1M230.2 91.9h.1M230.4 91.5v.4h1.8M230.4 91.5l7.1 .2M230.4 91.6h3.6M230.4 91.5h9.6"/>
<path d="M231 94.3v.3M231 94.7v.2M231 94.9h6.4M231.9 93.2l.2 .2M232.1 93.4v1.5M232.2 85.8h7.1v.8h-7.1zM232.2 91.9v.5M232.5 92.5l-.1 .7M232.6 92.4v.1M233.2 98.1a3.8 3.8 0 0 0 .5 3.1 2.41 2.41 0 0 0 2.6 .9 2.41 2.41 0 0 0 1.7-2v-2M233.2 86.6v4.6M233.2 94.9v.1"/>
<path d="M233.6 94.7v.2M234.9 94.7v.2M235.9 92.4l.1 .8M236.3 91.9h3.9M236.3 91.9h-4.1M236.3 91.9v.5M236.3 93.4v1.5M236.6 93.2l-.2 .2M236.8 83.8h-7.6M237.4 94.7h1.1M237.4 94.3v.6M237.4 94.3h1.1"/>
<path d="M237.5 91.7l.4 .2M238 91.5v.4M238 94.9v.1M238 86.6v4.6M238.4 93h1.8M238.5 94.3v.3M238.5 94.7v.2M238.5 93.1l.2 .1M239.1 93l1.1 .2M239.3 94.7h5.7M239.3 93.2l.1 .2M239.3 93.4v1.5h-1.9"/>
<path d="M239.4 93.4l-.1 .6M239.4 93.6h.6M239.5 93l.8 .2-11.2 .2M240.1 91.5l-2.6 .2M240.1 93.6h.1M240.2 93.1h.1M240.3 91.3v.5zM241.1 89.1h.6M241.1 89.1v2.1v-.3h.6M241.1 93.3v.1M241.2 93.6l.3 .1M241.2 93.2h.3"/>
<path d="M241.3 93.1h.2M241.3 92.5v.5h1.9M241.4 93.7h.1M241.5 94.8l-.8 .2M241.5 94.7v.3M241.5 92.3h1.6M241.5 94.5v.3M241.5 92.3v1.4M241.5 92.5h1.7v1h-1.7M241.7 89.1v2.1M241.9 89.5l-.1 1.7 .3-.3M241.9 89.1l-.2 .3"/>
<path d="M242 88.5l-.9 .6M242 88.5h14.1v6.3h-4.4M242 88.5l.2 .7-.5 .5M242.1 90.9v.3M242.1 94.7l-.3 .3M242.2 88.5l-.1 2.4M242.8 93.5l-1.1 .1M242.8 93.5l.1 .1M243.2 93.7h.1M243.3 92.5v.5M243.4 93.2l.1 .1M243.5 93.3v.1"/>
<path d="M243.7 94.7v.3M244.5 94.7v.2M244.8 93.9l-.8 .5M244.8 94l.2 .1M245 94.2v.7M245 94.6h3.6M245 94.4l-5.7 .1M246.8 94.9v.1M248.4 94.9v.1M248.6 94.3v.6M248.6 94.9h-4.9M248.6 94.8h.5"/>
<path d="M248.6 94.2v.1M248.8 94l-.2 .1M248.8 93.9l.4 .1M249 94.7v.1M249.1 94.7v.1M249.1 94.9l.1 .1M249.3 94.1h.1M249.5 94.4h.1M249.6 94.4l-1 .1 5.5-.1M251 93.3v.1M251.2 92.5v1h1.6v-1h-1.6v.5h1.6M251.4 92.3h1.6"/>
<path d="M251.5 93.6l-.3 .1M251.7 93.5l-.1 .1M251.7 94.7v.3M251.7 93.5h1.1M252.5 94.7v.1M253.1 93.7h.1M253.2 92.5v.5M253.3 93.2l.1 .2M254.2 94.1v.6M254.2 93.3l.8 .4M254.2 93h1l.4 .5h-.5M254.2 91.5h1.4"/>
<path d="M254.2 93.4l.4 .3M254.2 93.2l.9 .4M254.2 93h.2M254.2 92.1h.2M254.2 91.2v3M254.5 92.2l.1 .2M254.6 93.7v1M254.6 93.7h.4M254.6 93.2l.4 .4M254.6 92.4v.4M254.7 93l.4 .5M254.9 91.5v1.5"/>
<path d="M255 93.6h.1M255 93.6v.1M255.1 93.5v.1M63 100h-1.4v11l.7 1 23.5 .1 1-.7 .1-11.4h-23.4M65 100l-.1 2.1h.9v-2.1M65 101h.8M65.7 100l-.1 2.1M65.7 100v-1.7h2v1.7M73.2 101h.2M73.2 100v2.1h2.1v-2.1M73.4 100v1.6l.5 .3 1.2-.3v-1.6M75.1 101h.2"/>
<path d="M80.8 100v-1.7h2v2.7M82.7 100v2.1h.9v-2.1M82.9 101v1.1M83.5 100v1h-.8M125.9 100v9.4h16.1v-8.1h24.5v8.1h16.2v-9.4M166.5 102.8l-.8 .5-.9 2 .4 .2 .9-2 .4-.1M103.5 173.1h101.6v17h-101.6zM331 173.1h10.2v17h-1.7v-.4h-6.8v.4h-1.7zM103.5 188.4h-41.2a8 8 0 0 0-8 8v61.3M105.4 190.1v8.3h1.2v-8.3M105.4 197.4a.99 .99 0 0 0-.1 1.5 .99 .99 0 0 0 1.4 0 .99 .99 0 0 0-.1-1.5M105.4 192.3a.98 .98 0 0 0 0 1.6"/>
<path d="M106.6 192.3a1.04 1.04 0 0 1 0 1.6M110.5 190.1v8.3h1.2v-8.3M110.5 192.3a.98 .98 0 0 0 0 1.6M111.7 197.4a.99 .99 0 0 1 .1 1.5 .99 .99 0 0 1-1.5 0 .99 .99 0 0 1 .2-1.5M111.7 192.3a1.04 1.04 0 0 1 0 1.6M115.6 190.1v8.3h1.1v-8.3M115.6 192.3a.98 .98 0 0 0 0 1.6M116.7 197.4a.99 .99 0 0 1 .2 1.5 .99 .99 0 0 1-1.5 0 .99 .99 0 0 1 .2-1.5M116.7 192.3a1.04 1.04 0 0 1 0 1.6M120.6 190.1v8.3h1.2v-8.3M120.6 192.3a.98 .98 0 0 0 0 1.6M120.6 197.4a.99 .99 0 0 0-.1 1.5 .99 .99 0 0 0 1.5 0 .99 .99 0 0 0-.2-1.5"/>
<path d="M121.8 192.3a1.04 1.04 0 0 1 0 1.6M125.7 190.1v8.3h1.2v-8.3M125.7 192.3a.98 .98 0 0 0 0 1.6M126.9 197.4a.99 .99 0 0 1 .1 1.5 .99 .99 0 0 1-1.4 0 .99 .99 0 0 1 .1-1.5M126.9 192.3a1.04 1.04 0 0 1 0 1.6M130.8 190.1v8.3h1.2v-8.3M130.8 197.4a.99 .99 0 0 0-.1 1.5 .99 .99 0 0 0 1.4 0 .99 .99 0 0 0-.1-1.5M130.8 192.3a.98 .98 0 0 0 0 1.6M132 192.3a1.04 1.04 0 0 1 0 1.6M135.9 190.1v8.3h1.2v-8.3M135.9 192.3a.98 .98 0 0 0 0 1.6M137.1 197.4a.99 .99 0 0 1 .1 1.5 .99 .99 0 0 1-1.5 0 .99 .99 0 0 1 .2-1.5"/>
<path d="M137.1 192.3a1.04 1.04 0 0 1 0 1.6M141 190.1v8.3h1.1v-8.3M141 192.3a.98 .98 0 0 0 0 1.6M142.1 197.4a.99 .99 0 0 1 .2 1.5 .99 .99 0 0 1-1.5 0 .99 .99 0 0 1 .2-1.5M142.1 192.3a1.04 1.04 0 0 1 0 1.6M146 190.1v8.3h1.2v-8.3M146 192.3a.98 .98 0 0 0 0 1.6M146 197.4a.99 .99 0 0 0-.1 1.5 .99 .99 0 0 0 1.5 0 .99 .99 0 0 0-.2-1.5M147.2 192.3a1.04 1.04 0 0 1 0 1.6M151.1 190.1v8.3h1.2v-8.3M151.1 192.3a.98 .98 0 0 0 0 1.6M152.3 197.4a.99 .99 0 0 1 .1 1.5 .99 .99 0 0 1-1.4 0 .99 .99 0 0 1 .1-1.5"/>
<path d="M152.3 192.3a1.04 1.04 0 0 1 0 1.6M156.2 190.1v8.3h1.2v-8.3M156.2 192.3a.98 .98 0 0 0 0 1.6M157.4 197.4a.99 .99 0 0 1 .1 1.5 .99 .99 0 0 1-1.4 0 .99 .99 0 0 1 .1-1.5M157.4 192.3a1.04 1.04 0 0 1 0 1.6M161.3 190.1v8.3h1.2v-8.3M161.3 192.3a.98 .98 0 0 0 0 1.6M162.5 197.4a.99 .99 0 0 1 .1 1.5 .99 .99 0 0 1-1.5 0 .99 .99 0 0 1 .2-1.5M162.5 192.3a1.04 1.04 0 0 1 0 1.6M166.4 190.1v8.3h1.1v-8.3M166.4 197.4a.99 .99 0 0 0-.2 1.5 .99 .99 0 0 0 1.5 0 .99 .99 0 0 0-.2-1.5M166.4 192.3a.98 .98 0 0 0 0 1.6"/>
<path d="M167.5 192.3a1.04 1.04 0 0 1 0 1.6M171.4 190.1v8.3h1.2v-8.3M171.4 192.3a.98 .98 0 0 0 0 1.6M172.6 197.4a.99 .99 0 0 1 .2 1.5 .99 .99 0 0 1-1.5 0 .99 .99 0 0 1 .1-1.5M172.6 192.3a1.04 1.04 0 0 1 0 1.6M176.5 190.1v8.3h1.2v-8.3M176.5 192.3a.98 .98 0 0 0 0 1.6M177.7 197.4a.99 .99 0 0 1 .1 1.5 .99 .99 0 0 1-1.4 0 .99 .99 0 0 1 .1-1.5M177.7 192.3a1.04 1.04 0 0 1 0 1.6M181.6 197.4a.99 .99 0 0 0-.1 1.5 .99 .99 0 0 0 1.4 0 .99 .99 0 0 0-.1-1.5M181.6 192.3a.98 .98 0 0 0 0 1.6M181.6 190.1v8.3h1.2v-8.3"/>
<path d="M182.8 192.3a1.04 1.04 0 0 1 0 1.6M186.6 190.1v8.3h1.3v-8.3M186.6 192.3a1.04 1.04 0 0 0 0 1.6M187.9 197.4a1 1 0 0 1 .1 1.5 1 1 0 0 1-1.5 0 1 1 0 0 1 .1-1.5M187.9 192.3a1.04 1.04 0 0 1 0 1.6M191.7 197.4a1 1 0 0 0-.1 1.5 1 1 0 0 0 1.5 0 1 1 0 0 0-.2-1.5M191.7 190.1v8.3h1.2v-8.3M191.7 192.3a1.04 1.04 0 0 0 0 1.6M192.9 192.3a1.04 1.04 0 0 1 0 1.6M196.8 190.1v8.3h1.2v-8.3M196.8 192.3a1.04 1.04 0 0 0 0 1.6M198 197.4a1 1 0 0 1 .1 1.5 1 1 0 0 1-1.4 0 1 1 0 0 1 .1-1.5"/>
<path d="M198 192.3a1.04 1.04 0 0 1 0 1.6M201.9 190.1v8.3h1.2v-8.3M201.9 192.3a1.04 1.04 0 0 0 0 1.6M203.1 197.4a1 1 0 0 1 .1 1.5 1 1 0 0 1-1.4 0 1 1 0 0 1 .1-1.5M203.1 192.3a1.04 1.04 0 0 1 0 1.6M205.1 188.4h41.1a8 8 0 0 1 8 8v28M213.9 198.8h1.7v3.2h-1.7zM213.9 199.4h1.7M215.1 194.6h3.2v1.6h-3.2zM215.7 194.6v1.6M217.8 194.6v1.6M217.9 198.8h1.6v3.2h-1.6v-2.6"/>
<path d="M217.9 199.4h1.6M217.9 198.9v.5M217.9 198.8v.1M221.1 194.6h3.3v1.6h-3.3zM221.3 194.6l.4 .2M221.7 196l-.4 .2M221.7 194.6v1.6M223.7 194.6v1.6M223.7 196l.5 .2M224.2 194.6l-.5 .2M326.4 192.9v.4M326.4 198v.4"/>
<path d="M327.8 198h-2.6v.4h2.6M327.8 192.9h-2.6v.4h2.6M327.8 188.4h3.2v164h-3.2zM331.1 198.8l.8 .1-.1 3.1-.8-.1zM331.9 199.3v.1M331.9 194.6v1.6h-.9v-1.6h2.2v1.6h-1.2l.1-1.6M333.4 189.7l-.1 3.2h-2.3M333.8 189.7l-.1 3.3-.5 .3h-2.2M338.4 189.7v8.3h-7.4M338.9 189.7v8.1l-.3 .5-7.6 .1M73.4 218.8h1.7v3.2h-1.7zM73.4 219.4h1.7"/>
<path d="M73.7 215.4l.4 .5 .7-.5M73.7 215.4v.5M73.7 215.4l.7-.5 .4 .5M74.8 215.4v.5M78.2 214.2h.8v2.5h-.8zM79 218.7v5.5M79 214.2h2.4M79 216.6h2.4M79.1 218.6l-.1 .1M79.1 218.6h2.3M81.4 218.6v.1M81.4 218.5v.1"/>
<path d="M81.4 218.7v5.5M81.4 214.2h.8v2.5h-.8zM81.4 218.4l.3 5.8M81.4 218.5l-2.5 .1v5.6M81.4 218.5v.2M81.7 219.1h1.1v.8h-1.1M82.2 219.1v.8M85.5 219.8h1.5v3.2h-1.5zM96.3 206.6v1.6M97 214.6h12.5M97 214.6l-.2-.1v6.9l.2-.2M97 214.6v6.6"/>
<path d="M98.2 206.6h.6M98.2 206.6v1.6M98.8 206.6h.1M98.8 206.6v1.6h-3.2v-1.6h2.6M101 212.5h4.5M101.6 206.6h3.3v1.6h-3.3zM101.8 206.6l.4 .2M102.2 208l-.4 .2M102.2 206.6v1.6M102.4 206.6v1.6M104.1 206.6v1.6M104.3 206.6v1.6"/>
<path d="M104.3 208l.4 .2M104.7 206.6l-.4 .2M105.5 214.4v-3.5h-4.5v3.5M109.5 214.6v6.6M109.7 214.5l-.2 .1M109.8 214.4h-13.1v7h13.1M109.8 214.4v7M111.2 209.5h10M111.2 209.5l.3 .3M111.2 219.5h10M111.2 209.6v9.9M111.5 209.8h8.1"/>
<path d="M111.5 219.2h9.4M111.5 219.2l-.3 .3M111.5 209.8v9.4M112 209.5v-.4h1.8v.4M113.8 219.5v.4h-1.8v-.4M114.5 205.1h.6v1.6h-.6zM115.1 206.7h2M115.1 205.2h2M115.6 218.8h1.1M116.7 218.8a4.3 4.3 0 0 0 3.1-6.6 4.3 4.3 0 0 0-7.3 0 4.3 4.3 0 0 0 3.1 6.6M117.1 205.1h.7v1.6h-.7zM118.4 209.5v-.4h1.9v.4"/>
<path d="M119.6 209.8l1.3 1.2M120.3 219.5v.4h-1.9v-.4M120.9 219.2l.3 .3M120.9 211v8.2M121 209.7l-1.4 .1M121 209.7l-.1 1.3M121.2 209.5l-.2 .2M121.2 209.5v10M163.6 211.7h1.6v3.2h-1.6v-2.6M163.6 214.3h1.6M163.6 212.3h1.6M163.6 211.8v.5"/>
<path d="M163.6 211.7v.1M167.7 219.1l.2 .1M168 219.2l-.1 .1M168.8 216.7v-2.2h-1v3.2M170.3 216.6v.3M173.6 216.8l.2 .1M173.8 206.7h1.6M173.8 204.6h1.6M173.8 204.6v-.6h1.6v3.3h-1.6v-.5M173.8 204.6v2.2M173.8 216.6l-.1 .2M175.2 216.7v-2.2h1v3.2"/>
<path d="M176.1 219.2v.1M176.3 219.1l-.2 .1M178.9 206.7h1.6M178.9 204.6h1.6M178.9 204.6v-.6h1.6v3.3h-1.6v-.5M178.9 204.6v2.2M183 219.1l.2 .1M183.2 219.2v.1M183.9 206.7h1.6M183.9 204.6h1.6M183.9 204.6v-.6h1.6v3.3h-1.6v-.5M183.9 204.6v2.2"/>
<path d="M184.1 216.7v-2.2h-1.1v3.2M185.5 216.6v.3M188.9 216.8l.1 .1M189 204.6v-.6h1.6v3.3h-1.6v-.5M189 204.6v2.2M189 206.7h1.6M189 204.6h1.6M189.1 216.6l-.1 .2M190.5 216.7v-2.2h1v3.2M191.3 219.2v.1M191.6 219.1l-.3 .1M198.2 206.6v1.6"/>
<path d="M198.7 214.4v7M198.7 214.4h13M198.8 214.5l.2 .1M199 214.6v6.6M199 214.6h12.5M200.2 206.6h.5M200.2 206.6v1.6M200.7 206.6h.1M200.8 206.6v1.6h-3.2v-1.6h2.6M202.9 212.5h4.7M203.7 206.6v1.6M204.3 206.6v1.6"/>
<path d="M204.3 206.8l-.6-.2h3.1v1.6h-3.1l.6-.2M206.2 206.6v1.6M206.3 208l.4 .2M206.7 206.6l-.4 .2M207.6 214.4v-3.5h-4.7v3.5M211.5 214.6v6.6M211.7 214.5l-.2 .1M211.7 214.4v7M213.9 210.5l.2 .1M213.9 213.3l.2 .2M213.9 210.5v2.8M213.9 201.4h1.7"/>
<path d="M214 210.3h5.4M214 210.3v3.2M214 213.5h5.4M214.1 210.4l.1 .2M214.1 213.2l-.2 .1M214.1 213.2l.1 .1M214.1 210.6v2.6M214.1 210.4l-.2 .1M214.2 210.6h5.1M214.2 210.6h-.1M214.2 213.3l-.1 .2M214.2 213.3h5.1"/>
<path d="M214.3 209.7h1M214.3 214.1h1M214.8 204.2h.8v2.5h-.8zM215.3 213.5v1.2h-1v-1.2M215.3 210.3v-1.2h-1v1.2M215.6 219.6h2.3M215.6 219.6l-.8 .1v-2.5h3.9v2.5l-.8-.1M215.6 217.2v2.4M215.6 206.6h2.3M215.6 204.3h2.3M216.2 209.7h1M216.2 210.3v-1.2h1v1.2"/>
<path d="M217.9 217.2v2.4M217.9 201.4h1.6M217.9 204.2h.8v2.5h-.8zM218.1 209.7h1.1M218.1 214.1h1.1M218.1 213.5v1.2h1.1v-1.2M218.1 210.3v-1.2h1.1v1.2M219.3 213.3l.1 .2M219.3 210.6h.1M219.4 213.2l-.1 .1M219.4 210.4l-.1 .2M219.4 210.6v2.6"/>
<path d="M219.4 210.4l.2 .1M219.4 210.3l.3 3-.3 .2M219.6 210.5l-.2 2.7M219.6 210.5l-.2 .1M221.1 205.9l1-.2v-1.1h1.3v1.1l1 .2M221.1 211l.3 .1M221.2 205.9l.1 .1M221.2 205.9l-.1 5.1M221.3 210.9h-.1M221.3 210.9l.1 .1M221.3 206v4.9M221.3 211.2h.8v.6"/>
<path d="M221.4 205.7v.2M221.4 205.7l-.2 .2M221.4 205.7h2.7M221.4 211.1h2.7M221.4 205.9h2.7M221.4 205.9l-.1 .1M221.4 211h2.7M221.4 211v.1M221.5 206h2.4v1.1h-2.4zM222.1 205h1.3M222.1 211.8h1.3M224.1 205.9v.1"/>
<path d="M224.1 211v.1M224.1 205.7v.2M224.1 205.7l.2 .2M224.1 210.9h.2M224.1 210.9v.1M224.1 206v4.9M224.3 205.9l-.2 .1M224.3 205.9l.1 5.1M224.3 210.9l-.2 .2M224.4 211l-1 .2v1h-1.3v-.4M238.1 216.4a1.01 1.01 0 0 0-.9-1.6h-4.4a1.03 1.03 0 0 0-.9 1.3 1.03 1.03 0 0 0 1.3 .7M323.8 207.8h-8.9l-1 .6v23.6l.2 .7 .8 .3h11"/>
<path d="M323.8 211.8h2.1M323.8 207.9h2.1v21M325.9 207.8h-1.8l.5 .1M325.9 212.9h1.2M325.9 219.4h1.8v2h-1.8M325.9 211.1h-2.1v.9h2.1M325.9 211.2h-1v.8M325.9 217.9h.1M326 217.9h1.1M327.1 212.9v5M327.1 212.9l.6 .5v3.9l-.6 .6M327.7 214.9h.1"/>
<path d="M327.7 215.9h.1M327.7 216.2h.1M331 214.9h40.6v1h-40.6M331 216.2h.1M331 214.2v.7M331 218.9h.9v3l-.8 .1M331 206.6h2.2v1.6h-1.2l.1-1.6M331 219.9h.1M331 204.6l.1 .5M331 219.3v2.2M331 205.2l1.6-.1v1.5M331 215.9v9"/>
<path d="M331.1 212.4l.2 .4M331.1 212.4l-.1-1.5h.6l.1 1.4 .5 .2M331.1 214.2h2.4v.7M331.1 212.5v1.7M331.1 214.2h-.1M331.1 214l-.1 .2M331.3 218.6v.2M331.3 208.2v.9M331.3 216.7v1.9M331.3 217.9l-.2 .9M331.3 212.8l.9 .2M331.3 212.7v1.5"/>
<path d="M331.3 209.2l-.3 .4M331.5 209.9l-.2 1M331.5 209.5h1.1M331.5 209.1v.1M331.8 204.6h.1M331.9 204.1v1M331.9 204.1h-.9v4.1h.9v-1.6M331.9 201.4v.1M331.9 219.3v.1M331.9 204.2l1.6 .1v5.4M332.2 218.4h.3M332.2 218.4l-.9 .2"/>
<path d="M332.2 212.5l.8 .6 .1 1.1M332.2 208.2v1M332.2 209.6v2.9M332.2 213v1.2M332.2 218.4v2.6M332.2 209.8l-.7 .1M332.2 209.7h-.8l.1 .2M332.2 213l.4 .4v.8M332.5 218.6l-1.2 .1M332.5 218.4v6.5M332.5 218.5l1 .1v6.3v-3.6M332.5 218.7h1"/>
<path d="M332.6 216.7v1.8M332.6 208.2v1.2M332.6 209.5l-.3-.3-1.3-.1 .2 1.8M332.6 209.6v3M332.6 209.5l1.6 .3v4.8M333.1 216.7v1.9M333.5 215.9v.8l-2.5-.1M333.5 214.5l.9 .1v.3M333.5 206.6l-.3 .1M334.4 215.9v5.3l-.9 .2M334.4 216.2h4.9v8.7M340.1 215.9v9"/>
<path d="M73.4 221.4h1.7M73.7 224.9v.5M73.7 225.4l.4 .5 .7-.5M73.7 225.4l.7-.4 .4 .4M74.8 224.9v.5M78.4 221v.8M78.9 224.2h2.8M78.9 221h-1.1v.8h1.1M78.9 224.2l.2 .2M79 224.2h-.1M79 224.2h.1M79.1 224.4h2.3"/>
<path d="M79.1 224.2h2.3M79.1 224.2v.2M81.4 224.2v.2M81.4 224.2h.2M81.4 224.2h.1M81.6 224.2l-.2 .2M81.7 222.9h1.1v.8h-1.1M82.2 222.9v.8M85.5 222.4h1.5M85.5 220.4h1.5M97 221.2h12.5M97.9 223.4h1.5"/>
<path d="M98.5 237.7h2.5M98.5 230.1h2.5M98.5 230.1l-.8 .1v-2.5h4.1v2.5l-.8-.1M98.5 227.7v2.4M99.4 221.4v3.5h-1.5v-3.5M101 227.7v2.4M101 232.3v.6M101 234.9v.6M101 232.3h1.5v3.2h-1.5M102.5 223.4h1.5M102.5 232.9h-1.5v2h1.5M104 221.4v3.5h-1.5v-3.5"/>
<path d="M105.5 230.1h2.4M105.5 230.1l-.8 .1v-2.5h4v2.5l-.8-.1M105.5 227.7v2.4M107.1 223.4h1.5M107.9 227.7v2.4M108.6 221.4v3.5h-1.5v-3.5M109.5 221.2l.2 .2M113.2 229.7h.5M113.2 229.7v-1.6h3.1v1.6M113.7 228.2v1.5h2v-1.5M115.7 229.7h.6M117.3 231.6v1.6"/>
<path d="M117.3 224.6v1.6M118.5 236.4h71.4v68h-21.2v-4.4h-29v4.4h-21.2zM119.2 231.6h.6M119.2 231.6v1.6M119.2 224.6h.6M119.2 224.6v1.6M119.8 231.6h.1M119.8 224.6h.1M119.8 231.6v1.6h-3.1v-1.6h2.5M119.8 224.6v1.6h-3.1v-1.6h2.5M123.2 225v.8M123.2 232v.8"/>
<path d="M123.8 228.2l.1 .2M123.8 222.6v5.6M123.8 229.6l.1 5.5M123.8 229.6l.1 .1M123.8 222.6l.1 .1M123.9 222.4h2.4l.2 .7h1.1v.8h-1.1v3h1.1v.8h-1.1l-.2 .7h-2.4l-.2-2.6h-1.1v-.8h1.1zM123.9 228.1l-.1 .1M123.9 235.1l.1 .1M123.9 228.1l.1 .1M123.9 222.7v5.4M123.9 229.7v5.4M123.9 235.4l-.2-2.6h-1.1v-.8h1.1l.2-2.6h2.4l.2 .7h1.1v.8h-1.1v3h1.1v.8h-1.1l-.2 .7h-2.4"/>
<path d="M123.9 235.4h2.4M123.9 229.5l-.1 .1M123.9 222.5l-.1 .1M123.9 222.5h2.4M123.9 229.5h2.4M123.9 229.5l.1 .1M123.9 222.5l.1 .1M124 235.2l-.1 .2M124 228.2l-.1 .2M124 235.2h2.2M124 228.2h2.2M124 229.6h2.2"/>
<path d="M124 222.6h2.2M124 229.6l-.1 .1M124 222.6l-.1 .1M126.2 235.2l.1 .2M126.2 228.2l-2.3 .2M126.2 229.6l.1 .1M126.2 222.6l.1 .1M126.3 229.5l.2 .1M126.3 222.5l.2 .1M126.3 235.1l-.1 .1M126.3 222.7v5.4M126.3 229.7v5.4"/>
<path d="M126.3 228.1l-.1 .1M126.3 235.1l.2 .1M126.3 229.5l-.1 .1M126.3 222.5l-.1 .1M126.5 235.2l-.2 .2M126.5 222.6l-.2 5.5M126.5 229.6v5.6M126.5 229.6l-.2 .1M126.5 222.6l-.2 .1M127 223.1v.8M127 226.9v.8M127 230.1v.8"/>
<path d="M127 233.9v.8M130 227.9h1.5M130 229.9h1.5M131.5 229.9v-2.6h-1.5v3.2h1.5M131.5 229.9v.5M131.5 230.4v.1M133 227.3v.6M133 229.9v.6M133 227.3h1.5v.6M134.5 227.9h-1.5v2h1.5M134.5 227.9v2M134.5 229.9v.6h-1.5"/>
<path d="M135.9 227.9h1.6M135.9 229.9h1.6M137.5 229.9v-2.6h-1.6v3.2h1.6M137.5 229.9v.5M137.5 230.4v.1M147.9 235.6h2.5M147.9 233.2v2.4M150.4 235.6l.8 .1v-2.5h-4.1v2.5l.8-.1M150.4 233.2v2.4M167.8 224v3.3h1v-2.3M167.9 222.5l-.2 .2M170.3 224.9v.3"/>
<path d="M170.4 230.6h.1M170.5 230.6h.5M171 229v1.6M171 230.6h2.6v-1.6h-3.2v1.6M173 229v1.6M173.6 225l.2 .2M176.1 222.5l.2 .2M176.2 224v3.3h-1v-2.3M183 224v3.3h1.1v-2.3M183.2 222.5l-.2 .2M185.5 224.9v.3M186.3 229v1.6"/>
<path d="M188.2 229h.6M188.2 229v1.6M188.8 229h.1M188.8 229v1.6h-3.1v-1.6h2.5M188.9 225l.2 .2M191.3 222.5l.3 .2M191.5 224v3.3h-1v-2.3M198.7 221.4h13M199 221.2h12.5M199 221.2l-.2 .2M199.9 223.4h1.5M200.4 230.1l-.8 .1v-2.5h3.9v2.5l-.7-.1"/>
<path d="M200.4 227.7v2.4M200.4 230.1h2.4M201.4 221.4v3.5h-1.5v-3.5M202.8 227.7v2.4M204.5 223.4h1.5M206 221.4v3.5h-1.5v-3.5M207.3 230.1h2.4M207.3 230.1l-.8 .1v-2.5h4v2.5l-.8-.1M207.3 227.7v2.4M209.1 223.4h1.5M209.7 227.7v2.4M210.6 221.4v3.5h-1.5v-3.5"/>
<path d="M211.5 221.2l.2 .2M213.9 239l.3 .4M213.9 238.8h1.7v3.2h-1.7zM213.9 239.4h1.7M215.1 221.1h3.2v1.6h-3.2zM215.2 234.9l.1 .2M215.2 229.9l.1 .1M215.2 229.9v5M215.3 229.7l.1 .2M215.3 229.7l-.1 .2M215.3 235.1h2.8M215.3 234.9l.1 .1"/>
<path d="M215.3 230v4.9M215.3 235.2h.8v.6M215.3 229.7l2.8 .2M215.3 234.9h-.1M215.4 235l-.1 .1M215.4 235h2.7M215.4 229.9h2.7M215.4 229.9l-.1 .1M215.5 230h2.5v1.1h-2.5zM215.6 239l-.3 .4M215.7 221.1v1.6M216.1 229h1.3"/>
<path d="M216.1 235.8h1.3M217 238.8h1.6v3.2h-1.6zM217 239.4h1.6M217.8 221.1v1.6M218.1 235v.1M218.1 229.9v.1M218.1 235.2l.2-5.3-.9-.2v-1.1h-1.3v1.1l-1 .2 .2 5.3M218.1 234.9h.2M218.1 230l.2 4.9M218.1 235.2h-.7v1h-1.3v-.4M218.1 234.9v.1M218.1 230v4.9"/>
<path d="M218.3 234.9l-.2 .2M220 238.8h1.5v3.2h-1.5zM220 239.4h1.5M220.2 229.9l.1 .1M220.2 229.9v5M220.2 234.9l.1 .2M220.3 229.7l.1 .2M220.3 229.7l-.1 .2M220.3 229.7l2.7 .2M220.3 234.9h-.1M220.3 234.9l.1 .1M220.3 230v4.9"/>
<path d="M220.3 235.2h.8v.6M220.3 235.1h2.8M220.4 229.9h2.6M220.4 229.9l-.1 .1M220.4 235h2.6M220.4 235l-.1 .1M220.5 230h2.5v1.1h-2.5zM221.1 229h1.3M221.1 235.8h1.3M222.9 239.4h1.6M222.9 239l.2 .4M222.9 238.8h1.6v3.2h-1.6z"/>
<path d="M223 229.9l.2 .1M223 235l.1 .1M223.1 235.2h-.7v1h-1.3v-.4M223.1 235.2l.2-5.3-.9-.2v-1.1h-1.3v1.1l-1 .2 .2 5.3M223.2 230l.1 4.9M223.2 234.9h.1M223.2 230v4.9M223.2 234.9l-.2 .1M223.3 234.9l-.2 .2M224.5 239l-.1 .4M228.9 222.8l.3 .1-.1 5.2-.3-.2zM229.2 223.2h7.6"/>
<path d="M229.2 227.6h7.6M230.2 223.4a1.06 1.06 0 0 0-.6-1.5 1.06 1.06 0 0 0-1.3 .9v5.2a1.07 1.07 0 0 0 1.3 1 1.07 1.07 0 0 0 .6-1.6M232.2 227.4v4.9h7.1v-1.8h-1.3v-1.9M236.9 222.3l1.6 .1-.3 6.2-1.4-.2zM238 222.2v-.6h1.3v-1.8h-1.3v-4.4h-4.8v8M238.5 222.7l14.1 .3a2.43 2.43 0 0 1 1.9 2.4M242.8 227.9a.99 .99 0 0 1-1 .7 .99 .99 0 0 1-.9-.7M242.8 222.9a.99 .99 0 0 0-1-.7 .99 .99 0 0 0-.9 .7M254.2 226.4v20.1M254.5 225.5a2.46 2.46 0 0 1-2.5 2.4l-13.5 .2M324.6 233h-.5h1.8M324.9 228.9v.8h1"/>
<path d="M325.9 222.9l1.2 .1M325.9 228.9h-2.1v.8h2.1M325.9 229h-2.1M325.9 228.9v.8M325.9 227.9h1.2M325.9 229.7v3.3M327.1 223l.6 .5v3.9l-.6 .5M327.1 223v4.9M327.7 224.9h.1M327.7 225.9h.1M331 239.8h.1M331 224.9h40.6v1h-40.6"/>
<path d="M331 230.1l2.5 .1M331 237.7h2.5v2.4l-2.4 .1zM331 220.3l.1 .1M331 221.9l.1 .1M331 225.9v.3h.9v-.3M331 221h.1M331 222.9h.3M331 226.9h.3M331 223.7h.3M331.1 232.3h1.5v.6h-1.5M331.1 234.9h1.5M331.1 222l-.1 .5"/>
<path d="M331.2 235.7l-.2 .5 1.4-.5M331.3 226.4v4.5M331.3 222v2.3l1.2 .1M331.3 226.2v1.5M331.3 230.2v1.4M331.6 224.6h.3v.3M331.6 224.3v.6M331.9 232.3v-.7h-.9l.1 4.1M332 221.8h.5M332 232h.5M332 221h.5M332.2 225.9v1.8"/>
<path d="M332.2 230.2v1.8M332.2 221.8v3.1M332.5 225.9v1.8M332.5 230.2v2.1M332.6 234.9v.6h-1.5M332.6 232.9v2M333.5 227.7v7.9l-2.4 .1M333.5 227.7l-2.5 .1M333.5 235.1l-.9 .1M333.5 224.2h-2.2M333.5 224.2l-1 .2M333.5 222.5h.1"/>
<path d="M333.5 225.9v1.8M333.5 230.2v5l-.9 .1M333.5 233.2v.1M333.5 230.1v.1M333.5 239.8h8M334.1 221.2v1.6l-.6 .1M339.3 227.1h.8M340.1 225.9v6.4h-.8v-6.4M341.2 224.9a3.2 3.2 0 0 1 3.1-2.7 3.2 3.2 0 0 1 3.2 2.7M341.2 225.9a3.2 3.2 0 0 0 3.1 2.7 3.2 3.2 0 0 0 3.2-2.7M345.1 237.9h-3.6v5.1h3.6M345.1 236.4h2.3v68h-2.3z"/>
<path d="M346.1 225.9a1.82 1.82 0 0 1-1.8 1.3 1.82 1.82 0 0 1-1.7-1.3M346.1 224.9a1.8 1.8 0 0 0-1.8-1.3 1.8 1.8 0 0 0-1.7 1.3M347 225.9a2.72 2.72 0 0 1-2.7 2.2 2.72 2.72 0 0 1-2.6-2.2M347 224.9a2.72 2.72 0 0 0-2.7-2.2 2.72 2.72 0 0 0-2.6 2.2M347.4 238.7l2.1 1.1M349.5 239.8v1.2M349.5 239.8h1.4v1.2h-1.4M38.1 257.7h17v25.4h-17zM55.1 259.7h8.4v1.2h-8.4M59 259.7a.98 .98 0 0 0-1.6 0M62.4 259.7a1.01 1.01 0 0 1 1.5-.2 1.01 1.01 0 0 1 0 1.5 1.01 1.01 0 0 1-1.5-.1M74.5 257.3v.6"/>
<path d="M74.5 259.9v.6M74.5 257.3h1.6v.6h-1.6v2h1.6v.6h-1.6M75.6 253.6h2.2M75.6 253.6h-.5v1.6h3.3v-1.6h-.6M75.7 253.6v1.6M76 257.9v2M77.5 257.3h1.5v3.2h-1.5zM77.5 257.9h1.5M77.5 259.9h1.5M77.8 253.6v1.6M80.4 257.9h1.6v2h-1.6M82 257.3h-1.6v3.2h1.6"/>
<path d="M82 257.3v.6M82 259.9v.6M83.5 257.9v2M85 257.9h-1.6v-.6h1.6v3.2h-1.6v-.6h1.6M86.5 257.9v2M88 257.3h-1.6v.6h1.6v2h-1.6v.6h1.6M88 259.9v.6M88 257.3v.6M89.4 257.3h1.7v3.2h-1.7zM89.4 257.9h1.7M89.4 259.9h1.7M90.2 255.2v-1.6h3.1v1.6h-2.5"/>
<path d="M90.2 255.2h.1M90.2 255.2h.6M90.8 253.6v1.6M92.4 257.3h1.7v.6h-1.7zM92.4 259.9h1.7v.6h-1.7zM92.5 257.9v2M92.7 253.6v1.6M94 257.9v2M97.7 240.1v-2.4h.8v2.4M97.7 240.1v.1M98.5 240.1v.1M101 240.1v-2.4h.8v2.4"/>
<path d="M101 240.1v.1M101.8 240.1v.1M101.8 240.2h-4.1M118.5 254.5a1 1 0 0 0-1.3 .9 1 1 0 0 0 1.3 1M119.2 249.2h70v46h-70zM123.7 253.2h61v31h-61zM125.9 240.5a3.2 3.2 0 0 1-1.7 3.1 3.2 3.2 0 0 1-3.5-.4M182.5 240.5a3.2 3.2 0 0 0 1.8 3.1 3.2 3.2 0 0 0 3.5-.4M189.9 247.5a1 1 0 0 1 1.4 .9 1 1 0 0 1-1.4 1M213.1 249.2h.6M213.1 249.2v-1.6h.6v1.6h2v-1.6h.7v1.6M213.7 247.7h2"/>
<path d="M213.9 241.4h1.7M213.9 241.3h1.7M214.2 241.5l-.3 .4M215.3 241.5l.3 .4M215.7 249.2h.7M216.7 254.4h1.2M217 241.4h1.6M217.9 253.9v3.1M217.9 256.4l-1.2 .1M218 256.2l-1.3 .2M218 253.9l.1 3M218.1 256.5l-.1 .1"/>
<path d="M218.1 256.1l.6-2.2v3.1M218.1 253.9v3.1l.6-2.3M218.4 245.9h1.6v2h-1.6M218.7 254.3l-.6 2.3M218.8 254l.1 2.9M218.9 256.5l-.1 .1M218.9 254.3h-.1M218.9 253.9v3.1l.6-2.3M218.9 256.1l.6-2.2v3.1M219.5 254.3l-.6 2.3M219.7 253.9l-.1 3.1zM219.7 253.9l-.1 .1"/>
<path d="M219.7 256.5l-.1 .1M219.7 254.3h-.1M219.7 256.1l.6-2.2v3.1M219.7 253.9v3.1l.6-2.3M220 241.4h1.5M220 245.3h-1.6v3.2h1.6M220 245.3v.6M220 247.9v.6M220.3 254.3l-.6 2.3M220.4 254l.1 3M220.4 253.9v3.1M220.5 254.3h-.1"/>
<path d="M220.6 256.5h1.2M220.6 256.4h1.2M220.9 254.5l-.4 .1M220.9 254.4l.9 .1M220.9 254.4l-.4 .1M222.2 249.2h.6M222.2 249.2v-1.6h.6v1.6h1.9v-1.6h.6v1.6M222.8 247.7h1.9M222.9 241.4h1.6M222.9 241.3h1.6M223.1 241.5l-.2 .4M224.4 241.5l.1 .4"/>
<path d="M224.7 249.2h.6M226.4 253h1.2l.2-.5h2.9l.1 .5h1.2v1h-1.2v.9h1.2v1h-1.2v.9h1.2v1h-1.2l-.1 .5h-2.9l-.2-.5h-1.2v-1h1.2v-.9h-1.2v-1h1.2v-.9h-1.2zM226.6 259.6h.6M226.6 259.7v1.5h.6v-1.5h2v1.5h.6v-1.5M227 253v1M227 254.9v1M227 256.8v1M227.7 252.7l.2 .1M227.7 252.7v5.4M227.7 258.1l.2 .2M227.7 252.7l.3 .1M227.9 258l-.2 .1"/>
<path d="M227.9 258l.1 .1M227.9 252.8v5.2M227.9 258.3h2.7M228 258.1l-.1 .2M228 258.1h2.5M228 252.8h-.1M228 252.8h2.5M228.1 245.2v2.4M229.2 259.6h.6M230.4 244.4h-2.4v.8h2.4M230.4 244.4h.1M230.4 245.2h.1"/>
<path d="M230.4 247.6h-2.4v.8h2.4M230.4 247.6h.1M230.4 248.4h.1M230.5 244.4v4M230.5 258.1l.1 .2M230.5 252.8h.1M230.6 258l.2 .1M230.6 258l-.1 .1M230.6 252.8v5.2M230.6 252.6l.2 .1M230.6 252.6l-.1 .2M230.8 252.7l-.2 .1"/>
<path d="M230.8 258.1l-.2 .2M230.8 252.7v5.4M231.4 253v1M231.4 254.9v1M231.4 256.8v1M232.7 251.2v-1.6h3.1v1.6h-2.6M232.7 251.2h.1M232.7 251.2h.5M233.2 249.6v1.6M233.2 259.6v1.6M235.2 249.6v1.6M235.2 259.6v1.6"/>
<path d="M240.7 249h.4M240.7 250.6h.4M241.1 250.2h.7M241.1 246.8v14.5M241.1 251.9h.9M241.1 259.7h-.4v1h.4M241.1 257.7h-.4v.4h.4M241.1 255.7h-.4v.5h.4M241.1 254.7h-.4v.4h.4M241.1 252.7h-.4v.5h.4M241.1 250.1h-.4v1h.4M241.1 248.5h-.4v1h.4"/>
<path d="M241.1 251.7h-.4v.4h.4M241.1 253.7h-.4v.5h.4M241.1 256.7h-.4v.5h.4M241.1 258.7h-.4v.5h.4M241.1 246.8h.7M241.1 258.9h.9M241.3 246.2l-.5 .5 .3 .6M241.7 248.2h.2l-.2 1h.5M241.7 246.8v3.4M241.7 251.9v7M241.7 247.4h.2M241.7 247.1h.1"/>
<path d="M241.8 246.8v.3M241.8 247.1h.4l-.4 .4v1.3M241.8 249.2v1M241.8 251.9v3.2M241.8 255.8v3.1M241.9 255.1v.7M241.9 258.4h.3M241.9 258.1h.3M241.9 257.7h.3M241.9 257.6h.3M241.9 256.3h.3M241.9 256.2h.3"/>
<path d="M241.9 254.7h.3M241.9 254.5h.3M241.9 253.3h.3M241.9 253.2h.3M241.9 252.7h.3M241.9 252.5h.3M241.9 250.1h.2M241.9 249.2v1M241.9 251.9v7M241.9 250h.2M242 250.2h-.2M242 246.4h2.1l.6-.6-3.1 .1-.5 .9"/>
<path d="M242 246.4l-.3 .3M242.1 246.5h14v17.9h-14.3M242.1 246.5l-.3 .3M242.2 252.2v6.4M242.2 246.5v3.4M245.6 250.9v1M245.6 258.9v1M245.6 250.1v2.6M245.6 258.1v2.6M246.6 250.9v1M246.6 258.9v1M246.6 250.1v2.6"/>
<path d="M246.6 258.1v2.6M252.2 246.5l-.5-.3h-1.6l-.5 .3M316.5 257.4v9.7h1.2M316.5 257.4v-3h10.9v5.3M316.5 257.4h10.9M316.5 255.6v.6M327.8 259.7l-2.6 .3v.6l2.6 .3M331 256.2h.3M331 246.7l.1 .1M331 258.1h.1M331 259.7h.1M331 259.2h.1"/>
<path d="M331 255.1h.1M331 247.1h.1M331 257.2h.1M331 257.7h10.2v25.4h-10.2M331 254.7h.1M331 253.2h.1M331 252.7h.1M331 250.1h.1M331 258.7h.1M331 249h.1M331 248.5h.1M331 250.6h.1"/>
<path d="M331 254.2h.1M331 253.7h.1M331 246.5h.1M331 252.1h.1M331 251.1h.1M331 249.5h.1M331 256.7h.3M331 255.7h.1M331 241h10.5M331 246.9h.9v4.3h-.9v-1.7M331 247.3v2.2M331 253.6h.9v1.6h-.9"/>
<path d="M331 249.9h.9M331 245.2h2.5v-.8h-2.5v4.8M331.1 257.3h1.5v.4M331.1 245.3h1.5v.6h-1.5M331.1 252.3h1.5v.6h-1.5M331.1 241l-.1 2.2h1.6v-1.5l-1.5-.1M331.1 247.6l-.1 .1M331.1 245.2v.1M331.1 251.7v.1M331.1 255.9v.3M331.1 256.7v.1M331.1 251.8h.7l.1 .5"/>
<path d="M331.1 251.8l-.1 4.1h1.8M331.2 256.4h.7M331.2 256.5h.7M331.3 255.9v.9M331.3 255.5v.4M331.3 256.8v.5M331.4 251.2l-.1 .5h-.3M331.9 249.4v.1M331.9 249.2h1M331.9 254.9h.9M331.9 247.6h1.6v.8h-.9M331.9 255.5l.2 1.5"/>
<path d="M332 241.4l.1 .1M332 241.4v.2M332 255.5l.1 1.4M332.1 256.9l1.3 .1M332.1 249.2v3.1M332.4 259.1l.6 .6M332.4 259.1h2.4M332.4 259.1v2.4M332.5 249.2v3.1M332.5 255.9v.9M332.6 253h.2M332.6 245.9v3.3"/>
<path d="M332.6 253.6v1.9h-1.5M332.6 252.9v2M332.6 253.8l.9 .2-.1 3M332.6 252.7l1.5 .1v4.9M332.6 252.5h.2M332.6 254h.2M332.6 253.9h.8M332.6 248.8h.3M332.8 252.5v5.2M332.8 256.8h-1.8v34.3h2.5v-2.4l-2.5 .1M332.8 252.6l1.3 .2M332.9 248.4v2"/>
<path d="M333 259.7h1.2M333 259.7v1.2M333 250.5v.6M333 252.4l.2 .2M333 251.1v1.3M333.2 241v.3l-1.2 .1M333.4 259.7v1.2M333.5 245.2v2.4M333.5 254l-.1 2.9M333.5 245.8h.8v.4M333.8 259.7v1.2M334.2 259.7v1.2"/>
<path d="M334.3 246.5h.7M334.6 246.7a2.41 2.41 0 0 1 2.2 2M334.8 259.1l-.6 .6M334.8 259.1v2.4M335 246.5l-.2 .2M335 246.5a2.62 2.62 0 0 1 2.4 2.5v1.2M336.1 252.1v5.6M336.2 249.6v.3M336.4 250.2h.1M336.5 250.2h.9M336.6 249.2h.2M336.6 249.2l-.2 .1"/>
<path d="M336.8 252.6h.1M336.8 251.9v5.8zM336.8 248.7v.1M336.8 249l-.2 .2M336.8 248.8v1.4h.6M337.4 251.9v5.8M337.4 251.9h-1.1M337.4 250.2v1.7M337.5 259.1l.6 .6M337.5 259.1h2.3M337.5 259.1v2.4M338.1 259.7v1.2"/>
<path d="M338.4 259.8v1.1M338.4 259.7v.1M338.9 259.7v1.2M339.3 259.7h-1.2M339.3 259.7v1.2M339.8 259.1l-.5 .6M339.8 259.1v2.4M347.4 249.2h3.5v46h-3.5M349.5 241l-2.1 1.2M55.1 264.8h8.4v1.1h-8.4M55.1 274.9h8.4v1.2h-8.4M55.1 280h8.4v1.2h-8.4"/>
<path d="M55.1 269.8h8.4v1.2h-8.4M59 280a.98 .98 0 0 0-1.6 0M59 274.9a.98 .98 0 0 0-1.6 0M59 269.8a.98 .98 0 0 0-1.6 0M59 264.8a.98 .98 0 0 0-1.6 0M59 276.1a1.04 1.04 0 0 1-1.6 0M59 271a1.04 1.04 0 0 1-1.6 0M59 265.9a1.04 1.04 0 0 1-1.6 0M59 260.9a.98 .98 0 0 1-1.6 0M62.4 280a1.01 1.01 0 0 1 1.5-.2 1.01 1.01 0 0 1 0 1.5 1.01 1.01 0 0 1-1.5-.1M62.4 274.9a1.01 1.01 0 0 1 1.5-.1 1.01 1.01 0 0 1 0 1.5 1.01 1.01 0 0 1-1.5-.2M62.4 269.8a1.01 1.01 0 0 1 1.5-.1 1.01 1.01 0 0 1 0 1.5 1.01 1.01 0 0 1-1.5-.2"/>
<path d="M62.4 264.8a1.01 1.01 0 0 1 1.5-.2 1.01 1.01 0 0 1 0 1.5 1.01 1.01 0 0 1-1.5-.2M67.4 269l.2 2.7M67.4 271.8l.2 .1M67.4 269v2.8M67.6 268.9l5.2 .2M67.6 268.8l-.3 3 .6 .2v1.2h.9v-1.2h1v1.2h.9v-1.2h1v1.2h.9v-1.2l.5-.2M67.6 271.9h5.3M67.6 268.8h5.4M67.6 268.9l-.2 .1M67.6 271.7l-.2 .1M67.6 271.7v.1M67.6 271.8h5.2"/>
<path d="M67.6 271.8v.1M67.9 272.6h.9M67.9 268.2h.9M68.8 268.8v-1.2h-.9v1.2M69.8 272.6h.9M69.8 268.8v-1.2h.9v1.2M69.8 268.2h.9M71.7 268.8v-1.2h.9v1.2M71.7 268.2h.9M71.7 272.6h.9M72.8 269.1h.1M72.8 271.8l.1 .1"/>
<path d="M72.9 271.7l.2 .1M72.9 269.1v2.6M72.9 271.7l-.1 .1M72.9 268.9l-.1 .2M73 268.8l.1 .2M73.1 271.8l-.2 .1M73.1 269l-.2 .1M73.1 269v2.8M75 271.6h2.4M75 269.2h2.4M77.4 269.2l.1-.8h-2.5v4h2.5l-.1-.8M77.4 269.2v2.4"/>
<path d="M79.3 274.4l.4 .3M79.3 266.5h.2M79.3 266.5v7.9M79.5 274.3l-.2 .1M79.5 274.3l.3 .3M79.5 266.5v7.8M79.7 266.1l.1 .2M79.7 274.7h9.1M79.7 266.1l-.4 .4M79.7 266.1h9.1M79.8 266.3h8.9M79.8 266.3l-.3 .2"/>
<path d="M79.8 274.6h8.9M79.8 274.6l-.1 .1M80.1 265.1h.5M80.1 275.7h.5M80.1 264h.5v2h.8v-2h.5v2h.8v-2h.5v2h.8v-2h.5v2h.8v-2h.5v2h.8v-2h.5v2h.8v-2h.5v2l.8 .4v8l-.8 .4v2h-.5v-2h-.8v2h-.5v-2h-.8v2h-.5v-2h-.8v2h-.5v-2h-.8v2h-.5v-2h-.8v2h-.5v-2h-.8v2h-.5v-2l-.9-.4v-8l.9-.4zM81.4 265.1h.5M81.4 275.7h.5M82.7 275.7h.5M82.7 265.1h.5M84 275.7h.5M84 265.1h.5M85.3 275.7h.5"/>
<path d="M85.3 265.1h.5M86.6 265.1h.5M86.6 275.7h.5M87.9 275.7h.5M87.9 265.1h.5M88.7 266.3l.3 .2M88.7 274.6l.1 .1M88.8 266.1l-.1 .2M88.8 266.1l.3 .4M89 274.3l.1 .1M89 274.3l-.3 .3M89 266.5v7.8"/>
<path d="M89.1 266.5h-.1M89.1 266.5v7.9M89.1 274.4l-.3 .3M90.8 272.4h.1M90.8 271.6h.1M90.8 268.4v4M90.8 269.2h.1M90.8 268.4h.1M90.9 271.6h2.4v.8h-2.4M90.9 268.4h2.4v.8h-2.4M93.2 269.2v2.4M94.9 267.9l.1 .1"/>
<path d="M94.9 267.9v5.1M94.9 273l.3 .3M95 272.9l-.1 .1M95 272.9l.3 .3M95 268v4.9M95.2 267.4l-.5 .4v5.2l.8 .4v1.9h.5v-1.9h.5v1.9h.5v-1.9h.5v1.9h.5v-1.9h.5v1.9h.5v-1.9h.5v1.9h.5v-1.9l.7-.4M95.2 267.4h5.2l.3 .4v5.2M95.2 267.5l.1 .2M95.2 267.5l-.3 .4M95.2 273.3h5.1M95.3 267.7h4.9M95.3 267.7l-.3 .3"/>
<path d="M95.3 273.2l-.1 .1M95.3 273.2h4.9M95.5 274.3h.5M95.5 266.5h.5M96 267.4v-1.9h-.5v1.9M96.5 274.3h.5M96.5 266.5h.5M97 267.4v-1.9h-.5v1.9M97.5 274.3h.5M97.5 267.4v-1.9h.5v1.9M97.5 266.5h.5M98.5 267.4v-1.9h.5v1.9"/>
<path d="M98.5 274.3h.5M98.5 266.5h.5M99.5 267.4v-1.9h.5v1.9M99.5 266.5h.5M99.5 274.3h.5M100.2 267.7l.3 .3M100.2 273.2l.1 .1M100.5 272.9l-.3 .3M100.5 268v4.9M100.5 272.9l.2 .1M100.7 273l-.4 .3M102.4 268.8h1.6v.6h-1.6z"/>
<path d="M102.4 271.4h1.6v.6h-1.6zM102.5 269.4v2M104 269.4v2M118.5 278.5a1 1 0 0 0-1.3 .9 1 1 0 0 0 1.3 1M200.4 273.7h1.7v2.1h-1.7zM200.4 274.8h1.7M200.4 265h1.7v2.1h-1.7zM200.4 266h1.7M203.4 265h1.7v2.1h-1.7zM203.4 266h1.7M203.4 273.7h1.7v2.1h-1.7zM203.4 274.8h1.7"/>
<path d="M206.3 274.8h1.8M206.3 273.7h1.8v2.1h-1.8zM206.3 265h1.8v2.1h-1.8zM206.3 266h1.8M217.2 278.2h.9v2.5h-.9zM218.1 278.3h2.3M220.4 278.2h.8v2.5h-.8zM226.4 277.7h.2M226.6 277.3l-.2 4.7h.5M226.6 276.9h2.5v.6M227.2 261.2h2M228.8 275.5l-2.2 .2 .1 6.1"/>
<path d="M228.8 275.6l.1 .1M228.9 275.8v1.1M229.1 277.3h.3M229.4 276.1h.5M229.4 276.1v1.2M229.4 276.1l.4 .4M229.4 277.3l.4 .4M229.8 277.7l-.7-.1 .3 .3 .5-.2M229.8 276.5v1.2M229.8 276.5h.1M229.9 277.6v.1M231 275.7h1.8"/>
<path d="M232.7 261.2h.1M232.7 261.2h.5M233.2 261.2h2.6v-1.6h-3.1v1.6M240.7 261.8h.4M240.7 260.2h.4M241 276l1.9 .1M241 275.7v.5M241 276.2v.1M241 276.3l1.6 .1M241 275.7h-11.1v1.8M241.1 261.3v2.8h.6M241.1 263.6l-.3 .6 .5 .4"/>
<path d="M241.1 264.2l.7 .8h2.9l-.6-.6M241.1 261.3h-.4v1h.4M241.7 263.4h.2M241.7 264.1h.1M241.7 264.1l.1 .3M241.8 264.1v.3M241.8 263.8v.3M241.8 262v1.3l.4 .5h-.5M241.8 260.6v1M241.8 260.6h.2M241.8 260.6h-.7h.6v3.5M241.9 260.9h.2"/>
<path d="M241.9 260.7h.2M241.9 260.6v1M242.2 260.9v3.4M242.2 261.6h-.5l.2 1h-.2M242.7 276.4h.1M242.9 275.7h12.7v6.1M242.9 275.7v.6v-.6h-1.9v.6M245 274.4v1.3M245.1 274.3h.1M245.3 274.2h.8M246.3 274.3l.1 .1M247.2 274.4l-.7 .1"/>
<path d="M247.4 274.2h1M248.6 274.4v1.3M249.6 264.4l.5 .3h1.6l.5-.3M252.6 275.7h1.7M254.2 264.4v11.3M255.5 280l-.1 .2M255.6 278.2v1.7M316.5 263.4h10.9M316.5 265.2h2.8v1.2h8.1M316.5 277.4h10.9M317.6 267.1v8.5M317.7 265.2v10.4"/>
<path d="M322.3 269.2h2.1v-.8h-3v4h3v-.8h-2.1M322.3 268.4v4M326.8 266.4v.4h1M327.4 274.4h-8.1v1.2h-2.8v10.8h10.9v-5.2M327.4 260.9v3.9M327.4 265.9v3.9M327.4 271v3.9M327.4 276.1v3.9M327.8 264.8l-2.6 .2v.6l2.6 .3M327.8 274.9l-2.6 .3v.6l2.6 .3M327.8 280l-2.6 .3v.6l2.6 .3M327.8 269.8l-2.6 .3v.6l2.6 .3"/>
<path d="M327.8 274h-1v.4M331 264.8h.1M331 261.8h.1M331 264.4h.1M331 262.3h.1M331 274.9h.1M331 269.8h.1M331 280h.1M331 276.1h.1M331 260.9h.1M331 261.3h.1M331 263.8h.1"/>
<path d="M331 271h.1M331 265.9h.1M331 264.1v.1M332.4 269.2l.6 .6M332.4 274.3l.6 .6M332.4 279.4l.6 .6M332.4 264.2l.6 .6M332.4 269.2h2.4M332.4 264.2h2.4M332.4 266.5h2.4M332.4 271.6h2.4M332.4 264.2v2.3"/>
<path d="M332.4 269.2v2.4M332.4 261.5h2.4M332.4 274.3h2.4M332.4 279.4h2.4M332.4 274.3v2.4M332.4 279.4v2.4M332.4 276.7h2.4M333 271l-.6 .6M333 276.1l-.6 .6M333 264.8h1.2M333 260.9h1.2M333 265.9h1.2"/>
<path d="M333 264.8v1.1M333 269.8v1.2M333 274.9v1.2M333 280v1.2M333 265.9l-.6 .6M333 260.9l-.6 .6M333.4 280v1.2M333.4 274.9v1.2M333.4 275h.4M333.4 269.8v1.2M333.4 270.9h.4M333.4 269.9h.4"/>
<path d="M333.4 264.8v1.1M333.4 260.8h.4M333.4 265.9h.4M333.4 264.8h.4M333.8 274.9v1.2M333.8 280v1.2M333.8 269.8v1.2M333.8 264.8v1.1M334.2 271l.6 .6M334.2 276.1l.6 .6M334.2 265.9l.6 .6M334.2 260.9l.6 .6"/>
<path d="M334.2 274.9h-1.2M334.2 269.8h-1.2M334.2 280h-1.2M334.2 264.8v1.1M334.2 269.8v1.2M334.2 274.9v1.2M334.2 280v1.2M334.2 276.1h-1.2M334.2 271h-1.2M334.8 269.2l-.6 .6M334.8 274.3l-.6 .6M334.8 279.4l-.6 .6"/>
<path d="M334.8 264.2l-.6 .6M334.8 264.2v2.3M334.8 269.2v2.4M334.8 274.3v2.4M334.8 279.4v2.4M337.5 264.2l.6 .6M337.5 274.3l.6 .6M337.5 269.2l.6 .6M337.5 279.4l.6 .6M337.5 269.2h2.3M337.5 264.2h2.3M337.5 279.4h2.3"/>
<path d="M337.5 266.5h2.3M337.5 271.6h2.3M337.5 264.2v2.3M337.5 269.2v2.4M337.5 279.4v2.4M337.5 261.5h2.3M337.5 274.3h2.3M337.5 274.3v2.4M337.5 276.7h2.3M338.1 260.9l-.6 .6M338.1 265.9l-.6 .6M338.1 271l-.6 .6"/>
<path d="M338.1 276.1l-.6 .6M338.1 264.8v1.1M338.1 269.8v1.2M338.1 274.9v1.2M338.1 280v1.2M338.4 275v1.1M338.4 274.9v.1M338.4 275h.5M338.4 269.9v1.1M338.4 269.8v.1M338.4 280v.1M338.4 270.9h.5"/>
<path d="M338.4 269.9h.5M338.4 264.8v1.1M338.4 260.8h.5M338.4 264.8h.1M338.4 265.9h.5M338.4 264.8h.5M338.9 274.9v1.2M338.9 269.8v1.2M338.9 280v1.2M338.9 264.8v1.1M339.3 265.9l.5 .6M339.3 260.9l.5 .6"/>
<path d="M339.3 276.1l.5 .6M339.3 271l.5 .6M339.3 264.8h-1.2M339.3 274.9h-1.2M339.3 269.8h-1.2M339.3 280h-1.2M339.3 264.8v1.1M339.3 269.8v1.2M339.3 274.9v1.2M339.3 280v1.2M339.3 276.1h-1.2M339.3 260.9h-1.2"/>
<path d="M339.3 271h-1.2M339.3 265.9h-1.2M339.8 264.2l-.5 .6M339.8 269.2l-.5 .6M339.8 279.4l-.5 .6M339.8 274.3l-.5 .6M339.8 264.2v2.3M339.8 269.2v2.4M339.8 279.4v2.4M339.8 274.3v2.4M54.3 283.1v61.3a8 8 0 0 0 8 8h41.2M59 281.2a1.04 1.04 0 0 1-1.6 0"/>
<path d="M74.5 280.3v.6M74.5 282.9v.6M74.5 280.3h1.6v.6h-1.6v2h1.6v.6h-1.6M75.6 285.6h2.2M75.6 285.6h-.5v1.6h3.3v-1.6h-.6M75.7 285.6v1.6M76 280.9v2M77.5 280.3h1.5v3.2h-1.5zM77.5 282.9h1.5M77.5 280.9h1.5M77.8 285.6v1.6M80 298.7h.2"/>
<path d="M80.2 298.7v.1M80.4 280.9h1.6v2h-1.6M81.1 296.2h-3.3v1h2.3M82 280.3h-1.6v3.2h1.6M82 282.9v.6M82 280.3v.6M82.5 296.1v.3M85.8 296.3l.2 .1M86 296.2l-.1 .1M86 296.1v.1M86.5 280.9v2M87.4 296.2h3.2v1h-2.2"/>
<path d="M88 280.3h-1.6v.6h1.6v2h-1.6v.6h1.6M88 282.9v.6M88 280.3v.6M88.3 298.7v.1M88.5 298.7h-.2M89.4 280.3h1.7v3.2h-1.7zM89.4 282.9h1.7M89.4 280.9h1.7M90.2 287.2h.1M90.2 287.2h.6M90.8 285.6v1.6M90.8 287.2h2.5v-1.6h-3.1v1.6"/>
<path d="M92.5 280.9h1.6v-.6h-1.7l.1 3.2h1.6v-.6h-1.6M92.7 285.6v1.6M94 280.9v2M122.9 296.9a3.2 3.2 0 0 1 3 2.6 3.2 3.2 0 0 1-1.7 3.5M185.5 296.9a3.2 3.2 0 0 0-2.9 2.6 3.2 3.2 0 0 0 1.7 3.5M217 282.8h1.6v3.2h-1.6zM217 283.4h1.6M217 285.4h1.6M217.6 293.2h.6M217.6 297.6h3.2v1.6h-3.2zM218.1 280.6h2.3M218.2 291.6h-.6v1.6"/>
<path d="M218.2 291.7v1.5h2.1v-1.5M218.2 297.6v1.6M218.2 291.7h2.1M220 282.8h1.5v3.2h-1.5zM220 283.4h1.5M220 285.4h1.5M220.3 291.6h.5v1.6M220.3 293.2h.5M220.3 297.6v1.6M226.7 282.5v1.6M226.8 281.9l.1 .1M226.9 282v2.6h.8v18.2"/>
<path d="M226.9 282.5v1.6M226.9 282.1v2.1M227 288.4h.7M227 299.4h.7M227 286.2h.7M227 297.2h.7M227 295h.7M227 290.6h.7M227 292.8h.7M227 285.6v.6M227 287.8v.6M227 290v.6"/>
<path d="M227 292.2v.6M227 294.4v.6M227 296.6v.6M227 298.8v.6M227.1 284.4h.1M227.2 284.4h.3M227.6 284.4h.1M227.7 287.8h-2.1v.6h1.4M227.7 298.8h-2.1v.6h1.4M227.7 285.6h-2.1v.6h1.4M227.7 296.6h-2.1v.6h1.4M227.7 294.4h-2.1v.6h1.4"/>
<path d="M227.7 290h-2.1v.6h1.4M227.7 292.2h-2.1v.6h1.4M227.8 286.4l.1 2zM227.8 298.5l.1 2zM227.8 284.6l.2 1.4M227.8 288.9l.2 9.2M228 288.5h.1M228.1 286.2v.1M228.1 288.6v.1M229.1 283.7h9.1M229.2 283.8v.1M229.2 281.9l.6 .1"/>
<path d="M229.2 283.9l8.7 .1M229.3 283.5l-.1 .1M229.3 281.5h-.1M229.4 283.4h.4M229.8 282v1.4M229.9 283.4v.3M232.8 283.4h5.5M234.7 281.1l-3.3 .9M234.7 281.1l2.5 .1 .2 1.3-4.9 .9h-2.7M234.7 281.1l-3.2 .9h-1.7M236.3 281.1l1.9-.1-.7 .5M236.6 280.7h1.7l-.4-.4a13.9 13.9 0 0 0-6.9 1.1h-1.6"/>
<path d="M236.6 280.3v.8M237 280.7v.3M237.4 282.4l.6 .2v1.1M237.5 281.5h.7M238.3 280.8v2.7l-.4 .5M248.7 281.2h.3M248.7 280.7v1.5M248.7 280.8h.6M248.7 281.1h.6M248.7 280.6v.1M249.2 281.5l-.5 .5M249.2 280.6v.1"/>
<path d="M250 281.6h.1M250.2 282.1l-.2 .1M252 280.7v.4h-2.7v-.3M252 281.1h.6M252 280.8h.6M252.1 280.6l-.1 .1M252.2 280.5h-.1M252.5 280.5h.1M252.5 281.9h.1M252.5 282.3l-.1 .1M252.6 280.6v.1M252.6 280.8l-.2 1.4"/>
<path d="M252.6 281.7l-.3 .7h-3.4M255.6 281.8l-1.4 5.1v57.5a8 8 0 0 1-8 8h-41.1M255.6 281.8l-.7 2.5M331 283.5h1.6M331 299.5h.1M331 281.2h.1M331 285.1h.1M331 287.2h.9M331 285.6h.9v1.6M331 294.4h1.3v.6h-1.3zM331 293.2l.1-1.6 1.5 .1v1.5h-1.5M331 298.4h1.5"/>
<path d="M331 296.2h.6v1h-.3M331 297.2h.3M331.3 291.2v.4M331.3 293.2v1.2M331.3 295v.4M331.3 296.2v1M331.3 294.4v.6M331.9 288.2v.5M332 288.4v.3M332 291.2v.4M332 293.2v1.2M332 295v.2"/>
<path d="M332.3 288.2l-.4 .2M332.4 281.8h2.4M332.5 295.4h-1.5v12.8h.9v-1.6h-.9M332.5 295.2v3.7l-1.2 .1v.8h-.3M332.5 295.2l-.6 .2M332.5 295.2l.2 2.9M332.6 283.9v.7M332.6 283.1v.8h-1.5M332.6 287.2v1h-1.5M332.7 298.1l-.2 7.5M332.7 298.1l-.2 .2M332.7 296.1l.8 .4v7.8l-.8 .4"/>
<path d="M332.7 298.7h.7M333 281.2l-.6 .6M333.4 280.1h.4M333.4 296.4h.1M333.4 298.8h.1M333.5 284.6v2.5l-1.6 .1M333.5 298.4l.6 .1v3.8l-.6 .1M334.2 281.2l.6 .6M334.2 281.2h-1.2M334.4 286.4h.3v2h-.3M334.4 283.1v21.5M334.4 284.6l-3.4 .1"/>
<path d="M334.4 285.9h.3M334.4 298h.3M334.4 298.5h.1M334.4 288.9h.3M334.4 284.4h.3M334.5 298.5l.2 2h-.3M334.7 283.1v21.5M337.5 281.8h2.3M338.1 281.2l-.6 .6M338.4 280.1v1.1M338.4 280.1h.5M339.3 281.2l.5 .6"/>
<path d="M339.3 281.2h-1.2M60 318.6l.2 .1M61 316.3v-2.3h-.9v3.2M62.5 316.1l.1 .2M62.6 316.3l-.1 .1M65.9 316.3l.1 .1M66 316.1l-.1 .2M67.4 316.3v-2.3h1v3.2M68.4 318.7h-.1M68.5 318.6l-.1 .1M70.4 318.8h1.6v3.2h-1.6zM70.4 319.4h1.6"/>
<path d="M80 318.6l.2 .1M80.1 303.6h-2.3v1h3.3M80.2 302v.2M80.2 302.1l-.2 .1M81.1 316.3v-2.3h-1.1v3.2M82.5 316.1v.3M82.5 304.5v.2M82.6 306.6h3.2v1.6h-3.2zM83.3 306.6v1.6M85.3 306.6v1.6M85.8 316.3l.2 .1M85.8 304.5l.2 .2"/>
<path d="M86 316.1l-.1 .2M87.5 316.3v-2.3h.9v3.2M88.3 302l.2 .2M88.4 303.6h2.2v1h-3.2M88.5 318.6l-.2 .1M96.4 318.8h1.6v3.2h-1.6zM96.4 319.4h1.6M99.9 318.6l.3 .1M101 316.3v-2.3h-1v3.2M102.5 316.1v.3M106 316.1v.3M107.4 316.3v-2.3h1.1v3.2"/>
<path d="M108.5 318.6l-.2 .1M210 318.6l.2 .1M211 316.3v-2.3h-.9v3.2M212.5 316.1v.2M212.6 316.3l-.1 .1M215.9 316.3l.1 .1M216 316.1l-.1 .2M217.5 316.3v-2.3h.9v3.2M217.6 300.6h3.2v1.6h-3.2zM217.6 303.6h3.2v1.6h-3.2zM218.2 300.6v1.6M218.2 303.6v1.6"/>
<path d="M218.3 318.7v.1M218.5 318.6l-.2 .1M220.3 300.6v1.6M220.3 303.6v1.6M220.4 318.8h1.6v3.2h-1.6zM220.4 319.4h1.6M226.4 318.8h1.6v3.2h-1.6zM226.4 319.4h1.6M226.6 305.1h2.8M226.6 305.1v1.4M226.7 306.7h.1M226.8 306.8h.1"/>
<path d="M226.8 303.2h-1.2v.6h1M226.8 303.2l-.2 1.9M226.9 306.8h1.6M227 301.6h.7M227 301v.6M227.3 305.2h1.4M227.4 303l-.6 .2M227.7 301h-2.1v.6h1.4M227.7 302.8l-.2 .2M227.8 301l-.1 1.8M228 300.6h.1M228.1 300.7v.1"/>
<path d="M228.7 305.1v1.6M229.4 304.8h4.1M229.4 305.1h24.8M229.4 304.4v.7M229.9 318.6l.3 .1M229.9 304.1l-.3 .1M230.2 304h.2M230.4 304l2.6 .1zM230.5 304.1v.2M230.5 304.6v.2M231 303.6l-.9 .5M231 316.3v-2.3h-1v3.2"/>
<path d="M231.1 303.5h.8M231.3 303.5v.4M231.6 303.7l-.2 .3M231.6 303.6v.1M232.1 303.6l.9 .5M232.4 316.1l.1 .2M232.6 316.3l-.1 .1M233.1 304.1h6.6M236 316.1v.3M237.4 316.3v-2.3h1.1v3.2M238.5 304.1l1.3 .1M238.5 318.6l-.2 .1"/>
<path d="M240 304.3v.1M240 304.4v.1M240 304.5l.3 .3M240.3 304.8l-10.2-.5v.3l5.9 .5M240.3 304.8l.1 .2M241.5 305.2h1.7M245 305.1v1.4M245.1 306.5v.1M246.2 306.6h-.9M247 306.3l-.6 .2M247.2 306.5l.1 .1M247.5 306.6h.9"/>
<path d="M248.6 305.1l-.1 1.4M251.2 305.2h1.6M331 301.1l.3-.1v.9h1.2v3.7M331 303.6h.6v1h-.3M331 304.6h.3M331 318.3v7.1M331 318.3h1M331 315.4h.4M331 302.5h1.5l.2 .3M331.3 303.6v1M331.3 315.2v.2M331.3 305.4v1.2"/>
<path d="M331.4 315.2h-.4v3.1M331.6 315.1v2.4l-.2-2.3M331.6 315.4h.9M331.6 315.1l-.6-1.1 .4 1.2M331.6 315.2h.9M331.9 305.4l.6 .2M332 318.3v4.2M332.5 315.2v10.4M332.5 305.4h-1.5M332.5 315.2v3.1M332.5 318.3h-.5M332.7 318.6l.8 .2"/>
<path d="M332.7 316.1l.8 .4v7.8l-.8 .4M332.7 318.1l-.2 .2M332.7 304.8h1.6M332.7 305.2h.2M333.4 302h.1M333.4 302.1l-.7 .1M333.5 304.8h-.1M333.5 318.4l.6 .1v3.8l-.6 .1M333.5 304h.9M334.4 303h.3M334.4 304.4l-.4 .4M334.4 301h.3"/>
<path d="M334.7 304.7l-.4 .4h-1.6M60.1 323.6v3.2h.9v-2.2M60.1 322.2h-.1M60.1 322l.1 .2M60.1 322.1v.1M62.6 324.5l-.1 .2M65.9 324.5l.1 .1M66 324.6v.1M68.3 322l.1 .2M68.4 322.2h.1M68.4 323.6v3.2h-1v-2.2M70.4 321.4h1.6"/>
<path d="M80 338.6l.2 .1M80 323.6v3.2h1.1v-2.2M80.2 322.1l-.2 .1M80.2 322v.2M80.2 338.7v.1M81.1 336.2h-3.3v1h2.3M82.5 336.1v.3M82.5 324.4v.3M82.6 328.6h3.2v1.6h-3.2zM82.6 332.6h3.2v1.6h-3.2zM83.3 328.6v1.6M83.3 332.6v1.6"/>
<path d="M85.3 328.6v1.6M85.3 332.6v1.6M85.8 324.5l.2 .2M86 336.1l-.2 .2M87.4 336.2h3.2v1h-2.2M88.3 322l.2 .2M88.4 323.6v3.2h-.9v-2.2M88.5 338.6l-.2 .2M96.4 321.4h1.6M100 323.6v3.2h1v-2.2M100.2 322l-.3 .2M102.5 324.4v.3"/>
<path d="M106 324.4v.3M108.3 322v.2M108.3 322.1l.2 .1M108.5 323.6v3.2h-1.1v-2.2M210.1 323.6v3.2h.9v-2.2M210.1 322.1l-.1 .1M210.1 322l.1 .2M212.6 324.5l-.1 .2M215.9 324.5l.1 .2M218.3 322v.2M218.3 322.1l.2 .1M218.4 323.6v3.2h-.9v-2.2"/>
<path d="M220.4 321.4h1.6M226.4 321.4h1.6M230 323.6v3.2h1v-2.2M230.2 322.1l-.3 .1M230.2 322v.2M232.6 324.5l-.2 .2M236 324.4v.3M238.3 322l.2 .2M238.5 323.6v3.2h-1.1v-2.2M331 336.2h.6v1h-.3M331 337.2h.3M331 337.2v6.4"/>
<path d="M331 328.6h.9v1.6h-.9zM331 325.4l.4 .2M331 332.6h.9v1.6h-.9zM331 322.5h1M331 325.4h.4M331.3 336.2v1M331.3 325.4v.2M331.4 325.6l.2-2.3v2.4M331.4 325.6l-.4 1.2 .6-1.1M331.6 325.4h.9M331.6 325.6h.9M332 322.5l.5 .1"/>
<path d="M332.5 335.2l-.6 .2M332.5 335.2v10.4M332.5 335.4h-1.5v1.8M332.5 335.2v3.7l-1.2 .1-.3 .8 .3 1.2M332.5 322.6l.2 .2M332.5 322.6v3M332.7 338.1l-.2 .2h-1.5M332.7 336.1l.8 .4v7.8l-.8 .4M332.7 338.6l.7 .1M333.4 322.1l-.7 .1M333.4 338.8h.1M333.4 322l.1 .1"/>
<path d="M333.5 322.1l-.1 .1M333.5 338.4l.6 .1-.1 3.9M80 342.2h.2M80.1 343.6h-2.3v1h3.3M82.5 344.5v.2M85.9 344.5l.1 .2M86 344.5h-.2M88.4 343.6h2.2v1h-3.2M88.5 342.2h-.2M103.5 350.8h101.6v17h-101.6zM105.4 343.5a1.01 1.01 0 0 1-.2-1.5 1.01 1.01 0 0 1 1.5 0 1.01 1.01 0 0 1-.1 1.5M105.4 350.8v-8.4h1.2v8.4"/>
<path d="M105.4 346.9a.98 .98 0 0 0 0 1.6M106.6 346.9a1.04 1.04 0 0 1 0 1.6M110.5 350.8v-8.4h1.2v8.4M110.5 346.9a.98 .98 0 0 0 0 1.6M111.7 346.9a1.04 1.04 0 0 1 0 1.6M111.7 343.5a1.01 1.01 0 0 0 .1-1.5 1.01 1.01 0 0 0-1.5 0 1.01 1.01 0 0 0 .2 1.5M115.6 350.8v-8.4h1.1v8.4M115.6 346.9a.98 .98 0 0 0 0 1.6M116.7 346.9a1.04 1.04 0 0 1 0 1.6M116.7 343.5a1.01 1.01 0 0 0 .2-1.5 1.01 1.01 0 0 0-1.5 0 1.01 1.01 0 0 0 .2 1.5M120.6 343.5a1.01 1.01 0 0 1-.1-1.5 1.01 1.01 0 0 1 1.5 0 1.01 1.01 0 0 1-.2 1.5M120.6 350.8v-8.4h1.2v8.4"/>
<path d="M120.6 346.9a.98 .98 0 0 0 0 1.6M121.8 346.9a1.04 1.04 0 0 1 0 1.6M125.7 350.8v-8.4h1.2v8.4M125.7 346.9a.98 .98 0 0 0 0 1.6M126.9 346.9a1.04 1.04 0 0 1 0 1.6M126.9 343.5a1.01 1.01 0 0 0 .2-1.5 1.01 1.01 0 0 0-1.5 0 1.01 1.01 0 0 0 .1 1.5M130.8 343.5a1.01 1.01 0 0 1-.2-1.5 1.01 1.01 0 0 1 1.5 0 1.01 1.01 0 0 1-.1 1.5M130.8 350.8v-8.4h1.2v8.4M130.8 346.9a.98 .98 0 0 0 0 1.6M132 346.9a1.04 1.04 0 0 1 0 1.6M135.9 350.8v-8.4h1.2v8.4M135.9 346.9a.98 .98 0 0 0 0 1.6"/>
<path d="M137.1 346.9a1.04 1.04 0 0 1 0 1.6M137.1 343.5a1.01 1.01 0 0 0 .1-1.5 1.01 1.01 0 0 0-1.5 0 1.01 1.01 0 0 0 .2 1.5M141 350.8v-8.4h1.1v8.4M141 346.9a.98 .98 0 0 0 0 1.6M142.1 346.9a1.04 1.04 0 0 1 0 1.6M142.1 343.5a1.01 1.01 0 0 0 .2-1.5 1.01 1.01 0 0 0-1.5 0 1.01 1.01 0 0 0 .2 1.5M146 343.5a1.01 1.01 0 0 1-.1-1.5 1.01 1.01 0 0 1 1.5 0 1.01 1.01 0 0 1-.2 1.5M146 346.9a.98 .98 0 0 0 0 1.6M146 350.8v-8.4h1.2v8.4M147.2 346.9a1.04 1.04 0 0 1 0 1.6M151.1 350.8v-8.4h1.2v8.4M151.1 346.9a.98 .98 0 0 0 0 1.6"/>
<path d="M152.3 346.9a1.04 1.04 0 0 1 0 1.6M152.3 343.5a1.01 1.01 0 0 0 .2-1.5 1.01 1.01 0 0 0-1.5 0 1.01 1.01 0 0 0 .1 1.5M156.2 350.8v-8.4h1.2v8.4M156.2 343.5a1.01 1.01 0 0 1-.2-1.5 1.01 1.01 0 0 1 1.5 0 1.01 1.01 0 0 1-.1 1.5M156.2 346.9a.98 .98 0 0 0 0 1.6M157.4 346.9a1.04 1.04 0 0 1 0 1.6M161.3 350.8v-8.4h1.2v8.4M161.3 346.9a.98 .98 0 0 0 0 1.6M162.5 346.9a1.04 1.04 0 0 1 0 1.6M162.5 343.5a1.01 1.01 0 0 0 .1-1.5 1.01 1.01 0 0 0-1.5 0 1.01 1.01 0 0 0 .2 1.5M166.4 343.5a1.01 1.01 0 0 1-.2-1.5 1.01 1.01 0 0 1 1.5 0 1.01 1.01 0 0 1-.2 1.5M166.4 350.8v-8.4h1.1v8.4"/>
<path d="M166.4 346.9a.98 .98 0 0 0 0 1.6M167.5 346.9a1.04 1.04 0 0 1 0 1.6M171.4 346.9a.98 .98 0 0 0 0 1.6M171.4 350.8v-8.4h1.2v8.4M172.6 346.9a1.04 1.04 0 0 1 0 1.6M172.6 343.5a1.01 1.01 0 0 0 .2-1.5 1.01 1.01 0 0 0-1.5 0 1.01 1.01 0 0 0 .1 1.5M176.5 350.8v-8.4h1.2v8.4M176.5 346.9a.98 .98 0 0 0 0 1.6M177.7 346.9a1.04 1.04 0 0 1 0 1.6M177.7 343.5a1.01 1.01 0 0 0 .2-1.5 1.01 1.01 0 0 0-1.5 0 1.01 1.01 0 0 0 .1 1.5M181.6 346.9a.98 .98 0 0 0 0 1.6M181.6 343.5a1.01 1.01 0 0 1-.2-1.5 1.01 1.01 0 0 1 1.5 0 1.01 1.01 0 0 1-.1 1.5"/>
<path d="M181.6 350.8v-8.4h1.2v8.4M182.8 346.9a1.04 1.04 0 0 1 0 1.6M186.6 346.9a1.04 1.04 0 0 0 0 1.6M186.6 350.8v-8.4h1.3v8.4M187.9 346.9a1.04 1.04 0 0 1 0 1.6M187.9 343.5a1.01 1.01 0 0 0 .1-1.5 1.01 1.01 0 0 0-1.5 0 1.01 1.01 0 0 0 .1 1.5M191.7 343.5a1.01 1.01 0 0 1-.1-1.5 1.01 1.01 0 0 1 1.5 0 1.01 1.01 0 0 1-.2 1.5M191.7 350.8v-8.4h1.2v8.4M191.7 346.9a1.04 1.04 0 0 0 0 1.6M192.9 346.9a1.04 1.04 0 0 1 0 1.6M196.8 350.8v-8.4h1.2v8.4M196.8 346.9a1.04 1.04 0 0 0 0 1.6"/>
<path d="M198 346.9a1.04 1.04 0 0 1 0 1.6M198 343.5a1.01 1.01 0 0 0 .2-1.5 1.01 1.01 0 0 0-1.5 0 1.01 1.01 0 0 0 .1 1.5M201.9 350.8v-8.4h1.2v8.4M201.9 346.9a1.04 1.04 0 0 0 0 1.6M203.1 346.9a1.04 1.04 0 0 1 0 1.6M203.1 343.5a1.01 1.01 0 0 0 .1-1.5 1.01 1.01 0 0 0-1.5 0 1.01 1.01 0 0 0 .2 1.5M326.4 342.4v.5M326.4 347.5v.4M327.8 342.4h-2.6v.5h2.6M327.8 347.5h-2.6v.4h2.6M331 347.5h2.2l.5 .3 .1 3.4M331 342.4h.1"/>
<path d="M331 342.9h.1M331 347.9l2.3 .1 .1 3.2M331 343.6h.6v1h-.3M331 344.6h.3M331 341.1h.3M331 343.6v1.8h1M331 342.5h1.5l.2 .3M331 350.8h1.7v.4h6.8v-.4h1.7v17h-10.2zM331.3 341v.8l1.2 .1v3.7M331.3 343.6v1M331.9 345.4l.6 .2M332 345.4h.5"/>
<path d="M333.5 342.9h4.9v8.3M333.5 342.1l-.8 .1M333.5 342.4h4.7l.6 .3 .1 8.5"/>
<circle cx="235.6" cy="99.8" r="1.51"/>
<circle cx="62.2" cy="196.4" r="3.2"/>
<circle cx="229.2" cy="195.4" r="1.01"/>
<circle cx="246.2" cy="196.4" r="3.2"/>
<circle cx="58.3" cy="207.9" r="1"/>
<circle cx="74.3" cy="215.4" r=".71"/>
<circle cx="89.7" cy="207.9" r="1.01"/>
<circle cx="222.7" cy="216.9" r="2"/>
<circle cx="250.2" cy="207.9" r="1"/>
<circle cx="74.3" cy="225.4" r=".69"/>
<circle cx="172" cy="220.9" r="2"/>
<circle cx="172" cy="220.9" r="5.6"/>
<circle cx="187.3" cy="220.9" r="2"/>
<circle cx="187.3" cy="220.9" r="5.6"/>
<circle cx="208.2" cy="238.9" r="1"/>
<circle cx="99.8" cy="244.4" r="1"/>
<circle cx="123.8" cy="242.7" r="3.1"/>
<circle cx="146.6" cy="240.4" r="1.76"/>
<circle cx="146.6" cy="240.4" r=".59"/>
<circle cx="151.7" cy="240.4" r="1.76"/>
<circle cx="151.7" cy="240.4" r=".59"/>
<circle cx="156.8" cy="240.4" r="1.76"/>
<circle cx="156.8" cy="240.4" r=".59"/>
<circle cx="161.9" cy="240.4" r="1.75"/>
<circle cx="161.9" cy="240.4" r=".59"/>
<circle cx="184.7" cy="242.7" r="3.1"/>
<circle cx="208.2" cy="248.4" r="1.01"/>
<circle cx="250.2" cy="240.4" r="1.01"/>
<circle cx="87.6" cy="267.7" r=".5"/>
<circle cx="99.1" cy="269.1" r=".51"/>
<circle cx="229.2" cy="265.4" r="1.01"/>
<circle cx="123.8" cy="299.9" r="3.1"/>
<circle cx="184.7" cy="299.9" r="3.1"/>
<circle cx="84.2" cy="300.4" r="5.6"/>
<circle cx="84.2" cy="300.4" r="1.99"/>
<circle cx="58.3" cy="332.9" r="1.01"/>
<circle cx="64.2" cy="320.4" r="5.6"/>
<circle cx="64.2" cy="320.4" r="2"/>
<circle cx="84.2" cy="320.4" r="5.6"/>
<circle cx="84.2" cy="320.4" r="2.02"/>
<circle cx="104.2" cy="320.4" r="5.6"/>
<circle cx="104.2" cy="320.4" r="2"/>
<circle cx="214.2" cy="320.4" r="2"/>
<circle cx="214.2" cy="320.4" r="5.6"/>
<circle cx="234.2" cy="320.4" r="2.01"/>
<circle cx="234.3" cy="320.5" r="5.6"/>
<circle cx="250.2" cy="332.9" r="1"/>
<circle cx="62.2" cy="344.4" r="3.2"/>
<circle cx="84.2" cy="340.4" r="5.6"/>
<circle cx="84.2" cy="340.4" r="1.99"/>
<circle cx="246.2" cy="344.4" r="3.2"/>
</g>
<g fill="#000">
<circle cx="59.3" cy="93.9" r=".25"/>
<circle cx="60.1" cy="94.3" r=".25"/>
<circle cx="60.1" cy="94.6" r=".25"/>
<circle cx="60.1" cy="92.5" r=".25"/>
<circle cx="60.2" cy="92.5" r=".25"/>
<circle cx="62.5" cy="92.5" r=".25"/>
<circle cx="62.6" cy="92.4" r=".25"/>
<circle cx="62.6" cy="92.5" r=".25"/>
<circle cx="63.6" cy="94.9" r=".25"/>
<circle cx="64.9" cy="94.9" r=".25"/>
<circle cx="65.9" cy="92.5" r=".25"/>
<circle cx="65.9" cy="92.4" r=".25"/>
<circle cx="66" cy="92.5" r=".25"/>
<circle cx="67.4" cy="94.6" r=".25"/>
<circle cx="67.4" cy="94.3" r=".25"/>
<circle cx="67.6" cy="91.8" r=".25"/>
<circle cx="68.1" cy="92.4" r=".25"/>
<circle cx="68.2" cy="92.4" r=".25"/>
<circle cx="68.2" cy="92.5" r=".25"/>
<circle cx="68.3" cy="92.5" r=".25"/>
<circle cx="74.5" cy="94.8" r=".25"/>
<circle cx="76.1" cy="94.8" r=".25"/>
<circle cx="77.5" cy="94.9" r=".25"/>
<circle cx="77.8" cy="94.9" r=".25"/>
<circle cx="78.4" cy="94" r=".25"/>
<circle cx="78.6" cy="93.9" r=".25"/>
<circle cx="79" cy="92.5" r=".25"/>
<circle cx="79" cy="93.4" r=".25"/>
<circle cx="79" cy="94.9" r=".25"/>
<circle cx="79" cy="93.7" r=".25"/>
<circle cx="80.2" cy="92.5" r=".25"/>
<circle cx="80.3" cy="92.5" r=".25"/>
<circle cx="80.3" cy="92.4" r=".25"/>
<circle cx="81.4" cy="92.4" r=".25"/>
<circle cx="82.5" cy="92.5" r=".25"/>
<circle cx="82.5" cy="92.4" r=".25"/>
<circle cx="82.6" cy="92.4" r=".25"/>
<circle cx="82.6" cy="92.5" r=".25"/>
<circle cx="85.9" cy="92.5" r=".25"/>
<circle cx="86" cy="92.5" r=".25"/>
<circle cx="88.2" cy="92.4" r=".25"/>
<circle cx="88.3" cy="92.5" r=".25"/>
<circle cx="89.4" cy="94.9" r=".25"/>
<circle cx="90.7" cy="94.9" r=".25"/>
<circle cx="92.4" cy="94.8" r=".25"/>
<circle cx="99.2" cy="93.9" r=".25"/>
<circle cx="100" cy="94.6" r=".25"/>
<circle cx="100" cy="94.3" r=".25"/>
<circle cx="100.2" cy="92.5" r=".25"/>
<circle cx="100.2" cy="92.4" r=".25"/>
<circle cx="100.3" cy="92.4" r=".25"/>
<circle cx="101" cy="92.4" r=".25"/>
<circle cx="101.8" cy="92.4" r=".25"/>
<circle cx="102.5" cy="92.5" r=".25"/>
<circle cx="102.5" cy="92.4" r=".25"/>
<circle cx="102.6" cy="92.4" r=".25"/>
<circle cx="102.6" cy="92.5" r=".25"/>
<circle cx="209.2" cy="93.9" r=".25"/>
<circle cx="210.1" cy="94.3" r=".25"/>
<circle cx="210.1" cy="94.6" r=".25"/>
<circle cx="210.1" cy="92.5" r=".25"/>
<circle cx="210.2" cy="92.5" r=".25"/>
<circle cx="210.5" cy="92.4" r=".25"/>
<circle cx="212.5" cy="92.5" r=".25"/>
<circle cx="212.5" cy="92.4" r=".25"/>
<circle cx="212.6" cy="92.4" r=".25"/>
<circle cx="212.6" cy="92.5" r=".25"/>
<circle cx="213.6" cy="94.9" r=".25"/>
<circle cx="214.9" cy="94.9" r=".25"/>
<circle cx="215.9" cy="92.5" r=".25"/>
<circle cx="215.9" cy="92.4" r=".25"/>
<circle cx="216" cy="92.5" r=".25"/>
<circle cx="217.2" cy="92.4" r=".25"/>
<circle cx="217.5" cy="94.6" r=".25"/>
<circle cx="217.5" cy="94.3" r=".25"/>
<circle cx="218" cy="92.4" r=".25"/>
<circle cx="218.1" cy="92.4" r=".25"/>
<circle cx="218.2" cy="92.4" r=".25"/>
<circle cx="218.3" cy="92.5" r=".25"/>
<circle cx="218.7" cy="92.4" r=".25"/>
<circle cx="218.8" cy="92.4" r=".25"/>
<circle cx="218.8" cy="92.5" r=".25"/>
<circle cx="218.9" cy="92.4" r=".25"/>
<circle cx="218.9" cy="92.5" r=".25"/>
<circle cx="219.5" cy="92.4" r=".25"/>
<circle cx="219.6" cy="92.4" r=".25"/>
<circle cx="219.6" cy="92.5" r=".25"/>
<circle cx="219.7" cy="92.4" r=".25"/>
<circle cx="219.7" cy="92.5" r=".25"/>
<circle cx="220" cy="94.8" r=".25"/>
<circle cx="220.3" cy="94.8" r=".25"/>
<circle cx="220.3" cy="92.4" r=".25"/>
<circle cx="220.4" cy="92.4" r=".25"/>
<circle cx="220.4" cy="92.5" r=".25"/>
<circle cx="220.5" cy="92.4" r=".25"/>
<circle cx="222.2" cy="94.8" r=".25"/>
<circle cx="222.8" cy="94.8" r=".25"/>
<circle cx="222.9" cy="94.8" r=".25"/>
<circle cx="224.5" cy="94.8" r=".25"/>
<circle cx="224.7" cy="94.8" r=".25"/>
<circle cx="225.3" cy="94.8" r=".25"/>
<circle cx="227.2" cy="93.4" r=".25"/>
<circle cx="227.2" cy="92.5" r=".25"/>
<circle cx="227.2" cy="93.5" r=".25"/>
<circle cx="227.3" cy="93.5" r=".25"/>
<circle cx="227.3" cy="92.4" r=".25"/>
<circle cx="227.3" cy="93.6" r=".25"/>
<circle cx="227.4" cy="93.6" r=".25"/>
<circle cx="227.4" cy="92.3" r=".25"/>
<circle cx="227.5" cy="93.6" r=".25"/>
<circle cx="228.6" cy="93.5" r=".25"/>
<circle cx="228.6" cy="92.3" r=".25"/>
<circle cx="228.6" cy="93.6" r=".25"/>
<circle cx="228.6" cy="92.4" r=".25"/>
<circle cx="228.7" cy="93.5" r=".25"/>
<circle cx="228.7" cy="92.4" r=".25"/>
<circle cx="228.7" cy="94.3" r=".25"/>
<circle cx="228.7" cy="92.5" r=".25"/>
<circle cx="228.7" cy="93.4" r=".25"/>
<circle cx="228.8" cy="94.1" r=".25"/>
<circle cx="228.9" cy="94.1" r=".25"/>
<circle cx="229.1" cy="94.2" r=".25"/>
<circle cx="229.1" cy="94.1" r=".25"/>
<circle cx="229.1" cy="94.3" r=".25"/>
<circle cx="229.2" cy="94.4" r=".25"/>
<circle cx="230" cy="94.3" r=".25"/>
<circle cx="230" cy="94.6" r=".25"/>
<circle cx="230.1" cy="92.1" r=".25"/>
<circle cx="230.1" cy="92.7" r=".25"/>
<circle cx="230.2" cy="92.5" r=".25"/>
<circle cx="230.2" cy="91.9" r=".25"/>
<circle cx="230.2" cy="92.4" r=".25"/>
<circle cx="230.3" cy="92.4" r=".25"/>
<circle cx="230.3" cy="91.9" r=".25"/>
<circle cx="230.4" cy="91.9" r=".25"/>
<circle cx="232.1" cy="91.9" r=".25"/>
<circle cx="232.5" cy="91.5" r=".25"/>
<circle cx="232.5" cy="92.5" r=".25"/>
<circle cx="232.5" cy="92.4" r=".25"/>
<circle cx="232.6" cy="92.5" r=".25"/>
<circle cx="232.6" cy="92.4" r=".25"/>
<circle cx="233.2" cy="86.6" r=".25"/>
<circle cx="233.6" cy="94.9" r=".25"/>
<circle cx="234.9" cy="94.9" r=".25"/>
<circle cx="235.9" cy="92.4" r=".25"/>
<circle cx="235.9" cy="92.5" r=".25"/>
<circle cx="236" cy="92.5" r=".25"/>
<circle cx="236" cy="92.4" r=".25"/>
<circle cx="237.4" cy="94.6" r=".25"/>
<circle cx="237.4" cy="94.3" r=".25"/>
<circle cx="238" cy="86.6" r=".25"/>
<circle cx="238.2" cy="92.4" r=".25"/>
<circle cx="238.2" cy="92.5" r=".25"/>
<circle cx="238.3" cy="92.5" r=".25"/>
<circle cx="238.9" cy="93.2" r=".25"/>
<circle cx="240" cy="91.2" r=".25"/>
<circle cx="240.1" cy="91.5" r=".25"/>
<circle cx="240.1" cy="91.2" r=".25"/>
<circle cx="240.1" cy="93.6" r=".25"/>
<circle cx="240.2" cy="91.6" r=".25"/>
<circle cx="240.2" cy="91.2" r=".25"/>
<circle cx="240.2" cy="91.8" r=".25"/>
<circle cx="240.2" cy="91.7" r=".25"/>
<circle cx="240.2" cy="93" r=".25"/>
<circle cx="240.2" cy="93.5" r=".25"/>
<circle cx="240.3" cy="91.8" r=".25"/>
<circle cx="240.3" cy="91.7" r=".25"/>
<circle cx="240.3" cy="93.5" r=".25"/>
<circle cx="240.3" cy="93.1" r=".25"/>
<circle cx="240.3" cy="93.3" r=".25"/>
<circle cx="240.3" cy="93.4" r=".25"/>
<circle cx="240.3" cy="93.2" r=".25"/>
<circle cx="241.1" cy="89.1" r=".25"/>
<circle cx="241.1" cy="93.3" r=".25"/>
<circle cx="241.1" cy="93.5" r=".25"/>
<circle cx="241.2" cy="93.6" r=".25"/>
<circle cx="241.2" cy="93.2" r=".25"/>
<circle cx="241.2" cy="93.3" r=".25"/>
<circle cx="241.3" cy="93.6" r=".25"/>
<circle cx="241.3" cy="93.1" r=".25"/>
<circle cx="241.3" cy="93.7" r=".25"/>
<circle cx="241.3" cy="92.4" r=".25"/>
<circle cx="241.3" cy="93" r=".25"/>
<circle cx="241.4" cy="92.3" r=".25"/>
<circle cx="241.5" cy="92.3" r=".25"/>
<circle cx="241.5" cy="93.6" r=".25"/>
<circle cx="241.7" cy="93.6" r=".25"/>
<circle cx="241.7" cy="89.7" r=".25"/>
<circle cx="242" cy="89.1" r=".25"/>
<circle cx="242.8" cy="93.5" r=".25"/>
<circle cx="242.9" cy="93.6" r=".25"/>
<circle cx="243" cy="93.6" r=".25"/>
<circle cx="243.1" cy="93.7" r=".25"/>
<circle cx="243.2" cy="92.3" r=".25"/>
<circle cx="243.3" cy="92.4" r=".25"/>
<circle cx="243.3" cy="93.7" r=".25"/>
<circle cx="243.3" cy="93" r=".25"/>
<circle cx="243.4" cy="93.6" r=".25"/>
<circle cx="243.4" cy="93.1" r=".25"/>
<circle cx="243.5" cy="93.5" r=".25"/>
<circle cx="243.5" cy="93.6" r=".25"/>
<circle cx="244.1" cy="95" r=".25"/>
<circle cx="244.9" cy="94" r=".25"/>
<circle cx="244.9" cy="94.8" r=".25"/>
<circle cx="245" cy="94.1" r=".25"/>
<circle cx="245" cy="94.8" r=".25"/>
<circle cx="248.6" cy="94.2" r=".25"/>
<circle cx="248.7" cy="94.1" r=".25"/>
<circle cx="248.8" cy="94" r=".25"/>
<circle cx="249" cy="93.9" r=".25"/>
<circle cx="249.1" cy="93.9" r=".25"/>
<circle cx="249.2" cy="95" r=".25"/>
<circle cx="249.2" cy="94" r=".25"/>
<circle cx="249.3" cy="94" r=".25"/>
<circle cx="249.3" cy="94.2" r=".25"/>
<circle cx="249.4" cy="94.3" r=".25"/>
<circle cx="249.4" cy="94.4" r=".25"/>
<circle cx="249.5" cy="94.4" r=".25"/>
<circle cx="251" cy="93.5" r=".25"/>
<circle cx="251" cy="93.3" r=".25"/>
<circle cx="251.1" cy="93.6" r=".25"/>
<circle cx="251.1" cy="93.5" r=".25"/>
<circle cx="251.1" cy="93.3" r=".25"/>
<circle cx="251.1" cy="93.2" r=".25"/>
<circle cx="251.2" cy="93.1" r=".25"/>
<circle cx="251.2" cy="93.6" r=".25"/>
<circle cx="251.2" cy="93.7" r=".25"/>
<circle cx="251.2" cy="93" r=".25"/>
<circle cx="251.2" cy="92.4" r=".25"/>
<circle cx="251.2" cy="92.5" r=".25"/>
<circle cx="251.3" cy="92.3" r=".25"/>
<circle cx="251.4" cy="92.3" r=".25"/>
<circle cx="251.6" cy="93.6" r=".25"/>
<circle cx="252.8" cy="93.6" r=".25"/>
<circle cx="252.9" cy="93.6" r=".25"/>
<circle cx="253" cy="93.7" r=".25"/>
<circle cx="253.1" cy="92.3" r=".25"/>
<circle cx="253.2" cy="92.4" r=".25"/>
<circle cx="253.2" cy="93.7" r=".25"/>
<circle cx="253.2" cy="93" r=".25"/>
<circle cx="253.3" cy="93.1" r=".25"/>
<circle cx="253.3" cy="93.7" r=".25"/>
<circle cx="253.3" cy="93.6" r=".25"/>
<circle cx="253.4" cy="93.6" r=".25"/>
<circle cx="253.4" cy="93.5" r=".25"/>
<circle cx="254" cy="94.4" r=".25"/>
<circle cx="254.1" cy="94.4" r=".25"/>
<circle cx="254.2" cy="94.4" r=".25"/>
<circle cx="254.2" cy="94.3" r=".25"/>
<circle cx="254.4" cy="93" r=".25"/>
<circle cx="254.5" cy="93" r=".25"/>
<circle cx="254.5" cy="92.1" r=".25"/>
<circle cx="254.5" cy="92.9" r=".25"/>
<circle cx="254.5" cy="92.2" r=".25"/>
<circle cx="254.6" cy="92.9" r=".25"/>
<circle cx="254.6" cy="92.3" r=".25"/>
<circle cx="166.2" cy="103.5" r=".25"/>
<circle cx="221.1" cy="196.2" r=".25"/>
<circle cx="221.7" cy="196" r=".25"/>
<circle cx="221.7" cy="194.8" r=".25"/>
<circle cx="331.9" cy="196.2" r=".25"/>
<circle cx="331.9" cy="194.6" r=".25"/>
<circle cx="102.2" cy="206.8" r=".25"/>
<circle cx="102.2" cy="208" r=".25"/>
<circle cx="104.3" cy="208" r=".25"/>
<circle cx="104.3" cy="206.8" r=".25"/>
<circle cx="114.5" cy="206.7" r=".25"/>
<circle cx="117.1" cy="206.7" r=".25"/>
<circle cx="167.9" cy="219.2" r=".25"/>
<circle cx="168" cy="219.2" r=".25"/>
<circle cx="170.3" cy="216.8" r=".25"/>
<circle cx="170.4" cy="216.8" r=".25"/>
<circle cx="173.6" cy="216.8" r=".25"/>
<circle cx="173.7" cy="216.8" r=".25"/>
<circle cx="173.8" cy="216.9" r=".25"/>
<circle cx="173.8" cy="216.8" r=".25"/>
<circle cx="176.1" cy="219.2" r=".25"/>
<circle cx="183.2" cy="219.2" r=".25"/>
<circle cx="185.5" cy="216.8" r=".25"/>
<circle cx="185.6" cy="216.8" r=".25"/>
<circle cx="188.9" cy="216.8" r=".25"/>
<circle cx="189" cy="216.8" r=".25"/>
<circle cx="189" cy="216.9" r=".25"/>
<circle cx="191.3" cy="219.2" r=".25"/>
<circle cx="191.3" cy="219.3" r=".25"/>
<circle cx="203.7" cy="208.2" r=".25"/>
<circle cx="206.2" cy="208" r=".25"/>
<circle cx="206.2" cy="206.8" r=".25"/>
<circle cx="206.8" cy="208.2" r=".25"/>
<circle cx="323.8" cy="207.9" r=".25"/>
<circle cx="324.1" cy="207.9" r=".25"/>
<circle cx="324.1" cy="207.8" r=".25"/>
<circle cx="325.9" cy="207.9" r=".25"/>
<circle cx="331" cy="218.8" r=".25"/>
<circle cx="331" cy="212.2" r=".25"/>
<circle cx="331.3" cy="209.1" r=".25"/>
<circle cx="331.4" cy="209.6" r=".25"/>
<circle cx="331.5" cy="209.6" r=".25"/>
<circle cx="331.5" cy="209.5" r=".25"/>
<circle cx="331.9" cy="206.6" r=".25"/>
<circle cx="331.9" cy="208.2" r=".25"/>
<circle cx="332.1" cy="209.5" r=".25"/>
<circle cx="332.2" cy="209.6" r=".25"/>
<circle cx="339.3" cy="216.2" r=".25"/>
<circle cx="101" cy="232.3" r=".25"/>
<circle cx="101" cy="234.9" r=".25"/>
<circle cx="102.5" cy="232.9" r=".25"/>
<circle cx="102.5" cy="232.3" r=".25"/>
<circle cx="102.5" cy="234.9" r=".25"/>
<circle cx="102.5" cy="235.5" r=".25"/>
<circle cx="113.2" cy="228.1" r=".25"/>
<circle cx="113.2" cy="229.7" r=".25"/>
<circle cx="113.7" cy="228.1" r=".25"/>
<circle cx="115.7" cy="229.7" r=".25"/>
<circle cx="115.7" cy="228.1" r=".25"/>
<circle cx="116.3" cy="228.1" r=".25"/>
<circle cx="133" cy="227.9" r=".25"/>
<circle cx="133" cy="230.5" r=".25"/>
<circle cx="133" cy="229.9" r=".25"/>
<circle cx="133" cy="227.3" r=".25"/>
<circle cx="134.5" cy="230.5" r=".25"/>
<circle cx="134.5" cy="227.9" r=".25"/>
<circle cx="167.9" cy="222.6" r=".25"/>
<circle cx="167.9" cy="222.5" r=".25"/>
<circle cx="168" cy="222.6" r=".25"/>
<circle cx="170.3" cy="224.9" r=".25"/>
<circle cx="170.3" cy="225" r=".25"/>
<circle cx="170.4" cy="225" r=".25"/>
<circle cx="173.6" cy="225" r=".25"/>
<circle cx="173.7" cy="225" r=".25"/>
<circle cx="173.8" cy="224.9" r=".25"/>
<circle cx="173.8" cy="225" r=".25"/>
<circle cx="176.1" cy="222.6" r=".25"/>
<circle cx="176.1" cy="222.5" r=".25"/>
<circle cx="183.2" cy="222.5" r=".25"/>
<circle cx="183.2" cy="222.6" r=".25"/>
<circle cx="185.5" cy="224.9" r=".25"/>
<circle cx="185.5" cy="225" r=".25"/>
<circle cx="185.6" cy="225" r=".25"/>
<circle cx="188.9" cy="225" r=".25"/>
<circle cx="189" cy="225" r=".25"/>
<circle cx="189" cy="224.9" r=".25"/>
<circle cx="191.3" cy="222.6" r=".25"/>
<circle cx="191.3" cy="222.5" r=".25"/>
<circle cx="254.5" cy="225.4" r=".25"/>
<circle cx="324.1" cy="233" r=".25"/>
<circle cx="325.9" cy="233" r=".25"/>
<circle cx="331" cy="223.7" r=".25"/>
<circle cx="331" cy="230.1" r=".25"/>
<circle cx="331" cy="233.2" r=".25"/>
<circle cx="331" cy="227.7" r=".25"/>
<circle cx="331.1" cy="234.7" r=".25"/>
<circle cx="331.1" cy="232.9" r=".25"/>
<circle cx="331.1" cy="235.5" r=".25"/>
<circle cx="331.1" cy="233.9" r=".25"/>
<circle cx="331.1" cy="233.2" r=".25"/>
<circle cx="331.9" cy="221" r=".25"/>
<circle cx="331.9" cy="221.8" r=".25"/>
<circle cx="331.9" cy="232" r=".25"/>
<circle cx="333.5" cy="224.9" r=".25"/>
<circle cx="333.5" cy="233.2" r=".25"/>
<circle cx="333.5" cy="222.6" r=".25"/>
<circle cx="333.5" cy="224.8" r=".25"/>
<circle cx="333.5" cy="222.5" r=".25"/>
<circle cx="74.5" cy="257.3" r=".25"/>
<circle cx="74.5" cy="259.9" r=".25"/>
<circle cx="82" cy="257.9" r=".25"/>
<circle cx="82" cy="257.3" r=".25"/>
<circle cx="82" cy="259.9" r=".25"/>
<circle cx="85" cy="257.9" r=".25"/>
<circle cx="85" cy="259.9" r=".25"/>
<circle cx="85" cy="257.3" r=".25"/>
<circle cx="88" cy="259.9" r=".25"/>
<circle cx="88" cy="257.3" r=".25"/>
<circle cx="88" cy="257.9" r=".25"/>
<circle cx="92.4" cy="259.9" r=".25"/>
<circle cx="92.4" cy="257.3" r=".25"/>
<circle cx="213.1" cy="249.2" r=".25"/>
<circle cx="213.7" cy="249.2" r=".25"/>
<circle cx="214.2" cy="241.5" r=".25"/>
<circle cx="215.3" cy="241.5" r=".25"/>
<circle cx="215.6" cy="242" r=".25"/>
<circle cx="215.7" cy="249.2" r=".25"/>
<circle cx="216.4" cy="249.2" r=".25"/>
<circle cx="216.7" cy="254.4" r=".25"/>
<circle cx="216.7" cy="256.4" r=".25"/>
<circle cx="217.2" cy="254.4" r=".25"/>
<circle cx="217.2" cy="256.4" r=".25"/>
<circle cx="217.2" cy="256.5" r=".25"/>
<circle cx="217.2" cy="254.5" r=".25"/>
<circle cx="217.3" cy="256.5" r=".25"/>
<circle cx="217.3" cy="254.5" r=".25"/>
<circle cx="217.3" cy="254.4" r=".25"/>
<circle cx="217.3" cy="256.4" r=".25"/>
<circle cx="217.9" cy="254.5" r=".25"/>
<circle cx="217.9" cy="253.9" r=".25"/>
<circle cx="217.9" cy="254.3" r=".25"/>
<circle cx="217.9" cy="257" r=".25"/>
<circle cx="217.9" cy="253.8" r=".25"/>
<circle cx="218" cy="257" r=".25"/>
<circle cx="218" cy="253.8" r=".25"/>
<circle cx="218" cy="256.2" r=".25"/>
<circle cx="218.1" cy="253.8" r=".25"/>
<circle cx="218.1" cy="257" r=".25"/>
<circle cx="218.1" cy="256.9" r=".25"/>
<circle cx="218.1" cy="253.9" r=".25"/>
<circle cx="218.2" cy="256.9" r=".25"/>
<circle cx="218.7" cy="253.9" r=".25"/>
<circle cx="218.7" cy="257" r=".25"/>
<circle cx="218.7" cy="254" r=".25"/>
<circle cx="218.7" cy="253.8" r=".25"/>
<circle cx="218.8" cy="253.8" r=".25"/>
<circle cx="218.8" cy="257" r=".25"/>
<circle cx="218.9" cy="253.9" r=".25"/>
<circle cx="218.9" cy="257" r=".25"/>
<circle cx="218.9" cy="254" r=".25"/>
<circle cx="218.9" cy="256.9" r=".25"/>
<circle cx="218.9" cy="253.8" r=".25"/>
<circle cx="219" cy="256.9" r=".25"/>
<circle cx="219.5" cy="254" r=".25"/>
<circle cx="219.5" cy="253.9" r=".25"/>
<circle cx="219.5" cy="257" r=".25"/>
<circle cx="219.5" cy="253.8" r=".25"/>
<circle cx="219.6" cy="253.8" r=".25"/>
<circle cx="219.6" cy="257" r=".25"/>
<circle cx="219.6" cy="254" r=".25"/>
<circle cx="219.7" cy="253.8" r=".25"/>
<circle cx="219.7" cy="253.9" r=".25"/>
<circle cx="219.7" cy="254" r=".25"/>
<circle cx="219.7" cy="257" r=".25"/>
<circle cx="219.7" cy="256.9" r=".25"/>
<circle cx="219.8" cy="256.9" r=".25"/>
<circle cx="220" cy="245.9" r=".25"/>
<circle cx="220" cy="248.5" r=".25"/>
<circle cx="220" cy="245.3" r=".25"/>
<circle cx="220" cy="247.9" r=".25"/>
<circle cx="220.3" cy="254" r=".25"/>
<circle cx="220.3" cy="253.9" r=".25"/>
<circle cx="220.3" cy="257" r=".25"/>
<circle cx="220.3" cy="253.8" r=".25"/>
<circle cx="220.4" cy="253.8" r=".25"/>
<circle cx="220.4" cy="257" r=".25"/>
<circle cx="220.4" cy="254.6" r=".25"/>
<circle cx="220.5" cy="257" r=".25"/>
<circle cx="220.5" cy="253.8" r=".25"/>
<circle cx="220.5" cy="253.9" r=".25"/>
<circle cx="220.5" cy="254" r=".25"/>
<circle cx="220.5" cy="256.5" r=".25"/>
<circle cx="220.6" cy="256.4" r=".25"/>
<circle cx="221.2" cy="256.5" r=".25"/>
<circle cx="221.2" cy="254.5" r=".25"/>
<circle cx="221.2" cy="254.4" r=".25"/>
<circle cx="221.2" cy="256.4" r=".25"/>
<circle cx="221.8" cy="256.4" r=".25"/>
<circle cx="221.8" cy="254.4" r=".25"/>
<circle cx="222.2" cy="249.2" r=".25"/>
<circle cx="222.8" cy="249.2" r=".25"/>
<circle cx="223.1" cy="241.5" r=".25"/>
<circle cx="224.4" cy="241.5" r=".25"/>
<circle cx="224.5" cy="242" r=".25"/>
<circle cx="224.7" cy="249.2" r=".25"/>
<circle cx="225.3" cy="249.2" r=".25"/>
<circle cx="227.2" cy="259.6" r=".25"/>
<circle cx="229.8" cy="259.6" r=".25"/>
<circle cx="241.1" cy="250.2" r=".25"/>
<circle cx="241.7" cy="250.2" r=".25"/>
<circle cx="241.7" cy="246.7" r=".25"/>
<circle cx="241.9" cy="255.8" r=".25"/>
<circle cx="241.9" cy="255.1" r=".25"/>
<circle cx="242" cy="251.9" r=".25"/>
<circle cx="242" cy="258.9" r=".25"/>
<circle cx="242" cy="250.2" r=".25"/>
<circle cx="242" cy="252" r=".25"/>
<circle cx="242.1" cy="252" r=".25"/>
<circle cx="242.1" cy="250.1" r=".25"/>
<circle cx="242.1" cy="258.9" r=".25"/>
<circle cx="242.1" cy="252.1" r=".25"/>
<circle cx="242.1" cy="258.8" r=".25"/>
<circle cx="242.1" cy="246.5" r=".25"/>
<circle cx="242.1" cy="258.7" r=".25"/>
<circle cx="242.1" cy="250" r=".25"/>
<circle cx="242.2" cy="250" r=".25"/>
<circle cx="242.2" cy="252.2" r=".25"/>
<circle cx="242.2" cy="258.7" r=".25"/>
<circle cx="242.2" cy="246.5" r=".25"/>
<circle cx="242.5" cy="246.5" r=".25"/>
<circle cx="243.8" cy="246.5" r=".25"/>
<circle cx="244.1" cy="246.4" r=".25"/>
<circle cx="245.6" cy="252.7" r=".25"/>
<circle cx="245.6" cy="250.1" r=".25"/>
<circle cx="245.6" cy="258.1" r=".25"/>
<circle cx="246.6" cy="258.1" r=".25"/>
<circle cx="246.6" cy="252.7" r=".25"/>
<circle cx="246.6" cy="250.1" r=".25"/>
<circle cx="316.6" cy="256.2" r=".25"/>
<circle cx="331" cy="250.7" r=".25"/>
<circle cx="331" cy="248.2" r=".25"/>
<circle cx="331" cy="249" r=".25"/>
<circle cx="331" cy="253" r=".25"/>
<circle cx="331.1" cy="256.4" r=".25"/>
<circle cx="331.1" cy="257.3" r=".25"/>
<circle cx="331.1" cy="245.9" r=".25"/>
<circle cx="331.1" cy="246.8" r=".25"/>
<circle cx="331.1" cy="241.4" r=".25"/>
<circle cx="331.1" cy="256.5" r=".25"/>
<circle cx="331.1" cy="241.6" r=".25"/>
<circle cx="331.1" cy="243.2" r=".25"/>
<circle cx="331.1" cy="252.9" r=".25"/>
<circle cx="331.1" cy="255.5" r=".25"/>
<circle cx="331.1" cy="247.6" r=".25"/>
<circle cx="331.1" cy="249.2" r=".25"/>
<circle cx="331.2" cy="256.4" r=".25"/>
<circle cx="331.9" cy="256.5" r=".25"/>
<circle cx="331.9" cy="256.8" r=".25"/>
<circle cx="332" cy="256.4" r=".25"/>
<circle cx="332" cy="256.9" r=".25"/>
<circle cx="332" cy="256.5" r=".25"/>
<circle cx="332" cy="256.8" r=".25"/>
<circle cx="332.1" cy="257" r=".25"/>
<circle cx="332.1" cy="256.9" r=".25"/>
<circle cx="332.9" cy="252.3" r=".25"/>
<circle cx="332.9" cy="250.4" r=".25"/>
<circle cx="333" cy="250.4" r=".25"/>
<circle cx="333.4" cy="253.9" r=".25"/>
<circle cx="333.4" cy="254" r=".25"/>
<circle cx="333.4" cy="256.9" r=".25"/>
<circle cx="334.1" cy="252.8" r=".25"/>
<circle cx="334.3" cy="246.2" r=".25"/>
<circle cx="334.3" cy="246.3" r=".25"/>
<circle cx="334.3" cy="246.4" r=".25"/>
<circle cx="334.3" cy="246.5" r=".25"/>
<circle cx="334.4" cy="246.5" r=".25"/>
<circle cx="334.4" cy="246.6" r=".25"/>
<circle cx="334.5" cy="246.6" r=".25"/>
<circle cx="334.6" cy="246.7" r=".25"/>
<circle cx="336.2" cy="252.1" r=".25"/>
<circle cx="336.2" cy="252" r=".25"/>
<circle cx="336.2" cy="250" r=".25"/>
<circle cx="336.2" cy="249.5" r=".25"/>
<circle cx="336.2" cy="249.6" r=".25"/>
<circle cx="336.3" cy="249.4" r=".25"/>
<circle cx="336.3" cy="251.9" r=".25"/>
<circle cx="336.3" cy="250.1" r=".25"/>
<circle cx="336.3" cy="249.3" r=".25"/>
<circle cx="336.4" cy="249.3" r=".25"/>
<circle cx="336.5" cy="250.2" r=".25"/>
<circle cx="336.8" cy="252.7" r=".25"/>
<circle cx="336.8" cy="250.2" r=".25"/>
<circle cx="336.8" cy="249" r=".25"/>
<circle cx="67.6" cy="269.1" r=".25"/>
<circle cx="82" cy="260.5" r=".25"/>
<circle cx="85" cy="260.5" r=".25"/>
<circle cx="88" cy="260.5" r=".25"/>
<circle cx="227.3" cy="276.9" r=".25"/>
<circle cx="228.3" cy="276.9" r=".25"/>
<circle cx="228.7" cy="275.5" r=".25"/>
<circle cx="228.8" cy="275.6" r=".25"/>
<circle cx="228.9" cy="275.8" r=".25"/>
<circle cx="228.9" cy="275.7" r=".25"/>
<circle cx="229.1" cy="277.6" r=".25"/>
<circle cx="229.2" cy="277.7" r=".25"/>
<circle cx="229.9" cy="277.6" r=".25"/>
<circle cx="231" cy="275.7" r=".25"/>
<circle cx="232.8" cy="275.7" r=".25"/>
<circle cx="241" cy="276.3" r=".25"/>
<circle cx="241.1" cy="264.2" r=".25"/>
<circle cx="241.1" cy="276.4" r=".25"/>
<circle cx="241.2" cy="276.4" r=".25"/>
<circle cx="242" cy="260.6" r=".25"/>
<circle cx="242.1" cy="260.7" r=".25"/>
<circle cx="242.1" cy="264.4" r=".25"/>
<circle cx="242.1" cy="260.8" r=".25"/>
<circle cx="242.1" cy="264.3" r=".25"/>
<circle cx="242.2" cy="260.9" r=".25"/>
<circle cx="242.2" cy="264.3" r=".25"/>
<circle cx="242.8" cy="276.4" r=".25"/>
<circle cx="242.9" cy="276.3" r=".25"/>
<circle cx="242.9" cy="276.1" r=".25"/>
<circle cx="243.8" cy="264.4" r=".25"/>
<circle cx="244.1" cy="264.4" r=".25"/>
<circle cx="245" cy="274.4" r=".25"/>
<circle cx="245.1" cy="274.3" r=".25"/>
<circle cx="245.2" cy="274.2" r=".25"/>
<circle cx="245.6" cy="260.7" r=".25"/>
<circle cx="246.1" cy="274.2" r=".25"/>
<circle cx="246.2" cy="274.2" r=".25"/>
<circle cx="246.2" cy="274.3" r=".25"/>
<circle cx="246.3" cy="274.3" r=".25"/>
<circle cx="246.4" cy="274.4" r=".25"/>
<circle cx="246.5" cy="274.5" r=".25"/>
<circle cx="246.6" cy="260.7" r=".25"/>
<circle cx="246.6" cy="274.6" r=".25"/>
<circle cx="246.9" cy="274.6" r=".25"/>
<circle cx="247.1" cy="274.5" r=".25"/>
<circle cx="247.3" cy="274.3" r=".25"/>
<circle cx="248.4" cy="274.2" r=".25"/>
<circle cx="248.4" cy="274.3" r=".25"/>
<circle cx="248.5" cy="274.3" r=".25"/>
<circle cx="248.5" cy="274.4" r=".25"/>
<circle cx="248.6" cy="274.4" r=".25"/>
<circle cx="252.6" cy="275.7" r=".25"/>
<circle cx="254.3" cy="275.7" r=".25"/>
<circle cx="255.4" cy="277.9" r=".25"/>
<circle cx="255.4" cy="278" r=".25"/>
<circle cx="255.5" cy="278.1" r=".25"/>
<circle cx="255.5" cy="278" r=".25"/>
<circle cx="255.5" cy="277.8" r=".25"/>
<circle cx="255.5" cy="280" r=".25"/>
<circle cx="255.5" cy="277.7" r=".25"/>
<circle cx="255.6" cy="280" r=".25"/>
<circle cx="255.6" cy="277.7" r=".25"/>
<circle cx="331" cy="261.8" r=".25"/>
<circle cx="331" cy="262.6" r=".25"/>
<circle cx="74.5" cy="283.5" r=".25"/>
<circle cx="74.5" cy="282.9" r=".25"/>
<circle cx="74.5" cy="280.9" r=".25"/>
<circle cx="74.5" cy="280.3" r=".25"/>
<circle cx="80.2" cy="298.7" r=".25"/>
<circle cx="80.2" cy="298.8" r=".25"/>
<circle cx="82" cy="283.5" r=".25"/>
<circle cx="82" cy="280.9" r=".25"/>
<circle cx="82.5" cy="296.4" r=".25"/>
<circle cx="82.5" cy="296.3" r=".25"/>
<circle cx="82.6" cy="296.3" r=".25"/>
<circle cx="85.9" cy="296.3" r=".25"/>
<circle cx="86" cy="296.4" r=".25"/>
<circle cx="86" cy="296.3" r=".25"/>
<circle cx="88" cy="283.5" r=".25"/>
<circle cx="88" cy="280.9" r=".25"/>
<circle cx="88.3" cy="298.7" r=".25"/>
<circle cx="88.3" cy="298.8" r=".25"/>
<circle cx="92.4" cy="280.9" r=".25"/>
<circle cx="92.4" cy="280.3" r=".25"/>
<circle cx="92.4" cy="283.5" r=".25"/>
<circle cx="92.4" cy="282.9" r=".25"/>
<circle cx="217.6" cy="293.2" r=".25"/>
<circle cx="218.2" cy="293.2" r=".25"/>
<circle cx="218.2" cy="291.6" r=".25"/>
<circle cx="220.3" cy="293.2" r=".25"/>
<circle cx="220.8" cy="291.6" r=".25"/>
<circle cx="220.8" cy="293.2" r=".25"/>
<circle cx="226.7" cy="281.8" r=".25"/>
<circle cx="226.8" cy="281.9" r=".25"/>
<circle cx="226.9" cy="282" r=".25"/>
<circle cx="226.9" cy="284.2" r=".25"/>
<circle cx="226.9" cy="282.1" r=".25"/>
<circle cx="227" cy="284.3" r=".25"/>
<circle cx="227.1" cy="284.4" r=".25"/>
<circle cx="227.7" cy="284.5" r=".25"/>
<circle cx="227.8" cy="284.6" r=".25"/>
<circle cx="227.9" cy="288.9" r=".25"/>
<circle cx="228" cy="288.9" r=".25"/>
<circle cx="228" cy="298.5" r=".25"/>
<circle cx="228" cy="286.4" r=".25"/>
<circle cx="228" cy="298.1" r=".25"/>
<circle cx="228" cy="286" r=".25"/>
<circle cx="228" cy="286.3" r=".25"/>
<circle cx="228" cy="298.4" r=".25"/>
<circle cx="228" cy="288.8" r=".25"/>
<circle cx="228" cy="298.2" r=".25"/>
<circle cx="228" cy="288.5" r=".25"/>
<circle cx="228.1" cy="286.1" r=".25"/>
<circle cx="228.1" cy="288.7" r=".25"/>
<circle cx="228.1" cy="298.2" r=".25"/>
<circle cx="228.1" cy="298.3" r=".25"/>
<circle cx="228.1" cy="288.8" r=".25"/>
<circle cx="229.1" cy="283.6" r=".25"/>
<circle cx="229.1" cy="281.7" r=".25"/>
<circle cx="229.1" cy="283.8" r=".25"/>
<circle cx="229.1" cy="281.8" r=".25"/>
<circle cx="229.1" cy="281.6" r=".25"/>
<circle cx="229.1" cy="283.7" r=".25"/>
<circle cx="229.2" cy="281.9" r=".25"/>
<circle cx="229.2" cy="281.6" r=".25"/>
<circle cx="229.3" cy="281.5" r=".25"/>
<circle cx="229.3" cy="283.5" r=".25"/>
<circle cx="229.3" cy="281.4" r=".25"/>
<circle cx="229.4" cy="281.4" r=".25"/>
<circle cx="229.4" cy="283.4" r=".25"/>
<circle cx="229.8" cy="282" r=".25"/>
<circle cx="234.7" cy="281.1" r=".25"/>
<circle cx="237.8" cy="284" r=".25"/>
<circle cx="237.9" cy="284" r=".25"/>
<circle cx="238.3" cy="280.8" r=".25"/>
<circle cx="238.3" cy="280.7" r=".25"/>
<circle cx="238.3" cy="281.5" r=".25"/>
<circle cx="248.7" cy="282.2" r=".25"/>
<circle cx="248.7" cy="280.6" r=".25"/>
<circle cx="248.7" cy="282.3" r=".25"/>
<circle cx="248.7" cy="280.5" r=".25"/>
<circle cx="248.8" cy="282.3" r=".25"/>
<circle cx="248.8" cy="280.5" r=".25"/>
<circle cx="248.8" cy="282.4" r=".25"/>
<circle cx="248.9" cy="280.5" r=".25"/>
<circle cx="249" cy="280.5" r=".25"/>
<circle cx="249.1" cy="281.2" r=".25"/>
<circle cx="249.1" cy="280.5" r=".25"/>
<circle cx="249.2" cy="281.5" r=".25"/>
<circle cx="249.2" cy="281.3" r=".25"/>
<circle cx="249.2" cy="281.2" r=".25"/>
<circle cx="249.2" cy="280.6" r=".25"/>
<circle cx="249.2" cy="281.4" r=".25"/>
<circle cx="249.3" cy="280.7" r=".25"/>
<circle cx="249.7" cy="282" r=".25"/>
<circle cx="249.7" cy="281.9" r=".25"/>
<circle cx="249.7" cy="281.8" r=".25"/>
<circle cx="249.7" cy="281.7" r=".25"/>
<circle cx="249.8" cy="282.1" r=".25"/>
<circle cx="249.8" cy="281.7" r=".25"/>
<circle cx="249.8" cy="281.6" r=".25"/>
<circle cx="249.9" cy="281.6" r=".25"/>
<circle cx="250" cy="282.2" r=".25"/>
<circle cx="250.1" cy="282.2" r=".25"/>
<circle cx="250.1" cy="281.6" r=".25"/>
<circle cx="250.1" cy="282.1" r=".25"/>
<circle cx="250.2" cy="281.7" r=".25"/>
<circle cx="250.2" cy="282.1" r=".25"/>
<circle cx="250.2" cy="282" r=".25"/>
<circle cx="250.3" cy="281.8" r=".25"/>
<circle cx="250.3" cy="281.9" r=".25"/>
<circle cx="250.3" cy="282" r=".25"/>
<circle cx="252.1" cy="280.6" r=".25"/>
<circle cx="252.2" cy="280.5" r=".25"/>
<circle cx="252.3" cy="280.5" r=".25"/>
<circle cx="252.4" cy="280.5" r=".25"/>
<circle cx="252.4" cy="282.4" r=".25"/>
<circle cx="252.5" cy="280.5" r=".25"/>
<circle cx="252.6" cy="280.5" r=".25"/>
<circle cx="252.6" cy="282.3" r=".25"/>
<circle cx="252.6" cy="282.2" r=".25"/>
<circle cx="252.6" cy="280.6" r=".25"/>
<circle cx="252.6" cy="280.7" r=".25"/>
<circle cx="255" cy="284.1" r=".25"/>
<circle cx="255.1" cy="283.7" r=".25"/>
<circle cx="255.4" cy="280.2" r=".25"/>
<circle cx="255.5" cy="280.3" r=".25"/>
<circle cx="255.6" cy="280.4" r=".25"/>
<circle cx="255.6" cy="281.8" r=".25"/>
<circle cx="331" cy="299.8" r=".25"/>
<circle cx="331.1" cy="291.6" r=".25"/>
<circle cx="331.1" cy="283.9" r=".25"/>
<circle cx="331.1" cy="284.1" r=".25"/>
<circle cx="331.1" cy="283.5" r=".25"/>
<circle cx="331.1" cy="288.2" r=".25"/>
<circle cx="331.1" cy="293.2" r=".25"/>
<circle cx="331.3" cy="296.2" r=".25"/>
<circle cx="331.6" cy="296.2" r=".25"/>
<circle cx="332" cy="295.4" r=".25"/>
<circle cx="333.4" cy="298.7" r=".25"/>
<circle cx="333.4" cy="296.3" r=".25"/>
<circle cx="333.4" cy="298.8" r=".25"/>
<circle cx="333.4" cy="296.4" r=".25"/>
<circle cx="333.5" cy="298.7" r=".25"/>
<circle cx="333.5" cy="298.8" r=".25"/>
<circle cx="334.7" cy="288.4" r=".25"/>
<circle cx="60.1" cy="318.7" r=".25"/>
<circle cx="60.1" cy="318.8" r=".25"/>
<circle cx="60.2" cy="318.7" r=".25"/>
<circle cx="62.5" cy="316.4" r=".25"/>
<circle cx="62.6" cy="316.3" r=".25"/>
<circle cx="62.6" cy="316.4" r=".25"/>
<circle cx="65.9" cy="316.3" r=".25"/>
<circle cx="65.9" cy="316.4" r=".25"/>
<circle cx="66" cy="316.4" r=".25"/>
<circle cx="68.3" cy="318.7" r=".25"/>
<circle cx="68.3" cy="318.8" r=".25"/>
<circle cx="80.2" cy="318.8" r=".25"/>
<circle cx="80.2" cy="318.7" r=".25"/>
<circle cx="80.2" cy="302.1" r=".25"/>
<circle cx="80.2" cy="302" r=".25"/>
<circle cx="80.2" cy="302.2" r=".25"/>
<circle cx="82.5" cy="304.5" r=".25"/>
<circle cx="82.5" cy="316.4" r=".25"/>
<circle cx="82.5" cy="316.3" r=".25"/>
<circle cx="82.6" cy="304.5" r=".25"/>
<circle cx="82.6" cy="316.3" r=".25"/>
<circle cx="85.8" cy="304.5" r=".25"/>
<circle cx="85.9" cy="304.5" r=".25"/>
<circle cx="85.9" cy="316.3" r=".25"/>
<circle cx="85.9" cy="316.4" r=".25"/>
<circle cx="86" cy="304.5" r=".25"/>
<circle cx="86" cy="316.4" r=".25"/>
<circle cx="88.3" cy="302.2" r=".25"/>
<circle cx="88.3" cy="302.1" r=".25"/>
<circle cx="88.3" cy="318.7" r=".25"/>
<circle cx="88.3" cy="302" r=".25"/>
<circle cx="88.3" cy="318.8" r=".25"/>
<circle cx="100.2" cy="318.7" r=".25"/>
<circle cx="100.2" cy="318.8" r=".25"/>
<circle cx="102.5" cy="316.4" r=".25"/>
<circle cx="102.6" cy="316.3" r=".25"/>
<circle cx="102.6" cy="316.4" r=".25"/>
<circle cx="105.9" cy="316.3" r=".25"/>
<circle cx="106" cy="316.4" r=".25"/>
<circle cx="106" cy="316.3" r=".25"/>
<circle cx="108.3" cy="318.7" r=".25"/>
<circle cx="108.3" cy="318.8" r=".25"/>
<circle cx="210.1" cy="318.7" r=".25"/>
<circle cx="210.1" cy="318.8" r=".25"/>
<circle cx="210.2" cy="318.7" r=".25"/>
<circle cx="212.5" cy="316.4" r=".25"/>
<circle cx="212.5" cy="316.3" r=".25"/>
<circle cx="212.6" cy="316.3" r=".25"/>
<circle cx="215.9" cy="316.3" r=".25"/>
<circle cx="215.9" cy="316.4" r=".25"/>
<circle cx="216" cy="316.4" r=".25"/>
<circle cx="218.3" cy="318.7" r=".25"/>
<circle cx="218.3" cy="318.8" r=".25"/>
<circle cx="226.6" cy="306.6" r=".25"/>
<circle cx="226.6" cy="303.8" r=".25"/>
<circle cx="226.6" cy="306.5" r=".25"/>
<circle cx="226.7" cy="306.7" r=".25"/>
<circle cx="226.8" cy="306.8" r=".25"/>
<circle cx="226.9" cy="306.8" r=".25"/>
<circle cx="227.3" cy="305.2" r=".25"/>
<circle cx="227.4" cy="303" r=".25"/>
<circle cx="227.5" cy="303" r=".25"/>
<circle cx="227.9" cy="301" r=".25"/>
<circle cx="228" cy="301" r=".25"/>
<circle cx="228" cy="300.9" r=".25"/>
<circle cx="228" cy="300.7" r=".25"/>
<circle cx="228" cy="300.6" r=".25"/>
<circle cx="228.1" cy="300.7" r=".25"/>
<circle cx="228.1" cy="300.9" r=".25"/>
<circle cx="228.6" cy="306.8" r=".25"/>
<circle cx="228.6" cy="306.7" r=".25"/>
<circle cx="228.7" cy="305.1" r=".25"/>
<circle cx="228.7" cy="306.6" r=".25"/>
<circle cx="229.4" cy="304.5" r=".25"/>
<circle cx="229.5" cy="304.3" r=".25"/>
<circle cx="229.5" cy="304.2" r=".25"/>
<circle cx="229.6" cy="304.2" r=".25"/>
<circle cx="230" cy="304.1" r=".25"/>
<circle cx="230.1" cy="304.1" r=".25"/>
<circle cx="230.2" cy="318.7" r=".25"/>
<circle cx="230.2" cy="318.8" r=".25"/>
<circle cx="230.4" cy="304" r=".25"/>
<circle cx="231" cy="303.6" r=".25"/>
<circle cx="231" cy="303.5" r=".25"/>
<circle cx="231.3" cy="303.9" r=".25"/>
<circle cx="231.4" cy="304" r=".25"/>
<circle cx="231.6" cy="303.6" r=".25"/>
<circle cx="231.6" cy="303.8" r=".25"/>
<circle cx="232" cy="303.5" r=".25"/>
<circle cx="232" cy="304.6" r=".25"/>
<circle cx="232" cy="303.6" r=".25"/>
<circle cx="232.1" cy="304.6" r=".25"/>
<circle cx="232.1" cy="303.6" r=".25"/>
<circle cx="232.5" cy="316.4" r=".25"/>
<circle cx="232.5" cy="316.3" r=".25"/>
<circle cx="232.6" cy="316.3" r=".25"/>
<circle cx="233" cy="304.1" r=".25"/>
<circle cx="233.1" cy="304.1" r=".25"/>
<circle cx="235.9" cy="316.3" r=".25"/>
<circle cx="235.9" cy="316.4" r=".25"/>
<circle cx="236" cy="316.4" r=".25"/>
<circle cx="236" cy="305.1" r=".25"/>
<circle cx="236.1" cy="305.1" r=".25"/>
<circle cx="236.1" cy="304.8" r=".25"/>
<circle cx="238.3" cy="318.7" r=".25"/>
<circle cx="238.3" cy="318.8" r=".25"/>
<circle cx="239.8" cy="304.2" r=".25"/>
<circle cx="239.9" cy="304.2" r=".25"/>
<circle cx="240" cy="304.2" r=".25"/>
<circle cx="240" cy="304.4" r=".25"/>
<circle cx="240.3" cy="305.1" r=".25"/>
<circle cx="240.4" cy="305.1" r=".25"/>
<circle cx="240.4" cy="305" r=".25"/>
<circle cx="241.5" cy="305.2" r=".25"/>
<circle cx="243.2" cy="305.2" r=".25"/>
<circle cx="245" cy="306.4" r=".25"/>
<circle cx="245" cy="306.3" r=".25"/>
<circle cx="245.1" cy="306.6" r=".25"/>
<circle cx="245.2" cy="306.6" r=".25"/>
<circle cx="246.2" cy="306.6" r=".25"/>
<circle cx="246.3" cy="306.5" r=".25"/>
<circle cx="246.5" cy="306.3" r=".25"/>
<circle cx="246.7" cy="306.2" r=".25"/>
<circle cx="247" cy="306.3" r=".25"/>
<circle cx="247.1" cy="306.3" r=".25"/>
<circle cx="247.1" cy="306.4" r=".25"/>
<circle cx="247.2" cy="306.4" r=".25"/>
<circle cx="247.3" cy="306.6" r=".25"/>
<circle cx="247.4" cy="306.6" r=".25"/>
<circle cx="248.4" cy="306.6" r=".25"/>
<circle cx="248.5" cy="306.5" r=".25"/>
<circle cx="248.6" cy="306.4" r=".25"/>
<circle cx="251.2" cy="305.1" r=".25"/>
<circle cx="252.8" cy="305.1" r=".25"/>
<circle cx="331" cy="301.1" r=".25"/>
<circle cx="331" cy="306.5" r=".25"/>
<circle cx="331.3" cy="303.6" r=".25"/>
<circle cx="331.6" cy="303.6" r=".25"/>
<circle cx="332.9" cy="305.2" r=".25"/>
<circle cx="333.4" cy="316.3" r=".25"/>
<circle cx="333.4" cy="318.7" r=".25"/>
<circle cx="333.4" cy="316.4" r=".25"/>
<circle cx="333.4" cy="318.8" r=".25"/>
<circle cx="333.4" cy="304.5" r=".25"/>
<circle cx="333.4" cy="302.1" r=".25"/>
<circle cx="333.4" cy="302" r=".25"/>
<circle cx="333.4" cy="302.2" r=".25"/>
<circle cx="333.4" cy="304.4" r=".25"/>
<circle cx="333.5" cy="318.7" r=".25"/>
<circle cx="333.5" cy="302.1" r=".25"/>
<circle cx="333.5" cy="316.4" r=".25"/>
<circle cx="333.5" cy="304.4" r=".25"/>
<circle cx="333.5" cy="318.8" r=".25"/>
<circle cx="333.5" cy="304.3" r=".25"/>
<circle cx="333.5" cy="302" r=".25"/>
<circle cx="333.5" cy="316.5" r=".25"/>
<circle cx="334" cy="304.8" r=".25"/>
<circle cx="334.2" cy="304.8" r=".25"/>
<circle cx="334.3" cy="304.8" r=".25"/>
<circle cx="334.3" cy="304.7" r=".25"/>
<circle cx="334.4" cy="304.7" r=".25"/>
<circle cx="334.4" cy="304.6" r=".25"/>
<circle cx="334.7" cy="300.5" r=".25"/>
<circle cx="334.7" cy="304.6" r=".25"/>
<circle cx="334.7" cy="304.7" r=".25"/>
<circle cx="60.1" cy="322.1" r=".25"/>
<circle cx="60.1" cy="322" r=".25"/>
<circle cx="60.2" cy="322.2" r=".25"/>
<circle cx="60.2" cy="322.1" r=".25"/>
<circle cx="62.5" cy="324.4" r=".25"/>
<circle cx="62.5" cy="324.5" r=".25"/>
<circle cx="62.6" cy="324.5" r=".25"/>
<circle cx="65.9" cy="324.5" r=".25"/>
<circle cx="66" cy="324.4" r=".25"/>
<circle cx="66" cy="324.5" r=".25"/>
<circle cx="68.3" cy="322.2" r=".25"/>
<circle cx="68.3" cy="322.1" r=".25"/>
<circle cx="68.3" cy="322" r=".25"/>
<circle cx="80.2" cy="322.2" r=".25"/>
<circle cx="80.2" cy="322.1" r=".25"/>
<circle cx="80.2" cy="338.8" r=".25"/>
<circle cx="80.2" cy="338.7" r=".25"/>
<circle cx="80.2" cy="322" r=".25"/>
<circle cx="82.5" cy="324.4" r=".25"/>
<circle cx="82.5" cy="324.5" r=".25"/>
<circle cx="82.5" cy="336.4" r=".25"/>
<circle cx="82.5" cy="336.3" r=".25"/>
<circle cx="82.6" cy="324.5" r=".25"/>
<circle cx="82.6" cy="336.3" r=".25"/>
<circle cx="85.8" cy="324.5" r=".25"/>
<circle cx="85.9" cy="324.5" r=".25"/>
<circle cx="85.9" cy="336.3" r=".25"/>
<circle cx="86" cy="336.3" r=".25"/>
<circle cx="86" cy="336.4" r=".25"/>
<circle cx="86" cy="324.4" r=".25"/>
<circle cx="86" cy="324.5" r=".25"/>
<circle cx="88.3" cy="338.7" r=".25"/>
<circle cx="88.3" cy="322.2" r=".25"/>
<circle cx="88.3" cy="322.1" r=".25"/>
<circle cx="88.3" cy="322" r=".25"/>
<circle cx="88.3" cy="338.8" r=".25"/>
<circle cx="100.2" cy="322.1" r=".25"/>
<circle cx="100.2" cy="322" r=".25"/>
<circle cx="100.2" cy="322.2" r=".25"/>
<circle cx="102.5" cy="324.4" r=".25"/>
<circle cx="102.5" cy="324.5" r=".25"/>
<circle cx="102.6" cy="324.5" r=".25"/>
<circle cx="105.9" cy="324.5" r=".25"/>
<circle cx="106" cy="324.5" r=".25"/>
<circle cx="106" cy="324.4" r=".25"/>
<circle cx="108.3" cy="322.2" r=".25"/>
<circle cx="108.3" cy="322.1" r=".25"/>
<circle cx="108.3" cy="322" r=".25"/>
<circle cx="210.1" cy="322.1" r=".25"/>
<circle cx="210.1" cy="322" r=".25"/>
<circle cx="210.2" cy="322.2" r=".25"/>
<circle cx="210.2" cy="322.1" r=".25"/>
<circle cx="212.5" cy="324.4" r=".25"/>
<circle cx="212.5" cy="324.5" r=".25"/>
<circle cx="212.6" cy="324.5" r=".25"/>
<circle cx="215.9" cy="324.5" r=".25"/>
<circle cx="216" cy="324.4" r=".25"/>
<circle cx="216" cy="324.5" r=".25"/>
<circle cx="218.3" cy="322.2" r=".25"/>
<circle cx="218.3" cy="322.1" r=".25"/>
<circle cx="218.3" cy="322" r=".25"/>
<circle cx="230.2" cy="322.1" r=".25"/>
<circle cx="230.2" cy="322" r=".25"/>
<circle cx="230.2" cy="322.2" r=".25"/>
<circle cx="232.5" cy="324.4" r=".25"/>
<circle cx="232.5" cy="324.5" r=".25"/>
<circle cx="232.6" cy="324.5" r=".25"/>
<circle cx="235.9" cy="324.5" r=".25"/>
<circle cx="236" cy="324.4" r=".25"/>
<circle cx="236" cy="324.5" r=".25"/>
<circle cx="238.3" cy="322.2" r=".25"/>
<circle cx="238.3" cy="322.1" r=".25"/>
<circle cx="238.3" cy="322" r=".25"/>
<circle cx="331" cy="339.8" r=".25"/>
<circle cx="331.3" cy="336.2" r=".25"/>
<circle cx="331.6" cy="336.2" r=".25"/>
<circle cx="333.4" cy="338.7" r=".25"/>
<circle cx="333.4" cy="322.2" r=".25"/>
<circle cx="333.4" cy="336.3" r=".25"/>
<circle cx="333.4" cy="338.8" r=".25"/>
<circle cx="333.4" cy="336.4" r=".25"/>
<circle cx="333.4" cy="324.4" r=".25"/>
<circle cx="333.4" cy="324.5" r=".25"/>
<circle cx="333.4" cy="322.1" r=".25"/>
<circle cx="333.4" cy="322" r=".25"/>
<circle cx="333.5" cy="324.4" r=".25"/>
<circle cx="333.5" cy="338.7" r=".25"/>
<circle cx="333.5" cy="336.4" r=".25"/>
<circle cx="333.5" cy="338.8" r=".25"/>
<circle cx="333.5" cy="336.5" r=".25"/>
<circle cx="333.5" cy="324.3" r=".25"/>
<circle cx="80.2" cy="342.1" r=".25"/>
<circle cx="82.5" cy="344.5" r=".25"/>
<circle cx="82.6" cy="344.5" r=".25"/>
<circle cx="85.9" cy="344.5" r=".25"/>
<circle cx="86" cy="344.5" r=".25"/>
<circle cx="88.3" cy="342.1" r=".25"/>
<circle cx="88.3" cy="342.2" r=".25"/>
<circle cx="331" cy="341.1" r=".25"/>
<circle cx="331.3" cy="343.6" r=".25"/>
<circle cx="331.6" cy="343.6" r=".25"/>
<circle cx="332" cy="345.4" r=".25"/>
<circle cx="333.4" cy="342.1" r=".25"/>
<circle cx="333.4" cy="344.5" r=".25"/>
<circle cx="333.4" cy="342.2" r=".25"/>
<circle cx="333.4" cy="344.4" r=".25"/>
<circle cx="333.5" cy="342.1" r=".25"/>
<circle cx="333.5" cy="344.4" r=".25"/>
<circle cx="333.5" cy="344.3" r=".25"/>
</g>
<path d="M54.3 151l3.4-.5v1.1zM54.3 149.3v47.1M254.2 149.3v47.1" fill="none" stroke="#008080" stroke-width=".42"/>
<path d="M54.3 151l3.4-.5v1.1z" fill="#008080"/>
<path d="M250.7 150.5l3.5 .5-3.5 .6z" fill="none" stroke="#008080" stroke-width=".42"/>
<path d="M250.7 150.5l3.5 .5-3.5 .6z" fill="#008080"/>
<path d="M54.3 151h199.9M246.2 188.4h33.9M278.4 188.4l.6 3.5h-1.2zM246.2 352.4h33.9" fill="none" stroke="#008080" stroke-width=".42"/>
<path d="M278.4 188.4l.6 3.5h-1.2z" fill="#008080"/>
<path d="M277.8 348.9h1.2l-.6 3.5z" fill="none" stroke="#008080" stroke-width=".42"/>
<path d="M277.8 348.9h1.2l-.6 3.5z" fill="#008080"/>
<path d="M278.4 188.4v164M214.2 320.4v75.7M234.2 320.4v75.7M214.2 394.4l3.6-.6v1.1z" fill="none" stroke="#008080" stroke-width=".42"/>
<path d="M214.2 394.4l3.6-.6v1.1z" fill="#008080"/>
<path d="M230.8 393.8l3.4 .6-3.4 .5z" fill="none" stroke="#008080" stroke-width=".42"/>
<path d="M230.8 393.8l3.4 .6-3.4 .5z" fill="#008080"/>
<path d="M84.2 320.4v75.7M104.3 320.4v75.7M100.7 393.8l3.6 .6-3.6 .5zM214.2 394.4h20" fill="none" stroke="#008080" stroke-width=".42"/>
<path d="M100.7 393.8l3.6 .6-3.6 .5z" fill="#008080"/>
<path d="M84.2 394.4l3.6-.6v1.1z" fill="none" stroke="#008080" stroke-width=".42"/>
<path d="M84.2 394.4l3.6-.6v1.1z" fill="#008080"/>
<path d="M64.3 320.4v75.7M84.2 320.4v75.7M64.3 394.4l3.4-.6v1.1zM84.2 394.4h20.1" fill="none" stroke="#008080" stroke-width=".42"/>
<path d="M64.3 394.4l3.4-.6v1.1z" fill="#008080"/>
<path d="M80.8 393.8l3.4 .6-3.4 .5z" fill="none" stroke="#008080" stroke-width=".42"/>
<path d="M80.8 393.8l3.4 .6-3.4 .5z" fill="#008080"/>
<path d="M25.6 300.4h58.6M27.4 300.4l.6 3.5h-1.2zM25.6 320.4h58.6M64.3 394.4h19.9" fill="none" stroke="#008080" stroke-width=".42"/>
<path d="M27.4 300.4l.6 3.5h-1.2z" fill="#008080"/>
<path d="M26.8 316.9h1.2l-.6 3.5z" fill="none" stroke="#008080" stroke-width=".42"/>
<path d="M26.8 316.9h1.2l-.6 3.5z" fill="#008080"/>
<path d="M27.4 300.4v20M25.6 320.4h58.6M26.8 336.9h1.2l-.6 3.5zM25.6 340.4h58.6" fill="none" stroke="#008080" stroke-width=".42"/>
<path d="M26.8 336.9h1.2l-.6 3.5z" fill="#008080"/>
<path d="M27.4 320.4l.6 3.5h-1.2z" fill="none" stroke="#008080" stroke-width=".42"/>
<path d="M27.4 320.4l.6 3.5h-1.2z" fill="#008080"/>
<path d="M27.4 320.4v20M25.6 352.4h36.7M25.6 340.4h58.6M26.8 348.9h1.2l-.6 3.5z" fill="none" stroke="#008080" stroke-width=".42"/>
<path d="M26.8 348.9h1.2l-.6 3.5z" fill="#008080"/>
<path d="M27.4 340.4l.6 3.5h-1.2z" fill="none" stroke="#008080" stroke-width=".42"/>
<path d="M27.4 340.4l.6 3.5h-1.2z" fill="#008080"/>
<path d="M64.3 320.4v75.7M27.4 340.4v12M54.3 344.4v51.7M50.8 393.8l3.5 .6-3.5 .5z" fill="none" stroke="#008080" stroke-width=".42"/>
<path d="M50.8 393.8l3.5 .6-3.5 .5z" fill="#008080"/>
<path d="M64.3 394.4l3.4-.6v1.1z" fill="none" stroke="#008080" stroke-width=".42"/>
<path d="M64.3 394.4l3.4-.6v1.1z" fill="#008080"/>
<path d="M234.2 320.4v75.7M254.2 344.4v51.7M47.2 394.4h24M250.7 393.8l3.5 .6-3.5 .5z" fill="none" stroke="#008080" stroke-width=".42"/>
<path d="M250.7 393.8l3.5 .6-3.5 .5z" fill="#008080"/>
<path d="M234.2 394.4l3.5-.6v1.1z" fill="none" stroke="#008080" stroke-width=".42"/>
<path d="M234.2 394.4l3.5-.6v1.1z" fill="#008080"/>
<path d="M234.2 320.4h36.9M246.2 352.4h24.9M268.7 348.9h1.2l-.6 3.5zM234.2 394.4h20" fill="none" stroke="#008080" stroke-width=".42"/>
<path d="M268.7 348.9h1.2l-.6 3.5z" fill="#008080"/>
<path d="M269.3 320.4l.6 3.5h-1.2z" fill="none" stroke="#008080" stroke-width=".42"/>
<path d="M269.3 320.4l.6 3.5h-1.2z" fill="#008080"/>
<path d="M67.3 191.9l.6 1-3.1 1.6zM70.4 190.3l-36.8 27.6M269.3 320.4v32" fill="none" stroke="#008080" stroke-width=".42"/>
<path d="M67.3 191.9l.6 1-3.1 1.6z" fill="#008080"/>
<path d="M56.6 200l3.1-1.7-2.5 2.6z" fill="none" stroke="#008080" stroke-width=".42"/>
<path d="M56.6 200l3.1-1.7-2.5 2.6z" fill="#008080"/>
<path d="M37.5 177.6l24.8 18.8M53.5 189l2.4 2.6-3.2-1.7z" fill="none" stroke="#008080" stroke-width=".42"/>
<path d="M53.5 189l2.4 2.6-3.2-1.7z" fill="#008080"/>
<path d="M101.9 164l3.5 .5-3.5 .6zM105.4 162.8v26.9M110.5 162.8v26.9" fill="none" stroke="#008080" stroke-width=".42"/>
<path d="M101.9 164l3.5 .5-3.5 .6z" fill="#008080"/>
<path d="M110.5 164.5l3.5-.5v1.1z" fill="none" stroke="#008080" stroke-width=".42"/>
<path d="M110.5 164.5l3.5-.5v1.1z" fill="#008080"/>
<path d="M246.2 98.1h33.9M246.2 95h33.9M278.4 98.1l.6 3.5h-1.2zM98.4 164.5h19.1" fill="none" stroke="#008080" stroke-width=".42"/>
<path d="M278.4 98.1l.6 3.5h-1.2z" fill="#008080"/>
<path d="M277.8 91.5h1.2l-.6 3.5z" fill="none" stroke="#008080" stroke-width=".42"/>
<path d="M277.8 91.5h1.2l-.6 3.5z" fill="#008080"/>
<path d="M278.4 88v26.6" fill="none" stroke="#008080" stroke-width=".42"/>
<g fill="none" stroke="#e6e6e6" stroke-width=".42">
<path d="M29.6 381.4a6.8 6.8 0 0 1 8.7 .8l.7 2.3-2.9 .1a2.81 2.81 0 0 0-2.1-2 2.81 2.81 0 0 0-2.8 1.1 2.05 2.05 0 0 0 2.3 1.9l1.4 .3a4.5 4.5 0 0 1 4.1 6.4 6.6 6.6 0 0 1-10.4 0l-.7-2.3 2.8-.3a3.1 3.1 0 0 0 2.6 2.7 3.1 3.1 0 0 0 3.3-2 2.75 2.75 0 0 0-3-1.9 5 5 0 0 1-5.2-4.4l.4-1.6zM44.9 386.8a2.65 2.65 0 0 1 3.2 .1 2.65 2.65 0 0 1 .8 3.1 2.53 2.53 0 0 1-2.9 2.6 2.53 2.53 0 0 1-2.1-3.2l.2-1.5zM53.8 380.4h2.7v14.1h-2.7zM59.3 380.4h2.7v2.5h-2.7zM59.3 384.3h2.7v10.2h-2.7zM65.3 385.4a4.1 4.1 0 0 1 6.1 .1v-5.1h2.7v14.1h-2.5v-1.5a4.1 4.1 0 0 1-4.9 1.5 4.1 4.1 0 0 1-2.6-4.4 6.2 6.2 0 0 1 1.2-4.7zM67.7 386.7a2.27 2.27 0 0 1 2.6-.2 2.27 2.27 0 0 1 1.1 2.3 2.77 2.77 0 0 1-2.7 3.8 3.9 3.9 0 0 1-1-5.9zM82.2 380.4h10.5v2.4h-7.6v3.2h7.1v2.3h-7.1v3.9h7.9v2.3h-10.8zM95.9 385.4a4.1 4.1 0 0 1 6.1 .1v-5.1h2.7v14.1h-2.5v-1.5a4.1 4.1 0 0 1-4.9 1.5 4.1 4.1 0 0 1-2.6-4.4 6.2 6.2 0 0 1 1.2-4.7zM98.3 386.7a2.27 2.27 0 0 1 2.6-.2 2.27 2.27 0 0 1 1.1 2.3 2.77 2.77 0 0 1-2.7 3.8 3.9 3.9 0 0 1-1-5.9zM108.4 385a4 4 0 0 1 5.8 .7v-1.4h2.5v9.2a4.2 4.2 0 0 1-4.9 5.2 3.8 3.8 0 0 1-4.8-3.2l.1-.3 3 .4a2.12 2.12 0 0 0 3.6 .3l.3-3a4 4 0 0 1-4.7 1.3 4 4 0 0 1-2.6-4.2 5.8 5.8 0 0 1 1.7-5zM110.1 386.9a2.37 2.37 0 0 1 2.9-.4 2.37 2.37 0 0 1 1 2.8 2.4 2.4 0 0 1-2.3 3 2.4 2.4 0 0 1-2.2-3.1z"/>
<path d="M119.9 385.5a4.8 4.8 0 0 1 5.5-1 4.8 4.8 0 0 1 2.7 4.8v.9h-6.7a2.01 2.01 0 0 0 1.3 2.4 2.01 2.01 0 0 0 2.5-1.3l2.7 .5a5 5 0 0 1-6.4 2.7 5 5 0 0 1-2.8-6.4zM122 386.8a2.05 2.05 0 0 1 2.4-.4 2.05 2.05 0 0 1 1.1 2.1h-4.1zM137.2 382.1a6.2 6.2 0 0 1 10.4 2.2l-2.8 .7a3.3 3.3 0 0 0-4-2.3 3.3 3.3 0 0 0-2.5 3.9 5.1 5.1 0 0 0 2 5.5 3.2 3.2 0 0 0 4.6-2.7l2.8 .8a6.3 6.3 0 0 1-7.4 4.5 6.3 6.3 0 0 1-5-7.1 7.6 7.6 0 0 1 1.9-5.5zM153.2 386.8a2.65 2.65 0 0 1 3.1 .1 2.65 2.65 0 0 1 .8 3.1 2.53 2.53 0 0 1-2.8 2.6 2.53 2.53 0 0 1-2.2-3.2l.3-1.5zM161.9 384.3h2.5v1.4a3.6 3.6 0 0 1 6 0 3.5 3.5 0 0 1 4.2-1.5 3.5 3.5 0 0 1 2.3 3.8v6.5h-2.7v-5.8a1.86 1.86 0 0 0-1.4-2.5 2.28 2.28 0 0 0-2 2.9v5.4h-2.7l-.1-6.1a1.74 1.74 0 0 0-1.5-2.2 1.74 1.74 0 0 0-1.9 1.9v6.4h-2.7zM179.4 384.3h2.5v1.4a3.6 3.6 0 0 1 6 0 3.5 3.5 0 0 1 4.2-1.5 3.5 3.5 0 0 1 2.3 3.8v6.5h-2.7v-5.8a1.86 1.86 0 0 0-1.5-2.5 2.28 2.28 0 0 0-1.9 2.9l-.1 5.4h-2.7v-6.1a1.74 1.74 0 0 0-1.5-2.2 1.74 1.74 0 0 0-1.9 1.9v6.4h-2.7zM197 384.3h2.7v4.7a3.4 3.4 0 0 0 .9 3.5 2.22 2.22 0 0 0 2.9-2.6l.1-5.6h2.7v10.2h-2.5v-1.5a3.6 3.6 0 0 1-4.3 1.7 3.6 3.6 0 0 1-2.5-3.9zM209 384.3h2.5v1.5a3.6 3.6 0 0 1 4.4-1.7 3.6 3.6 0 0 1 2.4 4.1v6.3h-2.7v-5.2a2.28 2.28 0 0 0-1.7-3.1 2.39 2.39 0 0 0-2.1 3l-.1 5.3h-2.7zM221.1 380.4h2.7v2.5h-2.7zM221.1 384.3h2.7v10.2h-2.7zM226.6 382.3l2.8-1.6v3.6h1.8v2.2h-1.8v4.1a1.41 1.41 0 0 0 .5 1.9l1.3-.2 .2 2.1a3 3 0 0 1-4.7-1.5l-.1-6.4h-1.2v-2.2h1.2zM231.8 384.3h2.8l2.5 7.3 2.3-7.3h2.9l-4.3 11.6a3.9 3.9 0 0 1-5.3 2.6l-.2-2.1a2.17 2.17 0 0 0 3.1-1.8z"/>
<path d="M249.5 380.4h10.5v2.4h-7.6v3.2h7.1v2.3h-7.1v3.9h7.9v2.3h-10.8zM263.2 385.4a4.1 4.1 0 0 1 6.1 .1v-5.1h2.7v14.1h-2.5v-1.5a4.1 4.1 0 0 1-4.9 1.5 4.1 4.1 0 0 1-2.6-4.4 6.2 6.2 0 0 1 1.2-4.7zM265.7 386.7a2.27 2.27 0 0 1 2.5-.2 2.27 2.27 0 0 1 1.1 2.3 2.77 2.77 0 0 1-2.7 3.8 3.9 3.9 0 0 1-.9-5.9zM274.7 380.4h2.7v2.5h-2.7zM274.7 384.3h2.7v10.2h-2.7zM280.2 382.3l2.7-1.6v3.6h1.9v2.2h-1.9v4.1a1.41 1.41 0 0 0 .6 1.9l1.3-.2 .2 2.1a3 3 0 0 1-4.7-1.5l-.1-6.4h-1.2v-2.2h1.2zM286.7 380.4h2.7v2.5h-2.7zM286.7 384.3h2.7v10.2h-2.7zM295.3 386.8a2.65 2.65 0 0 1 3.1 .1 2.65 2.65 0 0 1 .8 3.1 2.53 2.53 0 0 1-2.8 2.6 2.53 2.53 0 0 1-2.1-3.2l.2-1.5zM304.2 384.3h2.5v1.5a3.6 3.6 0 0 1 4.3-1.7 3.6 3.6 0 0 1 2.4 4.1v6.3h-2.7v-5.2a2.28 2.28 0 0 0-1.6-3.1 2.39 2.39 0 0 0-2.2 3v5.3h-2.7z"/>
<circle cx="46.5" cy="389.4" r="5.4"/>
<circle cx="154.7" cy="389.4" r="5.4"/>
<circle cx="296.9" cy="389.4" r="5.4"/>
</g>
<use href="#words"/>
</svg>
